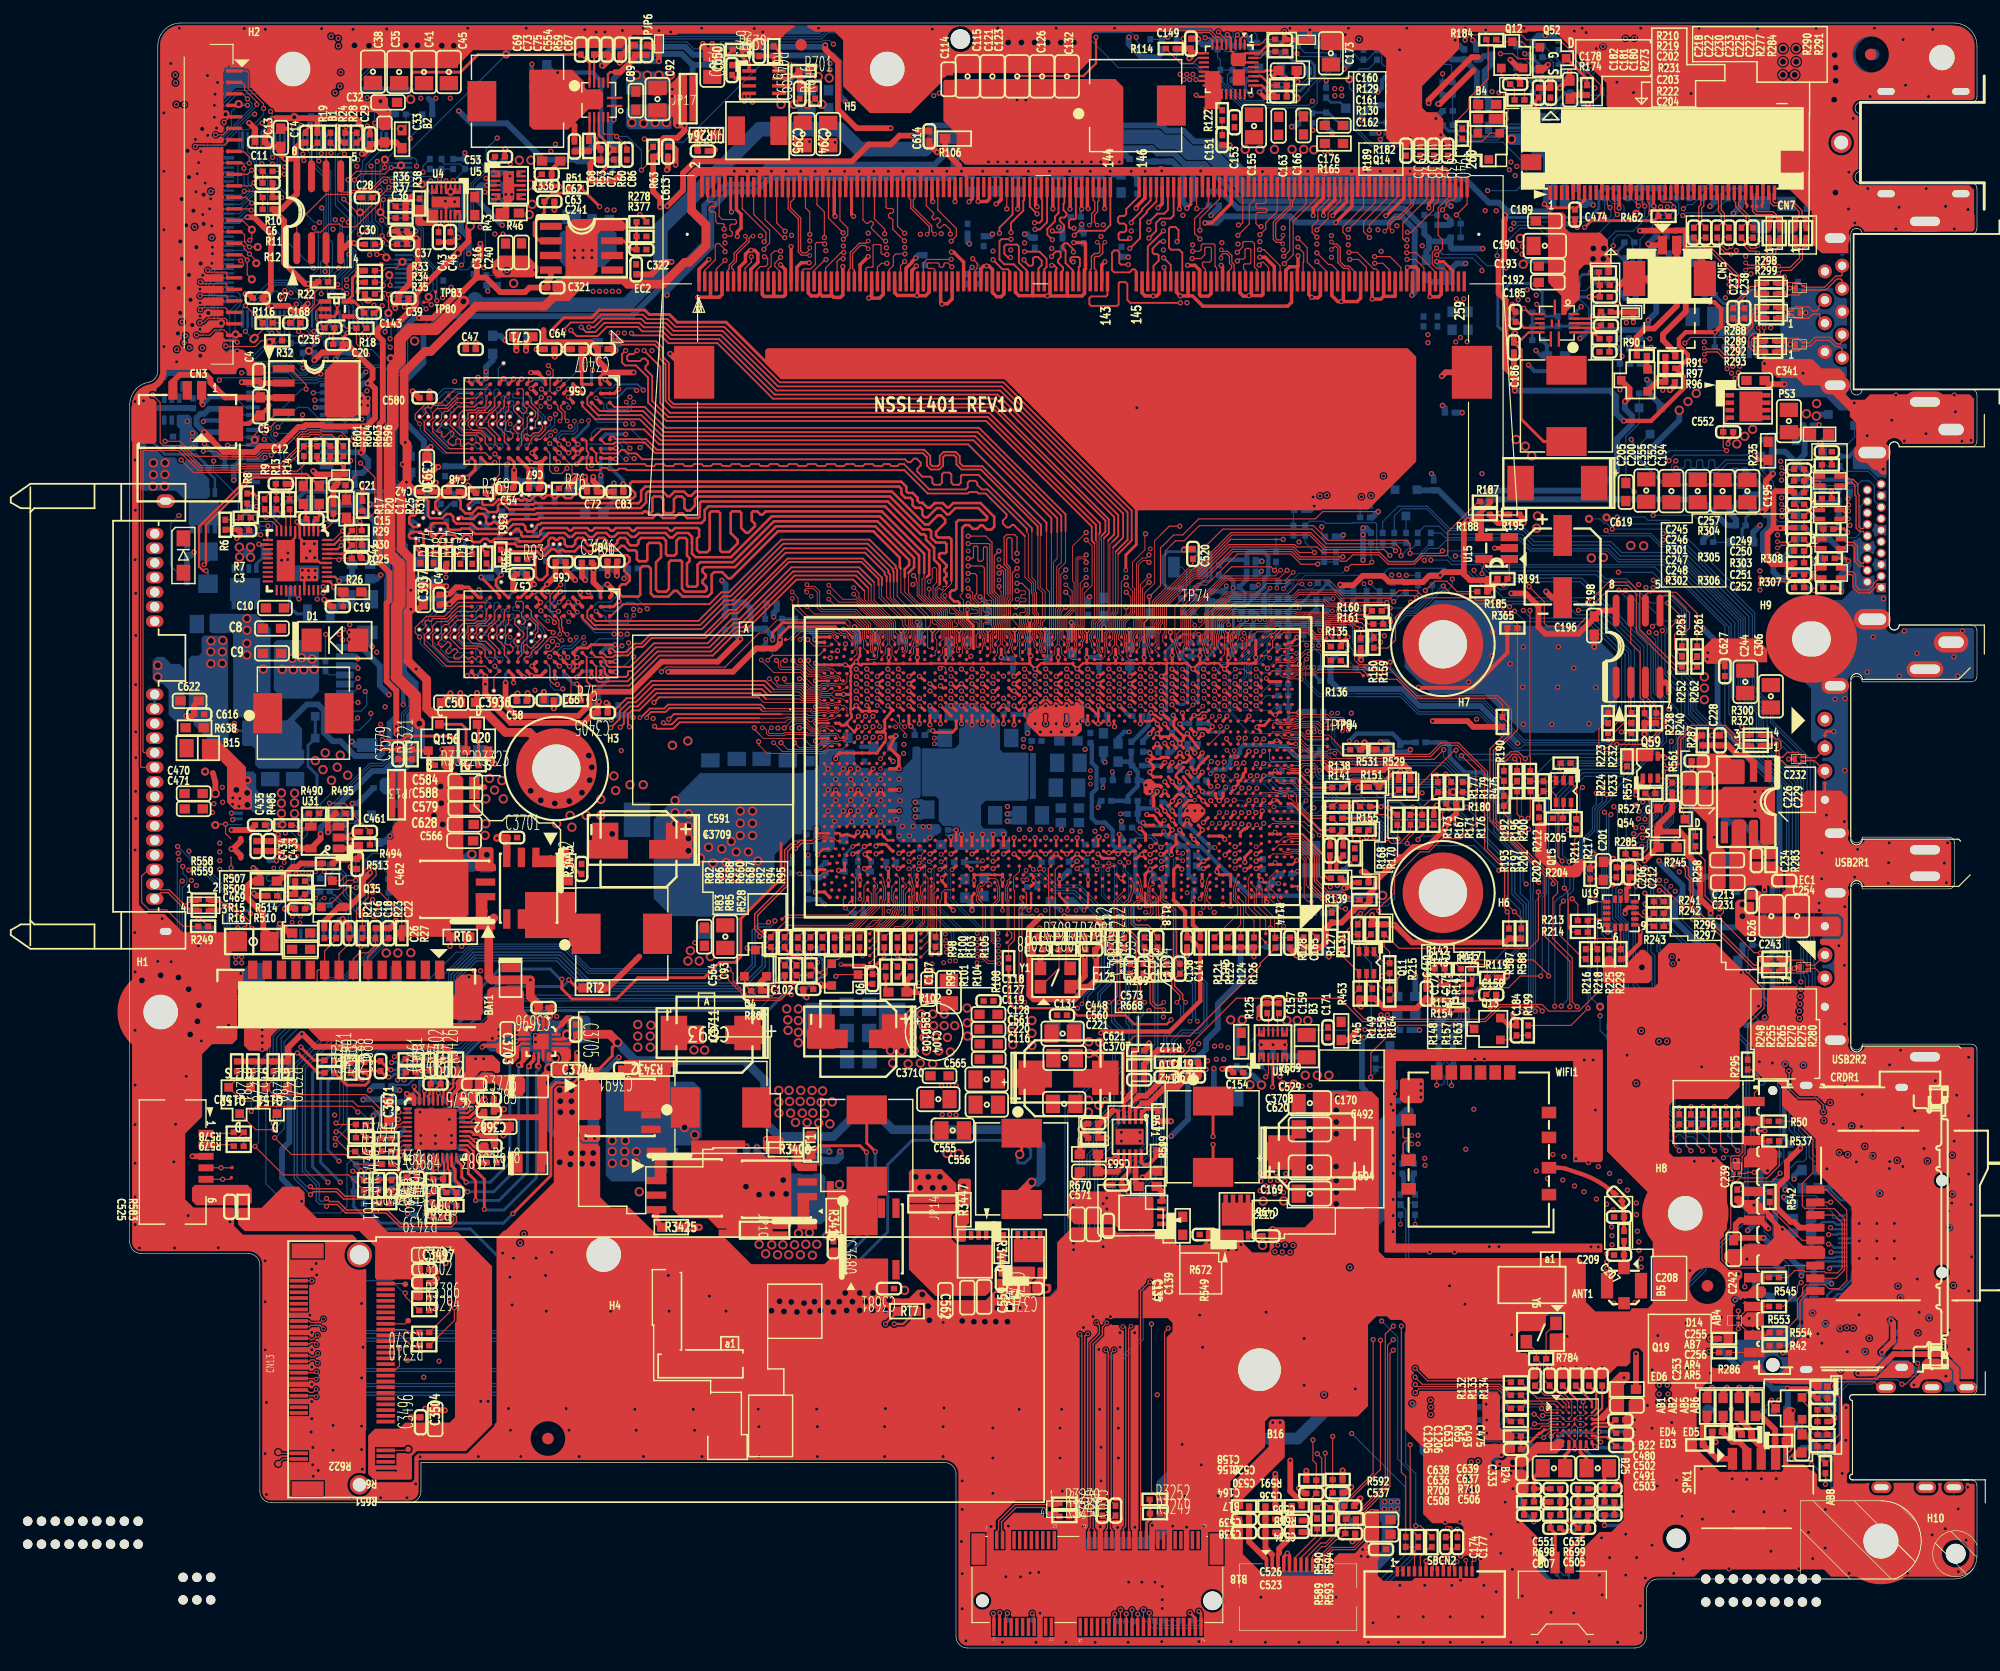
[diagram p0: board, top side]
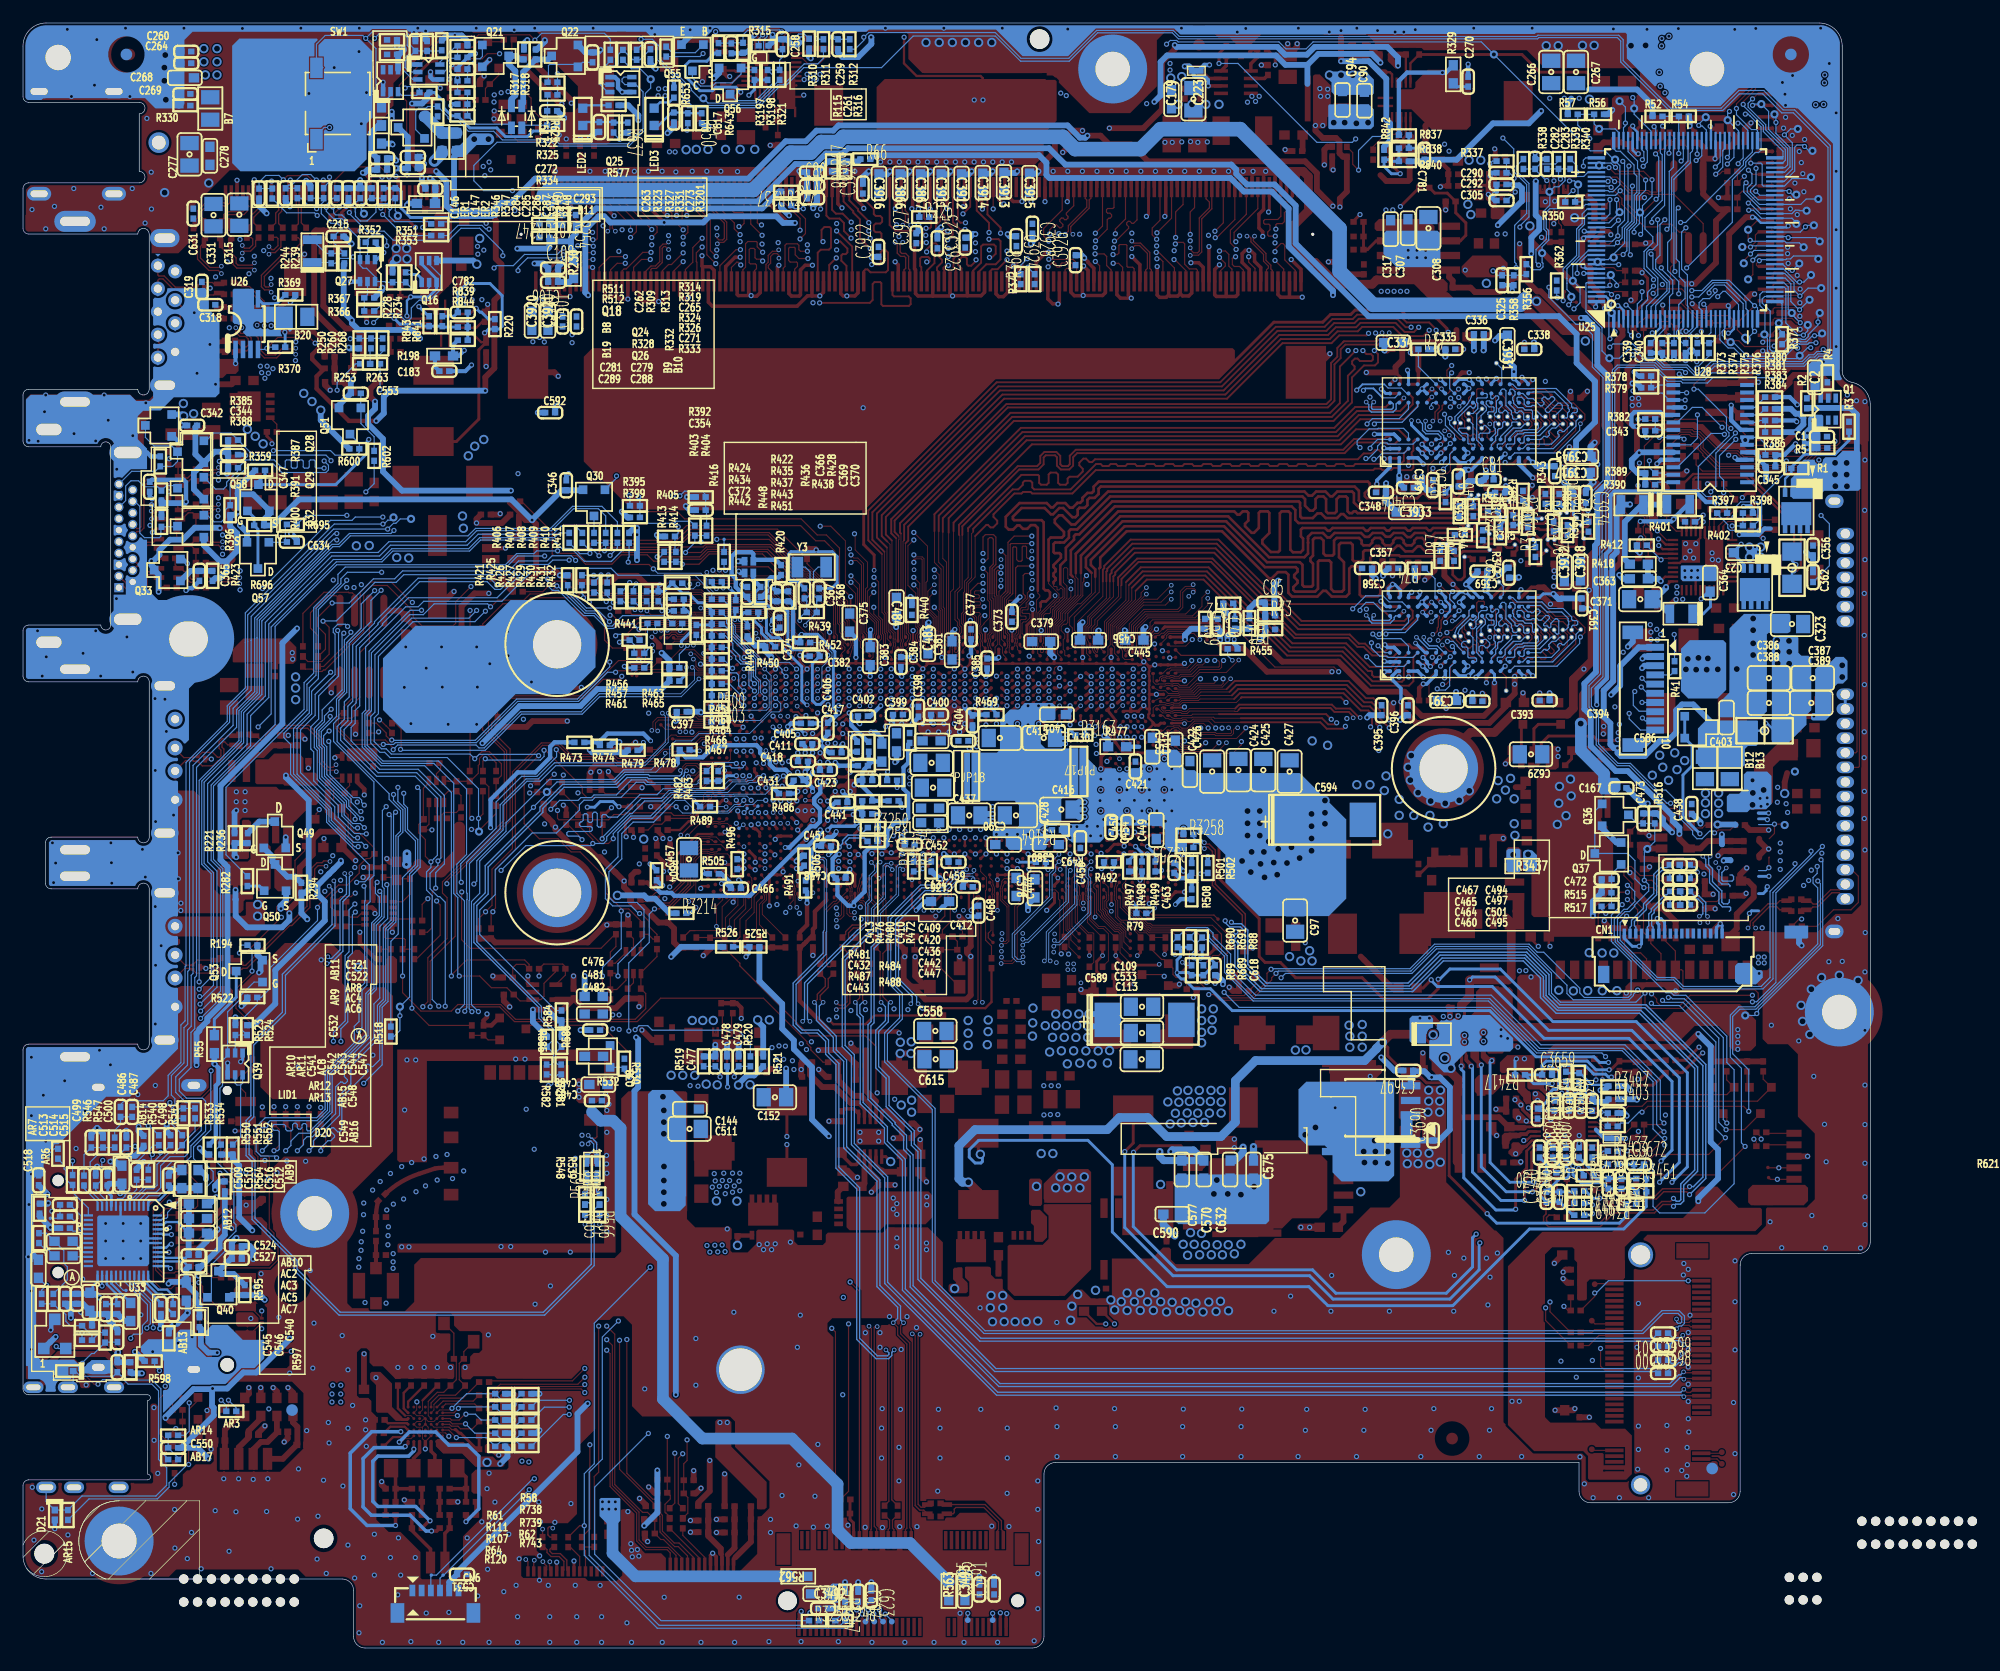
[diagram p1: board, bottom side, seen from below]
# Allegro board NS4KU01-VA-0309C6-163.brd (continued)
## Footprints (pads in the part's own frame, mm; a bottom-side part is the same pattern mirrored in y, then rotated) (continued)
SMD_CRYSTAL-TXC-4P_3D2X2D5
  rect 1.016x1.194 smd: 1(-1.291,-0.8) 2(1.291,-0.8) 3(1.291,0.8) 4(-1.291,0.8)
SOD_123_2D0
  rect 1.397x1.194 smd: 1(-1.499,0) 2(1.499,0)
SOT363
  rect 0.406x0.813 smd: 1(0.65,0.955) 2(0,0.955) 3(-0.65,0.955) 4(-0.65,-0.955) 5(0,-0.955) 6(0.65,-0.955)
SOT-23-5
  rect 0.711x1.016 smd: 1(-0.95,-1.2) 2(0,-1.2) 3(0.95,-1.2) 4(0.95,1.2) 5(-0.95,1.2)
SWITCH_T-V_TME-533K-Q-TR_DIP
  rect 1.092x1.778 smd: 1(1.85,3.1) 2(1.85,-3.1) 3(-1.85,3.1) 4(-1.85,-3.1)
  rect 0.61x1.016 smd: 5(2.5,0) 6(-2.5,0)
TC276BC236D165
  round 7.01 hole 4.191: 1(0,0)
TC296BC236D118
  round 7.518 hole 2.997: 1(0,0)
TF_M2_KEY-B_2280_3H
  rect 0.33x1.6 smd: 1(-9.25,3.773) 2(-9,-3.777) 3(-8.75,3.773) 4(-8.5,-3.777) 5(-8.25,3.773) 6(-8,-3.777) 7(-7.75,3.773) 8(-7.5,-3.777) 9(-7.25,3.773) 10(-7,-3.777) 11(-6.75,3.773) 20(-4.5,-3.777) 21(-4.25,3.773) 22(-4,-3.777) 23(-3.75,3.773) 24(-3.5,-3.777) 25(-3.25,3.773) 26(-3,-3.777) 27(-2.75,3.773) 28(-2.5,-3.777) 29(-2.25,3.773) 30(-2,-3.777) 31(-1.75,3.773) 32(-1.5,-3.777) 33(-1.25,3.773) 34(-1,-3.777) 35(-0.75,3.773) 36(-0.5,-3.777) 37(-0.25,3.773) 38(0,-3.777) 39(0.25,3.773) 40(0.5,-3.777) 41(0.75,3.773) 42(1,-3.777) 43(1.25,3.773) 44(1.5,-3.777) 45(1.75,3.773) 46(2,-3.777) 47(2.25,3.773) 48(2.5,-3.777) 49(2.75,3.773) 50(3,-3.777) 51(3.25,3.773) 52(3.5,-3.777) 53(3.75,3.773) 54(4,-3.777) 55(4.25,3.773) 56(4.5,-3.777) 57(4.75,3.773) 58(5,-3.777) 59(5.25,3.773) 60(5.5,-3.777) 61(5.75,3.773) 62(6,-3.777) 63(6.25,3.773) 64(6.5,-3.777) 65(6.75,3.773) 66(7,-3.777) 67(7.25,3.773) 68(7.5,-3.777) 69(7.75,3.773) 70(8,-3.777) 71(8.25,3.773) 72(8.5,-3.777) 73(8.75,3.773) 74(9,-3.777) 75(9.25,3.773)
  rect 1.321x2.794 smd: 76(-10.35,2.998) 77(10.35,2.998)
  round 1.676 hole 1.168: 78(-10,-1.502)
  round 2.184 hole 1.676: 79(10,-1.502)
TF_M2_KEY-E_2230_3H
  round 1.118 hole 1.118 unplated: (-10,-1.5)
  round 1.626 hole 1.626 unplated: (10,-1.5)
  rect 0.305x1.575 smd: 1(-9.25,3.775) 2(-9,-3.775) 3(-8.75,3.775) 4(-8.5,-3.775) 5(-8.25,3.775) 6(-8,-3.775) 7(-7.75,3.775) 8(-7.5,-3.775) 9(-7.25,3.775) 10(-7,-3.775) 11(-6.75,3.775) 12(-6.5,-3.775) 13(-6.25,3.775) 14(-6,-3.775) 15(-5.75,3.775) 16(-5.5,-3.775) 17(-5.25,3.775) 18(-5,-3.775) 19(-4.75,3.775) 20(-4.5,-3.775) 21(-4.25,3.775) 22(-4,-3.775) 23(-3.75,3.775) 32(-1.5,-3.775) 33(-1.25,3.775) 34(-1,-3.775) 35(-0.75,3.775) 36(-0.5,-3.775) 37(-0.25,3.775) 38(0,-3.775) 39(0.25,3.775) 40(0.5,-3.775) 41(0.75,3.775) 42(1,-3.775) 43(1.25,3.775) 44(1.5,-3.775) 45(1.75,3.775) 46(2,-3.775) 47(2.25,3.775) 48(2.5,-3.775) 49(2.75,3.775) 50(3,-3.775) 51(3.25,3.775) 52(3.5,-3.775) 53(3.75,3.775) 54(4,-3.775) 55(4.25,3.775) 56(4.5,-3.775) 57(4.75,3.775) 58(5,-3.775) 59(5.25,3.775) 60(5.5,-3.775) 61(5.75,3.775) 62(6,-3.775) 63(6.25,3.775) 64(6.5,-3.775) 65(6.75,3.775) 66(7,-3.775) 67(7.25,3.775) 68(7.5,-3.775) 69(7.75,3.775) 70(8,-3.775) 71(8.25,3.775) 72(8.5,-3.775) 73(8.75,3.775) 74(9,-3.775) 75(9.25,3.775)
  rect 1.219x2.743 smd: 76(10.35,3) 77(-10.35,3)
TOPOPEN-157X20
  rect 0.508x3.988 smd: 1(-0.356,0) 2(0.356,0)
TOPOPEN_20X30
  rect 0.762x0.508 smd: 1(0,0.381) 2(0,-0.381)
TOPOPEN_20X157
  rect 0.508x3.988 smd: 1(-0.318,0) 2(0.318,0)
TOPSHORT_20X30
  rect 0.508x0.762 smd: 1(0,0.254) 2(0,-0.254)
TP12T
  round 0.305 smd: 1(0,0)
TP20
  round 0.508 smd: 1(0,0)
TQFN32-2_4X4_GS9271
  rect 0.203x0.914 smd: 1(-1.4,-2.157) 2(-1,-2.157) 3(-0.6,-2.157) 4(-0.2,-2.157) 5(0.2,-2.157) 6(0.6,-2.157) 7(1,-2.157) 8(1.4,-2.157) 18(1,2.157) 19(0.6,2.157) 20(0.2,2.157) 21(-0.2,2.157) 22(-0.6,2.157) 23(-1,2.157) 24(-1.4,2.157)
  rect 0.914x0.203 smd: 9(2.157,-1.4) 10(2.157,-1) 11(2.157,-0.6) 12(2.157,-0.2) 13(2.157,0.2) 14(2.157,0.6) 15(2.157,1) 25(-2.157,1.4) 26(-2.157,1) 27(-2.157,0.6) 28(-2.157,0.2) 29(-2.157,-0.2) 30(-2.157,-0.6) 31(-2.157,-1) 32(-2.157,-1.4)
  custom 0.229x0.229 smd: 16(2.157,1.4)
  custom 0.381x0.381 smd: 17(1.4,2.157)
  rect 1.067x1.422 smd: 33(-0.885,0.705)
  rect 1.118x1.143 smd: 34(-0.855,-0.845)
TSOT23-8
  rect 0.305x1.219 smd: 1(-0.975,-1.3) 2(-0.325,-1.3) 3(0.325,-1.3) 4(0.975,-1.3) 5(0.975,1.3) 6(0.325,1.3) 7(-0.325,1.3) 8(-0.975,1.3)
unnamed#2
  round 0.813 hole 0.813 unplated: (0,0)
UQFN16_0D4_3X3
  rect 1.346x0.203 smd: 1(-1.381,0.526) 2(-1.381,-0.175) 8(1.381,-0.526) 9(1.381,0.175)
  rect 0.203x0.889 smd: 3(-0.8,-1.501) 4(-0.399,-1.501) 5(0,-1.501) 6(0.399,-1.501) 7(0.8,-1.501) 10(0.8,1.501) 11(0.399,1.501) 12(0,1.501) 13(-0.399,1.501) 14(-0.8,1.501)
  rect 0.66x0.203 smd: 15(0,0.165) 16(0,-0.434)
VIA16
  round 0.406 hole 0.254: 1(0,0)
VQFN40-3_0D4_5D0X5D0MCM
  rect 0.2x0.9 smd: 1(1.8,2.57) 2(1.4,2.57) 3(1,2.57) 4(0.6,2.57) 5(0.2,2.57) 6(-0.2,2.57) 7(-0.6,2.57) 8(-1,2.57) 9(-1.4,2.57) 10(-1.8,2.57) 21(-1.8,-2.57) 22(-1.4,-2.57) 23(-1,-2.57) 24(-0.6,-2.57) 25(-0.2,-2.57) 26(0.2,-2.57) 27(0.6,-2.57) 28(1,-2.57) 29(1.4,-2.57) 30(1.8,-2.57)
  rect 0.9x0.2 smd: 11(-2.57,1.8) 12(-2.57,1.4) 13(-2.57,1) 14(-2.57,0.6) 15(-2.57,0.2) 16(-2.57,-0.2) 17(-2.57,-0.6) 18(-2.57,-1) 19(-2.57,-1.4) 20(-2.57,-1.8) 31(2.57,-1.8) 32(2.57,-1.4) 33(2.57,-1) 34(2.57,-0.6) 35(2.57,-0.2) 36(2.57,0.2) 37(2.57,0.6) 38(2.57,1) 39(2.57,1.4) 40(2.57,1.8)
  rect 1.58x1.18 smd: 41(1.01,-1.21)
  rect 1.58x1.98 smd: 42(1.01,0.81)
  rect 1.58x3.6 smd: 43(-1.01,0)
WFN-25_14P
  rect 0.813x1.6 smd: 1(8.125,0) 2(6.875,0) 3(5.625,0) 4(4.375,0) 5(3.125,0) 6(1.875,0) 7(0.625,0) 8(-0.625,0) 9(-1.875,0) 10(-3.125,0) 11(-4.375,0) 12(-5.625,0) 13(-6.875,0) 14(-8.125,0)
  rect 2.108x2.997 smd: S1(-10.675,-2.9) S2(10.675,-2.9)
WSRPG0402-1R0M-H
  rect 1.499x2.489 smd: 1(1.85,0) 2(-1.85,0)
XTAL_CS3215_2P
  rect 1.016x1.803 smd: 1(-1.25,0) 2(1.25,0)

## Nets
3.3V_LCD_S: B9.2 B10.2 Q26.S R332.1
5V_ON_HV: C552.1 Q51.D Q61.4 R600.2
+0.6V_DDR: C173.1 C176.1 C3917.2 C3918.2 C3919.2 C3932.2 C3933.2 C3935.2 C3938.2 C3939.2 C3940.2 C3945.2 CN11.258 R81.1 R87.1 R93.1 R129.1 R140.1 R165.1 R256.1 R257.1 R266.1 R267.1 R269.1 R271.1 R272.1 R274.1 R276.1 R279.1 R281.1 R335.1 R341.1 R342.1 R343.1 R344.1 R345.1 R354.1 R355.1 R357.1 R360.1 R361.1 R363.1 U13.29
+1.00V_CPU: B3.1 C171.1 C398.2 C399.2 C410.1 R145.1 R472.1 R493.1 U11.AK28 U11.AK30 U11.AL30 U11.AL42 U11.AM28 U11.AM30 U11.AM42 U14.8 U14.9
+1.00VS_CPU: R118.1 R125.1 R398.1 R491.1 R521.2 U14.13 U14.14
+1.2VS: C42.2 C47.2 C48.2 C49.2 C50.2 C54.2 C56.2 C57.2 C58.2 C64.2 C65.2 C66.2 C67.2 C71.2 C72.2 C83.2 C84.2 C114.1 C115.1 C121.1 C123.1 C126.1 C132.1 C161.2 C261.1 C334.2 C335.2 C336.2 C338.2 C348.2 C349.2 C351.2 C353.2 C357.2 C358.2 C359.2 C361.2 C373.2 C375.1 C377.2 C379.1 C381.1 C383.1 C384.2 C385.2 C391.2 C393.2 C394.2 C395.2 C396.2 C483.1 C484.1 C3866.2 C3867.2 C3911.2 C3912.2 C3913.2 C3914.2 C3915.2 C3916.2 C3922.2 C3923.2 C3924.2 C3925.1 C3926.1 C3927.1 C3928.1 C3929.1 CN11.12 CN11.33 CN11.54 CN11.75 CN11.96 CN11.111 CN11.112 CN11.117 CN11.118 CN11.123 CN11.124 CN11.129 CN11.130 CN11.135 CN11.136 CN11.141 CN11.142 CN11.147 CN11.148 CN11.153 CN11.154 CN11.159 CN11.160 CN11.163 CN11.178 CN11.199 CN11.220 CN11.241 L7.1 R67.1 R71.1 R106.1 R226.2 R316.1 R364.1 R368.1 R372.1 R399.2 R440.1 R469.1 U11.AU23 U11.AU28 U11.AU35 U11.AU42 U11.BB23 U11.BB32 U11.BB41 U11.BB47 U11.BB51 U13.2 U13.28 U1635.A1 U1635.A9 U1635.B3 U1635.B9 U1635.C1 U1635.D1 U1635.D9 U1635.E2 U1635.E7 U1635.F2 U1635.F8 U1635.G1 U1635.G7 U1635.G9 U1635.J1 U1635.J2 U1635.J8 U1635.J9 U1635.L1 U1635.L9 U1635.R1 U1635.T9 U1636.A1 U1636.A9 U1636.B3 U1636.B9 U1636.C1 U1636.D1 U1636.D9 U1636.E2 U1636.E7 U1636.F2 U1636.F8 U1636.G1 U1636.G7 U1636.G9 U1636.J1 U1636.J2 U1636.J8 U1636.J9 U1636.L1 U1636.L9 U1636.R1 U1636.T9 U1637.A1 U1637.A9 U1637.B3 U1637.B9 U1637.C1 U1637.D1 U1637.D9 U1637.E2 U1637.E7 U1637.F2 U1637.F8 U1637.G1 U1637.G7 U1637.G9 U1637.J1 U1637.J2 U1637.J8 U1637.J9 U1637.L1 U1637.L9 U1637.R1 U1637.T9 U1638.A1 U1638.A9 U1638.B3 U1638.B9 U1638.C1 U1638.D1 U1638.D9 U1638.E2 U1638.E7 U1638.F2 U1638.F8 U1638.G1 U1638.G7 U1638.G9 U1638.J1 U1638.J2 U1638.J8 U1638.J9 U1638.L1 U1638.L9 U1638.R1 U1638.T9
+1.2VS_DDR: CN11.134 R226.1
+1.5VS_ON_S: C259.1 R312.2 U13.6
+1.8VA_FB: C234.2 R221.2 R236.2 R283.1 U23.7
+1.8VA_FB_R: C322.2 R278.2 R377.1 U8.7
+1.8VA_PCH: C307.1 C308.1 C317.1 C322.1 C531.2 CN6.5 EC2.2 R138.2 R151.2 R377.2 R508.2 R523.1 R3214.1 U8.6
+1.8VA_PCH_EN: C241.2 R336.2 U8.2
+1.35VS_BOOT: R130.2 U13.27
+1.35VS_ON: R312.1 R321.1 U25.16
+1.35VS_PHASE: C162.1 L7.2 R115.1 R122.1 U13.17 U13.18 U13.19 U13.20 U13.25
+2.5VS: C179.1 C223.1 C294.1 C295.1 C653.1 C3400.2 C3401.2 C3404.2 C3405.2 C3406.2 C3407.2 C3920.2 C3921.2 C3930.2 C3931.2 C3936.2 C3937.2 CN11.257 CN11.259 L23.2 R646.1 U32.5 U1635.B1 U1635.R9 U1636.B1 U1636.R9 U1637.B1 U1637.R9 U1638.B1 U1638.R9
+3.3V: AB9.2 B10.1 B16.1 B19.2 C20.1 C140.1 C212.1 C342.2 C344.1 C346.1 C474.2 C509.1 C515.1 C580.1 C592.1 C613.1 C614.1 C3496.1 C3497.1 C3502.1 C3503.1 C3504.1 CN7.7 CN13.2 CN13.4 CN13.70 CN13.72 CN13.74 Q10.5 Q28.G Q29.G Q30.S Q32.G Q40.S Q58.S R35.2 R51.1 R61.2 R64.2 R107.2 R111.2 R127.1 R131.2 R144.2 R149.1 R152.2 R154.2 R157.1 R158.1 R163.1 R180.1 R185.2 R187.2 R188.1 R191.1 R202.1 R204.1 R205.1 R207.2 R217.1 R225.1 R230.2 R237.2 R239.1 R254.2 R359.2 R374.2 R379.1 R381.1 R384.1 R385.1 R388.2 R389.1 R390.2 R396.1 R421.1 R423.2 R424.2 R431.1 R432.2 R437.1 R443.1 R448.1 R451.1 R454.1 R460.1 R464.1 R466.2 R467.1 R500.1 R503.1 R551.1 R552.1 R557.1 R577.2 R583.1 R584.1 R585.1 R586.1 R587.1 R588.1 R591.1 R592.1 R595.1 R653.2 R658.1 R696.2 R697.1 R3197.2 R3198.2 R3278.1 R3279.1 R3280.1 R3281.1 R3386.1 R3426.2 U5.13 U5.14 U15.4 U19.14 U25.11 U28.19 U28.24 U33.9
+3.3V_CCD: C285.1 CN7.19 Q58.D R359.1 R462.1
+3.3V_DDR: C106.1 C108.2 CN11.255 R230.1
+3.3V_LCD: C279.1 C288.1 CN7.8 CN7.9 Q26.D R323.1
+3.3V_WIFI: C485.2 C488.2 Q38.D R532.2 R563.2 WIFI1.8
+3.3VA: C167.1 C476.1 C481.1 C482.1 CN8.1 Q38.S R38.2 R190.1 R362.1 R365.2 R411.1 R461.1 R479.1 R489.2 R530.1 R532.1 U4.8 U4.9
+3.3VA_LDO: C73.1 C75.1 R91.1 U9.6
+3.3VA_ON_R: C282.1 R338.2 R339.2 U4.3
+3.3VA_PCH: C198.1 R43.2 R155.1 R170.1 R195.1 R238.2 R240.1 R287.2 R434.1 R463.1 R465.1 R474.1 R478.1 R484.1 R524.1 R526.2 U4.13 U4.14 U20.8
+3.3VA_PCH_ON: C283.1 R339.1 R340.2 U4.5
+3.3VA_RTC: C369.1 C370.1 C406.2 D4.3 R420.1 R428.1 R452.1 U11.AK19 U11.BB14
+3.3VAL: B2.1 B17.1 C11.1 C13.1 C14.1 C32.1 C35.1 C38.1 C41.1 C45.1 C53.2 C69.1 C143.1 C240.1 C266.1 C267.1 C316.1 C518.1 C781.2 L2.2 LID1.1 Q17.5 Q35.S R12.1 R19.2 R21.1 R22.2 R28.1 R33.1 R36.2 R37.2 R38.1 R43.1 R52.1 R57.1 R97.1 R328.2 R333.1 R334.1 R348.1 R349.1 R369.1 R370.1 R373.2 R598.1 R639.1 R840.1 U3.8 U4.1 U4.2 U4.6 U4.7 U5.1 U5.2 U5.6 U5.7 U8.3 U9.7 U25.74
+3.3VAL_BOOT: R53.1 U9.10
+3.3VAL_BOOT1: C68.1 R53.2
+3.3VAL_EN: C86.1 R63.2 U9.13
+3.3VAL_SN: C270.1 R329.2
+3.3VAL_SW: C68.2 L2.1 R329.1 R837.1 U9.8 U9.9 U9.15 U9.16
+3.3VAL_VBYP: C87.1 R59.1 U9.3
+3.3VAL_VCC: C74.1 U9.11
+3.3VDVDD: AB9.1 C512.1 C516.1 U33.1
+3.3VS: C156.1 C158.1 C164.1 C345.2 R46.1 R525.2 R562.2 SBCN2.1 SBCN2.2 SBCN2.3 U5.8 U5.9 U28.5
+3.3VS_ON: R350.1 R520.1 U25.106
+5V: AB10.2 B8.2 B9.1 B15.2 B18.1 B22.1 C4.1 C347.1 C3682.2 C3703.1 C3704.1 D15.2 D26.A D34.A D41.A D42.A PS3.2 Q61.5 Q61.6 Q61.7 Q61.8 Q61.S1 Q156.E R235.1 R391.2 R400.1 R597.2 R3322.2 R3407.2 U2.2 U109.26 U110.4 U110.13
+5V_AMP: AB10.1 AC2.1 AC3.1 AC5.1 U33.39 U33.46
+5V_CODECAVDD: AC7.1 AC8.1 C540.2 C541.1 C542.1 R597.1 U33.25 U33.38
+5V_ON: C150.1 Q10.1 R113.1 R337.1 R602.2 U25.47
+5V_ON_1: C553.1 Q51.G R602.1
+5VAL: B11.1 C149.1 C186.1 C194.1 C195.1 C196.1 C200.1 C205.1 C226.1 C229.1 C232.1 C292.2 C321.1 C341.1 C352.1 C355.1 C433.1 C434.1 C478.2 C554.2 C619.1 C782.2 JP17.1 L9.2 Q61.1 Q61.2 Q61.3 R59.2 R63.1 R114.2 R220.2 R294.1 R310.2 R600.1 R670.2 R841.1 U4.4 U5.4 U8.4 U13.9 U14.4 U18.7 U23.3 U23.4 U26.2 U26.3 U31.5
+5VAL_BOOT: R222.1 U18.10
+5VAL_BOOT1: C204.1 R222.2
+5VAL_EN: C202.1 Q16.3 Q16.6 R210.2 R219.1 U18.13
+5VAL_LDO: C185.1 U18.6
+5VAL_LX: C204.2 L9.1 R198.1 R844.1 U18.8 U18.9 U18.15 U18.16
+5VAL_SN: C183.1 R198.2
+5VAL_VBYP: R220.1 U18.3
+5VAL_VCC: C203.1 U18.11
+5VS_PANEL: B11.2 C293.1 CN7.5
+V1.00A_SIP: R504.2 U11.AB17 U11.Y18
+V1.8A_SIP: R138.1 U11.AA1
+V1.8S_EDRAM: C463.2 R501.1 R508.1
+VCCAMPHYPLL_1P0: C466.2 R505.2 U11.K15 U11.L15
+VCCAPLL_1P0: R486.2 U11.V15
+VCCAPLLEBB_1P0: C441.2 R488.2 U11.N18
+VCCCLKX: C443.2 R108.2 R487.2 U11.A10 U11.A14 U11.K19 U11.L19 U11.L21 U11.N20
+VCCDSW_1P0: C397.2 TP54.1 U11.AL1
+VCCDTS_1P0: R143.2 U11.T1
+VCCFHV: R476.2 U11.AK20
+VCCMPHYAON_1P0: R139.1 R153.2 U11.K17
+VCCMPHYAON_1P0_C: R139.2 U11.L1
+VCCMPHYGTAON_1P0_LS_SIP: C172.2 C175.2 C457.1 R147.2 U11.N15 U11.N16 U11.N17 U11.P15 U11.P16
+VCCOPC: R477.2 U11.AB62 U11.AE62 U11.AG62 U11.P62 U11.V62
+VCCOPC_TP: R477.1 TP61.1
+VCCPAZIO: C372.2 R434.2 U11.AJ19
+VCCPDSW_3P3: C405.2 R479.2 U11.AD17 U11.AD18 U11.AJ17
+VCCPGPPF_1P8: C411.2 R151.1 U11.AF16
+VCCPGPPX: C431.2 R473.1 R474.2 U11.AG15 U11.AK15 U11.T16 U11.Y15 U11.Y16
+VCCPRIM_1P0: C423.2 R481.2 U11.AB19 U11.AB20 U11.P18
+VCCPRIM_3P3: C413.2 R484.2 U11.AJ21 U11.V19
+VCCPRTCPRIM_3P3: R465.2 U11.AK17
+VCCPSPI: R478.2 U11.AJ16
+VCCSA: C116.1 C118.2 C119.1 C127.1 C128.1 C131.2 C220.1 C221.1 C448.1 C560.1 C561.1 C621.1 C3707.1 L26.1 R3250.2 R3450.1 R3451.2 U11.AK23 U11.AK25 U11.G23 U11.G25 U11.G27 U11.G28 U11.J22 U11.J23 U11.J27 U11.K23 U11.K25 U11.K27 U11.K28 U11.K30
+VCCSFR: C451.2 R491.2 U11.K20 U11.K21
+VCCSFR_OC: C402.2 R440.2 U11.AL23
+VCCSRAM_1P0: C417.2 R480.2 U11.AF20 U11.AF21 U11.T19 U11.T20
+VCCST_CPU: C145.2 C618.1 C3672.1 R86.2 R88.2 R89.2 R92.1 R95.2 R118.2 R528.2 R689.2 R690.2 R691.2 R3413.2 R3414.2 R3527.2 U11.A18
+VCCSTG: C458.2 R83.2 R98.2 R100.1 R101.1 R103.1 R472.2 U11.A22 U11.G20
AGND_+1.35VS: C149.2 C160.2 C258.2 C259.2 PJP10.1 R315.2 U13.4 U13.30 U13.32 U13.34
AGND_+2.5V: PJP11.2 R701.2 U32.6
AGND_+3.3VAL: C74.2 C86.2 C87.2 PJP6.1 R60.2 R842.2 U9.14
AGND_+5VAL: C202.2 C203.2 PJP12.1 R219.2 R231.2 R843.2 U18.14
GND POWER: AB4.1 AB11.1 AB12.1 AB13.1 AB14.1 AC2.2 AC3.2 AC5.2 ANT1.1 ANT1.S1 ANT1.S3 BAT1.S1 BAT1.S2 C1.2 C2.2 C3.2 C4.2 C5.2 C6.2 C7.2 C8.2 C9.2 C10.2 C11.2 C13.2 C14.2 C16.2 C18.2 C19.2 C20.2 C22.2 C26.2 C28.2 C29.2 C30.1 C32.2 C33.2 C35.2 C36.1 C37.1 C38.2 C39.2 C41.2 C42.1 C43.1 C45.2 C46.1 C47.1 C48.1 C49.1 C50.1 C53.1 C54.1 C56.1 C57.1 C58.1 C62.1 C63.1 C64.1 C65.1 C66.1 C67.1 C69.2 C71.1 C72.1 C73.2 C75.2 C78.1 C79.2 C80.1 C81.1 C82.1 C83.1 C84.1 C85.2 C89.2 C90.2 C92.2 C93.2 C94.2 C97.2 C102.1 C104.2 C105.2 C106.2 C107.1 C108.1 C109.2 C113.2 C114.2 C115.2 C116.2 C118.1 C119.2 C121.2 C123.2 C125.2 C126.2 C127.2 C128.2 C131.1 C132.2 C133.2 C134.2 C135.2 C136.2 C137.2 C139.2 C140.2 C143.2 C144.2 C145.1 C146.2 C147.2 C150.2 C151.2 C152.2 C153.2 C154.1 C155.2 C156.2 C157.1 C158.2 C159.1 C161.1 C163.2 C164.2 C165.1 C166.2 C167.2 C168.2 C169.2 C170.2 C171.2 C172.1 C173.2 C175.1 C176.2 C178.2 C179.2 C180.2 C181.2 C182.1 C183.2 C184.1 C185.2 C186.2 C189.2 C190.2 C192.2 C193.2 C194.2 C195.2 C196.2 C198.2 C200.2 C201.2 C205.2 C206.2 C208.2 C209.2 C212.2 C213.2 C214.2 C215.2 C220.2 C221.2 C223.2 C226.2 C228.1 C229.2 C231.2 C232.2 C235.2 C236.2 C239.1 C240.2 C241.1 C242.1 C243.2 C244.2 C254.2 C257.2 C260.2 C262.2 C263.2 C264.2 C265.2 C266.2 C267.2 C268.2 C269.1 C270.2 C271.2 C272.2 C273.2 C277.2 C278.2 C279.2 C281.2 C282.2 C283.2 C284.2 C285.2 C286.2 C287.2 C288.2 C289.2 C290.2 C292.1 C293.2 C294.2 C295.2 C305.2 C306.2 C307.2 C308.2 C315.2 C316.2 C317.2 C318.2 C319.2 C321.2 C323.2 C325.1 C331.2 C332.2 C333.2 C334.1 C335.1 C336.1 C338.1 C339.2 C340.2 C341.2 C342.1 C343.1 C344.2 C345.1 C346.2 C347.2 C348.1 C349.1 C351.1 C352.2 C353.1 C354.1 C355.2 C356.1 C357.1 C358.1 C359.1 C361.1 C362.1 C363.2 C365.1 C366.2 C367.1 C368.1 C369.2 C370.2 C372.1 C373.1 C374.1 C375.2 C377.1 C378.2 C379.2 C380.2 C381.2 C382.2 C383.2 C384.1 C385.1 C386.2 C387.2 C388.2 C389.2 C390.2 C391.1 C393.1 C394.1 C395.1 C396.1 C397.1 C398.1 C399.1 C400.2 C401.2 C402.1 C403.2 C404.1 C405.1 C406.1 C409.2 C410.2 C411.1 C412.2 C413.1 C414.2 C415.2 C416.2 C417.1 C418.1 C420.2 C421.2 C422.2 C423.1 C424.2 C425.2 C426.2 C427.2 C428.2 C430.2 C431.1 C432.1 C433.2 C434.2 C435.2 C436.2 C437.2 C438.2 C441.1 C442.2 C443.1 C444.2 C445.2 C447.2 C448.2 C449.2 C450.2 C451.1 C452.2 C453.2 C454.2 C455.2 C456.2 C457.2 C458.1 C459.2 C461.2 C462.2 C463.1 C466.1 C468.2 C469.2 C470.2 C471.2 C472.2 C473.2 C474.1 C475.2 C476.2 C477.2 C478.1 C479.2 C480.2 C481.2 C482.2 C483.2 C484.2 C485.1 C488.1 C490.2 C491.1 C492.2 C493.2 C496.2 C498.1 C499.1 C500.1 C502.1 C503.2 C504.2 C509.2 C510.1 C511.2 C512.2 C514.1 C515.2 C516.2 C517.2 C518.2 C519.2 C520.1 C523.2 C524.2 C525.2 C526.2 C527.2 C528.2 C529.2 C530.2 C531.1 C532.1 C533.2 C534.2 C535.2 C536.2 C537.2 C538.2 C539.2 C551.1 C552.2 C553.2 C554.1 C555.2 C556.2 C558.2 C559.2 C560.2 C561.2 C562.2 C564.2 C565.2 C566.2 C570.2 C571.2 C573.2 C575.2 C577.2 C579.2 C580.2 C583.2 C584.2 C586.2 C588.2 C589.2 C590.2 C591.2 C592.2 C593.2 C594.2 C597.1 C613.2 C615.2 C616.2 C617.2 C618.2 C619.2 C620.2 C621.2 C622.2 C623.1 C626.2 C627.2 C628.2 C629.2 C631.2 C632.2 C633.2 C634.1 C635.2 C636.1 C637.2 C649.2 C650.2 C654.2 C1205.1 C1206.1 C3400.1 C3401.1 C3404.1 C3405.1 C3406.1 C3407.1 C3491.2 C3492.2 C3493.2 C3494.2 C3495.2 C3496.2 C3497.2 C3502.2 C3503.2 C3504.2 C3672.2 C3680.2 C3681.2 C3682.1 C3690.2 C3691.2 C3697.2 C3701.2 C3702.2 C3703.2 C3704.2 C3707.2 C3708.2 C3709.2 C3710.2 C3711.2 C3713.2 C3714.2 C3773.2 C3783.2 C3866.1 C3867.1 C3911.1 C3912.1 C3913.1 C3914.1 C3915.1 C3916.1 C3917.1 C3918.1 C3919.1 C3920.1 C3921.1 C3922.1 C3923.1 C3924.1 C3925.2 C3926.2 C3927.2 C3928.2 C3929.2 C3930.1 C3931.1 C3932.1 C3933.1 C3934.1 C3935.1 C3936.1 C3937.1 C3938.1 C3939.1 C3940.1 C3945.1 CN1.1 CN1.4 CN1.7 CN1.8 CN1.17 CN1.18 CN1.S1 CN1.S2 CN3.1 CN3.S1 CN3.S2 CN4.3 CN4.S1 CN4.S2 CN5.1 CN5.S1 CN5.S2 CN6.2 CN6.S1 CN6.S2 CN7.6 CN7.10 CN7.13 CN7.23 CN7.26 CN7.29 CN7.32 CN7.35 CN7.38 CN7.S2 CN8.2 CN8.3 CN8.S1 CN8.S2 CN9.H1 CN9.H2 CN9.P4 CN9.P10 CN9.P12 CN9.S1 CN9.S4 CN9.S7 CN11.1 CN11.2 CN11.5 CN11.6 CN11.9 CN11.10 CN11.14 CN11.15 CN11.18 CN11.19 CN11.22 CN11.23 CN11.26 CN11.27 CN11.30 CN11.31 CN11.35 CN11.36 CN11.39 CN11.40 CN11.43 CN11.44 CN11.47 CN11.48 CN11.51 CN11.52 CN11.56 CN11.57 CN11.60 CN11.61 CN11.64 CN11.65 CN11.68 CN11.69 CN11.72 CN11.73 CN11.77 CN11.78 CN11.81 CN11.82 CN11.85 CN11.86 CN11.89 CN11.90 CN11.93 CN11.94 CN11.98 CN11.99 CN11.102 CN11.103 CN11.106 CN11.107 CN11.167 CN11.168 CN11.171 CN11.172 CN11.175 CN11.176 CN11.180 CN11.181 CN11.184 CN11.185 CN11.188 CN11.189 CN11.192 CN11.193 CN11.196 CN11.197 CN11.201 CN11.202 CN11.205 CN11.206 CN11.209 CN11.210 CN11.213 CN11.214 CN11.217 CN11.218 CN11.222 CN11.223 CN11.226 CN11.227 CN11.230 CN11.231 CN11.234 CN11.235 CN11.238 CN11.239 CN11.243 CN11.244 CN11.247 CN11.248 CN11.251 CN11.252 CN11.261 CN11.262 CN13.1 CN13.3 CN13.5 CN13.11 CN13.21 CN13.27 CN13.33 CN13.39 CN13.45 CN13.51 CN13.57 CN13.71 CN13.73 CN13.75 CN14.1 CN14.7 CN14.18 CN14.33 CN14.39 CN14.45 CN14.51 CN14.57 CN14.63 CN14.69 CN14.75 CN33.S1 CN33.S2 CRDR1.5 CRDR1.8 CRDR1.H1 CRDR1.H2 CRDR1.H3 CRDR1.H4 CRDR2.6 CRDR2.10 CRDR2.11 CRDR2.12 CRDR2.13 D7.3 D8.3 D9.3 D10.3 D11.3 D12.3 D13.3 D14.A D15.1 D20.A D21.A DCIN1.2 DCIN1.3 DCIN1.4 DCIN1.5 EC1.1 EC2.1 ED3.2 ED4.2 ED5.2 ED6.2 H1.1 H2.1 H3.1 H4.1 H5.1 H6.1 H7.1 H8.1 H9.1 H10.1 H11.1 H24.1 HDMI1.2 HDMI1.5 HDMI1.8 HDMI1.11 HDMI1.17 HDMI1.S1 HDMI1.S2 HDMI1.S3 HDMI1.S4 JP11.2 JP12.2 KBT1.S1 KBT1.S2 LID1.2 PJP2.2 PJP6.2 PJP10.2 PJP11.1 PJP12.2 PJP36.2 Q1.1 Q1.4 Q4.S Q6.E Q10.3 Q12.S Q13.E Q16.1 Q16.4 Q17.3 Q18.1 Q18.4 Q20.S Q21.E Q22.E Q24.1 Q24.4 Q25.1 Q25.4 Q27.1 Q27.4 Q33.S Q36.S Q37.S Q39.1 Q39.4 Q42.1 Q42.2 Q42.3 Q44.1 Q44.2 Q44.3 Q46.1 Q46.2 Q46.3 Q48.1 Q48.2 Q48.3 Q49.S Q50.S Q51.S Q52.S Q53.S Q55.E Q56.S Q57.S Q59.1 Q59.4 Q62.1 Q62.2 Q62.3 Q63.1 Q63.2 Q63.3 R4.2 R5.1 R6.2 R11.2 R15.2 R24.2 R30.2 R31.2 R34.2 R46.2 R51.2 R54.2 R56.2 R58.1 R62.1 R65.2 R68.2 R69.2 R72.2 R73.2 R74.2 R75.2 R76.2 R77.2 R79.2 R80.1 R96.2 R102.2 R104.2 R106.2 R112.2 R119.2 R125.2 R135.2 R141.2 R142.2 R145.2 R150.1 R165.2 R168.2 R176.1 R182.1 R194.1 R221.1 R227.1 R229.2 R234.1 R235.2 R245.2 R246.1 R247.1 R250.1 R278.1 R309.1 R317.2 R318.2 R319.1 R330.1 R346.1 R352.1 R358.2 R367.1 R378.1 R380.1 R383.2 R386.1 R387.2 R392.2 R405.2 R422.1 R436.1 R438.1 R449.1 R450.1 R455.2 R482.1 R483.2 R492.1 R495.2 R497.1 R498.1 R499.1 R502.1 R506.2 R510.2 R512.1 R515.2 R516.2 R519.2 R522.2 R529.2 R531.2 R546.1 R603.2 R604.2 R637.2 R650.2 R668.2 R669.2 R3154.1 R3247.1 R3251.2 R3258.1 RCH1.1 S1.2 S2.2 S3.2 S4.2 S5.2 S6.2 S7.2 S8.2 S9.2 S10.2 S11.2 S12.2 S13.2 S14.2 S15.2 S16.2 S17.2 S18.2 S19.2 S20.2 S21.2 S22.2 S23.2 S24.2 S25.2 S26.2 S27.2 S28.2 S31.2 S32.2 S33.2 S34.2 S35.2 S36.2 S37.2 S38.2 S39.2 S40.2 S41.2 S42.2 S43.2 S44.2 S45.2 S46.2 S47.2 S48.2 S49.2 S50.2 S51.2 S52.2 S53.2 S54.2 SBCN1.4 SBCN1.5 SBCN1.S1 SBCN1.S2 SBCN2.6 SBCN2.9 SBCN2.12 SBCN2.S1 SBCN2.S2 SPK1.S1 SPK1.S2 SW1.3 SW1.4 SW1.5 SW1.6 U1.28 U1.29 U1.30 U2.5 U2.6 U2.7 U2.8 U3.4 U4.11 U4.S1 U5.11 U5.S1 U8.8 U8.S1 U9.2 U11.A5 U11.A65 U11.A67 U11.A70 U11.AA2 U11.AA4 U11.AA65 U11.AA68 U11.AB8 U11.AB15 U11.AB16 U11.AB18 U11.AB21 U11.AD8 U11.AD13 U11.AD16 U11.AD19 U11.AD20 U11.AD21 U11.AD62 U11.AE64 U11.AE65 U11.AE66 U11.AE67 U11.AE68 U11.AE69 U11.AF1 U11.AF2 U11.AF4 U11.AF10 U11.AF15 U11.AF17 U11.AF63 U11.AG16 U11.AG17 U11.AG18 U11.AG19 U11.AG20 U11.AG21 U11.AG71 U11.AH6 U11.AH13 U11.AH63 U11.AH64 U11.AH67 U11.AJ4 U11.AJ15 U11.AJ18 U11.AJ20 U11.AK8 U11.AK11 U11.AK16 U11.AK18 U11.AK21 U11.AK22 U11.AK27 U11.AK63 U11.AK68 U11.AK69 U11.AL2 U11.AL4 U11.AL28 U11.AL32 U11.AL35 U11.AL38 U11.AL45 U11.AL48 U11.AL52 U11.AL55 U11.AL58 U11.AL64 U11.AL65 U11.AL66 U11.AM8 U11.AM13 U11.AM21 U11.AM25 U11.AM27 U11.AM43 U11.AM45 U11.AM46 U11.AM55 U11.AM60 U11.AM61 U11.AM68 U11.AM71 U11.AN20 U11.AN23 U11.AN28 U11.AN30 U11.AN32 U11.AN33 U11.AN35 U11.AN37 U11.AN38 U11.AN40 U11.AN42 U11.AN58 U11.AN63 U11.AP10 U11.AP18 U11.AP20 U11.AP23 U11.AP28 U11.AP32 U11.AP35 U11.AP38 U11.AP42 U11.AP58 U11.AP63 U11.AP68 U11.AP70 U11.AR5 U11.AR8 U11.AR11 U11.AR15 U11.AR16 U11.AR20 U11.AR23 U11.AR28 U11.AR35 U11.AR42 U11.AR43 U11.AR45 U11.AR46 U11.AR48 U11.AR50 U11.AR52 U11.AR53 U11.AR55 U11.AR58 U11.AR63 U11.AT2 U11.AT4 U11.AT20 U11.AT23 U11.AT28 U11.AT35 U11.AT42 U11.AT56 U11.AT58 U11.AT63 U11.AT68 U11.AT71 U11.AU10 U11.AU15 U11.AU20 U11.AU32 U11.AU38 U11.AV1 U11.AV68 U11.AV69 U11.AV70 U11.AV71 U11.AW6 U11.AW8 U11.AW10 U11.AW12 U11.AW14 U11.AW16 U11.AW18 U11.AW21 U11.AW23 U11.AW26 U11.AW28 U11.AW30 U11.AW32 U11.AW34 U11.AW36 U11.AW38 U11.AW41 U11.AW43 U11.AW45 U11.AW47 U11.AW49 U11.AW51 U11.AW53 U11.AW55 U11.AW57 U11.AW60 U11.AW62 U11.AW64 U11.AW66 U11.AY66 U11.B10 U11.B14 U11.B18 U11.B22 U11.B30 U11.B34 U11.B39 U11.B44 U11.B48 U11.B53 U11.B58 U11.B62 U11.B66 U11.B71 U11.BA1 U11.BA2 U11.BA6 U11.BA10 U11.BA14 U11.BA18 U11.BA23 U11.BA28 U11.BA32 U11.BA36 U11.BA41 U11.BA45 U11.BA49 U11.BA53 U11.BA57 U11.BA62 U11.BA66 U11.BA71 U11.BB6 U11.BB18 U11.BB26 U11.BB30 U11.BB34 U11.BB38 U11.BB43 U11.BB55 U11.BB60 U11.BB64 U11.BB67 U11.BB70 U11.C1 U11.C5 U11.C25 U11.D6 U11.D10 U11.D11 U11.D14 U11.D18 U11.D22 U11.D25 U11.D26 U11.D30 U11.D34 U11.D39 U11.D44 U11.D45 U11.D47 U11.D48 U11.D53 U11.D58 U11.D62 U11.D66 U11.D69 U11.E6 U11.E11 U11.E15 U11.E18 U11.E21 U11.E46 U11.E50 U11.E53 U11.E56 U11.E65 U11.E71 U11.F1 U11.F2 U11.F4 U11.F8 U11.F13 U11.F22 U11.F23 U11.F27 U11.F28 U11.F32 U11.F33 U11.F35 U11.F37 U11.F38 U11.F40 U11.F42 U11.F68 U11.G5 U11.G6 U11.G10 U11.G22 U11.G43 U11.G45 U11.G48 U11.G52 U11.G55 U11.G58 U11.G60 U11.G63 U11.G66 U11.H15 U11.H18 U11.H71 U11.J8 U11.J11 U11.J13 U11.J25 U11.J28 U11.J32 U11.J35 U11.J38 U11.J42 U11.K16 U11.K18 U11.K22 U11.K61 U11.K63 U11.K64 U11.K65 U11.K66 U11.K67 U11.K68 U11.K70 U11.K71 U11.L2 U11.L4 U11.L8 U11.L11 U11.L16 U11.L17 U11.L18 U11.L20 U11.N6 U11.N10 U11.N13 U11.N19 U11.N21 U11.N65 U11.N68 U11.P17 U11.P19 U11.P20 U11.P21 U11.R6 U11.R13 U11.T2 U11.T4 U11.T15 U11.T17 U11.T18 U11.T21 U11.U10 U11.U63 U11.U64 U11.U66 U11.U67 U11.U69 U11.U70 U11.V16 U11.V17 U11.V18 U11.W6 U11.W9 U11.W13 U11.Y17 U11.Y19 U11.Y20 U11.Y21 U12.11 U13.11 U13.12 U13.13 U13.14 U13.15 U13.16 U14.11 U14.S1 U15.2 U18.2 U19.5 U19.12 U20.4 U23.8 U23.S1 U25.1 U25.3 U25.27 U25.49 U25.75 U25.91 U25.113 U25.122 U25.128 U26.1 U28.4 U28.8 U28.18 U28.25 U31.2 U32.4 U33.7 U33.42 U33.43 U33.S1 U109.29 U110.6 U110.11 U110.17 U1634.B6 U1634.C2 U1634.C4 U1634.D4 U1634.D6 U1634.E2 U1634.F3 U1634.G4 U1635.A2 U1635.A8 U1635.B2 U1635.C9 U1635.D2 U1635.D8 U1635.E1 U1635.E3 U1635.E8 U1635.E9 U1635.F1 U1635.G8 U1635.H1 U1635.H9 U1635.K1 U1635.K9 U1635.M9 U1635.N1 U1635.T1 U1636.A2 U1636.A8 U1636.B2 U1636.C9 U1636.D2 U1636.D8 U1636.E1 U1636.E3 U1636.E8 U1636.E9 U1636.F1 U1636.G8 U1636.H1 U1636.H9 U1636.K1 U1636.K9 U1636.M9 U1636.N1 U1636.T1 U1637.A2 U1637.A8 U1637.B2 U1637.C9 U1637.D2 U1637.D8 U1637.E1 U1637.E3 U1637.E8 U1637.E9 U1637.F1 U1637.G8 U1637.H1 U1637.H9 U1637.K1 U1637.K9 U1637.M9 U1637.N1 U1637.T1 U1638.A2 U1638.A8 U1638.B2 U1638.C9 U1638.D2 U1638.D8 U1638.E1 U1638.E3 U1638.E8 U1638.E9 U1638.F1 U1638.G8 U1638.H1 U1638.H9 U1638.K1 U1638.K9 U1638.M9 U1638.N1 U1638.T1 USB2R1.4 USB2R1.S1 USB2R1.S2 USB2R1.S3 USB2R1.S4 USB2R2.4 USB2R2.S1 USB2R2.S2 USB2R2.S3 USB2R2.S4 USB3R1.4 USB3R1.7 USB3R1.H1 USB3R1.H2 USB3R1.H3 USB3R1.H4 WIFI1.1 WIFI1.5 Y1.2 Y1.4 Y6.2 Y6.4
GND_CLK: CN4.1 R578.1
GND_CN: BAT1.10 BAT1.11 R15.1 R16.1
GND_DAT: CN4.2 R579.1
GND_OZ8690: C12.2 C17.1 C21.1 C25.1 C371.1 PJP2.1 R401.1 R412.2 U1.5 U1.35 U1.42
GND_SIGNAL: C3658.2 C3659.2 C3660.1 C3671.1 C3673.1 C3674.1 C3686.2 C3687.2 C3692.1 C3693.1 PJP36.1 R648.1 R3415.1 RT6.1 RT7.1 U109.41
P1.24V_AUX_LX: L23.1 R264.1 U32.3
SVDD: C493.1 U1634.B7
TP_EN/+2.5VS_ON: CN7.14 R645.1 U25.119
V1.00A: B3.2 C142.1 C144.1 C152.1 C154.2 C169.1 C170.1 C432.2 C492.1 C504.1 C511.1 C620.1 C3708.1 L8.1 R110.1 R143.1 R147.1 R153.1 R476.1 R480.1 R481.1 R486.1 R487.1 R488.1 R504.1 R505.1 R521.1 U11.AF18 U11.AF19 U11.V20 U11.V21 U14.1 U14.2 U14.6 U14.7
V1.00A_BOOT: R671.2 U12.10
V1.00A_BOOT1: C563.1 R671.1
V1.00A_CS: C529.1 R669.1 U12.2
V1.00A_EN: C519.1 R576.2 U12.3
V1.00A_FB: C142.2 R110.2 R112.1 U12.4
V1.00A_LG: C332.1 Q48.4 U12.6
V1.00A_LX: C563.2 L8.2 Q47.1 Q47.2 Q47.3 Q48.5 Q48.6 Q48.7 Q48.8 Q48.S1 R549.1 U12.8
V1.00A_RF: C573.1 R599.1 R668.1 U12.5
V1.00A_SN: C496.1 R549.2
V1.00A_UG: R672.2 U12.9
V1.00A_VDD: C571.1 R670.1 U12.7
VCCEOPIO_SENSE: TP51.1 U11.AL63
VCCGT_SENSE: R3255.1 R3439.1 U11.J70
VCCGTX_SENSE: TP60.1 U11.AK62
VCCIO_SENSE: TP53.1 U11.AM23
VCCOPC_1P8: R501.2 U11.G61 U11.H63
VCCOPC_SENSE: TP63.1 U11.AC63
VCCRTCEXT: C374.2 U11.BB10
VCCSA_SENSE: R3250.1 R3434.1 U11.H20
VCCST_PWRGD: R85.1 R528.1 U25.80
VCCST_PWRGD_R: R85.2 R403.2 U11.B65
VDDA: C3671.2 R3407.1 R3408.1 R3410.1 U109.1
VDDIO: C490.1 R697.2 U1634.D3
VDDQC: C404.2 R469.2 U11.AM40
VIN: B4.1 C8.1 C9.1 C10.1 C89.1 C90.1 C92.1 C94.1 C135.1 C137.1 C139.1 C153.1 C155.1 C163.1 C166.1 C189.1 C190.1 C192.1 C193.1 C614.2 C616.1 D1.C JP10.2 JP13.2 JP14.2 Q47.5 Q47.6 Q47.7 Q47.8 Q47.S1 R210.1 R228.1 R311.1 R313.2 R314.2 R511.2 R638.1 R3403.2 U1.6 U1.21 U1.22 U1.23 U1.24 U1.25 U1.43 U9.1 U13.21 U13.22 U13.23 U13.24 U13.33 U18.1
VIN_CPU_CORE: C570.1 C575.1 C577.1 C590.1 C632.1 JP10.1 Q43.5 Q43.6 Q43.7 Q43.8 Q60.5 Q60.6 Q60.7 Q60.8
VIN_CPU_VCCGT: C566.1 C579.1 C584.1 C588.1 C628.1 C629.1 JP13.1 Q45.5 Q45.6 Q45.7 Q45.8
VIN_CPU_VCCSA: C214.1 C559.1 C562.1 JP14.1 Q41.5 Q41.6 Q41.7 Q41.8 Q41.S1
VIN_LCD: C180.1 C181.1 C182.2 CN7.1 CN7.2 CN7.3 CN7.4 CN7.S1 Q14.D R273.2
VIN_LCD_IN0: B4.2 Q14.S R182.2 R189.1
VSSEOPIO_SENSE: TP59.1 U11.AJ62
VSSGT_SENSE: R3258.2 R3442.1 U11.J69
VSSGTX_SENSE: TP58.1 U11.AL61
VSSIO_SENSE: TP52.1 U11.AM22
VSSOPC_SENSE: TP62.1 U11.AE63
VSSSA_SENSE: R3251.1 R3436.1 U11.H21
+0.675_DDR_EN: C258.1 Q56.D R321.2 R3198.1 U13.5
+CPU_CORE: C104.1 C105.1 C109.1 C113.1 C134.1 C136.1 C400.1 C409.1 C412.1 C420.1 C436.1 C437.1 C442.1 C444.1 C447.1 C452.1 C459.1 C468.1 C533.1 C555.1 C556.1 C558.1 C565.1 C583.1 C589.1 C593.1 C615.1 C3710.1 C3711.1 L27.2 L31.2 PJP18.1 R99.2 R102.1 R3153.2 R3422.1 RT1.2 U11.A30 U11.A34 U11.A39 U11.A44 U11.AK33 U11.AK35 U11.AK37 U11.AK38 U11.AK40 U11.AL33 U11.AL37 U11.AL40 U11.AM32 U11.AM33 U11.AM35 U11.AM37 U11.AM38 U11.G30 U11.G32 U11.G33 U11.G35 U11.G37 U11.G38 U11.G40 U11.G42 U11.J30 U11.J33 U11.J37 U11.J40 U11.K33 U11.K35 U11.K37 U11.K38 U11.K40 U11.K42 U11.K43
+CPU_VCCGT: C93.1 C97.1 C414.1 C421.1 C422.1 C424.1 C425.1 C426.1 C427.1 C445.1 C449.1 C450.1 C453.1 C454.1 C455.1 C456.1 C564.1 C591.1 C594.1 C3709.1 L28.2 PJP17.1 R3163.2 R3164.1 R3255.2 R3446.2 RT2.2 U11.A58 U11.A62 U11.A66 U11.AA63 U11.AA64 U11.AA66 U11.AA67 U11.AA69 U11.AA70 U11.AA71 U11.AC64 U11.AC65 U11.AC66 U11.AC67 U11.AC68 U11.AC69 U11.AC70 U11.AC71 U11.AK53 U11.AK55 U11.AK56 U11.AK58 U11.AK60 U11.AK70 U11.AL53 U11.AL56 U11.AL60 U11.AM53 U11.AM56 U11.AM58 U11.AU58 U11.AU63 U11.BB57 U11.BB66 U11.J53 U11.J55 U11.J56 U11.J58 U11.J60 U11.K53 U11.K55 U11.K56 U11.K58 U11.K60 U11.L62 U11.L63 U11.L64 U11.L65 U11.L66 U11.L67 U11.L68 U11.L69 U11.L70 U11.L71 U11.M62 U11.N63 U11.N64 U11.N66 U11.N67 U11.N69 U11.N70 U11.N71 U11.R63 U11.R64 U11.R65 U11.R66 U11.R67 U11.R68 U11.R69 U11.R70 U11.R71 U11.T62 U11.U65 U11.U68 U11.U71 U11.W63 U11.W64 U11.W65 U11.W66 U11.W67 U11.W68 U11.W69 U11.W70 U11.W71 U11.Y62
+CPU_VCCGTXR42: C378.1 C380.1 C390.1 C401.1 C415.1 C416.1 C428.1 C430.1 PJP17.2 PJP18.2 U11.A48 U11.A53 U11.AK42 U11.AK43 U11.AK45 U11.AK46 U11.AK48 U11.AK50 U11.AL43 U11.AL46 U11.AL50 U11.AM48 U11.AM50 U11.AM52 U11.J43 U11.J45 U11.J46 U11.J48 U11.J50 U11.J52 U11.K48 U11.K50
+VSDIO: C213.1 C231.1 C234.1 C418.2 EC1.2 Q54.S R173.2 R245.1 R283.2 R473.2 R561.1 U11.AD15 U23.6
+VSDIO_EN: C228.2 R287.1 U23.2
+VSDIO_R: Q54.D R167.2 R171.2 R177.2 R179.2 R258.2 R475.2
AC_IN+: B7.1 C277.1 C278.1 DCIN1.1
ACZ_BITCLK: C520.2 R407.2 U11.AY22
ACZ_BITCLK_CODEC: R407.1 R564.1
ACZ_RST#: R406.2 U11.AW22
ACZ_RST#_CODEC: C500.2 R406.1 U33.11
ACZ_SDATAIN0: R540.1 U11.BA21
ACZ_SDATAOUT_CODEC: C498.2 R409.1 U33.5
ACZ_SDOUT: R408.1 R409.2 U11.BB22
ACZ_SPKR: C487.2 R460.2 U11.AW5
ACZ_SPKR_B1: C486.1 C487.1 R547.2
ACZ_SPKR_B2: C499.2 C513.1 R546.2 R547.1
ACZ_SYNC: R410.2 U11.BA22
ACZ_SYNC_CODEC: C514.2 R410.1 U33.10
ADAP_IN: C25.2 C235.1 Q17.2 R18.1 R412.1 U1.36 U25.18
ADAP_IN_R: Q17.4 R18.2 R362.2 U11.AY15
ADAPTOR_I: C6.1 C21.2 R10.1 R25.1
ADR0: R58.2 R61.1 U1634.B2
ADR1: R62.2 R64.1 U1634.D2
ALRTB_R: R647.2 U109.7
AMP_MUTE#: R541.1 U25.20
ANT1: C508.1 U1634.G7
ANT2: C506.1 U1634.G6
AP6234_UART_RXD: R581.2 WIFI1.9
AP6234_UART_TXD: R582.2 WIFI1.10
APU_LCDVDD_EN_G: C273.1 Q25.2 R327.2 R331.2
AUX_OFF: C107.2 Q6.C Q16.5 R99.1
BAT1C: BAT1.6 C26.1 R27.2 S28.1
BAT1D: BAT1.7 C22.1 R23.2 S27.1
BAT+: B12.1 B13.1 BAT1.1 BAT1.2 BAT1.3 BAT1.4 BAT1.5 C438.1 R507.1 R509.2
BAT_D: D4.2 R90.1
BAT_I: C435.1 R485.1 U25.70
BAT_SMBCLK: R14.1 R27.1 R36.1 U25.110
BAT_SMBDAT: R13.1 R23.1 R37.1 U25.111
BAT_V: C473.1 Q36.D R507.2 R516.1 U25.73
BAT_V_ON#: C469.1 Q35.G Q36.G Q37.D R509.1 R510.1
BATT-: BAT1.12 BAT1.13 BAT1.14 D19.1 D19.2 R16.2 R514.2 RCH1.2
BATT_DUMP(ROM_PWR): BAT1.8 C18.1 Q35.D S26.1
BATT_TEMP: BAT1.9 C16.1 R21.2 S25.1 U25.71
BATT_VA_OFF#: Q27.2 R352.2 U25.25
BL_DETECT: U11.R12 U25.30
BL_ON: C215.1 C284.1 CN7.20 D6.A R239.2 R244.2
BL_PWM: CN7.21 R250.2 R260.2 R268.2
BPM#0: TP13.1 U11.C55
BPM#1: TP14.1 U11.D55
BPM#2: TP15.1 U11.B54
BPM#3: TP71.1 U11.C56
BST: C364.2 D18.C U1.26
BST1: C3696.1 D42.C U110.1
BST2: C3705.1 D41.C U110.16
BSTA2: C3683.1 D34.C R648.2 U109.25
BT_HOST_WAKE: R596.2 U25.88
BT_ON: R52.2 R54.1 R249.2 R3253.1 U25.82
BT_WAKE: R601.2 U25.69
BTL_BEEP: C486.2 U25.28
CAP+: C546.1 U33.36
CAP-: C546.2 U33.35
CARD_3V3: C242.2 C524.1 C527.1 CRDR1.6 Q40.D R55.2 R550.1 R595.2
CHG_LX: C364.1 D1.A L1.2 R26.2 U1.27 U1.33 U1.34 U1.41
CHG_R_LED: C272.1 LED1.1 R325.2 R334.2
CHG_REF: C461.1 R494.2 U25.81
CLICK_CLK: CN4.4 R594.1 TP3.1
CLICK_DATA: CN4.5 R590.1 TP2.1
CLICK_PAD_+3.3V: C525.1 CN4.6 R583.2
CLK_EC_LPC: CN8.6 R161.2 U25.13
CLK_EC_LPC_R: C343.2 R382.1 U28.21
CLK_EC_LPC_SOC: R161.1 U11.AW9
CLK_LAN_REQ3#: R421.2 U11.AT10
CLK_PCIE_LAN_DN3: SBCN2.11 U11.D40
CLK_PCIE_LAN_DP3: SBCN2.10 U11.C40
CLK_PCIE_SSD_DN: CN13.53 U11.E40
CLK_PCIE_SSD_DP: CN13.55 U11.E38
CLK_PCIE_WLAN_DN: CN14.49 U11.B40
CLK_PCIE_WLAN_DP: CN14.47 U11.A40
CLK_REQ: R741.2 U1634.A2
CLK_TPM: R159.2 R382.2
CLK_TPM_SOC: R159.1 U11.AY9
CODEC_BITCLK: C510.2 R564.2 U33.6
CODEC_DIN: R540.2 U33.8
CODEC_GND: AB4.2 AB11.2 AB12.2 AB13.2 AB14.2 AB16.1 AC7.2 AC8.2 AR8.2 AR12.2 C253.2 C255.1 C256.2 C540.1 C541.2 C542.2 C543.2 C544.2 C545.1 C547.2 C548.1 C549.1 C550.2 U33.26 U33.37
CODEC_PCBEEP: C513.2 U33.12
COMP_OZ8690: R9.2 U1.9
CORE_VID0: TP49.1 U11.AN11
CORE_VID1: TP48.1 U11.AN13
CPPE#: R32.1 R371.1 U25.33
CPU_PROCHOT#: R3160.2 R3527.1 U109.9
CSNA: C3658.1 C3685.1 C3688.1 R3409.2 R3422.2
CSNA_GT: R3409.1 U109.35
CSNB: C3692.2 C3706.1 C3720.1 R3430.2 R3446.1
CSNB_VCORE: R3430.1 U109.15
CSNC: C3686.1 C3715.1 C3721.1 R3428.2 R3451.1
CSNC_SA: R3428.1 U109.13
CSPA: C3659.1 C3685.2 C3688.2 R3417.1 R3421.2 R3431.2 U109.34
CSPB: C3693.2 C3706.2 C3720.2 R3444.1 R3445.2 U109.16
CSPC: C3687.1 C3715.2 C3721.2 R3449.1 R3450.2 U109.14
D+_M: L25.4 R548.2 WIFI1.6
D-_M: L25.1 R539.2 WIFI1.7
DC_IN: C323.1 C362.2 Q34.5 Q34.6 Q34.7 Q34.8 Q34.S1 R20.2 R366.1 R419.2
DC_IN+: B7.2 C260.1 C264.1 C268.1 C269.2 D23.2 Q31.1 Q31.2 Q31.3 R1.1 R2.1 R330.2
DC_IN_B: C356.2 D16.A Q31.5 Q31.6 Q31.7 Q31.8 Q31.S1 R17.2 R29.1 R419.1
DDPC_CTRLCLK: TP67.1 U11.N7
DDPC_CTRLDATA: TP66.1 U11.N8
DDPD_CTRLCLK: TP64.1 U11.N11
DDPD_CTRLDATA: TP65.1 U11.N12
DDR0_A_ALERT#: R364.2 TA18.1 TB19.1 TC19.1 U11.AW50 U1635.P9 U1636.P9 U1637.P9 U1638.P9
DDR0_A_MD_PAR: R363.2 TA23.1 TB22.1 TC23.1 U11.AT52 U1635.T3 U1636.T3 U1637.T3 U1638.T3
DDR1_B_ALERT#: CN11.116 U11.AN43
DDR1_B_PARITY: CN11.143 U11.AP43
DDR4_DRAMRST: R395.2 U11.AT13
DDR4_DRAMRST#: C3934.2 CN11.108 R395.1 R399.1 TP1.1 U1635.P1 U1636.P1 U1637.P1 U1638.P1
DDR_RCOMP0: R436.2 U11.AR18
DDR_RCOMP1: R422.2 U11.AT18
DDR_RCOMP2: R438.2 U11.AU18
DDR_VREF_CA: C77.2 R70.2 U11.AY67
DDR_VTT_CNTL: R3201.2 U11.AW67
DDR_VTT_CNTL_D: Q55.B R3201.1
DMIC_CLK: ER2.2 U33.3
DMIC_CLK_R: C147.1 CN7.24 ER2.1
DMIC_DATA: ER1.2 U33.2
DMIC_DATA_R: C146.1 CN7.25 ER1.1
DSW_PWER_EN: R340.1 U25.29
DSW_PWROK: R356.1 U25.107
DSW_PWROK_R: C325.2 R356.2 R358.1 R413.2 U11.BB20
DWL_REQ: R745.2 U1634.A1
E-USB-N: D9.2 L12.4 R288.1 S51.1 USB3R1.2
E-USB-P: D9.1 L12.1 R289.1 S53.1 USB3R1.3
EAPD/COMBO_JACK: AR10.2 C532.2 R533.2
EC_3.3VA: B2.2 C7.1 C29.1 C33.1 C36.2 C39.1 U25.26 U25.50 U25.92 U25.114 U25.121 U25.127
EC_BL_ON: D6.C R244.1 U25.76
EC_BL_PWM: R56.1 R57.2 R268.1 U25.95
EC_EXTSMI#: R374.1 U11.L6 U25.15
EC_PECI: R105.1 U25.117
EC_PROCHOT#: R3161.2 U25.77
ECSCI#: R375.1 R376.1 U25.23
EDP_AUXN: C218.1 U11.E45
EDP_AUXN_R: C218.2 CN7.27
EDP_AUXP: C222.1 U11.F45
EDP_AUXP_R: C222.2 CN7.28
EDP_DISP_UTIL: R263.2 U11.B52
EDP_HPD_CN: CN7.22 R347.2
EDP_R_D0+: C233.2 CN7.31
EDP_R_D0-: C230.2 CN7.30
EDP_R_D1+: C227.2 CN7.34
EDP_R_D1-: C225.2 CN7.33
EDP_RCOMP: R493.2 U11.E52
EDP_TXN0: C230.1 U11.C47
EDP_TXN1: C225.1 U11.D46
EDP_TXP0: C233.1 U11.C46
EDP_TXP1: C227.1 U11.C45
FAN_CTRL0: R397.1 U2.4 U25.78
FAN_SPEED: C5.1 CN3.3 U2.3
FB_3.3_EN: R60.1 R838.2 R840.2 R842.1 U9.12
FB_5_EN: R231.1 R839.2 R841.2 R843.1 U18.12
G_ADDR: R225.2 R229.1 U19.7
G_INT1: R242.1 R243.1 U11.AD3
G_INT2: R241.1 U11.AD4
G_INT_1: R241.2 R242.2 U19.11
G_INT_2: R243.2 U19.9
G_SCL: R213.2 R214.2 U19.4
G_SDA: R216.2 R218.2 U19.6
G_VIO: C201.1 C206.1 R217.2 U19.1
GPP_B4: TP39.1 U11.AY5
GPP_B15: R437.2 U11.AN8
GPP_B16: R454.2 U11.AP7
GPP_B17: R448.2 U11.AP8
GPP_B18: R451.2 U11.AR7
GPP_B19: R467.2 U11.AM5
GPP_B20: R443.2 U11.AN7
GPP_B21: R464.2 U11.AP5
GPP_B22: R466.1 U11.AN5
H_A20GATE: R35.1 U25.126
H_CATERR#: R95.1 U11.D63
H_CPUPWRGD: R79.1 U11.A68
H_PECI: R105.2 U11.A54
H_PROCHOT#_D: R82.2 U11.C65
H_RCIN#: R424.1 U11.AW13 U25.4
H_THRMTRIP#: R92.2 R94.1 U11.C63
HDMI_5V_C: B6.1 C257.1 HDMI1.18
HDMI_+5V: B6.2 PS3.1
HDMI_CLK: HDMI1.15 Q29.D R391.1
HDMI_DAT: HDMI1.16 Q32.D R400.2
HDMI_DDC_CLK: Q29.S R388.1 U11.L13
HDMI_DDC_DAT: Q32.S R396.2 U11.L12
HDMI_HPD: Q28.S R385.2 U11.L9
HDMIOUT_CLK+: HDMI1.10 L18.3
HDMIOUT_CLK-: HDMI1.12 L18.2
HDMIOUT_D0+: HDMI1.7 L19.3
HDMIOUT_D0-: HDMI1.9 L19.2
HDMIOUT_D1+: HDMI1.4 L20.3
HDMIOUT_D1-: HDMI1.6 L20.2
HDMIOUT_D2+: HDMI1.1 L21.3
HDMIOUT_D2-: HDMI1.3 L21.2
HP_GND: AB16.2 AUDR1.2 AUDR1.6
HP_JD_SENSE#: AR5.1 AR7.2
HP_JD_SENSE_MB#: AB8.1 AR5.2 Q19.S
HP_L: AR4.2 U33.32
HP_OUT_L2: AB7.2 AUDR1.4 C255.2 D14.C
HP_OUT_R2: AB17.2 AUDR1.3 C549.2 D20.C
HP_R: AR14.2 U33.33
HPD_HDMI: D15.3 HDMI1.19 Q28.D R387.1
IACM: C15.1 R20.1 U1.2
IACP: C15.2 R17.1 U1.3
ICHP: C386.1 C387.1 C388.1 C389.1 L1.1 R471.1 U1.17 U1.18 U1.19 U1.20 U1.38
INT_MIC: C521.2 C522.2 TP77.1
INT_PIRQA#: R431.2 U11.BB11
INT_SERIRQ: R389.2 R432.1 U11.AY11 U25.5 U28.27
IRQ: R740.2 U1634.D1
JACK_HP_L: AB7.1 AR4.1 C256.1
JACK_HP_R: AB17.1 AR14.1 C550.1
JACK_MIC1_R_L: AB15.1 AR10.1 AR11.1 AR12.1 AR13.1
KEY_OUT0: KBT1.24 S23.1 U25.36
KEY_OUT1: KBT1.23 S24.1 U25.37
KEY_OUT2: KBT1.22 S22.1 U25.38
KEY_OUT3: KBT1.21 S21.1 U25.39
KEY_OUT4: KBT1.20 S20.1 U25.40
KEY_OUT5: KBT1.19 S19.1 U25.41
KEY_OUT6: KBT1.18 S17.1 U25.42
KEY_OUT7: KBT1.17 S16.1 U25.43
KEY_OUT8: KBT1.16 S15.1 U25.44
KEY_OUT9: KBT1.15 S14.1 U25.45
KEY_OUT10: KBT1.14 S13.1 U25.46
KEY_OUT11: KBT1.13 S12.1 U25.51
KEY_OUT12: KBT1.12 S11.1 U25.52
KEY_OUT13: KBT1.11 S10.1 U25.53
KEY_OUT14: KBT1.10 S9.1 U25.54
KEY_OUT15: KBT1.9 S8.1 U25.55
KEYIN0: KBT1.8 S7.1 U25.58
KEYIN1: KBT1.7 S6.1 U25.59
KEYIN2: KBT1.6 S5.1 U25.60
KEYIN3: KBT1.5 S4.1 U25.61
KEYIN4: KBT1.4 S18.1 U25.62
KEYIN5: KBT1.3 S3.1 U25.63
KEYIN6: KBT1.2 S2.1 U25.64
KEYIN7: KBT1.1 S1.1 U25.65
LAN_TXN: C174.1 SBCN2.7
LAN_TXP: C177.1 SBCN2.8
LANPHYPC: R187.1 TP18.1 U11.AW17
LDRENB: U109.19 U110.8
LDRENC: U109.21 U110.9
LED2_VIN: LED2.A R577.1
LED3_VIN: LED3.A R653.1
LED_3V3: B16.2 C523.1 C526.1 SBCN1.2
LID#: LID1.3 R598.2 U25.19
LID_3V3: B17.2 C538.1 C539.1 SBCN1.3
LINE_OUT_IN#: AB8.2 AUDR1.5
LPC_AD0: CN8.9 R425.2 U25.10 U28.26
LPC_AD0_SOC: R425.1 U11.AY13
LPC_AD1: CN8.8 R427.2 U25.9 U28.23
LPC_AD1_SOC: R427.1 U11.BA13
LPC_AD2: CN8.7 R426.2 U25.8 U28.20
LPC_AD2_SOC: R426.1 U11.BB13
LPC_AD3: CN8.10 R429.2 U25.7 U28.17
LPC_AD3_SOC: R429.1 U11.AY12
LPC_FRAME#: CN8.5 R430.2 U25.6 U28.22
LPC_FRAME#_SOC: R430.1 U11.BA12
LRST1#: C340.1 R373.1 U25.14
LVDS_HPD: R346.2 R347.1 R371.2 U11.L10
LVDS_VIN: R174.2 U25.35
M2_WLAN_WAKE#: CN14.55 R3249.1 R3252.1
M_A_A0: R257.2 TA16.1 TB17.1 TC17.1 U11.AY50 U1635.P3 U1636.P3 U1637.P3 U1638.P3
M_A_A1: R266.2 TA13.1 TB12.1 TC12.1 U11.BB50 U1635.P7 U1636.P7 U1637.P7 U1638.P7
M_A_A2: R267.2 TA12.1 TB13.1 TC13.1 U11.AY51 U1635.R3 U1636.R3 U1637.R3 U1638.R3
M_A_A3: R269.2 TA10.1 TB11.1 TC11.1 U11.BA50 U1635.N7 U1636.N7 U1637.N7 U1638.N7
M_A_A4: R271.2 TA5.1 TB4.1 TC4.1 U11.BB52 U1635.N3 U1636.N3 U1637.N3 U1638.N3
M_A_A5: R272.2 TA4.1 TB5.1 TC5.1 U11.BA51 U1635.P8 U1636.P8 U1637.P8 U1638.P8
M_A_A6: R274.2 TA2.1 TB1.1 TC1.1 U11.BA52 U1635.P2 U1636.P2 U1637.P2 U1638.P2
M_A_A7: R276.2 TA1.1 TB2.1 TC2.1 U11.AW52 U1635.R8 U1636.R8 U1637.R8 U1638.R8
M_A_A8: R279.2 TA3.1 TB3.1 TC3.1 U11.AY52 U1635.R2 U1636.R2 U1637.R2 U1638.R2
M_A_A9: R281.2 TA8.1 TB9.1 TC9.1 U11.BB54 U1635.R7 U1636.R7 U1637.R7 U1638.R7
M_A_A10/AP: R335.2 TA17.1 TB16.1 TC16.1 U11.AT50 U1635.M3 U1636.M3 U1637.M3 U1638.M3
M_A_A11: R341.2 TA9.1 TB8.1 TC8.1 U11.BA54 U1635.T2 U1636.T2 U1637.T2 U1638.T2
M_A_A12/BC_N: R342.2 TA15.1 TB14.1 TC14.1 U11.AW54 U1635.M7 U1636.M7 U1637.M7 U1638.M7
M_A_A13: R343.2 TA6.1 TB7.1 TC7.1 U11.AU46 U1635.T8 U1636.T8 U1637.T8 U1638.T8
M_A_A14/WE_N: R344.2 TA7.1 TB6.1 TC6.1 U11.AT46 U1635.L2 U1636.L2 U1637.L2 U1638.L2
M_A_A15/CAS_N: R354.2 TA24.1 TB24.1 TC24.1 U11.AU48 U1635.M8 U1636.M8 U1637.M8 U1638.M8
M_A_A16/RAS_N: R345.2 TA28.1 TB27.1 TC28.1 U11.AU50 U1635.L8 U1636.L8 U1637.L8 U1638.L8
M_A_DQ0: U11.AL71 U1636.G2
M_A_DQ1: U11.AL68 U1636.J3
M_A_DQ2: U11.AN68 U1636.F7
M_A_DQ3: U11.AN69 U1636.J7
M_A_DQ4: U11.AL70 U1636.H2
M_A_DQ5: U11.AL69 U1636.H3
M_A_DQ6: U11.AN70 U1636.H8
M_A_DQ7: U11.AN71 U1636.H7
M_A_DQ8: U11.AR70 U1635.H2
M_A_DQ9: U11.AR68 U1635.J3
M_A_DQ10: U11.AU71 U1635.F7
M_A_DQ11: U11.AU68 U1635.J7
M_A_DQ12: U11.AR71 U1635.G2
M_A_DQ13: U11.AR69 U1635.H3
M_A_DQ14: U11.AU70 U1635.H7
M_A_DQ15: U11.AU69 U1635.H8
M_A_DQ16: U11.BB65 U1635.B8
M_A_DQ17: U11.AW65 U1635.C3
M_A_DQ18: U11.AW63 U1635.A3
M_A_DQ19: U11.AY63 U1635.D3
M_A_DQ20: U11.BA65 U1635.C7
M_A_DQ21: U11.AY65 U1635.C8
M_A_DQ22: U11.BA63 U1635.C2
M_A_DQ23: U11.BB63 U1635.D7
M_A_DQ24: U11.BA61 U1636.C8
M_A_DQ25: U11.AW61 U1636.D7
M_A_DQ26: U11.BB59 U1636.D3
M_A_DQ27: U11.AW59 U1636.A3
M_A_DQ28: U11.BB61 U1636.B8
M_A_DQ29: U11.AY61 U1636.C7
M_A_DQ30: U11.BA59 U1636.C2
M_A_DQ31: U11.AY59 U1636.C3
M_A_DQ32: U11.AY39 U1637.D7
M_A_DQ33: U11.AW39 U1637.C7
M_A_DQ34: U11.AY37 U1637.D3
M_A_DQ35: U11.AW37 U1637.A3
M_A_DQ36: U11.BB39 U1637.B8
M_A_DQ37: U11.BA39 U1637.C8
M_A_DQ38: U11.BA37 U1637.C3
M_A_DQ39: U11.BB37 U1637.C2
M_A_DQ40: U11.AY35 U1638.D3
M_A_DQ41: U11.AW35 U1638.C2
M_A_DQ42: U11.AY33 U1638.C8
M_A_DQ43: U11.AW33 U1638.B8
M_A_DQ44: U11.BB35 U1638.A3
M_A_DQ45: U11.BA35 U1638.C3
M_A_DQ46: U11.BA33 U1638.D7
M_A_DQ47: U11.BB33 U1638.C7
M_A_DQ48: U11.AY31 U1637.J7
M_A_DQ49: U11.AW31 U1637.H7
M_A_DQ50: U11.AY29 U1637.G2
M_A_DQ51: U11.AW29 U1637.H2
M_A_DQ52: U11.BB31 U1637.H8
M_A_DQ53: U11.BA31 U1637.F7
M_A_DQ54: U11.BA29 U1637.H3
M_A_DQ55: U11.BB29 U1637.J3
M_A_DQ56: U11.AY27 U1638.G2
M_A_DQ57: U11.AW27 U1638.H2
M_A_DQ58: U11.AY25 U1638.J7
M_A_DQ59: U11.AW25 U1638.J3
M_A_DQ60: U11.BB27 U1638.H7
M_A_DQ61: U11.BA27 U1638.H8
M_A_DQ62: U11.BA25 U1638.H3
M_A_DQ63: U11.BB25 U1638.F7
M_A_DQS0: U11.AM69 U1636.G3
M_A_DQS1: U11.AT70 U1635.G3
M_A_DQS2: U11.AY64 U1635.B7
M_A_DQS3: U11.BA60 U1636.B7
M_A_DQS4: U11.AY38 U1637.B7
M_A_DQS5: U11.BA34 U1638.B7
M_A_DQS6: U11.AY30 U1637.G3
M_A_DQS7: U11.BA26 U1638.G3
M_A_DQS#0: U11.AM70 U1636.F3
M_A_DQS#1: U11.AT69 U1635.F3
M_A_DQS#2: U11.BA64 U1635.A7
M_A_DQS#3: U11.AY60 U1636.A7
M_A_DQS#4: U11.BA38 U1637.A7
M_A_DQS#5: U11.AY34 U1638.A7
M_A_DQS#6: U11.BA30 U1637.F3
M_A_DQS#7: U11.AY26 U1638.F3
M_B_A0: CN11.144 U11.BA46
M_B_A1: CN11.133 U11.AY46
M_B_A2: CN11.132 U11.AY47
M_B_A3: CN11.131 U11.BB46
M_B_A4: CN11.128 U11.BA47
M_B_A5: CN11.126 U11.AY48
M_B_A6: CN11.127 U11.BA48
M_B_A7: CN11.122 U11.AP48
M_B_A8: CN11.125 U11.BB48
M_B_A9: CN11.121 U11.AP50
M_B_A10_AP: CN11.146 U11.AW46
M_B_A11: CN11.120 U11.AN48
M_B_A12: CN11.119 U11.AN50
M_B_A13: CN11.158 U11.BA43
M_B_A14_MB_WE#: CN11.151 U11.AY44
M_B_A15_MB_CAS#: CN11.156 U11.AY43
M_B_A16_MB_RAS#: CN11.152 U11.AW44
M_B_ACT#: CN11.114 U11.AN53
M_B_BA0: CN11.150 U11.BB44
M_B_BA1: CN11.145 U11.BA44
M_B_BG0: CN11.115 U11.AP52
M_B_BG1: CN11.113 U11.AN52
M_B_DQ0: CN11.4 U11.AF65
M_B_DQ1: CN11.7 U11.AF64
M_B_DQ2: CN11.21 U11.AK65
M_B_DQ3: CN11.16 U11.AK64
M_B_DQ4: CN11.8 U11.AF66
M_B_DQ5: CN11.3 U11.AF67
M_B_DQ6: CN11.17 U11.AK67
M_B_DQ7: CN11.20 U11.AK66
M_B_DQ8: CN11.25 U11.AF70
M_B_DQ9: CN11.29 U11.AF68
M_B_DQ10: CN11.41 U11.AH71
M_B_DQ11: CN11.38 U11.AH68
M_B_DQ12: CN11.24 U11.AF71
M_B_DQ13: CN11.28 U11.AF69
M_B_DQ14: CN11.37 U11.AH70
M_B_DQ15: CN11.42 U11.AH69
M_B_DQ16: CN11.50 U11.AT66
M_B_DQ17: CN11.46 U11.AU66
M_B_DQ18: CN11.59 U11.AP65
M_B_DQ19: CN11.63 U11.AN65
M_B_DQ20: CN11.45 U11.AN66
M_B_DQ21: CN11.49 U11.AP66
M_B_DQ22: CN11.58 U11.AT65
M_B_DQ23: CN11.62 U11.AU65
M_B_DQ24: CN11.67 U11.AT61
M_B_DQ25: CN11.71 U11.AU61
M_B_DQ26: CN11.79 U11.AP60
M_B_DQ27: CN11.83 U11.AN60
M_B_DQ28: CN11.70 U11.AN61
M_B_DQ29: CN11.66 U11.AP61
M_B_DQ30: CN11.84 U11.AT60
M_B_DQ31: CN11.80 U11.AU60
M_B_DQ32: CN11.174 U11.AU40
M_B_DQ33: CN11.170 U11.AT40
M_B_DQ34: CN11.186 U11.AT37
M_B_DQ35: CN11.182 U11.AU37
M_B_DQ36: CN11.173 U11.AR40
M_B_DQ37: CN11.169 U11.AP40
M_B_DQ38: CN11.187 U11.AP37
M_B_DQ39: CN11.183 U11.AR37
M_B_DQ40: CN11.195 U11.AT33
M_B_DQ41: CN11.191 U11.AU33
M_B_DQ42: CN11.204 U11.AU30
M_B_DQ43: CN11.208 U11.AT30
M_B_DQ44: CN11.194 U11.AR33
M_B_DQ45: CN11.190 U11.AP33
M_B_DQ46: CN11.207 U11.AR30
M_B_DQ47: CN11.203 U11.AP30
M_B_DQ48: CN11.211 U11.AU27
M_B_DQ49: CN11.215 U11.AT27
M_B_DQ50: CN11.224 U11.AT25
M_B_DQ51: CN11.228 U11.AU25
M_B_DQ52: CN11.212 U11.AP27
M_B_DQ53: CN11.216 U11.AN27
M_B_DQ54: CN11.225 U11.AN25
M_B_DQ55: CN11.229 U11.AP25
M_B_DQ56: CN11.233 U11.AT22
M_B_DQ57: CN11.237 U11.AU22
M_B_DQ58: CN11.249 U11.AU21
M_B_DQ59: CN11.245 U11.AT21
M_B_DQ60: CN11.236 U11.AN22
M_B_DQ61: CN11.232 U11.AP22
M_B_DQ62: CN11.246 U11.AP21
M_B_DQ63: CN11.250 U11.AN21
M_B_DQS0: CN11.13 U11.AH65
M_B_DQS1: CN11.34 U11.AG70
M_B_DQS2: CN11.55 U11.AR65
M_B_DQS3: CN11.76 U11.AR60
M_B_DQS4: CN11.179 U11.AR38
M_B_DQS5: CN11.200 U11.AR32
M_B_DQS6: CN11.221 U11.AR27
M_B_DQS7: CN11.242 U11.AR21
M_B_DQS#0: CN11.11 U11.AH66
M_B_DQS#1: CN11.32 U11.AG69
M_B_DQS#2: CN11.53 U11.AR66
M_B_DQS#3: CN11.74 U11.AR61
M_B_DQS#4: CN11.177 U11.AT38
M_B_DQS#5: CN11.198 U11.AT32
M_B_DQS#6: CN11.219 U11.AR25
M_B_DQS#7: CN11.240 U11.AR22
M_VREF_CA_MD0: C81.2 C82.2 C85.1 R70.1 R71.2 R73.1 U1635.M1 U1636.M1 U1637.M1 U1638.M1
M_VREF_CB_DIMM0: C78.2 C79.1 C80.2 CN11.164 R66.1 R67.2 R68.1
MA_ACT_N: R361.2 TA29.1 TB29.1 TC29.1 U11.BA55 U1635.L3 U1636.L3 U1637.L3 U1638.L3
MA_BA0: R357.2 TA14.1 TB15.1 TC15.1 U11.AU52 U1635.N2 U1636.N2 U1637.N2 U1638.N2
MA_BA1: R360.2 TA11.1 TB10.1 TC10.1 U11.AT48 U1635.N8 U1636.N8 U1637.N8 U1638.N8
MA_BG0: R355.2 TA21.1 TB20.1 TC20.1 U11.AY55 U1635.M2 U1636.M2 U1637.M2 U1638.M2
MA_CKE0: R93.2 TA20.1 TB18.1 TC18.1 U11.BA56 U1635.K2 U1636.K2 U1637.K2 U1638.K2
MA_CLK0: R81.2 TA26.1 TB26.1 TC26.1 U11.AT53 U1635.K7 U1636.K7 U1637.K7 U1638.K7
MA_CLK#0: R87.2 TA25.1 TB25.1 TC25.1 U11.AU53 U1635.K8 U1636.K8 U1637.K8 U1638.K8
MA_CS#0: R140.2 TA19.1 TB21.1 TC21.1 U11.AU45 U1635.L7 U1636.L7 U1637.L7 U1638.L7
MA_ODT0: R256.2 TA22.1 TB23.1 TC22.1 U11.AT45 U1635.K3 U1636.K3 U1637.K3 U1638.K3
MB_CKE0: CN11.109 U11.AN56
MB_CKE1: CN11.110 U11.AP55
MB_CLK0: CN11.137 U11.AP45
MB_CLK1: CN11.138 U11.AP46
MB_CLK#0: CN11.139 U11.AN45
MB_CLK#1: CN11.140 U11.AN46
MB_CS#0: CN11.149 U11.BB42
MB_CS#1: CN11.157 U11.AY42
MB_ODT0: CN11.155 U11.BA42
MB_ODT1: CN11.161 U11.AW42
ME_WE#: Q30.G R32.2
MIC1_JD_SENSE#: AR3.1 AR6.2
MIC1_JD_SENSE#_0: AR3.2 Q19.D
MIC1_JD_SENSE_MB#: AR15.1 C253.1 Q19.G
MIC1_L: AC4.1 U33.21
MIC1_R: AC6.1 U33.22
MIC1_VREF_L: AR13.2 U33.31
MIC2_L: C521.1 U33.16
MIC2_R: C522.1 U33.17
MIC2_VREFO: TP78.1 U33.29
MIC_JD_IN#: AB15.2 AR15.2 AUDR1.1 C548.2 D21.C
MSATA_MPCIE_DET_N: R3294.2 R3386.2 U11.G4
MUTE: R534.1 R541.2 U33.4
NFC_CLK_REQ: R741.1 U11.BA8
NFC_DWL_REQ: R745.1 U11.U7
NFC_EN: R742.1 U11.AY8
NFC_I2C1_CLK: R738.1 U11.U9
NFC_I2C1_CLK_R: R111.1 R738.2 U1634.B1
NFC_I2C1_DATA: R739.1 U11.U8
NFC_I2C1_DATA_R: R107.1 R739.2 U1634.C1
NFC_INT#: R740.1 U11.BA7
NFC_RST: R743.1 U11.BB7
NFC_VBAT: B22.2 C333.1 C480.1 R120.2 U1634.C7 U1634.G1 U1634.G2
OZ8127_HDR11: Q43.4 R3406.2
OZ8283_HDR1: R3406.1 U109.31
OZ8283_HDR2: R3425.2 U109.24
OZ8283_HDR2R: Q60.4 R3425.1
OZ8283_HDR3: R3437.2 U110.2
OZ8283_HDR3R: Q45.4 R3437.1
OZ8283_HDR4: R3447.2 U110.15
OZ8283_HDR4R: Q41.4 R3447.1
OZ8283_LDR1: C3681.1 C3773.1 Q44.4 U109.28
OZ8283_LDR2: C3690.1 C3697.1 C3783.1 Q62.4 Q63.4 U109.27
OZ8283_LDR3: C3701.1 Q46.4 U110.5
OZ8283_LDR4: C3713.1 Q42.4 U110.12
OZ8283_LX1: C3675.2 L27.1 Q43.1 Q43.2 Q43.3 Q44.5 Q44.6 Q44.7 Q44.8 R3416.1 R3417.2 U109.32
OZ8283_LX2: C3683.2 L31.1 Q60.1 Q60.2 Q60.3 Q62.5 Q62.6 Q62.7 Q62.8 Q63.5 Q63.6 Q63.7 Q63.8 R3431.1 R3432.1 U109.23
OZ8283_LX3: C3696.2 L28.1 Q45.1 Q45.2 Q45.3 Q46.5 Q46.6 Q46.7 Q46.8 R3443.1 R3444.2 U110.3
OZ8283_LX4: C3705.2 L26.2 Q41.1 Q41.2 Q41.3 Q42.5 Q42.6 Q42.7 Q42.8 Q42.S1 R3448.1 R3449.2 U110.14
PA: C23.1 Q34.4 U1.12
PANEL_3.3V_ON: R331.1 U25.124
PANEL_DETECT: C287.1 CN7.16 R349.2 U25.67
PANEL_DETECT 2: C286.1 CN7.17 R348.2 U25.120
PANEL_VCC: CN7.18 R518.1
PCH_BL_PWM: R253.1 R260.1 R263.1
PCH_PCIE_WAKE#: R132.2 R190.2 U11.AM15
PCH_PWROK: C354.2 R392.1 R404.1 U25.86
PCH_PWROK_R: R403.1 R404.2 U11.BA20
PCH_SMB_CLK: CN11.253 Q11.1 R163.2 R214.1 R215.2
PCH_SMB_CLK_R: Q11.6 R164.1 R215.1 U11.R7
PCH_SMB_DATA: CN11.254 Q11.4 R149.2 R218.1 R453.2
PCH_SMB_DATA_R: Q11.3 R148.1 R453.1 U11.R8
PCH_SPI0_IO2: R136.2 U11.AW2
PCH_SPI_CLK: R261.2 U20.6
PCH_SPI_CLK_E: R262.2 U25.97
PCH_SPI_CLK_R: R261.1 R262.1 U11.AV2
PCH_SPI_CS#0: R223.2 U20.1
PCH_SPI_CS#0_E: R224.1 U25.96
PCH_SPI_CS#0_R: R223.1 R224.2 U11.AU3
PCH_SPI_HOLD#: R238.1 U11.AU4 U20.7
PCH_SPI_SI: R251.2 U20.5
PCH_SPI_SI_E: R252.2 U25.99
PCH_SPI_SI_R: R251.1 R252.1 U11.AV3
PCH_SPI_SO: R232.2 U20.2
PCH_SPI_SO_E: R233.1 U25.98
PCH_SPI_SO_R: R232.1 R233.2 U11.AW3
PCH_SPI_WP: R136.1 R240.2 U20.3
PCH_TCK: R104.1 U11.B56
PCH_TDI: R100.2 U11.D59
PCH_TDO: R103.2 U11.A56
PCH_TMS: R101.2 U11.C59
PCH_VRALERT#: R461.2 U11.AM11
PCH_XATL24_OUT: C133.1 R109.1 R3085.2 R3095.2 Y1.3
PCH_XTAL24_IN: C125.1 R109.2 R3058.2 R3087.2 Y1.1
PCIE_CLKREQ4#: CN14.53 R500.2 U11.AU8
PCIE_N0: TP16.1 U11.D42
PCIE_P0: TP17.1 U11.C42
PCIE_RCOMPN: R496.2 U11.F5
PCIE_RCOMPP: R496.1 U11.E5
PCIE_RXN6: C695.2 U11.G18
PCIE_RXN10: C174.2 U11.F25
PCIE_RXN11: CN13.29 U11.E28
PCIE_RXP6: C696.2 U11.F18
PCIE_RXP10: C177.2 U11.E25
PCIE_RXP11: CN13.31 U11.E27
PCIE_TXN6: C694.1 CN14.37
PCIE_TXN10: C141.1 SBCN2.14
PCIE_TXN10_C: C141.2 U11.D23
PCIE_TXN11: C3535.1 CN13.35
PCIE_TXN11_C: C3535.2 U11.D24
PCIE_TXP6: C693.1 CN14.35
PCIE_TXP10: C138.1 SBCN2.13
PCIE_TXP10_C: C138.2 U11.C23
PCIE_TXP11: C3883.1 CN13.37
PCIE_TXP11_C: C3883.2 U11.C24
PCIE_WAKE#: R133.2 U25.68
PCIE_WAKE#_CN: R132.1 R133.1 SBCN2.4
PID_1_CHG_R_LED: R322.1 R325.1 SBCN1.11 U25.24
PID_1_CHG_R_LED0: C263.1 Q22.B R322.2
PID_2_PWR_LED: R324.1 R326.1 SBCN1.8 U25.34
PID_2_PWR_LED0: C265.1 Q21.B R324.2
PID_3_RF_LED_ON#: C535.1 R625.1 SBCN1.9 U25.94
PLATFORM_ID1: R33.2 R34.1 U25.123
PLATFORM_ID2: R11.1 R12.2 U25.56
PLATFORM_ID3: R24.1 R28.2 U25.87
PLT_RST#: C623.2 CN14.52 R41.2 R134.2 R3310.1 U11.AN10 U25.22 U28.16
PLT_RST#_CN: R134.1 SBCN2.5
PM_BATLOW#: R411.2 U11.AU13
PM_CLKRUN#: R160.2 R185.1 U25.93
PM_CLKRUN#_SOC: R160.1 U11.AW11
PM_H_SLP_S0#: R435.1 U11.AT11
PM_RSMRST#: R116.2 R405.1 R414.1 U25.32
PM_RSMRST#_R: R413.1 R414.2 U11.AY17
PM_SLP_S0#: Q10.2 R117.1 R119.1 R435.2
PM_SLP_S3#: TP80.1 U11.AP15 U25.109
PM_SLP_S4#: TP83.1 U11.BA16 U25.108
PM_SLP_S5#: R416.1 U11.AY16
PM_SLP_SUS#: R442.1 U11.AN15
PM_SLP_SUS#_R: R336.1 R338.1 R442.2 R576.1 U25.83
PM_SUS_STAT#: R375.2 U11.BA11
PME#: TP42.1 U11.AU11
PMON: R3415.2 R3433.1 U109.10
PMON_20464516: R401.2 U1.4
PMUVCC: C633.1 U1634.B5
PROC_TCK: TP7.1 U11.B61
PROC_TDO: TP8.1 U11.A61
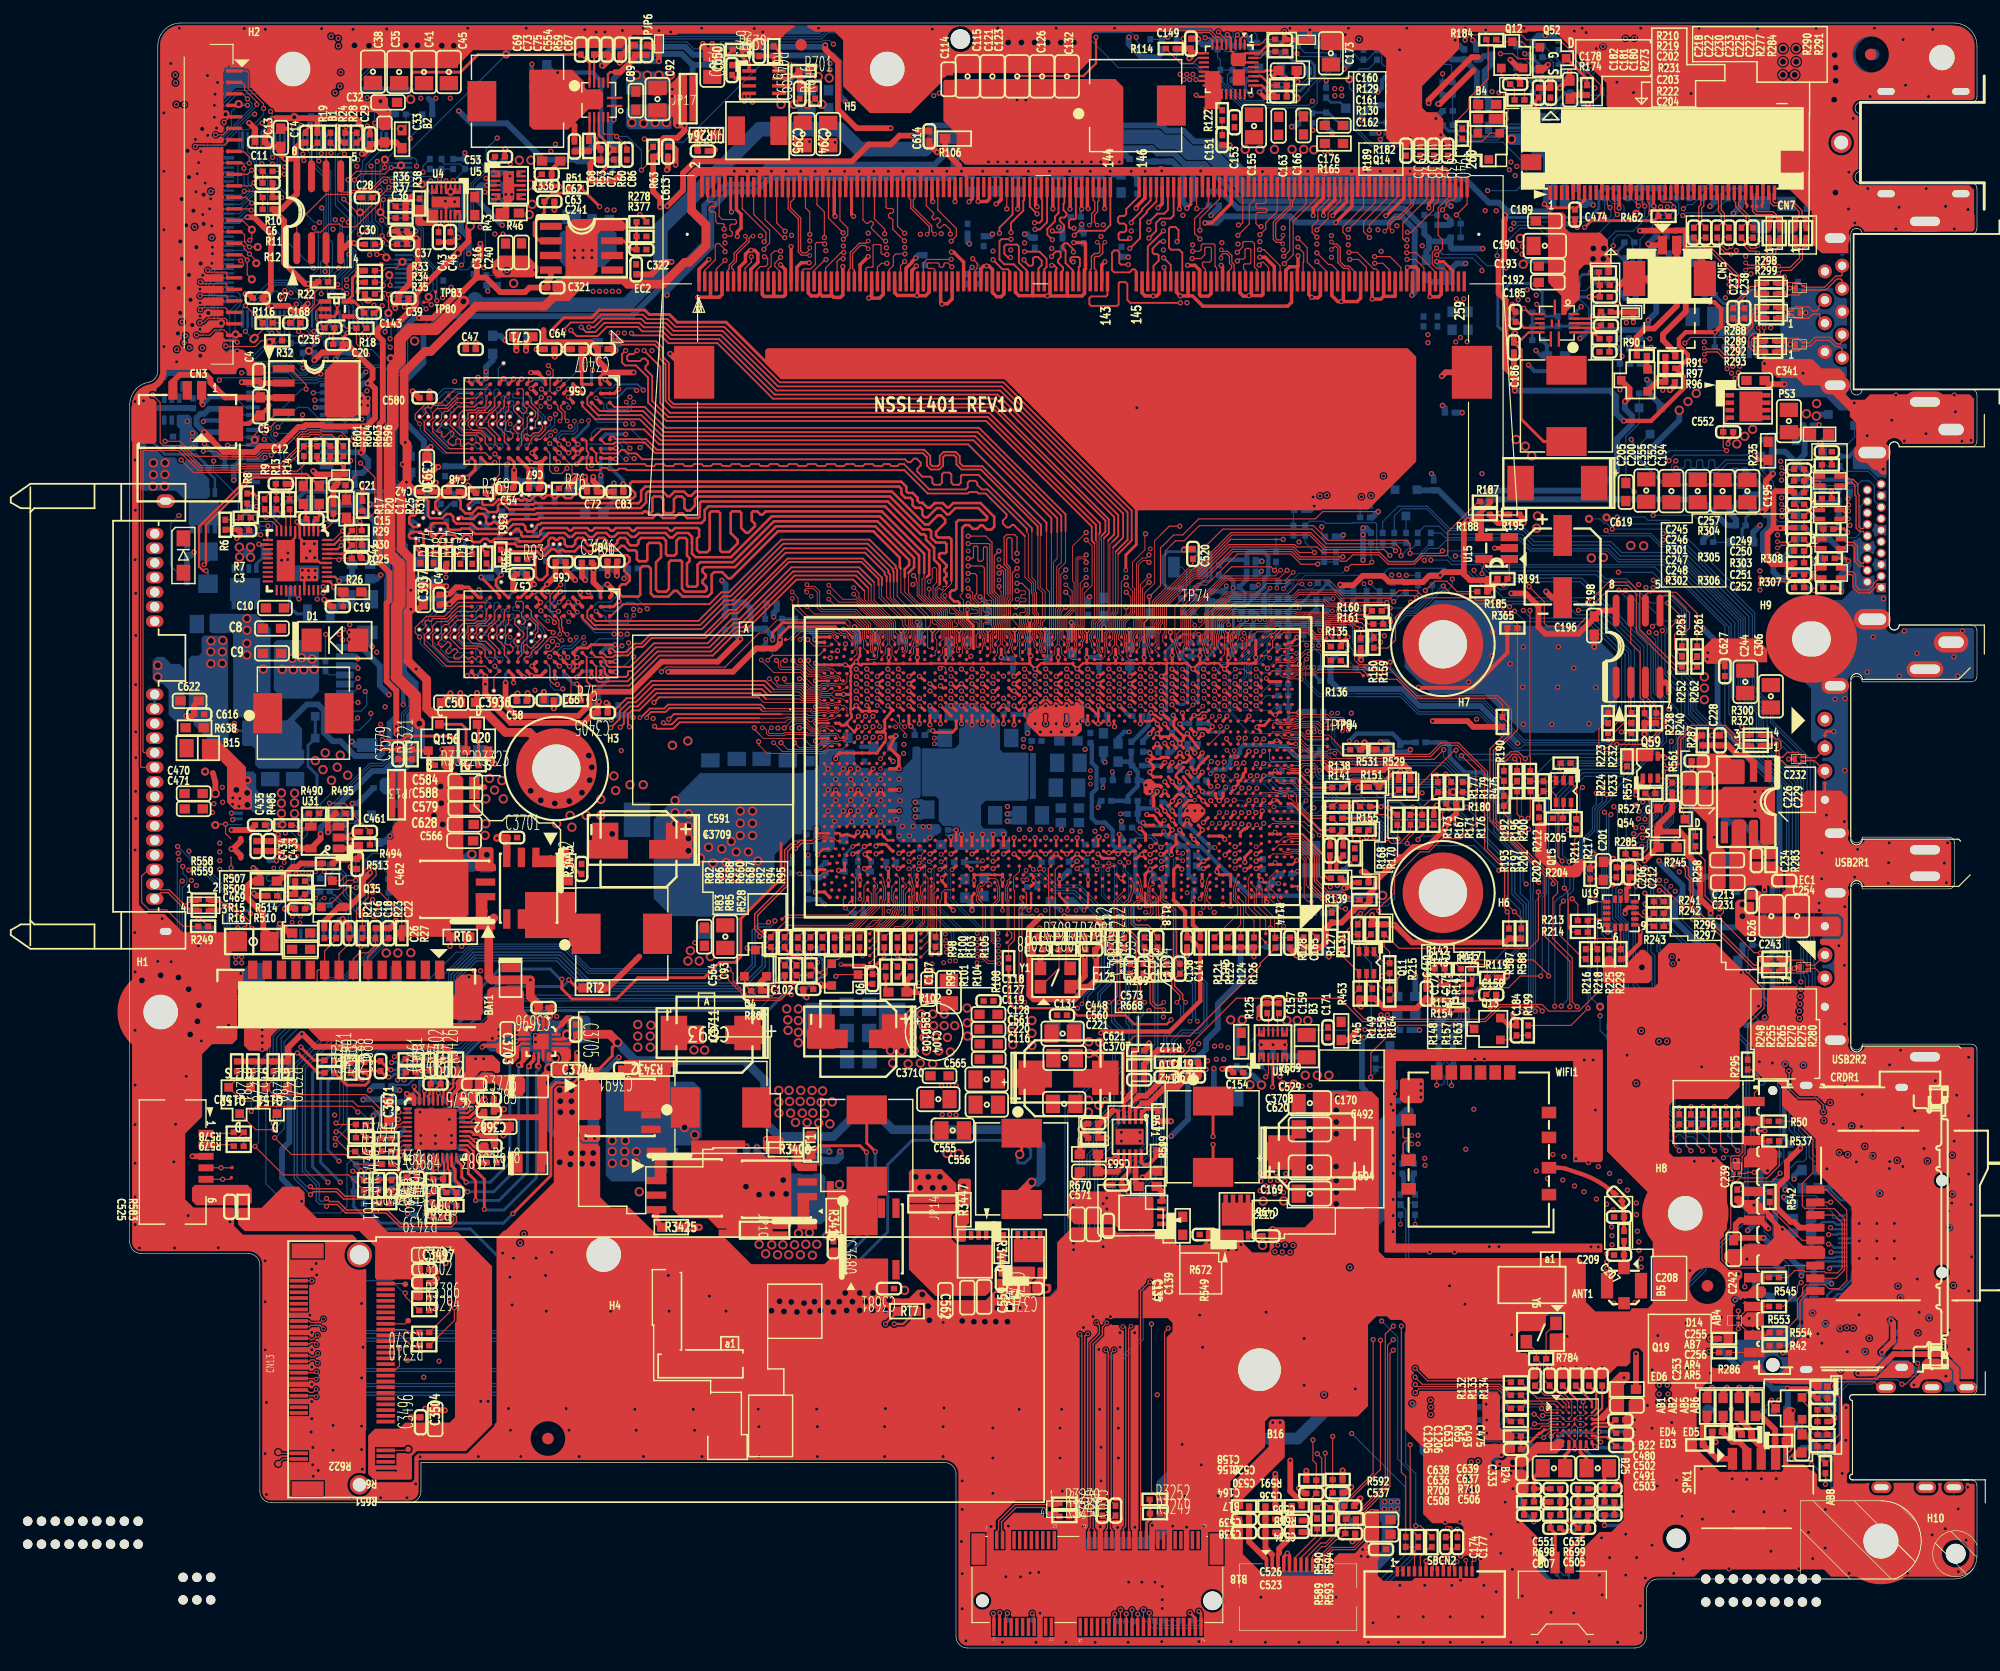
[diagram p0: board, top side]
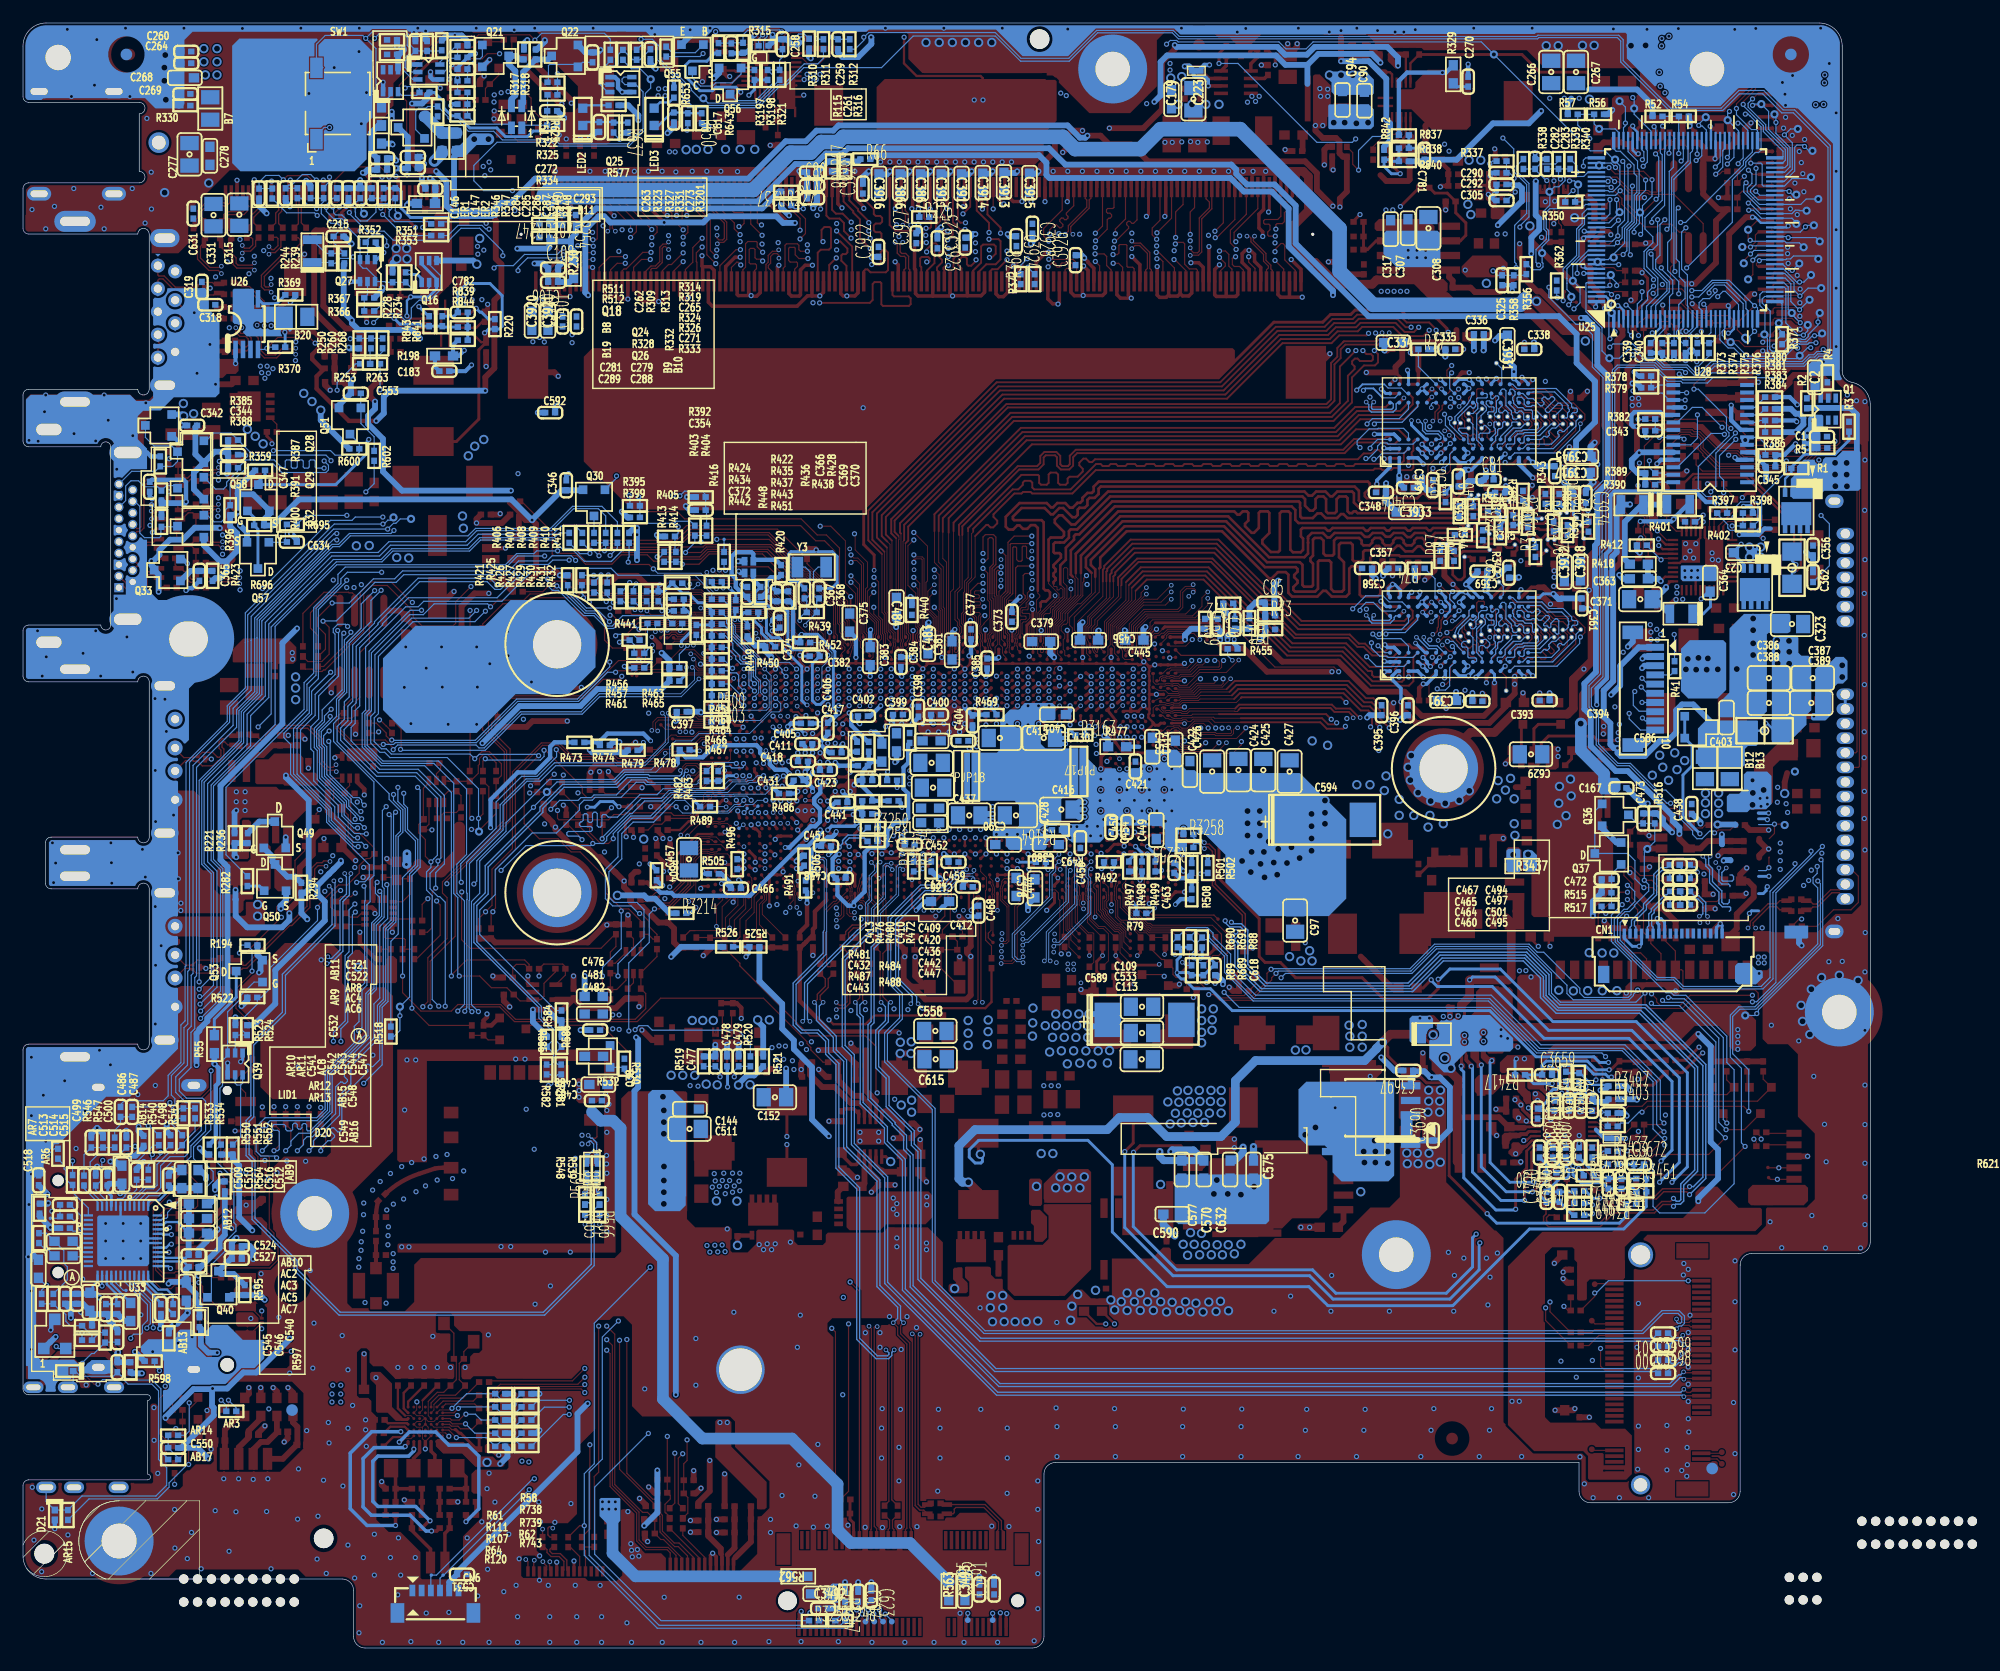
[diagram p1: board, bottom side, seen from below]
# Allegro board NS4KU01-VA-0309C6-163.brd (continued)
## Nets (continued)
PROCHOT#: Q4.D R82.1 R83.1 R402.1 R3160.1
PROCHOT#_H: R398.2 R402.2 U1.11
PSYS_H: R31.1 R3433.2 U1.40
PWMB: U109.20 U110.7
PWMC: U109.22 U110.10
PWR_B_LED: C271.1 LED1.2 R326.2 R333.2
PWR_B_LED_GND: LED1.3 Q21.C R317.1
PWR_GATE#: TP50.1 U11.AM10
PWR_R_LED_GND: LED1.4 Q22.C R318.1
PWR_REQ: R742.2 U1634.B3
PWR_USB#: R370.2 U25.48 U26.4
PWRBTN#: U11.BA15 U25.21
PWRON#: C262.1 Q18.2 Q24.2 R309.2 R313.1 S48.1 SBCN1.12 SW1.1 SW1.2
PWRSW: Q18.3 R328.1 U25.125
PWRSW_0: Q18.5 Q18.6 R511.1 R512.2
R42_XTAL24_IN: R3087.1 U11.E3
R42_XTAL24_OUT: R3095.1 U11.C7
RSNA: C3661.1 C3662.1 R3405.2 U109.37
RSNB: C3694.1 C3695.1 R3442.2 U109.18
RSNC: C3684.1 C3689.1 R3436.2 U109.11
RSP_LLA: C3662.2 R3402.1 U109.36
RSP_LLB: C3695.2 R3440.1 U109.17
RSP_LLC: C3684.2 R3429.1 U109.12
RTC_RST#: C366.1 JP11.1 R420.2 U11.AM16
RTC_X1: C367.2 R439.1 U11.AM18 Y3.1
RTC_X2: C368.2 R439.2 U11.AM20 Y3.2
RUN_ON_CPU_R: C477.1 Q10.4 R113.2 R117.2 R519.1 U14.5
RXN: C505.1 U1634.F5
RXP: C507.1 U1634.F6
SA0_DIM1: CN11.256 R246.2 R254.1
SA1_DIM1: CN11.260 R207.1 R247.2
SA2_DIM1: CN11.166 R227.2 R237.1
SAFTY_PROTECT: C1.1 Q1.2 R5.2 U25.112
SATA_5V: B15.1 C470.1 C471.1 CN1.9 CN1.10 CN1.11 CN1.12 CN1.13 CN1.14 CN1.15 CN9.P7 CN9.P8 CN9.P9
SATA_DET#: R144.1 U11.H2
SATA_ODD_PRSNT_R_N: R154.1 U11.H3
SATA_RXN0: C464.2 C501.2 U11.F20
SATA_RXN0_C: C464.1 CN1.5
SATA_RXN0_R: C501.1 CN9.S5
SATA_RXN2: C3499.1 U11.E30
SATA_RXP0: C460.2 C495.2 U11.E20
SATA_RXP0_C: C460.1 CN1.6
SATA_RXP0_R: C495.1 CN9.S6
SATA_RXP2: C3498.1 U11.F30
SATA_TXN0: C465.2 C497.2 U11.B21
SATA_TXN0_C: C465.1 CN1.3
SATA_TXN0_R: C497.1 CN9.S3
SATA_TXN2: C3500.2 R3232.1
SATA_TXP0: C467.2 C494.2 U11.A21
SATA_TXP0_C: C467.1 CN1.2
SATA_TXP0_R: C494.1 CN9.S2
SATA_TXP2: C3501.2 R3152.1
SCL_OZ8690: R14.2 U1.7
SD3_CD#: R173.1 R286.1 U11.W10
SD3_CLK: R176.2 R265.1 U11.W8
SD3_CMD: R179.1 R270.1 U11.AB11
SD3_D0: R255.1 R475.1 U11.AB13
SD3_D1: R177.1 R248.1 U11.AB12
SD3_D2: R167.1 R280.1 U11.W12
SD3_D3: R171.1 R275.1 U11.W11
SD3_PWREN0: Q39.5 Q39.6 R552.2
SD3_PWREN1: Q39.3 Q40.G Q53.G R551.2
SD3_PWREN#: Q39.2 R285.1 R522.1 R523.2 R524.2 R527.1 U11.BA9
SD3_WP: R194.2 R258.1 R295.1 U11.W7
SD_1P8_SEL: R150.2 R282.1 U11.BB9
SD_CD#_CN: CRDR1.1 R42.1 R286.2 S43.1
SD_CLK_CN: C239.2 CRDR1.7 R265.2 R542.1 S36.1
SD_CMD_CN: CRDR1.4 R270.2 R545.1 S38.1
SD_D0_CN: CRDR1.9 D7.1 R255.2 R537.1 S40.1
SD_D1_CN: CRDR1.10 D7.2 R50.1 R248.2 S39.1
SD_D2_CN: CRDR1.2 D8.2 R280.2 R554.1 S41.1
SD_D3_CN: CRDR1.3 D8.1 R275.2 R553.1 S42.1
SD_WP_CN: CRDR1.11 R295.2
SDA_OZ8690: R13.2 U1.8
SEC_BAT: C622.1 CN9.P1 CN9.P2 D23.1
SENBAT_V: R517.2 U25.31
SENBAT_V_R: C472.1 Q37.G R515.1 R517.1
SENSEA: AR6.1 AR7.1 U33.13
SHDDLED#: C534.1 R643.1 R658.2 SBCN1.10 U11.H1
SIO_I2C0_CLK: R213.1 U11.N3
SIO_I2C0_DATA: R216.1 U11.M4
SLP_A#: U11.AN16 U25.100
SM_INTRUDER#: R452.2 U11.AP16
SMB_3.3V: R148.2 R164.2 R188.2 R192.2 R193.2 R195.2
SMBALERT#: R141.1 R155.2 U11.R10
SMBCLK_C: CN7.11 R351.1
SMBCLK_EC: C37.2 Q151.D R197.2 U25.115
SMBCLK_EC_D: Q15.1 R191.2 R211.2 R351.2 R578.2 U15.1
SMBCLK_EC_S0: Q151.S R3280.2 U109.4
SMBCLK_PCH: R196.1 U11.W3
SMBCLK_PCH_EC: Q15.6 R193.1 R196.2 R197.1 R211.1
SMBDAT_C: CN7.12 R353.1
SMBDAT_EC: C30.2 Q152.D R200.2 U25.116
SMBDAT_EC_D: Q15.4 R202.2 R212.2 R353.2 R579.2 U15.5
SMBDAT_EC_S0: Q152.S R3281.2 U109.5
SMBDAT_PCH: R201.1 U11.V3
SMBDAT_PCH_EC: Q15.3 R192.1 R200.1 R201.2 R212.1
SMC_WAKE_SCI#: R376.2 R489.1 U11.N9
SML0ALERT#: R168.1 R170.2 U11.W1
SML1ALERT#: R463.2 U11.AM7
SOC_3.3V_ON: R327.1 U11.U13 U25.66
SPI_CE#: U3.1 U25.101
SPI_CLK: B1.1 C28.1 U25.105
SPI_CLK_EC: B1.2 U3.6
SPI_HOLD#: R19.1 U3.7
SPI_SI: U3.5 U25.102
SPI_SO: U3.2 U25.103
SPI_WP#: R22.1 U3.3
SPK_L+: AB6.2 ED6.1 S37.1 SPK1.4
SPK_L-: AB5.2 ED5.1 S35.1 SPK1.3
SPK_R+: AB1.2 ED3.1 S31.1 SPK1.1
SPK_R-: AB2.2 ED4.1 S32.1 SPK1.2
SPKL1+: AB6.1 U33.40
SPKL1-: AB5.1 U33.41
SPKR1+: AB1.1 U33.45
SPKR1-: AB2.1 U33.44
SRCCLKREQ0#: TP45.1 U11.AR10
SRTC_RST#: C382.1 JP12.1 R428.2 U11.AN18
SSD_CLKREQ5#: R503.2 R3370.1 U11.AU7
SSD_DET: CN13.69 R3294.1
SSD_DEVSLP: CN13.38 U11.J3
SUS_ACK#: R441.2 U25.118
SUS_ACK#_R: R441.1 R457.1 U11.AP11
SUSWARN#: R456.2 U25.79
SUSWARN#_R: R456.1 R457.2 U11.AR13
SYS_PWROK: R128.2 U25.57
SYS_PWROK_R: C165.2 R127.2 R128.1 U11.B6
SYS_RESET#: R131.1 U11.B5
TEMPA: C3673.2 R3408.2 RT7.2 U109.38
TEMPB: C3674.2 R3410.2 RT6.2 U109.39
TEST1: CN9.P6 R596.1 R603.1
TEST2: CN9.P5 R601.1 R604.1
TEST3: CN9.P13 R249.1
TESTB1/BADD: R383.1 R384.2 U28.9
TMDSB_CLK+: C246.1 U11.G56
TMDSB_CLK+_C: C246.2 L18.4 R301.2
TMDSB_CLK-: C245.1 U11.F56
TMDSB_CLK-_C: C245.2 L18.1 R304.2
TMDSB_D0+: C248.1 U11.G53
TMDSB_D0+_C: C248.2 L19.4 R302.2
TMDSB_D0-: C247.1 U11.F53
TMDSB_D0-_C: C247.2 L19.1 R305.2
TMDSB_D1+: C250.1 U11.F58
TMDSB_D1+_C: C250.2 L20.4 R303.2
TMDSB_D1-: C249.1 U11.E58
TMDSB_D1-_C: C249.2 L20.1 R306.2
TMDSB_D2+: C252.1 U11.F55
TMDSB_D2+_C: C252.2 L21.4 R307.2
TMDSB_D2-: C251.1 U11.E55
TMDSB_D2-_C: C251.2 L21.1 R308.2
TP_5V: B18.2 C528.1 C530.1 SBCN1.1
TP_CLK: C536.1 R591.2 R593.2 R594.2 U25.89
TP_CLK_CN: R593.1 SBCN1.7
TP_DATA: C537.1 R589.2 R590.2 R592.2 U25.90
TP_DATA_CN: R589.1 SBCN1.6
TP_USB_PN1_R: CN7.40 L13.3 R291.2
TP_USB_PP1_R: CN7.39 L13.2 R290.2
TX1: B24.1 U1634.G3
TX2: B25.1 U1634.G5
U22_XTAL24_IN: R3058.1 U11.E37
U22_XTAL24_OUT: R3085.1 U11.E35
UART0_CTS: R180.2 U11.AB3
UART0_RST: R584.2 U11.W4
UART0_RX: R582.1 R586.2 U11.AB1
UART0_TX: R581.1 R585.2 U11.AB2
UART2_RX: CN6.3 R588.2 TP76.1 U11.AD1
UART2_TX: CN6.4 R587.2 TP75.1 U11.AD2
UMA_DIS_DET: R142.1 R152.1 U11.U6
USB2_COMP: R482.2 U11.AB6
USB30_RX_N: L14.2 R293.2 U11.H8
USB30_RX_N_IN: D10.2 L14.1 R293.1 S54.1 USB3R1.5
USB30_RX_P: L14.3 R292.2 U11.G8
USB30_RX_P_IN: D10.1 L14.4 R292.1 S52.1 USB3R1.6
USB30_TX_N: C238.1 U11.C13
USB30_TX_N_C: C238.2 L17.2 R299.2
USB30_TX_N_IN: D13.2 L17.1 R299.1 S50.1 USB3R1.8
USB30_TX_P: C237.1 U11.D13
USB30_TX_P_C: C237.2 L17.3 R298.2
USB30_TX_P_IN: D13.1 L17.4 R298.1 S49.1 USB3R1.9
USB_5N: D12.1 L16.4 R296.1 S44.1 USB2R2.2
USB_5P: D12.2 L16.1 R297.1 S45.1 USB2R2.3
USB_5V: B20.1 U26.6 U26.7 U26.8
USB_5VOUT: B20.2 C243.1 C244.1 C254.1 C306.1 C315.1 C318.1 C319.1 C331.1 C626.1 C627.1 C631.1 USB2R1.1 USB2R2.1 USB3R1.1
USB_8N: D11.1 L29.4 R300.1 S46.1 USB2R1.2
USB_8P: D11.2 L29.1 R320.1 S47.1 USB2R1.3
USB_PN1: L12.3 R288.2 U11.AB9
USB_PN2: R566.1 R568.1 U11.AD6
USB_PN2_LGA: L25.2 R539.1 R568.2
USB_PN2_M.2: L49.3 R566.2 R3243.2
USB_PN2_W: CN14.5 L49.4 R3243.1
USB_PN4: L32.3 R559.2 U11.AD9
USB_PN4_CN_R: CN9.P15 L32.4 R559.1
USB_PN5: L16.3 R296.2 U11.AJ1
USB_PN6: L11.4 R284.2 U11.AF6
USB_PN7: L13.4 R291.1 U11.AH1
USB_PN8: L29.3 R300.2 U11.AF8
USB_PN9: TP81.1 U11.AG1
USB_PP1: L12.2 R289.2 U11.AB10
USB_PP2: R565.1 R567.1 U11.AD7
USB_PP2_LGA: L25.3 R548.1 R567.2
USB_PP2_M.2: L49.2 R565.2 R3239.2
USB_PP2_W: CN14.3 L49.1 R3239.1
USB_PP4: L32.2 R558.2 U11.AD10
USB_PP4_CN_R: CN9.P14 L32.1 R558.1
USB_PP5: L16.2 R297.2 U11.AJ2
USB_PP6: L11.1 R277.2 U11.AF7
USB_PP7: L13.1 R290.1 U11.AH2
USB_PP8: L29.2 R320.2 U11.AF9
USB_PP9: TP82.1 U11.AG2
V_ADPATER: R29.2 R30.1 U1.37
V_DDR_CB_VREF: C76.2 R66.2 U11.BA67
VAC: C363.1 R418.2 R3323.1 U1.32
VAD: C23.2 Q34.1 Q34.2 Q34.3 U1.13 U1.14 U1.15 U1.16
VB: Q16.2 Q24.3 Q27.3 Q27.6 R228.2 R234.2
VCHG: B12.2 B13.2 C403.1 C3579.2 D17.A D19.3 R8.1 R471.2 U1.39
VCLK_R: R622.2 U109.6
VCORE_ON: R621.2 U25.84
VCORE_VCCSENSE: R3153.1 R3401.1 U11.E32
VCORE_VSSSENSE: R3154.2 R3405.1 U11.E33
VDHF: C502.2 U1634.D7
VDIO_R: R651.2 U109.8
VEN: R120.1 R743.2 U1634.E1
VIDALERT#: R89.1 R647.1 R660.2 R691.1
VIDSCLK: R622.1 R687.2 R690.1 R3414.1
VIDSOUT: R88.1 R651.1 R688.2 R689.1 R3413.1
VMID: C503.1 U1634.F7
VR_EN: C586.1 R621.1 U109.2
VR_READY: R3426.1 U109.33
WB_ANTA: C207.1 WIFI1.2
WEBCAM_+5V: B8.1 B19.1 C281.1 C289.1 CN7.15
WEBCAM_ON: R462.2 R695.2 U25.104
WEBCAM_USB+: CN7.36 L11.2 R277.1 S33.1
WEBCAM_USB-: CN7.37 L11.3 R284.1 S34.1
WIFI_BT_ANT_CN: ANT1.S2 B5.2 C209.1
WIFI_BT_ANT_R: B5.1 C207.2 C208.1
WLAN_3.3VDD: C3491.1 C3492.1 C3493.1 C3494.1 C3495.1 CN14.2 CN14.4 CN14.72 CN14.74 R562.1 R563.1
WLAN_HOST_WAKE_EC: R518.2 R3252.2 U25.85
WLAN_HOST_WAKE_SOC: R365.1 R3249.2 U11.BB15
WLAN_ON: CN14.56 R199.1 R3248.2 U25.17
XDP_TCK_JTAGX: R98.1 U11.A59
XTAL_IN: C1205.2 R784.2 U1634.A3 Y6.3
XTAL_OUT: C1206.2 R784.1 U1634.C3 Y6.1
N123255: Q31.4 R1.2 R3.1
N123343: C2.1 Q1.5 Q1.6 R2.2 R4.1
N123405: Q1.3 R3.2
N123817: R378.2 R379.2 U28.15
N126703: R390.1 U28.28
N126765: R386.2 U28.7
N15641221: R381.2 U28.10
N15767439: C339.1 U25.12
N16053782: Q24.5 Q24.6 R314.1 R319.2
N17639924: Q27.5 R366.2 R367.2
N18176932: AC4.2 AR9.2 AR11.2
N18176934: AC6.2 AR9.1
N18775510: R380.2 U28.11
N18791800: R533.1 R534.2 U33.47
N20449136: R253.2 U11.R11
N20451145: TP68.1 U11.H5
N20451146: TP20.1 U11.D7
N20451156: TP74.1 U11.BA17
N20451171: R483.1 U11.AB7
N20451217: TP33.1 U11.AY21
N20451220: R108.1 U11.E42
N20451227: Q30.D R408.2
N20452140: Q11.2 R157.2
N20452178: R416.2 TP34.1
N20452276: TP29.1 U11.AU1
N20452277: TP28.1 U11.AU2
N20453875: R506.1 U11.E13
N20453885: TP47.1 U11.AP13
N20453922: TP11.1 U11.D60
N20453925: R499.2 U11.H66
N20453926: R449.2 U11.AU16
N20453927: R450.2 U11.AT16
N20453928: R498.2 U11.H65
N20453936: Q4.G R80.2 R3161.1
N20453947: C102.2 Q6.B R94.2
N20453993: TP72.1 U11.B59
N20453994: TP70.1 U11.C61
N20453995: TP19.1 U11.B7
N20453996: TP10.1 U11.C60
N20454605: R3164.2 U11.K52
N20454815: R3163.1 U11.AK52
N20465328: R455.1 U11.AY71
N20465363: R86.1 U11.C64
N20465393: R135.1 U11.AY3
N20465492: TP40.1 U11.AW71
N20465512: TP38.1 U11.AW70
N20465520: TP21.1 U11.BB3
N20465522: TP24.1 U11.AY4
N20465536: TP36.1 U11.BA68
N20465538: TP35.1 U11.BA70
N20465582: TP27.1 U11.BB5
N20465590: TP43.1 U11.AT5
N20465592: TP41.1 U11.AU5
N20465606: TP5.1 U11.BB68
N20465608: TP6.1 U11.BB69
N20465622: TP56.1 U11.AK13
N20465624: TP55.1 U11.AK12
N20465636: TP69.1 U11.E8
N20465638: R497.2 U11.F65 U11.G65
N20465664: TP4.1 U11.E68
N20465666: R492.2 U11.E60
N20465674: R502.2 U11.E70
N20477829: R6.1 R7.1 R8.2
N20477836: C3.1 R7.2 U1.10
N20477991: C462.1 R494.1 R513.1 U31.1
N20478004: R490.1 R495.1 U31.3
N20478029: R485.2 R490.2 U31.4
N20478055: R513.2 R514.1
N20478465: C371.2 D18.A U1.31
N20478537: C12.1 R9.1
N20478593: D16.C D17.C R418.1
N20478599: C17.2 R25.2 U1.1
N20478786: C19.1 R26.1
N20490831: C178.1 Q12.G R174.1
N20491024: Q14.G R184.1 R189.2
N20491118: Q12.D Q52.G R184.2
N20491230: Q25.5 Q25.6 Q26.G R332.2
N20491272: Q25.3 R323.2
N20495877: Q11.5 R158.2
N20517388: CN5.2 R90.2
N20520101: R121.1 R123.1 R124.1 R126.1 R525.1 R526.1
N20520130: R529.1 U11.AG3
N20520132: R531.1 U11.AG4
N20520144: TP12.1 U11.D56
N20520146: TP9.1 U11.D61
N20520298: TP23.1 U11.J1
N20520302: TP26.1 U11.J2
N20520326: R126.2 U11.B9
N20520328: R121.2 U11.D9
N20520330: R123.2 U11.C9
N20520332: R124.2 U11.A9
N20666125: R10.2 U25.72
N20760284: C46.2 U4.12
N20760306: C43.2 U4.10
N20760742: C479.1 R520.2 U14.3
N20760798: C157.2 U14.12
N20760802: C159.2 U14.10
N20761063: C305.1 R350.2 U5.5
N20761065: C290.1 R337.2 U5.3
N20761089: C63.2 U5.10
N20761094: C62.2 U5.12
N20806808: Q33.D R301.1 R302.1 R303.1 R304.1 R305.1 R306.1 R307.1 R308.1
N20806890: C365.2 Q33.G R423.1
N21082318: TP57.1 U11.AF13
N21109689: TP37.1 U11.AY68
N22024249: C184.2 Q13.B R199.2
N22024263: Q13.C Q38.G R530.2
N22305840: Q15.2 R205.2
N22305920: Q15.5 R204.2
N22401821: C162.2 R130.1
N22401893: C151.1 R122.2
N22401921: C261.2 R115.2 R315.1 R316.2 U13.3
N22402176: R129.2 U13.31
N22402238: R310.1 U13.8
N22402256: R114.1 U13.10
N22553007: TP79.1 U11.AH3
N22553010: TP84.1 U11.AJ3
N23119620: D4.1 R91.2 R96.1 R97.2
N25111157: R369.2 U26.5
N25464769: Q47.4 R672.1
N25488348: TP73.1 U11.L7
N25568278: R311.2 U13.7
N25568374: C160.1 U13.1
N25663816: CN8.4 R41.1
N25665640: C517.1 LED2.C R625.2 R637.1
N25665924: C617.1 LED3.C R643.2 R650.1
N25687178: R660.1 U11.B63
N25687185: R687.1 U11.A63
N25687195: R688.1 U11.D64
N25839152: CRDR2.8 R50.2
N25839155: CRDR2.7 R537.2
N25839158: CRDR2.5 R542.2
N25839161: CRDR2.3 R545.2
N25839164: CRDR2.2 R553.2
N25839167: CRDR2.1 R554.2
N25839177: CRDR2.9 R42.2
N26433249: CN9.P3 R638.2
N26482662: Q49.D R236.1
N26483213: Q49.G Q50.D R294.2
N26483218: Q50.G R282.2
N26484019: Q53.D R55.1
N26484324: Q54.G Q59.3 R285.2 R561.2
N26516302: CRDR2.4 R550.2
N26523035: Q55.C Q56.G R3197.1
N26526896: C634.2 Q57.G R695.1
N26526935: Q57.D Q58.G R696.1
N26564205: C168.1 Q17.1 R116.1
N26603686: C781.1 R837.2 R838.1
N26604940: C782.1 R839.1 R844.2
N26701011: Q52.D R273.1
N27282749: R599.2 U12.1
N27388610: Q59.5 Q59.6 R557.2
N27388676: Q59.2 R527.2
N27538533: B24.2 C551.2 C638.1 R698.2
N27538535: B25.2 C635.1 C639.1 R699.2
N27538543: C636.2 C638.2 R700.1
N27538545: C637.1 C639.2 R710.1
N27538569: C508.2 CN33.1 R700.2
N27538571: C506.2 CN33.2 R710.2
N27538743: C505.2 R699.1
N27538964: R65.1 U1634.A7
N27539034: C475.1 U1634.C6
N27539138: C491.2 U1634.E7
N27539315: C507.2 R698.1
N27647798: C3689.2 R3429.2 R3434.2
N27647889: C3675.1 D26.C U109.30
N27647893: C3660.2 R3403.1 U109.40
N27647940: R3445.1 RT2.1
N27648096: C3694.2 R3439.2 R3440.2
N27648286: C3661.2 R3401.2 R3402.2
N27648351: C3714.1 R3448.2
N27648358: R3421.1 RT1.1
N27648790: C3680.1 R3416.2
N27649020: C3691.1 R3432.2
N27719031: Q151.G R3279.2
N27719037: Q152.G R3278.2
N27740374: R3214.2 U11.U11 U11.U12
N28022357: C597.2 CN14.54 R3247.2 R3248.1 R3253.2
N28022719: CN14.50 TP188.1
N28022721: CN14.48 TP187.1
N28022723: CN14.46 TP186.1
N28022725: CN14.44 TP185.1
N28022786: CN14.16 TP184.1
N28022788: CN14.6 TP183.1
N28022853: C695.1 CN14.43
N28022855: C696.1 CN14.41
N28025825: C694.2 U11.D20
N28025828: C693.2 U11.C20
N28033617: C3501.1 CN13.49
N28033619: C3500.1 CN13.47
N28033621: C3498.2 CN13.41
N28033623: C3499.2 CN13.43
N28034069: CN13.50 R3310.2
N28034083: CN13.54 TP209.1
N28034085: CN13.52 R3370.2
N28034570: R3232.2 U11.A25
N28034572: R3152.2 U11.B25
N28172519: C3579.1 R3321.1
N28172541: Q156.B R3321.2 R3322.1
N28172556: Q20.G Q156.C
N28172573: Q20.D R3323.2
N28287409: C76.1 R69.1
N28330696: C236.1 R264.2
N28330751: R639.2 TP46.1 U32.1
N28330775: C653.2 R646.2 R701.1 U32.7
N28330789: C649.1 R645.2 U32.8
N28330811: C650.1 C654.1 JP17.2 U32.2
N28361448: C77.1 R72.1
N28363524: R74.1 U1635.F9
N28388369: R76.1 U1637.F9
N28390577: R77.1 U1638.F9
N28397978: R75.1 U1636.F9
N28437134: CN11.95 R372.2
N28437143: CN11.97 R368.2
N28576440: TC27.1 U1635.N9
N28576458: TC30.1 U1636.N9
N28576472: TC31.1 U1637.N9
N28576486: TC32.1 U1638.N9
N68041277: R397.2 U2.1
N133129643: C543.1 C544.1 U33.27
N133129783: C545.2 U33.34
N133129846: AR8.1 U33.19
N133130060: C547.1 U33.28
N276491031: C3702.1 R3443.2
N280337050: CN13.68 TP190.1
N280338137: CN13.7 TP200.1
N2803381310: CN13.10 TP189.1
N2803381313: CN13.9 TP201.1

Pads without a net: CN1 16; CN3 2; CN6 1 6; CN9 P11; CN11 87 88 91 92 100 101 104 105 162 165; CN13 6 8 20 22 23 24 25 26 28 30 32 34 36 40 42 44 46 48 56 58 59 60 61 62 63 64 65 66 67 76 77 78 79; CN14 8 9 10 11 12 13 14 15 17 19 20 21 22 23 32 34 36 38 40 42 58 59 60 61 62 64 65 66 67 68 70 71 73 76 77; HDMI1 13 14; M3 1; M4 1; M5 1; M6 1; M9 1; M10 1; M13 1; M14 1; U8 1 5; U9 4 5; U11 A3 A4 A6 A7 A11 A13 A15 A17 A19 A23 A26 A27 A29 A31 A33 A36 A38 A42 A45 A47 A50 A52 A69 AB4 AC1 AC2 AC3 AD11 AD12 AF11 AF12 AH7 AH8 AH9 AH10 AH11 AH12 AK6 AK7 AK9 AK10 AK32 AL25 AL27 AM1 AM2 AM3 AM4 AN1 AN2 AN3 AN55 AP1 AP2 AP3 AP4 AP53 AP56 AR56 AT1 AT7 AT8 AT15 AT43 AT55 AU43 AU55 AU56 AW1 AW7 AW15 AW20 AW48 AW56 AW68 AW69 AY1 AY2 AY7 AY20 AY54 AY56 B2 B3 B11 B13 B15 B17 B19 B23 B26 B27 B29 B31 B33 B36 B38 B42 B45 B47 B50 B67 B69 B70 BA3 BA4 BA5 BB2 BB4 BB17 BB56 C2 C4 C8 C11 C12 C15 C16 C17 C19 C21 C27 C28 C29 C31 C32 C33 C36 C37 C38 C41 C50 C51 C52 C54 C67 C68 C70 C71 D1 D3 D4 D5 D8 D12 D15 D16 D17 D19 D21 D27 D28 D29 D31 D32 D33 D36 D37 D38 D41 D50 D51 D52 D54 D65 D67 D68 D71 E1 E2 E10 E16 E22 E23 E43 E48 E61 E63 E66 F6 F10 F11 F15 F16 F21 F43 F46 F48 F50 F52 F60 F61 F63 F66 F70 F71 G1 G2 G3 G11 G13 G15 G16 G21 G46 G50 G68 G69 G70 G71 H6 H10 H11 H13 H16 H69 H70 J4 J5 J6 J10 J68 J71 K32 K45 K46 M1 M2 M3 N1 N2 P1 P2 P3 P4 R9 U1 U2 U3 U4 V1 V2 W2; U13 26; U15 3; U18 4 5; U19 2 3 8 10 13 15 16; U23 1 5; U25 2; U28 1 2 3 6 12 13 14; U33 14 15 18 20 23 24 30 48; U109 3; U1634 A4 A5 A6 B4 C5 D5 E3 E4 E5 E6 F1 F2 F4; U1635 T7; U1636 T7; U1637 T7; U1638 T7; WIFI1 3 4 11 12 13 14

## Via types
v1: diameter 0.711, hole 0.356, TOP to BOTTOM, 68 vias
v2: diameter 0.406, hole 0.254, TOP to BOTTOM, 450 vias
v3: diameter 0.457, hole 0.254, TOP to BOTTOM, 3173 vias
v4: diameter 0.813, hole 0.508, TOP to BOTTOM, 412 vias

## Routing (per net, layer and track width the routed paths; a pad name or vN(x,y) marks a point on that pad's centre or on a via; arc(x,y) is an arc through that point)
3.3V_LCD_S: length 3.4
  BOTTOM w1.016: Q26.S 125.56,133.17 B9.2 B10.2
5V_ON_HV: length 12.9
  TOP w0.102: Q61.4 138.49,106.41 C552.1 138.49,104.41 v3(138.78,104.12)
  BOTTOM w0.102: v3(138.78,104.12) 133.81,104.12 133.42,103.72 131.58,103.72 131.31,103.99 R600.2 131.31,104.73 Q51.D
+0.6V_DDR: length 114
  TOP w0.508: R281.1 27.48,94.21 v3(27.48,93.67) ; R269.1 30.06,100.42 v3(29.38,101.1)
  BOTTOM w0.508: C3945.2 25.89,103.88 25.57,104.2 25.57,104.95 23.92,106.6 23.92,110.14 25.52,111.74 25.52,114.25 27.08,115.81 43.61,115.81 49.94,122.13 49.94,125.42 51.77,127.26 54.18,127.26 55.1,128.17 55.1,128.56 55.53,128.99 69.95,128.99 71.37,130.41 88.85,130.41 89.3,129.96 90.76,129.96 91.69,129.04 93.41,129.04 96.66,125.79 114.42,125.79 v3(114.84,125.37)
  vias: v3(27.48,93.11) v3(30.36,94.54)
+1.00V_CPU: length 25.5
  TOP w0.203: U11.AK30 83.94,80.37 v3(84.17,80.37) ; U11.AM30 83.71,81.52 U11.AL30 ; U11.AL42 v3(77.77,81.93) 77.38,81.54 U11.AM42 77.25,81.54 v3(76.86,81.93) ; v3(84.17,80.37) 84.4,80.37 U11.AK28 ; v3(84.17,80.37) U11.AL30 ; U11.AL30 v3(84.17,81.93)
  TOP w0.254: v3(84.17,81.93) U11.AM28 ; v3(83.26,81.93) U11.AM30
  L3_IN1 w0.127: 76.14,70.24 76.35,70.44 76.35,70.93 75.97,71.3 75.81,71.3 75.51,71 75.51,70.37 75.38,70.24 76.14,70.24
  L3_IN1 w0.203: v3(77.77,81.93) 77.77,80.15 77.16,79.54 77.16,74.81 75.81,73.46 75.81,71.3
  L3_IN1 w0.254: 75.38,70.24 75.38,70.11 74.11,68.84 v2(74.11,68.46)
  BOTTOM w0.254: R493.1 73.99,68.34 v2(74.11,68.46)
  vias: v4(100.55,54.57) v4(101.47,54.57) v4(102.38,54.57)
+1.00VS_CPU: length 173.6
  TOP w0.381: R118.1 93.04,62.24 92.4,62.87 v3(92.4,64.78)
  L3_IN1 w0.381: v3(42.72,78.04) 43.3,78.04 45.68,75.66 45.68,69.65 50.16,65.16 57.73,65.16 58.87,66.3 60.62,66.3 61.57,65.36 61.57,64.19 64.74,61.02 64.74,57.44 63.97,56.66 63.97,54.79 59.14,49.96 56.31,49.96 56.28,49.94 56.02,49.94 55.04,48.96 55.04,46.22 57.71,43.55 58.85,43.55 59.64,44.34 61.8,44.34 63.11,45.64 66.19,45.64 69.98,49.44 78.89,49.44 83.65,54.2 89.82,54.2 90.16,53.86 93.04,53.86 93.67,54.49 95.55,54.49 v4(95.68,54.62) 95.68,55.97 92.54,59.11 92.54,64.64 v3(92.4,64.78)
  L4_IN2 w0.381: v3(23.77,82.03) 24.62,81.18 39.57,81.18 v3(42.72,78.04) ; v3(13.3,99.42) 13.15,99.27 v3(11.02,99.27)
  BOTTOM w0.381: R398.1 10.2,99.07 10.41,99.27 v3(11.02,99.27) ; R491.1 92.4,65.75 v3(92.4,64.78) ; v3(13.3,99.42) 13.53,99.65 14.27,99.65 15.19,100.57 22.22,100.57 22.6,100.18 22.6,95.49 22.97,95.13 22.97,92.69 22.89,92.61 22.89,84.31 23.77,83.43 v3(23.77,82.03)
  BOTTOM w0.508: v4(96.69,54.62) 96.69,54.49 96.21,54.01 R521.2
+1.2VS: length 296.5
  TOP w0.102: v3(88.61,91.42) 89.58,92.39 89.58,95.64 90.72,96.78 91.51,96.78 92.91,98.18 103.04,98.18 103.68,98.81 v3(108.5,98.81)
  TOP w0.152: U11.BB41 78.22,88.4 ; U11.BB23 88.16,87.5 88.16,89.17 88.61,89.62 v3(88.61,91.42)
  TOP w0.178: U11.BB47 74.56,87.92 74.56,87.92 74.57,88.1 74.57,88.45 v3(74.6,88.52) ; v3(72.05,88.48) 72.11,88.43 72.11,87.93 72.11,87.81 U11.BB51 ; v3(83.18,88.47) 83.18,87.51 U11.BB32
  TOP w0.203: v3(96.95,140.27) 96.88,140.27 96.5,139.89 U13.2 ; U13.28 98.6,137.07 98.7,137.16 C161.2 ; v3(83.97,140.06) 83.97,139.63 83.98,139.62 83.98,137.79 82.88,136.69 77.32,136.69 77.13,136.51 C123.1
  TOP w0.229: U1637.B9 40.98,103.44 41.69,103.44 U1637.A9
  TOP w0.254: v3(37,84.36) 36.93,84.43 U1636.G9 ; U1637.F2 37.73,109.12 v2(38.09,109.48) 38.49,109.09 U1637.E2 ; v2(38.91,90.06) 38.53,90.44 U1636.E2 38.53,90.55 v2(38.13,90.95) 37.73,90.55 U1636.F2 ; U1636.B9 40.93,84.46 v3(40.95,84.43) ; v3(42.19,87.24) 40.09,87.24 39.81,86.95 38.94,86.95 U1636.E7 38.53,86.46 v3(38.87,86.13) ; v3(37.25,103.1) 37.25,103.11 36.93,103.43 U1637.G9 ; v3(52.29,124.87) 52.22,124.93 CN11.12 ; v3(34.06,110.35) 33.73,110.02 U1637.L1 ; v3(76.86,84.48) 77.14,84.67 77.26,84.79 U11.AU42 ; U1637.E7 v3(38.96,104.66) ; v3(35.71,90.92) 35.71,90.97 U1636.J1 ; v3(62.91,124.48) 62.72,124.66 CN11.54 ; v3(38.85,102.95) 39.33,103.43 U1637.D9 ; v3(38.22,85.35) 38.18,85.35 37.78,85.75 U1636.F8 37.73,85.84 v2(37.44,86.13) 37.44,86.16 37.05,86.55 U1636.G7 ; v3(84.17,84.48) U11.AU28 ; v3(38.85,84.41) 39.33,84.89 U1636.D9 ; v3(30.09,84.46) 29.73,84.82 U1636.T9 ; v3(34.88,109.52) 35.25,109.89 U1637.J1 ; U1637.B3 40.93,108.3 v2(40.53,108.69) ; v3(29.33,101.76) 30.02,102.45 30.02,103.2 U1637.T9 ; v3(86.91,84.48) U11.AU23 ; v3(80.51,84.48) U11.AU35 ; U1636.C1 U1636.D1 39.14,91.54 v3(39.14,91.81) ; 78.22,88.4 78.21,88.42 v3(78.21,89.36) ; v3(35.13,92.48) 35.1,92.48 33.96,91.35 U1636.L1 ; v2(40.53,90.15) 40.93,89.75 U1636.B3 ; U1637.G7 37.33,104.69 v2(37.33,104.66) 37.7,104.29 U1637.F8 38.1,103.91 v3(38.14,103.91) ; U1637.D1 U1637.C1
  TOP w0.305: CN11.147 87.97,117.84 88.24,117.57 v3(88.94,117.57) 89.26,117.57 89.47,117.78 CN11.153 ; U1636.G1 36.93,91.39 37.4,91.86 37.41,91.86 v3(37.43,91.88) ; CN11.33 v3(57.47,121.86) ; v3(89.36,125.23) 89.72,125.59 CN11.154 ; U1636.J2 35.71,90.92 v3(35.71,90.92) ; U1636.R1 30.34,91.35 29.45,92.23 28.86,92.23 ; v3(42.25,103.41) 41.81,103.41 U1637.A9 ; v3(37.36,110.31) 37.34,110.29 37.33,110.29 36.93,109.89 U1637.G1 ; v3(78.86,125.32) 78.72,125.45 CN11.118 ; v3(34.88,109.52) 34.9,109.52 U1637.J2 ; v3(79.76,117.57) 81.47,117.57 81.47,117.57 ; v3(79.76,117.57) 79.97,117.78 CN11.123 ; v3(79.76,117.57) 79.74,117.59 78.47,117.59 ; CN11.124 v3(80.22,125.15) ; U1637.R1 30.27,110.15 v3(30.27,110.49) ; CN11.199 100.97,117.03 100.63,116.68 93.26,116.68 92.36,117.58 91.98,117.58 ; v3(72.94,125.76) 73.22,126.04 CN11.96 ; CN11.220 106.22,125.36 v3(104.82,123.96) ; v3(111.42,117.62) 111.47,117.67 CN11.241 ; U1636.A1 41.89,91.5 41.89,92.11 ; CN11.112 77.23,125.19 v3(77.16,125.12) ; CN11.75 67.97,119.78 v3(68.37,120.17) ; U1637.D1 39.27,109.95 39.27,111.1 ; 78.47,117.59 CN11.117 ; 78.47,117.59 77.28,117.59 76.97,117.89 CN11.111 ; CN11.141 84.47,120.27 v3(84.75,120.54) ; CN11.148 88.22,126.06 87.47,125.31 v3(87.47,125.18) ; 91.98,117.58 91.97,117.57 v3(91.29,117.57) 90.97,117.89 CN11.159 ; 91.98,117.58 CN11.163 ; CN11.142 v3(84.72,125.16) ; U1637.J8 34.97,103.92 v3(34.97,103.91) 35.33,103.55 U1637.J9 ; CN11.178 95.72,125.62 94.02,123.92 v3(93.45,123.92) ; 81.47,117.57 82.76,117.57 82.97,117.78 CN11.135 82.97,119.83 83.06,119.92 83.06,122.12 82.97,122.21 v3(82.04,122.21) ; 81.47,117.57 CN11.129 ; U1637.L9 34.77,102.45 v3(34.91,102.45) ; v3(34.27,84.42) 34.26,84.42 U1636.L9 ; v3(42.25,84.86) 41.81,84.86 U1636.A9 ; v3(41.31,110.31) U1637.A1 ; CN11.160 v3(91.22,125.13) ; U1636.J8 34.97,85.38 v3(34.97,85.37) 35.33,85.01 U1636.J9 ; CN11.136 83.22,125.23 v3(83.3,125.15) ; CN11.130 81.72,125.14 v3(81.7,125.12)
  TOP w0.356: C161.2 99.33,136.65 v3(99.12,136.65)
  TOP w0.508: C57.2 34.49,93.13 v3(35.13,92.48) ; v3(42.88,101.21) 42.89,101.2 C83.2 ; C54.2 31.84,100.87 v3(31.67,101.04) ; C49.2 27.46,91.58 v3(27.54,91.66) 27.79,91.66 28.36,92.23 28.86,92.23 ; 39.27,111.1 C56.2 39.67,112.93 v3(39.96,112.63) ; C58.2 33.63,82.92 v3(33.71,83.01) ; C65.2 37.88,93.7 v3(38.72,92.87) ; v3(41.52,93.25) C84.2 ; C67.2 34.71,102.25 v3(34.91,102.45) ; C50.2 28.73,82.22 v3(28.73,83.04) ; v3(33.61,112.83) 33.58,112.85 33.58,113.85 C71.2 ; C66.2 36.84,81.73 v3(36.86,81.7) ; v3(26.6,101.33) 26.26,100.99 C42.2 C48.2 27.74,101.07 28.43,101.76 v3(29.33,101.76) ; C47.2 30.07,113.52 v3(30.06,113.53) ; C72.2 39.74,101.11 39.58,101.27 v3(39.58,101.84) ; C64.2 v3(35.35,112.93) ; v3(41.52,92.48) 41.89,92.11
  L3_IN1 w0.508: v3(29.33,101.76) 30.33,101.76 31.05,101.04 v3(31.67,101.04) 33.49,101.04 v3(34.91,102.45) 34.57,102.45 34.18,102.84 34.18,103.56 34.54,103.91 v3(34.97,103.91) 36.43,103.91 v3(37.25,103.1)
  L4_IN2 w0.203: v3(83.97,140.06) 85.42,140.06 86.04,140.69 93.56,140.69 93.94,140.31 94.42,139.83 96.51,139.83 v3(96.95,140.27)
  L4_IN2 w0.508: v3(43.1,105.54) 43.1,105.1 42.88,104.89 42.88,104.04 v3(42.25,103.41)
  BOTTOM w0.203: 36.54,90.71 36.54,90.69 36.53,90.68 ; 36.54,90.71 36.92,91.09 36.92,91.33 U1636.G1 ; 36.54,90.71 36.53,90.7 36.53,90.68 ; 36.53,90.68 36.53,90.15 U1635.G7
  BOTTOM w0.254: v3(39.14,91.81) 39.14,91.54 U1636.D1 ; 76.37,82.3 76.37,82.14 76.4,82.12 76.4,81.74 75.94,81.28 R469.1 ; v2(37.44,86.13) 37.73,85.84 U1636.F8 ; v2(37.33,104.66) 37.7,104.29 U1637.F8 ; U1636.F2 37.73,90.55 v2(38.13,90.95) ; v3(37.43,91.88) 36.93,91.38 U1636.G1 ; U1636.A1 41.73,91.5 41.89,91.66 41.89,92.11 v3(41.52,92.48) 41.32,92.48 40.81,91.98 40.81,91.47 U1635.B9 ; U1637.L1 33.73,110.02 v3(34.06,110.35) ; v3(27.54,91.66) 28.43,91.66 28.74,91.35 U1635.T9 ; v3(35.13,92.48) 35.1,92.48 33.96,91.35 U1636.L1 ; v3(38.22,85.35) 38.53,85.65 U1635.E2 38.53,85.79 v3(38.87,86.13) ; v3(38.14,103.91) 38.52,104.29 U1638.E2 38.58,104.29 v3(38.96,104.66) ; U1637.G1 36.94,109.89 v3(37.36,110.31) ; U1635.E7 38.58,89.75 38.91,90.07 v2(38.91,90.06) ; U1636.J1 35.71,90.97 v3(35.71,90.92) ; v3(34.88,109.52) 35.25,109.89 U1637.J1 ; U1638.T9 29.73,109.95 v3(30.27,110.49)
  BOTTOM w0.305: U1637.G9 36.93,103.43 37.25,103.11 v3(37.25,103.1) ; U1636.A9 42.17,84.95 v3(42.25,84.86) ; v3(30.09,84.46) 30.53,84.91 U1635.R1 ; U1636.J8 35.33,85.74 v3(34.97,85.37) 35.33,85.01 U1636.J9 ; 41.39,105.54 U1638.B3 40.93,105.09 41.39,105.54 41.39,105.54 ; 41.39,105.54 v3(43.1,105.54) ; v3(38.85,84.41) 38.85,84.46 U1636.D9 U1635.C1 ; U1636.G9 36.93,84.43 v3(37,84.36) ; 41.39,87 U1635.B3 40.93,86.55 41.39,87 41.39,87 ; 41.39,87 41.95,87 v3(42.19,87.24) ; v3(35.71,90.92) 35.71,90.92 U1636.J2 ; v3(34.88,109.52) 34.9,109.52 U1637.J2 ; v3(38.85,102.95) 38.85,103.01 U1637.D9 U1638.C1 ; U1636.L9 34.26,84.42 v3(34.27,84.42) ; U1637.A9 41.73,102.68 42.88,101.52 v3(42.88,101.21) ; v3(34.91,102.45) 34.64,102.45 33.73,103.36 U1637.L9 ; U1637.J8 35.33,104.28 v3(34.97,103.91) 35.33,103.55 U1637.J9
  BOTTOM w0.381: v3(29.33,101.76) 30.53,102.96 U1638.R1 ; v3(96.95,140.27) 97.3,139.91 97.3,139.12 97.71,138.71 R316.1 98.02,138.66 C261.1 ; C384.2 84.25,84.56 v3(84.17,84.48) ; C385.2 76.75,84.59 v3(76.86,84.48) ; v3(86.91,84.49) C383.1
  BOTTOM w0.508: C336.2 33.58,112.85 v3(33.61,112.83) ; C361.2 26.84,91.27 26.9,91.2 27.08,91.2 v3(27.54,91.66) ; v3(111.42,117.62) 111.68,117.88 111.68,123.32 110.51,124.49 110.03,124.49 109.49,123.96 v3(104.82,123.96) 101.42,123.96 100.88,124.49 95.06,124.49 94.48,123.92 v3(93.45,123.92) ; v3(34.91,102.45) 35.21,102.45 C353.2 ; C351.2 31.67,100.54 v3(31.67,101.04) ; v3(35.13,92.48) 34.13,93.49 C359.2 ; R364.1 25.8,100.53 v3(26.6,101.33) ; R399.2 107.99,98.31 v3(108.5,98.81)
  vias: v3(43.79,90.33) v3(74.63,129.22) v3(75.44,129.22) v3(76.26,129.22) v3(77.11,134.6) v3(77.07,129.22) v3(77.87,134.6) v3(77.88,129.22) v3(78.7,129.22) v3(79.51,129.22) v3(80.32,129.22) v3(81.13,129.22) v3(81.95,129.22) v3(82.76,129.22) v3(83.57,129.22) v3(84.39,129.22) v3(85.2,129.22) v3(86.01,129.22)
+1.2VS_DDR: length 2.6
  TOP w0.305: CN11.134 v3(82.72,125.13)
  BOTTOM w0.254: v3(82.72,125.13) 82.64,125.05 R226.1
+1.5VS_ON_S: length 7.3
  TOP w0.102: U13.6 94.9,139.8 94.61,140.09 94.5,140.09 93.91,140.67 90.82,140.67 v3(90.21,140.06)
  BOTTOM w0.102: v3(90.21,140.06) 90.04,139.89 C259.1 R312.2
+1.8VA_FB: length 2.4
  BOTTOM w0.508: R236.2 R221.2 142.15,68.91 v3(142.01,68.76)
+1.8VA_FB_R: length 4.8
  TOP w0.254: U8.7 42.94,122.36 43.7,121.59 C322.2 R377.1 R278.2
+1.8VA_PCH: length 304.8
  TOP w0.381: v3(109.67,76.21) 109.67,75.98 R151.2 108.55,74.94 108.09,75.4 106.07,75.4 105.48,74.81 R138.2
  L3_IN1 w0.508: v3(103.81,22.02) 104.57,21.26 v3(111.46,21.26) ; 105.86,52.97 105.99,53.1 v3(107.26,53.1)
  L3_IN1 w1.016: v4(108.89,65.44) 108.91,65.41 109.12,65.41 109.42,65.11 109.42,63.76 105.86,60.21 105.86,52.46 104.73,51.32 101.55,51.32 101.06,50.84 96.62,50.84 95.12,49.34 92.9,49.34 92.88,49.31 83.28,49.31 81.44,47.47 70.36,47.47 65.01,42.11 53.78,42.11 52.41,43.48 52.41,48.5 55.24,51.33 58.61,51.33 62.68,55.41 62.68,59.39 62.71,59.42 62.71,60.31 62.89,60.49 62.89,61.52 60.4,64.02 v2(60.4,64.65) 58.78,64.65 58.39,64.26 49.73,64.26 45,68.99 38.21,68.99 33.61,73.58 33.61,76.38 29.8,80.19 26.79,80.19 22.82,84.17 22.82,86.5 20.98,88.34 20.98,93.84 21.7,94.56 21.7,98.8 21.98,99.08 21.98,110.87 v4(24.76,113.65)
  L4_IN2 w0.508: v3(107.26,53.1) 107.82,52.54 131.89,52.54 132.72,53.37 140.11,53.37 141.58,54.85 v3(142.08,54.85)
  L4_IN2 w1.016: v4(33.36,118.67) 30.78,116.09 27.2,116.09 v4(24.76,113.65)
  BOTTOM w0.381: v2(60.4,64.65) 59.93,65.12 59.43,65.12 59.42,65.11 R508.2
  BOTTOM w0.508: CN6.5 123.5,5.72 C531.2 122.82,6.6 112.35,17.07 112.35,20.37 v3(111.46,21.26) ; R3214.1 104.34,63.89 105.61,65.16 106.28,65.16 106.56,65.44 v4(108.89,65.44) ; v3(107.26,53.1) 107.08,52.92 107.08,48.76 107.4,48.44 107.4,37.71 103.81,34.11 v3(103.81,22.02) ; R523.1 v3(142.08,54.85)
  vias: v3(41.5,125.05) v3(42.1,125.04)
+1.8VA_PCH_EN: length 7.8
  TOP w0.254: R336.2 37.85,126.51 36.76,126.51 C241.2 36.03,125.77 36.03,124.8 35.15,123.92 35.15,122.84 35.63,122.36 U8.2
+1.35VS_BOOT: length 2.4
  TOP w0.203: R130.2 99.13,135.9 98.36,136.67 U13.27
+1.35VS_ON: length 167.3
  L4_IN2 w0.102: v3(16.6,110.77) 16.66,110.83 16.66,113.96 v3(16.46,114.16) ; v3(87.47,140.06) 88.46,140.06 89.09,139.43 99.93,139.43 100.16,139.66 106.61,139.66 v3(106.83,139.88)
  BOTTOM w0.102: R321.1 94.79,136.36 96.8,134.34 101,134.34 v1(101.42,134.76) 101.75,134.76 102.46,135.46 102.46,135.6 103.74,136.88 103.9,136.88 105.23,138.22 105.23,139.27 105.84,139.88 v3(106.83,139.88) ; v3(87.47,140.06) 87.47,140.04 ; 87.47,140.04 87.47,139.78 88.23,139.02 R312.1 ; 87.47,140.04 87.04,140.47 76.05,140.47 73.81,138.23 69.65,138.23 67.23,140.65 60.57,140.65 60.05,140.13 29,140.13 28.89,140.24 21.86,140.24 21.47,139.85 21.47,138.02 17.34,133.9 12.95,133.9 11.42,135.43 9.26,135.43 7.57,133.74 6.57,133.74 3.47,130.64 3.47,112.63 3.77,112.33 4.47,112.33 4.75,112.05 5.17,112.05 5.75,111.46 13.52,111.46 14.5,110.47 16.2,110.47 16.5,110.77 v3(16.6,110.77) ; U25.16 16.25,114.8 16.46,114.59 v3(16.46,114.16)
+1.35VS_PHASE: length 20
  TOP w0.203: 98.83,135.44 98.4,135.87 U13.25
  TOP w0.381: 98.83,135.44 98.94,135.33 99.24,135.33 C162.1 99.61,134.8 98.65,134.8 v3(98.17,135.29)
  L4_IN2 w0.381: v3(98.17,135.29) 97.8,135.66 96.87,135.66 96.25,135.03 v3(92.69,135.03)
  BOTTOM w0.254: R115.1 100.4,138.69 101.11,137.98 102.61,137.98 102.97,137.61 102.97,136.66 101.72,135.41 100.63,135.41 100.33,135.72 98.59,135.72 v3(98.17,135.29)
+2.5VS: length 63.1
  TOP w0.254: U1637.B1 40.85,109.97 40.85,110.5 41.26,110.91 ; v3(31.73,103.09) 31.61,102.96 31.06,102.96 U1637.R9 ; v3(30.9,84.48) 30.9,84.57 U1636.R9 ; 40.93,92.04 U1636.B1
  TOP w0.508: v3(26.83,102.69) 26.7,102.69 25.93,101.92 C3930.2 ; v3(30.9,84.48) v3(30.9,83.81) 30.9,82.98 C3936.2 31.67,81.88 33.11,80.44 39.46,80.44 40.34,81.33 C3405.2 40.67,82.17 v3(40.79,82.28) ; v3(43.8,110.91) 41.26,110.91 41.26,111.41 40.67,111.99 C3407.2 40.09,113.54 36.26,113.54 35.96,113.84 35.96,114.6 ; C3937.2 v3(27.51,92.32) ; 40.93,92.04 40.3,92.67 v3(40.3,93.75) 40.3,94.25 C3406.2
  L4_IN2 w0.508: v3(40.3,93.75) 40.93,94.38 v3(40.93,101.95) 40.93,103.91 42.49,105.46 42.49,108.61 43.09,109.21 43.09,110.21 v3(43.8,110.91)
  BOTTOM w0.254: v3(30.36,92.02) 30.53,91.85 U1635.R9 ; v3(30.97,110.39) 30.53,109.96 U1638.R9
  BOTTOM w0.305: v3(40.79,82.28) 40.79,83.45 41.55,84.21 41.55,84.52 41.12,84.95 U1635.B1 ; U1638.B1 v3(40.93,101.95)
  BOTTOM w0.508: v3(30.97,110.39) v3(30.97,110.99) 30.97,111.39 31.54,111.96 C3931.2 ; v3(40.93,101.95) 40.93,101.3 C3404.2
  vias: v3(40.27,117.97) v3(40.83,117.97) v3(41.39,117.97) v3(41.94,117.97) v3(42.5,117.97) v3(115.3,117.31) v3(115.93,117.31) v4(56.6,134.23) v4(57.74,134.23) v4(58.95,134.23) v4(60.16,134.23)
+3.3V: length 560.2
  TOP w0.254: C20.1 18.54,113.94 v3(18.95,114.35) ; v3(107.49,70.49) 107.49,70.95 R152.2 ; v3(122.96,125.56) 123.28,125.23 125.44,125.23 C474.2 126.44,125.91 CN7.7
  TOP w0.381: U19.14 130.09,65.99 130.28,66.19 130.28,66.95 C212.1 ; R188.1 117.34,98.64 118.21,99.51 R187.2
  TOP w0.508: B16.1 v3(99.56,15.14) ; R592.1 v3(102.26,15.42) ; v3(6.48,105.72) 7.18,105.02 7.18,104.98 8.16,104 10.83,104 11.34,104.51 12.99,104.51 14.65,106.17 15.14,106.17 15.31,106.33 16.76,106.33 16.87,106.22 v3(20.28,106.22) ; R3426.2 27.35,52.28 16.12,52.28 15.01,53.39 v3(14.94,53.39) 13.75,52.2 R3279.1 R3280.1 R3278.1 R3281.1 ; R35.2 20.44,117.33 20.61,117.17 20.8,117.17 v3(20.8,117.2) ; 112.67,56.47 111.83,55.64 109.04,55.64 108.2,56.47 R158.1 R149.1 106.85,55.92 v3(107.01,55.76) ; 112.67,56.47 113.63,55.51 v3(115.01,55.51) v3(116.23,55.51) ; 112.67,56.47 C140.1 112.79,56.38 Q10.5 ; v3(20.28,106.22) 20.28,104.13 v3(20.09,103.94) ; v3(20.28,106.22) 20.59,106.22 21.32,106.95 21.32,109.5 20.85,109.96 v3(20.67,109.96) 21.1,110.4 21.1,111.2 20.76,111.54 20.75,111.54 18.93,113.36 C20.1 18.54,113.06 18.13,112.66 16.73,112.66 v3(16.05,111.97) ; v3(127.22,68.13) 126.92,67.83 R217.1 ; C614.1 69.49,130.74 v3(70.18,130.05) ; v3(141.88,98.79) 142.19,99.1 142.19,101.49 v3(142.82,102.12) ; C580.1 25.14,108.72 v3(24.58,109.27) ; 115.95,93.38 116.48,92.84 117.85,92.84 117.98,92.97 R185.2 118.87,92.74 R191.1 ; 115.95,93.38 115.95,97.72 v3(116.3,98.08) 116.86,98.08 R188.1 117.44,98.46 117.44,96.84 U15.4 ; 115.95,93.38 115.77,93.56 114.17,93.56 v3(113.89,93.28) 113.84,93.23 112.92,93.23 112.39,92.69 110.7,92.69 110.67,92.72 109.43,92.72 108.92,93.23 107.15,93.23 106.34,92.41 105.25,92.41 v2(105.2,92.46) ; R180.1 115.28,72.55 114.92,72.19 114.92,72.19 114.51,71.78 114.51,71.61 v3(114.27,71.38) 114.27,71.19 112.74,69.65 111.55,69.65 110.66,68.77 110.39,68.77 109.07,67.45 109.06,67.45 v3(108.3,66.69) 108.3,66.15 107.74,65.6 R154.2 107.74,64.88 107.3,64.45 106.67,64.45 105.31,63.08 R144.2 103.96,62.57 103.96,61.35 103.53,60.92 R131.2 R127.1 ; v3(47.44,128.96) 47.44,130.3 47.19,130.55 C613.1 ; R591.1 v3(105.41,15.44) ; C212.1 v3(130.98,67.01) ; R658.1 v3(106.55,10.63) ; v3(117.93,18.68) 118.18,18.42 R697.1 ; R3386.1 C3502.1 C3503.1 25.17,34.15 C3497.1 ; R588.1 R587.1 119.51,61.35 111.45,61.35 109.93,62.87 v3(109.8,62.87) 109.77,62.87 109.72,62.92 R163.1 R157.1 107.97,63.03 v3(107.97,63.74)
  TOP w1.016: 125.7,67.52 125.55,67.52 ; 125.55,67.52 126.13,68.1 ; 125.55,67.52 124.2,67.52 122.63,69.1 122.63,71.36
  L3_IN1 w0.254: v3(103.99,136.3) 103.03,135.35 101,135.35 100.35,134.7 97.78,134.7 v3(97.45,135.02)
  L3_IN1 w0.508: v3(114.27,71.38) 114.42,71.38 115.43,70.37 124.99,70.37 v3(127.22,68.13) 128.04,67.32 130.65,67.32 130.96,67.01 v3(130.98,67.01) ; v3(107.01,55.76) 107.01,60.08 v3(109.8,62.87) ; v3(144.64,40.78) 150.84,40.78 v3(152.09,39.53) ; v3(122.96,125.56) 122.96,121.6 125.55,119.01 130.7,119.01 131.96,117.75 v3(131.96,115.45) ; v4(121.33,131.2) 121.79,130.74 v3(128.42,130.74) ; v3(107.97,63.74) 107.97,63.99 107.79,64.17 107.79,65.69 108.3,66.2 v3(108.3,66.69) 107.81,67.18 107.81,68.24 107.49,68.56 v3(107.49,70.49) 107.49,71.08 108.43,72.02 109.31,72.02 110.02,72.73 110.02,73.31 108.91,74.41 108.91,76.78 109.34,77.21 109.34,77.53 109.34,77.53 109.34,79 109.34,79 109.34,81.59 107.56,83.37 107.56,85.35 107.66,85.45 107.66,89.7 107.99,90.03 107.99,91.27 107.33,91.93 105.73,91.93 v2(105.2,92.46)
  L3_IN1 w0.762: v4(131.42,59.19) 131.42,59.85 131.21,60.05 129.38,60.05 127.22,62.21 v3(127.22,68.13)
  L3_IN1 w1.016: 32.03,21.77 88.03,21.77 89.21,20.59 90.29,20.59 95.74,15.14 v3(99.56,15.14)
  L4_IN2 w0.381: v3(107.06,132.85) 107.06,135.14 106.05,136.14 104.14,136.14 v3(103.99,136.3)
  BOTTOM w0.203: v3(18.95,114.35) 18.69,114.35 18.25,114.8 U25.11
  BOTTOM w0.254: C515.1 153.18,40.19 153.18,39.63 152.86,39.31 U33.9 ; v3(97.45,135.02) 96.97,135.5 R3197.2 R3198.2 ; R448.1 100.76,88.96 R443.1 ; R443.1 R437.1 100.68,90.23 101.34,90.89 101.87,90.89 102.71,91.73 103.25,91.73 R424.2 104.82,91.88 R432.2 ; R443.1 R451.1 R454.1 R460.1 R464.1 R466.2 R467.1 100.68,81.83 R500.1 R503.1 ; R432.2 105.33,92.34 v2(105.2,92.46) ; R432.2 R431.1
  BOTTOM w0.381: R653.2 103.97,136.29 v3(103.99,136.3) ; v3(20.28,106.22) 20.59,106.22 20.76,106.39 20.76,107.2 20.49,107.47 18.27,107.47 18.02,107.22 U28.19
  BOTTOM w0.508: R381.1 6.9,107.75 6.47,107.32 6.17,107.32 5.81,106.97 5.81,106.4 v3(6.48,105.72) R384.1 ; R374.2 v3(16.05,111.97) ; R551.1 R552.1 142.31,42.52 141.75,41.96 141.75,37.45 v3(140.61,36.31) ; v3(116.23,55.51) 116.23,54.44 115.01,53.22 R586.1 ; Q28.G 145.56,103.8 145.56,106.15 C342.2 ; Q28.G 143.87,104.02 142.97,104.02 C344.1 ; Q28.G 145.69,102.2 145.69,100.76 Q29.G ; R379.1 20.29,109.96 v3(20.67,109.96) ; R64.2 v3(117.93,18.68) ; R239.1 132.67,120.35 132.67,116.16 v3(131.96,115.45) 131.96,115.2 131.37,114.61 126.76,114.61 v3(126.03,113.88) ; v3(117.58,121.69) 114.93,121.69 114.8,121.81 R207.2 114.46,122.31 112.92,122.31 ; R237.2 94.84,126.65 96.31,125.18 110.73,125.18 112.17,123.74 R254.2 112.5,122.98 112.92,122.56 112.92,122.31 ; 112.92,122.31 112.92,121.69 112.69,121.46 R230.2 ; v3(105.41,15.44) 105.41,11.78 v3(106.55,10.63) ; Q30.S 111.92,100.67 C346.1 113.74,100.67 116.22,98.18 116.3,98.18 v3(116.3,98.08) 118.1,99.88 136.55,99.88 138.82,97.61 R696.2 139.59,98.14 139.13,98.6 Q58.S 139.13,98.9 140.55,100.32 141.81,100.32 141.88,100.39 ; R390.2 R389.1 20.22,102.17 20.72,102.67 20.72,103.3 v3(20.09,103.94) 20.05,103.97 U28.24 ; AB9.2 145.15,41.56 144.64,41.05 v3(144.64,40.78) ; 141.88,100.39 v3(141.88,98.79) 142.16,98.51 R396.1 142.54,97.52 141.93,96.92 141.93,95.41 142.84,94.5 ; 141.88,100.39 141.88,100.89 R359.2 ; v3(142.82,102.12) 142.72,102.22 R388.2 C344.1 ; v3(14.94,53.39) 13.86,52.31 13.86,43.99 13.23,43.36 13.23,40.82 14.94,39.1 v3(14.94,38.85) ; v3(113.89,93.28) R421.1 ; v3(117.88,21.19) 118.11,20.96 R111.2 ; R585.1 R584.1 114.07,54.57 v3(115.01,55.51) ; B10.1 122.85,129.88 123.08,129.65 123.08,125.66 122.96,125.53 v3(122.96,125.56) ; B19.2 128.5,130.81 v3(128.42,130.74) ; R577.2 107.94,134.14 107.06,133.26 v3(107.06,132.85) ; R385.1 C344.1 ; 142.84,94.5 142.84,93.59 143.41,93.02 143.83,93.02 R423.2 ; 142.84,94.5 143.43,94.5 144.82,95.89 Q32.G ; R61.2 v3(117.93,22.11) ; R107.2 v3(117.93,19.82) ; C592.1 v3(115.8,107.42) ; Q40.S 142.4,30.69 R595.1 139.95,30.69 v3(139.53,30.28) ; C515.1 153.05,40.37 C509.1 151.94,39.68 v3(152.09,39.53)
  BOTTOM w0.762: v3(127.22,68.13) 127.17,68.18 v3(127.17,69.07)
  BOTTOM w1.016: v4(120.09,131.2) v4(121.33,131.2) 122.37,130.16 B10.1
  vias: v3(30.5,21.45) v3(31.14,21.45) v3(132.93,22.85) v3(132.93,22.09) v3(132.93,21.39) v3(133.63,22.85) v3(133.69,22.09) v3(133.69,21.39) v4(33.85,129.37) v4(34.87,129.37)
+3.3V_CCD: length 43.2
  TOP w0.254: v3(126.44,123.52) 127.03,124.11 132.48,124.11 R462.1 132.86,124.8 132.46,125.21 v3(132.46,125.38) 132.44,125.4 CN7.19
  L4_IN2 w0.254: v3(130.49,105.09) 130.41,105.17 130.41,109.57 128.83,111.15 128.83,113.3 127.63,114.49 127.63,118.2 126.44,119.39 v3(126.44,123.52)
  BOTTOM w0.254: R359.1 139.5,102 140.08,101.42 Q58.D 133.36,101.16 130.63,103.89 130.63,104.95 v3(130.49,105.09)
  BOTTOM w0.508: C285.1 132.25,125.59 v3(132.46,125.38)
+3.3V_DDR: length 6.1
  TOP w0.254: CN11.255 114.97,119.76 114.18,120.56 v3(113.58,120.56)
  BOTTOM w0.508: v3(113.58,120.56) 114.04,120.1 C108.2 C106.1 113.05,118.77 R230.1
+3.3V_LCD: length 35.2
  TOP w0.102: v3(116.05,139.82) 116.51,140.27 120.96,140.27 121.39,139.83 124.28,139.83 125.55,138.57 125.55,138.19 127.83,135.9 127.83,135.14 127.2,134.5 127.2,128.86 127.3,128.76 128.06,128.76 v3(128.14,128.68)
  BOTTOM w0.102: v3(116.05,139.82) 115.46,140.41 110.01,140.41 109.5,139.89 R323.1
  BOTTOM w0.508: v3(128.14,128.68) 128.11,128.66 C288.1 C279.1 127.1,131.38 Q26.D
  vias: v3(127.17,128.1)
+3.3V_WIFI: length 61.9
  BOTTOM w1.016: R563.2 83.46,9.13 88.6,9.13 89.75,10.27 89.75,14.25 93.71,18.21 101.49,18.21 104.92,21.64 104.92,33.83 108.61,37.52 108.61,45.2 109.26,45.85 110.34,45.85 111.09,46.61
  vias: v3(112.21,49.03) v3(112.21,48.47) v3(112.21,47.89)
+3.3VA: length 192.8
  TOP w0.356: R365.2 119.73,86.55 116.67,83.49 112.06,83.49 v3(112.02,83.53)
  TOP w0.508: v3(113.24,80.6) 116.26,80.6 116.76,80.09 R190.1
  TOP w1.016: v4(25.17,80.38) 24.81,80.74 24.81,82.8 23.18,84.42 23.18,90.48 23.44,90.73 23.44,94.23 22.58,95.09 22.58,106.05 22.86,106.33 22.86,111.34 23.47,111.96 23.47,113.8 24.35,114.68 26.58,114.68 v4(29,117.1)
  L3_IN1 w0.508: v4(25.17,80.38) 24.53,80.38 23.19,81.72 23.19,82.23 v3(22.53,82.89)
  L4_IN2 w0.254: v2(102.23,73.69) 102.35,73.81 103.73,73.81 103.85,73.93 106.81,73.93 106.93,73.82 109.44,73.82 109.6,73.97 111.93,73.97 v3(112.31,74.35)
  BOTTOM w0.254: R461.1 108.15,85.22 v3(108.28,85.35) ; v2(102.23,73.69) R489.2
  BOTTOM w0.508: v3(107.18,97.39) 107.44,97.39 ; 107.44,97.39 R411.1 ; 107.44,97.39 107.18,97.14 v3(107.18,96.81) v3(107.18,94.6) ; CN8.1 20.12,87.02 21.74,85.4 21.74,83.68 v3(22.53,82.89) ; R479.1 108.17,77.88 111.07,77.88 v3(111.3,78.11)
  BOTTOM w1.016: 23.14,74.98 23.14,76.04 25.15,78.05 25.15,80.37 v4(25.17,80.38)
  BOTTOM w1.27: 115.28,126.32 114.83,126.78 97.08,126.78 93.84,130.03 92.1,130.03 91.17,130.95 89.71,130.95 89.26,131.4 70.17,131.4 69.1,130.34 63.41,130.34 61.68,132.07 54.76,132.07 46.12,123.43 46.12,119.72 43.2,116.8 30.45,116.8 30.02,117.23 30.02,117.28
  vias: v3(108.73,55.05) v3(108.73,53.78) v3(109.29,55.05) v3(109.29,53.84) v3(117.8,124.98) v3(118.76,124.98) v4(25.7,124.37)
+3.3VA_LDO: length 128
  TOP w0.203: U9.6 40.36,138.54 C73.1
  TOP w0.508: v3(66.13,132.16) 63.18,132.16 61.55,133.78 61.55,137.91 60.45,139.02 v3(60.45,139.38) ; v3(131.24,123.24) 134.39,123.24 134.41,123.27 135.08,123.27 135.23,123.12 135.23,116.21 133.25,114.23 133.25,113.72 134.32,112.64 R91.1 ; v3(41.04,137.59) 41.17,137.59 41.68,138.1 41.68,138.56 C75.1 C73.1
  L4_IN2 w0.508: v3(131.24,123.24) 130.84,123.24 130.1,123.99 129.09,123.99 127.96,125.12 127.96,125.94 127.34,126.57 125.09,126.57 121.37,130.29 119.91,130.29 115.02,135.18 114.89,135.18 112.65,137.42 110.34,137.42 109.62,136.71 105.05,136.71 104.87,136.88 103.01,136.88 99.35,133.22 90.41,133.22 89.81,133.82 72.11,133.82 71.42,133.13 67.97,133.13 66.99,132.16 v3(66.13,132.16)
  BOTTOM w0.508: v3(41.04,137.59) 41.04,138.29 41.97,139.22 48.28,139.22 48.96,138.54 50.85,138.54 51.53,139.22 60.29,139.22 v3(60.45,139.38)
+3.3VA_ON_R: length 5.9
  TOP w0.102: U4.3 27.88,127.46 28.02,127.6 v3(28.11,127.6)
  BOTTOM w0.102: C282.1 28.7,129.04 27.35,129.04 27.1,129.29 R339.2 ; C282.1 R338.2 ; C282.1 29.13,128.55 28.17,127.6 v3(28.11,127.6)
+3.3VA_PCH: length 259.3
  TOP w0.254: R155.1 108.66,73.16 108.67,73.16 v3(108.74,73.16)
  TOP w0.508: v3(136.04,79.03) 136.36,79.35 R287.2 ; R170.1 111.3,76.06 v3(111.2,76.16) 111.14,76.21 111.14,76.39 110.72,76.82 109.46,76.82 108.97,76.34 104.26,76.34 v2(103.81,76.79) ; R195.1 119.15,98.56 v3(119.07,98.64) ; U20.8 127.79,90.2 C198.1 127.28,89.56 125.9,88.19 123.02,88.19 122.43,88.78 122.43,90.58 121.3,91.7 v3(120.06,91.7) ; R240.1 R238.2 131.65,79.47 v3(131.64,79.46) ; v3(23.2,79.49) 23.17,79.52 v3(23.17,80.14) 23.17,83.22 22.32,84.07 22.32,90.84 22.57,91.09 22.57,93.51 21.71,94.37 21.71,106.45 21.99,106.73 21.99,113.68 21.53,114.14 21.53,114.63 21.98,115.07 23.15,115.07 24.85,116.78 24.85,116.95 24.86,116.95 24.86,117.74 29.43,122.31 29.43,123.5 v4(29.59,123.66)
  L3_IN1 w0.203: v3(108.74,73.16) 108.14,73.16 105.99,71 105.99,70.6 105.99,70.59 105.99,70.09 105.99,70.09 105.99,69.07 106.47,68.59 106.47,67.83 106.96,67.35 106.96,64.6 106.5,64.14 106.5,63.76 104.21,61.48 v3(104.21,60.1)
  L3_IN1 w0.254: v3(111.2,76.16) 111.2,74.63 111.5,74.33 v3(111.5,73.11)
  L3_IN1 w0.508: v3(131.64,79.46) 131.9,79.2 131.9,76.59 132.94,75.55 133.45,75.55 135.45,73.54 135.45,72.65 133.04,70.24 133.04,68.59 v3(132.91,68.46) 132.53,68.46 131.9,69.1 130.22,69.1 126.51,72.81 124.06,72.81 122.41,74.45 122.41,77.17 120.92,78.67 v3(120.62,78.67) ; v3(119.07,98.64) 118.19,99.51 107.93,99.51 106.37,97.95 106.37,93.51 106.01,93.15 104.77,93.15 104.27,92.66 104.27,91.54 v2(104.57,91.24) 105.02,91.24 105.73,90.53 105.73,89.42 106.24,88.91 106.24,88.51 106.63,88.13 106.63,86.7 106.04,86.11 105.51,86.11 105.1,86.52 v2(105.05,86.52) 104.8,86.26 104.8,85.27 108.73,81.34 108.73,78.8 v3(108.71,78.77) 108.71,77.76 107.25,76.3 104.3,76.3 v2(103.81,76.79)
  L4_IN2 w0.381: v3(131.64,79.46) 132.59,79.46 133.93,78.11 135.2,78.11 136.04,78.95 v3(136.04,79.03) ; v2(93.92,76.03) 93.92,75.67 93.52,75.27 91.93,75.27 91.47,74.8 91.04,74.8 90.02,73.79 87.05,73.79 86.02,74.81 v2(84.58,74.81)
  L4_IN2 w0.508: v3(120.06,91.7) 120.06,97.65 v3(119.07,98.64)
  BOTTOM w0.254: v3(111.5,73.11) 110.87,73.11 110.38,73.6 109.26,73.6 108.82,73.16 v3(108.74,73.16) ; R434.1 104.31,91.19 104.36,91.24 v2(104.57,91.24)
  BOTTOM w0.381: 103.47,77.99 102.94,77.45 101.47,77.45 100.51,78.41 99.48,78.41 99.4,78.5 96.8,78.5 96.48,78.18 96.48,77.83 96.19,77.54 95.97,77.54 95.64,77.21 95.64,76.83 95.17,76.37 94.26,76.37 v2(93.92,76.03) ; 103.47,77.99 R478.1 ; 103.47,77.99 103.47,77.76 103.65,77.58 103.65,76.94 v2(103.81,76.79) ; R484.1 v2(84.58,74.81)
  BOTTOM w0.508: R524.1 140.48,54.16 138.61,56.03 138.61,58.95 134.31,63.26 134.31,64.91 134.95,65.54 134.95,66.3 133.94,67.32 133.55,67.7 133.55,67.7 132.91,68.34 v3(132.91,68.46) ; v3(108.71,78.77) 109.26,78.77 R474.1 ; v2(105.05,86.52) 105,86.52 104.36,85.88 R463.1 R465.1 105.06,83.38 110.63,83.38 112.1,81.91 117.38,81.91 v3(120.62,78.67) ; v3(104.21,60.1) 103.35,60.97 R526.2
+3.3VA_PCH_ON: length 3.9
  TOP w0.102: v3(26.93,127.73) 27.08,127.58 U4.5
  BOTTOM w0.102: C283.1 R339.1 ; R339.1 27.1,127.9 v3(26.93,127.73) ; R339.1 R340.2
+3.3VA_RTC: length 71.5
  TOP w0.178: U11.BB14 93.01,87.59 93.01,88.02 v2(92.88,88.15)
  TOP w0.254: v3(89.66,81.31) U11.AK19
  TOP w0.508: D4.3 130.34,109.51 130.34,108.79 v3(129.94,108.39)
  L3_IN1 w0.508: v3(101.62,96.17) 103.4,96.17 104.5,97.27 104.5,98.87 106.51,100.89 117.88,100.89 v3(118.13,100.64)
  L4_IN2 w0.508: v3(101.62,96.17) 101.09,95.64 98.75,95.64 98.19,95.08 98.15,95.08 97.76,94.69 97.76,92.92 97.02,92.18 v2(95.88,92.18)
  BOTTOM w0.254: v2(92.88,88.15) 91.48,88.15 89.98,86.64 89.98,86.06 90.11,85.93 90.11,81.75 89.85,81.49 89.83,81.49 v3(89.66,81.31)
  BOTTOM w0.381: v2(95.88,92.18) 95.88,92.24 ; 95.88,92.24 95.9,92.21 95.9,91.85 96.36,91.4 ; 95.88,92.24 95.9,92.26 95.9,92.74 95.55,93.1 94.86,93.1 R420.1 ; C406.2 90.59,80.45 90.17,80.87 90.09,80.87 v3(89.66,81.31) ; v2(92.88,88.15) 92.99,88.03 R452.1 93.38,87.43 93.62,87.66 93.62,90.78 93.85,91.02 C370.1 C369.1 95.36,91.02 95.74,91.4 96.36,91.4 ; 96.36,91.4 R428.1
  BOTTOM w0.508: v3(129.94,108.39) 129.94,107.76 130.55,107.15 130.55,106.43 129.26,105.14 129.26,102.3 127.6,100.64 v3(118.13,100.64)
+3.3VAL: length 562.7
  TOP w0.203: U9.7 39.96,137.8 C69.1
  TOP w0.254: C143.1 20.34,116.25 19.51,117.09 Q17.5 18.97,117.2 19.35,117.59 19.35,119.11 v3(19.83,119.59) ; 19.91,132.54 19.91,132.43 20.21,132.13 20.21,131.38 R28.1 ; 24.51,136 24.5,136.01 24.5,136.86 24.67,137.03 28.74,137.03 30.27,138.56 C69.1 ; v3(51.71,137.66) 51.71,138.28 R639.1
  TOP w0.381: v3(137.31,117.02) 137.72,117.02 138.29,116.45 138.29,114.92 v3(137.78,114.41) 135.22,114.41 134.63,113.82 134.63,113.25 135.4,112.48 135.4,112.07 134.61,111.27 R97.1 135.02,110.57 135.02,109.51 132.22,106.7 v3(129.84,106.7)
  TOP w0.508: v3(120.36,109.33) 120.36,110.5 119.58,111.29 119.58,117.2 118.97,117.81 118.97,120.33 119.45,120.81 119.45,124.11 119.53,124.19 v3(119.53,124.59) ; 14.52,129.51 U3.8 14.52,126.43 13.19,125.1 R12.1 13.41,124.11 13.41,120.45 15.24,118.63 v3(15.51,118.63) 16.18,118.63 R22.2 ; 14.52,129.51 14.52,129.5 v3(13.49,129.5) 13.13,129.87 C13.1 12.17,130.54 C11.1 11.77,131.47 12.21,131.91 12.21,132.52 12.36,132.67 12.36,132.72 12.57,132.93 12.62,132.93 12.72,133.03 16.3,133.03 ; 14.52,129.51 14.38,129.65 14.38,130.39 14.89,130.89 C14.1 ; v3(68.03,131.51) 66.9,131.51 66.13,130.74 64.23,130.74 62.76,129.27 49.12,129.27 48.09,128.25 48.09,126.76 v3(46.71,125.38) ; B17.1 101.85,12.65 100.86,13.64 v3(100.86,16.31) ; v3(20.89,67.42) 20.27,66.8 20.27,65.64 19.07,64.43 Q35.S 18.17,64.43 16.91,63.17 R21.1 ; v3(126.74,134.3) 126.74,129.22 126.06,128.53 125.99,128.53 125.92,128.46 124.68,128.46 v3(124.63,128.4) ; 16.3,133.03 R19.2 ; 16.3,133.03 19.63,133.03 19.91,132.75 19.91,132.54 ; v3(19.83,119.59) 20.01,119.77 R33.1 ; 24.56,126.25 23.97,125.66 R36.2 R37.2
  L2_VCC w0.508: v3(145.46,50.68) 149.98,50.68 153.03,47.63 153.03,44.62 153.54,44.12 156.24,44.12 158.41,41.94 v3(158.41,39.47) 159.07,38.8 159.07,27.6 158.53,27.06 v3(157.7,27.06)
  L3_IN1 w0.508: v3(15.51,118.63) 15.52,118.62 18.01,118.62 v3(18.07,118.56) 18.07,118.62 18.14,118.69 18.14,119.11 18.66,119.64 19.78,119.64 v3(19.83,119.59) 22.06,119.59 23.64,121.17 29.38,121.17 v3(29.46,121.24) 29.71,121.5 30.73,121.5 31.08,121.85 31.08,121.92 31.6,122.44 32.51,122.44 32.68,122.26 38.26,122.26 38.92,122.92 44.33,122.92 45.93,124.52 46.45,124.52 46.71,124.78 v3(46.71,125.38) ; v3(100.86,16.31) 100.99,16.18 v3(116.58,16.18) ; v3(21.8,80.31) 21.75,80.31 21.54,80.53 21.54,81.5 21.36,81.69 21.36,85.59 19.91,87.03 19.91,94.28 20.64,95.01 20.64,98.5 20.21,98.92 20.21,100.06 20.91,100.76 20.91,107.18 20.63,107.46 19.61,107.46 19.14,107.94 19.14,109.98 v3(17.06,112.05) ; v3(129.84,106.7) 129.84,103.7 136.27,97.28 136.27,89.29 136.72,88.83 v3(136.72,88.66)
  L4_IN2 w0.254: v3(51.71,137.66) 51.71,137.15 50.63,136.07 37.46,136.07 36.69,136.83 29.94,136.83 v3(27.86,134.75) ; v3(116.58,16.18) 116.58,16.41 117.15,16.98 117.15,22.52 119.69,25.05 132.64,25.05 136.22,21.47 141.57,21.47 142.59,22.49 143.45,22.49 143.88,22.06 145.32,22.06 145.61,22.36 146.46,22.36 148.15,24.06 148.15,24.6 148.66,25.1 149.28,25.1 149.94,25.76 v3(150.82,25.76)
  L4_IN2 w0.508: v3(21.8,80.31) 21.68,80.19 21.67,80.19 21.16,79.68 21.16,67.69 v3(20.89,67.42) ; v3(18.07,118.56) 18.05,118.54 18.05,118.34 17.2,117.49 17.2,116.28 18.16,115.32 18.16,113.68 17.06,112.58 v3(17.06,112.05) ; v3(157.7,27.06) 157.61,27.06 156.5,25.95 153.8,25.95 153.45,26.29 151.73,26.29 151.2,25.76 v3(150.82,25.76)
  BOTTOM w0.203: v3(13.49,129.5) 13.45,129.55 U25.74
  BOTTOM w0.254: R328.2 124.78,135.26 123.97,134.45 123.97,133.91 123.3,133.23 R333.1 122.35,132.8 122.34,132.8 121.72,132.18 119.37,132.18 118.61,131.42 116.69,131.42 116.2,131.91 114.63,131.91 R334.1 ; v3(137.78,114.41) 137.75,114.38 R370.1 ; R349.1 R348.1 127.99,126.93 127.68,126.63 127.68,125.21 126.87,124.39 119.73,124.39 v3(119.53,124.59)
  BOTTOM w0.381: v3(137.31,117.02) 136.88,117.45 R369.1
  BOTTOM w0.508: v3(29.46,121.24) 29.46,122.64 28.77,123.32 28.77,124.29 29.08,124.59 29.08,127.52 v3(29.06,127.54) ; LID1.1 158.16,26.61 158.15,26.61 v3(157.7,27.06) ; R598.1 150,24.94 v3(150.82,25.76) ; R52.1 18.92,134.17 20.27,135.52 24.46,135.52 ; C518.1 v3(158.41,39.47) ; v3(124.63,128.4) 123.74,127.52 123.74,125.41 123.26,124.93 119.86,124.93 v3(119.53,124.59) 119.5,124.62 119.5,125.17 118.99,125.68 118.12,125.68 116.03,127.77 97.5,127.77 94.26,131.02 92.51,131.02 91.58,131.94 90.12,131.94 89.67,132.39 69.76,132.39 68.69,131.33 68.21,131.33 v3(68.03,131.51) ; v3(120.36,109.33) 128.67,109.33 129.18,108.82 129.18,107.36 v3(129.84,106.7) ; v3(136.72,88.66) 137.99,87.39 137.99,80.36 143.38,74.98 143.38,68.54 143.01,68.17 142.77,67.93 142.77,56.51 144.52,54.75 144.52,54.5 145.21,53.81 145.21,53.68 145.46,53.43 v3(145.46,50.68) ; R328.2 125.42,135.06 125.42,134.73 125.85,134.3 v3(126.74,134.3) ; R373.2 v3(17.06,112.05) ; R57.1 26.29,134.43 25.98,134.73 ; v3(28.6,133.65) 29.68,132.58 32.79,132.58 35.95,129.41 C781.2 38.9,129.27 R840.1
  vias: v3(25.3,134.76) v3(26.59,134.76) v3(31.73,122.96) v3(32.43,122.94) v4(24.41,134.67)
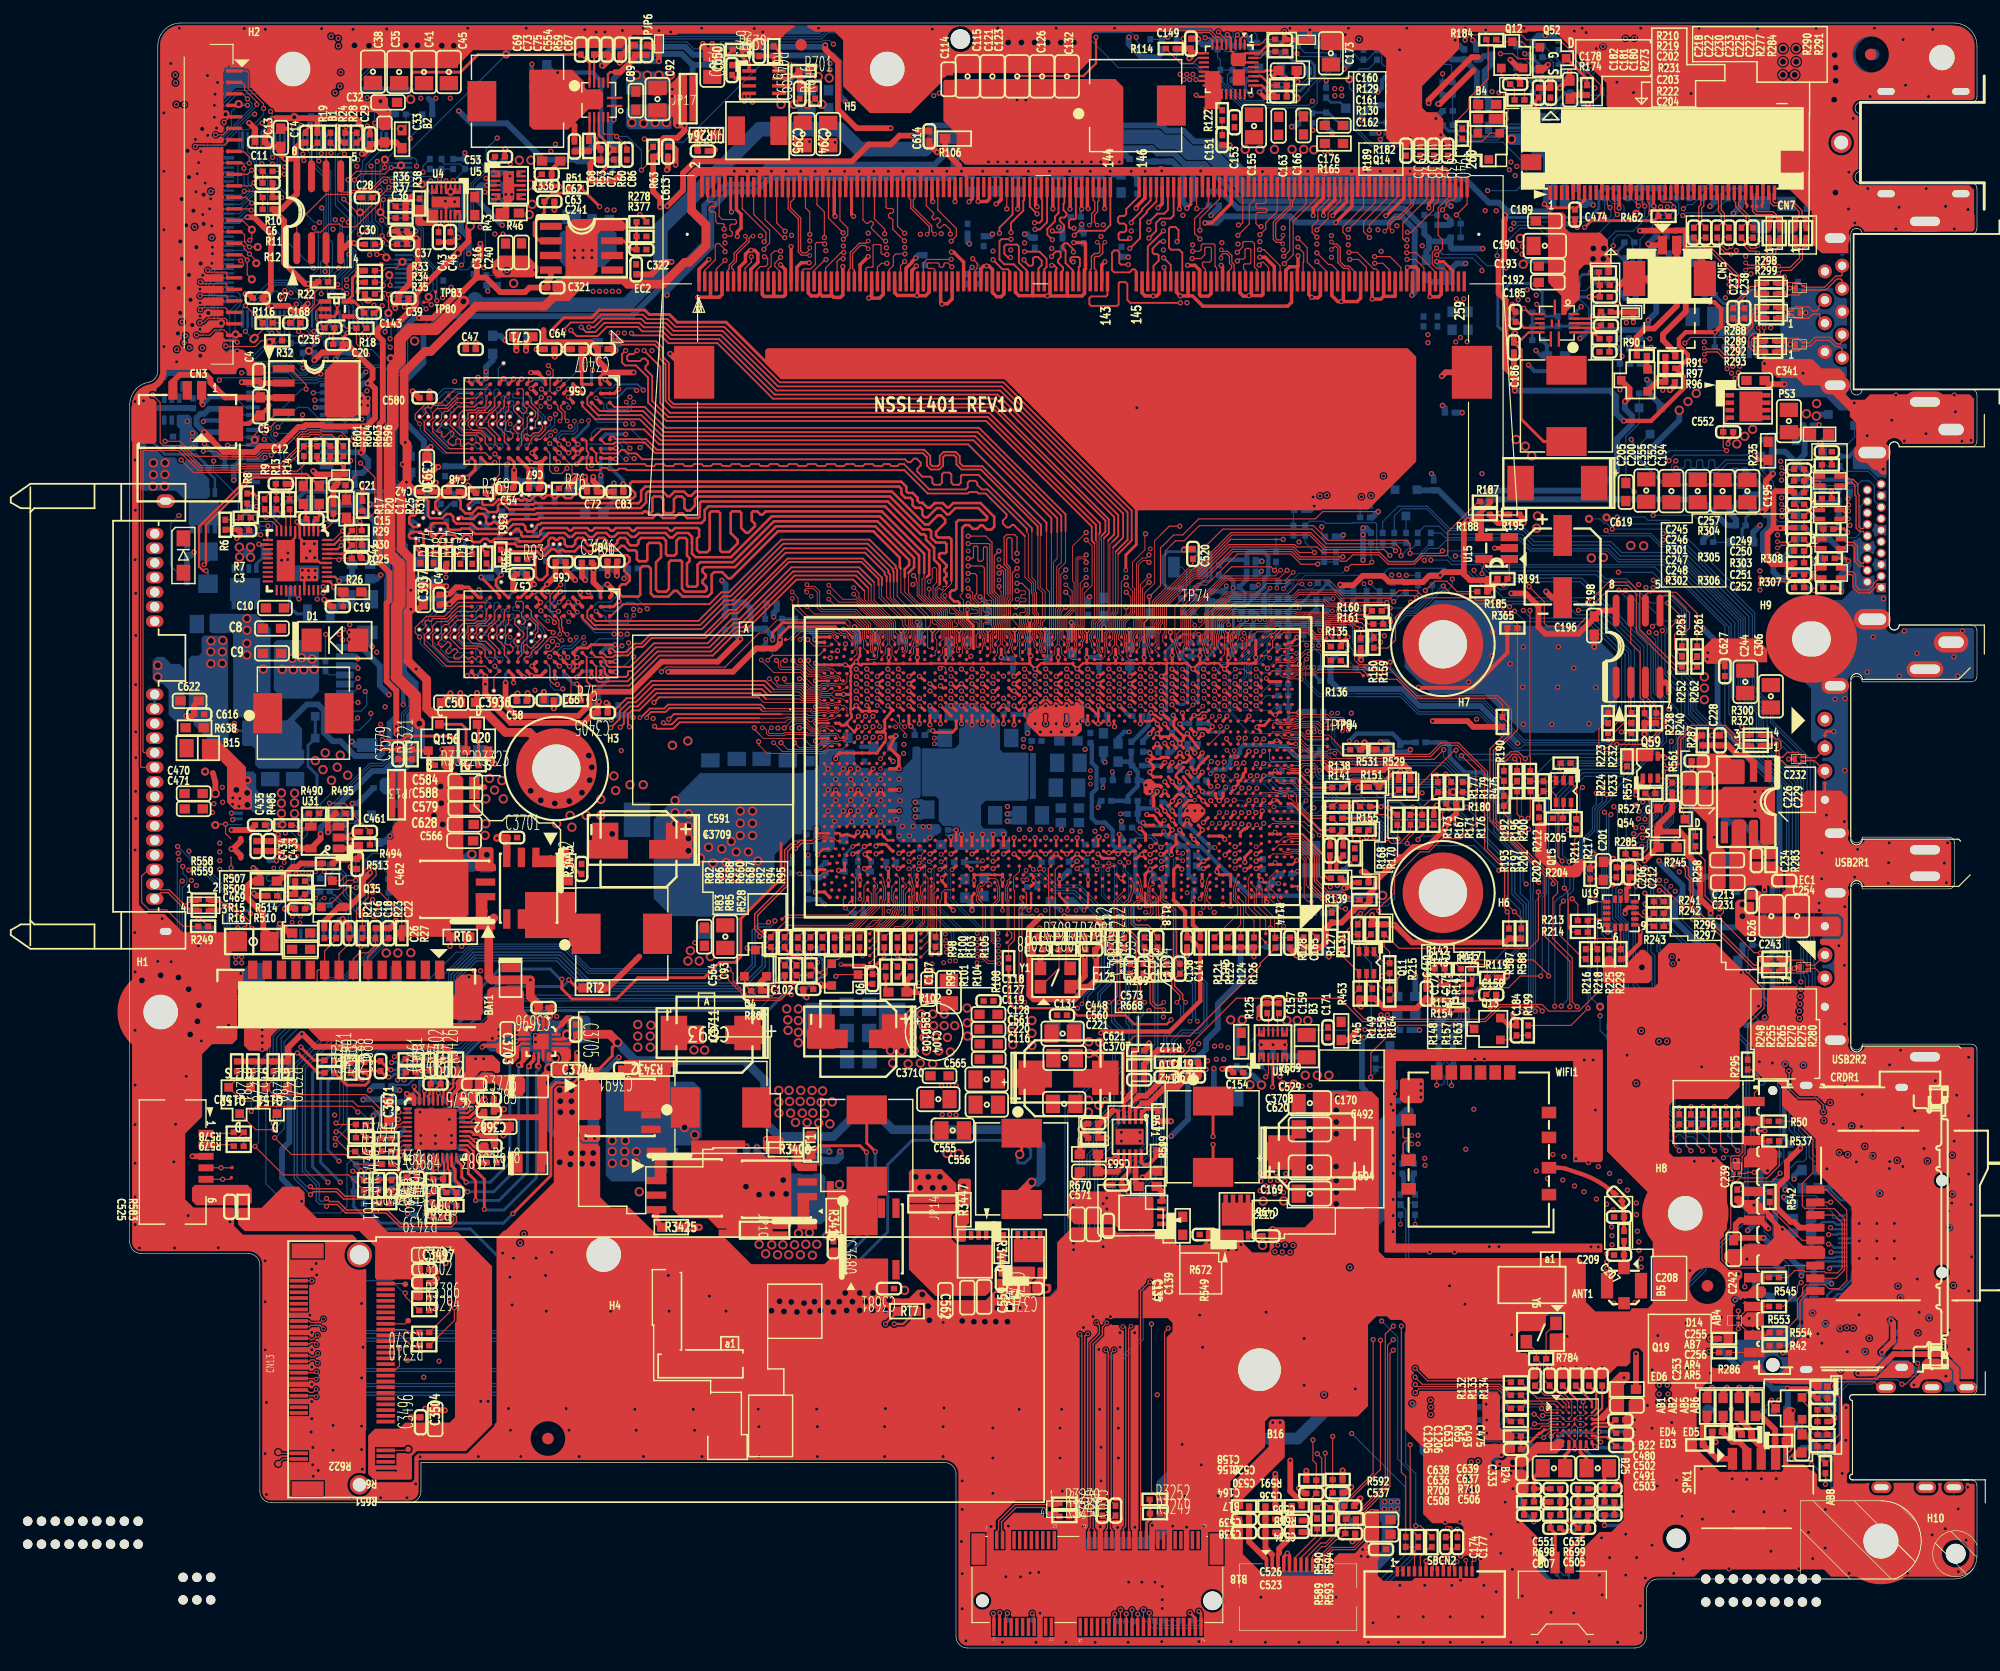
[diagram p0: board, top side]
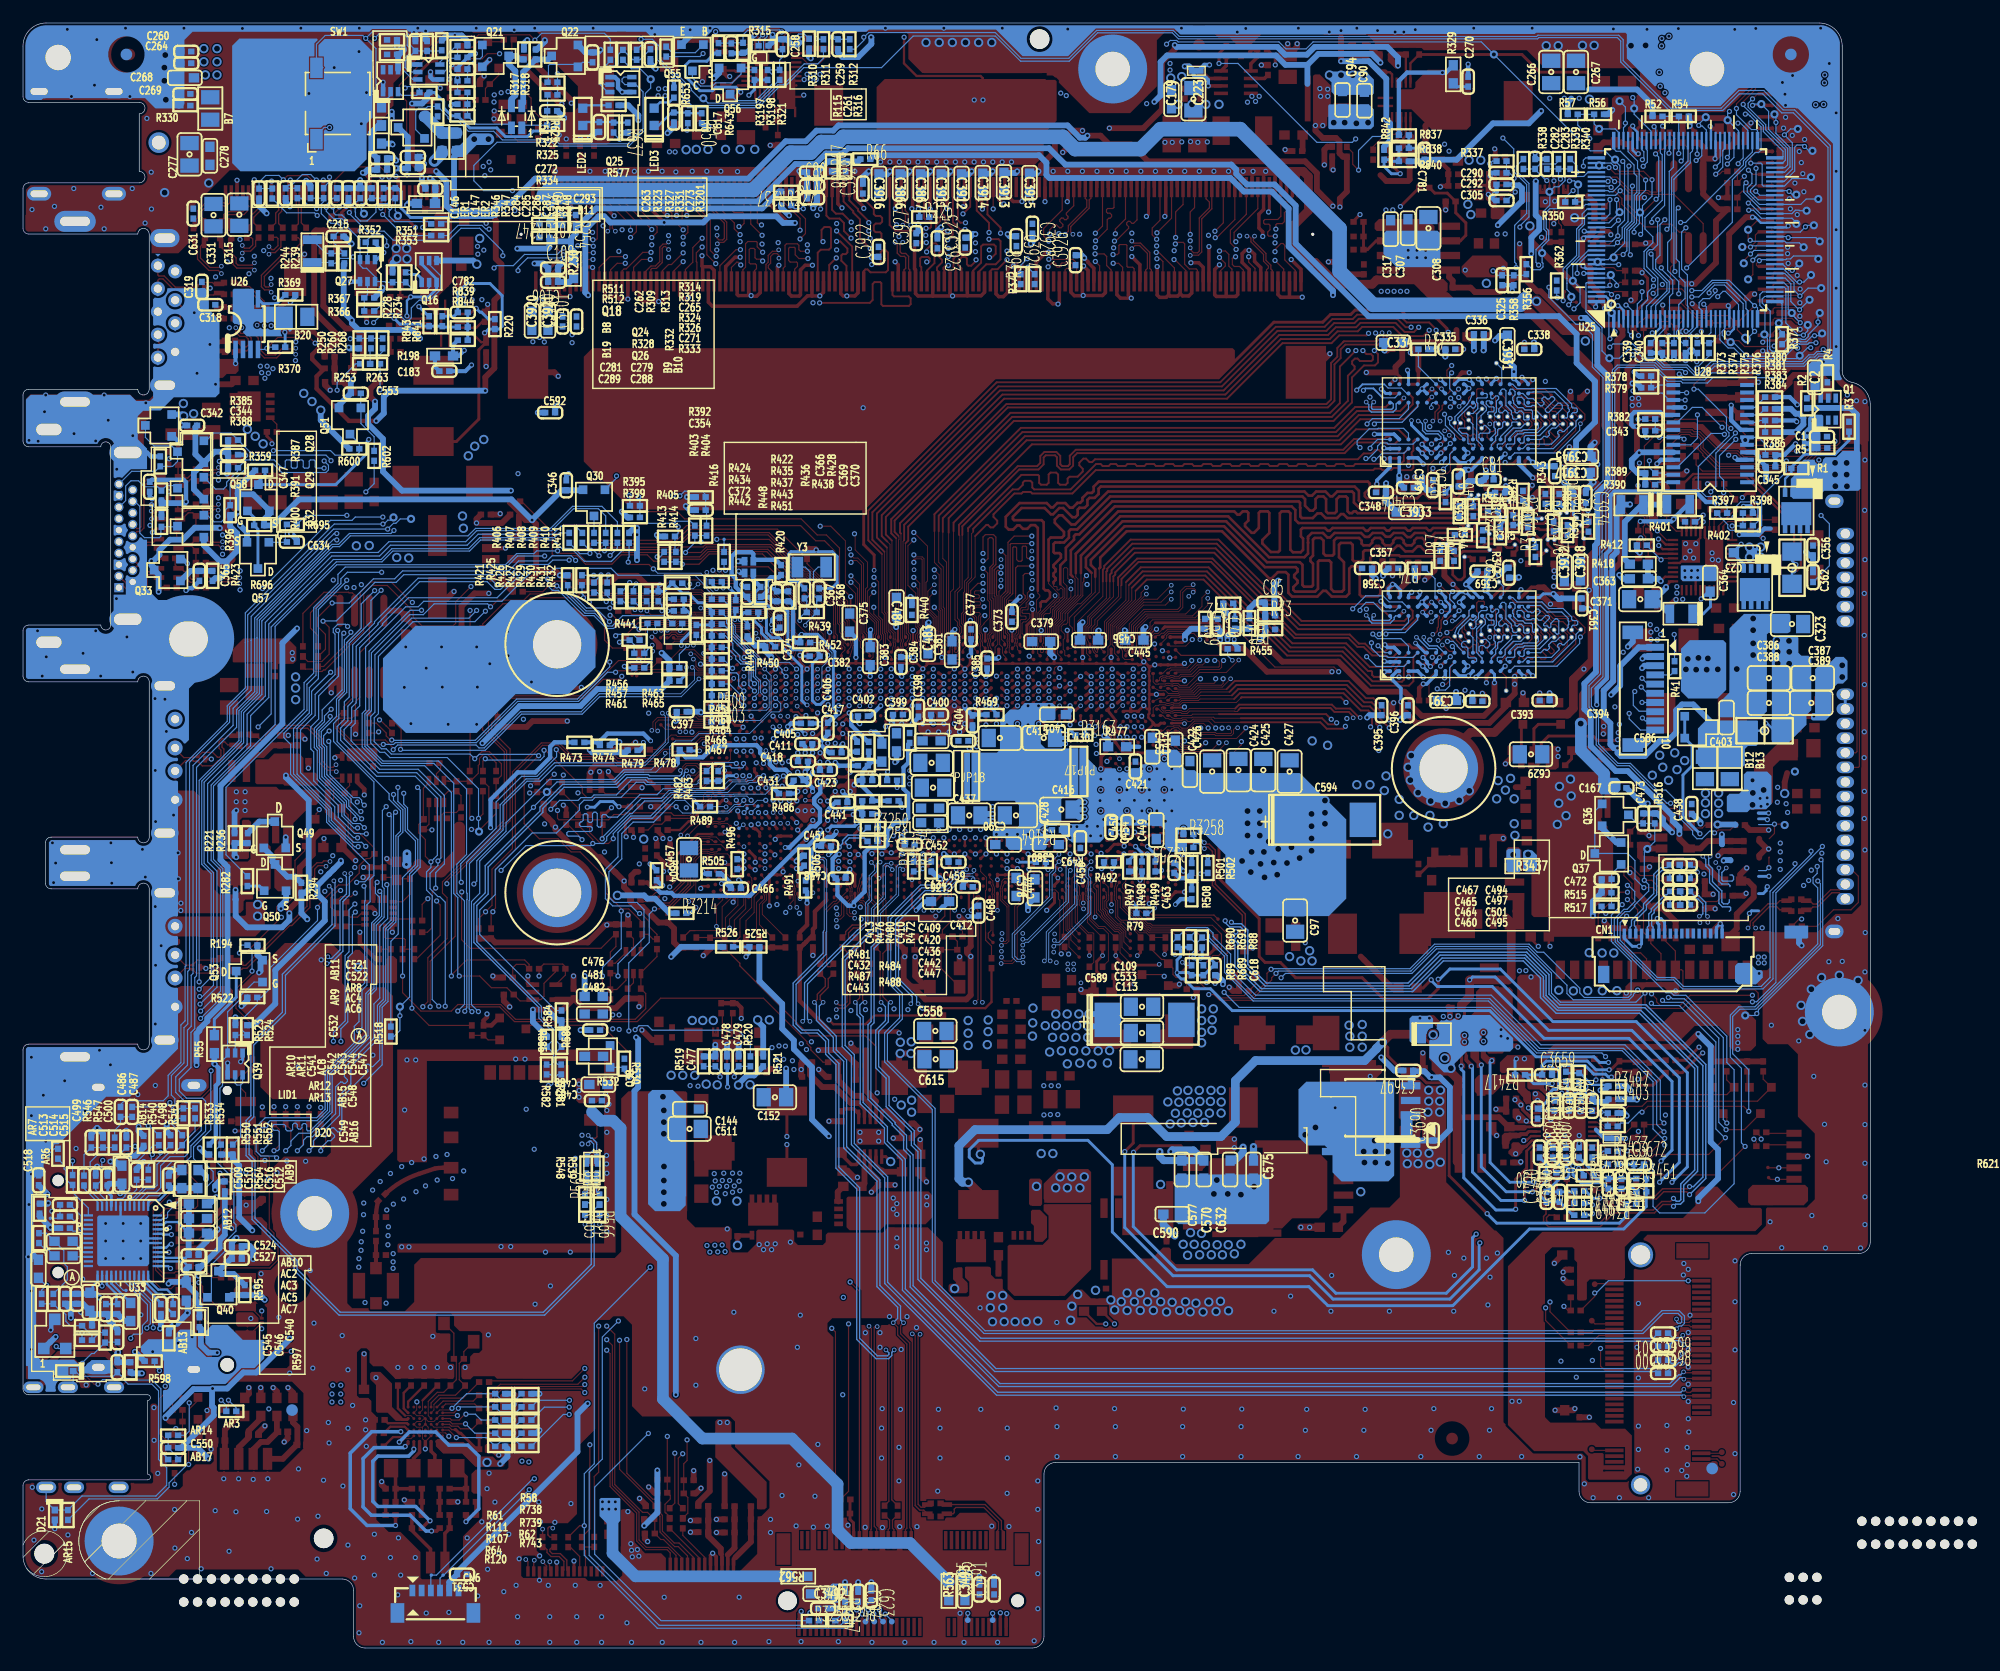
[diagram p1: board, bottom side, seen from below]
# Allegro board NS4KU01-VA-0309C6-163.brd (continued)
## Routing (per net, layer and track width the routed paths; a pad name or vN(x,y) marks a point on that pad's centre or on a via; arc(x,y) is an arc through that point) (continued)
+3.3VAL_BOOT: length 2.1
  TOP w0.203: U9.10 39.96,131.51 39.9,131.45
  TOP w0.508: 39.9,131.45 R53.1
+3.3VAL_BOOT1: length 1.3
  TOP w0.508: R53.2 39.85,130.13 C68.1
+3.3VAL_EN: length 11
  TOP w0.102: R63.2 44.98,130.03 44.98,129.02 v3(44.47,128.51) ; C86.1 43.2,130.54 v3(42.31,131.43) 42.12,131.63 41.26,131.63 41.16,131.73 U9.13
  BOTTOM w0.102: v3(42.31,131.43) 43.27,131.43 44.47,130.23 v3(44.47,128.51)
+3.3VAL_SN: length 1.4
  BOTTOM w0.254: C270.1 35.96,135.77 R329.2
+3.3VAL_SW: length 12.1
  TOP w0.508: C68.2 38.65,132.37 38.12,132.9
  BOTTOM w0.381: R329.1 36.88,136.99 v3(37.18,136.99) 40.25,136.99 40.97,136.27 R837.1
+3.3VAL_VBYP: length 4.9
  TOP w0.203: 42.18,137.02 41.75,137.02 41.56,136.84 U9.3
  TOP w0.508: C87.1 R59.1 43.92,138.32 42.63,137.02 42.18,137.02
+3.3VAL_VCC: length 3.1
  TOP w0.203: U9.11 40.36,131.5 40.59,131.27 40.59,130.89
  TOP w0.508: 40.59,130.89 40.59,130.65 40.92,130.33 C74.1
+3.3VDVDD: length 5.6
  BOTTOM w0.203: C516.1 147.87,39.76 148.69,38.94 149.46,38.94 149.66,38.74 U33.1
  BOTTOM w0.508: C516.1 147.64,39.99 C512.1 AB9.1
+3.3VS: length 87.9
  L4_IN2 w0.508: v4(34.72,124.65) 29.33,124.65 27.96,123.27 25.61,123.27 25.1,123.78 22.51,123.78 22.3,123.57 21.65,123.57 21.47,123.75 19.88,123.75 19.18,123.05 18.79,123.05 18.04,122.3 15.36,122.3 13.87,120.81 13.87,119.25 12.53,117.92 12.53,117.41 12.93,117.01 12.93,112.11 13.05,111.99 13.05,109.31 13.67,108.69 13.67,104.17 12.42,102.92 10.42,102.92 v3(9.04,101.54)
  BOTTOM w0.381: U28.5 10.04,103.97 9.68,103.61 9.68,103.37 9.11,102.79 C345.2
  BOTTOM w0.508: v3(9.04,101.54) 9.05,101.55 9.05,102.66 C345.2 ; R525.2 96.54,58 94.56,56.02 94.56,53.86 93.54,52.84 93.54,52.08 91.97,50.51 91.97,45.96 v3(90.51,44.5)
  BOTTOM w1.016: 109.31,11.1 109.31,8.24 107.3,6.23 R562.2
  vias: v3(99.53,34.47) v3(99.78,35.04) v3(100.16,34.45) v3(100.42,35.02) v3(100.85,34.43) v3(101.1,35) v3(109.04,12.07) v3(109.06,12.71) v3(109.62,12.71) v3(109.62,12.07) v3(110.18,12.71) v3(110.18,12.07) v4(34.97,125.53)
+3.3VS_ON: length 243.6
  L3_IN1 w0.102: v3(128.3,97.18) 128.3,97.45 123.35,102.41 122.18,102.41 118.24,106.35 118.24,116.89 120.75,119.4 121.38,119.4 122.09,120.12 122.09,124.47 117.65,128.91 91.68,128.91 91.66,128.93 91.64,128.93 90.01,130.56 74.24,130.56 72.99,129.32 72.99,128.1 72.53,127.64 67.46,127.64 66.98,127.16 51.66,127.16 48.46,130.36 38.31,130.36 35.34,127.39 32.48,127.39 31.69,128.18 26.27,128.18 26.14,128.05 v3(26.14,127.57)
  L4_IN2 w0.102: v3(145.23,57.92) 142.66,55.35 141.51,55.35 139.94,53.78 132.55,53.78 131.72,52.95 108.06,52.95 107.34,53.66 v3(107.34,53.77)
  BOTTOM w0.102: v3(107.34,53.77) 107,54.11 106.24,54.11 105.85,53.72 98.38,53.72 97.33,52.66 R520.1 ; v3(26.14,127.57) 25.71,127.57 v1(25.39,127.26) 25.39,127.26 25.39,126.3 25.65,126.04 R350.1 25.06,125.74 24.88,125.92 U25.106 ; v3(145.23,57.92) 145.23,75.44 141.78,78.9 141.78,81.5 140.2,83.07 140.2,87.83 140.2,89.46 133.69,95.97 133.11,95.97 132.17,96.91 128.57,96.91 v3(128.3,97.18)
+5V: length 192.1
  TOP w0.203: U110.4 34.76,54.06 ; 29.61,45.31 U109.26
  TOP w0.254: 30.1,45.24 30.02,45.31 29.61,45.31
  TOP w0.508: B18.1 96.42,14.34 99.34,17.26 v3(99.34,19.61) ; v3(112.88,134.33) 112.88,134.58 116.64,138.34 117.18,138.34 ; v3(130.9,25.58) 130.91,25.56 B22.1 ; 30.1,45.24 31.28,45.24 C3682.2 31.45,45.33 32.28,46.15 35.71,46.15 35.9,45.96 ; v3(9.72,110.07) 10.74,110.07 10.87,110.19 C4.1 11.42,109.99 U2.2
  TOP w0.762: D34.A 35.9,42.3 35.9,48.74 D26.A 35.8,49.42 36.42,50.04 36.42,50.38 v4(36.45,50.41)
  L3_IN1 w0.508: v3(37,130.76) 36.73,131.03 32.49,131.03 32.05,130.59 24.41,130.59 23.69,129.88 21.16,129.88 20.36,129.07 20.36,128.64 19.98,128.26 17.16,128.26 13.02,124.11 13.02,119.92 11.76,118.66 11.76,116.14 13,114.9 13,111.15 13.74,110.41 13.74,106.35 14.52,105.56 14.52,104.37 10.43,100.28 10.43,96.93
  L4_IN2 w0.508: v3(37,130.76) 43.45,130.76 44.48,131.8 48.52,131.8 48.93,132.21 62.37,132.21 63.03,131.55 67.25,131.55 68.22,132.52 71.68,132.52 72.37,133.21 89.56,133.21 90.16,132.61 99.6,132.61 100.51,133.53 105.43,133.53 106.7,132.26 107.3,132.26 109.37,134.33 v3(112.88,134.33)
  BOTTOM w0.381: v3(146.37,99.68) 146.37,101.37 146.58,101.58 149.35,101.58 C347.1
  BOTTOM w0.508: v3(128.49,133.59) v3(128.49,133) ; v4(146.58,107.12) 146.72,107.26 D15.2 ; R3407.2 21.21,48.86 v3(20.85,48.5) ; AB10.2 144.42,38.74 144.22,38.74 v3(143.76,39.2) ; R597.2 145.08,27.77 145.08,26.32 144.44,25.68 v3(143.66,25.68) ; v3(146.37,99.68) 146.5,99.55 148.28,99.55 R391.2 R400.1
  BOTTOM w1.016: B9.1 124.12,129.96 v4(124.79,129.3)
  vias: v1(10.23,75.45) v3(8.94,73.37) v3(8.96,73.92) v3(9.5,73.19) v3(9.57,73.87) v3(11.52,53.77) v3(11.52,53.2) v3(11.52,52.63) v3(11.52,52.06) v3(27.14,78.16) v3(27.14,77.52) v3(31.52,53.01) v3(32.09,53.77) v3(32.09,53.2) v3(99.97,19.61) v4(9.27,74.61) v4(10.21,74.35) v4(10.23,73.31) v4(145.71,107.32) v4(146.6,108.21)
+5V_AMP: length 10.6
  BOTTOM w0.203: U33.46 148.33,36.81 148.11,37.04 147.08,37.04 AC3.1 ; U33.39 148.28,34.01 148.2,33.93 146.39,33.93 AC5.1
  BOTTOM w0.508: AB10.1 AC2.1 146.12,36.18 ; 146.12,36.18 146.15,36.15 AC5.1 ; 146.12,36.18 AC3.1
+5V_CODECAVDD: length 14.6
  BOTTOM w0.203: U33.25 154.06,31.89 154.48,31.48 154.48,31.15 C542.1 ; U33.38 146.6,33.61 AC7.1
  BOTTOM w0.508: C541.1 AC8.1 154.83,30.79 ; 154.83,30.79 154.22,30.79 v3(153.89,30.46) ; 154.83,30.79 C542.1 ; R597.1 145.21,29.85 145.54,30.18 145.54,30.82 146.35,31.63 C540.2 ; C540.2 146.4,31.83 147.75,31.83 v3(147.9,31.68) ; C540.2 146.35,32.95 AC7.1
+5V_ON: length 230.4
  TOP w0.102: R113.1 114.27,58.79 115.26,57.79 115.26,56.65 115.53,56.38 Q10.1 116.35,56.27 117.34,56.27 C150.1 118.48,57.41 119.83,57.41 120.85,58.43 v3(122.63,58.43)
  L4_IN2 w0.102: v3(7.13,122.64) 7.36,122.64 8.53,123.81 8.53,129.44 10.11,131.02 14.06,131.02 14.41,131.38 20.73,131.38 21.19,130.92 21.48,130.92 21.58,130.82 26.58,130.82 28.26,129.14 32.99,129.14 v3(33.06,129.07) 33.19,129.07 33.39,128.86 33.39,128.81 33.62,128.58 43.9,128.58 44.22,128.89 45.11,128.89 46.12,129.91 68.7,129.91 69.65,130.86 72.32,130.86 73.04,131.59 88.88,131.59 89.61,130.86 94.57,130.86 96.04,129.4 114.95,129.4 115.71,128.64 118.63,128.64 122.86,124.41 126.75,124.41 128.39,122.77 129.19,122.77 129.77,122.19 129.77,116.81 129.11,116.15 129.11,111.6 130.87,109.83 130.87,101.04 130.74,100.91 v3(130.74,100.53) 130.74,100.36 129.94,99.56 129.94,97.75 128.66,96.46 128.66,93.95 125.91,91.2 v3(125.91,90.23)
  BOTTOM w0.102: R602.2 130.02,101.25 v3(130.74,100.53) ; v3(125.91,90.23) 126.9,90.23 130.46,86.67 130.46,81.58 130.83,81.22 130.83,78.41 129.34,76.92 124.84,76.92 123.11,75.19 123.11,65.61 122.75,65.25 122.75,58.56 v3(122.63,58.43) ; v3(33.06,129.07) 32.84,129.29 R337.1 ; v1(4.39,122.31) 4.72,122.64 v3(7.13,122.64) 7.22,122.72 U25.47
+5V_ON_1: length 5.5
  BOTTOM w0.102: R602.1 130.02,105.32 131.17,106.47 Q51.G 131.19,107.84 C553.1
+5VAL: length 341.3
  TOP w0.203: U5.4 v3(31.03,127.19) ; v3(27.49,127.57) 27.48,127.56 U4.4 ; U13.9 92.62,138.67 92.43,138.87 ; v3(99.31,48.79) 99.36,48.83 U14.4 ; C186.1 120.32,113.55 120.72,113.55 121.57,114.4 U18.7
  TOP w0.254: 92.43,138.87 C149.1 ; L9.2 122.88,104.9 120.93,106.86 120.93,112.88 C186.1
  TOP w0.508: v3(42.57,137.85) 42.63,137.91 C554.2 42.82,138.56 43.64,139.38 R59.2 ; v3(30.47,122.11) 30.47,120.92 30.17,120.62 30.17,119.21 30.21,119.17 ; R114.2 92.22,139.07 C149.1 92.22,138.36 v3(92.08,138.22) ; v3(48.22,132.38) 48.22,131.94 47.58,131.31 46.44,131.31 46.12,130.99 46.12,129.97 45.82,129.67 R63.1 45.49,126.64 46.1,126.03 v3(46.1,125.3) ; v3(120.42,114.35) 120.29,114.23 C186.1 ; U8.4 36.6,119.2 36.29,118.9 C321.1 34.74,118.29 34.35,117.9 32.2,117.9 30.93,119.17 30.21,119.17 ; 30.21,119.17 30.15,119.17 28.95,117.97 28.64,117.97 26.33,115.65 v3(25.14,115.65) ; R670.2 v3(82.57,44.21) ; v3(16.59,70.79) 16.59,70.37 U31.5 14.76,69.52 14.12,70.16 C433.1 C434.1 ; C232.1 136.6,77.47
  L3_IN1 w0.508: v3(30.47,122.11) 30.47,122.61 31.37,123.51 31.58,123.72 v3(32.37,123.72) 33.02,123.72 33.87,122.87 38.01,122.87 38.69,123.55 44.1,123.55 45.84,125.3 v3(46.1,125.3) ; v3(31.03,127.19) 30.11,127.19 29.83,126.9 27.92,126.9 27.49,127.33 v3(27.49,127.57) ; v3(82.57,44.21) 83.38,44.21 85.67,46.49 86.18,46.49 87.83,48.14 98.62,48.14 99.26,48.79 v3(99.31,48.79) 99.95,48.14 103.01,48.14 103.48,48.61 103.54,48.68 103.65,48.72 103.83,48.9 105.04,48.9 109.05,52.91 110.06,52.91 114.92,57.77 133.82,57.77 135.84,59.79 v3(135.84,63.36) 135.84,64.31 136.09,64.57 136.09,73.8 134.57,75.32 134.57,88.15 130.5,92.21 130.5,92.72 134.18,96.4 134.18,98.34 129.1,103.42 129.1,106.83 129.64,107.37 133.48,107.37 133.59,107.49
  L4_IN2 w0.381: v3(92.08,138.22) 88.76,138.22 88.65,138.12 73.83,138.12 71.78,136.07 70.63,136.07 70.35,135.79 v3(70.35,135.2)
  BOTTOM w0.254: v3(120.42,114.35) 120.09,114.69 R220.2 119.15,114.69 118.89,114.94 118.89,117.59 119.95,118.64 121.95,118.64 122.76,117.84 C782.2 123.09,115.8 R841.1 ; 99.31,50.11 99.31,50.53 C478.2 99.36,50.16 99.31,50.11 ; 99.31,50.11 v3(99.31,48.79)
  BOTTOM w0.381: C292.2 31.11,127.26 v3(31.03,127.19)
  BOTTOM w0.508: 48.92,137.66 50.83,137.66 51.65,138.48 61.11,138.48 61.68,137.91 61.68,134.99 v3(62.22,134.45) ; 48.92,137.66 48.92,136 ; 48.92,137.66 47.96,138.61 43.33,138.61 v3(42.57,137.85) ; v3(92.08,138.22) 92.22,138.36 C149.1 ; B11.1 127.03,125.61 v3(127.17,125.47) ; v3(32.37,123.72) 30.27,125.82 30.27,126.93 30.52,127.19 v3(31.03,127.19) ; R600.1 134.66,106.76 v4(134.66,107.63) ; v3(137.69,75.87) 137.69,75.7 135.71,73.72 135.71,65.98 136.01,65.67 R294.1 136.34,63.89 135.84,63.38 v3(135.84,63.36) ; v3(25.14,115.65) 24.73,115.65 23.72,114.64 23.72,111.53 22.82,110.63 22.82,101.32 23.72,100.41 23.72,96.07 23.92,95.86 23.92,92.3 23.84,92.22 23.84,84.86 24.85,83.86 24.85,81.65 24.29,81.09 24.29,78.43 22.11,76.25 21.07,76.25 17.17,72.35 17.17,71.91 16.59,71.33 v3(16.59,70.79)
  vias: v3(47.16,135.54) v3(47.15,134.92) v3(47.58,132.38) v3(47.84,135.6) v3(47.77,134.92) v3(62.89,134.29) v3(69.87,134.99) v3(119.9,128.53) v3(120.04,129.21) v3(120.41,128.03) v3(120.54,128.83) v3(138.82,111.24) v3(139.21,110.85) v3(139.33,111.46) v3(139.52,110.41) v3(139.8,110.9) v3(139.91,111.45) v4(135.43,108.39) v4(136.14,109.09)
+5VAL_BOOT: length 2.4
  TOP w0.203: R222.1 127.18,114.4 U18.10
+5VAL_BOOT1: length 1.1
  TOP w0.203: R222.2 C204.1
+5VAL_EN: length 12.2
  TOP w0.203: v3(126.85,117.48) C202.1 R219.1 127.69,118.57 R210.2 ; U18.13 126.94,115.6 v3(127.18,115.83)
  BOTTOM w0.203: v3(127.18,115.83) 127.18,117.16 v3(126.85,117.48)
  BOTTOM w0.254: Q16.6 125.9,120.34 124.59,119.04 Q16.3 124.59,118.18 125.29,117.48 v3(126.85,117.48)
+5VAL_LDO: length 2.3
  TOP w0.203: C185.1 120.63,115.32 121.15,114.8 U18.6
+5VAL_LX: length 2.7
  BOTTOM w0.356: v3(122.2,112.83) 122.68,112.35 R198.1 123.16,113.31 R844.1
+5VAL_SN: length 1.5
  BOTTOM w0.356: C183.1 124.74,111.41 R198.2
+5VAL_VBYP: length 3.6
  TOP w0.203: U18.3 121.7,116 121.22,116.48 v3(121.16,116.48)
  BOTTOM w0.254: v3(121.16,116.48) 120.83,116.16 120.7,116.16 120.09,115.55 R220.1
+5VAL_VCC: length 2.4
  TOP w0.203: U18.11 127.67,114.8 C203.1
+5VS_PANEL: length 3.8
  TOP w0.305: v3(125.17,127.82) 125.44,127.55 CN7.5
  BOTTOM w0.508: B11.2 124.71,125.64 C293.1 124.71,127.34 125.17,127.8 v3(125.17,127.82)
+V1.00A_SIP: length 25.1
  TOP w0.203: v3(91.25,75.32) 91.25,75.42 U11.Y18 90.93,75.93 U11.AB17
  L4_IN2 w0.381: v2(94.31,69.61) 94.23,69.61 93.93,69.3 93.93,67.32 95.43,65.81 100.38,65.81 101.26,66.68 101.72,66.68 101.98,66.94 104.31,66.94 v3(104.95,66.3)
  BOTTOM w0.381: v3(104.95,66.3) 105.03,66.3 R504.2 ; v2(94.31,69.61) 93.93,69.61 92.08,71.45 91.69,71.45 91.28,71.85 91.28,72.93 91.77,73.42 91.77,73.86 91.25,74.38 v3(91.25,75.32)
+V1.8A_SIP: length 4.4
  TOP w0.203: R138.1 102.86,74.81 101.6,76.08 U11.AA1
+V1.8S_EDRAM: length 3.3
  BOTTOM w0.381: C463.2 60.45,67.39 59.99,66.94 59.43,66.94 R501.1 R508.1
+VCCAMPHYPLL_1P0: length 13.7
  TOP w0.254: U11.L15 v3(93.22,71.13) U11.K15
  L4_IN2 w0.381: v2(99.84,66.48) 99.63,66.26 96.76,66.26 94.69,68.34 94.69,68.74 94.68,68.76 94.68,69.19 94.81,69.33 94.81,69.85 93.53,71.13 v3(93.22,71.13)
  BOTTOM w0.381: v2(99.84,66.48) 99.42,66.48 C466.2 99.01,66.49 99.84,67.32 R505.2
+VCCAPLL_1P0: length 1.4
  TOP w0.254: v3(93.22,74.48) U11.V15
  BOTTOM w0.381: v3(93.22,74.48) 93.4,74.3 R486.2
+VCCAPLLEBB_1P0: length 9.5
  TOP w0.254: v3(90.6,72.8) U11.N18
  L4_IN2 w0.381: v2(84.14,73.08) 84.68,73.62 86.3,73.62 86.59,73.33 90.14,73.33 90.47,73 90.47,72.92 v3(90.6,72.8)
  BOTTOM w0.381: v3(90.6,72.8) 90.47,72.92 90.47,73 89.93,73.54 C441.2 ; v2(84.14,73.08) 84.25,73.19 84.25,73.46 R488.2
+VCCCLKX: length 52.3
  TOP w0.203: v3(95.68,64.53) U11.A10 ; R108.2 76.37,56.17 76.91,55.64 81.73,55.64 82.37,55 86.56,55 87.32,54.24 90.12,54.24 v3(90.5,54.62)
  TOP w0.254: v3(88.08,71.76) 88.08,71.75 88.28,71.55 U11.L21 ; U11.K19 90.28,70.73 90.59,71.13 v3(90.6,71.13) 90.28,71.46 U11.L19 ; U11.A14 93.2,65.55 93.06,65.16 v2(93.01,65.16) ; v3(89.3,72.81) U11.N20
  L3_IN1 w0.203: v3(90.5,54.62) 90.37,54.75 90.37,63.51 92.27,65.41 92.75,65.41 v2(93.01,65.16)
  L3_IN1 w0.381: v3(95.68,64.53) 95.68,64.81 95.2,65.29 93.14,65.29 v2(93.01,65.16)
  L4_IN2 w0.381: v2(93.01,65.16) 93.01,65.44 92.2,66.26 92.2,69.81 91.51,70.49 90.86,70.49 90.6,70.75 v3(90.6,71.13)
  BOTTOM w0.305: v3(90.6,71.13) 90.28,71.46 88.28,71.46 88.08,71.66 v3(88.08,71.76) 87.8,71.76 87.6,71.97 C443.2
  BOTTOM w0.381: R487.2 87.6,72.7 ; 87.6,72.7 C443.2 ; 87.6,72.7 87.9,73.01 89.1,73.01 v3(89.3,72.81)
+VCCDSW_1P0: length 2.2
  TOP w0.152: v3(101.61,81.35) 101.6,81.33 100.73,81.33 U11.AL1
  BOTTOM w0.508: v3(101.61,81.35) 101.68,81.41 C397.2
+VCCDTS_1P0: length 4.8
  TOP w0.203: U11.T1 101,73.43 102.54,71.89 102.69,71.89 103.45,71.13 R143.2
+VCCFHV: length 4.3
  TOP w0.203: U11.AK20 89.25,81 89.25,81.01 89.13,81.13 89.04,81.13 v3(88.74,81.31)
  BOTTOM w0.381: R476.2 87.12,78.8 88.56,80.25 88.56,81.13 v3(88.74,81.31)
+VCCMPHYAON_1P0: length 20.1
  TOP w0.254: v3(91.25,71.13) U11.K17
  TOP w0.381: R139.1 105.53,66.65 v3(105.53,66.08) 105.79,66.08 106.27,66.56 R153.2
  BOTTOM w0.381: v3(91.25,71.13) 91.25,70.8 92.32,69.73 93.04,69.73 97.36,65.41 103.93,65.41 104.18,65.66 104.56,65.66 104.58,65.68 105.14,65.68 v3(105.53,66.08)
+VCCMPHYAON_1P0_C: length 6.3
  TOP w0.203: R139.2 104.09,66.94 103.7,67.32 103.7,68.97 101.9,70.77 U11.L1
+VCCMPHYGTAON_1P0_LS_SIP: length 4
  TOP w0.254: U11.N15 93.22,72.73 v3(93.22,72.81) ; U11.N17 91.92,72.73 v3(91.92,72.81) 92.23,73.12 U11.P16 ; U11.N16 92.57,72.73 v3(92.57,72.81) 92.88,73.12 U11.P15
  TOP w0.381: C175.2 105.45,70.29 v3(105.56,70.39) ; C172.2 v3(104.31,70.37)
  vias: v4(106.6,70.34)
+VCCOPC: length 7.6
  TOP w0.254: U11.AE62 v3(66.58,79.32) U11.AG62
  TOP w0.305: U11.AB62 66.58,76.45 ; 66.58,76.45 v3(66.88,76.45) ; 66.58,76.45 66.85,76.72 66.85,77.48 U11.AE62 ; v3(66.88,74.62) U11.V62 ; v3(66.88,72.79) U11.P62
  BOTTOM w0.508: v3(66.58,79.32) 66.24,78.98 R477.2
+VCCOPC_TP: length 1.1
  BOTTOM w0.381: R477.1 TP61.1
+VCCPAZIO: length 24.8
  TOP w0.254: v3(89.95,80.35) U11.AJ19
  L3_IN1 w0.254: v3(89.95,80.35) 90.16,80.56 90.16,81.29 90.44,81.57 90.76,81.57 91.29,82.1 91.69,82.1 91.94,82.36 91.94,84.29 92.2,84.54 92.73,84.54 92.86,84.67 92.86,85.31 93.13,85.58 93.41,85.58 94.97,87.13 98.87,87.13 100.49,88.75 101.85,88.75 102.97,87.64 103.33,87.28 v2(103.33,87.17)
  BOTTOM w0.254: v2(103.33,87.17) 103.33,87.55 102.53,88.34 102.53,89.89 102.83,90.18 C372.2 R434.2
+VCCPDSW_3P3: length 20.2
  TOP w0.254: U11.AD18 91.2,77.76 v3(91.27,77.84) U11.AD17 ; v3(91.25,80.35) U11.AJ17
  L3_IN1 w0.279: 91.95,78.91 93.43,78.91 93.69,79.18 94.45,79.18 94.87,79.6 97.13,79.6 97.42,79.32 97.42,78.79 97.71,78.5 99.1,78.5 99.4,78.2 100.32,78.2 101.04,77.48 101.89,77.48 102.53,78.11 104.4,78.11 104.54,78.25 106.26,78.25 106.63,78.62 v2(106.63,78.75)
  BOTTOM w0.381: v2(106.63,78.75) 106.63,78.39 106.95,78.06 R479.2 ; v3(91.25,80.35) 91.3,80.4 C405.2
+VCCPGPPF_1P8: length 19.6
  TOP w0.254: v3(92.57,77.84) U11.AF16
  TOP w0.508: v3(106.75,74.81) 106.79,74.86 R151.1
  L3_IN1 w0.381: v3(92.57,77.84) 92.57,77.92 93.09,78.44 93.78,78.44 94.05,78.72 94.95,78.72 95.11,78.56 96.16,78.56 96.48,78.24 96.48,78.03 97.05,77.46 99.07,77.46 99.73,76.8 99.77,76.8 100.06,76.51 100.06,76.47 100.33,76.2 100.33,75.48 101.58,74.23 106.16,74.23 v3(106.75,74.81)
  BOTTOM w0.381: C411.2 92.57,78.38 v3(92.57,77.84)
+VCCPGPPX: length 35.1
  TOP w0.254: v3(93.36,80.98) 93.15,80.77 U11.AK15 ; v3(93.21,79.43) 92.88,79.1 U11.AG15 ; v3(91.92,76.16) U11.Y16 ; v3(91.92,74.48) U11.T16 ; v3(93.22,76.16) U11.Y15
  L3_IN1 w0.254: 99.73,81.77 99.1,81.77 98.82,81.49 93.93,81.49 93.43,80.98 v3(93.36,80.98) ; v3(93.21,79.43) 93.21,79.97 93.82,80.58 95.16,80.58 95.17,80.57 100.07,80.57 100.28,80.77 100.28,80.78
  L3_IN1 w0.508: 99.73,81.77 100.12,81.38 100.12,80.94 101.29,79.77 101.29,79.64 102.05,78.88 v2(105.99,78.88)
  BOTTOM w0.381: v3(93.22,76.16) 93.22,76.07 92.7,75.56 C431.2 92.6,75.45 ; v2(105.99,78.88) 106.62,79.51 109.75,79.51 110.33,78.93 110.33,78.57 R474.2 110.66,78.75 R473.1 ; v3(91.92,76.16) 91.92,76.07 92.54,75.45 92.6,75.45 ; v3(91.92,74.48) 91.92,74.76 92.6,75.45
+VCCPRIM_1P0: length 4.4
  TOP w0.254: v3(91.25,73.65) U11.P18 ; v3(89.95,77) U11.AB20 ; v3(90.6,77) U11.AB19
  BOTTOM w0.381: v3(90.6,77) 90.42,76.81 C423.2 ; v3(89.95,77) 89.67,76.72 R481.2
+VCCPRIM_3P3: length 11.5
  TOP w0.254: v3(88.65,79.51) U11.AJ21 ; v3(89.95,75.33) U11.V19
  L4_IN2 w0.381: 87.24,76.72 88.36,75.6 88.82,75.6 89.09,75.33 v3(89.95,75.33) ; 87.24,76.72 87.47,76.94 87.47,78.33 v3(88.65,79.51) ; 87.24,76.72 86.28,76.72 85.77,76.21 v2(85.39,76.21)
  BOTTOM w0.381: R484.2 85.44,76.16 v2(85.39,76.21) ; C413.2 88.06,78.92 v3(88.65,79.51)
+VCCPRTCPRIM_3P3: length 19
  TOP w0.254: v3(91.49,81.31) U11.AK17
  L3_IN1 w0.254: v3(91.49,81.31) 91.72,81.54 92.69,81.54 92.77,81.47 93.44,81.47 93.69,81.72 93.69,82.3 93.8,82.4 93.8,83.4 93.77,83.42 93.77,85.28 95.3,86.8 99.74,86.8 101.8,84.74 102.62,84.74 102.89,85.02 v2(102.89,85.27)
  BOTTOM w0.254: R465.2 102.89,84.69 v2(102.89,85.27)
+VCCPSPI: length 12
  TOP w0.305: U11.AJ16 92.23,79.91 92.58,79.56 v3(92.58,79.48)
  L3_IN1 w0.254: v2(101.75,78.01) 101.29,78.01 99.69,79.61 97.77,79.61 97.5,79.88 97.5,79.94 97.35,80.09 v2(95.37,80.09)
  BOTTOM w0.254: v3(92.58,79.48) 92.6,79.48 93.01,79.89 93.64,79.89 93.9,79.64 94.94,79.64 95.26,79.95 95.26,79.95 95.37,80.07 v2(95.37,80.09) ; v2(101.75,78.01) 102.51,78.01 R478.2
+VCCSA: length 85
  TOP w0.076: 87.79,69.44 87.68,69.59 87.57,69.77
  TOP w0.102: U11.J22 87.59,69.6 ; U11.J22 87.68,69.77 87.56,69.78 ; U11.J22 87.7,69.5 ; U11.J22 87.69,70.02
  TOP w0.203: 85.9,69.08 86.28,69.3 U11.G25 86.86,69.07 86.86,69.04 86.76,68.94 v3(86.76,69.07) 86.82,69.02 86.82,69.1 87.17,69.3 U11.G23 ; 85.9,69.08 v3(85.9,69.05) 85.9,68.99 ; 85.9,69.08 85.9,69.1 U11.G27 85.27,69.15 v3(85.09,69.15) 84.9,69.15 U11.G28
  TOP w0.254: v4(77.34,42.93) 77.51,43.1 L26.1
  BOTTOM w0.254: R3451.2 19.47,40.81 R3450.1 19.47,38.39 21.42,36.44 29.61,36.44 36.28,29.77 47.14,29.77 48.79,31.42 61.11,31.42 65.87,36.18 65.87,42.02 67.99,44.14 77.48,44.14 78.31,43.32 78.31,42.68 77.8,42.17 77.29,42.17 77.16,42.3 77.16,42.75 v4(77.34,42.93)
  BOTTOM w0.381: R3250.2 86.18,71.41 v3(86.18,71.89)
  vias: v3(83.89,71.03) v3(84.53,71.26) v3(84.91,70.62) v4(76.66,54.61) v4(76.67,53.6) v4(76.74,52.46) v4(78.4,54.56) v4(78.4,53.46) v4(78.4,52.39)
+VCCSFR: length 6.9
  TOP w0.254: U11.K21 89.55,70.71 89.56,70.7 U11.K20 89.86,70.95 v2(89.86,71)
  BOTTOM w0.381: v2(89.86,71) 89.89,70.97 89.89,70.93 89.93,70.8 90.03,70.7 90.21,70.52 90.6,70.52 91.18,69.94 C451.2 91.25,69.8 91.58,69.8 92.02,69.35 92.02,67.24 R491.2
+VCCSFR_OC: length 23.8
  TOP w0.203: v3(87.83,80.37) U11.AL23
  L3_IN1 w0.254: 86.79,81.41 v3(87.83,80.37) 86.25,80.37 85.15,81.47 84.9,81.47 84.63,81.74 84.63,84.67 84.63,84.67 84.63,85.45 85.06,85.89 85.06,85.91 85.54,85.43 85.54,81.64 85.77,81.41 86.79,81.41
  L3_IN1 w0.381: v3(83.42,91.41) 83.42,89.58 83.99,89.01 83.99,86.98 85.06,85.91
  BOTTOM w0.381: C402.2 87.98,80.52 v3(87.83,80.37)
  BOTTOM w0.508: v3(83.42,91.41) 83.29,91.28 R440.2
+VCCSRAM_1P0: length 4.5
  TOP w0.254: U11.AF20 89.63,78.29 v3(89.3,78.62) 88.98,78.3 U11.AF21 ; U11.T19 90.28,74.07 v3(89.95,74.48) 89.63,74.07 U11.T20
  BOTTOM w0.381: v3(89.3,78.62) 89.4,78.52 C417.2 ; v2(86.86,79.66) 86.43,79.66 85.9,79.13 R480.2
+VCCST_CPU: length 154.4
  TOP w0.254: R3413.2 21.04,43.17 v3(21.1,43.23) ; R528.2 59.22,59.36 59.84,58.73 v2(60.25,58.73) ; v2(63.7,60.21) 63.42,60.49 R95.2 ; R3414.2 20.15,44.74 v3(20.15,44.92) ; R86.2 56.92,60.84 57.6,60.15 58.06,60.15 v3(58.21,60) ; R92.1 61.26,60.59 61.34,60.51 v2(61.34,60.31) ; U11.A18 90.72,65.03
  TOP w0.381: 90.72,65.03 91.72,64.04 91.72,62.67 91.89,62.49 C145.2 92.1,61.78 92.49,61.39 92.49,61.38 92.66,61.21 92.67,61.21 92.96,60.92 R118.2 93.04,56.27 90.37,53.6 84.53,53.6 v3(84.4,53.48)
  L3_IN1 w0.381: v2(63.7,60.21) 63.48,59.99 63.48,54.99 58.94,50.44 56.11,50.44 56.08,50.42 55.82,50.42 54.56,49.16 54.56,46.42 54.56,46.02 57.2,43.37 57.51,43.07 59.05,43.07 59.84,43.85 62,43.85 63.28,45.14 66.45,45.14 69.59,48.27 81.11,48.27 83.27,50.43 84.27,50.43 85.29,51.44 85.29,52.71 84.53,53.48 v3(84.4,53.48)
  L4_IN2 w0.254: v2(63.7,60.21) 63.04,60.21 62.94,60.31 v2(61.34,60.31) 61.34,59.78 60.29,58.73 v2(60.25,58.73) ; v3(22.75,50.91) 20.21,50.91 19.2,49.9 19.2,45.96 20.15,45.01 v3(20.15,44.92) 20.15,44.37 21.1,43.42 v3(21.1,43.23) 21.1,41.86 v3(20.72,41.48)
  BOTTOM w0.254: v3(20.72,41.48) 20.53,41.67 C3672.1 R3527.2 ; v2(60.25,58.73) 59.25,58.73 59.03,58.5 R89.2 R689.2 57.91,58.5 57.05,59.36 C618.1 56.94,59.54 57.4,60 v3(58.21,60) 58.06,60.15 R88.2 ; v2(60.25,58.73) 60.25,58.53 59.88,58.17 59.63,58.17 58.79,57.33 57.35,57.33 55.45,55.42 33.06,55.42 29.05,51.41 24.01,51.41 23.52,50.91 v3(22.75,50.91) ; v2(60.25,58.73) 60.25,59.82 59.94,60.13 59.94,60.68 R690.2 R691.2
+VCCSTG: length 111.2
  TOP w0.203: v3(88.34,64.55) 88.34,64.75 88.24,64.84 U11.A22
  TOP w0.254: R101.1 66.77,58.38 67.23,58.83 67.23,59.7 v2(66.72,60.21) R100.1 ; v3(89.61,69.02) 89.84,69.02 U11.G20 ; v2(67.86,60.21) R103.1 ; R98.2 v2(65.58,60.21) 65.58,60.1 64.57,59.1 64.11,59.1 63.83,59.38 61.86,59.38 v2(61.79,59.45) ; R83.2 v3(56.94,57.79)
  L3_IN1 w0.381: v2(65.58,60.21) 65.22,59.85 65.22,57.16 64.45,56.39 64.45,54.45 59.46,49.45 56.22,49.45 55.52,48.76 55.52,46.42 57.12,44.82 61.6,44.82 62.9,46.13 65.99,46.13 69.78,49.92 78.69,49.92 83.45,54.68 88.78,54.68 89.11,55.01 89.11,64.03 88.59,64.55 v3(88.34,64.55)
  L4_IN2 w0.254: v2(67.86,60.21) v2(66.72,60.21) v2(65.58,60.21) ; v3(56.94,57.79) 57.68,58.53 58.51,58.53 58.76,58.28 60.54,58.28 61.7,59.45 v2(61.79,59.45)
  BOTTOM w0.381: v3(89.61,69.02) 89.78,69.02 90.18,68.62 90.18,67.2 C458.2 89.76,66.79 89.76,65.47 88.84,64.55 v3(88.34,64.55) 88.34,64.84 87.4,65.77 87.4,69.17 86.98,69.59 85.69,69.59 85.43,69.85 85.43,71.09 84.74,71.78 84.01,71.78 83.61,72.17 83.61,74.3 84.02,74.71 84.02,76.56 83.61,76.97 83.61,78.57 R472.2
AGND_+1.35VS: length 35.3
  TOP w0.203: U13.34 96.6,137.87 U13.30 ; U13.34 96.35,138.24 95.7,138.9 U13.4 95.7,139.88 95.7,139.89 95.7,140.01 95.42,140.29 v3(95.4,140.29) ; U13.34 96.91,138.67 U13.32 98.14,138.67 98.77,139.3 99.87,139.3 100.4,139.84 C160.2
  TOP w0.381: C160.2 100.35,139.94 v3(100.35,140.55)
  TOP w0.457: C160.2 100.45,139.83 PJP10.1
  TOP w0.508: v3(92.86,139.91) 92.82,139.95 92.24,139.95 C149.2
  L3_IN1 w0.381: v3(86.84,140.06) 86.84,140.32 87.12,140.6 93.69,140.6 94.3,139.99 95.09,139.99 v3(95.4,140.29) 95.98,139.71 98.8,139.71 99.05,139.96 99.08,139.96 99.64,140.52 100.32,140.52 v3(100.35,140.55)
  BOTTOM w0.508: v3(95.4,140.29) 95.4,139.68 ; 95.4,139.68 R315.2 ; 95.4,139.68 95.19,139.89 C258.2 94.17,139.89 93.71,139.43 93.22,139.43 92.86,139.8 v3(92.86,139.91) ; C259.2 89.71,138.72 89.33,138.34 87.95,138.34 86.81,139.48 86.81,140.04 v3(86.84,140.06)
AGND_+2.5V: length 5.1
  TOP w0.305: U32.6 v3(57.54,135.83)
  TOP w0.508: v3(59.58,137.53) 59.38,137.53 R701.2
  BOTTOM w0.305: PJP11.2 58.82,136.77 58.63,136.58 57.74,136.58 57.54,136.37 v3(57.54,135.83)
  BOTTOM w0.508: PJP11.2 59.2,137.53 v3(59.58,137.53)
AGND_+3.3VAL: length 18.7
  TOP w0.508: 42.57,128.07 42.06,127.56 40.15,127.56 40.03,127.69 40.03,129.04 40.41,129.42 C74.2 ; v3(46,137.98) 46,139.24 PJP6.1 45.3,139.24 45.16,139.38 C87.2
  BOTTOM w0.508: v3(46,137.98) 43.58,137.98 42.06,136.45 v3(42.06,132.9) 41.73,132.57 41.73,131.06 42.25,130.54 R842.2
AGND_+5VAL: length 2.7
  TOP w0.381: PJP12.1 130.16,116.13 128.72,116.13
  BOTTOM w0.254: v3(126.13,116.64) 125.3,115.8 R843.2
GND POWER: length 1919.8
  TOP w0.076: v3(122.79,20.21) 122.8,20.2 124.32,20.2 U1634.C2 124.83,19.7 125.32,19.7 U1634.C4 ; v3(126.31,21.4) 126.32,21.39 126.32,20.71 126.57,20.46 U1634.B6 126.56,20.45 126.31,20.2 125.82,20.2 U1634.C4 ; 125.83,19.2 125.83,19.19 125.83,18.2 U1634.G4 ; 125.83,19.2 125.58,19.45 U1634.D4 ; 125.83,19.2 126.32,19.2 U1634.D6 126.55,19.45 126.31,19.7 125.93,19.7 125.68,19.95 125.58,19.95 U1634.C4 ; U1634.C4 U1634.D4 ; 123.83,18.7 124.3,18.7 124.55,18.95 U1634.E2 U1634.F3 125.33,18.71 125.33,19.2 U1634.D4
  TOP w0.102: U11.AG21 88.98,79.19 v3(89.3,79.51) ; 8.79,68.72 8.79,68.77 8.81,68.74 v3(8.81,67.85) ; U1634.F3 U1634.G4 ; 123.83,18.7 v3(123.53,18.41) ; v1(7.44,71.56) 7.52,71.64 v3(8.33,71.64) 8.33,70.83 8.79,70.37
  TOP w0.14: U11.BB67 62.61,88.08 62.61,88.1 62.13,88.59 v3(62.04,88.59) ; v3(92.5,81.08) 92.53,81.11 92.91,81.11 93.19,81.39 93.63,81.39 U11.AM13
  TOP w0.152: v3(67.05,88.48) 67.05,87.68 U11.BB60 ; U11.AF10 95.32,78.94 v3(95.32,79.08)
  TOP w0.178: U11.BB55 69.75,87.58 69.75,88.45 v3(69.79,88.49) ; U11.BB64 64.8,88.11 64.8,88.49 v3(64.8,88.49) ; U11.BB43 76.92,88.51 v3(76.89,88.53) ; U11.AM71 60.67,81.77 59.66,81.77 v3(59.6,81.83) ; U11.BB34 81.87,87.85 81.87,89.13 v3(81.83,89.17) ; v3(90.44,88.32) 90.44,87.74 U11.BB18 ; U11.AT71 59.78,84.1 v3(59.6,84.1) ; U11.BB26 86.85,87.98 86.85,88.49 86.88,88.51 v3(86.88,88.54) ; U11.AG71 59.78,79.09 59.62,78.93 v3(59.6,78.87) ; U11.H71 60.28,69.49 v3(59.78,68.99) ; U11.BB38 79.53,87.59 79.53,88.54 v3(79.56,88.56) ; U11.BB30 84.5,88.23 84.5,88.61 v3(84.66,88.77)
  TOP w0.203: v3(6.35,119.36) 6.55,119.16 S19.2 ; S16.2 7.34,121.14 7.24,121.24 v3(7.18,121.24) ; U11.AD20 89.52,77.31 89.09,77.31 U11.AD21 ; v3(9.34,113.55) 9.29,113.55 9.14,113.69 8.27,113.69 8.06,113.9 ; 90.14,85.6 89.84,85.6 89.81,85.63 U11.AW21 89.02,85.63 88.99,85.6 88.7,85.6 88.67,85.63 U11.AW23 87.7,85.63 87.67,85.6 87.37,85.6 87.34,85.63 U11.AW26 86.47,85.63 86.44,85.6 86.14,85.6 86.11,85.63 U11.AW28 85.24,85.63 85.21,85.6 84.92,85.6 84.89,85.63 U11.AW30 84.02,85.63 83.98,85.6 83.69,85.6 83.66,85.63 U11.AW32 82.83,85.63 v3(82.34,85.13) 81.97,85.5 U11.AW34 81.94,85.6 80.73,85.6 U11.AW36 80.67,85.6 79.45,85.6 U11.AW38 79.19,85.63 v3(78.68,85.12) 78.22,85.58 U11.AW41 78.19,85.6 77.05,85.6 U11.AW43 76.99,85.6 75.77,85.6 U11.AW45 75.71,85.6 74.56,85.6 U11.AW47 74.52,85.63 74.49,85.6 73.37,85.6 U11.AW49 73.3,85.6 72.17,85.6 U11.AW51 72.11,85.6 70.96,85.6 U11.AW53 70.91,85.61 69.67,85.61 U11.AW55 69.62,85.6 68.48,85.6 U11.AW57 68.42,85.6 67.28,85.6 U11.AW60 67.22,85.6 66,85.6 U11.AW62 65.94,85.6 64.73,85.6 U11.AW64 64.65,85.58 63.68,85.58 U11.AW66 63.42,85.49 63.33,85.58 63.32,85.58 v3(63.14,85.75) U11.AY66 U11.BA66 ; 90.14,85.6 90.11,85.57 U11.AU20 ; 90.14,85.6 90.17,85.63 U11.AW18 91.09,85.63 91.12,85.6 91.41,85.6 91.44,85.63 U11.AW16 91.89,85.63 v3(92.4,85.12) 92.91,85.63 U11.AW14 93.51,85.63 93.54,85.6 93.83,85.6 93.86,85.63 U11.AW12 94.64,85.63 v3(95.14,85.12) 95.44,85.42 U11.AW10 95.46,85.61 96.66,85.61 U11.AW8 97.08,85.63 97.11,85.6 97.4,85.6 97.43,85.63 U11.AW6 ; S3.2 7.44,135.13 v3(7.41,135.11) ; v3(101.42,68.49) 101.05,68.12 U11.F1 ; U11.AK22 88.8,80.6 U11.AK21 89.3,80.45 v3(89.3,80.35) ; CN7.35 140.44,125.62 140.57,125.49 S33.2 ; S10.2 6.8,127.16 6.58,127.39 v3(6.55,127.39) ; v3(148.53,61.07) 148.36,61.24 147.32,61.24 ; U11.D48 73.42,67.23 U11.D47 74.44,67.23 74.47,67.26 74.76,67.26 74.79,67.23 75.17,67.23 U11.D45 75.81,67.23 U11.D44 ; U11.AM68 62.65,81.26 62.74,81.17 62.74,80.9 62.33,80.49 U11.AK68 62.33,80.3 U11.AH67 ; U11.AM68 62.84,81.64 v3(63.14,81.94) ; U11.AM68 62.65,82.13 62.68,82.16 62.68,82.45 62.65,82.49 U11.AP68 62.65,83.36 62.68,83.39 62.68,83.68 62.65,83.71 U11.AT68 62.65,84.52 62.7,84.69 62.7,84.87 62.65,84.92 62.65,85.29 U11.AV68 ; CN7.38 141.94,125.62 141.84,125.52 S34.2 ; v3(6.12,116.97) 6.27,117.12 8.06,117.12 S21.2 ; 61.84,70.64 61.69,70.84 U11.K70 ; v3(6.78,131.53) 7.26,131.04 7.99,131.04 S6.2 ; S13.2 6.86,124.13 v3(6.35,124.64) ; v3(84.22,70.52) 84.17,70.47 U11.J28 ; v3(6.09,118.16) 6.12,118.14 S20.2 ; U11.AH63 65.68,79.54 65.68,78.84 U11.AF63 ; v3(7.36,133.1) 7.39,133.13 S4.2 ; S46.2 147.34,79.54 147.5,79.7 v3(148.08,79.7) ; v3(72.28,80.37) U11.AL52 ; S7.2 v3(6.17,130.13) ; v3(7.64,136.13) 7.65,136.12 7.66,136.13 S2.2 ; U11.K71 59.8,70.84 59.7,70.85 v2(59.7,71.26) ; v3(7.13,120.4) 7.39,120.15 S17.2 ; v3(74.11,80.37) U11.AL48 ; U11.F37 v3(80.51,69.04) U11.F35 ; v3(85.58,80.12) 85.54,80.16 U11.AK27 ; S15.2 7.53,122.15 v3(7.18,121.8) ; v3(78.68,70.45) U11.J38 ; v3(5.99,129.16) S8.2 ; U11.F38 v3(78.68,69.04) U11.F40 ; v3(7.13,123.66) 7.62,123.17 S14.2 ; v3(101.66,85.55) 101.53,85.42 U11.AV1 ; v3(82.34,70.45) U11.J32 ; U11.F33 v3(82.34,69.04) U11.F32 ; v3(101.64,66.05) 101.64,66.12 101.52,66.24 U11.C1 ; v3(76.86,70.45) U11.J42 ; v3(7.03,126.01) 7.16,126.14 S11.2 ; U11.G10 95.52,69.3 v3(95.2,68.97) ; S27.2 19.41,57.8 18.2,57.8 S26.2 18.17,57.8 S25.2 16.94,57.17 v3(16.91,57.14) ; S47.2 147.32,74.53 147.31,74.52 ; S5.2 v3(7.54,132.16) ; U11.AL64 64.83,81.43 64.78,81.48 64.4,81.48 64.36,81.43 U11.AL65 64.19,81.43 64.15,81.48 63.77,81.48 63.72,81.43 U11.AL66 ; v3(76.86,69.04) U11.F42 ; U109.29 29.36,46.51 29.71,46.86 v3(29.71,46.96) ; U11.K61 65.86,70.23 U11.K63 ; v3(75.94,80.37) U11.AL45 ; U11.AF1 100.79,78.62 v2(101.34,78.62) ; U11.BA2 U11.BA1 ; v3(70.45,80.37) U11.AL55 ; v3(68.63,80.37) U11.AL58 ; v3(86,70.75) U11.J25 ; v3(80.51,70.45) U11.J35 ; 5.73,131.15 v3(5.71,131.17) ; 90.67,75.24 U11.V18 v3(90.6,75.32) U11.Y19 90.67,75.24
  TOP w0.254: v3(62.83,69.04) U11.G66 ; v3(64.97,82.58) 65.15,82.43 65.17,82.43 65.31,82.28 U11.AN63 ; U11.BB6 U11.BA6 v3(97.86,86.14) 97.86,85.67 U11.AW6 ; U11.C25 86.15,66.87 v2(86.15,66.94) 86.1,66.94 ; U11.BA23 v3(88.16,86.14) U11.AW23 ; v3(95.99,72.65) 95.99,72.64 U11.N10 ; U11.N6 v3(98.43,72.79) ; U11.AT35 v3(80.51,83.85) U11.AR35 ; U11.AF63 U11.AE64 U11.AE65 U11.AE66 U11.AE67 U11.AE68 U11.AE69 61.35,77.5 v3(61.35,77.33) ; U11.AA65 v3(64.6,76.45) ; U11.F13 v3(93.31,68.41) 93.28,68.41 92.86,68.03 U11.E15 ; U11.N13 93.31,71.78 v3(93.31,71.77) ; v3(108.12,70.54) 108.2,70.62 108.2,71.71 107.77,72.14 R142.2 ; U11.V17 91.36,74.69 91.14,74.69 U11.V18 ; v3(91.25,78.68) U11.AG18 90.61,79.41 90.48,79.41 90.28,79.21 U11.AG19 90.14,79.23 89.77,79.23 U11.AG20 89.63,79.19 v3(89.3,79.51) 89.63,79.84 U11.AJ20 89.3,80.26 v3(89.3,80.35) ; v3(91.25,78.68) 91.58,79 U11.AG17 91.58,79.18 ; v3(91.25,78.68) U11.AF17 ; U11.F23 87.51,68.65 87.95,69.1 ; 86.1,66.94 U11.D26 ; 86.1,66.94 86.15,66.89 86.44,67.18 U11.D25 ; U11.BA14 v3(93.02,86.32) U11.AW14 ; U1637.B2 U1637.A2 42.11,109.09 v3(42.49,109.47) ; U11.E71 59.82,67.69 v3(59.7,67.56) ; v3(6.94,125.14) 7.06,125.14 7.08,125.12 S12.2 ; U11.K65 v3(63.93,70.94) U11.K66 ; v2(37.33,90.94) 37.73,91.34 U1636.F1 ; U11.AH6 98.28,79.73 97.96,80.04 v3(97.96,80.07) 98.11,80.22 98.64,80.22 U11.AJ4 ; U11.A65 64.14,64.86 64.05,64.78 v2(64.08,64.78) ; v3(92.4,85.12) U11.AU15 ; U11.BA18 v3(90.6,86.32) U11.AW18 ; 94.88,70.6 U11.J11 U11.J13 ; 94.88,70.6 v3(95.17,70.32) 95.17,70.4 94.96,70.6 94.88,70.6 ; U11.K16 92.23,70.56 v3(92.48,70.32) ; v3(92.5,81.08) 92.23,80.81 U11.AK16 ; U11.AU10 v3(95.14,85.12) ; v3(36.27,92.49) 35.81,92.04 35.81,91.67 U1636.H1 ; CN13.71 v3(16.24,32.43) ; U11.BA28 v3(85.68,86.14) U11.AW28 ; v3(73.12,67.72) 72.85,68 U11.E50 ; S39.2 141.48,45.05 141.56,44.96 v3(142.11,44.96) ; U11.BA57 v3(68.45,86.14) U11.AW57 ; v3(96.06,81.94) U11.AM8 ; U11.B58 v2(68.42,66.78) U11.D58 ; U11.T2 99.74,73.72 v2(99.44,73.72) 99.28,73.57 99.26,73.57 99.12,73.43 U11.T4 ; v3(96.91,67.67) 97.4,67.91 U11.E6 ; 91.33,77 91.26,77 U11.AB18 ; 91.33,77 91.81,77 U11.AD16 v3(91.92,77.84) ; 91.33,77 v2(91.28,77.05) ; U11.AP68 v3(62.04,82.92) U11.AP70 ; v3(69.54,69.04) U11.G55 ; v3(77.75,82.6) 77.73,82.6 U11.AN42 ; v3(79.6,80.37) U11.AL38 ; S37.2 143.07,14.74 v3(143.1,14.71) ; v3(59.59,65.74) U11.B71 U11.A70 ; C20.2 17.67,113.93 v3(17.5,114.1) 17.79,114.39 C235.2 ; v3(68.56,67.7) 68.59,67.73 68.61,67.73 68.64,67.75 69.08,67.97 U11.E56 ; v3(38.89,85.36) 38.53,85.01 U1636.E9 ; CN13.73 15.81,32.93 v3(15.82,32.93) ; U11.C5 98.55,66.58 v3(98.34,66.78) 98.13,67 U11.D6 ; 91.58,79.18 91.58,79.26 90.93,79.92 U11.AJ18 90.92,79.93 90.74,80.12 90.74,80.58 U11.AK18 90.89,80.77 90.67,81.1 90.67,81.14 v3(90.7,81.11) ; 91.58,79.18 v3(91.92,79.51) U11.AG16 U11.AF15 ; U11.AW10 95.44,86.04 v2(95.51,86.11) 95.44,86.17 U11.BA10 ; v3(75.03,83.18) 75.17,83.18 U11.AR45 ; C552.2 139.35,105.38 138.9,104.94 v3(138.9,104.71) ; v3(86,81.93) U11.AM25 ; CN14.39 v3(84.35,10.55) ; U11.AP18 91,82.86 v3(90.57,83.21) ; v3(62.65,76.45) U11.AA68 ; v3(93.95,74.91) 93.75,75.12 93.75,75.42 U11.W13 ; U11.AA2 99.79,76.08 ; 99.79,76.08 99.72,76.08 99.59,76.21 99.59,76.28 ; 99.79,76.08 99.59,76.28 ; v3(98.55,75.85) U11.W6 ; U11.G60 67.24,69.3 66.85,69.08 v3(66.85,69.1) ; S31.2 139.29,14.74 v3(139.26,14.71) ; U11.BA71 59.78,87.44 59.56,87.66 ; v3(74.11,83.85) U11.AR46 ; v3(83.26,82.58) U11.AN30 ; CN13.1 v3(15.95,14.93) ; U11.AF4 99.36,78.73 99.54,78.91 v2(99.69,78.91) 99.85,78.91 U11.AF2 ; U11.E11 94.48,67.79 v3(94.48,67.5) 94.48,67.43 94.69,67.23 U11.D11 U11.D10 U11.B10 ; U11.L16 v3(91.9,71.97) U11.L17 ; v3(63.85,67.77) U11.E65 ; v3(64.97,83.21) U11.AP63 ; v3(63.28,70.94) U11.K67 U11.K68 61.84,70.64 ; U1636.D2 39.33,90.59 v2(38.97,90.95) ; CN14.57 v3(88.85,10.67) ; U11.U69 v3(61.35,74.62) U11.U70 ; v2(86.57,93.71) 86.57,95.05 87.48,95.95 87.48,99.07 76.09,110.46 56.66,110.46 51.83,115.28 47.58,115.28 46.91,115.96 45.15,115.96 44.76,116.34 40.8,116.34 40.12,115.66 37.72,115.66 36.79,114.74 36.79,114.52 v3(36.68,114.41) ; v3(89.66,83.85) U11.AR20 ; v3(98.55,73.71) U11.R6 ; U11.AT23 v3(86.91,83.85) U11.AR23 ; U11.L18 v3(90.61,71.97) U11.N19 v3(89.95,72.78) U11.P20 ; v3(66.8,81.93) U11.AM60 ; CN13.33 v3(15.82,22.93) ; U1637.E3 38.53,108.35 v2(38.1,108.78) ; v3(71.37,69.04) U11.G52 ; U11.BA45 v3(75.74,86.14) ; 99.59,76.28 v2(99.56,76.3) 99.34,76.08 U11.AA4 ; U1637.M9 33.05,103.49 33.41,103.13 v3(33.41,102.4) ; v3(86.91,82.58) U11.AN23 ; U11.AL4 99.17,81.38 99.4,81.15 v2(99.56,81.15) 99.62,81.15 99.86,81.38 U11.AL2 ; 89.63,71.61 89.18,72.05 89.18,72.18 U11.N21 88.47,72.39 v3(88.39,72.47) ; 89.63,71.61 U11.L20 ; 89.63,71.61 89.63,71.68 v2(89.91,71.97) ; U11.D69 v3(61.6,67.62) U11.D69 ; U11.D69 U11.F68 ; U11.B53 70.9,66.34 70.59,66.65 70.59,66.73 70.58,66.74 70.58,66.93 v2(70.6,66.96) 70.6,66.97 U11.D53 ; U11.AD20 89.72,77.42 89.76,77.46 90.14,77.46 90.18,77.42 U11.AD19 ; v3(96.06,83.85) U11.AR8 ; U11.BA41 78.22,86.37 v3(78.33,86.27) 78.22,86.16 U11.AW41 ; v3(64.05,81.94) 64.28,81.72 U11.AL65 ; S35.2 141.85,14.77 v3(141.8,14.71) ; U11.AM43 v3(75.94,81.93) 75.84,81.93 75.48,81.57 U11.AM45 ; CN14.63 90.35,10.31 v3(90.64,10.59) ; U11.AT2 U11.AT4 99.05,84.03 v2(98.77,84.31) ; v3(91.43,67.72) 91.16,68 U11.E18 90.72,67.69 U11.D18 U11.B18 ; U11.AR43 76.67,83.21 v3(76.86,83.21) U11.AP42 ; v3(75.03,69.04) U11.G45 ; v3(44.35,124.64) 44.9,124.08 R278.1 ; v3(67.71,83.21) U11.AP58 ; v3(18.54,102.98) 17.47,102.98 ; 17.47,102.98 17.42,103.03 R603.2 ; 17.47,102.98 16.61,102.98 16.28,103.31 R604.2 ; v3(59.56,87.69) 59.56,87.66 ; 59.56,87.66 59.56,87.64 59.82,87.9 U11.BB70 ; U11.AT28 v3(84.17,83.85) U11.AR28 ; v3(68.63,84.48) U11.AT56 ; U11.B66 v2(63.46,66.76) U11.D66 ; 87.95,69.1 88.16,69.3 U11.G22 ; 87.95,69.1 v3(87.95,68.99) 88.29,68.66 U11.F22 ; v3(33.61,52.76) 33.68,52.76 33.86,52.94 U110.6 ; U11.B44 v2(75.85,66.81) U11.D44 ; v3(35.16,91.82) 34.68,91.35 U1636.K1 ; v3(74.11,67.77) U11.E46 ; U11.E53 70.89,67.94 70.46,67.73 70.46,67.71 70.42,67.7 v2(70.4,67.7) ; v3(21.94,116.72) 21.3,116.08 C143.2 ; U11.AR11 v3(94.23,83.85) ; v3(59.6,85.62) 59.73,85.49 U11.AV71 U11.AV70 U11.AV69 v3(62.18,85.49) U11.AV68 62.66,85.33 63.1,85.75 v3(63.14,85.75) ; U11.AW62 v3(65.97,86.14) U11.BA62 ; v2(90.53,68.97) 90.53,69.52 90.97,69.95 U11.H18 90.93,70.05 U11.K18 ; CN14.51 v3(87.35,10.5) ; CN13.39 v3(15.82,24.43) ; U11.BA1 101.43,87.87 v3(101.43,87.89) ; D13.3 v3(144.27,118.25) ; U11.AB8 96.97,76.21 96.8,76.04 96.8,76.02 96.77,75.99 96.77,75.8 96.49,75.39 U11.W9 96.32,75.11 96.02,74.81 v3(95.98,74.81) 95.97,74.8 95.97,74.74 U11.U10 ; v2(38.18,90.07) 38.22,90.07 38.53,89.76 U1636.E3 ; v3(18.04,116.77) 18.04,116.07 17.75,115.79 Q17.3 ; U11.AW53 v3(70.93,86.14) U11.BA53 ; v3(73.2,83.85) U11.AR48 ; U11.AR42 v3(76.86,83.85) U11.AT42 ; U11.E21 89.19,67.96 v3(88.68,67.72) 88.24,67.28 U11.D22 U11.B22 ; CN13.51 v3(15.82,27.43) ; 65.37,79.65 65.63,79.9 65.63,80.51 U11.AK63 65.58,80.65 66.27,81.54 U11.AM61 v3(65.88,81.93) ; 65.37,79.65 U11.AH63 ; 65.37,79.65 U11.AH64 ; v3(97.26,81.03) U11.AK8 ; v3(97.89,83.85) U11.AR5 ; U11.AB16 v3(92.57,76.16) U11.AB15 92.88,76.68 U11.AD13 ; U1637.H1 36.13,110.22 35.6,110.75 35.6,110.77 ; v3(96.06,68.41) U11.F8 ; v3(66.34,77.1) 66.34,77.06 66.05,77.35 U11.AD62 ; U11.F2 99.72,68.12 v2(99.54,68.3) 99.36,68.12 U11.F4 ; v3(34.84,110.29) 34.53,109.98 U1637.K1 ; v3(81.43,80.37) U11.AL35 ; U11.K63 v3(65.23,70.94) U11.K64 ; D11.3 v3(144.17,77.29) ; CN14.75 v3(93.35,10.62) ; U11.AM21 89.2,81.6 88.81,81.94 v3(88.74,81.94) ; C168.2 14.68,115.09 v3(14.68,114.48) ; v3(82.34,83.21) U11.AP32 ; v3(84.17,82.58) U11.AN28 ; v2(92.4,83.85) U11.AR15 ; U1636.N1 32.13,91.51 v3(30.54,93.11) ; v3(140.53,14.66) 140.48,14.71 S32.2 ; U11.AJ15 93.45,79.93 U11.AH13 v3(94.09,80.11) ; U11.B48 v2(73.38,66.73) U11.D48 ; v3(89.66,82.58) 89.7,82.58 90.11,82.22 U11.AN20 ; v3(62.66,64.72) 62.66,64.81 62.79,64.94 U11.A67 ; U11.A5 98.71,65.25 98.71,64.97 v3(98.82,64.86) ; C14.2 15.28,131.93 v3(15.69,132.34) ; U11.U66 v3(63.3,74.62) U11.U67 ; U11.F27 85.52,68.67 84.65,68.67 U11.F28 84.55,68.65 v3(84.15,69.05) ; U11.AT20 v3(89.66,84.48) U11.AU20 ; U11.U63 v3(65.25,74.62) U11.U64 ; U11.AU38 v3(78.68,85.12) ; U11.T17 91.43,74.21 91.08,74.21 U11.T18 v3(90.62,73.65) U11.P19 ; v3(86.91,83.21) U11.AP23 ; U1636.G8 36.98,85.75 v3(37.35,85.38) ; v3(81.43,82.58) U11.AN33 ; CN14.18 v3(79.1,3.02) ; v3(63.14,81.94) 63.63,81.46 U11.AL66 ; v2(91.49,83.85) U11.AR16 ; U11.T15 92.9,74.07 v3(93.29,73.67) 93.71,73.26 U11.R13 ; U1636.A8 41.74,85.73 42.16,85.73 v3(42.23,85.81) ; v3(67.71,69.04) U11.G58 ; U11.P21 U11.T21 89.3,74.39 v3(89.3,74.48) ; v3(89.66,83.21) U11.AP20 ; U11.L4 99.36,70.77 v2(99.54,70.95) 99.72,70.77 U11.L2 ; v3(42.53,91.02) 42.05,90.55 U1636.A2 U1636.B2 ; U11.AN38 v3(79.6,82.58) U11.AN37 ; U11.Y20 U11.Y21 88.65,76.07 v3(88.65,76.16) 88.98,76.49 U11.AB21 88.98,76.68 v2(88.44,77.22) 88.78,77.22 U11.AD21 88.65,77.75 v3(88.65,77.84) ; U110.17 35.93,52.54 U110.11 ; v3(78.68,83.21) U11.AP38 ; CN14.33 v3(82.85,10.55) ; v3(95.36,81.03) U11.AK11 ; U11.AT63 v3(64.97,83.85) U11.AR63 ; v3(85.09,80.37) U11.AL28 ; S18.2 v3(7.36,134.14) ; U11.BA36 v3(80.7,86.14) U11.AW36 ; v3(69.54,81.93) U11.AM55 ; v3(92.57,74.48) U11.V16 U11.Y17 ; v3(67.71,82.58) U11.AN58 ; v3(65.88,67.77) 65.94,67.71 U11.D62 v2(65.94,66.76) U11.B62 ; U11.AU32 v3(82.34,85.13) ; v3(42.27,104.35) 42.2,104.28 41.74,104.28 U1637.A8 ; v3(73.2,69.04) U11.G48 ; v2(72.81,90.3) 72.78,90.27 72.78,89.45 73.3,88.93 73.3,86.96 U11.BA49 ; U11.AK68 62.15,80.24 61.84,80.24 61.66,80.42 U11.AK69 ; U11.J8 96.52,70.9 96.85,71.23 96.92,71.23 96.95,71.25 U11.L8 97.07,71.27 v3(97.26,71.58) ; v3(83.26,80.37) U11.AL32 ; v3(71.37,83.85) U11.AR52 v3(72.28,83.85) U11.AR50 ; U1637.D2 39.33,109.13 v2(38.96,109.51) ; U11.AT58 v3(67.71,83.85) U11.AR58 ; S9.2 5.89,128.17 v3(5.86,128.2) ; v2(92.55,73.72) 92.53,73.7 92.02,73.7 91.68,73.35 91.68,73.32 U11.P17 ; CN13.21 v3(15.82,19.93) ; v3(85.09,81.93) U11.AM27 ; U1637.F1 37.73,109.88 37.34,109.49 v2(37.27,109.49) ; U1637.E9 38.53,103.49 v3(38.93,103.89) ; U11.D39 78.35,67.27 78.56,67.06 v2(78.56,66.73) 78.56,66.47 U11.B39 ; 5.97,129.14 v3(5.99,129.16) ; v3(84.17,83.21) U11.AP28 ; CN13.3 v3(16.39,15.43) ; v3(96.91,68.32) 96.91,68.78 U11.G6 ; SBCN2.6 v3(112.66,7.57) ; v3(64.6,72.79) U11.N65 ; U11.AD8 v3(97.26,77.98) ; CN14.69 v3(91.85,10.51) ; U11.D14 v2(93.2,66.68) U11.B14 ; CN13.75 v3(16.2,33.43) ; v3(82.34,82.58) U11.AN32 ; v3(69.54,83.85) U11.AR55 ; v3(87.8,71.26) 88.29,70.77 U11.K22 ; CN13.27 v3(15.82,21.43) ; CN13.57 v3(15.66,28.93) ; v3(97.89,69.04) U11.G5 ; U11.D34 v2(80.81,66.86) U11.B34 ; CN13.45 v3(15.82,25.93) ; U11.BA32 v3(83.17,86.14) U11.AW32 ; v3(95.36,71.71) U11.L11 ; v3(63.32,80.11) U11.AH67 ; v3(75.94,69.04) U11.G43 ; v3(62.65,72.79) U11.N68 ; U11.AR53 70.7,83.46 v3(70.45,83.66) ; U11.D30 v2(83.29,66.81) U11.B30 ; CN14.45 v3(85.85,10.48) ; v3(64.87,69.04) U11.G63 ; v3(78.7,82.54) 78.58,82.54 U11.AN40 ; v3(74.11,81.93) U11.AM46 ; SBCN2.9 v3(114.16,7.46) ; v3(95.14,83.21) U11.AP10 ; v3(80.51,82.58) U11.AN35 ; CN13.5 v3(15.9,15.93) ; v3(80.51,83.21) U11.AP35 ; CN13.11 v3(15.92,17.43) ; SBCN2.12 v3(115.66,5.89) ; D9.3 v3(145.65,116.11) ; D10.3 v3(144.3,113.35)
  TOP w0.305: CN11.168 93.22,128.27 93.09,128.4 ; 50.46,117.46 51.24,117.46 51.47,117.69 CN11.9 ; 50.46,117.46 50.47,117.47 CN11.5 ; 50.46,117.46 v3(49.37,117.46) ; v3(53.64,128.4) 53.72,128.32 CN11.18 ; CN7.6 125.94,127.81 v3(125.88,127.87) ; 60.53,128.4 60.22,128.1 CN11.44 ; v3(98.44,128.38) 98.22,128.16 CN11.188 ; v3(71.41,121.38) 71.61,121.38 72.47,120.51 72.47,118.83 CN11.93 ; CN11.73 67.47,119.97 67.99,120.49 67.99,120.55 v3(68.31,120.87) ; CN11.64 65.22,128.38 65.19,128.4 ; U1637.G8 36.95,104.29 v3(37.32,103.91) ; CN11.171 93.97,117.77 93.76,117.56 93.08,117.56 92.97,117.66 CN11.167 92.97,119.82 92.56,120.23 v3(91.93,120.23) ; 101.71,128.4 101.72,128.39 CN11.202 ; v3(102.38,128.4) 102.72,128.06 CN11.206 ; 96.18,128.4 96.22,128.36 CN11.180 ; CN11.184 97.22,128.3 97.33,128.4 ; CN11.217 105.47,117.25 v3(105.3,117.08) ; 101.47,120.11 CN11.201 ; 101.47,120.11 100.79,120.11 100.47,119.79 CN11.197 ; 101.47,120.11 101.53,120.16 v3(101.53,121.06) ; v3(52.8,122.74) 52.8,123.14 53.13,123.47 53.13,124.68 52.72,125.08 CN11.14 52.72,128.23 v3(52.55,128.4) ; 106.79,128.4 106.72,128.34 CN11.222 ; v3(59.04,120.45) 58.37,120.45 57.97,120.06 CN11.35 ; 60.97,117.66 60.87,117.56 60.19,117.56 59.97,117.77 ; 60.97,117.66 CN11.47 ; 60.97,117.66 61.19,117.44 61.77,117.44 61.97,117.65 CN11.51 v3(61.97,120.13) ; CN11.218 105.72,125.73 v3(104.55,124.56) ; v3(114.28,128.4) 114.22,128.35 CN11.252 ; 59.97,117.77 59.77,117.57 59.23,117.57 58.97,117.82 CN11.39 ; 59.97,117.77 CN11.43 ; v3(107.41,128.4) 107.72,128.09 CN11.226 ; CN11.22 54.72,128.18 v3(54.5,128.4) ; CN11.251 113.97,117.71 113.76,117.49 113.02,117.49 v3(113,117.51) 112.97,117.53 CN11.247 ; U1637.N1 32.13,110.03 v3(32.49,110.4) ; U1636.K9 34.53,84.93 v3(34.92,84.54) 34.94,84.52 35.7,84.52 U1636.H9 ; CN7.10 127.94,127.78 v3(128.14,127.97) ; CN11.234 109.72,128.18 v3(109.95,128.4) ; CN11.176 95.22,128.34 95.29,128.4 ; CN11.81 69.47,117.89 69.17,117.59 68.42,117.59 v3(68.4,117.61) ; v3(59.58,128.4) 59.22,128.05 CN11.40 ; CN11.94 72.72,128.1 72.42,128.4 ; CN7.26 v3(135.94,127.59) ; D12.3 144.75,59.19 v3(144.65,59.09) ; v3(55.77,128.4) 55.72,128.36 CN11.26 ; CN11.196 100.22,128.07 v3(99.89,128.4) ; CN11.86 70.72,128.12 v3(71.01,128.4) ; 51.63,128.4 51.72,128.3 CN11.10 ; v3(94.85,120.23) 94.97,120.11 CN11.175 ; CN11.107 75.97,117.74 75.74,117.5 75.34,117.5 74.97,117.87 CN11.103 74.97,119.87 74.67,120.17 v3(74.47,120.17) 74.21,120.17 73.97,119.93 CN11.99 ; CN11.106 75.72,125.94 75.35,125.57 v3(75.3,125.57) ; U1637.E8 v3(38.93,103.89) U1637.D8 ; v3(109.17,124.54) 109.21,124.54 110.72,126.05 CN11.238 110.72,128.34 110.66,128.4 ; v2(38.96,109.51) 38.96,109.46 U1637.E1 ; v3(69.79,125.76) 69.72,125.83 CN11.82 ; CN7.32 v3(138.94,127.55) ; v3(62.12,128.4) 62.22,128.3 CN11.52 ; v3(112.9,125.2) 112.9,125.59 113.22,125.92 CN11.248 ; CN11.30 56.72,128.09 v3(57.04,128.4) ; v3(92.48,70.32) 92.84,69.95 U11.H15 ; CN11.85 70.47,116.98 v3(70.59,116.86) 70.62,116.89 71.05,116.89 71.47,117.31 CN11.89 ; CN11.90 v3(71.72,125.77) ; CN11.243 111.97,119.87 111.76,120.09 111.09,120.09 v3(111.04,120.04) 110.97,119.98 CN11.239 ; CN11.213 104.47,117.59 104.99,117.08 v3(105.3,117.08) ; CN11.193 99.47,120.12 98.66,120.93 v3(98.21,120.93) ; CN11.15 52.97,120.04 53.51,120.58 53.51,121.19 53.86,121.53 v3(53.99,121.53) 54.31,121.53 54.59,121.25 54.59,120.48 53.97,119.87 CN11.19 ; v3(29.33,110.29) U1637.T1 ; v3(67.2,128.4) 67.22,128.38 CN11.72 ; 94.21,128.4 94.22,128.39 CN11.172 ; 55.97,117.52 56.83,117.52 56.97,117.67 CN11.31 56.97,119.86 v3(56.56,120.28) ; 55.97,117.52 55.14,117.52 54.97,117.69 CN11.23 ; 55.97,117.52 CN11.27 ; CN11.185 97.47,117.81 v3(97.26,117.6) ; CN11.6 50.72,128.34 50.78,128.4 ; CN11.56 63.22,128.24 v3(63.39,128.4) ; v3(108.68,128.4) 108.72,128.36 CN11.230 ; CN11.78 68.72,128.15 v3(68.47,128.4) ; 99.17,128.4 99.22,128.35 CN11.192 ; v3(61.31,124.48) 61.22,124.57 CN11.48 ; v3(64.18,120.99) 63.47,120.29 CN11.57 ; v3(137.31,127.64) 137.44,127.51 CN7.29 ; CN11.231 108.97,117.53 ; 108.97,117.53 109.93,117.53 109.97,117.58 CN11.235 ; 108.97,117.53 108.74,117.29 v3(107.97,117.29) CN11.227 ; CN11.36 58.22,128.32 v3(58.31,128.4) ; v3(40.12,84.44) 40.12,84.94 U1636.C9 ; 29,91.41 29.06,91.35 U1636.T1 ; CN11.189 98.47,117.7 98.37,117.6 v3(97.26,117.6) ; v3(65.93,128.4) 66.22,128.11 CN11.68 ; v3(50.33,120.73) 49.47,119.88 CN11.1 ; v3(33.36,83.93) 33.36,84.52 U1636.M9 ; CN11.65 65.47,117.68 65.17,117.38 v3(64.23,117.38) 64.47,117.62 CN11.61 ; CN11.209 103.47,117.62 103.26,117.4 102.76,117.4 v3(102.72,117.44) 102.47,117.69 CN11.205 ; U1634.G4 v3(125.57,17.31) ; v3(68.4,117.61) 68.47,117.68 CN11.77 ; v3(68.4,117.61) 66.72,117.61 66.47,117.85 CN11.69 ; CN11.2 49.72,128.36 49.76,128.4 ; v3(129.44,125.21) CN7.13 ; U1636.D8 39.27,85.75 v3(38.89,85.36) 38.53,85.72 U1636.E8 ; CN7.35 v3(140.44,127.67) ; v3(97.26,117.6) 97.21,117.54 96.78,117.54 96.47,117.85 CN11.181 ; CN11.60 64.22,128.1 64.53,128.4 ; CN7.38 v3(141.94,127.63) ; SBCN1.4 100.29,7.92 100.61,8.24 v3(100.61,8.24) 100.79,8.06 SBCN1.5 ; U1636.E1 38.53,91.34 38.97,90.91 v2(38.97,90.95) ; CN11.102 74.72,126.02 74.49,125.78 v3(73.72,125.78) CN11.98 ; 112.25,128.4 112.22,128.38 CN11.244 ; v3(105.3,117.08) 106.68,117.08 106.97,117.37 CN11.223 ; CN14.7 v3(76.35,10.59) ; CN11.210 103.72,126.07 102.85,125.2 v3(102.85,124.56) ; v3(40.13,102.83) U1637.C9 ; CN14.1 v3(74.85,10.56) ; CN11.214 104.72,125.92 103.74,124.94 v3(103.74,124.56) ; U1637.H9 35.7,103.06 34.94,103.06 v3(34.92,103.08) 34.53,103.47 U1637.K9
  TOP w0.356: C18.2 19.07,62.86 v3(18.51,63.43) 17.93,62.85 C16.2 ; v3(13.91,132.32) 13.71,132.11 C13.2 ; v3(18.05,132.34) 18.05,131.34 18.49,130.89 R24.2
  TOP w0.381: v3(32.64,130.35) 32.58,130.29 32.58,129.7 C53.1 ; U15.2 v3(118.61,95.64) ; v3(133.44,77.4) 133.3,77.55 Q59.4 ; v3(134.39,70.38) 134.39,69.65 R245.2 ; C257.2 147.06,104.63 v3(146.91,104.78) ; R31.2 20.21,99.78 20.21,101.06 v3(20.18,101.09) ; v3(9.34,112.79) 9.34,112.58 9.09,112.33 9.09,111.9 9.47,111.52 10.63,111.52 C4.2 ; R34.2 v3(19.86,118.75) ; v3(12.09,108.06) 12.09,107.91 C5.2 11.09,107.17 10.38,106.45 CN3.S2 ; CN3.1 6.25,108.21 v3(6.34,108.11) ; v3(19.95,96.53) 20.16,96.32 R30.2 ; 35.6,110.77 35.48,110.9 v3(34.85,110.9) ; v3(131.26,62.24) 131.26,61.29 129.87,59.9 R229.2 ; Q13.E 119.19,54.78 119.83,54.14 C184.1 120.52,54.56 120.21,54.86 v3(120.21,55.13) ; C175.1 104.87,68.33 v3(104.87,67.52) ; v3(130.94,67.88) C212.2 C206.2 ; v3(28.57,122.66) 28.47,122.66 28.06,122.26 C46.1 C43.1 ; R75.2 39.21,83.47 v3(38.85,83.83) ; v3(130.88,74.18) 130.88,74.69 131.5,75.31 Q59.1 ; C28.2 v3(19.63,126.12) ; R135.2 105.25,87.3 105.86,87.91 v2(105.89,87.91) ; CN3.S1 v3(1.2,108.45) ; C107.1 v2(64,57.74) ; C159.1 C157.1 98.51,56.07 98.12,55.67 v3(98.12,54.75) ; v3(20.65,132.34) 20.87,132.12 C29.2 ; v3(141.2,103.69) 141.57,103.31 R235.2 ; v3(23.87,116.62) 23.87,116.67 24.23,117.03 C39.2 ; v3(134.44,127.64) CN7.23 ; C30.1 19.62,122.05 v3(19.52,122.16) ; v3(128.44,62.24) 128.44,62.81 U19.5 ; v4(144.4,127.39) 144.59,127.58 CN7.S2 ; C37.1 24.1,122.25 23.24,123.11 C36.1 22.75,123.2 22.55,122.99 v3(22.55,122.89) ; v3(116.66,58.43) 116.66,57.83 116.51,57.68 Q10.3 ; v3(113.58,73.29) 113.33,73.03 R176.1 ; v3(129.96,63.87) 129.96,64.13 130.21,64.39 U19.12 ; v3(9.31,96.49) 9.6,96.77 9.6,97.09 C3.2 9.44,97.24 R6.2 ; v3(30.63,52.25) 30.76,52.37 31.77,52.37 31.77,52.37 32.65,52.37 C3703.2 ; PJP2.2 18.59,102.93 v3(18.54,102.98) ; 33.04,128.15 v3(33.04,128) ; C172.1 v3(104.31,67.57) ; v3(22.42,133.74) 22.14,133.46 C33.2 ; C185.2 120.16,116.44 v3(120.16,116.83) ; v3(13.2,126.12) R11.2 C6.2 ; v3(125.8,123.52) 125.6,123.73 C474.1 ; R51.2 36.67,128.56 C62.1 C63.1 37.28,127.13 v3(37.36,127.05) ; C173.2 105.04,140.29 v3(105.63,140.29) ; v3(46,140.64) PJP6.2
  TOP w0.406: PJP12.2 v3(130.68,115.27)
  TOP w0.457: PJP10.2 102.53,140.68 v3(102.56,140.71)
  TOP w0.508: v3(106.26,9.26) 106.5,9.5 C534.2 ; v3(36,83.14) 35.98,83.12 C66.1 ; C182.1 C181.2 v3(123.46,136.41) ; v3(32.53,46.85) 32.51,46.83 31.83,46.83 C3783.2 C3773.2 ; v3(13.23,68.89) 12.82,69.3 C433.2 C434.2 ; C573.2 83.1,45.6 v3(82.59,45.09) 83.31,44.38 R668.2 ; C196.2 123.62,91.34 v3(123.08,91.87) ; C3935.1 110.91,130.95 v3(111.27,131.31) ; C503.2 v3(130.7,17.54) ; 29,91.41 28.43,91.41 v3(27.79,90.77) 27.16,90.77 27.11,90.72 C49.1 ; C491.1 130.47,18.68 v3(130.77,18.97) ; v3(101.42,60.21) 100.83,60.79 C165.1 ; ED4.2 137.54,18.22 v3(137.84,17.91) ; v3(42.82,140.64) 42.82,139.62 C554.1 ; C613.2 46.76,128.61 v3(46.68,128.53) ; C538.2 v3(102.53,10.07) ; v3(37.62,112.88) 37.68,112.93 C56.1 ; v3(136.07,121.2) 136.89,120.38 CN5.S2 ; C57.1 33.32,93.09 33.32,92.1 v3(33.46,91.96) ; v3(58.82,56.57) 58.54,56.85 C102.1 ; v2(79.19,63.64) 78.18,62.62 78.18,61.02 C125.2 78.48,60.43 v3(78.18,60.13) 78.18,56.78 78.56,56.4 82.11,56.4 83.22,57.5 ; SBCN2.S1 v3(108.06,2.19) ; v3(129.31,118.29) 130.1,119.09 CN5.S1 131.81,119.09 v3(132.08,118.81) ; v3(127.4,12.88) 127.23,12.71 C637.2 ; v3(123.26,137.68) 122.87,137.28 Q52.S ; R531.2 107.01,78.11 107.31,78.42 v3(107.31,78.75) 107.93,78.13 R529.2 ; R141.2 v3(105.99,73.16) ; R495.2 17.22,71.91 v3(17.22,70.92) ; v3(98.34,52.46) v3(99.36,52.46) v3(100.37,52.46) ; 83.22,57.5 83.34,57.5 84.01,58.16 84.01,60.01 v3(83.92,60.1) C133.2 84.53,61.33 84.53,62.87 83.89,63.51 81.35,63.51 v2(81.23,63.64) ; 83.22,57.5 82.07,57.5 ; 120.1,28.24 120.11,28.23 Y6.2 ; 120.1,28.24 120.1,28.75 120.74,29.39 124.61,29.39 124.93,29.07 v3(124.93,27.1) ; 120.1,28.24 v3(120.1,27.23) 120.1,25.51 121.22,24.39 v3(122.12,24.39) C1205.1 ; v3(60.04,57.71) 60.15,57.6 Q6.E ; v3(49.81,139.5) 49.81,139.24 50.48,138.57 C650.2 v3(50.63,139.5) ; C469.2 14.3,64.35 13.56,64.35 v3(13.48,64.27) ; v3(83,60.1) 83,58.43 82.07,57.5 ; v3(26.69,32.12) 26.33,31.76 C3502.2 ; v3(119.2,16.77) 119.71,17.28 C490.2 ; C3496.2 v3(24.42,20.06) ; v3(91.61,95.49) 91.69,95.56 C520.1 ; v3(38.95,101.84) 38.17,101.07 R76.2 ; v3(112.1,131.24) 112.12,131.22 C3938.1 ; C3691.2 42.69,50.39 42.69,50.15 43.14,49.71 v3(43.46,49.71) ; C580.2 v3(26.06,109.27) ; C67.1 35.7,100.96 35.7,103.06 ; v3(88.59,52.59) 88.59,52.38 R112.2 ; v3(119.71,58.43) 119.58,58.3 R119.2 ; C3930.1 25.82,104.12 v3(26.15,104.44) ; v3(143.81,109.89) 142.41,109.89 C341.2 ; Q20.S 31.14,77.46 v3(31.71,76.89) ; v4(83.37,51.69) 83.38,51.7 v4(84.31,51.7) 84.4,51.6 84.4,49.97 C621.2 ; BAT1.S1 8.14,54.61 v3(8.59,54.15) ; v3(106.16,14) 105.66,13.5 C536.2 ; C539.2 v3(102.53,11.09) ; C154.1 95.6,50.35 v3(94.94,50.35) ; v3(26.69,32.69) 26.48,32.9 C3503.2 ; Q4.S 54.87,57.95 R80.1 55.39,57.14 v3(55.71,57.45) ; 8.96,69.48 9.09,69.48 9.65,68.92 9.65,68.72 ; 8.96,69.48 9.65,70.16 9.65,70.37 ; 8.96,69.48 v3(8.84,69.48) ; R669.2 92.83,50.89 92.91,50.81 v3(92.91,50.3) 92.91,49.74 C529.2 ; v3(41.42,82.19) 41.54,82.08 C3405.1 ; C42.1 24.87,100.55 v3(24.05,101.37) ; SBCN1.S2 v3(104.82,4.41) ; EC2.1 45.36,119.45 46.44,120.53 v3(47.09,120.53) ; C333.2 v3(120.04,15.2) ; v3(29.23,113.53) 29.2,113.5 C47.1 ; v3(91.39,50.3) 90.75,49.67 C519.2 ; ED5.2 140.08,18.73 139.52,19.28 v3(139.52,19.31) ; v3(34.44,112.83) 34.45,112.84 34.45,113.47 C71.1 ; C84.1 42.33,94.44 v3(42.33,93.25) ; v3(30.18,83.05) 30.18,82.39 30.1,82.31 C3936.1 ; v3(40.54,140.52) 40.35,140.33 C73.2 ; Y1.2 82.07,57.5 ; v3(10.37,132.61) 10.91,132.07 C11.2 ; R510.2 10.99,65.41 v3(10.79,65.62) ; v3(36.94,112.3) 36.92,112.31 C64.1 ; CN33.S2 v3(127.97,4.62) ; v3(107.03,85.91) 106.98,85.96 R150.1 ; C635.2 129.37,14.2 v3(129.37,14.47) ; ED6.2 143.86,17.61 v3(144.19,17.28) ; v3(120.46,136.69) 120.84,136.32 C178.2 ; C54.1 33.41,100.97 v3(33.41,102.4) ; v3(23.11,63.24) 23.11,63.1 22.61,62.59 C26.2 C22.2 ; v3(16.89,91.17) 17.49,90.56 C19.2 ; v3(29.49,58.34) 29.49,57.14 29.49,57.13 BAT1.S2 ; v3(106.75,53.73) 105.89,52.87 R145.2 ; CN4.S1 v3(3.98,45.54) ; v3(27.45,33.45) 27.45,33.49 C3497.2 ; C161.1 101.42,136.28 v3(101.5,136.2) ; C480.2 v3(131.9,21.09) ; v3(24.43,90.33) 25.09,90.33 C3937.1 ; C186.2 v3(120.29,111.43) ; v3(124.93,27.1) 124.93,25.77 123.55,24.39 v3(123.39,24.39) C1206.1 ; v3(124.93,27.1) 124.42,27.1 Y6.4 ; v3(39.59,92.87) 39.3,93.16 C3406.1 ; C241.1 v3(36.9,125.05) ; v3(40.28,101.84) 40.28,101.46 40.61,101.13 C72.1 C83.1 ; C571.2 82.57,41.09 v3(82.02,40.54) ; v3(13.04,62.98) 13.84,62.18 R15.2 ; SBCN2.S2 v3(118.76,4.9) ; C526.2 v3(100.28,11.19) ; CN5.1 132.09,121.99 v3(131.98,122.1) ; KBT1.S1 3.83,138.04 v3(3.56,137.78) ; C3940.1 114.53,130.97 v3(113.94,131.56) ; v3(27.87,83.02) 27.87,82.93 C50.1 ; v3(34.58,83.04) 34.58,82.43 C58.1 ; C462.2 19.38,67.74 v3(19.19,67.93) ; C535.2 106.42,12.46 106.96,12.99 v3(106.96,13) ; C636.1 v3(122.75,12.71) ; C7.2 10.34,117.73 v3(10.06,117.73) ; 7.23,76.08 7.44,75.3 v4(7.44,74.3) ; v3(114.03,110.58) 114.37,110.93 CN11.262 ; C525.2 v3(8.71,37.06) ; C3407.1 41.87,112.95 42,112.82 v3(42.21,112.82) ; CN4.3 v3(5.45,42.75) ; C198.2 v3(127.28,87.05) ; U3.4 18.62,121.72 19.06,122.16 v3(19.52,122.16) ; v3(133.85,109.37) 134.29,109.81 R96.2 ; C151.2 94.96,130.67 v3(95.6,130.67) ; v3(128.92,68.64) 128.65,68.36 C201.2 ; v3(46.97,112.54) 48.58,110.93 CN11.261 ; C3682.1 32.94,45.03 v3(32.47,44.56) ; R104.2 67.51,58.02 R102.2 68.47,57.03 68.6,57.16 v3(68.6,57.26) ; R168.2 110.28,76.05 v3(110.44,76.21) ; v3(133.75,83.06) 133.75,83.72 133.52,83.95 U20.4 ; C461.2 19.58,70.99 v3(19.23,70.64) 19.06,70.47 U31.2 ; v3(38.88,51.74) 38.88,50.3 C3704.2 ; C236.2 50.73,130.16 v3(50.86,130.29) ; C537.2 102.07,13.44 v3(101.62,13.89) ; C493.2 v3(126.82,24.39) ; v3(27.39,20.67) C3504.2 25.82,20.67 v3(25.68,20.82) ; C523.2 v3(100.28,10.04) ; C622.2 5.61,81.98 C616.2 5.46,81.04 v3(4.9,81.04) ; C530.2 v3(95.58,10.04) ; Y1.4 v3(79.15,60.1) ; 72.08,128.4 72.08,128.91 70.86,130.13 R106.2 ; C150.2 118.75,56.26 v3(118.25,55.75) ; C145.1 v3(91.89,60.22) ; v3(39.54,140.72) 39.2,140.38 C69.2 ; Q12.S 120.71,137.38 v3(119.99,138.11) ; CN33.S1 v3(121.02,4.52) ; v3(99.34,36.44) 99.31,36.41 C332.2 ; v3(8.84,71.13) 10.47,71.13 C435.2 ; SBCN1.S1 v3(98.3,4.41) ; C232.2 v3(135.74,76.51) ; C496.2 v3(93.85,35.29) ; v3(124.28,135.65) 124.93,136.3 C180.2 125.12,136.39 v3(125.12,137.04) ; C654.2 v3(52.92,137.64) ; v3(86.18,44.08) 86.02,44.08 U12.11 86.02,44.84 v3(86.18,44.84) ; v3(36.27,92.49) 37.01,93.24 C65.1 ; v3(41.3,140.52) 41.49,140.33 C75.2 ; C3939.1 v3(113.33,131.22) 113.31,131.24 ; v3(29.37,100.04) 28.86,100.55 C48.1 ; C528.2 v3(95.58,11.19) ; C633.2 v3(124.53,24.39) ; C475.2 v3(127.96,24.39) ; C228.1 v3(137.49,79.35) ; CN4.S2 v3(5.08,37.6) ; 30.14,74.85 30.82,74.85 ; C502.1 v3(130.77,19.84) ; R65.2 v3(125.68,24.39) ; C140.2 v3(112.69,58.43) ; C551.1 v3(120.21,13.85)
  TOP w0.762: v3(114.28,128.4) v3(111.27,128.4) v3(109.95,128.4) v3(108.68,128.4) v3(107.41,128.4) v3(106.19,128.4) v3(105,128.4) 103.75,128.4 ; H3.1 37.08,77.27 34.74,79.62 32.66,79.62 31.07,81.2 26.31,81.2 25.8,81.71 25.8,84.21 v3(24.89,85.12) 24.17,85.84 24.17,90.07 v3(24.43,90.33) v3(24.43,91.98) 24.43,94.71 23.57,95.57 23.57,100.9 v3(24.05,101.37) 24.09,101.42 24.09,104.68 v3(23.95,104.83) 23.85,104.92 23.85,110.93 25.66,112.75 26.17,112.75 30.1,116.68 36.05,116.68 36.88,117.5 38.02,117.5 39.48,118.96 42.91,118.96 43.29,118.58 46.33,118.58 48.24,120.49 48.62,120.49 50.08,121.95 50.08,123.73 48.83,124.98 48.83,127.94 49.28,128.4 51.63,128.4 51.63,128.4 v3(52.55,128.4) v3(53.64,128.4) v3(54.5,128.4) v3(55.77,128.4) v3(57.04,128.4) v3(58.31,128.4) v3(59.58,128.4) v3(60.85,128.4) v3(62.12,128.4) v3(63.39,128.4) v3(64.66,128.4) v3(65.93,128.4) v3(67.2,128.4) v3(68.47,128.4) v3(69.74,128.4) v3(71.01,128.4) v3(72.28,128.4) v3(74.14,128.4) v3(76.27,128.4) v3(78.1,128.4) v3(79.93,128.4) v3(81.68,128.4) v3(83.48,128.4) v3(85.21,128.4) v3(87.04,128.4) v3(88.25,128.4) 89.51,128.4 89.56,128.45 v3(89.68,128.45) 89.73,128.4 93.05,128.4 v3(93.07,128.43) 93.09,128.4 98.42,128.4 v3(98.44,128.38) 98.47,128.4 v3(99.89,128.4) v3(101.11,128.4) v3(102.38,128.4) 103.75,128.4 ; 103.75,128.4 v3(103.8,128.35)
  L2_VCC w0.102: 151.69,94.62 151.61,94.7 151.61,95.28 ; 151.64,93.76 151.64,93.4 151.43,93.2 ; 151.74,96.75 151.74,96.52 151.41,96.19 ; 151.66,97.51 151.58,97.59 151.58,99.65 151.66,99.72 ; 151.53,101.15 151.53,100.88 HDMI1.17
  L3_IN1 w0.127: 151.51,96.12 151.61,96.22 151.61,96.68 151.76,96.83 ; 151.64,94.67 151.64,95.05 151.53,95.15 ; 151.48,93.15 151.64,93.3 151.64,93.7 ; 151.69,97.74 151.64,97.79 151.64,99.65 ; 151.53,101.22 151.53,100.92 151.74,100.72
  L3_IN1 w0.381: v3(24.43,90.33) v3(24.43,91.98)
  L3_IN1 w0.508: v3(84.66,88.77) 84.66,89.07 85.39,89.8 89.13,89.8 91.53,92.19 91.53,94.59 92.27,95.33 92.27,98.05 77.51,112.81 52.61,112.81 48.47,116.96 38.25,116.96 36.68,115.39 v3(36.68,114.41)
  L4_IN2 w0.254: 91.54,124.56 91.85,124.25 91.85,120.35 91.93,120.26 v3(91.93,120.23) ; v4(48.5,78.87) 48.5,80.42 47.27,81.65 47.27,112.24 v3(46.97,112.54) 46.97,116.72 47.2,116.95 47.2,119.49 50.95,123.23 50.95,123.48 ; v3(112.33,121.93) 112.33,114.37 110.96,113 110.96,108.54 97.99,95.56 97.95,95.56 96.34,93.95 96.34,93.41 93.3,90.37 93.3,90.37 91.55,88.61 91.55,87.52 89.71,85.68 89.71,84.72 89.66,84.67 v3(89.66,84.48)
  L4_IN2 w0.381: v3(112.33,121.93) 112.33,122.58 110.37,124.54 v3(109.17,124.54) 109.15,124.56 v3(104.55,124.56) 104.55,124.56 v3(103.74,124.56) v3(102.85,124.56) v3(93.96,124.56) 91.54,124.56 ; v3(76.89,88.53) 77.05,88.53 77.68,89.16 77.68,89.66 79.7,91.68 79.7,95.79 80.65,96.75 80.65,100.97 v3(87.52,107.84) 87.52,108.83 91.88,113.19 v3(91.88,116.97) 91.91,117 91.91,120.18 ; 91.51,124.56 88.86,124.56 87.59,125.84 78,125.84 77.75,125.59 77.75,124.68 76.98,123.92 51.39,123.92 50.95,123.48 ; 91.51,124.56 v3(91.53,124.57) 91.54,124.56 ; 91.51,124.56 91.54,124.56
  L4_IN2 w0.508: v3(72.97,122.11) 72.38,121.51 72.38,118.69 64.69,111.01 64.69,92.51 67.05,90.15 v3(67.05,88.48) 67.05,88.44 68.45,87.04 v3(68.45,86.14)
  L5_GND w0.127: 151.56,95.18 151.56,94.97 151.66,94.87 151.66,94.59 151.79,94.47 ; 151.51,93.25 151.51,93.3 151.71,93.5 151.71,93.68 ; 151.75,96.77 151.58,96.6 151.58,96.22 151.43,96.07 ; 151.66,97.51 151.69,97.54 151.61,97.62 151.61,99.57 151.69,99.65 ; 151.81,100.64 151.58,100.87 151.58,101.17
  BOTTOM w0.102: v3(8.81,67.85) 9.06,67.6 9.71,67.6 ; 9.71,71.6 8.37,71.6 v3(8.33,71.64)
  BOTTOM w0.203: v3(21.94,116.72) 21.84,116.72 21.45,116.33 U25.3 ; U25.113 24.79,123.12 v3(24.86,123.2) ; U25.27 11.85,114.7 12.21,114.33 v3(12.34,114.33) ; S48.2 v3(133.5,137.42) ; v3(23.87,116.62) 23.8,116.69 U25.128 ; v3(13.91,132.32) 13.85,132.25 U25.75 ; v3(7.13,123.66) 7.26,123.52 U25.49 ; U33.43 150.09,35.61 v3(150.31,35.39) 150.13,35.21 U33.42 ; v3(22.18,114.45) 22.3,114.56 U25.1 ; U33.7 152.06,37.14 v3(151.84,36.91) ; U25.91 20.25,131.83 20.65,132.23 v3(20.65,132.34) ; U25.122 v3(24.9,119.52)
  BOTTOM w0.254: U1635.C9 40.13,91.53 v3(39.86,91.8) ; U1635.T1 v3(29.33,84.55) ; v3(33.46,91.96) 32.93,91.44 U1635.M9 ; v3(8.95,66.2) 9.05,66.1 9.05,65.85 9.3,65.6 9.71,65.6 ; R438.1 97.83,90.05 98.22,89.67 v2(98.22,89.42) ; C367.1 93.24,92.74 93.8,92.74 93.98,92.93 93.98,95.15 93.8,95.33 91.77,95.33 v3(91.61,95.49) 91.46,95.33 90.21,95.33 89.78,94.9 89.78,92.62 90.27,92.13 C368.1 ; U1637.A8 42.21,104.29 v3(42.27,104.35) ; R234.1 v3(126.95,119.61) 126.77,119.43 126.26,119.43 125.9,119.07 Q16.1 ; R482.1 R483.2 99.82,75.4 99.36,75.85 v3(98.55,75.85) ; U1637.K1 34.53,109.98 v3(34.84,110.29) 35.73,110.29 U1637.H1 ; USB2R1.4 147.32,73.76 147.32,75.29 ; U1638.T1 v3(29.33,103.09) ; v2(38.97,90.95) 38.57,91.35 U1636.E1 ; U1637.A2 42.11,109.09 v3(42.49,109.47) ; CN1.8 17.87,63.12 18.18,63.43 v3(18.51,63.43) 18.51,63.05 18.37,62.92 CN1.7 ; U1636.D8 39.27,85.75 v3(38.89,85.36) 38.53,85.01 U1636.E9 ; v3(42.53,91.02) 42.05,90.55 U1636.A2 ; U1638.E3 38.62,105.09 39.87,106.34 v2(39.87,106.74) ; v2(39.52,87.38) 39.42,87.28 38.69,86.55 U1635.E3 ; v3(10.5,63.87) 10.49,63.87 10.49,63.92 10.31,64.1 9.71,64.1 ; v2(98.67,89.42) 98.67,90.18 R436.1 ; v2(64.08,64.78) 63.77,64.47 63.77,63.89 R79.2 ; 9.71,67.1 v3(8.81,67.1) ; v3(42.23,85.81) 42.17,85.75 U1636.A8 ; v2(37.33,90.94) 36.94,90.55 U1635.G8 ; C382.2 92.98,86.24 93.02,86.29 v3(93.02,86.32) ; CN1.18 12.87,62.82 v3(13.04,62.98) 13.37,62.65 CN1.17 ; U1637.E9 38.53,103.49 v3(38.93,103.89) U1637.D8 ; U1638.G8 36.94,109.09 37.27,109.42 v2(37.27,109.49) ; U1638.M9 32.93,109.96 v3(32.49,110.4) ; v2(100.27,92.11) 100.58,92.41 100.58,92.62 R422.1 ; v3(40.22,111.11) 40.22,110.95 40.13,110.86 U1638.C9 ; v3(31.73,103.82) 32.07,103.49 U1638.N1 ; Q27.1 129.8,120.72 v3(129.18,121.34) 129.89,122.05 R352.1 ; v2(38.96,109.51) 38.58,109.89 U1637.E1 ; CN1.1 21.37,61.71 20.68,61.01 v3(20.09,61.01) 19.87,61.23 CN1.4 ; U1636.K1 34.68,91.35 v3(35.16,91.82) 35.66,91.82 U1636.H1 ; v3(141.63,50.98) 141.46,51.15 Q39.1 ; v3(31.73,85.37) 32.13,84.97 U1635.N1 ; C372.1 v2(104.52,90.18) ; 9.71,72.1 9.01,72.1 v3(8.94,72.03) ; v2(95.5,88.98) 95.5,89.44 95.35,89.59 C374.1
  BOTTOM w0.305: U1637.H9 35.7,103.06 34.94,103.06 v3(34.92,103.08) 34.53,103.47 U1637.K9 ; 9.71,72.6 v3(8.84,72.6) ; R319.1 121.91,138.28 122.78,137.42 C265.2 ; U1636.K9 34.53,84.93 v3(34.92,84.54) 34.94,84.52 35.7,84.52 U1636.H9 ; U1638.B2 U1637.A8 ; U1638.F1 37.32,103.9 v3(37.32,103.91) ; U1635.B2 U1636.A8 ; U1638.E8 38.53,109.09 38.96,109.51 v2(38.96,109.51) 38.96,109.46 39.33,109.09 U1637.D2 ; v3(38.85,83.83) 38.55,83.83 37.73,84.64 U1635.F1 ; U1635.E8 38.55,90.55 38.97,90.96 v2(38.97,90.95) 38.97,90.91 39.33,90.55 U1636.D2
  BOTTOM w0.356: C183.2 122.1,111.03 v3(121.56,111.56) ; U26.1 v3(142.07,111.69)
  BOTTOM w0.381: C423.1 v2(91.28,77.05) ; C466.1 98.15,66.59 v3(98.34,66.78) ; Q24.1 126.83,137.69 v3(126.94,137.57) ; v3(12.09,108.06) 12.09,106.76 11.25,105.92 U28.8 ; v3(81.43,80.37) 81.63,80.57 C400.2 ; v3(33.19,126.4) 32.66,125.86 C305.2 ; v3(29.13,130.01) C282.2 C283.2 ; C377.1 78.15,86.44 v3(78.33,86.27) ; v3(98.34,93.63) 98.19,93.48 JP12.2 ; v3(88.65,77.84) 88.55,77.94 C413.1 ; v3(79.56,88.56) 79.8,88.32 C381.2 ; R499.1 61.7,67.52 v3(61.6,67.62) ; C385.1 75.84,86.04 v3(75.74,86.14) ; SW1.3 131.34,132.34 v3(131.14,132.54) ; v2(63.46,66.76) 63.46,66.84 63.29,67.01 R498.1 ; C365.1 145.84,92.16 146.15,92.16 146.35,91.96 v3(146.38,91.96) ; LID1.2 158.08,28.28 158.08,27.69 v3(158.13,27.64) ; v3(18.54,102.98) 18.2,103.32 U28.25 ; Q27.4 v3(132.08,118.81) ; C411.1 91.94,77.86 v3(91.92,77.84) ; v2(90.53,68.97) 90.32,69.19 C451.1 ; v3(89.3,74.48) 89.3,74.4 88.89,73.99 C441.1 ; C347.2 149.52,100.13 v3(149.32,99.93) ; v3(94.09,80.11) 93.8,80.4 C405.1 ; v3(83.26,80.37) 82.72,80.91 C398.1 ; v3(63.85,67.77) 64.1,67.52 R497.1 ; Q25.1 109.1,136.6 108.83,136.33 108.83,135.66 v3(108.47,135.29) ; Q39.4 v3(142.76,50.87) ; C399.1 84.93,80.53 v3(85.09,80.37) ; C401.2 69.54,81.52 v3(69.54,81.93) ; R502.1 v2(57.58,68.84) ; Q24.4 124.92,136.39 125.12,136.59 v3(125.12,137.04) ; R3251.2 86.28,70.47 v3(86,70.75) ; C370.2 C369.2 95.29,92.13 v2(95.29,92.36) ; C375.2 88.16,87.84 v3(88.16,86.14) ; SW1.5 v3(135.69,135.17) ; C136.2 80.49,64.47 80.62,64.47 v2(80.94,64.14) ; R383.2 6.5,106.74 v3(6.39,106.64) ; v3(125.7,129.73) 125.75,129.67 125.9,129.67 ; v2(78.56,66.73) 78.86,66.43 C134.2 ; R378.1 20.16,110.6 v3(20.52,110.96) ; C3672.2 19.67,41.94 v3(20.1,41.52) ; v3(146.25,94.29) 146.64,94.69 Q33.S ; v3(33.04,128) 33.04,128.15 32.91,128.28 C290.2 ; C384.1 83.2,86.16 v3(83.17,86.14) ; C345.1 R386.1 7.46,103.74 v3(6.5,104.71) ; v3(32.68,126.4) 32.48,126.6 C292.1 ; v2(98.09,92.46) 97.89,92.26 C366.2 ; R387.2 149.42,103.61 149.76,103.95 HDMI1.S2 ; C443.1 v2(86.1,72.52) ; C512.2 147.39,41.56 v3(147.49,41.66) ; U28.18 v3(16.12,107.87) ; C402.1 86.89,81.03 v3(86,81.93) ; v3(92.57,76.16) 92.57,76.25 92.32,76.49 C418.1 ; R492.1 65.73,67.93 v3(65.88,67.77) ; C270.2 v3(34.95,137.72) ; C463.1 60.39,68.26 v3(59.7,67.56) ; v3(119.99,138.11) 120,138.11 Q21.E ; v3(19.42,105.27) 19.55,105.39 C343.1 ; C458.1 89.05,67.24 88.68,67.61 v3(88.68,67.72) ; v3(121.23,138.64) 121.3,138.56 121.66,138.56 R319.1 ; v2(55.28,87.7) 55.28,87.34 54.99,87.04 R455.2 ; v3(141.2,103.69) 141.27,103.77 C344.2 ; v2(69.92,78.62) 70.34,78.62 C430.2 v2(69.92,79.13) ; C468.2 77.57,63.61 78.4,63.61 78.43,63.64 v2(78.43,63.64) ; C271.2 123.23,134.25 v3(123.36,134.12) ; Q18.1 v3(129.25,136.15) ; v3(31.11,117.99) 31.11,118.32 R358.2 C325.1 ; v3(93.95,74.91) 93.57,75.29 C431.1 ; C373.1 74.59,90.7 v3(73.9,91.39) ; v3(6.34,108.11) 7,108.77 R380.1 ; C406.1 90.6,79.42 91.25,78.76 v3(91.25,78.68) 91.25,78.59 90.52,77.86 C417.1 ; v3(146.91,104.78) 147.48,105.35 D15.1 ; 58.31,137.15 58.31,137.21 57.87,137.66 v3(57.43,137.66) ; v3(24.43,90.33) 24.51,90.4 C361.1 ; U28.4 11.56,103.32 v3(11.76,103.52) ; v3(86.88,88.54) 86.91,88.51 C383.2 ; C432.1 86.74,75.9 v2(86.91,76.08) ; D21.A v3(157.78,10.37) ; SW1.6 v3(130.69,135.25) ; SW1.4 v3(131.34,138.82) ; C339.2 C340.2 18.08,112.28 v3(17.88,112.07) ; C346.2 113.33,101.91 v3(113.13,102.12) ; PJP36.2 v3(21.27,44.31)
  BOTTOM w0.406: Q25.4 v3(108.47,135.29)
  BOTTOM w0.508: v3(89.73,5.34) 90.12,5.34 90.47,4.99 C3492.2 90.47,4.68 89.99,4.2 v3(89.73,4.2) ; v4(121.1,120.33) 121.42,120.64 Q16.4 ; C3924.1 74.79,122.76 v3(74.97,122.94) ; C498.1 148.05,44.92 v3(148.05,45.55) ; v3(110.36,138.97) 110.59,138.74 C263.2 111.67,138.74 Q22.E ; v3(30.54,93.11) 30.57,93.07 C82.1 ; v3(84.22,70.52) 84.21,70.52 83.86,70.17 83.86,69.91 C452.2 ; v3(145.84,27.06) 146.4,26.5 v3(147.06,26.5) AB13.1 ; CN8.S1 20.64,87.49 v3(21.07,87.07) ; C286.2 v3(131.24,127.64) ; C286.2 C285.2 C284.2 ; C286.2 C287.2 ; v3(19.34,73.43) 19.83,73.43 C167.2 ; v3(42.5,51.36) 41.36,50.22 C3697.2 ; R309.1 125.55,139.86 v3(125.55,140.6) 125.55,140.6 ; R250.1 132.15,113.01 v3(132.23,113.08) ; R650.2 101.25,132.28 v3(100.97,132.28) ; AB14.1 150.49,44.96 v3(150.49,45.34) ; Q57.S 141.08,97.01 v3(141.69,97.62) ; v3(93.07,128.43) 92.97,128.32 C79.2 C80.1 C78.1 ; v3(140.54,33.81) 140.54,34.65 140.84,34.96 C524.2 C527.2 ; v3(56.26,57.71) 56.26,57.99 56.77,58.5 C618.2 ; C262.2 126.44,140.34 v3(126.57,140.47) ; v3(152.95,42.3) 152.52,42.3 152.17,41.94 C509.2 ; Q50.S 137.68,65.02 138.17,64.52 138.17,64.29 v3(138.12,64.29) ; R346.1 135.55,127.2 v3(135.94,127.59) ; C393.1 v3(34.58,83.04) ; C293.2 125.57,127.16 125.88,127.47 v3(125.88,127.87) ; v3(33.41,102.4) 33.41,101.78 C81.1 33.71,101.48 34.9,101.48 35.37,101.01 C353.1 ; C623.1 v3(86.81,5.72) ; C3494.2 v3(89.73,3.44) ; R246.1 114.69,123.74 R247.1 114.8,124.1 v3(114.41,124.49) ; v3(139.37,124.74) 140.03,125.4 C146.2 ; v2(95.51,86.11) 95.51,86.17 96.04,86.7 R450.1 96.14,87.17 96.88,87.17 96.89,87.18 96.93,87.18 97.58,87.82 R449.1 ; v3(79,6.58) 79,6.07 C3493.2 78.25,6.18 v3(78.25,6.53) ; C397.1 103.73,80.71 v2(103.83,80.61) ; v3(152.93,41.69) 153.21,41.41 C515.2 ; C3914.1 76.48,128.2 v3(76.27,128.4) ; v3(158.34,38.69) 158.39,38.64 AB11.1 ; v3(137.25,96.89) 136.75,96.39 C634.1 ; C500.1 v3(151.56,44.99) ; R58.1 v3(115.66,22.11) ; v3(40.85,80.7) 40.44,81.11 C396.1 ; R72.2 56.23,90.29 55.97,90.03 v2(55.97,89.65) ; CN8.2 19.61,86.22 v3(19.8,86.03) ; C351.1 32.79,100.28 v3(33.32,100.28) ; C354.1 102.58,98.94 v3(102.94,99.3) ; v3(116.09,120.39) 115.31,120.39 C108.1 C106.2 ; C517.2 110.75,131.83 v3(111.27,131.31) ; R194.1 140.16,60.25 Q53.S 139.9,59.63 139.9,58.86 v3(140.03,58.73) ; C362.1 C356.1 5.3,95 v3(5.59,95.29) ; R74.2 v3(39.59,92.87) ; v3(17.22,70.92) 18,71.71 18,72.07 18.5,72.57 R516.2 C473.2 ; v3(4.08,111.84) 4.64,111.28 C2.2 ; C459.2 80.11,68.64 v3(80.51,69.04) ; v3(9.66,58.66) 11,58.66 CN1.S2 ; v3(74.14,128.4) 74.28,128.26 C3913.1 ; v3(68.31,120.87) 68.55,121.11 C3926.2 ; v3(143.85,39.84) 143.85,40.2 143.48,40.57 AB12.1 ; R69.2 59.02,88.62 59.56,88.09 v3(59.56,87.69) ; C445.2 64.74,88.44 v3(64.8,88.49) ; v3(128.14,129.34) 128.11,129.34 128.31,129.55 C281.2 C289.2 ; Q55.E 102.56,140.18 v3(102.56,140.71) ; 69.29,72.91 C416.2 69.33,72.99 68.78,73.54 v3(68.27,73.54) ; 69.29,72.91 v3(68.27,72.91) ; 69.29,72.91 69.29,72.78 68.78,72.27 v3(68.27,72.27) ; v3(150.06,42.27) 150.67,41.66 C510.1 ; C64.1 36.92,112.31 v3(36.94,112.3) ; 38.95,101.08 38.56,100.69 C349.1 ; 38.95,101.08 39.14,100.89 C3404.1 ; 38.95,101.08 v3(38.95,101.84) ; C273.2 106.01,137.78 v3(105.56,137.32) ; v3(160.08,34.01) 159.99,34.01 159.74,34.27 159.23,33.76 C532.1 ; C3912.1 78.37,128.13 v3(78.1,128.4) ; C3922.1 86.75,120.97 v3(86.78,120.93) ; C272.2 113.52,133.06 v3(113.52,133) ; C597.1 v3(87.96,5.72) ; v3(131.85,110.29) 132.05,110.09 C553.2 133.08,108.07 Q51.S ; C617.2 103.97,132.28 v3(104.53,131.73) ; v3(111.73,58.43) C476.2 ; C3923.1 81.07,123.22 v3(80.75,123.54) ; v3(22.42,133.74) 22.8,133.36 R56.2 ; v3(29.23,113.53) 29.2,113.5 C47.1 ; v3(12.9,70.75) 12.9,69.9 12.88,69.88 ; R54.2 15.77,132.85 15.69,132.78 v3(15.69,132.34) ; C363.2 21.48,92.97 v3(21.82,93.31) ; v2(80.81,66.86) 80.89,66.94 80.97,66.94 81.56,67.52 R3154.1 ; v3(5.97,61.08) 6.19,61.31 6.19,62.35 6.15,62.31 ; C499.1 154.6,44.71 v3(154.1,45.22) 153.59,44.71 R546.1 ; C395.1 43.53,81.11 v3(43.73,80.91) ; v3(81.68,128.4) 81.95,128.13 C3867.1 ; v3(72.97,122.11) 72.81,122.26 C3928.2 ; C592.2 114.3,107.83 v3(114.09,108.04) ; v2(59.7,71.26) 59.69,71.25 R3258.1 ; C516.2 147.87,41.28 v3(147.49,41.66) ; C394.1 v3(27.87,83.02) ; C586.2 21.4,46.51 v3(21.17,46.28) ; v3(19.3,78.83) 19.61,78.51 CN8.S2 ; v3(142.01,72.83) 142.15,72.68 R221.1 ; v3(34.44,112.83) 34.45,112.84 C336.1 ; v3(29.33,103.09) 29,102.76 C3919.1 ; C391.1 v3(36,83.14) ; C152.2 v3(94.22,50.39) ; Q56.S 100.04,136.95 v3(100.5,136.49) ; R317.2 117.01,139.52 v3(116.71,139.82) ; v3(143.63,36.41) 143.63,36.38 144.57,35.44 144.57,35.36 145.28,34.65 AC5.2 ; v3(77.77,122.94) 77.98,122.94 78.29,122.63 C3925.2 ; C147.2 137.72,125.73 v3(137.34,125.35) ; Q49.S v3(137.71,70.49) ; C3911.1 80.2,128.13 v3(79.93,128.4) ; v3(141.55,55.81) 141.04,56.32 R522.2 ; v2(84.75,77.02) 84.63,77.15 C410.2 ; C215.2 132.61,122.74 v3(131.98,122.1) ; v3(115.19,139.82) 115.19,139.69 115.89,139 R318.2 ; v3(67.05,88.48) 67.1,88.42 C455.2 ; v3(93.96,124.56) 94.65,125.25 R227.1 ; v3(115.66,18.93) 115.91,18.68 R62.1 ; C438.2 15.47,72.52 14.75,71.81 v3(14.75,71.68) ; C3929.2 87.55,127.9 v3(87.04,128.4) ; C484.2 84.66,89.7 v3(84.66,88.77) ; v3(32.62,113.69) 32.21,114.1 C3931.1 ; v3(83.48,128.4) 83.75,128.13 C3866.1 ; R637.2 108.01,131.75 v3(108.56,131.75) ; v3(70.93,86.14) 71.27,86.47 C379.2 ; R506.2 92.83,68.89 v3(93.31,68.41) ; 12.14,68.48 12.17,68.51 12.7,68.51 v3(12.75,68.46) ; C358.1 43.3,93.32 v3(42.97,92.99) ; C342.1 146.76,106.31 v3(146.81,106.36) ; v3(76.27,72.53) 77.2,72.53 C437.2 77.33,72.31 76.91,71.89 v3(76.27,71.89) ; C482.2 v3(112.09,53.73) ; R68.2 89.73,128.4 v3(89.68,128.45) ; R405.2 105.33,96.65 v3(105.45,96.78) ; C3917.1 24.38,101.71 v3(24.05,101.37) 24.72,100.7 C3934.1 ; v3(127.45,139.07) 127.45,138.95 127.83,138.57 R512.1 127.95,138.48 Q18.4 ; Q37.S 22.06,70.04 v3(22.62,70.6) 23.3,71.28 Q36.S ; C359.1 33.32,93.58 33.32,92.1 v3(33.46,91.96) ; C357.1 42.33,93.42 v3(42.33,93.25) ; C3491.2 v3(76.15,6.2) ; C3933.1 42.09,99.71 C348.1 42.09,100.73 42.08,100.75 42.08,101.27 v3(42.08,101.27) ; R73.2 51.79,89.84 C85.2 51.79,92.49 v3(51.46,92.82) ; CN8.3 19.62,85.42 v3(19.83,85.2) ; C483.2 81.9,89.11 v3(81.83,89.17) ; C479.2 v3(98.34,52.46) ; 125.9,129.67 C279.2 C288.2 126.05,128.66 v3(125.67,129.04) ; v3(99.36,52.46) C478.1 ; C334.1 42.23,112.84 v3(42.21,112.82) ; v3(23.71,102.92) 24.32,103.53 C3945.1 24.32,104.46 v3(23.95,104.83) ; C472.2 23.34,65.68 R515.2 24.11,64.92 v3(24.11,63.66) ; R367.1 129.36,118.07 129.36,118.24 v3(129.31,118.29) ; C3915.1 72.49,128.2 v3(72.28,128.4) ; JP11.2 v3(98.39,94.5) ; C3927.2 82.72,123.21 v3(82.72,123.79) ; R3247.1 v3(89.1,5.72) ; C404.1 v3(78.02,79.54) ; v3(85.21,128.4) 85.48,128.13 C3916.1 ; v3(37.62,112.88) 37.68,112.93 C56.1 ; C3495.2 v3(77.42,6.2) ; v3(100.37,52.46) C477.2 R519.2 ; C514.1 154.22,41.71 154.1,41.84 v3(154.1,41.87) ; R392.2 v3(102.84,100.08)
  BOTTOM w0.635: v3(60.79,43.17) 60.66,43.3 58.83,43.3 C570.2 C577.2 61.41,42.39 61.74,42.72 v3(61.74,43.17) ; v3(54.5,43.55) 54.5,43.1 55.22,42.39 C632.2 ; v3(60.44,35.83) 61.44,36.83 C590.2 ; C575.2 v3(53.6,43.6)
  vias: v1(6.55,76.21) v2(13.43,68.3) v2(14.12,63.1) v2(14.8,63.07) v2(33.06,106.43) v2(33.06,87.89) v2(59.23,91.45) v2(68.6,57.84) v2(69.23,59.49) v2(69.23,58.98) v2(69.74,59.49) v2(69.74,58.98) v2(70.73,59.6) v2(70.89,62.09) v2(70.96,60.51) v2(72.82,92.84) v2(72.87,95.38) v2(73.65,62.14) v2(73.68,60.61) v2(75.55,94.64) v2(75.55,92.87) v2(75.46,62.14) v2(75.51,60.59) v2(77.13,93.23) v2(77.13,91.19) v2(81.32,93.12) v2(83.1,93.75) v2(83.49,76.29) v2(83.48,75.69) v2(83.5,75.12) v2(88.69,95.58) v2(91.89,65.67) v3(0.44,62.21) v3(0.47,108.38) v3(0.47,103.3) v3(0.49,98.93) v3(0.46,94.64) v3(0.52,91.7) v3(0.52,88.05) v3(0.51,83.77) v3(0.52,79.66) v3(0.53,77.42) v3(0.51,74.49) v3(0.52,72.12) v3(0.47,69.39) v3(0.47,58.79) v3(0.47,53.71) v3(0.47,48.95) v3(0.47,45.52) v3(0.47,42.15) v3(0.47,39.23) v3(0.47,36.82) v3(0.85,34.79) v3(2.44,59.7) v3(2.82,63.42) v3(2.97,133.48) v3(2.97,128.4) v3(2.97,123.32) v3(2.97,118.24) v3(2.97,113.16) v3(3.6,59.67) v3(3.83,42.28) v3(3.9,34.79) v3(4.31,140.85) v3(4.91,49.71) v3(5,106.66) v3(5.46,105.64) v3(5.46,105.06) v3(5.48,104.4) v3(5.77,126.63) v3(6.12,115.8) v3(6.09,114.66) v3(6.22,52.79) v3(6.75,136.73) v3(7.18,72.65) v3(7.31,73.42) v3(7.69,34.81) v3(8.05,74.84) v3(8.07,73.54) v3(9.39,62.62) v3(9.95,140.83) v3(11.78,140.74) v3(11.76,33.66) v3(11.76,30.11) v3(11.76,25.92) v3(11.76,16.9) v3(11.88,21.35) v3(11.88,13.34) v3(14.46,67.3) v3(15.77,18.78) v3(16.3,91.19) v3(16.68,140.82) v3(16.81,92.29) v3(16.81,91.73) v3(17.67,19.35) v3(17.67,17.2) v3(17.67,15.48) v3(17.8,46.34) v3(17.87,43.74) v3(19.26,13.07) v3(19.4,140.75) v3(20.14,108.66) v3(20.11,108.11) v3(20.15,29.96) v3(20.15,23.48) v3(20.15,19.29) v3(20.15,17.26) v3(20.21,15.54) v3(20.28,26.15) v3(20.7,108.66) v3(20.68,108.04) v3(21.2,56.95) v3(21.8,13.07) v3(22.32,140.78) v3(24.09,13.07) v3(24.15,25.01) v3(24.85,14.27) v3(25.23,16.62) v3(25.55,23.55) v3(26.88,24.94) v3(27.43,125.81) v3(27.5,123.86) v3(28.24,125.76) v3(28.24,110.14) v3(29.38,140.85) v3(30.3,16.65) v3(31.9,119.97) v3(32.41,34.34) v3(32.91,20.82) v3(33.04,32.25) v3(33.09,18.93) v3(33.23,29.83) v3(33.35,33.9) v3(33.98,16.65) v3(34.46,140.85) v3(35.2,119.82) v3(35.22,83.28) v3(35.26,82.35) v3(35.26,53.26) v3(35.26,52.69) v3(35.32,33.9) v3(36.14,32.39) v3(36.2,29.28) v3(36.66,34.4) v3(37.93,20.82) v3(38.17,18.93) v3(38.28,106.21) v3(38.28,87.66) v3(38.65,121.52) v3(38.65,120.89) v3(39.06,16.65) v3(39.4,121.53) v3(39.4,120.9) v3(40.16,121.53) v3(40.16,120.9) v3(41.79,29.28) v3(42.99,114.34) v3(43.48,108.77) v3(43.9,20.75) v3(44.01,18.93) v3(44.62,140.85) v3(44.65,16.65) v3(45.38,112.82) v3(45.49,80.82) v3(46.81,32.39) v3(46.87,29.28) v3(47.01,140.52) v3(48.98,20.75) v3(49.11,61.33) v3(49.09,18.93) v3(49.7,140.85) v3(49.73,16.65) v3(50.38,30.59) v3(51.73,122.18) v3(51.83,29.28) v3(53.11,134.92) v3(53.43,134.48) v3(53.74,134.92) v3(54.12,134.42) v3(54.27,140.83) v3(54.62,20.77) v3(54.68,19.25) v3(54.68,16.65) v3(54.81,122.79) v3(55.01,140.51) v3(56.33,79.99) v3(57.51,122.84) v3(57.62,130.96) v3(58.44,130.92) v3(59.08,130.99) v3(59.1,122.36) v3(59.7,20.77) v3(59.84,130.96) v3(59.76,19.25) v3(59.76,16.65) v3(59.86,140.85) v3(60.5,121.5) v3(60.66,130.92) v3(60.85,137.78) v3(60.85,137.21) v3(61.3,130.92) v3(62.02,121.91) v3(64.18,123.02) v3(65.6,19.25) v3(65.6,16.65) v3(65.68,20.82) v3(65.76,121.75) v3(67.28,78.57) v3(67.25,77.78) v3(67.35,121.78) v3(68.07,92.48) v3(68.71,122.93) v3(69.75,140.77) v3(70.52,122.98) v3(70.56,48.88) v3(70.61,46.38) v3(70.7,28.31) v3(70.68,19.25) v3(70.68,16.65) v3(70.76,20.88) v3(71.19,48.9) v3(71.25,46.38) v3(71.83,48.9) v3(71.82,46.35) v3(72.28,9.26) v3(72.35,14.53) v3(72.35,12.05) v3(72.35,6.46) v3(72.35,3.42) v3(72.67,0.62) v3(75.03,121.47) v3(75,19.12) v3(75,16.52) v3(75.02,13.45) v3(75.43,140.85) v3(75.84,0.5) v3(76.27,73.16) v3(76.56,121.57) v3(77.3,20.75) v3(77.36,29.58) v3(77.67,79) v3(77.67,78.37) v3(77.77,122.18) v3(78.3,78.24) v3(78.76,0.5) v3(80.12,121.69) v3(80.51,140.85) v3(80.84,19.12) v3(80.84,16.52) v3(80.98,20.75) v3(81.05,13.64) v3(81.37,0.5) v3(82.02,35.21) v3(82.02,34.64) v3(82.37,55.64) v3(82.89,27.86) v3(83.64,55.51) v3(83.71,28.82) v3(83.91,0.5) v3(84.22,25.96) v3(84.29,20.75) v3(84.41,122.73) v3(84.41,17.45) v3(84.41,14.53) v3(84.62,123.75) v3(84.6,35.65) v3(84.6,34.89) v3(84.85,55.57) v3(84.79,47.71) v3(85.24,28.82) v3(85.59,140.85) v3(85.87,20.82) v3(85.92,19.12) v3(85.92,16.52) v3(86.08,55.51) v3(86.06,27.42) v3(86.06,26.15) v3(86.76,0.5) v3(87.04,123.22) v3(87.32,55.51) v3(87.33,27.42) v3(87.7,63.38) v3(87.78,64.42) v3(87.8,44.84) v3(87.8,44.08) v3(88.56,123.33) v3(88.59,55.43) v3(89.68,0.56) v3(89.83,123.86) v3(89.83,121.57) v3(89.81,62.72) v3(89.83,54.87) v3(89.86,64.35) v3(91.28,136.84) v3(91.46,17.7) v3(91.61,136.38) v3(91.72,13.2) v3(91.87,136.84) v3(92.12,136.38) v3(92.4,136.84) v3(92.37,122.01) v3(92.65,136.38) v3(92.92,0.56) v3(92.99,28.94) v3(93.06,63.89) v3(93.11,15.93) v3(93.24,26.15) v3(93.54,50.3) v3(94.26,63.96) v3(94.57,13.26) v3(94.91,122.2) v3(95.02,64.65) v3(95.17,35.14) v3(95.48,34.64) v3(95.72,0.56) v3(95.87,35.14) v3(96.18,34.64) v3(96.31,122.08) v3(96.56,35.08) v3(98.22,122.29) v3(98.7,0.5) v3(98.76,29.2) v3(100.25,123.47) v3(100.25,121.57) v3(100.83,140.85) v3(101.62,0.5) v3(102.07,26.91) v3(102.07,22.85) v3(102.33,76.26) v3(102.41,79.64) v3(103.17,122.08) v3(103.87,130.09) v3(104.36,130.1) v3(104.44,122.82) v3(104.44,120.93) v3(104.99,0.5) v3(105.91,140.85) v3(105.9,122.01) v3(106.17,81.29) v3(106.51,22.53) v3(107.02,7.99) v3(107.15,8.56) v3(107.59,7.92) v3(107.72,9.07) v3(107.65,8.5) v3(107.65,0.5) v3(107.97,11.86) v3(108.48,123.32) v3(108.76,121.45) v3(109.62,47.27) v3(109.8,46.75) v3(109.8,44.84) v3(109.83,42.83) v3(109.83,42.09) v3(109.8,41.28) v3(109.8,39) v3(109.8,37.6) v3(109.8,36.2) v3(109.91,48.18) v3(110.12,123.66) v3(110.26,2.72) v3(110.26,0.5) v3(110.38,5.45) v3(110.99,140.85) v3(110.98,121.89) v3(111.96,44.59) v3(111.96,43.82) v3(112.42,2.72) v3(112.42,0.5) v3(112.54,42.58) v3(112.54,5.45) v3(112.57,41.97) v3(112.82,114.2) v3(112.82,113.5) v3(112.92,12.56) v3(112.98,34.43) v3(114.32,10.93) v3(114.7,31.48) v3(114.77,2.72) v3(114.77,0.5) v3(114.89,5.45) v3(115.13,34.43) v3(115.23,113.57) v3(115.59,10.98) v3(115.64,8.01) v3(115.65,113.96) v3(115.72,12.69) v3(116.04,29.9) v3(116.07,140.85) v3(116.11,43.37) v3(116.23,113.58) v3(116.35,84) v3(116.81,46.85) v3(116.91,51.21) v3(117.05,80.76) v3(117.42,7.76) v3(117.56,2.72) v3(117.56,0.5) v3(117.73,51.21) v3(117.69,5.45) v3(117.85,140.7) v3(118.16,34.9) v3(118.32,9.89) v3(118.39,86.28) v3(118.45,88.38) v3(119,34.9) v3(119.15,8.24) v3(119.53,12.69) v3(119.59,133.65) v3(119.62,132.97) v3(119.97,85.59) v3(120.04,0.5) v3(120.16,6.85) v3(120.5,121.55) v3(120.66,117.25) v3(120.67,10.97) v3(121.04,121.87) v3(121.01,121.2) v3(121.12,87.05) v3(121.05,83.55) v3(121.12,80.31) v3(121.15,140.85) v3(121.45,118.11) v3(121.51,117.23) v3(121.94,9.58) v3(122.23,117.64) v3(122.28,116.83) v3(122.25,41.48) v3(122.32,0.5) v3(123.21,40.82) v3(123.53,3.1) v3(123.59,80.31) v3(123.69,42.91) v3(124.1,83.55) v3(124.16,87.05) v3(124.42,0.5) v3(124.55,40.69) v3(124.65,42.74) v3(125.5,85.2) v3(125.5,3.04) v3(125.56,40.18) v3(125.69,42.53) v3(126.23,140.85) v3(126.41,51.13) v3(126.39,39.67) v3(126.45,7.86) v3(126.83,80.38) v3(126.77,42.21) v3(126.83,0.56) v3(127,34.88) v3(127.18,51.13) v3(127.4,83.53) v3(127.38,46.78) v3(127.47,39.04) v3(127.63,41.86) v3(127.63,34.88) v3(127.72,6.34) v3(127.91,9.58) v3(128.36,38.6) v3(128.37,34.29) v3(128.38,33.58) v3(128.38,33.01) v3(128.61,41.26) v3(128.61,7.86) v3(128.78,36.62) v3(128.82,35.86) v3(128.83,35.06) v3(128.93,38.09) v3(128.99,29.98) v3(129.31,0.5) v3(129.5,40.56) v3(130.01,9.89) v3(130.01,6.34) v3(130.13,51.55) v3(130.16,39.82) v3(130.82,30.04) v3(130.93,38.69) v3(130.94,37.68) v3(131.02,36.24) v3(130.96,7.86) v3(131.15,35.33) v3(131.17,34.58) v3(131.31,140.85) v3(131.28,3.67) v3(131.34,1.32) v3(131.35,33.85) v3(131.36,33.12) v3(131.7,67.87) v3(131.72,6.08) v3(132.3,24.19) v3(132.3,19.11) v3(132.3,8.95) v3(132.74,14.08) v3(132.8,27.17) v3(132.94,66.76) v3(133.62,68.89) v3(133.94,17.83) v3(134.01,19.61) v3(134.18,6.48) v3(134.31,65.8) v3(134.42,14.59) v3(134.63,59.84) v3(134.66,67.5) v3(134.91,11.46) v3(134.99,7.73) v3(135.25,28.25) v3(135.35,24.34) v3(135.58,32.82) v3(135.89,18.9) v3(135.98,42.32) v3(136.39,140.85) v3(136.61,50.53) v3(136.6,15.57) v3(136.67,11.21) v3(136.84,113.58) v3(136.86,111.95) v3(137.14,86.54) v3(137.11,85.98) v3(137.36,23.9) v3(137.61,42.35) v3(138.3,28.76) v3(138.46,41.33) v3(138.67,117.41) v3(138.99,119.1) v3(138.97,114.98) v3(138.99,6.89) v3(139.18,20.79) v3(139.37,11.87) v3(139.52,42.4) v3(139.62,121.51) v3(139.85,32.54) v3(140.44,121.02) v3(140.74,28.66) v3(140.9,119.5) v3(141.15,38.51) v3(141.24,74.45) v3(141.25,73.59) v3(141.25,72.83) v3(141.47,140.83) v3(141.51,120.75) v3(141.68,122.48) v3(141.68,93.66) v3(141.68,92.01) v3(142,74.45) v3(142.01,73.59) v3(142.03,11.85) v3(142.34,41.51) v3(142.61,114.8) v3(142.63,8.41) v3(142.78,120.52) v3(143.2,96.78) v3(143.2,95.11) v3(143.48,103.18) v3(143.55,101.56) v3(143.55,100.01) v3(143.61,98.41) v3(143.8,119.22) v3(143.84,11.94) v3(144.55,20.65) v3(145.06,6.89) v3(145.42,110.84) v3(145.9,10.05) v3(146.26,7.77) v3(146.55,140.85) v3(146.71,27.33) v3(146.82,64.77) v3(146.83,64.13) v3(147.04,66.88) v3(147.06,69.14) v3(147.34,8.69) v3(147.37,12.04) v3(147.46,72.42) v3(148.21,82.5) v3(148.83,15.19) v3(149.04,76.31) v3(149.02,71.86) v3(149.04,64.47) v3(149.02,59.36) v3(149.04,54.26) v3(149.04,48.91) v3(149.07,82.55) v3(149.16,20.9) v3(149.15,18.06) v3(149.27,25.76) v3(149.4,128.33) v3(149.37,125.12) v3(149.37,99.4) v3(149.42,6.48) v3(149.5,97.62) v3(149.78,133) v3(149.93,123.91) v3(149.87,108.27) v3(149.91,67.03) v3(150.16,69.45) v3(150.31,36.91) v3(150.31,33.87) v3(150.3,28.97) v3(150.56,48.13) v3(151,105.41) v3(151,84.87) v3(151.05,126.91) v3(151.25,134.91) v3(151.51,87.91) v3(151.63,140.85) v3(151.84,35.39) v3(151.84,33.87) v3(152.39,102.5) v3(152.42,91.24) v3(152.83,66.51) v3(152.9,70.01) v3(152.85,68.28) v3(152.94,50.71) v3(153.13,106.76) v3(153.36,36.91) v3(153.36,35.39) v3(153.36,33.87) v3(153.49,123.4) v3(153.49,108.95) v3(153.77,125.28) v3(153.79,84.51) v3(153.89,51.98) v3(154.12,139.86) v3(154.23,104.96) v3(154.22,88.45) v3(154.33,135.89) v3(154.5,6.48) v3(155.14,46.69) v3(155.05,22.87) v3(155.32,86.49) v3(155.35,32.08) v3(155.52,29.19) v3(155.93,43.43) v3(156.13,126.91) v3(156.11,105.59) v3(156.33,134.91) v3(156.64,9.83) v3(156.69,140.75) v3(156.92,49.32) v3(157.71,68.25) v3(157.81,125.35) v3(157.83,23.64) v3(157.88,66.55) v3(157.98,70.01) v3(158.03,37.98) v3(158.52,86.19) v3(158.57,123.4) v3(158.57,108.95) v3(158.56,44.07) v3(158.67,107.5) v3(158.77,48.07) v3(158.87,84.51) v3(158.91,12.09) v3(158.92,6.64) v3(159.23,104.94) v3(159.28,88.45) v3(159.59,9.38) v3(159.73,13.98) v3(159.76,125.08) v3(159.81,51.37) v3(159.81,46.29) v3(159.81,41.21) v3(159.81,31.05) v3(159.81,25.97) v3(160.02,105.01) v3(160.03,38.56) v4(1.06,58.05) v4(2.44,85.45) v4(2.44,84.43) v4(2.69,58.49) v4(4.24,58.3) v4(5.12,57.28) v4(5.25,53.35) v4(5.89,54.49) v4(6.01,55.89) v4(10.18,89.52) v4(10.18,88.5) v4(10.18,87.36) v4(10.18,86.34) v4(11.6,85.12) v4(19.53,139.35) v4(20.8,139.33) v4(24,139.35) v4(25.01,139.35) v4(27.12,139.33) v4(28.16,139.33) v4(30.88,70.66) v4(30.95,73.84) v4(30.95,71.68) v4(31.26,75.62) v4(31.71,74.6) v4(32.34,75.43) v4(32.47,73.84) v4(34.84,74.53) v4(35.73,73.71) v4(36.94,73.44) v4(37.11,71.68) v4(37.36,48.5) v4(37.42,47.55) v4(37.42,46.6) v4(37.37,42.24) v4(38.21,73.64) v4(38.27,72.4) v4(38.29,42.05) v4(38.43,71.38) v4(38.38,48.5) v4(38.38,47.55) v4(38.44,46.6) v4(38.35,43.03) v4(39.3,74.38) v4(39.3,42.11) v4(39.37,43.03) v4(39.67,72.4) v4(39.9,77.6) v4(39.97,75.46) v4(40.16,76.58) v4(40.24,42.11) v4(40.28,43.04) v4(40.94,73.79) v4(40.94,72.4) v4(41.93,70.79) v4(42.08,75.83) v4(42.23,74.56) v4(43.48,75.06) v4(44.03,136.78) v4(44.15,54.22) v4(44.15,53.2) v4(44.15,52.24) v4(44.62,75.06) v4(44.98,136.77) v4(45.23,53.2) v4(45.23,52.24) v4(45.3,54.15) v4(46,136.77) v4(47,136.78) v4(47.16,78.49) v4(48.51,59.74) v4(48.73,60.63) v4(49.04,52.01) v4(49.49,59.74) v4(49.96,51.99) v4(50.47,60.12) v4(55.77,29.32) v4(56.47,30.15) v4(56.85,29.26) v4(57.1,55.57) v4(57.19,54.62) v4(57.21,53.71) v4(57.49,30.09) v4(57.98,29.22) v4(58.11,55.57) v4(58.11,54.56) v4(58.11,53.54) v4(58.11,52.63) v4(58.6,29.99) v4(59.11,29.23) v4(59.51,30.11) v4(59.84,136.64) v4(60.02,29.35) v4(60.68,30.06) v4(60.79,136.51) v4(61.16,29.22) v4(61.67,30.11) v4(62.18,30.87) v4(62.3,29.35) v4(62.81,30.11) v4(63.45,30.87) v4(63.45,29.35) v4(63.95,30.11) v4(64.59,30.87) v4(64.59,29.35) v4(65.1,30.11) v4(65.67,29.39) v4(66,30.27) v4(68.88,30.74) v4(69.39,29.73) v4(69.49,28.5) v4(71.04,43) v4(72.05,43) v4(72.35,28.44) v4(72.77,55.64) v4(72.79,54.36) v4(72.81,53.21) v4(73.36,28.37) v4(74.32,28.37) v4(75.27,28.37) v4(75.4,30.66) v4(75.4,29.58) v4(76.29,28.37) v4(76.35,139.61) v4(76.41,30.66) v4(76.48,29.58) v4(77.49,139.61) v4(78.63,139.61) v4(79.78,139.61) v4(80.92,139.61) v4(82.06,139.61) v4(83.32,47.63) v4(83.32,46.59) v4(83.35,52.72) v4(84.22,47.21) v4(84.3,52.68) v4(96.95,130.31) v4(98.22,130.31) v4(99.49,130.31) v4(101.01,130.31) v4(102.03,130.31) v4(102.91,130.28) v4(104.84,41.87) v4(104.92,47.93) v4(104.85,46.75) v4(104.85,45.73) v4(104.85,44.71) v4(104.85,40.65) v4(104.85,39.63) v4(104.85,38.62) v4(120.5,105.08) v4(120.85,122.56) v4(121.28,104.5) v4(121.84,103.66) v4(122.27,97.37) v4(122.35,98.43) v4(127.02,94.78) v4(128.06,94.83) v4(130.45,95.86) v4(131.57,95.84) v4(148.13,134.63) v4(148.18,138.51) v4(148.23,126.55) v4(148.25,137.42) v4(148.25,136.28)
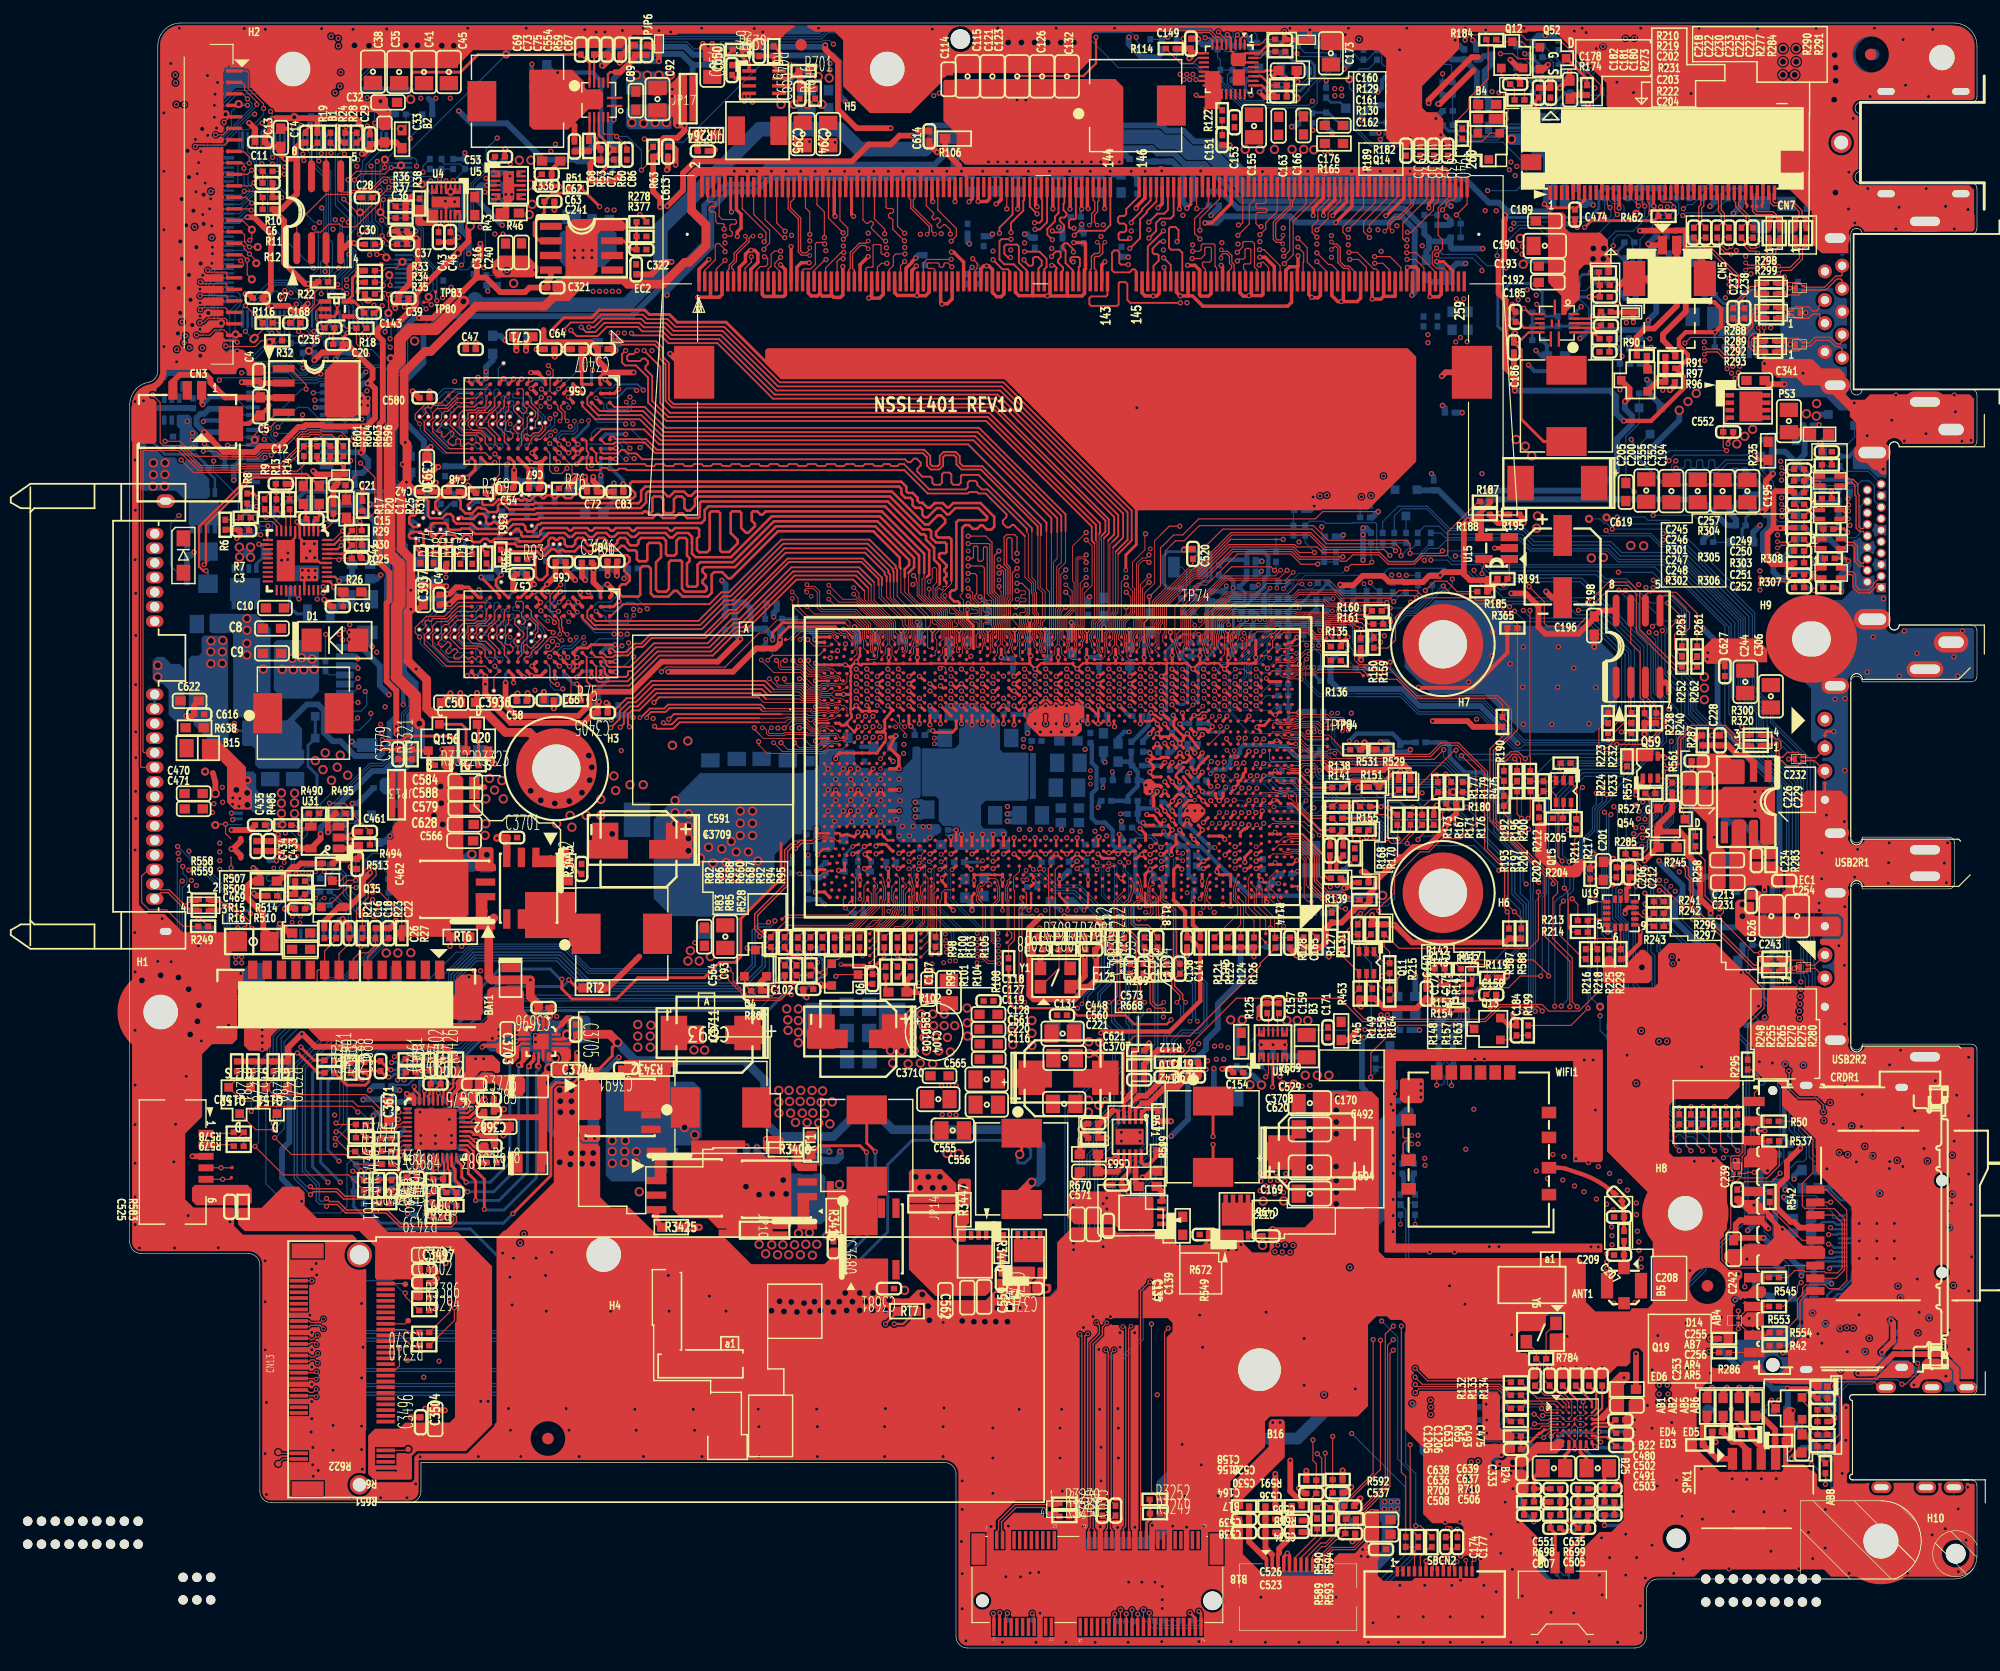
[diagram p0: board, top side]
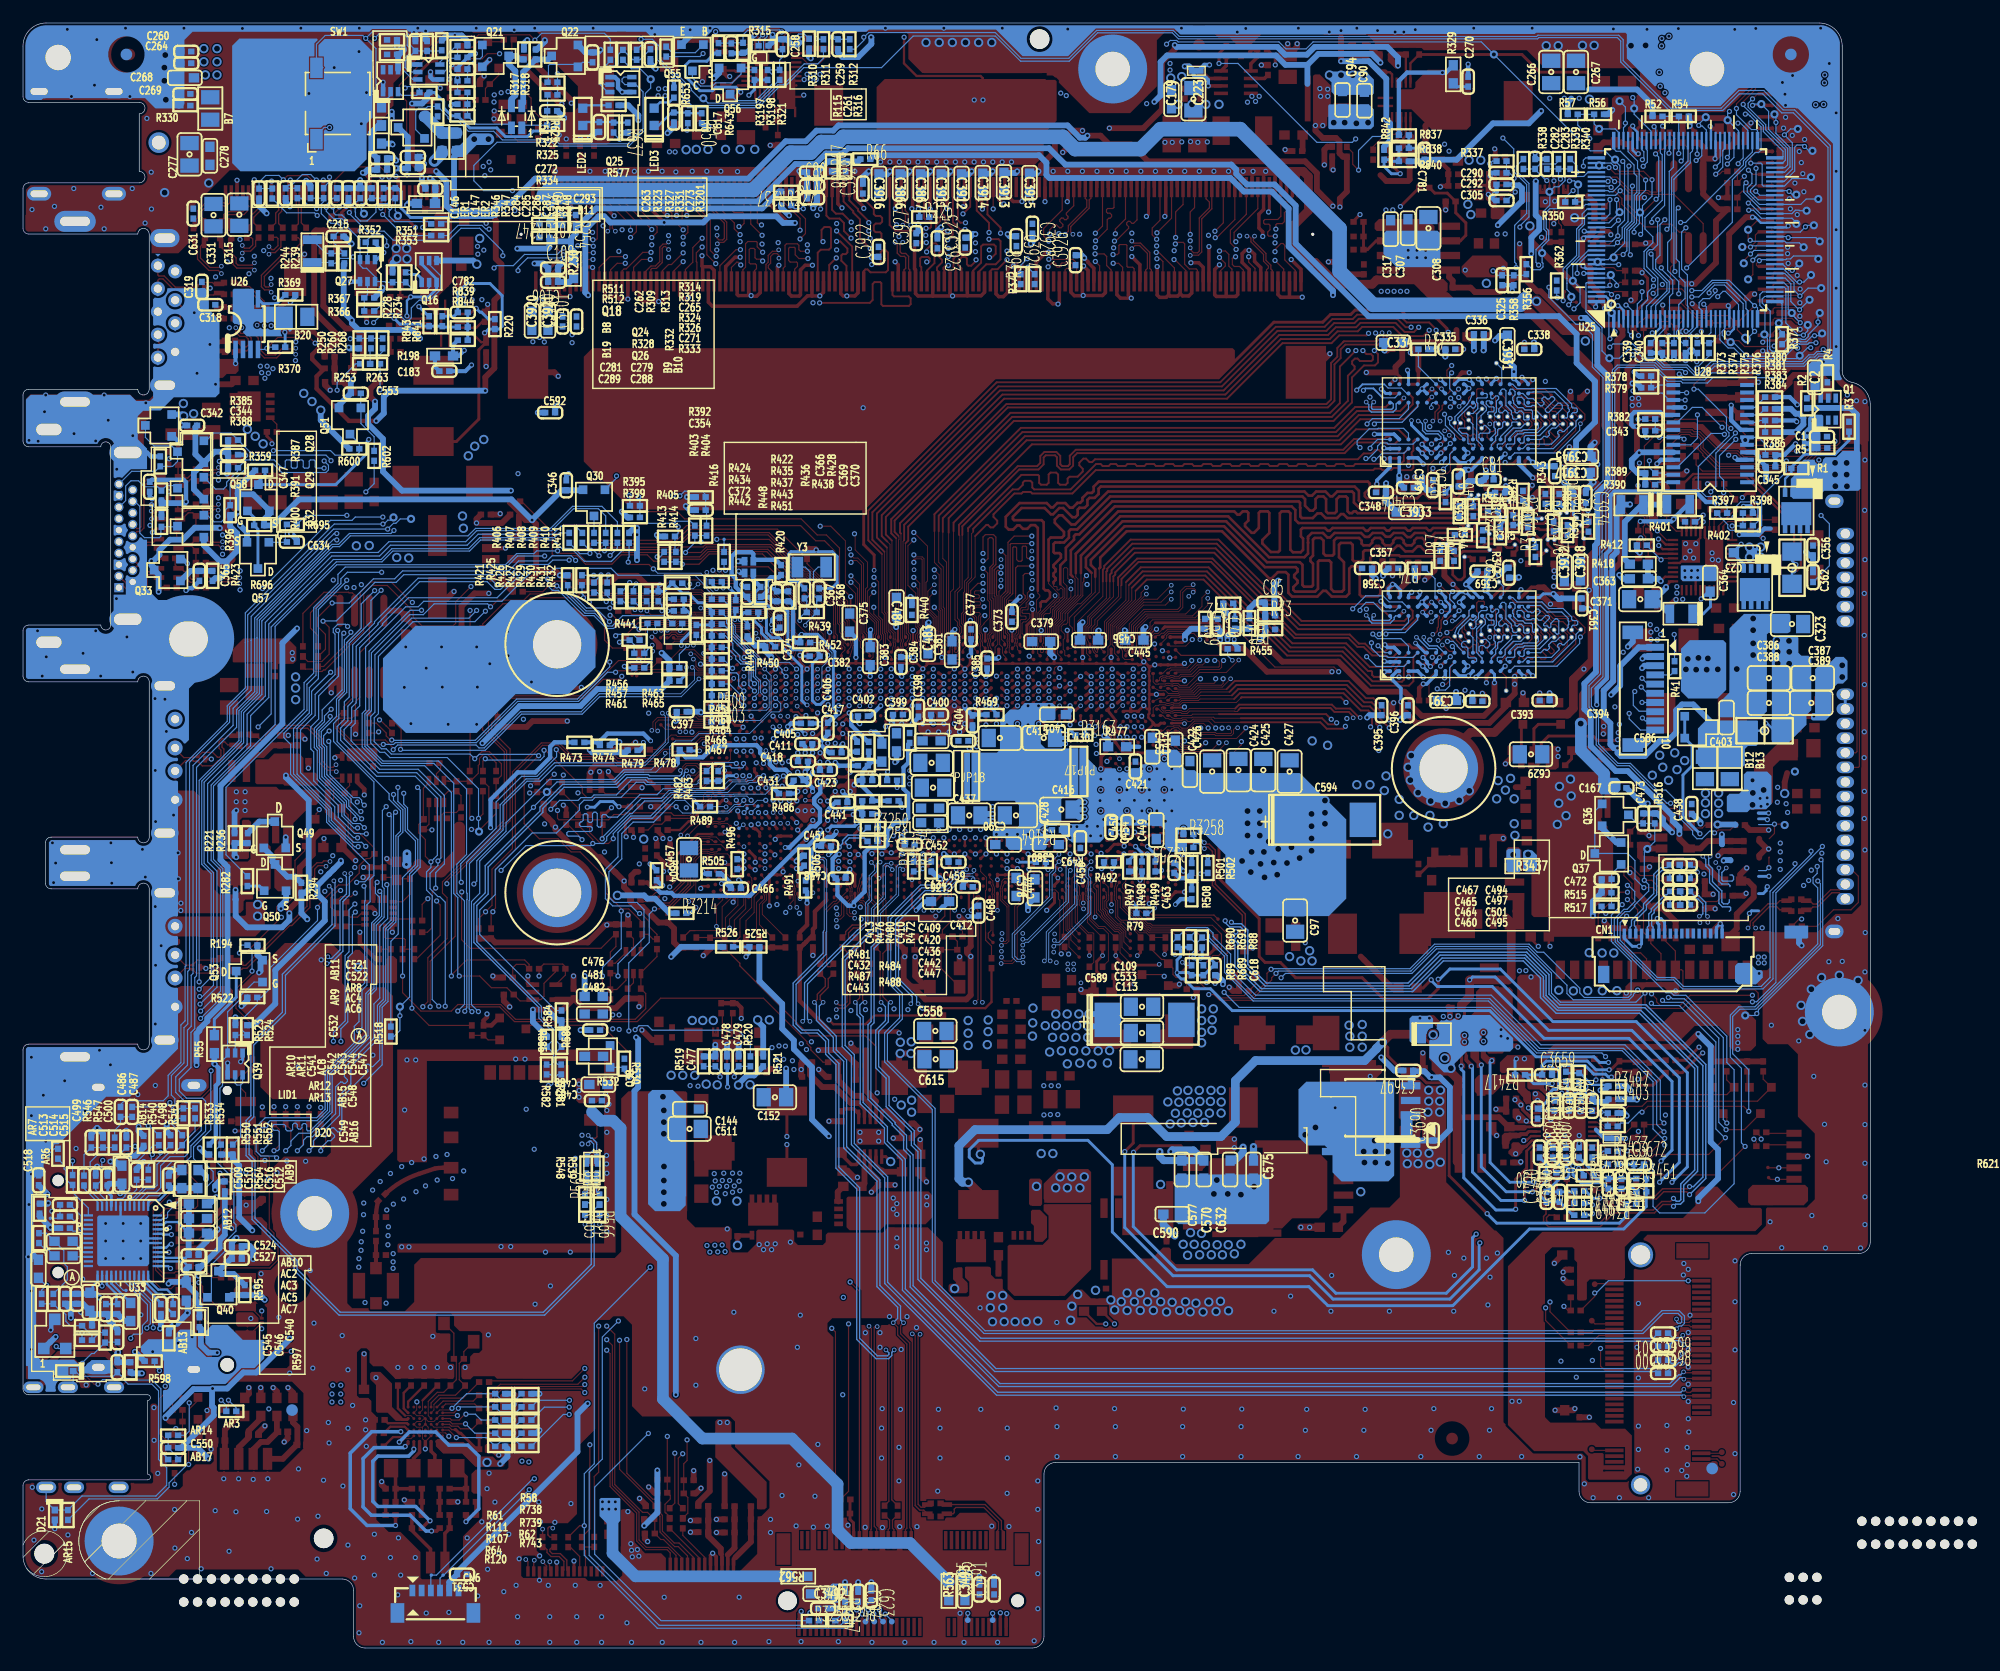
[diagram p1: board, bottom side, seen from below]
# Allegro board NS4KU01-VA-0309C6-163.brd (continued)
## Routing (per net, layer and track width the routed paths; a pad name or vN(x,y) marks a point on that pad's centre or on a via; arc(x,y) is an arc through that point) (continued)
GND_CLK: length 2.4
  TOP w0.102: CN4.1 8.95,44.75 R578.1
GND_DAT: length 2.5
  TOP w0.102: CN4.2 8.92,43.75 R579.1
GND_OZ8690: length 14.1
  TOP w0.203: U1.35 16.55,94.35 15.58,95.31 U1.42 15.58,95.72 14.77,96.53 U1.5 14.77,97.57 14.52,97.82 v3(14.52,97.92)
  TOP w0.508: C25.1 20.03,94.88 v3(20.03,95.23) ; v3(15.95,102.34) 16.25,102.04 PJP2.1 18.08,101.28 C21.1 17.7,100.9 C17.1 ; C12.2 v3(14.14,101.23)
  L3_IN1 w0.508: v3(14.14,101.23) 14.83,101.23 v3(15.95,102.34)
  BOTTOM w0.508: R412.2 20.28,95.88 20.28,95.48 v3(20.03,95.23)
  vias: v3(15.16,96.02) v3(15.36,94.78) v3(15.67,95.38) v3(16.05,96.02) v3(16.07,94.8)
GND_SIGNAL: length 87
  TOP w0.102: 28.09,46.49 28.09,46.47
  TOP w0.203: v3(65.68,28.18) 66.76,29.26 RT7.1 ; v3(27.83,61.01) 27.94,61.11 RT6.1
  TOP w0.508: R648.1 30.44,42.21 v3(30.37,42.28) ; C3671.1 22.59,45.96 v3(23.33,45.96)
  L3_IN1 w0.203: v3(25.23,46.6) 25.17,46.66 ; v3(23.33,45.96) 22.8,46.49 22.8,46.9 22.95,47.04 23.58,47.04 24.53,47.99 24.53,48.37 24.22,48.69 24.22,49.07 24.36,49.22 24.36,49.85 31.14,56.63 31.14,59.02 30.03,60.12 28.72,60.12 v3(27.83,61.01) ; v3(25.29,43.87) 24.86,43.87 24.66,43.66 24.66,41.33 24.86,41.12 25.82,41.12 31.01,35.93 31.01,30.28 33.23,28.05 65.55,28.05 v3(65.68,28.18)
  L3_IN1 w0.254: v3(25.23,46.6) 26.31,47.68 26.31,49.01 v3(27.83,50.53)
  BOTTOM w0.102: v3(27.77,45.96) 27.85,46.04 C3658.2
  BOTTOM w0.381: PJP36.1 23.07,44.31 23.83,45.07 ; 30.37,42.21 v3(30.37,42.28)
  BOTTOM w0.508: C3659.2 27.66,50.36 v3(27.83,50.53)
  vias: v3(25.29,44.56) v3(26.56,44.56) v3(26.56,43.87) v3(27.96,44.56) v3(27.96,43.93)
SVDD: length 2.8
  TOP w0.203: U1634.B7 127.45,20.83 127.45,22.18 C493.1
TP_EN/+2.5VS_ON: length 144.2
  TOP w0.102: v3(129.33,127.9) 129.94,127.29 CN7.14
  TOP w0.254: v3(56.6,137.78) 56.6,138.66 R645.1
  L3_IN1 w0.102: v3(20.67,127.12) 21.87,127.12 21.89,127.1 22.12,126.88 22.12,126.6 22.19,126.53 23.45,126.53 24.12,127.2 24.12,128.87 24.69,129.43 27.84,129.43 28.49,128.79 31.94,128.79 32.1,128.63 35.72,128.63 38.08,131 44.51,131 v3(44.73,131.22) 44.95,131 48.69,131 51.91,127.77 66.3,127.77 66.49,127.97 66.49,128.52 66.99,129.01 71.77,129.01 73.93,131.17 90.32,131.17 91.84,129.65 122.62,129.65 124.99,127.29 128.72,127.29 v3(129.33,127.9)
  BOTTOM w0.102: v3(44.73,131.22) 45.02,130.92 48.09,130.92 54.95,137.78 v3(56.6,137.78) ; U25.119 22.77,120.72 21.36,122.14 21.36,123.43 20.72,124.06 20.72,127.07 v3(20.67,127.12)
V1.00A: length 27.1
  TOP w0.254: v3(88.31,75.04) 88.31,75.08 88.45,74.9 U11.V21 ; v3(90.6,78.68) U11.AF18 ; U11.V21 89.05,74.98 89.55,74.98 U11.V20 ; U11.V21 v3(88.65,74.48) ; v3(89.95,78.68) U11.AF19 ; L8.1 v3(94.15,44.48)
  TOP w0.381: R143.1 105.38,71 104.92,70.54 v3(104.92,70.39)
  TOP w0.508: C142.1 R110.1 88.16,50.79 89.37,51.99 91.4,51.99 v3(91.42,51.97) ; 107.06,67.49 107.34,67.49 107.66,67.16 R153.1
  BOTTOM w0.381: C432.2 87.6,74.94 86.74,74.07 R487.1 R488.1 ; C432.2 87.6,76.17 87.42,76.35 87.42,76.41 R481.1 87.04,76.79 ; C432.2 87.98,75.45 88.31,75.12 v3(88.31,75.04) ; R504.1 105.89,68.03 105.89,68.03 v3(106.04,68.18) ; R480.1 86.76,77.07 87.04,76.79 ; v2(101.49,67.55) 101.26,67.32 R505.1 ; 87.04,76.79 R476.1 ; v3(95.24,74.86) 95.24,74.7 R486.1
  BOTTOM w0.508: R521.1 97,49.79 97.61,49.79 98.36,49.05 v4(98.36,48.95)
  vias: v3(98.24,41.28) v3(98.24,39.76) v3(98.31,40.59) v3(98.72,40.18) v3(98.88,41.28) v3(98.88,39.63) v3(99.13,40.65) v3(99.39,40.14) v3(99.51,39.51) v3(99.64,41.28) v3(99.77,40.65) v3(100.02,40.14) v3(100.27,39.61) v3(100.38,40.62) v3(100.47,41.25) v3(100.64,40.08) v3(101.88,48.85) v3(102.56,48.9) v3(106.98,68.18) v4(97.36,48.98) v4(98.5,38.86) v4(100.21,48.97) v4(100.28,38.87) v4(101.16,49.03) v4(102.16,49.8) v4(103.21,49.8) v4(104.22,49.8)
V1.00A_BOOT: length 2.6
  TOP w0.305: U12.10 87.91,42.25 88.12,42.04 88.56,42.04 89.35,42.83 R671.2
V1.00A_BOOT1: length 5.7
  TOP w0.508: R671.1 88.89,41.51 88.3,40.92 v3(88.02,40.92) ; C563.1 v3(84.76,40.27)
  L4_IN2 w0.508: v3(84.76,40.27) 87.37,40.27 v3(88.02,40.92)
V1.00A_CS: length 7.8
  TOP w0.305: 87.96,47.38 87.41,46.84 U12.2
  TOP w0.508: 87.96,47.38 88.59,47.38 89.99,48.78 91.08,48.78 C529.1 92.15,49.84 92.15,50.76 R669.1
V1.00A_EN: length 6.3
  TOP w0.305: 87.48,47.79 87.48,47.76 86.91,47.19 U12.3
  TOP w0.508: 87.48,47.79 87.71,48.02 88.34,48.02 89.68,49.36 C519.1 89.71,49.69 R576.2
V1.00A_FB: length 6.1
  TOP w0.305: 86.4,47.53 86.4,46.32 86.41,46.3 U12.4
  TOP w0.508: R112.1 R110.2 C142.2 87.3,48.47 86.87,48.04 86.87,48.01 86.4,47.53
V1.00A_LG: length 25.1
  TOP w0.254: v4(85.13,42.3) 85.57,42.73 U12.6
  TOP w0.381: v4(98.45,35.01) C332.1 98.41,35.86 97.22,35.86 Q48.4
  L3_IN1 w0.635: v4(98.45,35.01) 97.37,33.94 87.23,33.94 83.71,37.45 83.71,40.88 v4(85.13,42.3)
V1.00A_LX: length 15.1
  TOP w0.254: L8.2 v3(94.15,43.78)
  TOP w0.305: C563.2 86.23,40.83 86.9,41.5 86.9,41.91 86.91,41.92 U12.8
  TOP w0.508: C563.2 86.23,40.22 v3(86.81,39.63)
  L3_IN1 w0.254: v3(86.81,39.63) 90.01,39.63 v3(94.15,43.78)
V1.00A_RF: length 12.2
  TOP w0.305: U12.5 85.91,46.54 85.71,46.74 85.41,46.74
  TOP w0.508: v3(90.5,45.81) R599.1 ; 85.41,46.74 84.27,45.6 C573.1 R668.1 v3(84.91,44.33)
  L3_IN1 w0.508: v3(90.5,45.81) 86.07,45.81 84.91,44.65 v3(84.91,44.33)
V1.00A_UG: length 2.7
  TOP w0.305: 87.41,41.7 U12.9
  TOP w0.508: 87.41,41.7 87.41,40.41 R672.2
V1.00A_VDD: length 4.7
  TOP w0.305: U12.7 86.41,42.05 85.9,41.54
  TOP w0.508: R670.1 C571.1 85.77,41.41 85.9,41.54
VCCEOPIO_SENSE: length 0.8
  TOP w0.076: v2(64.97,81.95) 65.06,81.95 U11.AL63
VCCGT_SENSE: length 90.7
  TOP w0.076: U11.J70 60.88,70.16 60.74,70.3 60.48,70.42 60.05,70.42 59.93,70.3 59.66,70.3 59.33,69.96
  TOP w0.127: R3439.1 27.44,37.64 27.93,37.64 27.93,37.64 28.14,37.42 28.14,37.16 27.86,36.88 23.58,36.88 22.37,38.09 18.86,38.09 18.12,38.82 17.37,38.82 v3(17.1,39.09) ; 59.33,69.96 58.38,69.96 57.93,69.52 v2(57.87,69.52) 57.84,69.54 57.79,69.54 57.69,69.65 57.55,69.65 57.17,69.27 57.17,66.32 54.57,63.72 54.57,62.6 54.89,62.28 v3(55.14,62.28)
  BOTTOM w0.127: v2(57.87,69.52) 57.93,69.52 58.4,69.99 58.75,69.99 58.82,69.91 R3255.1 ; v3(55.14,62.28) 55.14,62.09 55.52,61.71 55.52,61.46 55.22,61.15 55.22,59.27 53.03,57.09 39.76,57.09 37.11,59.74 30.15,59.74 28.66,58.25 28.66,56.55 27.3,55.19 20.05,55.19 15.26,50.41 15.26,41.56 16.47,40.35 16.47,38.98 16.6,38.85 16.86,38.85 v3(17.1,39.09)
VCCGTX_SENSE: length 2
  TOP w0.076: v2(67.38,79.33) 67.38,79.58 66.91,80.05 66.91,80.24 66.41,80.73 U11.AK62
VCCIO_SENSE: length 0.6
  TOP w0.076: v2(86.91,81.92) 86.98,81.92 U11.AM23
VCCOPC_1P8: length 9.1
  TOP w0.254: v3(64.84,69.73) 64.99,69.88 U11.H63 65.71,69.88 66.03,69.56 66.06,69.52 66.2,69.38 66.22,69.37 66.29,69.3 U11.G61
  L3_IN1 w0.381: v2(58.97,68.97) 60.24,70.24 64.33,70.24 v3(64.84,69.73)
  BOTTOM w0.381: v2(58.97,68.97) R501.2
VCCOPC_SENSE: length 0.6
  TOP w0.076: U11.AC63 65.25,76.58 v2(65.25,76.44)
VCCRTCEXT: length 1.6
  TOP w0.203: v3(95.42,88.45) 95.42,88.36 95.44,88.34 U11.BB10
  BOTTOM w0.254: v3(95.42,88.45) 95.32,88.55 94.96,88.55 C374.2
VCCSA_SENSE: length 112.3
  TOP w0.076: U11.H20 v3(89.61,69.63)
  TOP w0.127: v3(15.71,39.42) 15.96,39.67 17.95,39.67 18.59,39.04 21.31,39.04 R3434.1
  L4_IN2 w0.127: v3(55.52,63.1) 55.52,63.32 56.1,63.89 64.2,63.89 65.74,65.43 66.98,65.43 67.51,65.95 68.89,65.95 69.11,66.17 84.39,66.17 85.83,67.6 86.91,67.6 87.26,67.94 87.26,69.4 88.32,70.47 89.07,70.47 89.32,70.22 89.32,69.91 v3(89.61,69.63)
  BOTTOM w0.127: v3(55.52,63.1) 55.39,62.98 54.65,62.98 54.1,62.42 54.1,59.44 52.48,57.82 40.17,57.82 37.49,60.5 29.87,60.5 29.84,60.48 27.92,58.56 27.92,56.86 27,55.93 19.48,55.93 14.3,50.74 14.3,40.83 v3(15.71,39.42) ; R3250.1 87.76,70.69 88.84,70.69 89.31,70.22 89.31,69.97 v3(89.61,69.63)
VCCST_PWRGD: length 129
  TOP w0.102: R528.1 57.97,58.49 ; 57.97,58.49 R85.1 ; 57.97,58.49 58.2,58.26 58.2,57.78 57.81,57.39 57.3,57.39 56.43,56.53 53.87,56.53 52.43,57.97 52.43,58.66 v3(52.08,59.02)
  L3_IN1 w0.102: v3(16.65,117.76) 17.2,117.2 20.11,117.2 20.49,117.58 21.87,117.58 v3(21.95,117.5) ; v3(22.63,113.84) 21.32,112.53 21.32,99.36 21.04,99.08 21.04,94.84 20.32,94.11 20.32,87.2 21.76,85.75 21.76,82.27 v3(22.2,81.84)
  L4_IN2 w0.102: v3(22.2,81.84) 22.35,81.69 22.35,77.94 21.77,77.36 21.77,64.84 v3(21.56,64.64)
  BOTTOM w0.102: v3(16.65,117.76) 16.65,118.83 17.61,119.79 17.61,122.22 17.27,122.57 17.27,127.86 15.85,129.28 U25.80 ; v3(21.56,64.64) 21.59,64.64 22.5,63.73 22.5,61.46 22.37,61.33 22.37,61.31 20.79,59.72 20.79,56.82 21.04,56.57 24.85,56.57 25.24,56.96 25.24,57.37 28.38,60.5 28.94,60.5 29.64,61.2 37.87,61.2 40,59.06 52.03,59.06 v3(52.08,59.02) ; v3(22.63,113.84) 22.72,113.93 22.72,116.11 22.6,116.23 22.6,116.51 22.52,116.59 22.52,116.93 v3(21.95,117.5)
VCCST_PWRGD_R: length 176.1
  TOP w0.076: 56.91,62.58 57.18,62.85 62.4,62.85 62.57,63.01 62.8,63.01 64.45,64.66 64.45,65.62 U11.B65
  TOP w0.102: 56.91,62.58 56.39,62.06 56.39,60.46 56.63,60.22 57.11,60.22 R85.2 57.55,58.96 57.55,58 v3(57.68,57.87)
  L4_IN2 w0.102: v3(140.11,80.09) 139.87,79.85 139.87,65.83 140.79,64.91 140.79,63.38 136,58.59 130.95,58.59 129.71,59.83 106.43,59.83 104.71,61.55 91.29,61.55 90.61,60.87 85.3,60.87 84.72,61.45 77.34,61.45 76.1,62.7 70.68,62.7 70.17,62.19 70.17,61.43 67.81,59.06 62.72,59.06 60.98,57.33 58.23,57.33 v3(57.68,57.87)
  BOTTOM w0.102: v3(140.11,80.09) 138.97,81.22 138.97,88.78 133.31,94.45 129.34,94.45 128.4,95.38 121.73,95.38 120.77,96.34 114.44,96.34 113.71,95.61 112.88,95.61 111.76,94.5 109.39,94.5 108.38,95.51 108.38,97.72 108.25,97.85 106.32,97.85 106.27,97.8 103.93,97.8 103.75,97.98 102.53,97.98 R403.2
VDDA: length 5.6
  BOTTOM w0.203: R3408.1 26.32,49.99 R3410.1 25.21,49.99 24.19,48.97 22.86,48.97 R3407.1 22.75,48.76 23.01,48.5 23.11,48.5
  BOTTOM w0.508: v3(23.45,48.5) 23.11,48.5 R3407.1
VDDIO: length 6.2
  TOP w0.076: U1634.D3 124.82,19.2 123.9,19.2
  TOP w0.102: 123.9,19.2 123.5,19.2 123.28,18.98 123.01,18.98
  TOP w0.254: 123.01,18.98 122.93,18.98 122.63,18.68 122.5,18.68 121.1,17.28 C490.1 R697.2
VDDQC: length 3
  TOP w0.254: v3(78.68,81.93) 78.25,81.54 U11.AM40
  BOTTOM w0.381: R469.2 77.95,81.16 C404.2 78.68,81.75 v3(78.68,81.93)
VIN: length 73.4
  TOP w0.203: U1.6 14.37,96.56 13.56,95.75
  TOP w0.508: v4(128.06,120.78) 128.35,120.78 128.55,120.58 R210.1 ; v3(68.47,131.94) 68.47,131.94 69.43,131.94 C614.2
  L4_IN2 w0.508: v3(128.04,139.25) 128.04,139.38 127.71,139.71 123.51,139.71 v3(123.01,140.22) ; v3(20.28,47.68) 20.53,47.42 21.42,47.42 22.37,46.47 22.37,41.39 26.76,37.01 43.9,37.01 45.81,35.1 v4(54.7,35.1)
  BOTTOM w0.102: v3(102.79,134.5) 102.43,134.14 96.72,134.14 94.94,135.92 94.47,135.92 92.64,137.75 91.47,137.75 90.98,138.24 R311.1
  BOTTOM w0.508: R314.2 121.91,139.71 122.42,140.22 v3(123.01,140.22) 123.72,140.22 R313.2 ; v3(20.28,47.68) 20.32,47.72 R3403.2 ; v4(128.06,120.78) 128.42,120.43 R228.1 ; R511.2 v3(128.04,139.25)
  vias: v3(13.2,94.59) v3(13.73,94.64) v3(13.75,95.22) v3(82,39.23) v3(82,38.53) v3(84.6,38.64) v3(84.6,37.71) v3(84.91,39.12) v3(84.91,38.17) v3(104.72,135.59) v3(104.73,134.97) v3(105.3,135.57) v3(105.34,134.97) v3(118.39,135.33) v3(118.99,135.24) v3(119.59,135.05) v3(119.61,134.43) v4(13.25,85.1) v4(14.12,86.05) v4(14.22,85.07) v4(14.93,86.1) v4(15.13,85.07) v4(15.86,86) v4(16.02,85.1) v4(16.13,77.16) v4(16.8,76.38) v4(16.99,77.84) v4(17.53,75.45) v4(18.04,76.59) v4(18.3,77.63) v4(18.94,75.89) v4(43.65,132.64) v4(44.66,132.58) v4(45.68,132.64) v4(46.63,132.64) v4(55.27,34.28) v4(55.8,35.06) v4(56.3,34.19) v4(56.76,35.06) v4(57.27,34.19) v4(57.78,35.06) v4(58.12,36.06) v4(58.29,34.19) v4(58.76,35.1) v4(59.08,36.12) v4(59.33,34.15) v4(59.71,35.1) v4(68.31,40.97) v4(68.69,40.01) v4(69.4,40.97) v4(69.78,40.01) v4(70.41,40.97) v4(70.79,40.01) v4(127.2,121.7) v4(127.17,120.78) v4(128.11,121.7)
VIN_CPU_CORE: length 2.1
  TOP w0.102: 53.53,40.09 Q43.7 Q43.8
  vias: v4(53.55,40.12) v4(54.7,39.42) v4(55.84,39.48) v4(56.79,40.69) v4(57.04,39.48)
VIN_CPU_VCCGT:
  vias: v4(25.99,74.09) v4(26.06,75.55) v4(26.44,72.38) v4(27.01,74.92) v4(27.07,73.46) v4(27.2,71.62)
VIN_LCD: length 4.3
  TOP w0.254: 122.2,132.26 122.2,134.56 C182.2
  TOP w0.508: R273.2 125.49,135.04 C180.1
VSSEOPIO_SENSE: length 0.5
  TOP w0.076: U11.AJ62 66.06,80.09 v2(66.57,80.09)
VSSGT_SENSE: length 92.5
  TOP w0.076: U11.J69 61.47,70.16 61.21,70.42 60.92,70.42 60.51,70.59 59.93,70.59 59.84,70.5 59.57,70.5 59.29,70.22 59.27,70.22
  TOP w0.127: R3442.1 28.18,38.25 28.18,37.74 28.39,37.53 28.39,37.06 27.96,36.63 23.47,36.63 22.27,37.83 18.75,37.83 18.02,38.57 17.27,38.57 v3(17.1,38.4) ; 59.27,70.22 58.27,70.22 58.08,70.03 v2(57.87,70.03) 57.75,69.9 57.45,69.9 56.92,69.37 56.92,66.43 54.31,63.82 54.31,62.49 54.74,62.06 v3(54.74,61.89)
  BOTTOM w0.127: R3258.2 58.82,70.49 58.58,70.24 58.09,70.24 v2(57.87,70.03) ; v3(54.74,61.89) 54.99,61.89 55.27,61.6 55.27,61.56 54.96,61.26 54.96,59.37 52.93,57.34 39.87,57.34 37.21,59.99 30.04,59.99 28.41,58.36 28.41,56.66 27.2,55.45 19.94,55.45 15.01,50.51 15.01,41.45 16.21,40.25 16.21,38.87 16.49,38.6 16.91,38.6 v3(17.1,38.4)
VSSGTX_SENSE: length 1.2
  TOP w0.076: U11.AL61 66.9,80.96 66.9,80.48 67.26,80.12 v2(67.35,80.12)
VSSIO_SENSE: length 0.6
  TOP w0.076: v2(87.83,81.92) 87.9,81.92 U11.AM22
VSSOPC_SENSE: length 0.6
  TOP w0.076: v2(65.25,77.33) 65.58,77.66 U11.AE63
VSSSA_SENSE: length 110.1
  TOP w0.076: U11.H21 v3(88.74,69.69)
  TOP w0.127: v3(15.71,40.12) 15.9,39.93 18.06,39.93 18.69,39.29 21.09,39.29 R3436.1
  L4_IN2 w0.127: v3(88.74,69.69) 89.05,70.01 89.05,70.11 88.96,70.2 88.41,70.2 87.51,69.3 87.51,67.84 87.01,67.34 85.93,67.34 84.5,65.91 69.21,65.91 69,65.7 67.61,65.7 67.09,65.17 65.85,65.17 64.31,63.64 56.22,63.64 56.06,63.48 v3(56.06,63.24)
  BOTTOM w0.127: R3251.1 87.44,70.43 88.74,70.43 89.06,70.11 89.06,70.01 v3(88.74,69.69) ; v3(56.06,63.24) 56.06,63.08 55.68,62.7 54.73,62.7 54.35,62.32 54.35,59.33 52.59,57.57 40.06,57.57 37.38,60.25 29.97,60.25 29.95,60.22 28.18,58.45 28.18,56.75 27.1,55.68 19.59,55.68 14.55,50.64 14.55,40.94 15.37,40.12 v3(15.71,40.12)
+0.675_DDR_EN: length 15.1
  TOP w0.102: U13.5 95.3,139.83 v3(94.61,140.52)
  BOTTOM w0.102: v3(94.61,140.52) 94.79,140.7 95.7,140.7 95.88,140.52 95.88,140.11 96.18,139.8 96.18,138.95 96.06,138.82 95.24,138.82 95.04,139.02 C258.1 94.53,138.34 94.79,138.08 R321.2 95.83,137.22 R3198.1 95.4,136.78 95.4,136.03 96.89,134.55 98.53,134.55 Q56.D
+CPU_CORE: length 110.5
  TOP w0.076: 76.33,70.52 U11.K43 76.46,70.53
  TOP w0.203: U11.A39 78.33,64.33 v2(78.15,64.14) ; v2(82.93,64.14) 83.29,64.51 U11.A30 ; v2(75.85,64.14) U11.A44 ; U11.G38 v3(79.6,69.04) 79.62,69.06 U11.G37 ; U11.G32 v3(83.26,69.04) U11.G30 ; v2(81.5,64.14) 81.5,64.7 80.81,65.39 U11.A34 ; U11.G35 v3(81.43,69.04) U11.G33 ; U11.G42 v3(77.77,69.04) U11.G40
  TOP w0.254: U11.AM38 v3(79.6,81.93) U11.AM37 v3(80.51,81.93) U11.AM35 v3(81.43,81.93) U11.AM33 ; v3(14.56,51.74) 14.63,51.74 16.34,50.03 R3422.1 ; v3(64.79,43.17) 64.05,43.91 L27.2 64.05,46.92 ; R99.2 65.7,57.26 R102.1
  L4_IN2 w0.254: v3(14.56,51.74) 14.63,51.74 14.94,51.42 14.94,42.88 13.74,41.67 13.74,37.93 15.99,35.67 33.49,35.67 v3(33.93,35.23)
  BOTTOM w0.076: 83,68.51 83,68.79 v3(83.26,69.04)
  BOTTOM w0.254: v3(33.93,35.23) 33.99,35.17 33.99,32.88 36.53,30.34 46.69,30.34 48.73,32.37 60.6,32.37 64.79,36.56 v3(64.79,43.17)
  BOTTOM w0.381: C468.1 77.74,64.55 v2(78.15,64.14) ; v2(82.93,64.14) 82.16,64.91 C136.1
  BOTTOM w0.508: 67.23,55.13 v4(67.89,55.13) ; 67.23,55.13 C589.1 ; 67.23,55.13 66.77,55.13 C589.1 ; C589.1 66.83,54.06 v4(68.02,54.06)
  vias: v2(78.81,64.14) v2(79.57,64.14) v2(82.24,64.14) v3(77.31,71.17) v3(77.77,70.45) v3(78.23,71.17) v3(78.68,80.37) v3(79.14,79.65) v3(79.14,71.17) v3(79.6,70.45) v3(80.06,79.65) v3(80.06,71.17) v3(80.51,80.37) v3(80.97,79.65) v3(80.97,71.17) v3(81.43,70.45) v3(81.88,79.65) v3(81.88,71.05) v3(82.34,80.37) v3(82.59,71) v3(83.03,78.14) v4(56.41,48.48) v4(56.41,47.48) v4(56.42,46.51) v4(57.3,48.49) v4(57.35,47.53) v4(57.43,46.51) v4(57.86,45.7) v4(58.32,48.49) v4(58.26,47.53) v4(58.45,46.51) v4(58.86,45.7) v4(59.18,47.53) v4(59.3,48.49) v4(59.36,46.52) v4(59.88,45.66) v4(60.09,47.47) v4(60.22,48.44) v4(60.39,46.5) v4(60.85,45.57) v4(61.05,47.49) v4(66.11,51.95) v4(66.3,50.87) v4(67.1,51.93) v4(67.65,50.79) v4(68.02,53.1) v4(68.17,51.93) v4(68.7,50.86) v4(68.78,55.13) v4(68.96,54.11) v4(69.03,53.1) v4(69.23,51.93) v4(69.8,55.13) v4(69.78,50.79) v4(69.87,54.11) v4(70.05,53.1) v4(70.3,51.93) v4(70.78,55.13) v4(70.78,54.11) v4(71.07,53.1) v4(71.32,51.83) v4(71.7,54.11)
+CPU_VCCGT: length 105.7
  TOP w0.076: U11.AA71 v3(60.7,76.45) 60.38,76.78 U11.AC71 ; v3(63.95,71.88) U11.L66 ; v3(63.3,72.79) U11.N67 ; v3(65.25,71.88) U11.L64 ; v3(62.65,74.62) U11.U68 ; v3(60.7,72.79) U11.N71 ; U11.W65 64.08,75.36 v3(63.95,75.54) ; v3(62.65,75.54) 62.78,75.36 U11.W67 ; v3(62,76.45) U11.AA69 ; U11.W69 61.48,75.36 v3(61.35,75.54) ; 62.65,71.88 U11.L68 ; v3(61.35,73.71) 61.14,73.41 U11.R70 ; v3(60.7,74.62) U11.U71 ; U11.R68 62.44,73.41 v3(62.65,73.71) ; U11.R66 63.74,73.41 v3(63.95,73.71) ; v3(64.6,74.62) U11.U65 ; v3(62,72.79) U11.N69 ; 61.35,71.88 U11.L70 ; v3(63.3,76.45) U11.AA67
  TOP w0.152: U11.BB57 v2(68.45,89.2)
  TOP w0.178: v2(59.6,80.38) 59.78,80.4 59.79,80.42 U11.AK70 ; v3(62.99,88.79) 63.47,88.33 U11.BB66
  TOP w0.203: v2(68.4,64.78) 68.42,64.8 U11.A58 ; v2(65.94,64.65) U11.A62 ; U11.A66 v2(63.46,65.13)
  TOP w0.254: v3(64.97,84.48) U11.AU63 ; v2(70.45,81.93) U11.AM53 71.37,81.08 U11.AL53 ; v2(68.63,81.93) U11.AM56 ; U11.AL60 67.71,80.37 67.79,80.3 67.79,80.25 v3(67.89,80.15) ; U11.AL56 v3(69.54,80.27) ; v3(67.71,84.48) U11.AU58 ; 56.6,69.96 56.6,66.92 53.11,63.42 53.11,60.12 52.6,59.61 51.27,59.61 49.93,58.28 44.15,58.28 42.31,56.44 38.44,56.44 37.55,57.33 v3(37.55,58.15) ; v3(67.71,81.93) U11.AM58
  TOP w0.508: 44.28,60.12 41.55,57.39 RT2.2
  L4_IN2 w0.254: v3(17.23,40.5) 20.21,37.52 23.9,37.52 v3(24.15,37.77)
  BOTTOM w0.254: v3(37.55,58.15) 37.42,58.15 36.53,59.04 32.15,59.04 27.58,54.47 20.34,54.47 15.9,50.03 15.9,41.83 v3(17.23,40.5) 17.26,40.47 ; R3446.2 24.28,37.64 v3(24.15,37.77) ; v3(67.89,80.15) 68.22,79.82 R3163.2
  BOTTOM w0.508: v2(68.45,89.2) 68.68,88.97 C455.1 ; v3(62.99,88.79) 63.17,88.61 C445.1
  vias: v3(61.26,71.89) v3(62.76,71.86) v3(65.25,75.54) v3(65.25,73.71) v3(66.62,72.04) v3(66.87,75.55) v3(66.94,73.68) v3(66.87,70.62) v3(67.16,71.45) v3(67.76,70.62) v3(68.07,71.45) v3(68.95,71.42) v3(69.49,71.42) v3(69.54,70.45) v4(47.39,73.69) v4(47.39,72.63) v4(47.39,71.67) v4(48.56,72.52) v4(48.56,71.46) v4(48.56,70.39) v4(48.56,69.32) v4(49.59,68.69) v4(50.3,69.63) v4(50.69,68.26) v4(51.45,69.49) v4(51.54,67.24) v4(51.84,68.3) v4(52.28,70.13) v4(52.64,67.01) v4(52.7,69.22) v4(52.99,68.18) v4(53.05,72.78) v4(53.05,71.71) v4(53.05,70.65) v4(53.77,69.22) v4(53.84,67.47) v4(54.12,72.78) v4(54.12,71.71) v4(54.12,70.65) v4(54.59,68.43)
+CPU_VCCGTXR42: length 14.5
  TOP w0.254: U11.A53 70.9,64.82 v3(71.57,64.14) ; U11.J45 v3(75.03,70.75) ; U11.J50 v3(72.28,70.75) ; U11.AL46 v3(75.03,80.27) ; U11.J43 v3(75.94,70.75) ; v3(73.2,81.93) U11.AM48 ; U11.A48 73.38,65.57 73.2,65.39 v3(73.2,64.14) ; U11.J48 v3(73.2,70.75) ; U11.AL50 v3(73.2,80.27) ; U11.AM50 v3(72.28,81.93) ; U11.AL43 v3(76.86,80.27) ; U11.J46 v3(74.11,70.75) ; v3(71.37,81.93) U11.AM52 ; U11.J52 v3(71.37,70.49)
  BOTTOM w0.508: v3(73.2,64.14) 73.2,64.66 C378.1
+VSDIO: length 85.9
  TOP w0.254: v3(93.22,77.84) 93.15,77.76 U11.AD15 ; R173.2 110.02,72.45 v3(109.4,73.07)
  TOP w0.457: 142.07,66.48 v3(142.07,65.92)
  TOP w0.508: 132.99,70.98 Q54.S 132.86,71.59 134.06,72.78 R561.1 ; 132.99,70.98 132.74,70.98 132.74,69.73 R245.1 132.77,69.6 v3(131.64,68.47) ; 132.99,70.98 134.71,70.98 135.35,70.34 135.35,68.99 136.5,67.85 136.5,65.13 137.39,64.24 v3(137.39,63.89)
  L3_IN1 w0.254: v3(102.9,73.06) 102.7,73.26 102.05,73.26 101.48,73.84 101.42,73.84 99.94,75.31 99.94,75.67 99.74,75.87 99.38,75.87 98.94,76.31 94.53,76.31 94.2,76.64 93.71,76.64 93.22,77.14 v3(93.22,77.84) ; v3(115.21,71.66) 115.54,71.33 v3(119.91,71.33)
  L3_IN1 w0.508: v3(131.64,68.47) 131.62,68.49 129.97,68.49 126.45,72 123.66,72 122.53,73.13 120.75,73.13 119.91,72.28 v3(119.91,71.33)
  L4_IN2 w0.254: v3(102.9,73.06) 103.16,73.06 103.57,72.65 108.99,72.65 v3(109.4,73.07) 109.82,72.65 112.68,72.65 113.19,72.14 114.73,72.14 v3(115.21,71.66)
  BOTTOM w0.381: v3(93.22,77.84) 93.19,77.81 C418.2 ; R473.2 113.4,78.75 113.41,78.75 114.35,78.75 114.73,78.37 114.73,77.42 116.01,76.14 117.54,76.14 119.91,73.77 v3(119.91,71.33)
  BOTTOM w0.508: v3(137.39,63.89) 137.39,63.31 138.04,62.67 141.05,62.67 142.06,63.67 142.06,65.08 142.07,65.09 v3(142.07,65.92)
+VSDIO_EN: length 5.8
  TOP w0.508: R287.1 C228.2 138.88,78.49 139.72,77.65 140.48,77.65 141.12,77.02 U23.2
+VSDIO_R: length 29.7
  TOP w0.102: R167.2 R171.2 112.31,73.05 R177.2 R179.2 R475.2 116.43,74.43 v3(116.51,74.35) ; R258.2 136.07,71.15 Q54.D 135.07,72.14 135.07,72.53 134.8,72.81 v3(134.8,72.91)
  L3_IN1 w0.102: v3(131.49,73.56) 134.26,73.56 134.57,73.26 134.57,73.14 v3(134.8,72.91)
  L4_IN2 w0.102: v3(116.51,74.35) 117.46,74.35 118.42,73.39 125.2,73.39 126.58,72.02 128.98,72.02 130.76,73.8 131.26,73.8 v3(131.49,73.56)
ACZ_BITCLK: length 32.1
  TOP w0.076: 92.25,94.14 89.05,90.94 89.05,89.43 88.91,89.29 88.91,88.6 88.58,88.27 88.58,87.8 88.63,87.68 88.63,87.54 88.57,87.31 88.57,87.19 88.64,86.98 88.74,86.87 88.84,86.76 U11.AY22
  TOP w0.102: 92.25,94.14 92.4,94.3 C520.2 94.99,97.29 102.74,97.29 104.01,96.02 109.98,96.02 110.46,95.54 110.46,95 v3(110.48,94.98)
  BOTTOM w0.102: R407.2 111.45,95.61 111.12,95.61 v3(110.48,94.98)
ACZ_BITCLK_CODEC: length 88.8
  L4_IN2 w0.102: v3(145.16,55.99) 145.16,55.87 145.84,55.18 145.84,52.38 147.7,50.53 150.77,50.53 152.27,49.03 152.27,44.43 150.93,43.09 149.48,43.09 v3(149.3,42.9)
  BOTTOM w0.102: v3(145.16,55.99) 143.68,57.46 143.68,67.55 144.49,68.36 144.49,75.16 141.06,78.59 141.06,81.2 139.48,82.78 139.48,89.18 133.7,94.96 129.55,94.96 128.61,95.89 121.94,95.89 120.98,96.85 114.48,96.85 113.79,97.54 112.52,97.54 R407.1 ; v3(149.3,42.9) 149.4,42.81 149.4,42.22 149.65,41.97 R564.1
ACZ_RST#: length 36.1
  TOP w0.076: 90.49,95.89 89.99,95.39 89.99,92.14 88.87,91.02 88.87,89.49 88.75,89.37 88.75,88.69 88.41,88.35 88.41,87.76 88.43,87.73 88.46,87.65 88.46,87.53 88.39,87.31 88.39,87.17 88.45,87.01 88.45,86.93 88.67,86.23 88.67,86.23 88.84,86.05 U11.AW22
  TOP w0.102: 90.49,95.89 90.88,96.28 91.64,96.28 92.96,97.59 102.87,97.59 104.14,96.32 110.94,96.32 111.27,95.99 v3(111.27,95.18)
  BOTTOM w0.102: R406.2 112.14,95.16 111.3,95.16 v3(111.27,95.18)
ACZ_RST#_CODEC: length 91.8
  L4_IN2 w0.102: v3(145.1,55.38) 145.54,54.95 145.54,52.26 147.57,50.22 150.64,50.22 151.94,48.93 151.94,44.65 150.9,43.62 v3(150.79,43.62)
  BOTTOM w0.102: U33.11 153.66,38.74 154.71,39.78 154.71,42.25 153.97,42.98 152.09,42.98 C500.2 151.45,43.62 v3(150.79,43.62) ; R406.1 113.94,96.96 114.35,96.54 120.86,96.54 121.81,95.59 128.49,95.59 129.42,94.65 133.56,94.65 139.18,89.04 139.18,82.66 140.76,81.07 140.76,78.46 144.19,75.03 144.19,68.49 143.38,67.67 143.38,57.11 v3(145.1,55.38)
ACZ_SDATAIN0: length 110.1
  TOP w0.076: U11.BA21 89.44,86.95 89.44,88.2 89.58,88.33 89.58,88.94 89.76,89.12 89.76,90.7 92.36,93.3 92.88,93.3 93.16,93.58
  TOP w0.102: 93.16,93.58 95.52,95.94 101.24,95.94 101.44,95.74 103.19,95.74 103.68,95.26 108.63,95.26 109.44,94.45 111.56,94.45 112.3,95.18 113.86,95.18 v3(114.08,95.4)
  L4_IN2 w0.102: v3(145.1,54.74) 145.28,54.57 145.28,52.13 147.44,49.97 149.55,49.97 149.96,49.56 149.96,45.7 v3(149.65,45.4)
  BOTTOM w0.102: v3(114.08,95.4) 115.9,95.4 116.14,95.16 117.65,95.16 118.61,94.19 133.28,94.19 138.63,88.84 138.63,80.3 143.99,74.94 143.99,68.57 143.17,67.76 143.17,56.68 v3(145.1,54.74) ; R540.1 149.55,45.4 v3(149.65,45.4)
ACZ_SDATAOUT_CODEC: length 96.4
  L4_IN2 w0.102: v3(148.58,43.09) 149.27,43.77 149.27,45.56 149.75,46.04 149.75,49.48 149.47,49.77 147.31,49.77 145.08,52 145.08,54.24 144.95,54.36 144.95,54.36 144.67,54.64 144.67,56.35 144.98,56.65 v3(145.18,56.65)
  BOTTOM w0.102: U33.5 151.26,38.83 149.96,40.14 149.28,40.14 149.09,40.32 149.09,42.37 148.58,42.88 v3(148.58,43.09) 148.36,43.09 C498.2 ; v3(145.18,56.65) 144.95,56.65 143.99,57.62 143.99,67.42 144.8,68.23 144.8,75.28 141.37,78.71 141.37,81.33 139.79,82.91 139.79,89.3 133.83,95.26 129.68,95.26 128.74,96.2 122.07,96.2 121.11,97.15 114.61,97.15 112.69,99.07 110.53,99.07 109.9,98.43 R409.1
ACZ_SDOUT: length 28.8
  TOP w0.076: U11.BB22 88.84,88.3 89.08,88.54 89.08,89.14 89.22,89.29 89.22,90.86 92.16,93.8 92.51,93.8 92.55,93.84
  TOP w0.102: v3(110,95.41) 109.7,95.72 103.89,95.72 102.62,96.99 95.7,96.99 92.55,93.84
  BOTTOM w0.102: v3(110,95.41) 109.9,95.51 R409.2 R408.1
ACZ_SPKR: length 109.6
  TOP w0.076: v3(98.88,85.19) 98.57,85.5 U11.AW5
  L4_IN2 w0.076: v3(98.88,85.19) 100.13,85.19 101.49,83.83 102.1,83.83 103.5,85.23 106.6,85.23
  L4_IN2 w0.102: 106.6,85.23 107.51,85.23 108.02,85.73 108.91,85.73 109.29,85.35 109.75,85.35 110.56,86.16 110.56,89.42 112.59,91.45 118.33,91.45 120.8,88.98 126.43,88.98 v3(129.42,91.97) ; v3(147.77,47.43) 147.54,47.66 142.69,47.66 141.8,48.55 131.49,48.55 v3(130.93,49.1)
  BOTTOM w0.076: v3(98.88,85.19) 99.67,85.99 R460.2
  BOTTOM w0.102: C487.2 148.15,47.05 v3(147.77,47.43) ; v3(129.42,91.97) 130.3,91.09 130.3,89.25 132.19,87.35 132.19,82.7 132.61,82.27 132.61,80.75 133.24,80.12 133.24,78.81 128.72,74.29 128.72,73.8 127.73,72.8 127.73,71.03 128.14,70.62 128.14,63.13 128.82,62.44 128.82,56.22 129.33,55.71 129.33,50.71 v3(130.93,49.1)
ACZ_SPKR_B1: length 3
  BOTTOM w0.102: R547.2 152.57,45.02 152.06,45.52 C486.1 C487.1
ACZ_SPKR_B2: length 4.7
  BOTTOM w0.102: C513.1 155.24,42.88 C499.2 R546.2 R547.1
ACZ_SYNC: length 28.5
  TOP w0.076: U11.BA22 88.97,87.25 89.11,87.4 89.11,88.33 89.25,88.47 89.25,89.08 89.4,89.23 89.4,90.81 92.23,93.63 92.64,93.63 92.7,93.69
  TOP w0.102: v3(109.52,95) 109.01,95.51 103.8,95.51 102.53,96.78 95.78,96.78 92.7,93.69
  BOTTOM w0.102: v3(109.52,95) 108.88,95.64 R410.2
ACZ_SYNC_CODEC: length 96.6
  L4_IN2 w0.102: v3(145.23,57.28) 145.26,57.28 145.56,56.98 145.56,55.89 146.15,55.31 146.15,52.51 147.82,50.83 151.07,50.83 152.57,49.33 152.57,43.44 v3(153.61,42.4)
  BOTTOM w0.102: v3(153.61,42.4) 153.69,42.32 153.69,40.7 154.17,40.22 C514.2 154.22,39.84 153.26,38.88 U33.10 ; R410.1 108.88,97.92 110.23,99.27 112.78,99.27 114.69,97.36 121.21,97.36 121.86,96.71 132.09,96.71 133.03,95.77 133.61,95.77 140,89.38 140,82.98 141.57,81.41 141.57,78.81 145,75.38 145,68.15 144.19,67.34 144.19,58.33 v3(145.23,57.28)
ADAP_IN: length 44.4
  TOP w0.102: C235.1 17.47,115.35 18.23,115.35 18.82,114.77 R18.1 19.7,113.42 v3(20.67,112.45) ; C235.1 16.8,114.67 16.19,114.67 v3(16.01,114.49) 16.01,113.23 v1(15.57,112.79) ; C235.1 16.15,115.57 16.15,116.21 16.38,116.44 Q17.2 ; v3(20.06,103.03) 21.3,101.79 21.3,98.78 20.94,98.41 19.74,98.41 19.6,98.27 19.6,97.65 19.73,97.52 19.73,96.85 19.52,96.63 19.52,96.42 19.73,96.21 19.73,95.58 19.64,95.49 19.46,95.49 19.3,95.33 C25.2 18.31,94.75 v3(18.18,94.62) 18.06,94.75 U1.36
  L4_IN2 w0.102: v3(20.06,103.03) 19.57,102.54 18.06,102.54 17.57,103.03 17.57,105.89 17.04,106.42 17.04,109.33 16.06,110.31 v3(16.06,110.9)
  BOTTOM w0.102: v3(18.18,94.62) 19.43,95.86 R412.1 ; v3(20.67,112.45) 19.97,111.76 18.67,111.76 18.08,111.16 16.31,111.16 v3(16.06,110.9) ; v3(16.01,114.49) 15.74,114.49 15.45,114.78 U25.18
ADAP_IN_R: length 111.1
  TOP w0.076: U11.AY15 92.11,86.89 92.11,87.04 92.03,87.13 92.03,89.82 95.23,93.02 99.89,93.02 100.45,93.58
  TOP w0.102: v3(20.14,114.13) 20.14,114.34 R18.2 20.01,115.32 19.91,115.32 19.45,115.79 Q17.4 ; v3(100.58,93.71) 100.45,93.58
  L3_IN1 w0.102: v3(100.58,93.71) 99.05,95.23 97.03,95.23 78.22,114.04 53.99,114.04 49.54,118.49 48.25,118.49 47.91,118.83 45.71,118.83 45.66,118.78 36.1,118.78 35.63,118.31 35.14,118.31 33.6,116.78 32.88,116.78 32.24,116.14 28.31,116.14 27.19,117.25 v3(27.19,117.42) 27.07,117.53 26.09,117.53 23.93,115.37 21.39,115.37 v3(20.14,114.13)
  BOTTOM w0.102: v3(27.19,117.42) 27.25,117.47 R362.2
ADAPTOR_I: length 48.5
  TOP w0.102: R10.1 C6.1 10.97,127.97 v3(10.94,127.97) ; v3(6.4,104.07) 7.52,104.07 8,103.59 11,103.59 11.51,104.1 13.16,104.1 14.82,105.76 15.31,105.76 15.48,105.93 16.59,105.93 16.76,105.76 18.39,105.76 19.63,104.51 19.63,101.97 C21.2 18.76,99.93 R25.1
  L4_IN2 w0.102: v3(6.4,104.07) 6.88,104.55 6.88,111.29 6.75,111.42 6.75,113.95 6.88,114.07 6.93,114.13 6.93,118.42 8.18,119.66 8.18,122.52 9.6,123.94 10.43,123.94 11.17,124.68 11.17,127.74 v3(10.94,127.97)
ADR0: length 8.5
  TOP w0.076: 123.4,20.7 124.33,20.7 U1634.B2
  TOP w0.102: 123.4,20.7 v3(123.26,20.84)
  BOTTOM w0.102: v3(123.26,20.84) 121.99,22.11 R61.1 119,21.6 117.73,21.6 R58.2
ADR1: length 8.3
  TOP w0.076: 123.9,19.7 124.33,19.7 U1634.D2
  TOP w0.102: v3(122.08,19.49) 123.23,19.49 123.44,19.7 123.9,19.7
  BOTTOM w0.102: v3(122.08,19.49) 121.27,18.68 R64.1 119,18.17 117.73,18.17 R62.2
ALRTB_R: length 1.5
  TOP w0.102: U109.7 23.62,44.51 23.46,44.35 R647.2
AMP_MUTE#: length 229
  L3_IN1 w0.102: v3(128.85,97.29) 128.09,98.05 128.09,98.94 118.44,108.59 118.44,116.81 120.83,119.2 121.46,119.2 122.3,120.03 122.3,124.56 117.73,129.12 91.76,129.12 90.11,130.77 74.14,130.77 72.79,129.42 72.79,128.19 72.47,127.87 67.4,127.87 66.89,127.36 51.75,127.36 48.54,130.57 38.23,130.57 35.25,127.59 32.56,127.59 31.77,128.38 28.32,128.38 27.98,128.72 25.34,128.72 24.86,128.24 24.86,126.13 24.29,125.56 19.65,125.56 18.85,126.36 16.99,126.36 14.24,123.6 14.24,119.41 13.48,118.65 v3(13.48,118.04)
  BOTTOM w0.102: v1(126.82,98.18) 127.75,98.18 128.13,97.8 128.34,97.8 v3(128.85,97.29) 133.55,97.29 141.02,89.83 141.02,87.5 141.01,83.41 142.59,81.83 142.59,80.5 146.07,77.01 146.07,58.99 146.23,58.83 146.23,54.26 146.55,53.93 146.55,50.88 147.65,49.78 147.65,48.09 147.34,47.78 147.34,47.2 147.62,46.92 147.62,45.57 146.7,44.66 R541.1 ; U25.20 14.65,116.31 14.88,116.54 14.88,116.98 14.52,117.34 13.97,117.34 13.48,117.83 v3(13.48,118.04)
ANT1: length 16.5
  TOP w0.254: U1634.G7 127.07,17.78 v3(127.33,17.52)
  TOP w0.305: v3(125.04,10.17) 124.58,10.17 C508.1
  BOTTOM w0.305: v3(127.33,17.52) 127.43,17.42 130.03,17.42 130.98,16.47 130.98,12.27 130.26,11.54 126.89,11.54 125.52,10.17 v3(125.04,10.17)
ANT2: length 14.9
  TOP w0.254: U1634.G6 v3(126.57,17.29)
  TOP w0.305: C506.1 125.24,11.06 v3(125.17,11.06)
  BOTTOM w0.305: v3(126.57,17.29) 126.57,17.13 127.02,16.69 129.69,16.69 130.13,16.24 130.13,12.75 129.69,12.31 126.42,12.31 v3(125.17,11.06)
AP6234_UART_RXD: length 2.9
  TOP w0.102: WIFI1.9 v3(113.59,48.94)
  BOTTOM w0.102: R581.2 114.04,49.87 114.25,49.67 114.25,49.16 114.03,48.94 v3(113.59,48.94)
AP6234_UART_TXD: length 2.8
  TOP w0.102: WIFI1.10 114.86,49.22 114.88,49.2 v3(114.88,48.9)
  BOTTOM w0.102: R582.2 114.71,49.87 114.5,49.67 114.5,49.04 114.64,48.9 v3(114.88,48.9)
APU_LCDVDD_EN_G: length 7.8
  BOTTOM w0.102: C273.1 106.92,138.11 R331.2 107.54,138.11 R327.2 108.81,138.55 108.81,137.75 108.99,137.57 109.55,137.57 110.24,136.87 110.24,136.21 109.98,135.94 Q25.2
AUX_OFF: length 200.3
  TOP w0.102: R99.1 65.58,59.24 64.94,58.61 C107.2 64.51,58.55 Q6.C 63.29,58.56 61.51,58.56 v3(61.36,58.41)
  L3_IN1 w0.102: v3(61.36,58.41) 61.36,55.04 58.31,51.99 54.5,51.99 51.52,49.01 51.52,43.42 53.49,41.45 65.43,41.45 69.91,45.93 83.94,45.93 85.92,47.92 85.92,48.43 86.15,48.65 95.37,48.65 96.89,50.17 100.03,50.17 101.39,50.17 101.87,50.66 105.72,50.66 108.28,53.22 108.28,60.72 110.19,62.62 110.19,62.65 110.21,62.69 110.21,63.04 110.18,63.07 110.18,69.04 v3(110.01,69.22)
  L4_IN2 w0.102: v3(129.37,93.54) 128.86,94.05 128.86,96.38 130.15,97.67 130.15,98.04 130.15,99.39 131.12,100.37 131.12,109.9 129.31,111.72 129.31,114.48 v3(130.07,115.24) ; v3(110.01,69.22) 110.31,68.91 117.16,68.91 119.11,66.96 122.66,66.96 122.76,66.87 127.27,66.87 128.74,65.39 129.82,65.39 130.2,65.78 130.98,65.78 131.36,66.16 131.36,66.4 v3(131.54,66.58)
  BOTTOM w0.102: Q16.5 125.24,120.32 124.24,119.32 124.24,118.14 125.18,117.2 126.11,117.2 126.79,116.52 126.79,115.67 127.02,115.45 127.33,115.45 127.89,116.01 129.31,116.01 v3(130.07,115.24) ; v3(131.54,66.58) 131.49,66.63 130.83,66.63 130.58,66.88 130.58,66.92 130.45,67.05 130.45,68.1 134.16,71.81 134.16,72.84 136.8,75.49 137.28,75.97 137.28,78.57 137.87,79.16 137.87,79.54 135.86,81.54 135.86,83.8 135.07,84.59 135.07,90.39 132.91,92.55 132.91,92.97 132.35,93.54 v3(129.37,93.54)
BAT1C: length 4.7
  TOP w0.102: R27.2 C26.1 22.32,61.73 20.69,60.09 BAT1.6
BAT1D: length 5.2
  TOP w0.102: R23.2 C22.1 21.36,61.05 20.76,60.45 19.96,60.45 19.44,59.93 BAT1.7
BAT+: length 1.9
  TOP w0.508: v3(13.66,65.54) R509.2 R507.1
  vias: v4(13.18,74.35) v4(13.18,73.46) v4(13.18,72.57) v4(14.32,74.32) v4(14.32,73.49) v4(14.32,72.55) v4(22.02,57.16) v4(22.29,60.43) v4(23.31,60.43) v4(23.29,57.16) v4(24.42,60.46) v4(24.56,57.16) v4(25.8,57.14) v4(27.07,57.2)
BAT_D: length 1.2
  TOP w0.508: D4.2 131.84,111.25 R90.1
BAT_I: length 91.3
  TOP w0.102: v3(13.53,70.88) 13.46,70.88 13.2,71.13 12.18,71.13 C435.1 11.85,71.65 13.03,71.65 13.11,71.63 R485.1
  L4_IN2 w0.102: v3(12.43,129.03) 12.31,129.03 11.85,128.57 11.85,124.78 10.6,123.54 9.77,123.54 8.61,122.38 8.61,119.52 7.36,118.27 7.36,113.98 7.16,113.78 7.16,111.58 7.78,110.96 v3(7.78,110.25)
  BOTTOM w0.102: v3(12.43,129.03) 11.85,129.61 U25.70 ; v3(7.78,110.25) 8,110.46 13.69,110.46 14.15,110 16.3,110 16.45,110.15 17.64,110.15 18.84,111.35 21.9,111.35 22.21,111.04 22.21,101.07 22.98,100.3 22.98,95.7 23.31,95.36 23.31,92.55 23.23,92.47 23.23,84.46 24.24,83.45 24.24,81.9 23.62,81.28 23.62,78.62 21.92,76.92 20.84,76.92 18.52,74.6 17.77,74.6 16.56,73.39 16.56,72.16 15.44,71.05 15.44,70.75 15.06,70.37 14.63,70.37 13.97,71.03 13.69,71.03 v3(13.53,70.88)
BAT_SMBCLK: length 87.4
  TOP w0.102: R27.1 23.64,63.8 21.73,65.72 v3(21.1,65.72) ; v3(22.63,125.94) 22.6,125.92 22.6,125.86 R36.1 ; R14.1 13.89,100.52 v3(13.86,100.54)
  L4_IN2 w0.102: v3(13.86,100.54) 21.19,100.54 22.35,99.38 22.35,85.3 21.81,84.77 21.81,80.93 20.75,79.86 20.75,69.67 20.48,69.4 20.48,65.96 20.72,65.72 v3(21.1,65.72) ; v3(11.72,105.65) 11.33,106.05 11.33,111.54 10.94,111.93 10.94,118.34 12.44,119.84 12.44,121.4 15.69,124.64 16.93,124.64 17.67,125.39 22.29,125.39 22.63,125.72 v3(22.63,125.94)
  BOTTOM w0.102: v3(22.63,125.94) 22.63,124.7 23,124.32 U25.110 ; v3(13.86,100.54) 13.42,100.98 13.42,103.9 11.72,105.6 v3(11.72,105.65)
BAT_SMBDAT: length 89.6
  TOP w0.102: v3(22.04,125.94) 21.79,125.69 v1(21.79,124.85) 21.79,124.79 22.24,124.34 R37.1 ; R23.1 20.22,64.19 v3(21.11,65.08) ; R13.1 v3(12.74,100.46)
  L4_IN2 w0.102: v3(21.11,65.08) 21.07,65.08 20.28,65.87 20.28,69.49 20.55,69.75 20.55,79.95 21.61,81.01 21.61,84.85 22.14,85.38 22.14,91.12 21.24,92.02 21.24,94.22 22.14,95.12 22.14,98.72 20.7,100.16 13.05,100.16 v3(12.74,100.46) ; v3(22.04,125.94) 21.69,125.59 17.59,125.59 16.84,124.84 15.6,124.84 12.24,121.48 12.24,119.93 10.74,118.43 10.74,111.84 11.12,111.46 11.12,105.66 v3(11.68,105.09)
  BOTTOM w0.102: v3(12.74,100.46) 12.74,101.55 13.1,101.9 13.1,103.67 v3(11.68,105.09) ; v3(22.04,125.94) 22.04,124.59 22.71,123.92 U25.111
BAT_V: length 115.9
  TOP w0.102: v3(19.64,66.76) 18.97,66.76 18.18,65.96 15.96,65.96 R507.2
  L4_IN2 w0.102: v3(13.46,128.78) 13.81,128.43 13.81,127.27 12.25,125.71 12.25,124.59 10.8,123.13 9.94,123.13 9.01,122.21 9.01,119.35 7.77,118.1 7.77,113.81 7.57,113.61 7.57,111.75 8.48,110.84 8.48,109.86 7.49,108.87 7.49,104.04 5.66,102.22 5.66,98.75 4.4,97.48 4.4,93.27 4.52,93.15 4.52,83.5 5.6,82.43 5.6,77.16 4.96,76.52 4.96,69.48 v3(5.15,69.29)
  BOTTOM w0.102: v3(5.15,69.29) 5.15,69 8.45,65.69 8.45,58.18 9.33,57.31 16.31,57.31 17.09,58.1 18.58,58.1 21.97,61.48 21.97,63.38 21.32,64.03 20.93,64.03 20.47,64.49 20.47,64.61 19.26,65.82 19.26,66.38 v3(19.64,66.76) 19.64,69.22 v1(19.38,69.48) 18.73,70.13 R516.1 C473.1 20.27,71.7 Q36.D ; U25.73 13.05,129.2 v3(13.46,128.78)
BAT_V_ON#: length 20.3
  TOP w0.102: v3(19.67,66.12) 18.9,66.12 17.51,64.74 16.96,64.74 Q35.G 16.5,64.27 C469.1 R509.1 15.19,65.54 14.55,64.91 13.33,64.91 R510.1
  BOTTOM w0.102: Q36.G 23.94,72.77 Q37.D 21.07,69.09 20.45,68.47 20.45,66.89 v3(19.67,66.12)
BATT-: length 27.5
  TOP w0.508: v3(10.74,67.83) 11.3,67.27 11.3,66.76 R514.2 10.64,66.68 10.13,66.18 10.13,65.29 11.6,63.81 11.6,62.55 12.14,62.02 RCH1.2
  L4_IN2 w0.508: v3(10.74,67.83) 10.36,68.21 10.36,70.11 11.76,71.51 14.04,71.51 14.75,70.81 v3(14.8,70.81)
  BOTTOM w0.254: D19.1 D19.2 15.49,78.48 15.49,76.69 16.28,75.9 16.28,72.28 v3(14.8,70.81)
BATT_DUMP(ROM_PWR): length 14.5
  TOP w0.102: Q35.D 18.33,66.72 18.77,67.17 19.99,67.17 20.78,67.95 21.02,67.95 21.41,67.56 21.41,67.17 20.72,66.47 20.72,65.23 19.71,64.23 19.71,62.23 19.2,61.73 C18.1 19.07,61.26 18.19,60.38 BAT1.8
BATT_TEMP: length 100.4
  TOP w0.102: v3(9.86,55.17) 9.74,55.29 9.74,56.95 10.02,57.23 16.18,57.23 16.28,57.33 16.28,58.86 16.39,58.97 BAT1.9 16.94,60.61 17.93,61.6 C16.1 R21.2
  L4_IN2 w0.102: v3(12.42,129.62) 12.81,129.23 12.81,126.55 12.05,125.79 12.05,124.7 10.69,123.33 9.85,123.33 8.81,122.29 8.81,119.43 7.56,118.19 7.56,113.9 7.36,113.7 7.36,111.67 8.28,110.75 8.28,110.03 7.28,109.04 7.28,104.13 5.46,102.3 5.46,98.83 4.19,97.57 4.19,93.19 4.32,93.06 4.32,83.42 5.39,82.34 5.39,77.25 4.75,76.6 4.75,69.01 v3(4.28,68.54)
  BOTTOM w0.102: U25.71 12.25,129.86 12.42,129.69 v3(12.42,129.62) ; v3(4.28,68.54) 4.13,68.39 4.13,61.07 9.72,55.48 9.72,55.31 v3(9.86,55.17) 10.03,55 v1(10.87,55)
BATT_VA_OFF#: length 158.5
  L4_IN2 w0.102: v3(6.32,113.03) 6.34,113.06 6.34,113.83 6.73,114.21 6.73,118.5 7.97,119.75 7.97,122.6 8.94,123.57 8.94,129.27 10.28,130.62 14.23,130.62 14.58,130.97 19.7,130.97 20.05,130.62 20.87,130.62 21.08,130.41 25.12,130.41 26.8,128.74 32.47,128.74 32.8,128.4 33.22,128.4 33.68,127.94 37.83,127.94 38.34,127.43 44.39,127.43 46.45,129.5 68.86,129.5 69.82,130.46 72.49,130.46 73.21,131.18 88.71,131.18 89.44,130.46 94.41,130.46 95.87,128.99 114.75,128.99 115.51,128.23 118.26,128.23 122.56,123.93 126.66,123.93 128.23,122.36 128.64,122.36 128.93,122.08 v3(128.93,121.93)
  BOTTOM w0.102: v3(128.93,121.93) 128.93,122.48 129.31,122.86 130.2,122.86 130.76,122.31 R352.2 130.6,122.07 Q27.2 ; v3(6.32,113.03) 6.67,113.03 7.39,112.32 10.69,112.32 11.92,113.55 v1(12.14,113.55) 12.26,113.55 12.87,114.15 12.87,114.49 12.65,114.72 U25.25
BL_DETECT: length 228
  TOP w0.076: v3(93.94,73.69) 93.94,73.66 U11.R12
  L3_IN1 w0.102: v3(15.51,117.48) 14.79,118.2 14.79,118.82 15.05,119.07 15.05,123.26 16.22,124.44 17.01,124.44 17.36,124.78 18.99,124.78 19.24,124.53 24.78,124.53 25.37,125.13 28.51,125.13 28.93,125.55 33.27,125.55 34.29,126.58 35.72,126.58 38.69,129.55 48.12,129.55 51.32,126.35 67.32,126.35 67.8,126.83 72.91,126.83 73.95,127.86 91.41,127.86 91.99,127.29 118.11,127.29 118.44,126.96 118.44,125.43 118.38,125.37 118.38,124.62 119.22,123.78 119.22,123.05 119.6,122.67 119.6,120.82 119.98,120.44 119.98,119.82 117.43,117.26 117.43,106.01 121.86,101.57 123.03,101.57 125.42,99.18 125.42,94.45 130.29,89.59 130.29,83.48 133.93,79.84 133.93,79.74 v3(133.93,79.74)
  L4_IN2 w0.076: v3(93.94,73.69) 93.94,73.69 94.5,74.24 103.33,74.24 103.45,74.37 104,74.37 104.86,75.22 105.84,75.22
  L4_IN2 w0.102: 105.84,75.22 107.49,75.22 108.08,74.63 111.72,74.63 112.08,74.99 112.57,74.99 113.61,73.95 115.06,73.95 115.26,73.74 117.48,73.74 118.24,72.98 125.02,72.98 126.39,71.61 129.72,71.61 130.85,72.74 v3(131.18,72.74)
  BOTTOM w0.102: v3(15.51,117.48) 14.9,117.48 13.66,118.72 12.48,118.72 10.81,117.04 10.81,116.47 10.65,116.31 U25.30 ; v3(133.93,79.74) 134.01,79.66 134.08,79.66 134.41,79.33 134.41,78.64 134.14,78.36 134.14,75.94 132.02,73.83 132.02,73.55 131.25,72.78 131.22,72.78 v3(131.18,72.74)
BL_ON: length 12.7
  TOP w0.102: CN7.20 132.94,125.99 133.22,125.71 133.91,125.71 134.18,125.44 v3(134.18,125.28)
  BOTTOM w0.102: D6.A 134.21,121.26 R244.2 R239.2 133.55,122.2 C215.1 133.06,123.23 133,123.23 132.61,123.61 132.61,124.07 132.84,124.29 133.55,124.29 134.18,124.93 v3(134.18,125.28) 134.18,125.49 133.6,126.07 C284.1
BL_PWM: length 26.6
  TOP w0.102: CN7.21 133.44,127.63 132.28,128.79 129.49,128.79 128.72,128.03 v3(128.72,127.9)
  L4_IN2 w0.102: v3(128.72,127.9) 128.72,127.77 129.87,126.63 129.87,124.88 130.65,124.09 131.01,124.09 133.75,121.34 133.75,115.62 132.1,113.97 v3(132.1,113.85)
  BOTTOM w0.102: R268.2 R260.2 R250.2 132.08,113.87 v3(132.1,113.85)
BPM#0: length 5.2
  TOP w0.076: TP13.1 69.31,62.03 69.31,62.3 69.57,62.56 69.57,66.16 U11.C55
BPM#1: length 6.7
  TOP w0.076: U11.D55 69.66,66.66 69.95,66.37 69.95,66.13 69.73,65.91 69.73,62.49 69.48,62.23 69.48,61.56 TP14.1
BPM#2: length 6.5
  TOP w0.076: U11.B54 69.9,65.6 69.9,62.42 69.64,62.16 69.64,60.97 TP15.1
BPM#3: length 2.7
  TOP w0.076: U11.C56 68.72,66.2 68.72,65.54 68.66,65.42 68.66,65.05 68.74,64.97 68.74,64.62 68.4,64.27 v2(68.37,64.27)
BST: length 5
  TOP w0.102: v3(14.7,91.22) 14.78,91.3 14.78,91.44 14.77,91.45 U1.26
  BOTTOM w0.254: D18.C 14.52,89.92 13.89,90.56 13.89,91.83 C364.2 14.07,91.85 v3(14.7,91.22)
BST1: length 1.8
  TOP w0.254: v3(36.53,54.91) 36.53,54.72 36.33,54.53 U110.1
  TOP w0.508: 36.66,55.75 36.53,55.63 v3(36.53,54.91)
  vias: v3(37.11,54.91)
BST2: length 2.1
  TOP w0.254: U110.16 37.06,53.73 37.58,54.25
  TOP w0.508: 37.58,54.25 37.58,54.31 38.04,54.77 v3(38.31,54.77)
  vias: v3(39.14,54.77)
BSTA2: length 3.5
  TOP w0.203: 30.57,44.56 30.5,44.63 29.87,44.63 29.87,44.69 29.64,44.91 U109.25
  TOP w0.381: 30.78,44.56 30.57,44.56
  TOP w0.508: C3683.1 31.7,44.2 31.33,44.56 30.78,44.56
BT_HOST_WAKE: length 69.5
  TOP w0.102: v3(1.99,108.96) 2.65,108.31 2.65,104.82 2.91,104.55 4.45,104.55 6.18,102.83 9.26,102.83 9.38,102.95 13.1,102.95 14.53,104.38 14.53,105.18 14.9,105.56 15.48,105.56 15.65,105.72 16.51,105.72 16.73,105.5 17.56,105.5 R596.2
  L4_IN2 w0.102: v3(1.99,108.96) 2.62,108.96 3.49,109.83 3.49,130.32 6.78,133.61 8.2,133.61 9.69,135.1 10.41,135.1 10.87,134.65 20.47,134.65 v3(20.64,134.82)
  BOTTOM w0.102: U25.88 19.05,131.9 20.52,133.37 v1(20.52,133.87) 20.52,134.7 v3(20.64,134.82)
BT_ON: length 244.8
  TOP w0.102: v3(5.97,63.38) 6.18,63.38 R249.2
  L3_IN1 w0.102: v3(106.19,18.66) 106.07,18.78 98.06,18.78 92.56,24.29 30.83,24.29 25.82,29.3 25.82,33.16 22.13,36.85 14.79,36.85 7.92,43.72 7.92,58.33 5.53,60.72 5.53,63 5.91,63.38 v3(5.97,63.38) 6.04,63.46 6.04,65.8 6.17,65.93 6.17,67.06 5.6,67.64 v3(5.12,67.64)
  L4_IN2 w0.102: v3(16.65,129.95) 16.55,129.95 16.02,129.42 16.02,127.49 11.02,122.49 11.02,120.49 9.02,118.5 9.02,118.09 8.76,117.83 8.76,113.79 8.76,113.03 8.76,111.56 9.09,111.23 9.09,104.18 6.07,101.16 6.07,98.58 4.8,97.31 4.8,93.44 4.93,93.32 4.93,83.67 6,82.6 6,76.99 5.36,76.35 5.36,70.15 5.75,69.76 5.75,68.27 v3(5.12,67.64)
  BOTTOM w0.102: R3253.1 105.09,2.38 110.86,8.15 110.86,13.99 v3(106.19,18.66) ; R52.2 R54.1 16.65,133.17 U25.82 v3(16.65,129.95)
BT_WAKE: length 50.9
  TOP w0.102: R601.2 15.14,102.89 14.58,102.34 10.06,102.34 9.94,102.22 5.55,102.22 v3(4.47,103.3)
  L4_IN2 w0.102: v3(4.47,103.3) 3.69,104.08 3.69,125.31 6.63,128.24 6.63,130.14 10.24,133.76 11.01,133.76 11.37,133.4 12.03,133.4 v3(12.24,133.61)
  BOTTOM w0.102: v3(12.24,133.61) 12.39,133.46 v1(12.39,132.85) 11.45,131.91 U25.69
BTL_BEEP: length 228.5
  L3_IN1 w0.102: v3(13.26,117.51) 13.04,117.73 13.04,118.5 14.03,119.5 14.03,123.69 16.91,126.56 19.73,126.56 19.96,126.32 23.53,126.32 24.33,127.12 24.33,128.78 24.77,129.23 27.76,129.23 28.41,128.58 31.86,128.58 32.02,128.43 35.8,128.43 38.17,130.79 48.6,130.79 51.83,127.57 66.44,127.57 66.69,127.82 66.69,128.44 67.07,128.81 71.86,128.81 74.02,130.97 90.21,130.97 91.84,129.34 117.79,129.34 122.5,124.64 122.5,124.02 122.5,119.95 121.55,118.99 120.92,118.99 118.64,116.72 118.64,108.81 128.57,98.89 128.57,98.21 129.05,97.73 v3(129.26,97.73)
  BOTTOM w0.102: C486.2 152.06,47.25 151.73,47.58 148.36,47.58 147.93,48.01 147.93,49.79 146.82,50.9 146.82,54.17 146.45,54.54 146.45,59.24 146.37,59.32 146.37,77 142.79,80.58 142.79,81.92 141.22,83.49 141.22,87.41 141.22,90 133.49,97.73 v3(129.26,97.73) 129.17,97.73 128.83,98.07 128.58,98.07 v1(128.34,98.31) ; v3(13.26,117.51) 12.8,117.97 12.6,117.97 11.45,116.82 U25.28
CAP+: length 3.9
  BOTTOM w0.203: C546.1 147.53,29.94 147.53,30.68 148.01,31.16 148.78,31.16 149.66,32.04 U33.36
CAP-: length 4.7
  BOTTOM w0.203: C546.2 148.05,29.6 148.05,30.38 148.46,30.79 148.87,30.79 150.06,31.99 U33.35
CARD_3V3: length 42.8
  TOP w0.508: 139.57,35.64 139.6,35.67 v3(141.98,35.67) ; 139.57,35.64 139.57,36.83 139.94,37.2 CRDR1.6 141.69,37.2 v3(142.42,36.48) ; 139.57,35.64 C242.2
  L4_IN2 w0.381: v3(143.88,50.77) 144.49,50.77 145.29,49.96 146.48,49.96 147.32,49.12 147.75,49.12 148.74,48.13 148.74,45.79 148.75,45.71 148.78,45.64 148.83,45.57 148.83,45.36 146.09,42.62 146.09,39.24 144.22,37.37 143.3,37.37 v3(142.42,36.48)
  BOTTOM w0.381: v3(143.88,50.77) 143.56,50.45 143.56,49.12 143.78,48.9 143.78,44.33 R550.1
  BOTTOM w0.508: v3(141.98,35.67) 142.01,35.67 142.39,35.29 C524.1 C527.1 142.51,33.82 Q40.D 143.3,32.52 142.23,32.52 R595.2 ; R55.2 143.91,50.8 v3(143.88,50.77)
CHG_LX: length 1.5
  TOP w0.203: U1.27 15.17,92.93 U1.41
  vias: v3(15,93.71) v3(15,93.07) v3(15.54,93.68) v3(15.56,93.1) v3(16.12,93.68) v3(16.09,93.1) v3(18.22,88.14) v3(18.51,87.66) v3(18.56,88.58) v3(19.12,88.98) v3(19.06,88.33) v3(19.06,87.7)
CHG_R_LED: length 5
  BOTTOM w0.102: R325.2 114.96,133.68 C272.1 R334.2 116.97,132.41 LED1.1
CHG_REF: length 85.5
  TOP w0.102: R494.2 C461.1 19.52,72.35 19.52,72.6 18.66,73.46 v3(17.36,73.46)
  L4_IN2 w0.102: v3(9.72,110.88) 8.96,111.64 8.96,112.63 8.96,112.94 8.96,112.94 8.96,113.39 8.96,113.71 8.96,113.71 8.96,117.75 9.23,118.01 9.23,118.41 11.22,120.41 11.22,122.41 16.44,127.62 v3(16.44,129.3)
  BOTTOM w0.102: v3(16.44,129.3) 16.25,129.49 U25.81 ; v3(9.72,110.88) 13.78,110.88 14.39,110.27 16.28,110.27 16.41,110.39 17.6,110.39 18.76,111.55 21.98,111.55 22.41,111.13 22.41,101.15 23.3,100.26 23.3,95.91 23.52,95.7 23.52,92.47 23.44,92.39 23.44,84.69 24.44,83.69 24.44,81.82 23.82,81.19 23.82,78.54 22,76.72 20.93,76.72 17.67,73.46 v3(17.36,73.46)
CLICK_CLK: length 115.7
  TOP w0.102: R594.1 103.9,12.6 v3(103.9,16.94) ; TP3.1 8.87,41.75 v3(7.95,41.75) CN4.4
  L3_IN1 w0.102: v3(103.9,16.94) 103.48,17.36 96.77,17.36 91.13,23 30.54,23 24.63,28.9 24.63,29.51 24.64,32.76 21.66,35.73 14.01,35.73 7.99,41.75 v3(7.95,41.75)
CLICK_DATA: length 114.6
  TOP w0.102: v3(103.21,16.89) 103.59,16.51 103.59,12.55 R590.1 ; TP2.1 8.69,40.75 v3(8.07,40.75) CN4.5
  L3_IN1 w0.102: v3(103.21,16.89) 103.15,16.95 96.29,16.95 90.55,22.69 30.41,22.69 24.33,28.78 24.33,29.63 24.33,32.63 21.54,35.43 13.42,35.43 8.1,40.75 v3(8.07,40.75)
CLK_EC_LPC: length 196.6
  TOP w0.102: R161.2 108.93,89.44 109.29,89.8 v3(109.52,89.8)
  L4_IN2 w0.102: v3(109.52,89.8) 109.39,89.8 108.55,90.63 108.55,93.68 108.68,93.81 108.68,97.93 109.21,98.46 109.21,100.89 109.95,101.63 109.95,104.08 112.62,106.75 112.62,110.14 114.51,112.04 114.51,119.12 115.39,120 115.39,122.18 111.49,126.07 95.48,126.07 94.24,127.31 71.84,127.31 71.29,126.77 69.53,126.77 69.26,126.5 48.54,126.5 47.8,125.76 46.02,125.76 45.45,125.19 45.45,124.24 44.4,123.2 35.35,123.2 33.78,121.62 24.07,121.62 22.24,119.79 21.28,119.79 20.59,120.48 18.62,120.48 v3(18.16,120.02) 18.1,120.08 16.67,120.08 16.27,119.67 16.27,116.71 14.3,114.75 14.3,113.41 14.7,113.01 14.7,109.53 15.4,108.83 15.4,106.36 15.3,106.26 15.3,103.93 12.93,101.56 11.1,101.56 9.27,99.73 9.27,98.15 8.22,97.1 8.22,94.29 14.13,88.38 16.26,88.38 18.56,86.07 18.56,84.39 19.4,83.56 v3(19.9,83.56)
  BOTTOM w0.102: CN8.6 19.36,83.01 v3(19.9,83.56) ; v3(18.16,120.02) 18.16,119.91 17.16,118.91 17.16,117.79 17.45,117.51 U25.13
CLK_EC_LPC_R: length 2.6
  BOTTOM w0.102: R382.1 C343.2 18.62,105.92 U28.21
CLK_EC_LPC_SOC: length 16.4
  TOP w0.076: U11.AW9 96.11,86.05 95.93,86.23 95.93,86.23 95.71,86.93 95.71,87.01 95.66,87.17 95.66,87.31 95.72,87.53 95.72,87.65 95.69,87.73 95.67,87.76 95.67,88.14 95.89,88.35 95.89,89.55 96.09,89.76 101.25,89.76 101.27,89.74 102.02,89.74 102.03,89.73 102.58,89.73 102.59,89.74 103.9,89.74 104.13,89.5 106.6,89.5
  TOP w0.102: 106.6,89.5 107.19,89.5 107.66,89.03 R161.1
CLK_LAN_REQ3#: length 24.9
  TOP w0.076: U11.AT10 95.43,84.14 95.14,84.43 v2(95.14,84.46)
  L4_IN2 w0.076: 106.6,86.88 105.88,86.16 104.92,86.16 104.71,86.37 104.71,86.85 104.04,87.52 102.44,87.52 102.42,87.54 102.05,87.54 101.72,87.21 100.71,87.21 100,86.5 97.28,86.5 96.94,86.16 96.51,86.16 95.66,85.31 95.66,85.02 95.14,84.5 v2(95.14,84.46)
  L4_IN2 w0.102: v3(109.57,89.24) 109.42,89.09 109.42,87.51 108.99,87.08 106.8,87.08 106.6,86.88
  BOTTOM w0.102: R421.2 113.2,91.77 111.61,90.18 110.51,90.18 v3(109.57,89.24)
CLK_PCIE_LAN_DN3: length 91.5
  TOP w0.076: v2(77.9,67.62) 77.9,67.46 U11.D40
  TOP w0.114: v2(115.36,7.51) 115.22,7.37 115.22,7.31 115.03,7.13 115.03,6.79 SBCN2.11
  L4_IN2 w0.114: v2(115.36,7.51) 115.22,7.66 115.22,7.69 115.13,7.78 115.13,8.44 113.83,9.75 113.83,28.81 107.35,35.29 107.35,50.2 103.7,53.86 89.92,53.86 88.84,54.94 88.39,54.94 88.38,54.94 83.32,54.94 83.09,55.17 83.09,55.7 83.38,56 v2(83.38,56.02)
  BOTTOM w0.076: v2(77.9,67.62) 77.9,67.44 78.03,67.33 78.82,67.33 80.29,65.87 80.44,65.87
  BOTTOM w0.114: 80.44,65.87 82.15,65.87 84.7,63.31 84.7,58.1 83.26,56.65 83.26,56.14 v2(83.38,56.02)
CLK_PCIE_LAN_DP3: length 91.4
  TOP w0.076: v2(77.97,66.81) 77.84,66.95 77.52,66.95 77.47,66.89 77.47,66.77 U11.C40
  TOP w0.114: v2(114.75,7.5) 114.75,7.5 114.78,7.48 114.78,6.79 SBCN2.10
  L4_IN2 w0.114: v2(114.75,7.5) 114.88,7.63 114.88,8.39 113.61,9.66 113.61,28.72 107.13,35.2 107.13,50.11 103.61,53.64 89.83,53.64 88.75,54.73 88.3,54.73 88.29,54.73 83.23,54.73 82.88,55.08 82.88,55.89 v2(82.75,56.02)
  BOTTOM w0.076: 80.44,65.61 80.43,65.61 80.41,65.63 80.4,65.63 80.4,65.65 80.2,65.65 78.73,67.11 78,67.11 77.87,66.99 77.87,66.91 v2(77.97,66.81)
  BOTTOM w0.114: v2(82.75,56.02) 82.88,56.14 82.88,56.63 84.45,58.2 84.45,63.21 82.04,65.61 80.44,65.61
CLK_PCIE_SSD_DN: length 114.7
  TOP w0.076: U11.E40 v2(78.52,67.7)
  TOP w0.114: CN13.53 15.62,27.93 15.74,28.06 16.54,28.06 v2(16.84,27.76)
  BOTTOM w0.102: v2(16.84,27.76) 16.84,27.79 16.63,28 16.39,28 16.15,28.24 16.15,28.87 16.61,29.33 18.11,29.33 19.86,27.59 76.93,27.59 81.27,31.93 81.27,46.92 85.42,51.06 85.42,53.39 84.12,54.68 84.12,56.93 85.13,57.94 85.13,63.42 82.44,66.1 80.45,66.1 80.38,66.18 80.34,66.18 78.94,67.57 78.65,67.57 v2(78.52,67.7)
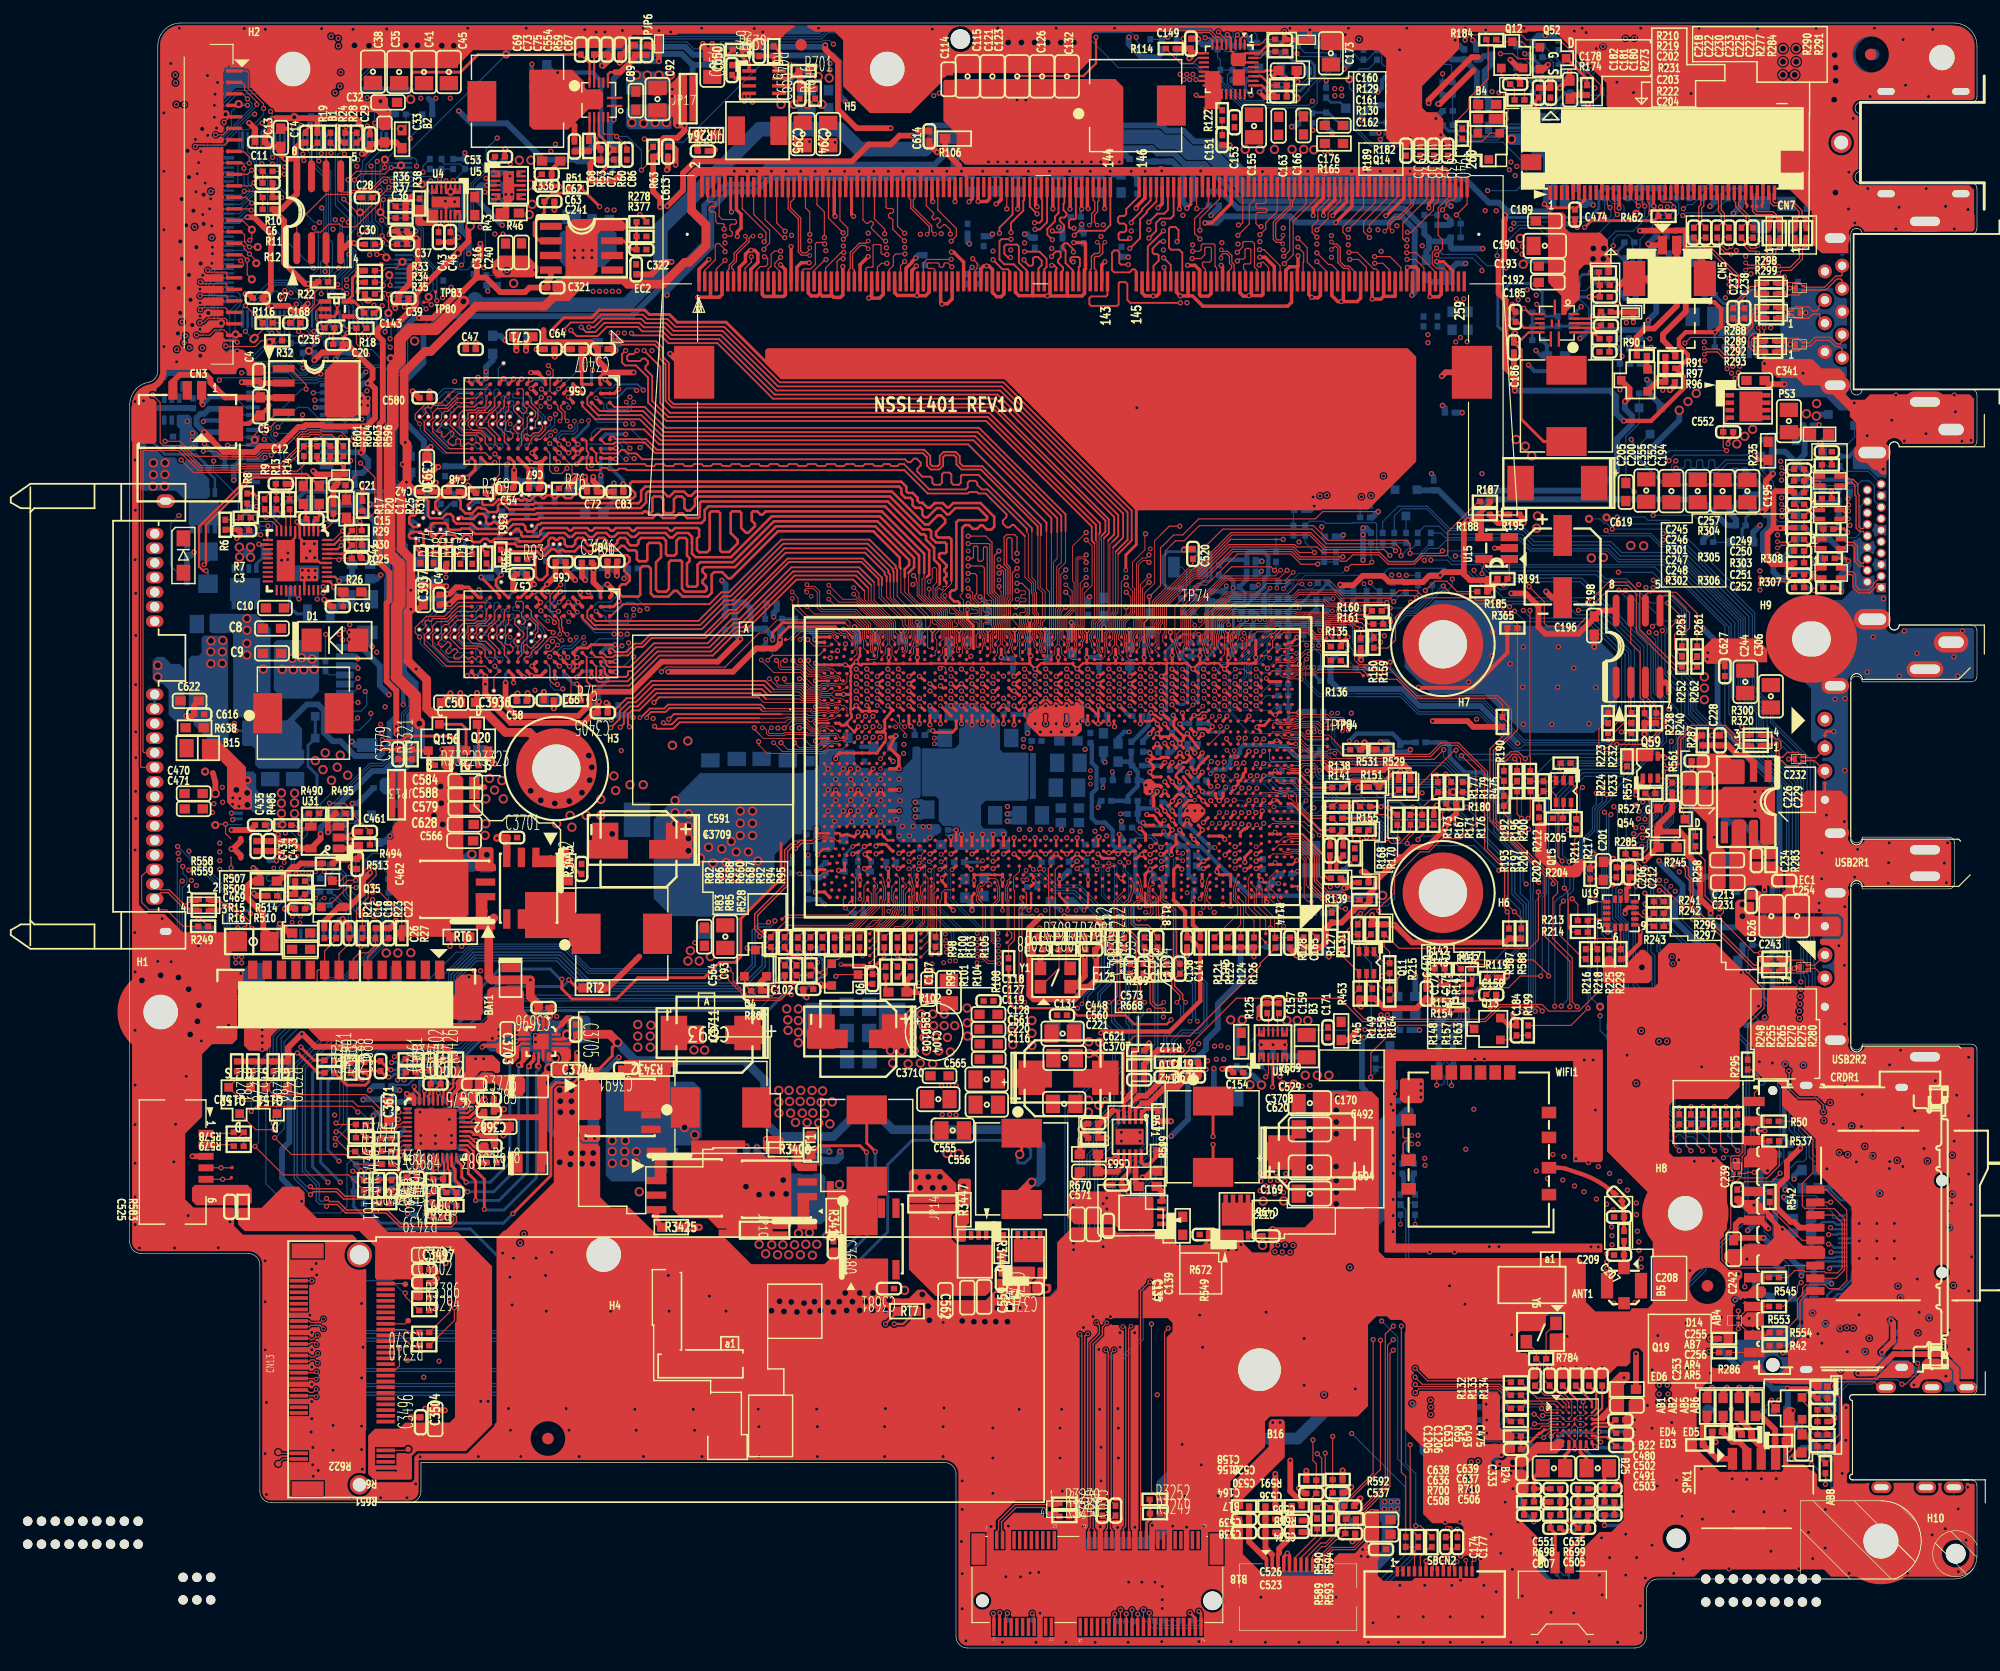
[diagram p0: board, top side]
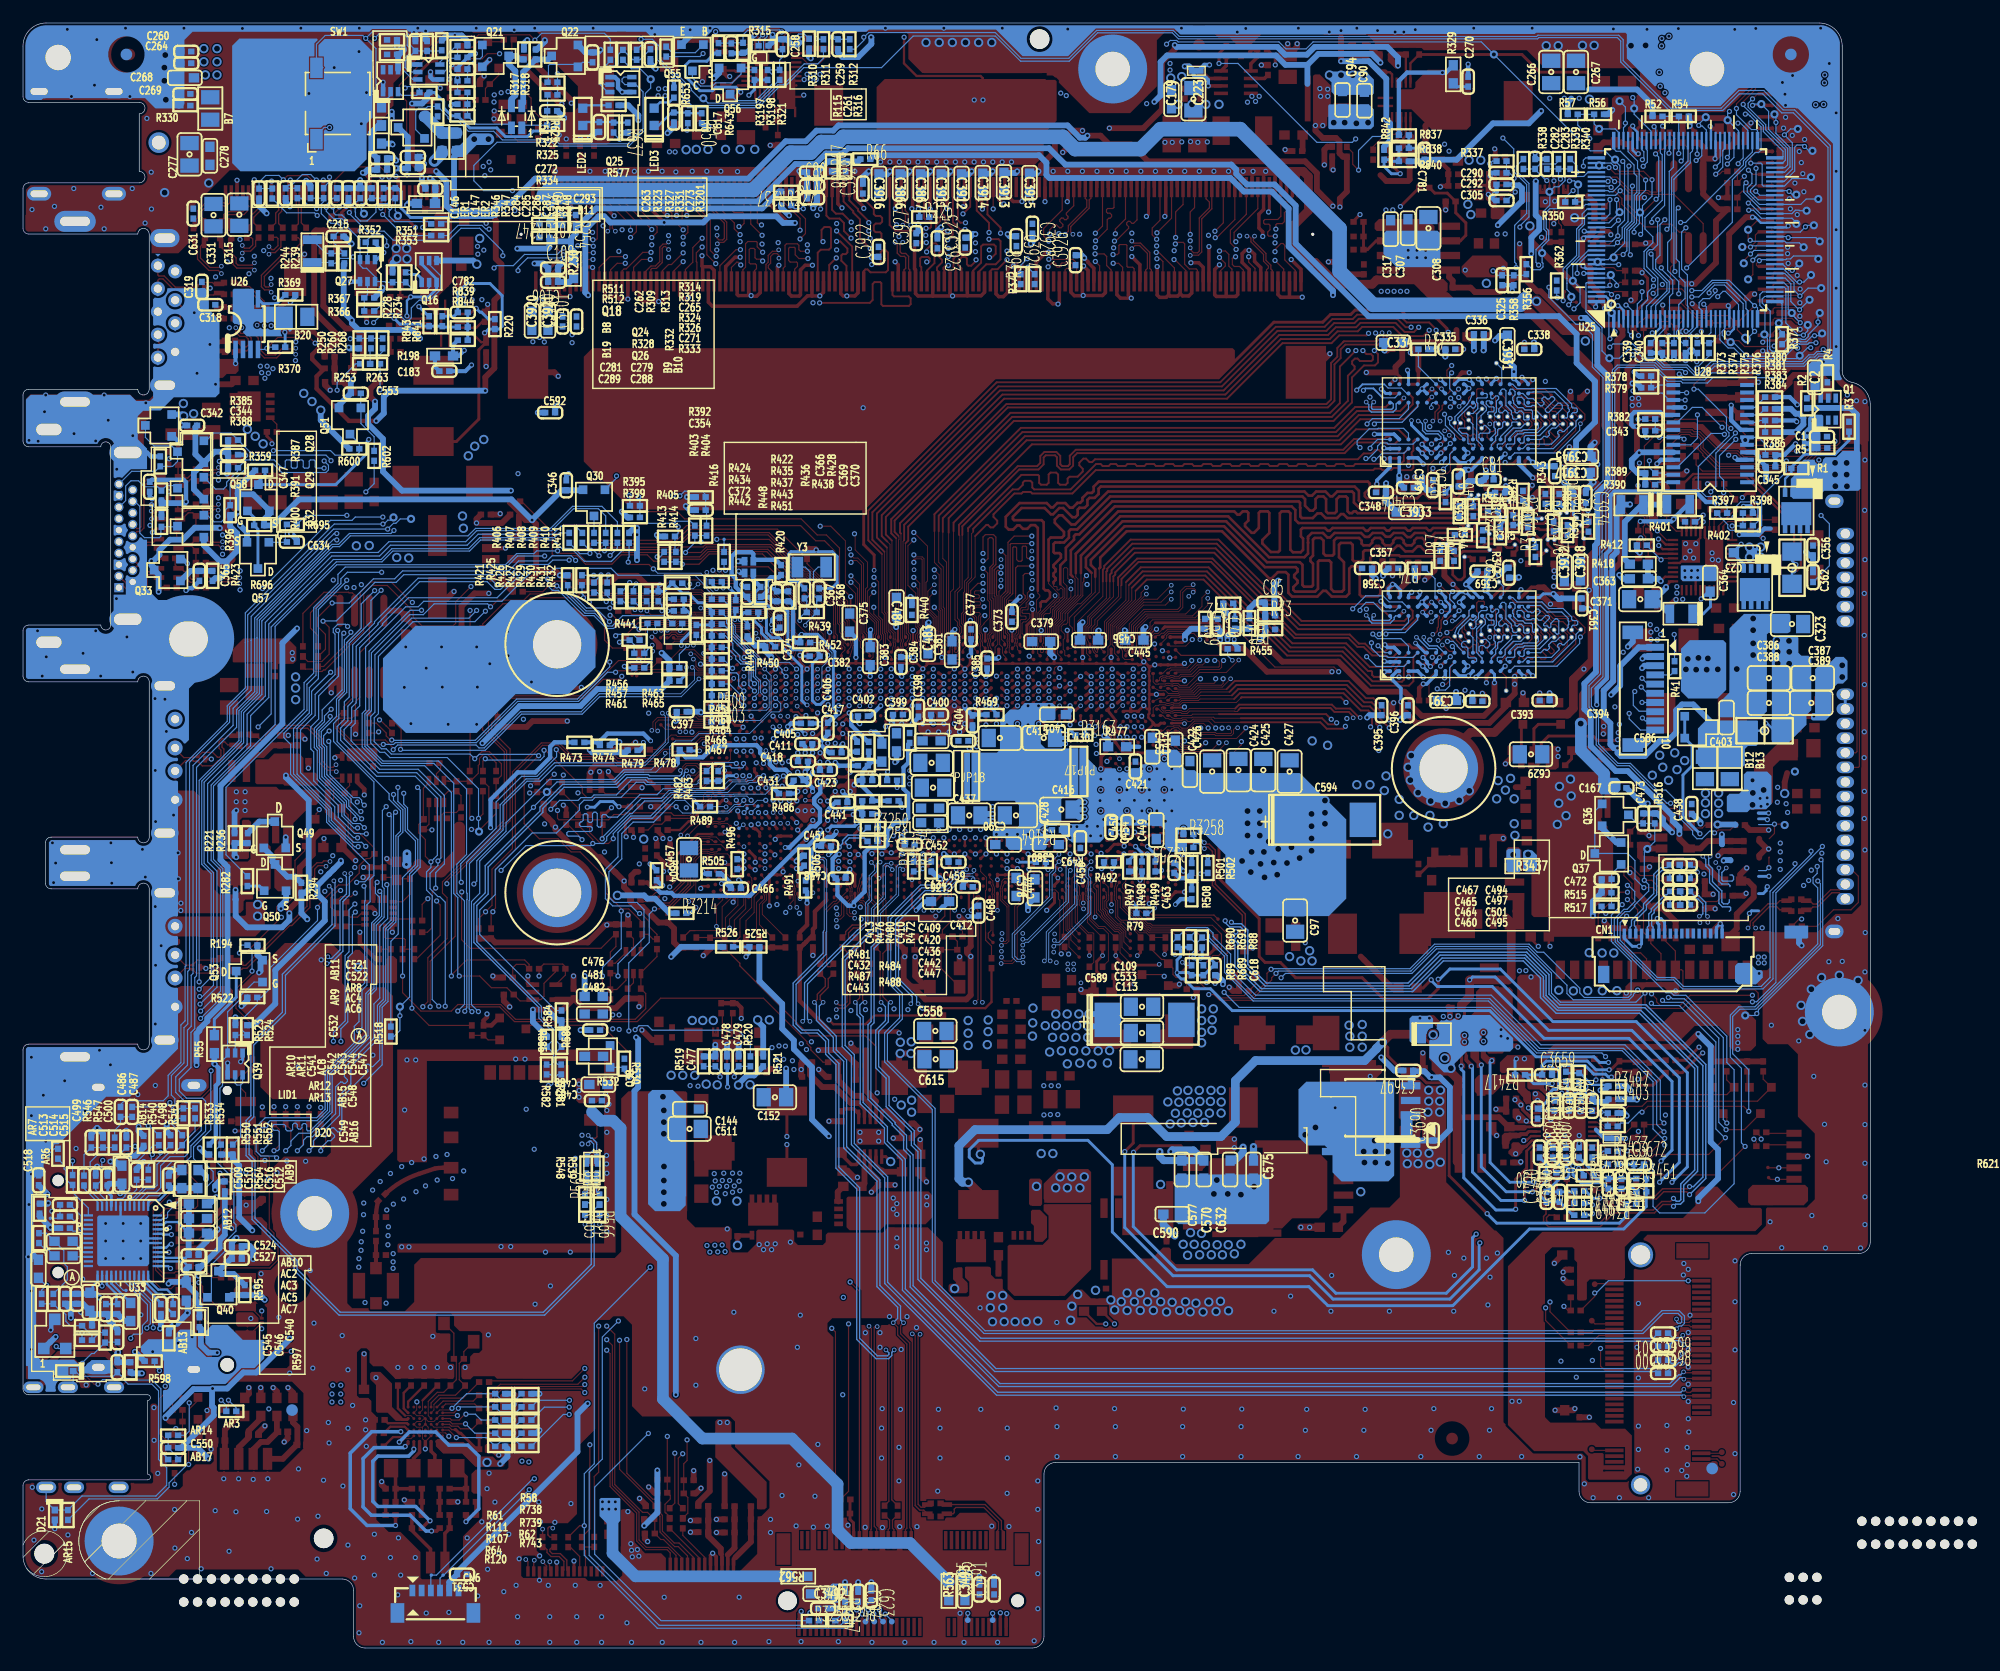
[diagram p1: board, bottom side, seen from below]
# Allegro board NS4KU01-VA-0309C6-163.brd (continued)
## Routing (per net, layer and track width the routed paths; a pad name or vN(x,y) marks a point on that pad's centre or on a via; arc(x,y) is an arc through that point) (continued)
CLK_PCIE_SSD_DP: length 114.7
  TOP w0.076: U11.E38 79.08,68 78.89,67.81 78.89,67.68 78.95,67.61 79.37,67.61 v2(79.45,67.69)
  TOP w0.114: CN13.55 15.62,28.43 15.74,28.31 16.54,28.31 v2(16.84,28.61)
  BOTTOM w0.102: v2(79.45,67.69) 79.4,67.64 79.4,67.5 80.55,66.34 82.54,66.34 85.3,63.59 85.37,63.52 85.37,57.84 84.36,56.83 84.36,54.79 85.66,53.49 85.66,50.96 81.51,46.82 81.51,31.83 77.03,27.35 19.76,27.35 18.01,29.09 16.71,29.09 16.39,28.77 16.39,28.34 16.49,28.24 16.72,28.24 16.84,28.36 v2(16.84,28.61)
CLK_PCIE_WLAN_DN: length 67
  TOP w0.102: v2(77.8,56.14) 77.54,56.4 77.54,64.14 77.92,64.53 77.92,65.66 U11.B40
  TOP w0.114: v2(87.02,27.98) 86.81,27.78 86.81,10.33 86.85,10.3 CN14.49
  L4_IN2 w0.114: v2(77.8,56.14) 77.8,56.12 77.54,55.87 77.54,55.64 77.73,55.45 81.7,55.45 82.83,54.31 85.93,54.31 89.04,51.2 89.04,36.35 86.81,34.12 86.81,28.19 v2(87.02,27.98)
CLK_PCIE_WLAN_DP: length 67
  TOP w0.102: U11.A40 77.53,65.4 77.44,65.4 77.36,65.33 77.36,65.14 77.65,64.85 77.65,64.6 77.29,64.23 77.29,56.27 v2(77.16,56.14)
  TOP w0.114: CN14.47 86.35,10.38 86.56,10.59 86.56,27.88 86.49,27.95 v2(86.31,27.95)
  L4_IN2 w0.114: v2(86.31,27.95) 86.37,27.95 86.6,28.18 86.6,34.21 88.82,36.44 88.82,51.11 85.84,54.09 82.74,54.09 81.61,55.23 77.55,55.23 77.32,55.46 77.32,55.99 77.17,56.14 v2(77.16,56.14)
CLK_REQ: length 4.1
  TOP w0.102: U1634.A2 124.55,20.95 124.02,21.47 121.41,21.47 R741.2
CLK_TPM: length 181.4
  TOP w0.102: v3(12.12,106.05) 12.74,106.68 14.93,106.68 15.1,106.84 16.97,106.84 17.07,106.73 20.07,106.73 v3(20.17,106.84) ; R159.2 108.15,86.95 109.32,86.95 110,87.64 110,89.62 v3(111.32,90.94)
  L4_IN2 w0.102: v3(111.32,90.94) 111.32,92.2 113.51,94.39 113.51,105.91 117.37,109.77 117.37,118.91 119.22,120.76 119.22,123.96 118.38,124.8 118.38,125.37 116.67,127.08 115.06,127.08 114.85,127.29 95.99,127.29 93.99,129.3 89.02,129.3 88.25,130.07 73.67,130.07 72.9,129.3 71.26,129.3 69.95,127.99 69.02,127.99 68.76,127.72 48.03,127.72 47.85,127.54 46.07,127.54 44.85,126.32 36,126.32 35.69,126.63 33.96,126.63 32.89,125.56 29.46,125.56 28.83,126.2 27.12,126.2 26.49,125.56 23.48,125.56 23.2,125.28 23.19,125.28 23.14,125.23 22.98,125.08 17.8,125.08 17.05,124.34 15.81,124.34 12.75,121.27 12.75,119.71 11.25,118.22 11.25,112.21 11.63,111.83 11.63,106.53 v3(12.12,106.05)
  BOTTOM w0.102: R382.2 19.58,106.84 v3(20.17,106.84)
CLK_TPM_SOC: length 15.6
  TOP w0.076: U11.AY9 96.11,86.76 96,86.87 95.9,86.98 95.83,87.19 95.83,87.31 95.89,87.54 95.89,87.68 95.84,87.8 95.84,88.07 96.05,88.29 96.05,88.67 96.46,89.07 97.22,89.07 97.22,89.08 97.56,89.08 97.57,89.07 97.85,89.07 97.85,89.08 98.07,89.08 98.07,89.07 98.82,89.07 99.31,89.57 101.96,89.57 101.96,89.57 102.65,89.57 102.66,89.57 103.83,89.57 104.07,89.34 106.37,89.34 106.54,89.16 106.6,89.16
  TOP w0.102: 106.6,89.16 107.06,89.16 108.12,88.1 R159.1
CODEC_BITCLK: length 3.7
  BOTTOM w0.102: R564.2 C510.2 150.67,39.86 151.66,38.86 U33.6
CODEC_DIN: length 7.5
  BOTTOM w0.102: U33.8 152.46,38.93 152.32,39.07 151.89,39.07 151.68,39.27 151.68,39.36 151.27,39.78 151.27,41.85 150.72,42.4 150.52,42.4 149.19,43.72 R540.2
CODEC_GND: length 91.4
  TOP w0.381: v3(144.06,22.56) 145.74,22.56 146.58,21.72 C255.1 ; C256.2 147.85,19.69 v3(148.15,20)
  TOP w0.508: C253.2 144.95,17 v3(144.42,16.47) ; v3(152.27,25.71) 153.26,26.7 153.26,28.28 v3(153.08,28.46) ; AB4.2 v3(137.36,26.9)
  L4_IN2 w0.508: v3(144.06,22.56) 144.49,22.99 146.4,22.99 147.58,24.17 147.58,24.91 148.63,25.96 v3(148.63,27.78) ; v3(151.48,42.8) 151.46,42.78 151.46,41.84 152.45,40.85 152.63,40.85 156.91,36.57 v3(158.15,36.57) 156.38,34.8 v3(156.38,28.71)
  BOTTOM w0.203: v3(153.67,31.47) 153.67,32.4 U33.26 ; U33.37 148.86,33.21 147.93,33.21 v3(147.72,33)
  BOTTOM w0.508: C545.1 148.56,27.85 v3(148.63,27.78) ; v3(145.29,32.36) 145.29,32.54 145.28,32.55 AC7.2 145.08,33.15 143.46,34.78 143.46,35.46 143,35.92 AB12.2 ; v3(148.15,20) 148.15,20.09 145.73,22.51 144.11,22.51 ; C540.1 146.22,30.08 146.22,29.17 v3(146.25,29.14) 146.25,29.09 147.14,28.2 v3(147.36,28.2) 147.87,27.69 AB13.2 ; AR12.2 154.55,28.03 154.55,29.14 ; 154.55,29.14 154.45,29.04 C543.2 ; 154.55,29.14 C542.2 155.34,29.93 AC8.2 C541.2 156.38,29.42 v3(156.38,28.71) ; 146.78,17.41 145.36,17.41 v3(144.42,16.47) ; 146.78,17.41 143.96,20.22 143.96,20.89 144.11,21.04 144.11,22.51 ; 146.78,17.41 C550.2 ; AB14.2 150.06,43.51 150.77,42.8 v3(151.48,42.8) ; AR8.2 158.09,36.51 v3(158.15,36.57) 159.1,37.52 AB11.2 ; 144.11,22.51 v3(144.06,22.56) 142.79,22.56 141.4,23.96 140.25,23.96 137.36,26.85 v3(137.36,26.9) ; C543.2 153.08,28.79 v3(153.08,28.46) 152.32,27.7 C548.1 ; C543.2 C544.2 151.71,28.43 C547.2 ; v3(152.27,25.71) 152.34,25.64 C549.1 AB16.1
CODEC_PCBEEP: length 2.3
  BOTTOM w0.102: C513.2 155.24,39.96 154.06,38.79 U33.12
COMP_OZ8690: length 2.5
  TOP w0.102: U1.9 13.17,97.57 R9.2
CORE_VID0: length 0.6
  TOP w0.076: U11.AN11 94.65,82.19 v2(94.28,82.56)
CORE_VID1: length 0.6
  TOP w0.076: v2(93.36,82.58) 93.37,82.58 U11.AN13
CPPE#: length 9.2
  TOP w0.102: R32.1 11.43,113.67 10.92,113.17 8.4,113.17 v3(8.35,113.21)
  BOTTOM w0.102: v3(8.35,113.21) 8.2,113.36 8.2,113.69 R371.1 7.66,114.41 7.95,114.69 v1(7.95,115.2) 7.66,115.48 7.66,116.87 7.87,117.08 U25.33
CPU_PROCHOT#: length 4.2
  TOP w0.102: U109.9 23.74,43.71 23.2,43.17 23.2,42.85 22.75,42.4 R3160.2 22.89,42.06 v3(23.43,41.53)
  BOTTOM w0.102: v3(23.43,41.53) 23.43,41.61 22.97,42.06 R3527.1
CSNA: length 18.1
  TOP w0.254: R3422.2 18.87,48.95 20.47,48.95 20.79,49.26 20.79,49.72 C3685.1 20.47,50.16 C3688.1 22.32,49.64 v3(22.5,49.64)
  BOTTOM w0.254: v3(22.5,49.64) 22.75,49.64 23.01,49.9 24.02,49.9 24.77,50.65 26.83,50.65 27.07,50.41 27.07,48.82 27.33,48.56 27.58,48.56 28.03,48.12 28.03,47.61 28.72,46.91 28.91,46.91 C3658.1 28.75,46.74 R3409.2
CSNA_GT: length 1.6
  TOP w0.203: v3(26.82,48.25) 26.82,48.25 26.78,48.21 U109.35
  BOTTOM w0.254: v3(26.82,48.25) 26.82,48.23 R3409.1
CSNB: length 7.4
  BOTTOM w0.254: R3446.1 25.85,37.64 C3706.1 C3720.1 28.66,39.31 28.66,40.09 28.14,40.61 R3430.2 28.14,42.05 C3692.2
CSNB_VCORE: length 2.2
  TOP w0.254: v3(26.65,41.42) 26.47,41.42 26.33,41.56 26.33,42.24 26.38,42.28 U109.15
  BOTTOM w0.254: R3430.1 27.18,41.42 v3(26.65,41.42)
CSNC: length 5.9
  BOTTOM w0.254: C3686.1 24.1,41.44 24.1,41.13 R3428.2 23.77,40.81 C3721.1 C3715.1 20.35,40.81 R3451.1
CSNC_SA: length 1.9
  TOP w0.254: U109.13 25.58,42.29 25.31,42.02 25.31,41.72 25.33,41.69 v3(25.34,41.69)
  BOTTOM w0.254: R3428.1 24.9,41.26 v3(25.34,41.69)
CSPA: length 18.4
  TOP w0.203: v3(27.64,49.07) 27.64,48.76 27.26,48.38 27.26,47.99 27.18,47.91 U109.34
  TOP w0.254: R3421.2 19,51.1 R3431.2 19.26,50.96 C3685.2 20.47,51.03 C3688.2 22.55,50.28 v3(22.69,50.28)
  BOTTOM w0.254: v3(22.69,50.28) 23.83,50.28 24.58,51.03 28.16,51.03 28.52,50.67 C3659.1 R3417.1 29.24,49.07 v3(27.64,49.07)
CSPB: length 9.3
  TOP w0.254: U109.16 26.78,42.18 26.83,42.13 v3(26.83,41.98)
  BOTTOM w0.254: R3444.1 R3445.2 25.8,39.66 C3706.2 C3720.2 27,40.82 26.42,40.82 26.19,41.04 26.19,41.61 26.56,41.98 v3(26.83,41.98) 27.03,41.98 27.59,42.54 C3693.2
CSPC: length 9.8
  TOP w0.254: U109.14 25.98,42.04 v3(25.85,41.92)
  BOTTOM w0.254: C3687.1 26.45,42.52 v3(25.85,41.92) 25.83,41.9 25.83,41.15 25.14,40.45 23.28,40.45 C3721.2 C3715.2 20.6,39.94 R3450.2 20.35,39.65 R3449.1
D+_M: length 5
  TOP w0.114: v2(111.42,43.82) 111.17,44.08 110.92,44.08 110.66,43.82 110.66,42.71 110.95,42.42 WIFI1.6
  BOTTOM w0.114: v2(111.42,43.82) 111.42,43.98 111.32,44.08 111.2,44.08 110.94,43.82 110.94,43.32 111.5,42.76 L25.4
D-_M: length 5
  TOP w0.114: v2(111.42,44.57) 111.18,44.33 110.78,44.33 110.66,44.46 110.66,45.44 WIFI1.7
  BOTTOM w0.114: v2(111.42,44.57) 111.19,44.33 111.07,44.33 110.69,43.95 110.69,43.21 110.7,43.2 L25.1
DC_IN: length 192.7
  TOP w0.203: R20.2 16.43,101.05 15.4,102.08 10.61,102.08 6.02,97.49 6.02,94.04 6.39,93.67 v3(6.63,93.67)
  L4_IN2 w0.102: v3(129.31,116.89) 128.93,117.28 128.93,119.05 129.56,119.69 129.56,122.11 129.1,122.56 128.31,122.56 126.74,124.13 122.66,124.13 118.36,128.44 115.62,128.44 114.87,129.19 95.96,129.19 94.49,130.66 89.52,130.66 88.8,131.39 73.13,131.39 72.4,130.66 69.74,130.66 68.78,129.7 46.25,129.7 44.18,127.64 41.39,127.64 41.38,127.64 38.42,127.64 37.92,128.15 33.77,128.15 33.31,128.61 32.89,128.61 32.56,128.94 28.18,128.94 26.5,130.62 21.2,130.62 20.65,131.17 14.5,131.17 14.15,130.82 10.2,130.82 8.73,129.36 8.73,123.65 7.77,122.69 7.77,119.83 6.52,118.58 6.52,114.29 5.91,113.68 5.91,103.33 5.05,102.47 5.05,99.25 v3(4.28,98.48)
  BOTTOM w0.102: v3(129.31,116.89) 129.94,116.26 R366.1 ; v3(4.28,98.48) 3.56,97.76 3.56,94.11 C362.2
  BOTTOM w0.203: R419.2 6.8,93.5 v3(6.63,93.67)
DC_IN+: length 8.2
  BOTTOM w0.508: 1.17,103.62 1.17,107.19 1.18,107.27 1.74,107.83 5.48,107.83 R2.1
  vias: v3(3.96,136.79) v3(3.98,136.1) v3(4.06,134.22) v3(4.74,134.2) v3(17.5,140.15) v3(17.85,135.24) v3(18.12,139.95) v3(18.14,139.31) v3(18.33,137.02) v3(18.26,135.8) v4(2.03,101.02) v4(2.05,103.05) v4(2.05,102.03) v4(3.03,101.02) v4(3.06,103.05) v4(3.06,102.04) v4(143.68,139.07) v4(143.68,137.93) v4(143.68,136.79) v4(144.7,136.79) v4(144.82,139.07) v4(144.82,137.93)
DC_IN_B: length 32.1
  TOP w0.203: R17.2 15.36,101.33 15.36,101.63 15.22,101.78 10.75,101.78 6.61,97.64 6.61,94.35 v3(6.47,94.21) ; R29.1 20.16,97.79 v3(19.98,97.97)
  L4_IN2 w0.381: v3(17.09,98.15) 17.11,98.18 17.11,98.69 16.75,99.06 14.26,99.06 12.03,96.83 11.41,96.83 v3(11.38,96.81)
  BOTTOM w0.203: v3(6.47,94.21) 6.8,94.54 R419.1
  BOTTOM w0.381: v3(11.38,96.81) 9.72,96.81 9.19,97.34 8.66,97.34 ; D16.A 15.84,99.45 17.11,98.18 v3(17.09,98.15) 17.27,97.97 v3(19.98,97.97)
DDPC_CTRLCLK: length 1
  TOP w0.076: U11.N7 97.62,72.22 v3(97.87,72.65)
  BOTTOM w0.076: v3(97.87,72.65) 97.61,72.91 TP67.1
DDPC_CTRLDATA: length 1.4
  TOP w0.076: U11.N8 v3(97.26,72.65)
  BOTTOM w0.076: TP66.1 v3(97.26,72.65)
DDPD_CTRLCLK: length 0.6
  TOP w0.076: U11.N11 95.02,72.33 v2(95.35,72.65)
DDPD_CTRLDATA: length 0.6
  TOP w0.076: U11.N12 94.37,72.32 v2(94.71,72.65)
DDR0_A_ALERT#: length 111.4
  TOP w0.076: U11.AW50 72.81,85.95 v3(73.1,86.24)
  TOP w0.102: U1637.P9 30.9,103.91 27.54,103.91 25.6,105.86 25.6,106.61 25.95,106.96 TC19.1 ; U1636.P9 30.9,85.37 27.54,85.37 25.6,87.32 25.6,88.07 25.95,88.42 TB19.1
  L3_IN1 w0.076: v3(73.1,86.24) 73.1,86.24 72.45,87.81 72.45,93.78 71.89,94.35
  L3_IN1 w0.292: TA18.1 25.56,98.22 27.52,98.22 28.37,97.75 29.82,97.75 30.18,97.39 30.62,97.39 31.06,97.82 33.68,97.82 34.45,97.05 35.67,97.05 36.61,97.99 38.63,97.99 38.96,97.66 68.57,97.66 71.89,94.35
  L4_IN2 w0.102: TC19.1 26.36,106.66 26.36,106.17 26.54,106 26.54,104.99 26.37,104.83 25.8,104.83 25.51,104.53 25.51,98.26 TA18.1 25.49,98.24 25.49,97.49 25.41,97.41 25.41,97.04 25.75,96.7 25.75,88.91 25.95,88.71 TB19.1
  BOTTOM w0.102: TC19.1 25.95,107.31 25.85,107.42 25.56,107.42 25.46,107.52 25.46,107.72 25.56,107.82 25.85,107.82 25.95,107.92 25.95,108.17 27.3,109.52 29.43,109.52 29.44,109.5 30.69,109.5 31.07,109.89 U1638.P9 ; TB19.1 25.95,88.83 25.85,88.93 25.53,88.93 25.42,89.03 25.42,89.24 25.53,89.34 25.85,89.34 25.95,89.44 25.95,89.65 26.69,90.39 27.96,90.39 28.53,90.96 30.69,90.96 31.07,91.35 U1635.P9
  BOTTOM w0.229: R364.2 25.8,98.56 TA18.1
DDR0_A_MD_PAR: length 97.5
  TOP w0.102: U11.AT52 71.47,84.49 v2(71.37,84.49) ; U1637.T3 28.39,108.29 27.64,107.53 27.36,107.53 27.09,107.27 27.09,106.84 26.71,106.46 TC23.1 ; TB22.1 26.71,87.92 27.09,88.3 27.09,88.73 27.36,88.99 27.64,88.99 28.39,89.75 U1636.T3
  L3_IN1 w0.076: v2(71.37,84.49) 70.91,84.03 70.35,84.03 69.77,84.61 69.77,86.77 70.21,87.21 70.21,89.18
  L3_IN1 w0.292: 70.21,89.18 69.68,89.71 65.62,89.71 64.41,90.92 64.41,92.19 62.8,93.8 41.4,93.8 40.88,93.28 39.91,93.28 39.73,93.47 33.34,93.47 32.8,94.01 32,94.01 31.58,93.59 31.58,92.82 31.33,92.57 28.41,92.57 27.95,93.02 27.95,93.86 27.65,94.16 26.43,94.16 25.32,95.27 25.32,96.75 TA23.1
  L4_IN2 w0.102: TC23.1 26.83,106.32 26.83,104.38 26.44,104 26.44,103.85 26.63,103.67 26.63,103.52 26.49,103.38 26.34,103.38 26.16,103.57 26.01,103.57 25.8,103.35 25.8,98.55 25.9,98.45 25.9,97.32 TA23.1 26.04,96.91 26.04,89.04 26.33,88.75 26.33,87.79 26.44,87.69 26.61,87.69 26.71,87.79 TB22.1
  BOTTOM w0.102: TB22.1 26.97,87.89 27.33,87.54 27.65,87.54 27.94,87.25 27.94,87.1 27.88,87.04 27.88,86.94 28.06,86.76 28.17,86.76 28.23,86.82 28.37,86.82 28.64,86.55 U1635.T3 ; U1638.T3 28.64,105.09 28.37,105.36 28.23,105.36 28.17,105.3 28.06,105.3 27.88,105.48 27.88,105.59 27.94,105.65 27.94,105.79 27.65,106.08 27.33,106.08 26.97,106.43 TC23.1
  BOTTOM w0.229: TA23.1 26.21,97.64 R363.2
DDR1_B_ALERT#: length 55.7
  TOP w0.076: v3(75.94,82.58) U11.AN43
  TOP w0.165: v3(78.85,124.7) 78.22,125.33 CN11.116
  L4_IN2 w0.076: 74.61,97.11 74.61,92.47 76.28,88.43 76.51,87.21 76.51,86.7 76.33,84.8 76.33,84.48 v3(75.94,82.58)
  L4_IN2 w0.216: v3(78.85,124.7) 79.18,124.68 81.84,124.57 84.53,124.25 84.86,124.13 85.09,123.91 85.15,123.5 85.26,122.44 85.26,120.88 85.17,119.51 85.17,115.61 74.61,105.05 74.61,97.11
DDR1_B_PARITY: length 56.3
  TOP w0.076: v2(76.86,82.6) 76.63,82.6 U11.AP43
  TOP w0.165: CN11.143 84.97,117.65 84.85,117.53 83.56,117.53 83.4,117.36 83.4,116.85 83.55,116.7 85.81,116.7 85.94,116.83 85.94,118.68 86.04,118.77 86.53,118.77 86.7,118.61 86.7,117.22 86.95,116.96 v3(91.31,116.96)
  L4_IN2 w0.076: 80.25,97.11 80.25,96.85 79.36,95.96 79.36,91.79 77.32,89.75 77.32,89.56 76.53,88.77 76.53,88.38 76.82,88.09 76.82,84.97 76.49,84.64 76.49,82.97 v2(76.86,82.6)
  L4_IN2 w0.216: v3(91.31,116.96) 91.31,113.18 87.11,108.99 87.11,108 80.25,101.14 80.25,97.11
DDR4_DRAMRST: length 29.9
  TOP w0.076: U11.AT13 93.66,84.14 v3(93.31,84.48)
  L4_IN2 w0.076: 104.57,93.58 105.79,92.36 105.79,89.9 105.4,89.52 104.66,89.52 103.97,88.82 103.97,88.52 103.58,88.13 103.21,88.13 102.27,89.08 100.09,89.08 99.67,88.65 96.58,88.65 95.1,87.17 95.1,87.13 93.68,85.71 93.68,84.78 93.39,84.48 v3(93.31,84.48)
  L4_IN2 w0.102: v3(107.87,100.21) 107.87,99.75 106.27,98.15 106.27,96.68 104.57,94.98 104.57,93.58
  BOTTOM w0.102: R395.2 107.79,100.13 v3(107.87,100.21)
DDR4_DRAMRST#: length 194.2
  TOP w0.102: v3(25.19,87.91) 24.81,88.29 24.81,88.74 25.79,89.72 27.37,89.72 28.56,90.9 30.88,90.9 U1636.P1 ; CN11.108 76.22,125.13 v3(76.22,125.13) ; v2(25.19,106.45) 24.81,106.84 24.81,107.28 25.79,108.26 27.06,108.26 TP1.1 28.24,109.44 30.88,109.44 U1637.P1
  L4_IN2 w0.102: v2(25.19,106.45) 24.53,105.8 v3(24.53,98.9) 24.47,98.83 24.47,92.48 24.81,92.13 24.81,88.29 v3(25.19,87.91)
  L4_IN2 w0.114: 59.85,125.34 60.69,125.34 60.71,125.35 68.88,125.35 69.27,124.97 76.06,124.97 v3(76.22,125.13) 77.28,126.19 93.78,126.19 95.02,124.95 111.02,124.95 114.24,121.73 114.24,120.55 113.39,119.69 113.39,112.5 111.45,110.57 111.45,107.17 106.93,102.65 106.93,100.22 v3(107.04,100.1)
  L4_IN2 w0.14: 59.85,125.34 48.98,125.34 45.71,122.06 35.82,122.06 34.18,120.42 30.51,120.42 28.41,118.32 v3(27.93,118.32)
  BOTTOM w0.102: U1635.P1 30.9,85.37 27.22,85.37 25.25,87.34 25.25,87.85 v3(25.19,87.91) ; v3(107.04,100.1) 106.93,99.99 R395.1 R399.1 ; v3(27.93,118.32) 27.93,117.46 25.57,115.1 25.04,115.1 24.15,114.21 24.15,111.39 23.22,110.46 23.22,101.51 24.15,100.58 24.15,100.14 C3934.2 24.72,99.09 v3(24.53,98.9) ; U1638.P1 30.9,103.91 27.22,103.91 25.25,105.88 25.25,106.39 v2(25.19,106.45)
DDR_RCOMP0: length 17.4
  TOP w0.254: v3(90.57,83.85) 91,83.51 U11.AR18
  L3_IN1 w0.152: 89.55,85.18 90.1,84.63 90.1,84.32 v3(90.57,83.85)
  L3_IN1 w0.254: 89.55,85.18 89.55,86.42 90.9,87.77 90.9,88.83 92.2,90.13 93.65,90.13 95.03,91.51 98.45,91.51 v2(99.1,92.16)
  BOTTOM w0.254: v2(99.1,92.16) 99.1,92.13 98.6,91.63 R436.2
DDR_RCOMP1: length 16.1
  TOP w0.254: U11.AT18 91,84.15 v3(90.57,84.48)
  L3_IN1 w0.152: v3(90.57,84.48) 90.57,84.52 90.08,85.01 90.08,85.4
  L3_IN1 w0.254: 90.08,85.4 90.08,86.49 91.23,87.64 91.23,88.69 92.31,89.77 93.91,89.77 95.32,91.18 98.96,91.18 99.69,91.91 v2(99.69,92.16)
  BOTTOM w0.254: v2(99.69,92.16) 99.69,92.59 R422.2
DDR_RCOMP2: length 10.2
  TOP w0.254: v3(90.57,85.12) 91,84.8 U11.AU18
  L3_IN1 w0.203: 91.15,86.22 90.57,85.64 v3(90.57,85.12)
  L3_IN1 w0.254: v2(96.44,89.42) 95.69,90.16 95.05,90.16 93.4,88.52 93.4,87.89 93.07,87.56 92.49,87.56 91.15,86.22
  BOTTOM w0.254: R438.2 96.64,89.62 v2(96.44,89.42)
DDR_VREF_CA: length 12.9
  TOP w0.076: U11.AY67 63.04,86.85 63.04,87.07 63.07,87.15 63.07,87.36 63.02,87.47 63.02,87.68 63.07,87.8 63.07,88.04 62.9,88.21 62.78,88.21 62.43,88.56 62.43,88.86 62.14,89.15
  TOP w0.254: v2(55.86,87.66) 55.86,88.28 56.73,89.15 62.14,89.15
  BOTTOM w0.508: v2(55.86,87.66) 55.86,87.99 C77.2 54.02,88.62 R70.2
DDR_VTT_CNTL: length 228
  TOP w0.076: 54.71,88.26 55.15,88.26 56.29,89.4 62.37,89.4 62.6,89.18 62.6,88.63 62.85,88.38 62.97,88.38 63.24,88.11 63.24,87.76 63.22,87.73 63.18,87.63 63.18,87.52 63.22,87.43 63.24,87.4 63.24,87.11 63.21,87.05 63.2,87.04 63.2,86.43 63.01,86.23 63,86.23 62.78,86.01 62.78,86 U11.AW67
  TOP w0.102: 54.71,88.26 51.74,85.3 46.61,85.3 v3(46.2,84.89)
  L4_IN2 w0.102: v3(22.64,113.11) 23.1,113.57 23.1,114.44 26.46,117.8 27.47,117.8 27.68,117.58 28.7,117.58 30.44,119.33 45.4,119.33 45.86,118.86 45.86,111.56 46.2,111.21 v3(46.2,84.89) ; v3(101.44,138.64) 101.26,138.82 83.41,138.82 83.31,138.72 73.28,138.72 72.89,138.33 70.4,138.33 69.04,139.68 62.29,139.68 61.25,138.64 43.08,138.64 42.27,139.45 29.33,139.45 28.66,140.12 23.69,140.12 23.01,139.45 23.01,135.57 21.64,134.2 20.62,134.2 20.62,134.2 18.14,134.2 13.82,134.2 12.61,132.99 10.21,132.99 6.96,129.73 6.96,127.09 3.89,124.03 3.89,113.11 v3(4.09,112.91)
  BOTTOM w0.102: v3(101.44,138.64) 101.7,138.38 R3201.2 ; v3(4.09,112.91) 4.26,112.74 4.64,112.74 4.92,112.45 5.33,112.45 5.92,111.87 13.81,111.87 14.8,110.88 15.21,110.88 15.89,111.56 17.91,111.56 18.5,112.16 19.41,112.16 20.64,113.4 22.35,113.4 v3(22.64,113.11)
DDR_VTT_CNTL_D: length 3.7
  BOTTOM w0.102: Q55.B 102.12,138.71 104.11,138.71 R3201.1
DMIC_CLK: length 101.5
  L4_IN2 w0.102: v3(135.02,125.15) 135.35,124.82 135.35,114.75 136.04,114.07 136.04,110.3 133.8,108.06 133.8,104.28 133.08,103.56 133.08,97.1 v3(133.27,96.91)
  BOTTOM w0.102: ER2.2 136.37,126.07 135.81,125.51 135.4,125.51 135.05,125.15 v3(135.02,125.15) ; v3(133.27,96.91) 133.5,96.91 140.71,89.7 140.71,87.62 140.71,83.28 142.28,81.71 142.28,80.22 145.76,76.74 145.76,58.66 145.92,58.5 145.92,54.06 146.25,53.73 146.25,50.68 147.27,49.66 147.27,48.31 146.38,47.43 145.18,47.43 145.05,47.3 145.05,45 146.25,43.79 146.25,42.96 146.48,42.73 147.77,42.73 148.58,41.92 148.58,40.01 148.97,39.63 149.75,39.63 150.46,38.91 U33.3
DMIC_CLK_R: length 5.5
  TOP w0.102: CN7.24 134.94,127.54 v3(135.05,127.64)
  BOTTOM w0.102: v3(135.05,127.64) 135.53,128.13 136.26,128.13 137.18,127.21 137.44,127.21 C147.1 136.7,126.93 ER2.1
DMIC_DATA: length 103.6
  L4_IN2 w0.102: v3(134.97,124.56) 134.97,114.7 135.74,113.94 135.74,110.43 133.5,108.19 133.5,104.41 132.78,103.69 132.78,96.79 133.22,96.35 v3(133.27,96.35)
  BOTTOM w0.102: v3(133.27,96.35) 133.32,96.4 133.55,96.4 140.41,89.55 140.41,87.75 140.41,83.15 141.98,81.58 141.98,80.06 145.46,76.58 145.46,58.45 145.62,58.3 145.62,53.85 145.94,53.53 145.94,50.48 146.96,49.46 146.96,48.44 146.33,47.81 144.93,47.81 144.67,47.55 144.67,44.94 145.95,43.67 145.95,42.73 146.35,42.32 147.57,42.32 148.28,41.61 148.28,39.76 148.71,39.32 149.62,39.32 150.06,38.88 U33.2 ; v3(134.97,124.56) 135.2,124.79 137.63,124.79 ER1.2
DMIC_DATA_R: length 8.1
  TOP w0.102: v3(137.92,127.67) 137.56,128.02 135.81,128.02 135.44,127.66 CN7.25
  BOTTOM w0.102: ER1.1 138.89,126.9 C146.1 140.03,127.46 139.44,128.05 138.29,128.05 v3(137.92,127.67)
DSW_PWER_EN: length 27.2
  L3_IN1 w0.102: v3(14.01,117.84) 14.01,118.89 14.44,119.33 14.44,123.52 16.77,125.85 17.96,125.85 18.21,125.6 19.32,125.6 19.58,125.35 24.36,125.35 25.44,126.43 25.44,128.28 v3(25.5,128.34)
  BOTTOM w0.102: v3(14.01,117.84) 14.01,118.05 13.54,118.52 12.66,118.52 11.05,116.9 U25.29 ; v3(25.5,128.34) 25.5,128.89 R340.1
DSW_PWROK: length 11.5
  BOTTOM w0.102: R356.1 29.81,120.33 29.33,119.85 28.69,119.85 28.44,120.09 28.44,120.41 28.52,120.49 v1(28.52,121.29) 28.52,121.84 27.95,122.42 27.95,123.24 28.16,123.46 28.16,124.85 27.86,125.15 25.11,125.15 24.74,125.52 U25.107
DSW_PWROK_R: length 108.1
  TOP w0.076: U11.BB20 90.07,87.94 90.07,88.97 90.1,88.99 90.1,90.57 92.5,92.97 93.25,92.97 93.86,93.58
  TOP w0.102: 93.86,93.58 95.81,95.54 101.07,95.54 101.73,94.88 v3(105.43,94.88)
  L3_IN1 w0.102: v3(32.79,119.75) 33.34,120.3 35.61,120.3 36.02,119.9 45.06,119.9 45.11,119.95 48.57,119.95 48.83,119.69 50.05,119.69 54.59,115.15 78.69,115.15 96.71,97.13 100.33,97.13 100.99,96.48 100.99,95.87 101.99,94.88 v3(105.43,94.88)
  BOTTOM w0.102: v3(105.43,94.88) 105.18,94.88 104.82,95.23 R413.2 ; R356.2 29.99,119.36 R358.1 C325.2 32.4,119.36 v3(32.79,119.75)
DWL_REQ: length 3.4
  TOP w0.102: R745.2 121.28,21.22 123.81,21.22 U1634.A1
E-USB-N: length 5.2
  TOP w0.114: USB3R1.2 146.78,116.66 146.78,116.42 146.61,116.26 146.25,116.26 145.89,116.62 144.8,116.62 D9.2 144.41,116.23 144.05,116.23 143.78,116.51 L12.4 143.19,116.51 R288.1
E-USB-P: length 5.2
  TOP w0.114: USB3R1.3 146.89,115.63 146.89,115.9 146.79,116 146.28,116 145.89,115.62 144.78,115.62 D9.1 144.42,115.98 143.98,115.98 143.71,115.71 L12.1 143.19,115.71 R289.1
EAPD/COMBO_JACK: length 24.9
  L3_IN1 w0.102: v3(147.24,45.85) 147.24,43.29 148.79,41.74 151.94,41.74 152.44,41.23 155.01,41.23 156.81,39.43 156.81,37.22 158.34,35.69 158.34,31.68 v3(158.49,31.53)
  BOTTOM w0.102: v3(147.24,45.85) 147.03,46.06 R533.2 ; C532.2 158.55,31.53 158.52,31.53 ; 158.52,31.53 v3(158.49,31.53) ; 158.52,31.53 158.92,31.12 AR10.2
EC_3.3VA: length 60
  TOP w0.508: v3(20.16,129.93) 20.34,129.93 20.87,130.46 C29.1 21.36,130.77 21.52,130.92 C33.1 23.16,130.92 B2.2 ; v3(15.47,116.89) 14.85,116.26 14.23,116.26 13.78,116.71 v3(12.34,116.71) 12.12,116.71 11.56,117.27 C7.1 11.83,117.65 11.83,117.67 12.26,118.11 12.26,122.95 10.8,124.41 v3(10.23,124.41) ; v3(23.09,116.49) 23.09,116.88 23.36,117.15 C39.1 23.36,117.66 24.33,118.63 24.33,119.27 24.32,119.28 24.32,119.77 24.33,119.78 24.33,120 24.51,120.18 v3(24.96,120.18) 25.03,120.24 25.03,122.47 v3(24.91,122.59) 24.89,122.56 24.63,122.56 24.1,123.1 C36.2
  L3_IN1 w0.508: v3(15.47,116.89) 16.08,116.89 16.91,116.06 22.27,116.06 22.7,116.49 v3(23.09,116.49)
  L4_IN2 w0.508: v3(20.16,129.93) 19.53,130.56 14.75,130.56 14.4,130.21 10.52,130.21 9.34,129.04 9.34,125.3 v3(10.23,124.41)
  BOTTOM w0.203: v3(10.23,124.41) 10.01,124.41 9.52,123.92 U25.50 ; U25.121 24.69,119.92 24.72,119.96 24.74,119.96 v3(24.96,120.18) ; U25.26 12.25,116.62 v3(12.34,116.71) ; v3(24.91,122.59) 24.77,122.72 U25.114 ; U25.127 22.98,117.52 22.78,117.32 22.78,116.69 22.98,116.49 v3(23.09,116.49) ; U25.92 20.65,130.24 20.34,129.93 v3(20.16,129.93)
EC_BL_ON: length 131.3
  L4_IN2 w0.102: v3(131.85,120.96) 131.73,120.96 129.51,123.17 128.56,123.17 126.92,124.82 123.03,124.82 118.8,129.05 115.94,129.05 115.18,129.8 106.89,129.8 105.34,131.35 89.7,131.35 89.05,132 72.87,132 72.15,131.27 69.49,131.27 68.53,130.31 51.92,130.31 51.36,130.87 49.62,130.87 49.06,130.31 45.72,130.31 44.83,129.42 36.14,129.42 35.43,130.13 33.25,130.13 32.67,129.55 28.56,129.55 26.4,131.71 17.4,131.71 17.2,131.91 15.54,131.91 15.11,132.34 14.96,132.34 v3(14.91,132.39)
  BOTTOM w0.102: v1(14.3,133.11) 14.91,132.5 v3(14.91,132.39) 14.86,132.34 14.6,132.34 14.25,131.99 U25.76 ; v3(131.85,120.96) 131.98,120.83 132.99,120.83 133.42,120.4 R244.1 133.83,120.48 D6.C
EC_BL_PWM: length 133.4
  L4_IN2 w0.102: v3(24.38,131.25) 24.45,131.19 26.5,131.19 28.35,129.34 32.75,129.34 33.34,129.93 35.25,129.93 35.96,129.22 44.92,129.22 45.81,130.11 49.15,130.11 49.71,130.67 51.28,130.67 51.84,130.11 68.61,130.11 69.57,131.07 72.23,131.07 72.96,131.79 88.97,131.79 89.69,131.07 94.66,131.07 96.13,129.6 115.04,129.6 115.79,128.84 118.72,128.84 122.94,124.62 126.83,124.62 128.48,122.97 129.27,122.97 132.46,119.78 132.46,115.41 131.02,113.97 130.96,113.97 129.69,112.7 v3(129.69,112.32)
  BOTTOM w0.102: U25.95 21.85,131.77 22.17,132.09 v1(23.57,132.09) 24,132.52 R56.1 R57.2 25.42,132.42 24.38,131.38 v3(24.38,131.25) ; R268.1 129.28,112.73 v3(129.69,112.32)
EC_EXTSMI#: length 228.9
  TOP w0.076: v3(98.55,71.71) U11.L6
  L3_IN1 w0.102: v3(133.8,84.85) 132.73,84.85 130.9,86.68 130.9,89.84 126.03,94.71 126.03,99.44 123.26,102.2 122.09,102.2 118.04,106.26 118.04,116.97 120.66,119.6 121.29,119.6 121.89,120.2 121.89,124.39 118.38,127.9 92.24,127.9 91.43,128.71 91.33,128.71 89.71,130.34 74.31,130.34 73.2,129.22 73.2,128.02 72.62,127.44 67.55,127.44 67.06,126.96 51.58,126.96 48.37,130.16 38.4,130.16 35.42,127.19 32.64,127.19 31.62,126.16 28.89,126.16 28.59,126.46 27.06,126.46 26.34,125.74 25.12,125.74 24.53,125.14 19.49,125.14 19.24,125.39 18.13,125.39 17.88,125.64 17.1,125.64 v3(16.68,125.22)
  L4_IN2 w0.102: v3(130.75,69.71) 128.09,69.71 128.01,69.78 118.49,69.78 117.96,70.31 113.19,70.31 112.14,71.36 100.6,71.36 100.22,71.74 98.58,71.74 v3(98.55,71.71)
  BOTTOM w0.102: v3(130.75,69.71) 131.11,70.06 131.83,70.06 133.75,71.98 133.75,73.01 136.72,75.99 136.72,79.96 135.46,81.23 135.46,83.19 v3(133.8,84.85) ; v3(16.68,125.22) 16.86,125.05 16.86,120.78 16.6,120.52 16.6,119.24 16.1,118.74 16.1,117.36 16.65,116.81 U25.15 16.65,114.67 16.84,114.48 16.84,114 16.31,113.47 R374.1
EC_PECI: length 125.7
  TOP w0.076: R105.1 70.02,60.69 v3(69.67,60.33)
  TOP w0.102: v3(57.49,56.82) 57.04,56.82 56.55,56.32 53.79,56.32 52.02,58.09 52.02,58.29 v3(51.65,58.66)
  L4_IN2 w0.102: v3(57.49,56.82) 57.68,57.01 61.01,57.01 62.81,58.81 67.85,58.81 69.37,60.33 v3(69.67,60.33) ; v3(20.22,57.2) 20.09,57.33 20.09,59.42 22.24,61.57 22.24,77 22.75,77.52 22.75,80.31 23.2,80.76 23.2,83.05 22.75,83.49 22.75,111.74 23.83,112.82 23.83,114.88 25.39,116.44 v3(25.75,116.44)
  BOTTOM w0.102: v3(25.75,116.44) 25.22,116.97 25.22,118.25 25.73,118.75 v1(25.85,118.88) 25.85,120.17 24.5,121.52 U25.117 ; v3(20.22,57.2) 20.58,56.84 20.58,56.74 20.96,56.36 25.82,56.36 26.36,56.91 26.36,57.63 29.73,61 37.78,61 39.92,58.86 51.45,58.86 v3(51.65,58.66)
EC_PROCHOT#: length 110
  TOP w0.102: v3(10.88,43.61) 13.36,41.14 19.02,41.14 R3161.2
  L4_IN2 w0.102: v3(15.13,129.35) 15.13,126.89 10.82,122.58 10.82,120.58 8.82,118.58 8.82,118.18 8.17,117.53 8.17,113.61 7.97,113.42 7.97,111.92 8.89,111.01 8.89,104.27 5.86,101.24 5.86,98.66 4.6,97.4 4.6,93.36 4.73,93.23 4.73,83.59 5.8,82.51 5.8,77.08 5.16,76.44 5.16,70.07 5.53,69.7 5.53,68.84 4.65,67.96 v3(4.61,67.96)
  BOTTOM w0.102: v3(15.13,129.35) 15.05,129.35 14.65,129.75 U25.77 ; v3(10.88,43.61) 11.2,43.93 11.2,50.41 12.16,51.37 12.16,55.03 11.44,55.75 10.03,55.75 4.57,61.21 4.57,66.1 4.97,66.5 4.97,66.99 4.62,67.35 4.62,67.96 v3(4.61,67.96)
ECSCI#: length 3.5
  BOTTOM w0.102: U25.23 13.45,113.86 13.84,113.47 R376.1 R375.1
EDP_AUXN: length 143.2
  TOP w0.102: v3(75.03,67.77) U11.E45
  TOP w0.114: v2(138.98,118.56) 139.19,118.35 139.44,118.35 139.57,118.47 139.57,119.26 137.42,121.41 136.8,121.41 136.2,122 136.2,122.37 C218.1
  L4_IN2 w0.076: 91.13,66.05 91.13,66.06 91.15,66.08 91.15,66.48 90.77,66.85 90.77,67.81 89.99,68.59 89.99,70.11 89.22,70.88 88.21,70.88 86.91,69.58 76.75,69.58 76.49,69.31 76.49,68.65 75.84,68 75.26,68 v3(75.03,67.77)
  L4_IN2 w0.114: v2(138.98,118.56) 139.2,118.34 141.64,118.34 144.48,115.49 144.48,114.22 143.81,113.55 143.81,110.66 142.07,108.93 142.07,105.48 139.63,103.05 139.63,98.61 139.22,98.2 139.22,91.61 139.46,91.38 139.46,62.63 137.71,60.88 106.85,60.88 104.7,63.04 100.82,63.04 100.48,63.38 97.15,63.38 96.94,63.17 92.11,63.17 91.13,64.14 91.13,66.05
EDP_AUXN_R: length 3.3
  TOP w0.114: CN7.27 136.54,126.44 136.54,125.51 136.36,125.32 136.36,123.92 C218.2
EDP_AUXP: length 143.2
  TOP w0.102: v3(75.03,68.41) 75.14,68.37 75.45,68.53 U11.F45
  TOP w0.114: v2(138.98,117.9) 139.17,118.09 139.55,118.09 139.82,118.37 139.82,119.37 137.53,121.66 136.9,121.66 136.45,122.11 136.45,122.46 136.63,122.64 C222.1
  L4_IN2 w0.076: v3(75.03,68.41) 75.06,68.41 75.29,68.18 75.76,68.18 76.31,68.73 76.31,69.39 76.68,69.76 86.84,69.76 88.14,71.05 89.3,71.05 90.17,70.19 90.17,68.67 90.95,67.88 90.95,66.93 91.33,66.55 91.33,66.08 91.35,66.06 91.35,66.05
  L4_IN2 w0.114: 91.35,66.05 91.35,64.23 92.2,63.38 96.85,63.38 97.06,63.6 100.57,63.6 100.91,63.26 104.79,63.26 106.94,61.1 137.62,61.1 139.24,62.72 139.24,91.29 139.01,91.52 139.01,98.29 139.42,98.7 139.42,103.14 141.85,105.57 141.85,109.02 143.59,110.75 143.59,113.64 144.27,114.31 144.27,115.4 141.55,118.12 139.2,118.12 v2(138.98,117.9)
EDP_AUXP_R: length 3.3
  TOP w0.114: CN7.28 136.92,126.55 136.8,126.42 136.8,125.4 136.61,125.21 136.61,123.84 C222.2
EDP_DISP_UTIL: length 139.8
  TOP w0.076: v3(70.31,60.36) 70.31,60.47 70.43,60.59 70.43,65 70.56,65.13 70.56,65.66 70.82,65.92 U11.B52
  L4_IN2 w0.102: v3(129.51,109.4) 129.05,108.94 129.05,98.55 v3(129.27,98.34) ; v3(139.73,92.12) 139.87,91.98 139.87,80.87 140.49,80.25 140.49,79.93 140.07,79.52 140.07,66 141.04,65.03 141.04,63.34 136.09,58.39 130.86,58.39 129.63,59.62 106.34,59.62 104.62,61.34 91.38,61.34 90.7,60.66 85.22,60.66 84.63,61.25 77.26,61.25 76.02,62.49 70.76,62.49 70.35,62.08 70.35,60.51 70.31,60.47 v3(70.31,60.36)
  BOTTOM w0.102: v3(139.73,92.12) 139.73,92.13 133.8,98.05 131.95,98.05 131.66,98.34 v3(129.27,98.34) ; R263.2 v3(129.51,109.4)
EDP_HPD_CN: length 2.5
  TOP w0.102: CN7.22 133.94,127.86 v3(133.9,127.9)
  BOTTOM w0.102: R347.2 134.41,127.01 133.9,127.52 v3(133.9,127.9)
EDP_R_D0+: length 3.4
  TOP w0.114: C233.2 138.58,123.91 138.58,124.77 138.32,125.03 138.32,126.42 CN7.31
EDP_R_D0-: length 3.4
  TOP w0.114: C230.2 138.33,123.86 138.33,124.66 138.06,124.93 138.06,126.42 CN7.30
EDP_R_D1+: length 3.6
  TOP w0.114: CN7.34 139.94,125.82 139.82,125.7 139.82,125.44 140.74,124.51 140.74,123.85 C227.2
EDP_R_D1-: length 3.7
  TOP w0.114: C225.2 140.48,123.92 140.48,124.41 139.56,125.33 139.56,125.71 139.44,125.83 CN7.33
EDP_RCOMP: length 1.2
  TOP w0.254: U11.E52 v2(71.46,67.67)
  BOTTOM w0.254: v2(71.46,67.67) 71.65,67.86 R493.2
EDP_TXN0: length 153.2
  TOP w0.076: U11.C47 73.98,66.58 73.7,66.3 73.62,66.04 73.62,65.79 73.66,65.7 73.66,65.51 73.63,65.43 73.62,65.42 73.62,65.4 73.57,65.35 73.57,64.98 74.14,64.41 74.14,59.94 74.55,59.52 v2(75.53,59.52)
  TOP w0.114: C230.1 138.13,122.48 138.13,121.84 138.63,121.34 139.02,121.34 139.02,121.33 139.03,121.33 v2(139.16,121.2)
  L4_IN2 w0.114: v2(139.16,121.2) 139.11,121.25 138.49,121.25 138.08,121.66 138.08,122.42 138.9,123.25 142.11,123.25 146.36,118.99 146.36,109.73 144.3,107.67 144.3,104.9 141.13,101.73 141.13,81.39 142.33,80.19 142.33,77.02 143.42,75.92 143.42,63.94 136.55,57.06 130.4,57.06 129.82,57.65 106.53,57.65 106.09,58.09 106.09,58.09 104.78,59.4 104.51,59.4 104.51,59.4 103.92,59.4 76.21,59.4 76.09,59.52 v2(75.53,59.52)
EDP_TXN1: length 143.7
  TOP w0.076: U11.D46 75.27,66.9 75.44,66.73 75.47,66.65 75.47,66.52 75.55,66.24 75.6,66.08 75.61,66.04 75.61,65.79 75.58,65.7 75.58,65.51 75.61,65.41 75.61,65.04 75.02,64.46 75.02,61.55 75.15,61.43 75.31,61.43 v2(75.48,61.6)
  TOP w0.114: C225.1 140.32,122.38 140.32,121.9 140.76,121.47 141.32,121.47 v2(141.49,121.3)
  L4_IN2 w0.114: v2(141.49,121.3) 141.69,121.5 142.64,121.5 144.95,119.2 144.95,115.82 145.51,115.25 145.51,112.2 144.69,111.38 144.69,109.98 142.61,107.9 142.61,104.41 140.28,102.08 140.28,81.04 141.48,79.84 141.48,76.43 142.57,75.33 142.57,64.29 136.26,57.98 130.69,57.98 129.5,59.16 106.22,59.16 104.45,60.93 91.55,60.93 90.87,60.25 84.79,60.25 84.21,60.84 76.76,60.84 76.14,61.45 75.64,61.45 v2(75.48,61.6)
EDP_TXP0: length 153.2
  TOP w0.076: U11.C46 74.85,66.25 74.92,66.33 74.92,66.46 74.77,66.62 74.5,66.62 74.14,66.25 73.93,66.25 73.83,66.15 73.79,66.01 73.79,65.82 73.82,65.73 73.82,65.48 73.79,65.38 73.79,65.07 74.35,64.5 74.35,60.03 74.64,59.74 75.25,59.74 75.5,59.99 v2(75.5,60.07)
  TOP w0.114: C233.1 138.96,122.67 138.5,122.67 138.38,122.55 138.38,121.94 138.73,121.59 138.9,121.59 v2(139.16,121.86)
  L4_IN2 w0.114: v2(75.5,60.07) 75.85,60.07 76.3,59.61 102.57,59.61 104.42,59.61 104.87,59.62 106.18,58.3 106.62,57.86 129.9,57.86 130.49,57.28 136.46,57.28 143.21,64.03 143.21,75.83 142.11,76.93 142.11,80.1 140.92,81.3 140.92,101.82 144.09,104.99 144.09,107.76 146.15,109.82 146.15,118.9 142.02,123.03 138.99,123.03 138.3,122.33 138.3,121.75 138.58,121.46 138.77,121.46 v2(139.16,121.86)
EDP_TXP1: length 143.7
  TOP w0.076: U11.C45 75.36,66.26 75.45,66.01 75.45,65.82 75.41,65.73 75.41,65.48 75.45,65.38 75.45,65.11 74.86,64.53 74.86,61.46 75.08,61.25 75.36,61.25 v2(75.51,61.09)
  TOP w0.114: C227.1 140.69,122.64 140.58,122.52 140.58,122.01 140.87,121.72 141.3,121.72 141.49,121.91 v2(141.49,121.96)
  L4_IN2 w0.114: v2(75.51,61.09) 75.65,61.23 76.05,61.23 76.67,60.62 84.12,60.62 84.7,60.03 90.96,60.03 91.64,60.72 104.36,60.72 106.13,58.95 129.41,58.95 130.6,57.76 136.35,57.76 142.79,64.2 142.79,75.42 141.69,76.52 141.69,79.93 140.5,81.13 140.5,101.99 142.83,104.32 142.83,107.81 144.91,109.89 144.91,111.29 145.73,112.11 145.73,115.34 145.16,115.91 145.16,119.29 142.73,121.72 141.67,121.72 141.49,121.91 v2(141.49,121.96)
FAN_CTRL0: length 50.1
  TOP w0.102: U2.4 12.81,107.45 10.87,105.51 10.87,105.04 v1(10.87,105.04) 10.41,104.58 v3(8.51,104.58)
  L4_IN2 w0.102: v3(15.05,129.9) 14.68,129.53 14.68,126.72 10.88,122.93 10.02,122.93 9.22,122.12 9.22,119.27 7.97,118.02 7.97,113.7 7.77,113.5 7.77,111.84 8.68,110.92 8.68,104.76 v3(8.51,104.58) 7.69,103.77 7.69,103.61 v3(7.29,103.21)
  BOTTOM w0.102: U25.78 v3(15.05,129.9) ; v3(7.29,103.21) 7.29,102.29 9.44,100.13 9.44,97.59 9.85,97.19 12.19,97.19 12.38,97.39 12.38,97.69 13.3,98.61 R397.1
FAN_SPEED: length 11.6
  TOP w0.508: CN3.3 3.75,110.11 4.34,110.7 6.63,110.7 7.01,110.32 7.01,110.04 8.3,108.75 C5.1 11.37,108.72 U2.3
FB_3.3_EN: length 12.2
  TOP w0.102: 40.76,131.63 41.81,130.58 41.81,130.53
  TOP w0.203: R60.1 40.76,131.58 U9.12
  TOP w0.254: R60.1 42.02,130.28 41.42,129.68 41.42,128.77 v3(40.85,128.19)
  BOTTOM w0.254: v3(40.85,128.19) 41.61,128.19 42.25,128.83 R842.1 41.69,129.41 41.55,129.27 R840.2 R838.2
FB_5_EN: length 9.6
  TOP w0.203: U18.12 127.23,115.2 127.66,115.62 127.66,116.01 R231.1
  TOP w0.254: R231.1 128.04,116.03 128.04,115.88 v3(128.29,115.62)
  BOTTOM w0.254: v3(128.29,115.62) 127.78,115.12 126.01,115.12 125.83,114.94 R843.1 R841.2 124.03,114.86 R839.2
G_ADDR: length 2.9
  TOP w0.102: U19.7 R229.1 R225.2
G_INT1: length 45.5
  TOP w0.076: U11.AD3 99.96,78.32 101.17,78.32 101.23,78.26 101.5,78.26 101.59,78.35 101.89,78.35 102.44,77.81 v2(104.72,77.81)
  TOP w0.102: v3(132.94,65.87) 133.17,65.87 133.8,65.24 133.8,64.42 133.32,63.94 R242.1 R243.1
  L4_IN2 w0.102: v3(121.36,66.43) 121.99,65.8 121.99,65.46 122.09,65.36 124.01,65.36 124.35,65.7 124.97,65.7 125.19,65.92 127.36,65.92 128.49,64.78 130.19,64.78 130.56,65.16 131.95,65.16 132.66,65.87 v3(132.94,65.87)
  BOTTOM w0.076: 106.62,76.36 105.97,76.36 104.72,77.61 v2(104.72,77.81)
  BOTTOM w0.102: v3(121.36,66.43) 121.1,66.68 121.1,68.46 118.56,71 118.56,71.75 114.8,75.52 109.17,75.52 108.33,76.36 106.62,76.36
G_INT2: length 44.9
  TOP w0.076: U11.AD4 99.05,77.25 99.21,77.1 101.67,77.1 101.75,77.17 104.02,77.17 104.34,76.84 106.62,76.84
  TOP w0.102: v3(114.2,78.11) 113.35,77.27 109.33,77.27 108.91,76.84 106.62,76.84 ; R241.1 132.89,65.33 132.03,65.33 131.72,65.64 v3(131.67,65.64)
  L4_IN2 w0.102: v3(122.45,66.58) 122.96,66.08 123.86,66.08 124.25,66.46 127.1,66.46 128.57,64.99 130.1,64.99 130.48,65.36 131.39,65.36 v3(131.67,65.64)
  BOTTOM w0.102: v3(122.45,66.58) 122.5,66.62 122.5,68.2 119.42,71.27 119.42,73.57 117.2,75.8 115.87,75.8 114.17,77.5 114.17,78.04 114.2,78.06 v3(114.2,78.11)
G_INT_1: length 2.9
  TOP w0.102: U19.11 131.13,63.89 131.47,63.55 132.12,63.55 R242.2 R241.2
G_INT_2: length 1.7
  TOP w0.102: R243.2 132.31,62.89 U19.9
G_SCL: length 2.7
  TOP w0.102: U19.4 126.85,63.39 R213.2 R214.2
G_SDA: length 4.6
  TOP w0.102: R216.2 R218.2 127.33,60.99 127.33,61.6 127.43,61.7 128.98,61.7 129.08,61.8 U19.6
G_VIO: length 5.5
  TOP w0.102: C206.1 128.29,67.01 C201.1 127.96,66.89 R217.2 126.92,65.54 127.57,64.89 U19.1
GPP_B4: length 0.8
  TOP w0.076: U11.AY5 98.89,86.28 v2(99.08,86.09)
GPP_B15: length 9.6
  TOP w0.076: v3(96.06,82.58) 96.45,82.19 U11.AN8
  BOTTOM w0.076: 96.87,84.69 96.87,84.52 96.44,84.09 96.44,83.07 96.06,82.69 v3(96.06,82.58)
  BOTTOM w0.102: 96.87,84.69 96.87,85.97 99.01,88.11 99.01,88.74 99.38,89.12 99.38,89.59 99.82,90.03 R437.2
GPP_B16: length 6.1
  TOP w0.076: v3(96.97,83.21) 97.35,82.84 U11.AP7
  BOTTOM w0.102: v3(96.97,83.21) 97.45,83.7 97.45,85.35 97.67,85.56 98.17,85.56 98.6,85.99 98.6,86.24 99.36,87 R454.2
GPP_B17: length 10.2
  TOP w0.076: U11.AP8 96.44,82.84 v3(96.06,83.21)
  L4_IN2 w0.076: v2(102.28,87.2) 102.09,87.01 100.73,87.01 99.46,85.74 97.36,85.74 96.44,84.82 96.44,83.59 v3(96.06,83.21)
  BOTTOM w0.076: R448.2 102.03,87.49 102.28,87.23 v2(102.28,87.2)
GPP_B18: length 6.4
  TOP w0.076: v3(96.97,83.85) 97.34,83.49 U11.AR7
  BOTTOM w0.102: v3(96.97,83.85) 97.26,84.14 97.26,85.43 97.59,85.75 98.02,85.75 98.24,85.98 98.24,86.27 98.85,86.88 98.85,87.36 99.51,88.02 R451.2
GPP_B19: length 2.9
  TOP w0.076: U11.AM5 98.3,81.54 v3(97.89,81.94)
  BOTTOM w0.102: R467.2 98.77,82.81 97.91,81.94 v3(97.89,81.94)
GPP_B20: length 8.6
  TOP w0.076: v3(96.97,82.58) 97.37,82.19 U11.AN7
  BOTTOM w0.076: 96.82,84.22 96.6,84 96.6,83.06 96.97,82.69 v3(96.97,82.58)
  BOTTOM w0.102: R443.2 99.69,89.03 99.26,88.61 99.26,88.09 97.07,85.91 97.07,84.47 96.82,84.22
GPP_B21: length 3.8
  TOP w0.076: U11.AP5 98.27,82.84 v3(97.89,83.21)
  BOTTOM w0.102: R464.2 99.25,84.97 99.07,84.79 98.55,84.79 98.34,84.59 98.34,83.67 v3(97.89,83.21)
GPP_B22: length 3.1
  TOP w0.076: v3(97.89,82.58) 98.28,82.19 U11.AN5
  BOTTOM w0.102: R466.1 99.14,83.83 v3(97.89,82.58)
H_A20GATE: length 4.4
  TOP w0.102: v1(22.49,116.09) v3(22.49,117.69) 22.22,117.95 21.52,117.95 R35.1
  BOTTOM w0.102: v3(22.49,117.69) 22.72,117.92 U25.126
H_CATERR#: length 6.8
  TOP w0.076: U11.D63 65.48,66.9 65.56,66.63 65.56,66.52 65.64,66.24 65.68,66.08 65.7,66.04 65.7,65.79 65.69,65.77 65.69,65.44 65.7,65.41 65.7,65.05 65.58,64.93 65.58,63.53 65.17,63.12 64.91,63.12 64.54,62.75 64.31,62.75 63.42,61.86 R95.1
H_CPUPWRGD: length 2
  TOP w0.102: v2(62.2,64.34) 62.02,64.52 62.02,65.08 62.14,65.2 U11.A68
  BOTTOM w0.102: v2(62.2,64.34) 62.66,63.89 R79.1
H_PECI: length 3.5
  TOP w0.076: R105.2 70.12,61.93 70.12,65.17 U11.A54
H_PROCHOT#_D: length 11.5
  TOP w0.076: U11.C65 63.81,66.24 63.81,64.99 63.66,64.84 63.66,64.33 62.83,63.5 57.3,63.5 56.64,62.84
  TOP w0.102: 56.64,62.84 55.72,61.93 R82.2
H_RCIN#: length 110.6
  TOP w0.076: v2(101.87,92.51) 101.49,92.51 100.64,91.66 95.4,91.66 93.56,89.82 93.56,88.65 93.45,88.54 93.45,88.34 93.25,88.14 93.25,87.76 93.26,87.74 93.3,87.65 93.3,87.53 93.24,87.31 93.24,87.17 93.29,87.01 93.29,86.93 93.43,86.49 93.51,86.23 93.51,86.23 93.69,86.05 U11.AW13
  L3_IN1 w0.076: 97.5,93.58 98.11,92.97 101.42,92.97 v2(101.87,92.51)
  L3_IN1 w0.102: v3(20.75,114.13) 20.75,114.22 21.7,115.17 32.14,115.17 33.14,116.17 33.85,116.17 35.25,117.57 45.31,117.57 45.96,118.22 47.65,118.22 47.99,117.88 48.41,117.88 52.86,113.43 77.97,113.43 96.79,94.6 96.79,94.29 97.5,93.58
  BOTTOM w0.076: v2(101.87,92.51) 102.28,92.11 102.76,92.11 R424.1
  BOTTOM w0.102: v3(20.75,114.13) 21.05,114.42 U25.4
H_THRMTRIP#: length 8
  TOP w0.076: U11.C63 65.45,66.26 65.52,66.05 65.52,65.11 65.4,64.99 65.4,63.59 65.09,63.28 64.61,63.28 63.51,62.19 62.91,62.19 62.5,61.78 R94.1 R92.2
HDMI_+5V: length 1.9
  TOP w0.762: PS3.1 145.89,105.71 B6.2
HDMI_CLK: length 7.4
  BOTTOM w0.102: Q29.D 147.34,101.07 148.08,101.07 R391.1 148.84,100.97 149.98,100.97 150.5,101.49 151.16,101.49 151.62,101.04 151.62,99.77 152.19,99.2 HDMI1.15
HDMI_DAT: length 7.4
  BOTTOM w0.102: HDMI1.16 150.82,99.7 150.39,99.27 150.39,96.95 149.98,96.55 148.69,96.55 148.56,96.68 148.56,97.44 R400.2 147.16,97.49 Q32.D
HDMI_DDC_CLK: length 90.7
  TOP w0.076: v2(94.08,71.71) 93.72,71.36 U11.L13
  L4_IN2 w0.076: v2(94.08,71.71) 94.64,72.28 98.03,72.28 98.17,72.42 98.8,72.42 99,72.61 100.84,72.61 101.18,72.27 102.89,72.27
  L4_IN2 w0.102: v3(130.71,70.79) 130.61,70.7 118.87,70.7 118.34,71.23 115.06,71.23 114.53,71.76 113.03,71.76 112.52,72.27 102.89,72.27 ; v3(134.38,102.59) 134.3,102.52 134.3,97.72 134.57,97.45 134.57,91.07 133.2,89.7 v3(133.2,88.47)
  BOTTOM w0.102: v3(130.71,70.79) 131.21,70.79 131.24,70.82 131.73,70.82 133.14,72.23 133.14,73.27 135.28,75.4 135.28,77.92 135.53,78.17 135.53,80.09 134.85,80.78 134.85,82.79 133.12,84.52 133.12,88.4 v3(133.2,88.47) ; Q29.S 143.8,100.77 143.12,100.77 142.84,101.05 142.84,101.37 141.9,102.31 141.9,102.57 R388.1 141.17,103.31 138.71,103.31 138,102.59 137.85,102.59 137.75,102.7 137.75,103.2 137.65,103.31 137.33,103.31 137.23,103.2 137.23,102.7 137.13,102.59 136.81,102.59 136.71,102.7 136.71,103.2 136.61,103.31 136.29,103.31 136.19,103.2 136.19,102.7 136.09,102.59 135.77,102.59 135.67,102.7 135.67,103.2 135.56,103.31 135.25,103.31 135.15,103.2 135.15,102.7 135.04,102.59 v3(134.38,102.59)
HDMI_DDC_DAT: length 90.7
  TOP w0.076: U11.L12 94.37,71.38 v2(94.71,71.71)
  L4_IN2 w0.076: 102.58,71.97 101.01,71.97 100.53,72.45 99.09,72.45 98.88,72.24 98.22,72.24 98.09,72.11 95.11,72.11 v2(94.71,71.71)
  L4_IN2 w0.102: 102.58,71.97 112.4,71.97 113.44,70.92 118.21,70.92 118.74,70.39 130.85,70.39 131.46,71 v3(131.46,71.31) ; v3(132.66,88.24) 132.76,88.35 132.76,90.54 134.26,92.04 134.26,97.32 134,97.59 134,102.85 v3(134.37,103.22)
  BOTTOM w0.102: v3(134.37,103.22) 134,102.85 134,102.44 134.22,102.21 138.05,102.21 138.83,103 140.73,103 141.51,102.22 141.57,102.22 142.54,101.25 R396.2 142.95,98.97 142.95,98.28 143.3,97.92 143.94,97.92 144.51,98.5 Q32.S ; v3(131.46,71.31) 131.78,71.31 132.83,72.36 132.83,73.39 134.97,75.53 134.97,78.04 135.23,78.3 135.23,79.97 134.54,80.65 134.54,81.57 132.81,83.3 132.81,88.09 v3(132.66,88.24)
HDMI_HPD: length 87.3
  TOP w0.076: v3(96.64,71.66) 96.32,71.34 U11.L9
  L4_IN2 w0.076: v3(96.64,71.66) 96.94,71.96 98.17,71.96 98.29,72.07 98.7,72.07 98.73,72.04 100.35,72.04 100.73,71.66 102.41,71.66
  L4_IN2 w0.102: 102.41,71.66 112.27,71.66 113.31,70.62 118.08,70.62 118.61,70.09 131.11,70.09 v3(131.46,70.44) ; v3(132.33,88.83) 132.43,88.93 132.43,90.71 133.96,92.24 133.96,97.2 133.69,97.46 133.69,103.16 v3(133.77,103.24)
  BOTTOM w0.102: Q28.S 144.63,104.97 143.96,105.65 142.46,105.65 R385.2 140.54,103.73 134.21,103.73 133.77,103.28 v3(133.77,103.24) ; v3(131.46,70.44) 131.49,70.47 131.8,70.47 133.44,72.11 133.44,73.14 136.42,76.12 136.42,79.83 135.15,81.1 135.15,82.91 133.42,84.64 133.42,88.16 133.58,88.31 133.58,88.63 133.19,89.02 132.52,89.02 v3(132.33,88.83)
HDMIOUT_CLK+: length 6.6
  TOP w0.114: L18.3 149.18,101.08 149.45,101.35 149.68,101.35 149.93,101.1 149.93,100.26 150.03,100.16 150.03,97.39 150.33,97.09 150.62,97.09 HDMI1.10
HDMIOUT_CLK-: length 6.6
  TOP w0.114: L18.2 149.18,101.88 149.45,101.61 149.78,101.61 150.18,101.21 150.18,100.37 150.29,100.27 150.29,97.49 150.44,97.34 150.65,97.34 HDMI1.12
HDMIOUT_D0+: length 12.4
  TOP w0.114: L19.3 148.72,98.16 148.99,98.43 149.17,98.43 149.37,98.23 v2(149.37,98.18)
  L4_IN2 w0.089: HDMI1.7 152.21,95.27 151.87,95.62 151.76,95.62 151.68,95.7 151.61,95.77 151.47,96.11 151.47,96.35 151.56,96.57 151.56,96.83 151.47,97.04 151.47,97.34 151.6,97.65 151.6,97.75 151.47,98.06 151.47,98.34 151.6,98.64 151.6,98.74 151.47,99.05 151.47,99.34 151.57,99.58 151.57,99.78 151.47,100.02 151.47,100.35 151.56,100.57 151.56,100.83 151.46,101.07 151.23,101.29 151.22,101.29 151.17,101.34 151.17,101.34 151.15,101.34 151.15,101.34
  L4_IN2 w0.114: v2(149.37,98.18) 149.61,98.42 149.92,98.42 150.21,98.71 150.21,101.05 150.6,101.44 151.05,101.44 151.15,101.34
HDMIOUT_D0-: length 12.4
  TOP w0.114: L19.2 148.77,98.96 149.04,98.69 149.22,98.69 v2(149.4,98.86)
  L4_IN2 w0.089: 151.3,101.5 151.62,101.18 151.75,100.86 151.75,100.53 151.66,100.32 151.66,100.06 151.76,99.82 151.76,99.55 151.66,99.3 151.66,99.08 151.79,98.78 151.79,98.61 151.66,98.3 151.66,98.1 151.79,97.79 151.79,97.61 151.66,97.31 151.66,97.08 151.75,96.86 151.75,96.53 151.66,96.32 151.66,96.15 151.77,95.88 151.84,95.81 152.04,95.81 152.21,95.98 HDMI1.9
  L4_IN2 w0.114: 151.3,101.5 151.14,101.66 150.51,101.66 149.99,101.14 149.99,98.8 149.83,98.64 149.63,98.64 v2(149.4,98.86)
HDMIOUT_D1+: length 4
  TOP w0.114: HDMI1.4 150.64,94.07 150.33,94.07 149.9,94.5 149.9,95.69 149.7,95.89 149.19,95.89 148.92,95.62 L20.3
HDMIOUT_D1-: length 4
  TOP w0.114: L20.2 148.92,96.42 149.19,96.15 149.81,96.15 150.16,95.8 150.16,94.6 150.43,94.33 150.64,94.33 HDMI1.6
HDMIOUT_D2+: length 5.4
  TOP w0.114: L21.3 148.95,93.08 149.2,93.33 149.64,93.33 149.75,93.22 149.75,92.23 150.23,91.75 151.23,91.75 151.81,92.33 151.81,92.46 151.88,92.54 152.01,92.54 152.21,92.34 HDMI1.1
HDMIOUT_D2-: length 5.4
  TOP w0.114: HDMI1.3 151.84,92.83 151.81,92.83 151.57,92.58 151.57,92.58 151.55,92.57 151.55,92.44 151.12,92.01 150.33,92.01 150.01,92.34 150.01,93.33 149.75,93.59 149.32,93.59 149.02,93.88 L21.2
HP_GND: length 28.4
  TOP w0.508: AUDR1.2 159.24,22.67 158.74,23.17 158.74,24.23 157.41,25.56 153.29,25.56 151.61,23.88 v3(150.21,23.88)
  L4_IN2 w0.508: AUDR1.6 152,13.75 148.74,13.75 148,14.49 148,19.26 147.44,19.82 147.44,21.12 148.71,22.39 148.71,22.39 v3(150.21,23.88)
  BOTTOM w0.508: v3(150.21,23.88) 151.1,23.88 AB16.2
HP_JD_SENSE#: length 40.7
  TOP w0.102: v3(148.18,22.77) 148.18,22.18 148.63,21.72 148.63,18.63 AR5.1
  L4_IN2 w0.102: v3(156.23,42.35) 157.25,43.36 158.65,43.36 159.15,42.86 159.15,37.85 160.02,36.98 160.02,34.75 159.68,34.41 159.68,32.16 159.15,31.63 159.15,31.03 159.71,30.48 159.71,28.82 159.15,28.26 159.15,26.44 157.84,25.13 153.04,25.13 152.45,24.54 149.96,24.54 v3(148.18,22.77)
  BOTTOM w0.102: AR7.2 v3(156.23,42.35)
HP_JD_SENSE_MB#: length 6.6
  TOP w0.102: AB8.1 146.68,16.75 AR5.2 146.68,17.79 146.07,18.4 146.07,20.8 145.33,21.54 Q19.S
HP_L: length 16
  TOP w0.102: v3(147.26,19.08) 147.54,18.8 AR4.2
  L3_IN1 w0.102: v3(147.26,19.08) 147.26,19.11 147.22,19.16 147.22,25.31 149.37,27.47 149.42,27.47 v3(149.78,27.82)
  BOTTOM w0.102: U33.32 151.26,31.79 149.47,30 149.47,28.2 149.78,27.9 v3(149.78,27.82)
HP_OUT_L2: length 7.5
  TOP w0.102: AB7.2 C255.2 D14.C 147.95,23.15 151.58,23.15 152.06,22.67 AUDR1.4
HP_OUT_R2: length 16.6
  BOTTOM w0.102: AUDR1.3 156.18,23.13 D20.C 156,24.08 155.55,23.63 152.7,23.63 C549.2 152.01,23.66 151.76,23.66 151.4,23.3 149.32,23.3 148.56,22.54 148.56,17.08 147.92,16.44 AB17.2
HP_R: length 16.7
  L3_IN1 w0.102: v3(146.09,21.32) 146.22,21.32 147.01,22.11 147.01,25.44 149,27.43 149,27.63 v3(149.22,27.85)
  BOTTOM w0.102: v3(146.09,21.32) 146.09,18.85 146.45,18.5 AR14.2 ; v3(149.22,27.85) 149.24,27.87 149.24,30.1 150.86,31.72 U33.33
HPD_HDMI: length 11.1
  BOTTOM w0.102: HDMI1.19 151.09,102.32 149.04,102.32 R387.1 147.54,102.75 147.11,103.18 Q28.D 147.62,104.53 149.17,104.53 149.9,105.27 D15.3
IACM: length 2.6
  TOP w0.203: R20.1 16.48,98.43 C15.1 15.97,97.93 U1.2
IACP: length 2.6
  TOP w0.203: U1.3 15.57,97.97 C15.2 15.28,98.26 15.28,98.98 15.08,99.19 R17.1
ICHP: length 24.7
  TOP w0.203: U1.38 18.04,95.55 18.38,95.89 v3(18.38,95.87)
  L3_IN1 w0.203: v3(9.09,80.4) 12.75,80.4 17.47,85.13 17.47,90.33 18.71,91.57 18.71,95.54 v3(18.38,95.87)
  BOTTOM w0.203: R471.1 8.33,79.76 8.96,80.4 v3(9.09,80.4)
  vias: v4(7.04,86.62) v4(7.06,87.57) v4(7.05,85.59) v4(8.09,87.62) v4(8.05,86.62) v4(8.05,85.61)
INT_MIC: length 1.9
  BOTTOM w0.102: TP77.1 157.48,37.37 C522.2 C521.2
INT_PIRQA#: length 14.3
  TOP w0.076: U11.BB11 94.88,89.13 95.89,90.14 101.34,90.14 101.41,90.07 102.16,90.07 102.16,90.06 102.45,90.06 102.45,90.07 104.04,90.07 104.27,89.83 105.98,89.83 v2(106.32,90.18)
  BOTTOM w0.076: v2(106.32,90.18) 106.14,90.36 106.14,90.81 R431.2
INT_SERIRQ: length 132.7
  TOP w0.076: U11.AY11 94.56,87.06 94.45,87.17 94.45,88.14 94.55,88.24 94.55,89.3 95.8,90.56 101.29,90.56 101.54,90.81 103.68,90.81 103.96,90.53 104.82,90.53 105.02,90.33 v2(105.02,90.18)
  L3_IN1 w0.076: 101.84,93.58 102.12,93.3 102.28,93.3 103.22,92.36 103.22,91.85 104.38,90.7 104.5,90.7 v2(105.02,90.18)
  L3_IN1 w0.102: v3(21.23,116.77) 21.56,117.1 23.81,117.1 25.6,118.89 28,118.89 28.88,118.01 29.6,118.01 30.13,117.48 33.01,117.48 34.61,119.08 35.61,119.08 35.87,119.34 45.29,119.34 45.34,119.39 48.16,119.39 48.51,119.05 49.77,119.05 54.23,114.59 78.46,114.59 97.17,95.88 99.55,95.88 101.84,93.58
  L4_IN2 w0.102: v3(21.23,116.77) 21.23,115.2 21.46,114.96 21.46,106.01 19.2,103.75 v3(19.2,103.24)
  BOTTOM w0.102: U28.27 18.02,102.02 18.17,102.17 R389.2 18.71,102.17 19.2,102.65 v3(19.2,103.24) ; v2(105.02,90.18) 105.02,90.71 R432.1 ; v3(21.23,116.77) 21.15,116.77 20.65,116.27 U25.5
IRQ: length 3.6
  TOP w0.102: R740.2 120.9,19.64 121.48,19.06 122.51,19.06 122.74,19.29 123.32,19.29 123.48,19.45 U1634.D1
JACK_HP_L: length 2.2
  TOP w0.102: AR4.1 C256.1 AB7.1
JACK_HP_R: length 2.5
  BOTTOM w0.102: AR14.1 C550.1 147.06,16.54 AB17.1
JACK_MIC1_R_L: length 7.7
  BOTTOM w0.102: AB15.1 153.89,27.42 AR13.1 154.55,27.17 AR12.1 156.44,28.02 156.82,28.41 156.82,29 157.3,29.47 157.45,29.47 AR11.1 AR10.1
KEY_OUT0: length 10.8
  TOP w0.102: KBT1.24 8.45,114.14 S23.1 8.44,114.37 8.21,114.61 7.39,114.61 6.94,114.16 v3(5.81,114.16)
  BOTTOM w0.102: U25.36 7.47,118.32 7.33,118.19 7.33,115.22 6.28,114.16 v3(5.81,114.16) 5.43,114.54 v1(5.43,115.04)
KEY_OUT1: length 8.4
  TOP w0.102: KBT1.23 8.47,115.14 S24.1 8.44,115.49 8.3,115.62 6.8,115.62 6.42,115.24 v3(6.09,115.24)
  BOTTOM w0.102: v3(6.09,115.24) 6.1,115.25 6.1,115.25 6.5,115.64 6.5,115.66 6.83,115.98 v1(6.83,116.09) 7.13,116.39 7.13,118.35 7.51,118.72 U25.37
KEY_OUT2: length 8.8
  TOP w0.102: v3(6.14,116.37) 6.31,116.54 8.33,116.54 8.44,116.42 S22.1 8.45,116.14 KBT1.22
  BOTTOM w0.102: v1(5.28,117.23) 6.14,116.37 v3(6.14,116.37) 6.19,116.37 6.9,117.08 6.9,118.63 7.4,119.12 U25.38
KEY_OUT3: length 8.9
  TOP w0.102: v3(6.12,117.56) 6.18,117.62 8.37,117.62 8.47,117.52 S21.1 8.48,117.14 KBT1.21
  BOTTOM w0.102: U25.39 7.43,119.52 6.62,118.72 6.62,118.07 v3(6.12,117.56) 6.06,117.61 6.04,117.61 5.41,118.25 v1(4.26,118.25)
KEY_OUT4: length 7.3
  TOP w0.102: KBT1.20 S20.1 8.44,118.52 8.34,118.62 6.3,118.62 v3(6.14,118.77)
  BOTTOM w0.102: U25.40 7.54,119.92 6.39,118.77 v3(6.14,118.77) 5.77,118.77 v1(5.15,119.39)
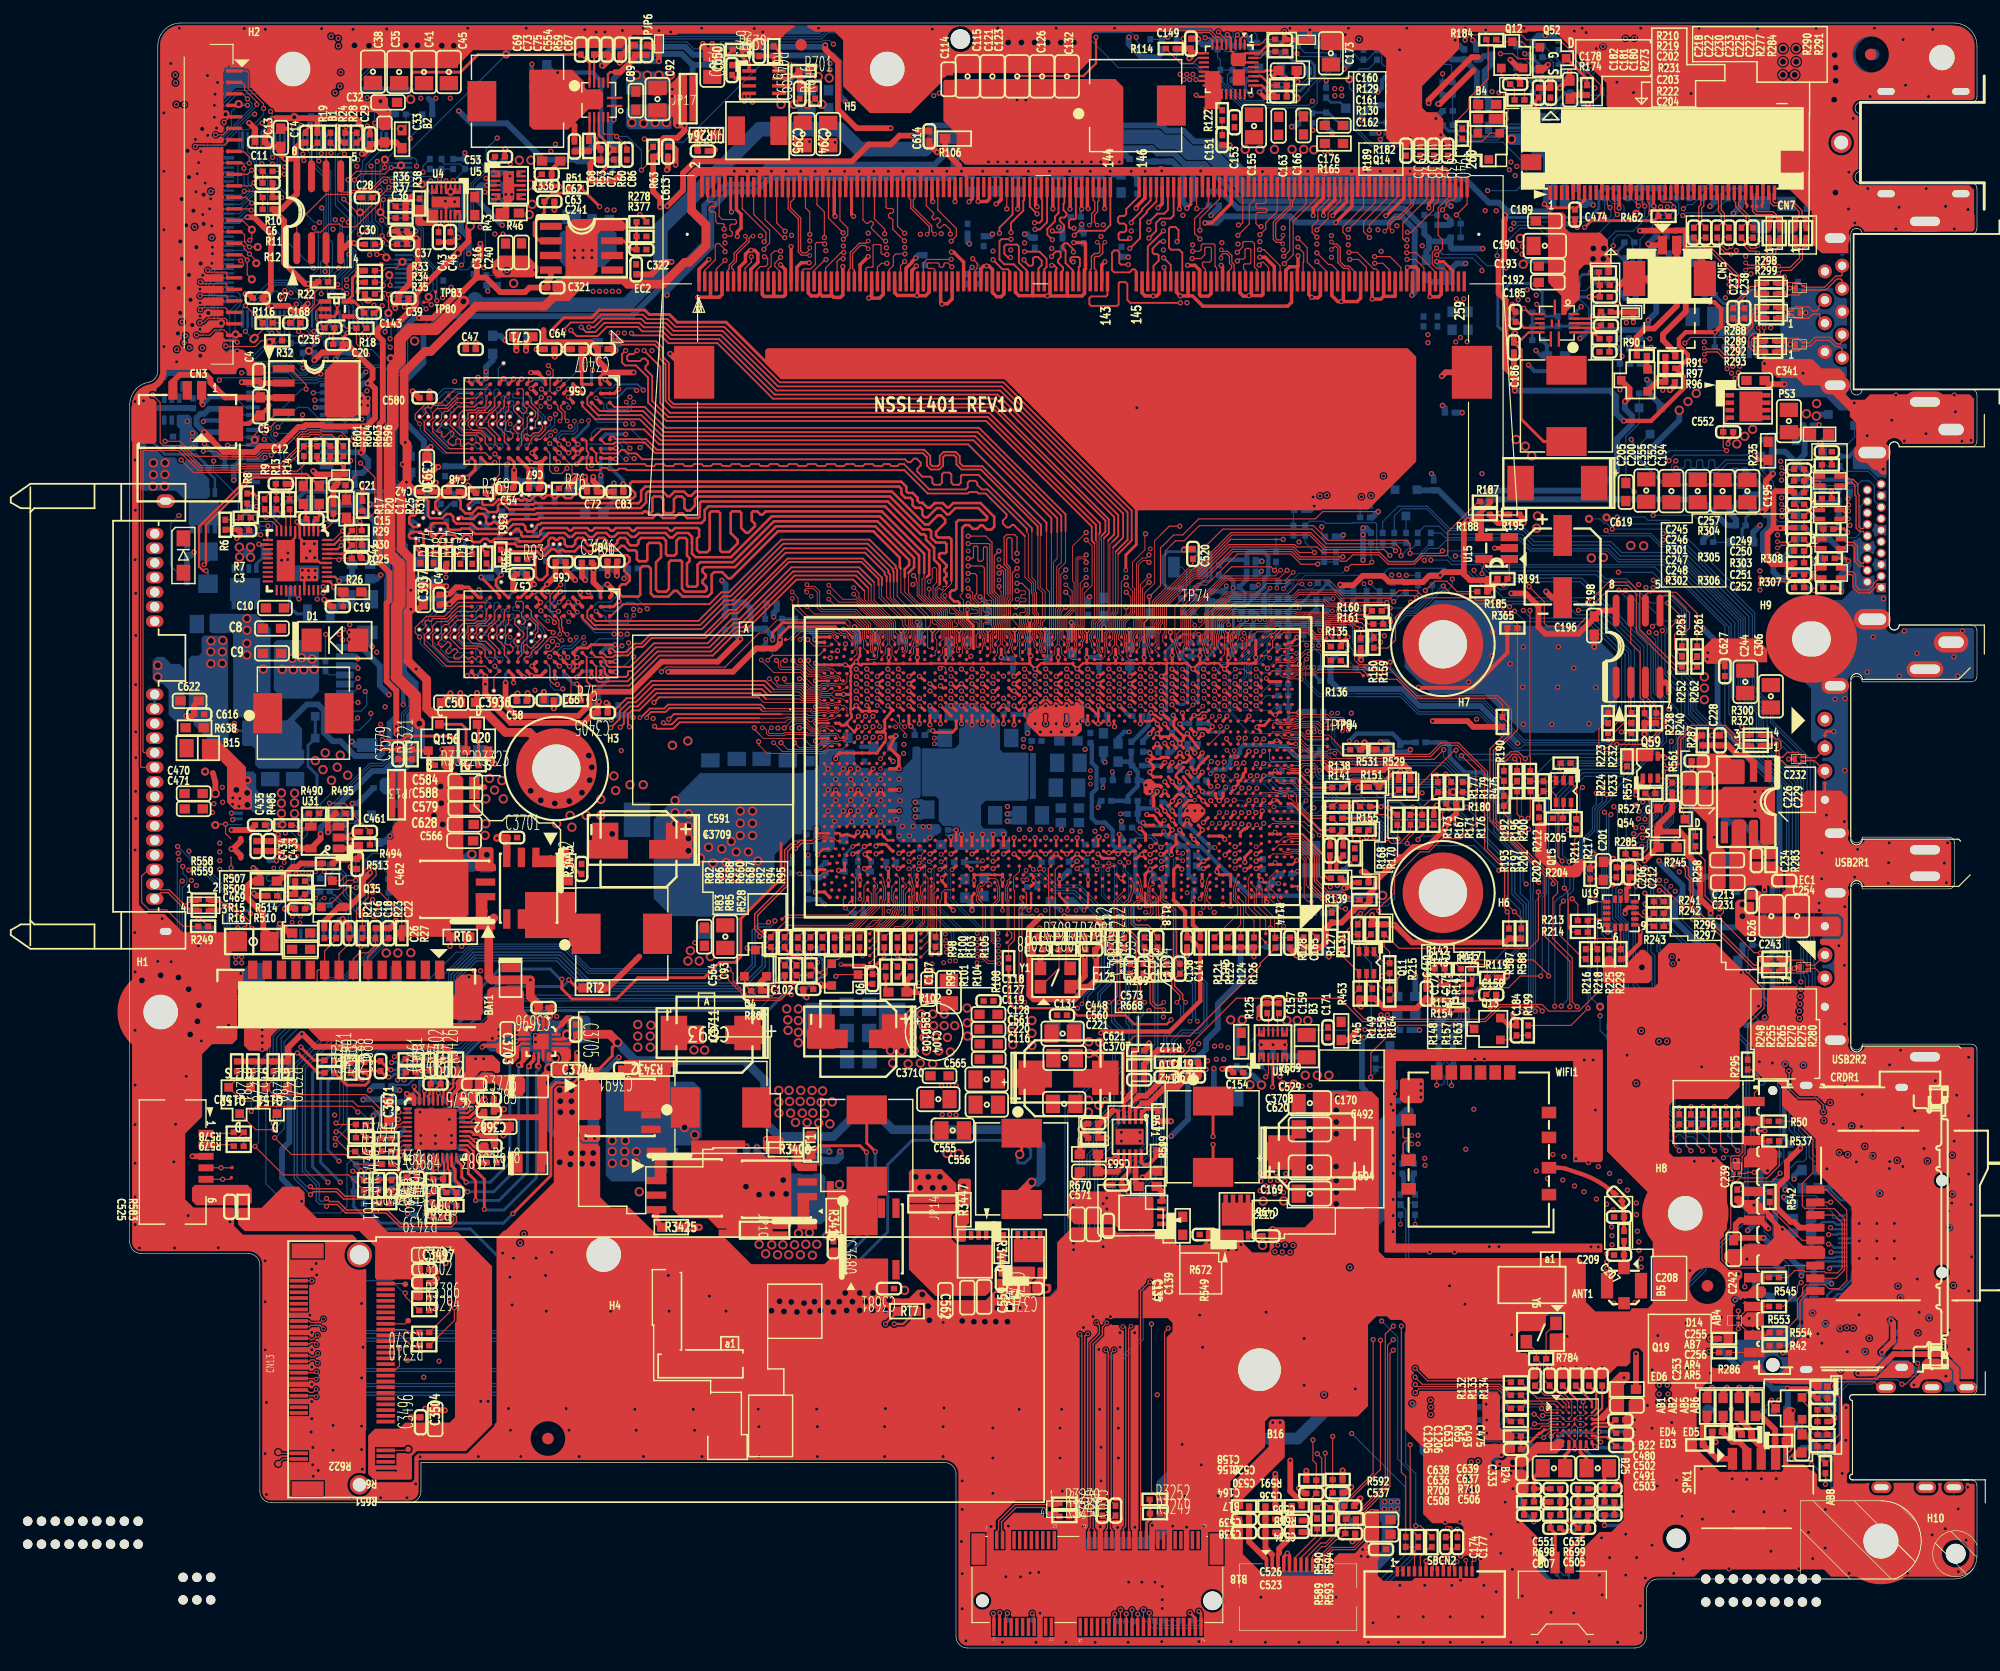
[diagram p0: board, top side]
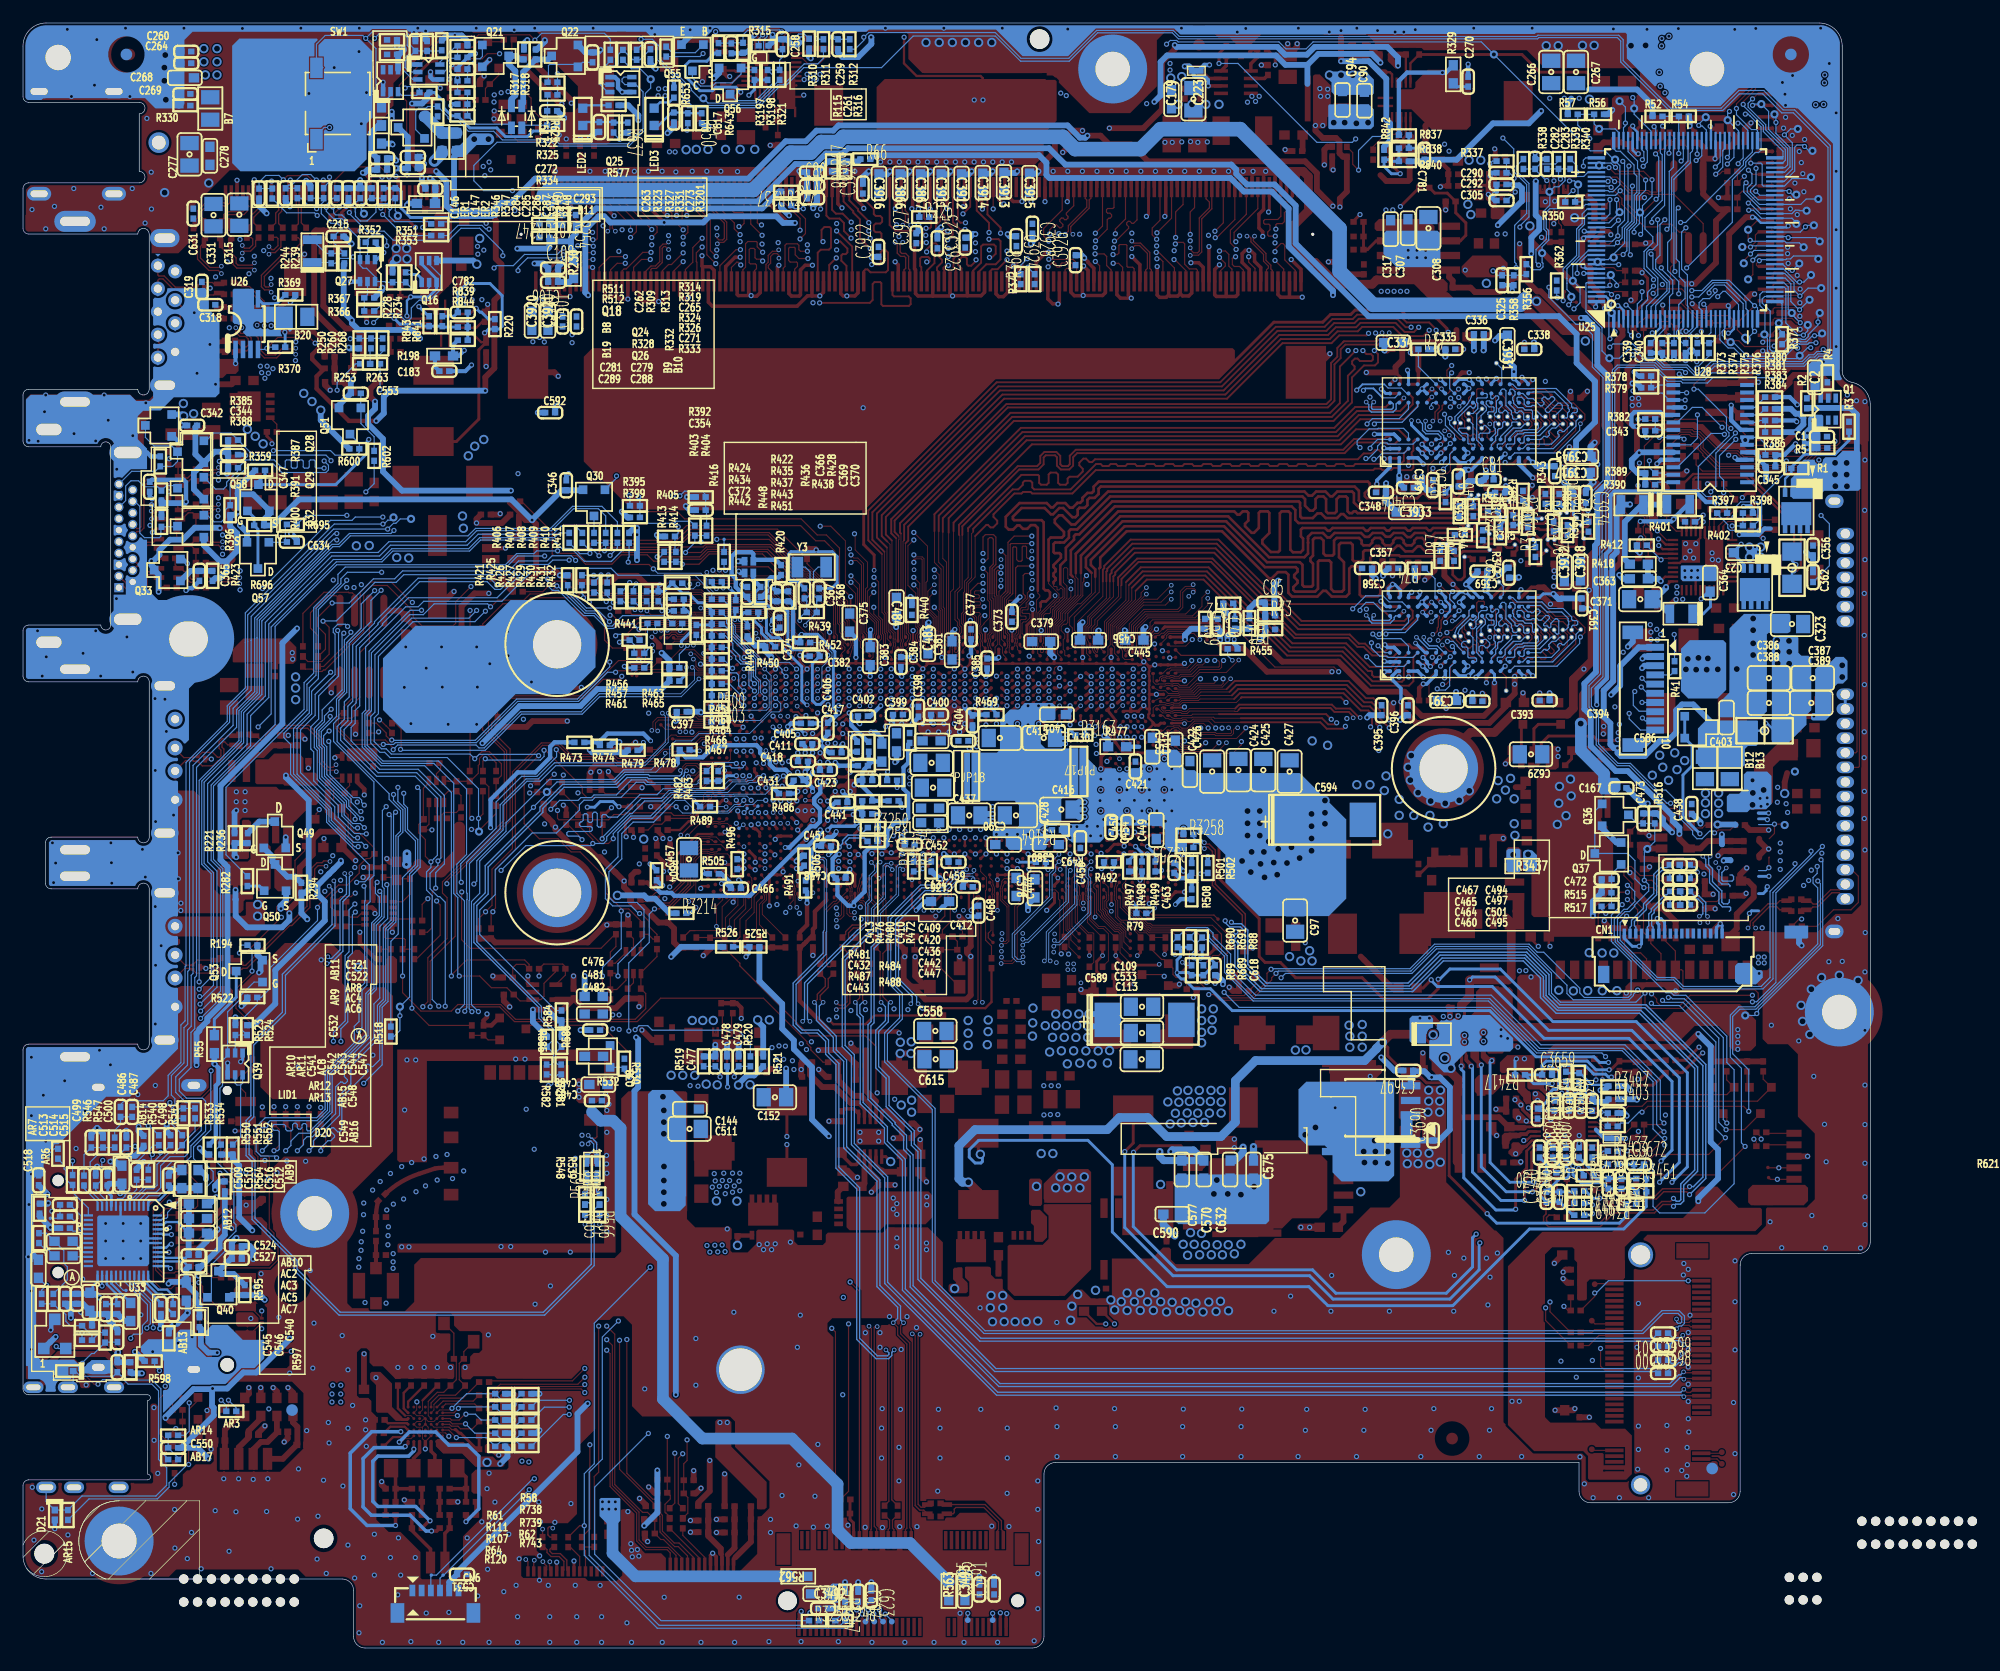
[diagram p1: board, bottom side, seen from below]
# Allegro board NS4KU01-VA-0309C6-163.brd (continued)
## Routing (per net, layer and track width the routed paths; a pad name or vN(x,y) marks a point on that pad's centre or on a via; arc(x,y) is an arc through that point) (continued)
KEY_OUT5: length 5.4
  TOP w0.102: v3(6.78,119.79) 6.93,119.64 8.35,119.64 8.44,119.55 S19.1 8.46,119.14 KBT1.19
  BOTTOM w0.102: U25.41 7.62,120.32 7.08,119.79 v3(6.78,119.79) 6.76,119.79 v1(6.17,120.39)
KEY_OUT6: length 6.7
  TOP w0.102: KBT1.18 9.79,120.14 9.89,120.24 9.89,120.39 v3(9.64,120.63)
  BOTTOM w0.102: v1(4.52,120.79) 4.77,121.04 6.68,121.04 6.93,120.79 7.29,120.79 7.35,120.72 U25.42 9.55,120.72 v3(9.64,120.63)
KEY_OUT7: length 5.2
  TOP w0.102: KBT1.17 9.75,121.14 v3(10.21,120.68) 10.21,119.41 v1(10.61,119.01)
  BOTTOM w0.102: v3(10.21,120.68) 9.76,121.12 U25.43
KEY_OUT8: length 5.1
  TOP w0.102: v1(10.99,120.41) 10.99,120.63 v3(10.41,121.21) 9.93,121.7 9.93,121.9 9.69,122.14 KBT1.16
  BOTTOM w0.102: U25.44 10.1,121.52 v3(10.41,121.21)
KEY_OUT9: length 5.1
  TOP w0.102: v1(11.12,121.82) v3(10.41,121.82) 9.98,122.25 9.98,122.86 9.7,123.14 KBT1.15
  BOTTOM w0.102: v3(10.41,121.82) 10.31,121.92 U25.45
KEY_OUT10: length 7.8
  TOP w0.102: v3(10.44,122.41) 10.61,122.58 v1(10.61,123.33) 9.8,124.14 KBT1.14
  BOTTOM w0.102: v3(10.44,122.41) 10.36,122.32 U25.46 7.44,122.32 7.3,122.18 6.17,122.18 v1(5.79,121.8)
KEY_OUT11: length 6.2
  TOP w0.102: KBT1.13 10.45,125.14 v3(10.56,125.02)
  BOTTOM w0.102: v1(6.42,123.83) 6.42,123.94 6.8,124.32 U25.51 9.46,124.32 10.16,125.02 v3(10.56,125.02)
KEY_OUT12: length 7.3
  TOP w0.102: KBT1.12 10.1,126.14 v3(10.6,125.64)
  BOTTOM w0.102: v1(5.53,124.98) 6.14,124.98 6.19,125.02 6.51,125.02 6.8,124.72 U25.52 9.55,124.72 10.47,125.64 v3(10.6,125.64)
KEY_OUT13: length 6
  TOP w0.102: v3(10.79,127.41) 10.52,127.14 KBT1.11
  BOTTOM w0.102: U25.53 9.52,125.12 11,126.6 11,127.21 v3(10.79,127.41)
KEY_OUT14: length 10.7
  TOP w0.102: KBT1.10 10.23,128.14 v3(10.59,128.5)
  BOTTOM w0.102: v1(4.52,125.99) 5.57,125.99 6.04,125.52 U25.54 9.63,125.52 10.69,126.58 10.69,126.95 10.28,127.36 10.28,128.2 v3(10.59,128.5)
KEY_OUT15: length 5.9
  TOP w0.102: KBT1.9 9.75,129.14 9.93,128.96 v3(9.93,128.66)
  BOTTOM w0.102: v3(9.93,128.66) 9.93,127.28 10.41,126.8 10.41,126.59 9.74,125.92 U25.55
KEYIN0: length 10.1
  TOP w0.102: v3(10.39,129.11) 10.39,129.66 9.9,130.14 KBT1.8 8.45,130.14 S7.1
  BOTTOM w0.102: v1(5.15,127.9) 5.28,127.77 6.8,127.77 7.45,127.12 U25.58 9.29,127.12 9.4,127.23 9.4,129.01 9.5,129.11 v3(10.39,129.11)
KEYIN1: length 9.8
  TOP w0.102: KBT1.7 8.47,131.14 S6.1 8.47,130.88 8.28,130.69 5.83,130.69 v3(5.71,130.56)
  BOTTOM w0.102: v1(5.03,130.18) 5.33,130.18 v3(5.71,130.56) 5.84,130.69 6.37,130.69 6.57,130.49 6.57,128.43 7.48,127.52 U25.59
KEYIN2: length 8.5
  TOP w0.102: v3(7.47,131.58) 8.12,131.58 8.44,131.9 S5.1 8.46,132.14 KBT1.6
  BOTTOM w0.102: U25.60 7.43,127.92 6.77,128.59 6.77,130.88 v3(7.47,131.58) 7.44,131.58 6.93,132.09 v1(6.3,132.09)
KEYIN3: length 7.9
  TOP w0.102: KBT1.5 8.46,133.14 S4.1 8.44,132.9 v3(8.2,132.65)
  BOTTOM w0.102: U25.61 7.44,128.32 6.98,128.79 6.98,130.48 8.2,131.7 v3(8.2,132.65) 8.2,133.23 v1(8.33,133.36)
KEYIN4: length 9.4
  TOP w0.102: v3(10.23,134.14) 10.23,134.14 KBT1.4
  BOTTOM w0.102: v3(10.23,134.14) 10.13,134.25 v1(9.47,134.25) 8.84,133.61 8.84,132.05 7.18,130.39 7.18,128.97 7.42,128.72 U25.62
KEYIN5: length 9.2
  TOP w0.102: KBT1.3 9.79,135.14 v3(10.23,134.7)
  BOTTOM w0.102: v3(10.23,134.7) 10.61,134.32 10.61,133.98 9.09,132.46 9.09,132.01 7.38,130.31 7.38,129.36 7.62,129.12 U25.63
KEYIN6: length 9.8
  TOP w0.102: KBT1.2 9.74,136.14 9.98,135.9 9.98,135.52 11.05,134.45 v3(11.05,134.22)
  BOTTOM w0.102: U25.64 7.71,129.57 7.59,129.7 7.59,130.16 9.29,131.86 9.29,132.37 10.93,134.01 10.93,134.11 v3(11.05,134.22)
KEYIN7: length 8.8
  TOP w0.102: KBT1.1 10.18,137.14 10.28,137.04 10.28,135.61 11.63,134.27 v3(11.63,133.87)
  BOTTOM w0.102: v3(11.63,133.87) 11.63,133.33 10.33,132.03 9.9,132.03 9.8,131.93 U25.65
LAN_TXN: length 3.4
  TOP w0.114: C174.1 114.55,8.78 114.75,8.58 114.75,8.41 114.54,8.21 113.84,8.21 113.28,7.64 113.28,6.79 SBCN2.7
LAN_TXP: length 3.4
  TOP w0.114: C177.1 115.23,8.78 115,8.55 115,8.3 114.65,7.95 113.95,7.95 113.53,7.54 113.53,6.79 SBCN2.8
LANPHYPC: length 37.5
  TOP w0.076: 94.14,93.58 93.16,92.59 92.83,92.59 TP18.1 90.83,90.59 90.83,87.76 90.85,87.73 90.88,87.65 90.88,87.53 90.82,87.31 90.82,87.17 90.87,87.01 90.87,86.93 91.09,86.23 91.09,86.23 91.26,86.05 U11.AW17
  TOP w0.102: 94.14,93.58 95.9,95.33 100.98,95.33 101.64,94.67 105.09,94.67 105.27,94.5 105.73,94.5 106.29,95.05 108.55,95.05 109.36,94.24 111.65,94.24 112.38,94.98 114.4,94.98 114.55,95.13 114.55,97.04 117.22,99.7 R187.1
LDRENB: length 17.8
  TOP w0.254: U109.19 27.98,41.92 28.28,41.62 28.28,40.69 29.3,39.67 v3(29.36,39.67)
  BOTTOM w0.254: v3(33.8,50.7) 33.8,41.83 31.64,39.67 v3(29.36,39.67)
LDRENC: length 20.8
  TOP w0.254: U109.21 29.21,43.31 29.42,43.1 29.42,41.26 30.06,40.63 v3(30.06,38.91) ; U110.9 35.14,51.17 34.67,50.7 v3(34.67,50.59)
  BOTTOM w0.254: v3(30.06,38.91) 32.09,38.91 34.57,41.39 34.57,50.48 v3(34.67,50.59)
LED2_VIN: length 2.3
  BOTTOM w0.203: LED2.A 111.64,134.14 R577.1
LED3_VIN: length 2.1
  BOTTOM w0.203: LED3.A 105.18,134.4 104.39,134.4 R653.1
LED_3V3: length 5.4
  TOP w0.305: SBCN1.2 99.29,8.11
  TOP w0.508: 99.29,8.11 98.7,8.7 C523.1 C526.1 B16.2
LID#: length 264.5
  TOP w0.102: v3(19.01,56.88) 18.56,56.44 18.56,56.18 18.25,55.87 16.53,55.87 15.64,56.76 v3(10.25,56.76)
  L3_IN1 w0.102: v3(117.18,16.24) 116.54,16.88 113.69,16.88 111.53,19.04 98.21,19.04 92.67,24.57 30.83,24.57 26.02,29.39 26.02,33.25 22.21,37.06 15.1,37.06 8.21,43.95 8.21,54.84 10.12,56.76 v3(10.25,56.76)
  L4_IN2 w0.102: v3(15.63,114.07) 15.67,114.04 15.67,110.42 16.74,109.34 16.74,106.24 17.22,105.77 17.22,103.09 18.13,102.18 20.39,102.18 22.55,100.02 22.55,83.41 22.95,83.01 22.95,81.2 22.55,80.81 22.55,77.76 22.03,77.24 22.03,61.72 19.01,58.7 19.01,56.89 v3(19.01,56.88) ; v3(117.18,16.24) 117.43,16.5 117.43,22.4 119.81,24.77 132.52,24.77 136.11,21.19 141.79,21.19 142.71,22.11 143.33,22.11 143.7,21.74 145.49,21.74 145.8,22.06 146.63,22.06 148.68,24.1 v3(148.68,24.11) 149.52,24.95 152.22,24.95 152.81,25.54 157.33,25.54 157.65,25.87 v3(157.65,26.22)
  BOTTOM w0.102: v3(148.68,24.11) 149.1,24.53 R598.2 ; U25.19 15.05,114.9 15.63,114.31 v3(15.63,114.07) ; v3(157.65,26.22) 157.47,26.04 LID1.3
LID_3V3: length 5.6
  TOP w0.305: SBCN1.3 99.79,7.89 99.8,7.9 99.8,8.15 99.89,8.24
  TOP w0.508: 99.89,8.24 99.89,8.65 100.99,9.74 C538.1 C539.1 B17.2
LINE_OUT_IN#: length 11.2
  TOP w0.102: AB8.2 v3(147.36,14.23)
  L4_IN2 w0.102: v3(147.36,14.23) 147.34,14.21 147.34,13.39 147.82,12.91 155.05,12.91 AUDR1.5
LPC_AD0: length 217.4
  L4_IN2 w0.102: v3(110.94,93.28) 112.06,94.39 112.06,104.9 113.53,106.37 113.53,108.02 117.06,111.56 117.06,119.85 118.65,121.44 118.65,124.1 118.45,124.3 117.84,124.3 117.39,124.74 117.39,125.93 116.54,126.78 114.93,126.78 114.72,126.99 95.86,126.99 93.86,128.99 88.89,128.99 88.12,129.76 73.8,129.76 73.03,128.99 72.22,128.99 70.91,127.68 69.15,127.68 68.88,127.41 48.16,127.41 47.42,126.68 45.64,126.68 44.98,126.01 35.87,126.01 35.56,126.32 34.09,126.32 33.02,125.26 29.08,125.26 28.95,125.13 23.48,125.13 23.33,124.98 23.31,124.98 23.11,124.78 18.07,124.78 17.85,124.56 v3(17.85,124.2) 17.35,124.2 16.26,123.11 15.02,123.11 13.05,121.14 13.05,119.59 11.55,118.09 11.55,112.33 12.24,111.65 12.24,108.88 12.5,108.62 12.5,105.72 v3(12.68,105.53) 11.4,104.25 10.89,104.25 7.31,100.68 7.31,98.09 6.58,97.37 6.58,94.88 6.02,94.32 6.02,93.95 6.25,93.72 6.25,92.38 6.89,91.74 8.74,91.74 13.46,87.03 15.73,87.03 16.84,85.93 16.84,83.26 19.23,80.87 v3(19.8,80.87)
  BOTTOM w0.102: R425.2 111.71,93.28 111.71,93.28 v3(110.94,93.28) ; v3(17.85,124.2) 18.28,123.77 18.28,121.09 18.65,120.72 18.65,119.97 17.47,118.79 17.47,117.92 18.65,116.74 U25.10 ; v3(19.8,80.87) 19.55,80.61 CN8.9 ; v3(12.68,105.53) 12.76,105.61 13.83,105.61 16.77,102.67 U28.26
LPC_AD0_SOC: length 23.9
  TOP w0.076: U11.AY13 93.69,86.76 93.58,86.87 93.48,86.98 93.41,87.19 93.41,87.31 93.47,87.54 93.47,87.68 93.42,87.8 93.42,88.07 93.61,88.27 93.61,88.47 93.72,88.59 93.72,89.75 95.47,91.5 101.06,91.5 101.57,92.01 104.85,92.01 105.35,91.5 106.6,91.5
  TOP w0.102: v3(111.83,91.32) 111.66,91.5 106.6,91.5
  BOTTOM w0.102: v3(111.83,91.32) 111.83,91.55 111.96,91.68 R425.1
LPC_AD1: length 205.4
  L4_IN2 w0.102: v3(20.47,83.17) 20.46,83.18 19.32,83.18 18.26,84.24 18.26,85.94 16.13,88.07 14,88.07 7.91,94.16 7.91,97.23 8.96,98.28 8.96,99.85 10.97,101.86 12.8,101.86 14.82,103.88 14.82,107.02 v3(15.02,107.23) 15.02,108.78 14.4,109.4 14.4,112.88 13.99,113.28 13.99,114.87 15.96,116.84 15.96,119.46 15.58,119.84 15.58,120.59 16.2,121.21 v3(19.05,121.21) 20.11,121.21 20.7,121.8 23.49,121.8 23.84,122.16 29.17,122.16 29.77,122.77 30.52,122.77 31.1,123.34 34.48,123.34 34.89,123.76 44.24,123.76 44.94,124.46 44.94,125.4 45.81,126.27 47.59,126.27 48.32,127.01 69.05,127.01 69.32,127.27 71.08,127.27 71.63,127.82 94.45,127.82 95.69,126.58 114.55,126.58 115.89,125.24 115.89,121.13 116.66,120.37 116.66,111.85 113.13,108.31 113.13,106.54 111.65,105.06 111.65,95.02 110.52,93.89 110.26,93.89 v3(109.67,93.3)
  BOTTOM w0.102: U28.23 15.59,104.62 15.02,105.19 v3(15.02,107.23) ; v3(19.05,121.21) 18.89,121.05 18.89,119.92 17.67,118.7 17.67,118 19.05,116.63 U25.9 ; v3(20.47,83.17) 20.6,83.05 20.6,81.97 20.09,81.46 18.74,81.46 CN8.8 ; v3(109.67,93.3) 109.77,93.2 R427.2
LPC_AD1_SOC: length 19.9
  TOP w0.076: U11.BA13 93.69,87.46 93.95,87.72 93.95,88.35 94.05,88.45 94.05,89.57 95.65,91.17 101.19,91.17 101.63,91.6 104.74,91.6 105.43,90.91 106.6,90.91
  TOP w0.102: v3(109.24,90.91) 106.6,90.91
  BOTTOM w0.102: R427.1 109.77,91.5 109.24,90.97 v3(109.24,90.91)
LPC_AD2: length 210.4
  L4_IN2 w0.102: v3(110.31,93.3) 111.86,94.85 111.86,104.98 113.33,106.45 113.33,108.19 116.86,111.72 116.86,120.45 116.1,121.21 116.1,125.32 114.64,126.79 95.78,126.79 94.54,128.02 71.54,128.02 71,127.48 69.24,127.48 68.97,127.21 48.24,127.21 47.5,126.47 45.73,126.47 45.04,125.78 35.76,125.78 35.42,126.12 34.17,126.12 33.1,125.05 29.16,125.05 29.04,124.93 23.57,124.93 23.21,124.57 18.86,124.57 v3(18.48,124.2) 18.48,123.6 17.79,122.91 15.11,122.91 13.26,121.06 13.26,119.5 11.76,118.01 11.76,112.42 12.44,111.73 12.44,108.97 12.81,108.59 12.81,106.21 v3(12.88,106.15) 13.06,105.97 13.06,105.38 11.73,104.05 10.97,104.05 7.51,100.59 7.51,97.98 7.1,97.56 7.1,93.68 13.52,87.26 15.79,87.26 17.09,85.96 17.09,83.58 18.44,82.22 v3(19.84,82.22)
  BOTTOM w0.102: CN8.7 19.83,82.21 v3(19.84,82.22) ; v3(110.31,93.3) 110.53,93.07 110.53,93.07 110.92,92.69 R426.2 ; U28.20 16.77,106.57 15.47,107.87 14.6,107.87 v3(12.88,106.15) ; v3(18.48,124.2) 18.48,122.02 18.91,121.59 19.21,121.59 19.43,121.37 19.43,120.11 18.46,119.14 18.46,117.66 19.43,116.68 19.45,116.68 U25.8
LPC_AD2_SOC: length 20.4
  TOP w0.076: 106.6,91.3 105.3,91.3 104.79,91.8 101.6,91.8 101.13,91.33 95.56,91.33 93.89,89.66 93.89,88.52 93.79,88.42 93.79,88.21 93.69,88.11 U11.BB13
  TOP w0.102: 106.6,91.3 109.54,91.3 v3(109.85,90.99)
  BOTTOM w0.102: R426.1 110.64,91.78 v3(109.85,90.99)
LPC_AD3: length 197.4
  L4_IN2 w0.102: v3(107.82,92.64) 106.8,93.66 106.8,98.03 108.66,99.88 108.66,101.05 109.44,101.84 109.44,104.29 112.11,106.96 112.11,110.36 114,112.25 114,119.34 114.86,120.19 114.86,121.99 111.28,125.57 95.27,125.57 94.03,126.8 72.05,126.8 71.5,126.26 69.74,126.26 69.47,125.99 48.75,125.99 45.44,122.69 35.56,122.69 33.93,121.06 30.25,121.06 29.85,120.66 23.84,120.66 22.47,119.29 20.62,119.29 20.47,119.13 19.55,119.13 v3(18.84,118.42) 17.66,117.24 17.66,116.4 18.56,115.49 18.56,110.67 19.67,109.57 20.36,109.57 v3(20.62,109.31) ; v3(20.96,81.26) 21.21,81.51 21.21,83.34 20.6,83.94 19.45,83.94 18.87,84.52 18.87,86.19 17.42,87.64 17.42,88.29 16.83,88.88 14.34,88.88 8.72,94.5 8.72,96.89 9.78,97.94 9.78,99.52 11.31,101.05 13.14,101.05 15.8,103.72 15.8,105.71 16.53,106.43 16.53,108.06 v3(16.09,108.51)
  BOTTOM w0.102: CN8.10 19.97,79.81 20.96,80.8 v3(20.96,81.26) ; v3(20.62,109.31) 20.43,109.12 18.08,109.12 17.48,108.52 U28.17 16.1,108.52 v3(16.09,108.51) ; v3(18.84,118.42) 18.84,118.39 19.35,117.88 19.35,117.23 19.85,116.74 U25.7 ; v3(107.82,92.64) 107.82,92.54 108.48,91.88 R429.2
LPC_AD3_SOC: length 19.4
  TOP w0.076: U11.AY12 94.26,86.47 93.95,86.77 93.95,87.2 94.12,87.36 94.12,88.28 94.22,88.38 94.22,89.48 95.74,91 101.26,91 101.4,91.14 103.93,91.14 104.21,90.86 105.23,90.86 105.4,90.69 106.6,90.69
  TOP w0.102: v2(107.36,90.28) 107.36,90.41 107.08,90.69 106.6,90.69
  BOTTOM w0.102: R429.1 108.38,91.02 107.87,90.51 107.44,90.51 107.36,90.43 v2(107.36,90.28)
LPC_FRAME#: length 186.4
  L4_IN2 w0.102: v2(107.26,92.54) 106.6,93.2 106.6,98.11 108.45,99.97 108.45,103.88 111.66,107.08 111.66,110.48 113.6,112.42 113.6,119.5 114.45,120.36 114.45,121.82 111.11,125.16 95.1,125.16 93.86,126.4 76.88,126.4 75.66,125.17 69.36,125.17 68.97,125.56 48.89,125.56 45.61,122.28 35.73,122.28 34.09,120.65 30.42,120.65 28.65,118.88 20.9,118.88 19.96,117.94 v3(19.83,117.94) 19.76,117.87 19.76,113.96 21.1,112.61 21.1,106.16 20.72,105.78 18.84,105.78 v3(18.33,105.27) ; v3(16.18,105.11) 16.18,103.81 13.22,100.85 11.39,100.85 9.98,99.43 9.98,97.86 8.93,96.8 8.93,94.58 14.42,89.09 16.91,89.09 17.62,88.37 17.62,87.73 19.07,86.28 19.07,85.08 v3(19.83,84.32)
  BOTTOM w0.102: v3(19.83,117.94) 19.86,117.91 19.86,117.25 20.25,116.86 U25.6 ; R430.2 107.49,92.24 107.26,92.46 v2(107.26,92.54) ; v3(16.18,105.11) 16.34,105.27 U28.22 v3(18.33,105.27) ; v3(19.83,84.32) 19.33,83.81 CN8.5
LPC_FRAME#_SOC: length 17
  TOP w0.076: 106.6,90.48 106.51,90.48 106.48,90.52 105.32,90.52 105.14,90.7 104.08,90.7 103.8,90.98 101.47,90.98 101.31,90.81 95.8,90.81 94.38,89.39 94.38,88.31 94.28,88.21 94.28,86.95 U11.BA12
  TOP w0.102: v2(106.85,90.25) 106.62,90.48 106.6,90.48
  BOTTOM w0.102: v2(106.85,90.25) 106.85,90.43 107.44,91.02 R430.1
LRST1#: length 3.1
  BOTTOM w0.102: U25.14 17.05,113.49 R373.1 C340.1
LVDS_HPD: length 265.3
  TOP w0.076: v3(95.99,71.71) U11.L10
  L4_IN2 w0.076: 102.41,71.15 100.48,71.15 100.1,71.53 99,71.53 98.68,71.21 96.49,71.21 v3(95.99,71.71)
  L4_IN2 w0.102: v3(131.41,69.68) 131.06,69.32 127.97,69.32 127.74,69.55 118.43,69.55 117.87,70.11 113.1,70.11 112.06,71.15 102.41,71.15 ; v3(4.54,115.3) 4.54,121.7 6.17,123.33 6.17,123.64 7.67,125.14 7.67,129.87 9.78,131.99 12.47,131.99 14.07,133.59 20.87,133.59 20.87,133.59 21.69,133.59 21.69,133.59 22.31,132.98 39.63,132.98 40.71,134.06 51.46,134.06 52.09,133.43 66.52,133.43 67.44,134.35 70.92,134.35 73.79,137.22 89.26,137.22 89.66,137.63 92.31,137.63 92.83,138.14 100.34,138.14 100.63,137.85 101.97,137.85 102.76,138.64 109.32,138.64 110.03,139.35 113.14,139.35 113.47,139.02 119.76,139.02 120.72,138.06 123.52,138.06 125.55,136.03 127.96,136.03 130.12,133.87 130.12,127.58 130.53,127.17 130.53,125.16 130.9,124.79 131.36,124.79 132.27,123.88 v3(133,123.88) 133.1,123.88 134.36,122.62 134.36,111.78 132.84,110.26 132.84,105.14 132.14,104.44 132.14,99.95 131.7,99.5 131.7,96.96 132.41,96.25 v3(132.41,92.85)
  BOTTOM w0.102: R371.2 7.21,113.83 6.02,113.83 5.97,113.78 5.65,113.78 5.38,114.05 5.38,114.21 4.54,115.05 v3(4.54,115.3) 4.54,115.94 v1(4.39,116.09) ; v3(132.41,92.85) 132.41,92.77 134.87,90.3 134.87,84.29 135.66,83.5 135.66,81.31 137.03,79.94 137.03,76.01 133.95,72.93 133.95,71.9 131.74,69.68 v3(131.41,69.68) ; v3(133,123.88) 133.78,123.88 134.62,124.72 134.62,125.56 134.41,125.77 R347.1 R346.2
LVDS_VIN: length 152.6
  TOP w0.102: R174.2 121.22,135.38 121.48,135.65 121.48,136.66 121.87,137.04 121.87,138.09 121.77,138.19 120.63,138.19 120.19,138.63 v3(119.12,138.63)
  L4_IN2 w0.102: v3(119.12,138.63) 118.32,137.82 114.86,137.82 114.25,138.44 102.84,138.44 102.06,137.65 100.55,137.65 100.26,137.94 92.92,137.94 92.4,137.42 89.75,137.42 89.34,137.02 73.87,137.02 71,134.15 67.53,134.15 66.6,133.22 51.9,133.22 51.27,133.85 40.99,133.85 39.91,132.77 22.22,132.77 21.61,133.38 21.61,133.39 20.96,133.39 20.95,133.38 14.15,133.38 12.55,131.78 9.87,131.78 7.87,129.79 7.87,125.05 6.37,123.55 6.37,123.23 4.98,121.83 4.98,114.94 4.47,114.44 4.47,113.75 v3(4.72,113.5)
  BOTTOM w0.102: v3(4.72,113.5) 5.31,113.5 5.43,113.37 6.14,113.37 6.18,113.42 6.58,113.42 7.44,112.55 8.71,112.55 8.94,112.78 8.94,112.97 8.94,113.88 9.2,114.15 v1(9.2,114.22) 9.16,114.27 9.16,116.3 9.6,116.74 9.6,117.69 9.36,117.92 U25.35
M2_WLAN_WAKE#: length 3.7
  TOP w0.254: CN14.55 88.35,10.35 88.37,10.37 88.37,10.88 88.67,11.19 R3249.1 88.67,12.89 R3252.1
M_A_A0: length 95.4
  TOP w0.076: U11.AY50 72.77,86.76 72.57,86.96 72.49,87.17 72.49,87.31 72.56,87.54 72.56,87.68 72.54,87.71 72.53,87.72 72.5,87.8 72.5,88.06 72.68,88.24 72.68,88.72 72.17,89.23 72.17,89.93 70.85,91.25 v2(70.85,91.51)
  TOP w0.102: TB17.1 29,87.92 29.41,88.33 29.41,88.76 29.52,88.88 30.09,88.88 30.29,89.09 30.9,89.09 31.33,89.52 U1636.P3 ; TC17.1 29,106.46 29.41,106.87 29.41,107.31 29.52,107.42 30.09,107.42 30.29,107.63 30.9,107.63 31.33,108.06 U1637.P3
  TOP w0.229: TA16.1 28.44,95.14 R257.2
  L3_IN1 w0.292: v2(70.85,91.51) 69.56,90.22 65.87,90.22 64.86,91.24 64.86,92.43 63,94.28 39.39,94.28 39.06,93.95 33.54,93.95 33,94.49 31.8,94.49 30.9,93.58 30.33,93.58 29.8,93.05 28.62,93.05 28.43,93.24 28.43,94.06 27.85,94.65 26.63,94.65 26.32,94.96 26.32,95.32 26.39,95.4 28.12,95.4 TA16.1
  L4_IN2 w0.102: TC17.1 29,103.91 28.4,103.32 28.4,98.93 28.2,98.73 28.2,98.05 28.47,97.78 28.47,95.83 28.15,95.51 TA16.1 28.41,95.43 28.51,95.32 28.51,90.19 28.79,89.92 28.79,88.9 28.62,88.73 28.62,87.15 28.72,87.05 29.76,87.05 29.84,87.12 29.84,87.35 29.7,87.49 29.17,87.49 29,87.66 TB17.1
  BOTTOM w0.102: TC17.1 28.85,106.28 28.85,106.1 29.01,105.94 30.16,105.94 30.27,105.82 30.8,105.82 31.33,105.29 U1638.P3 ; TB17.1 28.85,87.74 28.85,87.55 29.01,87.4 30.16,87.4 30.27,87.28 30.8,87.28 31.33,86.75 U1635.P3
M_A_A1: length 102
  TOP w0.076: U11.BB50 72.86,87.99 72.86,88.78 72.34,89.3 72.34,90.01 72.1,90.25 72.1,90.54
  TOP w0.102: TC12.1 29.76,106.94 29.41,106.58 29.41,106.29 29.82,105.88 30.54,105.88 U1637.P7 ; U1636.P7 30.54,87.33 29.82,87.33 29.41,87.74 29.41,88.04 29.76,88.39 TB12.1
  TOP w0.229: 72.1,90.54 72.1,90.88 71.98,91.01 71.64,91.01 71.29,91.35 71.29,91.8 71.46,91.97 71.69,91.97 71.84,92.12 71.84,97.89 72.02,98.07 74.4,98.07 74.51,98.17 74.51,98.37 73.76,99.12 71.75,99.12 71.21,98.58 71.02,98.58 70.48,99.12 70.14,99.12 69.34,98.32 69.09,98.32 68.88,98.53 68.88,98.98 68.74,99.12 68.74,99.12 68.72,99.14 68.27,99.14 68.04,99.37 68.04,99.83 67.85,100.01 67.4,100.01 67.06,100.35 67.06,100.8 66.87,100.99 44.81,100.99 44.44,100.63 44.44,99.78 44.21,99.55 35.19,99.55 35.09,99.44 33.01,99.44 32.59,99.86 32.05,99.86 31.58,99.39 30.73,99.39 30.63,99.49 30.63,99.83 30.52,99.94 29.94,99.94 29.39,99.39 29.39,99.21 TA13.1
  L4_IN2 w0.102: TC12.1 29.55,107.28 29.55,107.87 29.65,107.98 30.04,107.98 30.14,107.88 30.14,106.1 30.25,106 30.31,106 30.41,105.9 30.41,105.7 30.31,105.59 30.16,105.59 30.06,105.49 30.06,105.29 30.16,105.19 30.31,105.19 30.41,105.09 30.41,104.88 30.31,104.78 30.19,104.78 30.12,104.71 30.12,100.49 29.94,100.32 29.94,99.25 29.78,99.09 TA13.1 29.51,98.64 29.75,98.4 29.75,96.33 29.39,95.97 29.39,91.58 30.07,90.9 30.07,90.32 30.46,89.93 30.46,89.38 29.76,88.68 TB12.1
  BOTTOM w0.102: TB12.1 29.66,88.42 29.66,88.32 29.73,88.25 30.05,88.25 30.12,88.32 30.12,88.81 30.33,89.01 30.5,89.01 30.66,88.86 30.77,88.86 30.88,88.97 30.88,89.15 31.33,89.6 U1635.P7 ; TC12.1 29.66,106.97 29.66,106.86 29.73,106.79 30.05,106.79 30.12,106.86 30.12,107.35 30.33,107.56 30.5,107.56 30.66,107.4 30.77,107.4 30.88,107.51 30.88,107.69 31.33,108.14 U1638.P7
  BOTTOM w0.229: TA13.1 30.18,99.76 R266.2
M_A_A2: length 106.5
  TOP w0.076: 71.41,92.8 71.41,92.55 70.51,91.65 70.51,91.36 72.01,89.86 72.01,89.16 72.42,88.74 72.42,88.21 72.34,88.13 72.34,87.76 72.36,87.71 72.36,87.45 72.33,87.34 72.33,87.14 72.36,87.06 72.36,86.49 U11.AY51
  TOP w0.102: U1637.R3 30.35,108.29 29.97,107.92 28.49,107.92 27.86,107.28 27.86,106.95 27.48,106.57 TC13.1 ; U1636.R3 30.35,89.75 29.97,89.37 28.49,89.37 27.86,88.74 27.86,88.4 27.48,88.02 TB13.1
  TOP w0.229: 71.41,92.8 71.41,96.38 71.23,96.56 70.24,96.56 70.07,96.72 70.07,97.05 70.87,97.84 70.87,98.12 70.5,98.49 70.22,98.49 69.43,97.69 69.1,97.69 66.24,100.56 49.17,100.56 48.82,100.21 48.51,100.21 48.16,100.56 47.34,100.56 46.93,100.14 46.74,100.14 46.32,100.56 45.03,100.56 44.88,100.4 44.88,99.6 44.38,99.11 35.22,99.11 35.12,99.01 32.97,99.01 32.45,99.53 32.19,99.53 32.01,99.34 32.01,98.91 31.87,98.77 31.17,98.77 30.88,99.06 30.59,99.06 30.5,99.15 30.23,99.15 29.74,98.66 29.18,98.66 28.75,99.08 28.75,99.77 28.48,100.04 26.95,100.04 26.56,99.65 26.56,99.13 26.95,98.75 TA12.1
  L4_IN2 w0.102: TB13.1 27.18,87.89 27.1,87.97 27.1,88.89 26.62,89.37 26.62,98.34 TA12.1 27.03,98.75 27.03,99.02 26.95,99.11 26.5,99.11 26.38,99.23 26.38,99.49 26.49,99.59 27.13,99.59 27.23,99.69 27.23,99.89 27.13,100 26.49,100 26.38,100.1 26.38,100.3 26.49,100.4 27.13,100.4 27.23,100.5 27.23,100.71 27.13,100.81 27.01,100.81 26.92,100.9 26.92,101.13 27.01,101.21 27.12,101.21 27.23,101.33 27.23,103.8 27.5,104.07 27.5,106.41 TC13.1
  BOTTOM w0.102: U1635.R3 30.53,86.36 30.39,86.22 30.18,86.22 30.08,86.32 30.08,86.75 29.95,86.89 28.73,86.89 27.73,87.89 TB13.1 ; U1638.R3 30.53,104.9 30.39,104.76 30.18,104.76 30.08,104.86 30.08,105.3 29.95,105.43 28.73,105.43 27.73,106.43 TC13.1
  BOTTOM w0.229: TA12.1 27.07,98.67 27.89,99.48 R267.2
M_A_A3: length 99.3
  TOP w0.076: U11.BA50 72.77,86.99 72.89,86.87 72.99,86.87 73.05,86.93 73.05,88.82 72.5,89.36 72.5,90.08 72.46,90.12 72.46,91.12 72.17,91.4 72.17,91.55 72.35,91.72 72.35,91.93
  TOP w0.102: U1636.N7 32.13,86.78 31.19,87.73 31.19,88.17 TB11.1 ; TC11.1 31.19,106.71 31.19,106.27 32.13,105.32 U1637.N7
  TOP w0.229: 72.35,91.93 72.35,97.4 72.59,97.64 72.95,97.64 73.27,97.31 73.64,97.31 73.94,97.61 74.13,97.61 74.49,97.26 74.88,97.26 75.13,97.51 75.13,98.36 73.94,99.56 71.57,99.56 71.2,99.18 71.03,99.18 70.66,99.56 69.96,99.56 69.56,99.16 69.32,99.16 68.92,99.55 68.92,99.55 68.9,99.58 68.67,99.58 68.47,99.77 68.47,100.01 68.03,100.44 67.64,100.44 67.49,100.59 67.49,100.98 67.05,101.42 43.66,101.42 43.49,101.25 43.49,100.86 43.93,100.43 43.93,100.15 43.75,99.98 39.37,99.98 38.97,100.37 38.74,100.37 38.35,99.98 37.87,99.98 37.59,100.26 37.33,100.26 37.05,99.98 36.85,99.98 36.59,100.24 36.26,100.24 36,99.98 35.88,99.98 35.61,100.25 35.3,100.25 34.82,99.77 34.62,99.77 34.52,99.87 34.24,99.87 34.15,99.77 33.95,99.77 33.81,99.9 33.62,99.9 33.48,99.77 33.14,99.77 32.87,100.04 32.87,100.23 32.77,100.33 31.8,100.33 31.67,100.21 31.67,99.95 31.54,99.81 TA10.1 30.96,100.24 R269.2
  L4_IN2 w0.102: TB11.1 31.63,88.62 31.63,90.41 31.24,90.8 31.24,98.91 31.11,99.04 31.11,99.46 31.39,99.74 TA10.1 31.69,99.81 31.77,99.89 31.77,100.57 31.68,100.66 31.49,100.66 31.29,100.86 31.29,102.1 31.39,102.2 31.72,102.2 31.82,102.3 31.82,102.5 31.72,102.61 31.39,102.61 31.29,102.71 31.29,103.19 31.35,103.25 31.35,103.98 31.63,104.26 31.63,106.02 31.92,106.31 31.92,108.07 31.82,108.17 31.62,108.17 31.54,108.09 TC11.1
  BOTTOM w0.102: U1635.N7 31.99,89.6 31.99,89.49 32.29,89.19 32.29,88.96 32.19,88.86 31.98,88.86 31.77,89.08 31.67,89.08 31.49,88.89 31.49,88.58 TB11.1 ; U1638.N7 31.99,108.15 31.99,108.04 32.29,107.74 32.29,107.51 32.19,107.41 31.98,107.41 31.77,107.62 31.67,107.62 31.49,107.44 31.49,107.12 TC11.1
M_A_A4: length 93.1
  TOP w0.076: v2(69.47,92.74) 69.74,93.01 69.74,93.84 69.84,93.94 70.03,93.94 70.13,93.84 70.13,92.66 69.81,92.34 69.81,91.29 70.88,90.22 70.88,89.65 71.34,89.19 71.34,88 U11.BB52
  TOP w0.102: U1637.N3 32.13,108.06 31.49,107.42 31.39,107.42 30.97,107 30.97,106.88 TC4.1 ; TB4.1 30.97,88.34 30.97,88.46 31.39,88.88 31.49,88.88 32.13,89.52 U1636.N3
  TOP w0.229: TA5.1 29.76,95.7 R271.2
  L3_IN1 w0.292: v2(69.47,92.74) 70.27,91.94 70.57,91.94 70.87,92.23 70.87,92.54 69.81,93.59 69.11,93.59 68.67,94.03 68.67,94.74 68.21,95.19 67.98,95.19 67.78,94.98 67.78,94.54 67.52,94.28 67.08,94.28 66.82,94.54 66.82,95.49 66.58,95.73 66.16,95.73 65.87,95.44 65.87,94.26 65.71,94.09 65.31,94.09 64.7,94.7 64.7,95.44 64.41,95.73 38.79,95.73 38.5,95.44 36.33,95.44 35.68,96.09 35.15,96.09 34.64,95.58 34.3,95.58 33.45,96.42 32.93,96.42 32.5,96.86 32.18,96.86 31.96,96.63 31.96,96.19 31.76,95.99 31.47,95.99 31.07,96.39 30.44,96.39 30.31,96.25 30.31,95.75 30.18,95.62 29.93,95.62 TA5.1
  L4_IN2 w0.102: TB4.1 30.52,87.38 30.39,87.24 30.27,87.24 30.13,87.38 30.13,88.64 30.75,89.26 30.75,90.05 30.36,90.44 30.36,91.02 29.68,91.7 29.68,95.12 29.81,95.25 30.19,95.25 30.32,95.38 30.32,95.54 30.12,95.75 TA5.1 29.8,95.97 30.04,96.21 30.04,98.94 30.23,99.13 30.23,100.19 30.41,100.37 30.41,104.46 30.7,104.75 30.7,106.26 TC4.1
  BOTTOM w0.102: U1638.N3 32.13,105.34 31.16,106.31 31.16,106.52 31.07,106.6 30.69,106.6 TC4.1 ; TB4.1 30.69,88.06 31.07,88.06 31.16,87.97 31.16,87.77 32.13,86.8 U1635.N3
M_A_A5: length 107.2
  TOP w0.076: U11.BA51 72.11,86.61 72.05,86.55 71.94,86.55 71.86,86.63 71.86,87.08 71.96,87.18 71.96,87.28 71.86,87.38 71.86,87.42 71.84,87.48 71.84,87.68 71.87,87.77 71.87,88.13 71.68,88.32 71.68,88.75 71.75,88.82 71.88,88.82 71.95,88.9 71.95,88.98 71.68,89.26 71.68,89.36 71.84,89.53 71.84,89.79 71.69,89.94 71.34,89.94 71.26,90.02 71.26,90.38 71.08,90.56 71.02,90.56 70.87,90.7 70.87,90.77 70.68,90.96 70.61,90.96 70.49,91.08 70.49,91.15 70.33,91.31 70.26,91.31 70.16,91.41 70.16,92.03 70.29,92.16 70.36,92.16 70.52,92 70.62,92 70.68,92.05 70.68,92.25 70.72,92.3 70.92,92.3 70.98,92.35 70.98,92.55
  TOP w0.102: TB5.1 29,88.39 28.62,88.01 28.62,87.66 29.15,87.13 30.46,87.13 30.88,86.71 30.88,86.2 U1636.P8 ; TC5.1 29,106.94 28.62,106.55 28.62,106.2 29.15,105.67 30.46,105.67 30.88,105.25 30.88,104.74 U1637.P8
  TOP w0.229: 70.98,92.55 70.98,92.69 70.8,92.86 70.8,93.03 70.98,93.2 70.98,93.44 70.81,93.61 70.81,93.82 70.98,93.98 70.98,94.17 70.34,94.8 70.34,95.09 70.46,95.2 70.88,95.2 70.98,95.3 70.98,95.99 70.84,96.13 70.42,96.13 70.42,96.13 70.06,96.13 69.64,96.55 69.64,97.11 69.49,97.26 68.93,97.26 66.06,100.13 49.35,100.13 49.12,99.9 49.12,99.33 48.7,98.9 48.44,98.9 48.21,99.13 48.21,99.9 47.98,100.13 47.52,100.13 47.29,99.9 47.29,98.84 47.14,98.68 46.53,98.68 46.38,98.84 46.38,99.89 46.14,100.13 45.56,100.13 45.42,99.99 45.42,98.85 45.26,98.68 45.04,98.68 44.88,98.84 44.72,98.84 44.56,98.68 35.4,98.68 35.3,98.58 32.69,98.58 32.57,98.46 32.57,98.17 32.14,97.74 31.92,97.74 31.76,97.9 31.58,97.9 31.41,97.74 31.07,97.74 30.98,97.84 30.98,98.35 30.71,98.62 30.31,98.62 29.89,98.2 29.02,98.2 28.87,98.35 28.71,98.35 TA4.1
  L4_IN2 w0.102: TC5.1 29.38,106.69 29.38,103.68 29.28,103.57 29.07,103.57 28.95,103.45 28.95,102.69 29.09,102.55 29.37,102.55 29.47,102.45 29.47,102.25 29.37,102.14 28.77,102.14 28.69,102.07 28.69,98.76 28.56,98.62 TA4.1 29,98.2 29.17,98.03 29.17,97.09 29.06,96.98 28.91,96.98 28.81,96.88 28.81,90.31 29.08,90.04 29.08,88.6 TB5.1
  BOTTOM w0.102: TB5.1 29,88.51 29.18,88.33 29.28,88.33 29.36,88.4 29.36,89.01 29.46,89.11 29.99,89.11 30.2,89.32 30.62,89.32 31,89.71 31,89.91 31.07,89.98 31.07,90.22 30.87,90.42 30.87,90.71 31.07,90.92 31.26,90.92 31.33,90.84 U1635.P8 ; TC5.1 29,107.05 29.18,106.87 29.28,106.87 29.36,106.95 29.36,107.55 29.46,107.66 29.99,107.66 30.2,107.86 30.62,107.86 31,108.25 31,108.45 31.07,108.52 31.07,108.76 30.87,108.96 30.87,109.26 31.07,109.46 31.26,109.46 31.33,109.38 U1638.P8
  BOTTOM w0.229: R272.2 29.65,98.2 TA4.1
M_A_A6: length 101.3
  TOP w0.076: U11.BA52 71.44,87.47 71.18,87.74 71.18,89.12 70.72,89.58 70.72,90.15 70.54,90.33 69.47,91.4 v2(69.47,92.09)
  TOP w0.102: U1636.P2 31.25,90.55 30.97,90.26 30.97,89.45 30.81,89.29 30.21,89.29 30.01,89.09 28.97,89.09 28.62,88.74 28.62,88.3 28.24,87.92 TB1.1 ; TC1.1 28.24,106.46 28.62,106.84 28.62,107.28 28.97,107.63 30.01,107.63 30.21,107.83 30.81,107.83 30.97,107.99 30.97,108.8 31.25,109.09 U1637.P2
  TOP w0.229: R274.2 26.68,95.2 27.45,95.98 TA2.1
  L3_IN1 w0.292: TA2.1 27.45,96.15 27.19,95.88 26.14,95.88 25.87,96.15 25.87,96.6 26.23,96.95 26.23,97.38 26.58,97.73 27.31,97.73 28.53,96.51 28.53,96.41 29.09,95.86 29.09,94.78 29.33,94.54 29.68,94.54 30.19,95.05 30.99,95.05 31.45,95.5 32.34,95.5 32.78,95.94 33.25,95.94 34.15,95.05 34.79,95.05 35.08,95.33 35.45,95.33 35.83,94.96 38.7,94.96 38.99,95.25 63.4,95.25 65.51,93.14 65.93,93.14 66.52,93.73 68.31,93.73 68.6,93.44 68.6,92.15 68.92,91.84 69.22,91.84 v2(69.47,92.09)
  L4_IN2 w0.102: TB1.1 28.24,87.64 28.12,87.52 27.93,87.52 27.83,87.62 27.83,88.77 27.95,88.89 27.95,89.34 27.39,89.9 27.39,90.91 27.93,91.45 27.93,93.75 27.63,94.05 27.31,94.05 27.21,94.15 27.21,94.24 27.3,94.34 27.3,95.88 27.45,96.03 TA2.1 27.62,96.54 27.62,99.11 27.82,99.32 27.82,103.56 28.24,103.98 TC1.1
  BOTTOM w0.102: TC1.1 28.24,106.36 28.91,105.68 30.05,105.68 30.17,105.57 30.65,105.57 30.9,105.31 30.9,104.76 30.98,104.69 31.54,104.69 31.64,104.58 31.64,104.44 31.49,104.29 U1638.P2 ; TB1.1 28.24,87.81 28.91,87.14 30.05,87.14 30.17,87.03 30.65,87.03 30.9,86.77 30.9,86.22 30.98,86.14 31.54,86.14 31.64,86.04 31.64,85.9 31.49,85.75 U1635.P2
M_A_A7: length 121.7
  TOP w0.076: 69.3,93.14 69.11,92.95 69.11,91.53 70.55,90.08 70.55,89.51 71.01,89.05 71.01,87.22 71.22,87.01 71.22,86.46 71.54,86.14 U11.AW52
  TOP w0.102: U1636.R8 30.53,86.12 30.44,86.22 30.32,86.22 30.1,86 30.03,86 29.82,86.21 29.71,86.21 29.5,86 29.38,86 29.03,86.34 28.95,86.34 28.6,86 28.27,86 28.18,86.09 28.18,86.3 28.48,86.6 28.48,86.74 28.33,86.89 28.19,86.89 27.77,86.47 27.63,86.47 27.48,86.61 27.48,86.75 27.9,87.17 27.9,87.32 27.76,87.46 27.61,87.46 27.19,87.04 27.05,87.04 26.82,87.27 26.82,87.45 27.12,87.75 27.12,88.04 27.48,88.39 TB2.1 ; U1637.R8 30.53,104.54 30.23,104.83 30.08,104.83 29.87,104.62 29.68,104.62 29.52,104.78 29.33,104.78 29.03,104.49 28.83,104.49 28.75,104.58 28.75,105.04 28.65,105.14 28.44,105.14 28.34,105.04 28.34,104.7 28.21,104.56 27.96,104.56 27.66,104.87 27.66,105.01 28.17,105.52 28.17,105.66 28.02,105.81 27.88,105.81 27.37,105.3 27.22,105.3 27.13,105.39 27.13,105.59 27.01,105.71 26.81,105.71 26.73,105.8 26.73,105.93 27.09,106.3 27.09,106.55 27.48,106.94 TC2.1
  TOP w0.229: 69.3,93.14 69.48,93.32 69.48,95.44 65.65,99.26 50.28,99.26 49.97,98.95 49.97,98.09 49.69,97.82 35.76,97.82 35.65,97.71 35.51,97.71 35.37,97.57 35.37,97.41 35.04,97.08 34.57,97.08 34.38,97.27 34.38,97.52 34.18,97.71 33.33,97.71 32.5,96.88 30,96.88 29.54,97.34 28.83,97.34 28.72,97.23 27.81,97.23 27.64,97.4 27.64,97.62 27.45,97.81 26.34,97.81 26.19,97.66 26.19,96.76 26.34,96.61 26.48,96.61 26.59,96.72 26.59,96.72 27.01,97.14 TA1.1
  L4_IN2 w0.102: TB2.1 27.39,88.62 27.39,88.79 27.65,89.06 27.65,89.22 27.44,89.44 27.34,89.44 27.21,89.31 27.1,89.31 26.92,89.49 26.92,89.59 27.01,89.69 27.01,89.83 26.92,89.93 26.92,90.03 27.04,90.15 27.04,90.26 26.92,90.38 26.92,90.48 27.1,90.67 27.1,90.9 26.92,91.09 26.92,91.36 26.96,91.41 27.07,91.41 27.16,91.5 27.16,91.72 27.08,91.8 26.99,91.8 26.92,91.88 26.92,92.13 26.99,92.2 27.05,92.2 27.13,92.28 27.13,92.53 27.05,92.61 26.97,92.61 26.92,92.67 26.92,92.96 26.97,93.02 27.05,93.02 27.09,93.06 27.09,93.34 26.92,93.52 26.92,93.61 27.03,93.73 27.03,93.91 26.92,94.03 26.92,94.37 27.01,94.46 27.01,94.59 26.92,94.69 26.92,94.79 27.01,94.88 27.01,95.06 26.92,95.16 26.92,95.33 27.01,95.43 27.01,95.66 26.92,95.75 26.92,95.91 27.11,96.11 27.11,96.28 26.92,96.47 26.92,96.63 27.02,96.73 27.23,96.73 27.32,96.82 27.32,97.2 27.25,97.27 TA1.1 27.01,97.68 27.32,97.99 27.32,99.24 27.53,99.44 27.53,103.68 27.86,104.01 27.86,107.42 27.64,107.64 27.45,107.64 27.24,107.43 27.24,107.3 TC2.1
  BOTTOM w0.102: U1638.R8 30.2,109.09 29.74,108.64 29.3,108.64 28.67,108.01 28.52,108.01 28.36,108.17 28.36,108.32 28.53,108.49 28.53,108.63 28.39,108.77 28.24,108.77 28.07,108.6 27.93,108.6 27.72,108.81 27.57,108.81 27.43,108.67 27.43,108.53 28.24,107.72 28.24,107.58 28.09,107.43 27.95,107.43 27.14,108.24 26.95,108.24 26.77,108.06 26.77,107.78 TC2.1 ; TB2.1 27.48,88.39 27.24,88.15 27.15,88.15 27.07,88.23 27.07,89.33 27.23,89.49 27.36,89.49 27.76,89.09 27.76,88.79 27.83,88.72 27.93,88.72 28.09,88.88 28.34,88.88 28.39,88.94 28.39,89.02 27.88,89.54 27.88,89.65 28,89.78 28.21,89.78 28.62,89.37 28.8,89.37 29.02,89.59 29.02,89.73 28.71,90.05 28.71,90.19 28.85,90.34 28.99,90.34 29.31,90.02 29.45,90.02 29.52,90.09 29.74,90.09 30.14,90.49 30.14,90.59 30.2,90.66 30.42,90.66 U1635.R8
  BOTTOM w0.229: R276.2 27.19,97.09 TA1.1
M_A_A8: length 110.2
  TOP w0.076: 70.39,92.49 70,92.1 70,91.34 71.05,90.29 71.05,89.71 71.51,89.25 71.51,88.26 71.71,88.06 71.71,87.85 71.67,87.75 71.67,87.45 71.7,87.39 71.7,87.03 71.54,86.88 U11.AY52
  TOP w0.102: TB3.1 25.95,88.02 26.33,88.4 26.33,88.87 26.71,89.25 27.6,89.25 28.49,90.14 30.12,90.14 U1636.R2 ; U1637.R2 30.12,108.68 28.49,108.68 27.6,107.79 26.71,107.79 26.33,107.41 26.33,106.95 25.95,106.57 TC3.1
  TOP w0.229: TA3.1 24.98,97.48 24.62,97.48 24.29,97.81 24.29,98.31 24.44,98.45 24.71,98.45 24.98,98.71 24.98,99.73 25.15,99.91 25.74,99.91 25.94,99.7 25.94,98.42 26.13,98.24 27.16,98.24 27.52,98.6 27.88,98.6 28.11,98.37 28.11,98.05 28.39,97.77 29.72,97.77 30.18,97.31 32.32,97.31 33.15,98.15 35.48,98.15 35.58,98.25 45.44,98.25 45.79,98.6 46,98.6 46.34,98.25 47.32,98.25 47.72,98.66 48.05,98.66 48.45,98.25 49.39,98.25 49.53,98.39 49.53,99.13 49.55,99.15 49.55,99.58 49.67,99.7 65.88,99.7 68.75,96.83 69.05,96.83 69.2,96.68 69.2,96.38 69.91,95.67 69.91,94.62 70.39,94.14 70.39,92.49
  L4_IN2 w0.114: TC3.1 25.95,106.25 25.61,105.9 25.61,105.8 25.76,105.65 26.16,105.65 26.24,105.57 26.24,105.22 26.14,105.12 25.66,105.12 25.21,104.68 25.21,98.49 25.13,98.41 TA3.1 25.06,97.56 25.06,96.96 25.45,96.57 25.45,88.78 25.53,88.7 25.53,88.32 TB3.1
  BOTTOM w0.102: U1635.R2 30.2,85.75 29.81,86.13 27.71,86.13 27.04,86.8 27.04,86.94 27.16,87.06 27.16,87.21 27.02,87.35 26.88,87.35 26.76,87.23 26.61,87.23 TB3.1 ; U1638.R2 30.2,104.29 29.81,104.68 27.71,104.68 27.04,105.34 27.04,105.49 27.16,105.61 27.16,105.75 27.02,105.89 26.88,105.89 26.76,105.77 26.61,105.77 TC3.1
  BOTTOM w0.229: R279.2 24.82,97.93 TA3.1
M_A_A9: length 98.2
  TOP w0.076: 68.35,92.74 68.43,92.65 68.43,91.5 69.97,89.96 69.97,89.39 70.52,88.85 70.52,88 U11.BB54
  TOP w0.102: U1636.R7 30.15,86.93 28.7,86.93 27.86,87.77 27.86,88.12 28.24,88.5 TB9.1 ; U1637.R7 30.15,105.47 28.7,105.47 27.86,106.31 27.86,106.66 28.24,107.04 TC9.1 ; 68.35,92.74 68.35,93.02 v3(68.12,93.25)
  TOP w0.229: R281.2 27.54,95.45 28.03,95.94 TA8.1
  L3_IN1 w0.292: TA8.1 28.03,96.24 28.6,95.66 28.6,94.58 28.92,94.26 28.92,93.65 29.03,93.54 29.6,93.54 30.13,94.07 30.7,94.07 31.6,94.97 33.2,94.97 33.74,94.43 38.86,94.43 39.19,94.77 63.2,94.77 65.51,92.46 65.51,91.3 66.01,90.79 68.41,90.79 68.67,91.05 68.67,91.46 68.32,91.81 66.63,91.81 66.51,91.94 66.51,92.93 66.83,93.25 v3(68.12,93.25)
  L4_IN2 w0.102: TB9.1 28.24,88.91 28.49,89.16 28.49,89.8 28.37,89.92 27.78,89.92 27.68,90.02 27.68,90.23 27.78,90.33 28.12,90.33 28.22,90.43 28.22,94.14 28.06,94.3 27.78,94.3 27.68,94.4 27.68,94.61 27.78,94.71 28.15,94.71 28.22,94.78 28.22,94.95 28.1,95.08 27.67,95.08 27.59,95.15 27.59,95.76 27.71,95.87 28.1,95.87 28.18,95.95 28.18,96.23 TA8.1 27.91,96.5 27.91,98.99 28.11,99.2 28.11,103.44 28.62,103.95 28.62,106.69 TC9.1
  BOTTOM w0.102: TB9.1 28.49,88.53 29.13,89.17 29.13,89.43 29.2,89.51 29.37,89.51 29.46,89.42 29.87,89.42 30.08,89.63 30.08,90 30.3,90.22 30.62,90.22 30.7,90.14 30.7,89.88 30.56,89.75 U1635.R7 ; TC9.1 28.49,107.07 29.06,107.64 29.06,107.91 29.2,108.05 29.37,108.05 29.46,107.96 29.87,107.96 30.08,108.17 30.08,108.54 30.3,108.76 30.62,108.76 30.7,108.68 30.7,108.43 30.56,108.29 U1638.R7
M_A_A10/AP: length 96.4
  TOP w0.076: U11.AT50 73.05,84.44 v3(73.17,84.44)
  TOP w0.102: TC16.1 32.3,106.46 32.66,106.82 32.66,107.38 32.93,107.66 U1637.M3 ; U1636.M3 32.93,89.11 32.66,88.84 32.66,88.28 32.3,87.92 TB16.1
  L3_IN1 w0.076: 74.29,97.11 74.29,94.11 74.37,94.03 74.62,94.03 74.7,93.95 74.7,93.76 74.62,93.69 74.27,93.69 74.19,93.61 74.19,93.46 74.27,93.38 74.62,93.38 74.7,93.31 74.7,93.15 74.62,93.08 74.27,93.08 74.19,93 74.19,92.85 74.27,92.77 74.62,92.77 74.7,92.7 74.7,92.54 74.62,92.47 74.27,92.47 74.19,92.39 74.19,92.24 74.27,92.16 74.62,92.16 74.7,92.09 74.7,89.18 74.24,88.72 74.24,86.16 73.59,85.51 73.59,84.86 v3(73.17,84.44)
  L3_IN1 w0.292: 74.29,97.11 74.29,97.32 72.5,99.11 41.53,99.11 41.2,99.43 36.01,99.43 35.41,98.84 31.69,98.84 31.52,98.67 31.52,98.48 TA17.1
  L4_IN2 w0.102: TB16.1 32.49,87.7 32.49,87.16 32.42,87.08 32.06,87.08 31.92,87.21 31.92,90.53 31.53,90.93 31.53,98.23 TA17.1 31.64,98.6 31.75,98.7 32.43,98.7 32.53,98.81 32.53,99.01 32.43,99.11 31.53,99.11 31.42,99.21 31.42,99.36 31.55,99.49 31.96,99.49 32.06,99.59 32.06,100.89 32.11,100.94 32.11,103.39 32.41,103.68 32.41,103.82 32.3,103.93 32.16,103.93 32.05,104.03 32.05,104.23 32.16,104.33 32.3,104.33 32.41,104.43 32.41,104.64 32.3,104.74 32,104.74 31.9,104.84 31.9,105.04 32,105.15 32.3,105.15 32.41,105.25 32.41,105.45 32.3,105.55 31.94,105.55 31.84,105.65 31.84,105.86 31.94,105.96 32.3,105.96 32.41,106.06 32.41,106.33 TC16.1
  BOTTOM w0.102: TC16.1 32.48,106.62 32.64,106.62 32.71,106.54 32.71,106.15 32.58,106.03 32.58,105.61 32.93,105.26 U1638.M3 ; U1635.M3 32.93,86.72 32.58,87.07 32.58,87.48 32.71,87.61 32.71,88 32.64,88.07 32.48,88.07 TB16.1
  BOTTOM w0.229: TA17.1 31.64,98.16 32.15,97.65 R335.2
M_A_A11: length 110.2
  TOP w0.076: 68.6,93.47 68.6,91.57 70.22,89.94 70.22,89.37 70.68,88.91 70.68,87.73 70.41,87.46 U11.BA54
  TOP w0.102: TC8.1 25.42,107.07 25.75,107.39 25.75,107.54 25.66,107.62 25.66,107.77 25.81,107.91 25.95,107.91 26.04,107.83 26.18,107.83 26.41,108.06 27.55,108.06 28.58,109.09 U1637.T2 ; TB8.1 25.45,88.55 25.75,88.85 25.75,89 25.66,89.08 25.66,89.23 25.81,89.37 25.95,89.37 26.04,89.28 26.18,89.28 26.41,89.51 27.55,89.51 28.58,90.55 U1636.T2
  TOP w0.229: 68.6,93.47 68.6,94.99 65.18,98.4 55.8,98.4 52.25,94.85 49.18,94.85 48.86,95.16 48.86,96.12 48.86,96.12 48.86,96.47 48.86,96.62 48.53,96.96 47.57,96.96 47.18,96.57 46.94,96.57 46.55,96.96 44.25,96.96 43.92,96.62 43.58,96.62 43.24,96.96 42.42,96.96 42.1,96.63 41.74,96.63 41.41,96.96 40.59,96.96 40.24,96.6 39.94,96.6 39.58,96.96 38.77,96.96 38.43,96.62 38.15,96.62 37.82,96.96 36.42,96.96 35.68,96.22 33.86,96.22 33.63,96.45 31.72,96.45 31.47,96.2 31.31,96.2 31.06,96.45 30.72,96.45 30.43,96.16 29.87,96.16 29.71,96.32 29.71,96.55 29.47,96.8 29.11,96.8 28.74,96.42 28.58,96.42 28.2,96.8 27.28,96.8 27.02,96.54 27.02,96.16 26.62,95.76 25.66,95.76 25.54,95.88 25.54,96.81 25.29,97.05 24.5,97.05 24.27,96.82 24.27,96.61 24.39,96.49 TA9.1 24.87,95.58 R341.2
  L4_IN2 w0.102: TC8.1 25.57,106.69 25.57,106.33 24.91,105.67 24.91,98.68 24.76,98.53 24.76,96.6 TA9.1 25.07,96.49 25.15,96.41 25.15,96.1 25.07,96.02 24.86,96.02 24.76,95.92 24.76,95.72 24.86,95.62 25.07,95.62 25.15,95.54 25.15,95.29 25.07,95.21 24.86,95.21 24.76,95.11 24.76,94.91 24.86,94.8 25.07,94.8 25.15,94.73 25.15,94.47 25.07,94.4 24.86,94.4 24.76,94.3 24.76,94.09 24.86,93.99 25.07,93.99 25.15,93.92 25.15,93.66 25.07,93.59 24.86,93.59 24.76,93.48 24.76,93.28 24.86,93.18 25.07,93.18 25.15,93.1 25.15,92.82 25.09,92.76 24.91,92.76 24.82,92.67 24.82,92.54 24.92,92.44 25.1,92.44 25.15,92.4 25.15,88.57 TB8.1
  BOTTOM w0.102: TC8.1 25.57,106.69 25.57,106.26 27.55,104.29 U1638.T2 ; TB8.1 25.57,88.15 25.57,87.77 27.6,85.75 U1635.T2
M_A_A12/BC_N: length 102.6
  TOP w0.076: U11.AW54 70.31,86.14 70.65,86.48 70.65,86.96 70.85,87.16 70.85,88.98 70.39,89.44 70.39,90.01 68.85,91.55 68.85,92.95 69.05,93.14 69.05,93.47
  TOP w0.102: TC14.1 33.04,106.91 32.66,106.53 32.66,105.91 32.79,105.78 33.11,105.78 33.3,105.59 33.3,105.27 33.11,105.09 U1637.M7 ; TB14.1 33.06,88.39 32.66,87.99 32.66,87.36 32.79,87.24 33.11,87.24 33.3,87.05 33.3,86.73 33.11,86.55 U1636.M7
  TOP w0.229: TA15.1 33.18,96.89 33.55,97.26 33.78,97.26 34.04,97 34.04,96.76 34.15,96.65 35.51,96.65 35.69,96.84 35.69,97.12 35.96,97.39 38,97.39 38.2,97.19 38.38,97.19 38.59,97.39 39.76,97.39 40,97.15 40.18,97.15 40.42,97.39 41.59,97.39 41.81,97.16 42.02,97.16 42.24,97.39 43.42,97.39 43.67,97.14 43.83,97.14 44.07,97.39 46.73,97.39 46.97,97.14 47.14,97.14 47.39,97.39 49.35,97.39 49.48,97.26 49.48,96.66 49.29,96.47 49.29,95.48 49.5,95.28 50.17,95.28 50.4,95.51 50.4,98.67 50.56,98.83 51.15,98.83 51.31,98.67 51.31,95.44 51.45,95.3 52.09,95.3 52.83,96.04 52.83,96.34 52.23,96.95 52.23,98.7 52.36,98.83 53.01,98.83 53.14,98.7 53.14,97.39 53.56,96.97 53.76,96.97 54.34,97.55 54.34,97.75 54.06,98.04 54.06,98.71 54.18,98.83 54.54,98.83 54.82,98.55 54.99,98.55 55.28,98.83 65.36,98.83 69.05,95.15 69.05,93.47
  L4_IN2 w0.102: TB14.1 32.51,89.03 32.51,90.81 32.41,90.91 32.41,92.28 32.87,92.74 32.87,93.75 32.79,93.84 32.3,93.84 32.17,93.97 32.17,94.2 32.27,94.3 32.77,94.3 32.87,94.4 32.87,94.61 32.77,94.71 32.28,94.71 32.18,94.81 32.18,95.01 32.28,95.11 32.61,95.11 32.71,95.22 32.71,95.42 32.61,95.52 32.21,95.52 32.11,95.61 32.11,95.88 32.2,95.97 32.68,95.97 32.77,96.06 32.77,96.4 33.11,96.73 TA15.1 33.38,97.17 33.38,97.32 33.23,97.48 33.23,97.6 33.41,97.78 33.41,97.89 33.15,98.14 33.15,98.35 33.41,98.6 33.41,98.7 33.15,98.96 33.15,99.16 33.41,99.42 33.41,99.65 32.94,100.12 32.94,100.53 32.99,100.58 32.99,100.87 32.89,100.97 32.78,100.97 32.7,101.05 32.7,101.29 32.78,101.37 32.92,101.37 32.99,101.45 32.99,101.71 32.92,101.78 32.77,101.78 32.7,101.86 32.7,102.11 32.77,102.19 32.89,102.19 32.99,102.29 32.99,102.53 33.17,102.7 33.17,105.99 33.42,106.24 33.42,106.67 33.04,107.05 TC14.1
  BOTTOM w0.102: TB14.1 33.23,88.64 33.23,88.87 33.15,88.95 32.77,88.95 32.7,89.03 32.7,89.31 32.77,89.38 33.12,89.38 33.38,89.63 33.38,89.83 33.3,89.9 33.15,89.9 32.99,89.75 U1635.M7 ; U1638.M7 33.09,108.45 33.3,108.45 33.38,108.37 33.38,108.17 33.12,107.92 32.77,107.92 32.7,107.85 32.7,107.57 32.77,107.49 33.15,107.49 33.23,107.42 33.23,107.26 TC14.1
  BOTTOM w0.229: TA15.1 33.41,97.19 R342.2
M_A_A13: length 107.6
  TOP w0.076: v3(74.11,85.12) U11.AU46
  TOP w0.102: U1636.T8 27.8,85.75 26.33,87.21 26.33,88.12 26.71,88.5 TB7.1 ; TC7.1 26.71,106.94 26.33,106.56 26.33,105.76 27.8,104.29 U1637.T8
  L3_IN1 w0.076: v3(74.11,85.12) 74.46,85.75 74.77,86.61 74.93,87.47 75.02,87.89 75.16,88.27 75.16,95.4 75.26,97.11
  L3_IN1 w0.292: TA6.1 26.37,98.73 26.69,99.05 26.81,99.1 29.15,99.57 29.46,99.57 30.66,100.06 31.14,100.26 31.54,100.26 33.21,99.8 35.01,99.8 35.61,100.4 41.6,100.4 41.93,100.08 72.9,100.08 75.26,97.72 75.26,97.11
  L4_IN2 w0.102: TB7.1 26.64,88.79 26.56,89.02 26.33,89.25 26.33,98.69 TA6.1 26.09,99.01 26.09,101.7 26.21,101.82 26.65,101.82 26.75,101.92 26.75,102.13 26.65,102.23 26.23,102.23 26.16,102.3 26.16,102.96 26.25,103.05 26.7,103.05 26.92,103.28 26.92,103.9 27.12,104.1 27.12,106.66 TC7.1
  BOTTOM w0.102: TC7.1 26.61,106.96 26.4,106.96 26.31,107.05 26.31,107.39 26.16,107.54 26.16,107.7 26.26,107.8 26.26,108.04 27.43,109.22 29.3,109.22 29.32,109.2 29.62,109.2 U1638.T8 ; U1635.T8 29.62,90.66 28.66,90.66 28.09,90.08 26.81,90.08 26.26,89.53 26.26,89.31 26.21,89.26 26.21,89.01 26.26,88.96 26.26,88.73 26.47,88.53 TB7.1
  BOTTOM w0.229: R343.2 26.37,98.83 TA6.1
M_A_A14/WE_N: length 100.2
  TOP w0.076: v3(75.03,83.87) 74.84,83.87 U11.AT46
  TOP w0.102: U1636.L2 33.54,90.74 33.54,90.95 33.61,91.02 34.06,91.02 34.2,90.87 34.2,90.18 34.06,90.03 34.06,89.71 34.4,89.37 34.4,89.23 34.18,89.01 34.05,89.01 TB6.1 ; TC6.1 34.12,107.37 34.31,107.37 34.5,107.56 34.5,107.75 34.2,108.04 34.2,109.41 34.12,109.5 33.74,109.5 33.67,109.42 33.67,109.15 U1637.L2
  L3_IN1 w0.076: v3(75.03,83.87) 75.4,84.24 75.4,84.7 75.33,84.76 75.33,87.17 75.71,87.55 75.71,89.58 75.79,89.66 76.15,89.66 76.22,89.74 76.22,89.89 76.15,89.96 75.79,89.96 75.71,90.04 75.71,90.19 75.79,90.27 76.15,90.27 76.22,90.35 76.22,97.11
  L3_IN1 w0.292: 76.22,97.11 76.22,98.12 73.3,101.04 44.18,101.04 43.27,101.95 41.6,101.95 41.02,101.36 38.25,101.36 38.14,101.47 35.91,101.47 TA7.1
  L4_IN2 w0.102: TB6.1 33.84,89.25 33.84,94.54 34.1,94.81 34.44,94.81 34.59,94.96 34.59,100.15 TA7.1 34.88,100.25 35.07,100.06 35.07,99.15 35.15,99.07 35.45,99.07 35.53,99.15 35.53,100.57 35.24,100.86 35.24,101.93 35.1,102.07 34.74,102.07 34.52,102.29 34.52,103.28 34.33,103.47 34.33,107.15 TC6.1
  BOTTOM w0.102: U1635.L2 33.73,86.08 34.2,86.56 34.2,88.61 33.83,88.99 TB6.1 ; TC6.1 34.2,107.28 34.2,105.04 33.73,104.56 U1638.L2
  BOTTOM w0.229: R344.2 35.66,99.29 TA7.1
M_A_A15/CAS_N: length 99.2
  TOP w0.076: v3(73.2,85.12) U11.AU48
  TOP w0.102: TB24.1 32.3,88.39 31.92,88.01 31.92,87.72 32.56,87.09 32.56,86.33 32.93,85.95 U1636.M8 ; TC24.1 32.3,106.94 31.92,106.55 31.92,106.26 32.56,105.63 32.56,104.87 32.93,104.49 U1637.M8
  L3_IN1 w0.076: 73.81,92.06 73.94,91.94 74.37,91.94 74.44,91.86 74.44,91.12 74.34,91.01 73.91,91.01 73.83,90.94 73.83,90.71 73.91,90.63 74.43,90.63 74.51,90.56 74.51,90.41 74.43,90.33 73.91,90.33 73.83,90.25 73.83,90.1 73.91,90.02 74.43,90.02 74.51,89.95 74.51,89.8 74.43,89.72 73.91,89.72 73.83,89.64 73.83,89.45 73.91,89.38 74.33,89.38 74.4,89.3 74.4,89.15 74.33,89.07 73.91,89.07 73.83,88.99 73.83,86.05 73.43,85.65 73.11,85.65 72.98,85.52 72.98,85.33 v3(73.2,85.12)
  L3_IN1 w0.292: 73.81,92.06 73.81,97.12 72.3,98.63 39.36,98.63 39.04,98.95 36.21,98.95 35.32,98.07 34.11,98.07 33.83,98.35 32.16,98.35 TA24.1
  L4_IN2 w0.102: TC24.1 32.22,107.16 32.22,107.87 32.29,107.95 32.9,107.95 32.98,107.87 32.98,107.51 32.66,107.19 32.66,103.55 32.41,103.3 32.41,100.82 32.35,100.77 32.35,99.88 32.83,99.41 32.83,98.42 32.75,98.35 TA24.1 32.15,98.07 32.25,97.97 32.75,97.97 32.83,97.9 32.83,97.66 32.69,97.52 31.9,97.52 31.82,97.45 31.82,97.22 31.91,97.13 32.28,97.13 32.38,97.03 32.38,96.83 32.28,96.73 31.93,96.73 31.82,96.62 31.82,91.05 32.21,90.66 32.21,88.59 TB24.1
  BOTTOM w0.102: U1635.M8 32.98,90.5 32.98,90.17 32.9,90.09 32.79,90.09 32.55,90.33 32.38,90.33 32.3,90.25 32.3,90.08 32.49,89.88 32.49,88.94 32.66,88.78 32.66,88.63 32.52,88.5 TB24.1 ; TC24.1 32.55,107.07 32.66,107.18 32.66,107.32 32.49,107.49 32.49,108.42 32.3,108.62 32.3,108.79 32.38,108.87 32.55,108.87 32.79,108.63 32.9,108.63 32.98,108.71 32.98,109.04 U1638.M8
  BOTTOM w0.229: TA24.1 32.36,98.55 R354.2
M_A_A16/RAS_N: length 100.6
  TOP w0.076: v3(72.28,85.12) U11.AU50
  TOP w0.102: U1636.L8 33.73,86.02 34.06,86.35 34.06,87.34 34.55,87.83 34.55,88.79 TB27.1 ; U1637.L8 34.06,104.62 34.06,105.72 34.55,106.21 34.55,106.99 TC28.1
  L3_IN1 w0.076: 73.34,91.92 73.49,91.77 73.49,86.03 73.3,85.84 73,85.84 v3(72.28,85.12)
  L3_IN1 w0.292: TA28.1 35.52,97.59 36.41,98.47 38.84,98.47 39.16,98.15 69.84,98.15 70.13,97.85 70.13,96.79 71.68,95.24 72.09,95.24 72.35,95.49 72.35,96.19 71.3,97.24 71.3,97.85 71.59,98.15 72.1,98.15 73.34,96.9 73.34,91.92
  L4_IN2 w0.102: TB27.1 34.33,88.99 34.18,89.14 34.18,89.36 34.28,89.46 34.63,89.46 34.75,89.59 34.75,89.78 34.63,89.9 34.27,89.9 34.13,90.04 34.13,94.42 34.22,94.51 34.76,94.51 34.88,94.64 34.88,95.73 35.05,95.89 35.54,95.89 35.64,96 35.64,96.2 35.54,96.3 34.98,96.3 34.88,96.4 34.88,96.61 34.98,96.71 35.72,96.71 35.82,96.81 35.82,97.01 35.72,97.11 34.98,97.11 34.88,97.22 34.88,97.52 TA28.1 35.65,97.59 35.82,97.76 35.82,98.02 35.72,98.12 34.98,98.12 34.88,98.22 34.88,98.43 34.98,98.53 35.72,98.53 35.82,98.63 35.82,100.69 35.53,100.98 35.53,103.29 35.29,103.53 34.71,103.53 34.54,103.71 34.54,107.27 34.61,107.34 TC28.1
  BOTTOM w0.102: U1638.L8 33.37,109.09 33.29,109.01 33.29,108.77 33.36,108.7 34.14,108.7 34.21,108.63 34.21,108.33 34.11,108.23 34.11,107.76 34.52,107.34 TC28.1 ; U1635.L8 33.37,90.55 33.3,90.47 33.3,90.28 33.37,90.2 33.81,90.2 34.05,89.97 34.05,89.52 34.27,89.29 34.27,88.82 34.45,88.63 34.68,88.63 34.75,88.71 TB27.1
  BOTTOM w0.229: R345.2 35.24,97.3 TA28.1
M_A_DQ0: length 33.6
  TOP w0.076: 56.6,81.2 58.88,81.2 59.01,81.08 59.91,81.08 59.92,81.08 U11.AL71
  TOP w0.102: v3(37.45,92.46) 37.43,92.46 36.53,91.56 36.53,90.95 U1636.G2
  TOP w0.165: 56.6,81.2 47.29,81.2 v3(46.84,80.75)
  L4_IN2 w0.216: v3(46.84,80.75) 46.82,80.78 46.82,82.98 45.32,84.48 45.32,87.59 43.71,89.2 43.16,89.2 40.1,92.26 37.64,92.26 v3(37.45,92.46)
M_A_DQ1: length 34.2
  TOP w0.076: U11.AL68 62.33,81.73 62.12,81.94 61.87,81.94 61.79,82.01 61.27,82.01 61.11,81.96 60.97,81.96 60.75,82.02 60.63,82.02 60.55,81.99 60,81.99 59.77,82.22 55.09,82.22 54.71,82.6
  TOP w0.089: U1636.J3 35.33,89.51 36.36,88.48
  TOP w0.102: v3(36.8,88.29) 36.61,88.48 36.36,88.48
  TOP w0.165: v3(45.56,82.22) 46.01,82.67 54.64,82.67 54.71,82.6
  L4_IN2 w0.216: v3(45.56,82.22) 45.56,82.26 42.95,84.88 42.95,85.06 42.68,85.33 41.87,85.33 41.26,85.94 41.26,88.17 39.78,89.64 37.86,89.64 37.46,89.25 37.46,88.96 v3(36.8,88.29)
M_A_DQ2: length 33.9
  TOP w0.076: U11.AN68 61.75,82.6 61.25,82.6 61.02,82.84 60.08,82.84 60.04,82.88 58.73,82.88 58.24,83.37 55.95,83.37
  TOP w0.102: U1636.F7 37.73,86.48 v3(38.07,86.15)
  TOP w0.165: 55.95,83.37 55.23,84.09 45.34,84.09 43.84,82.59 43.18,82.59 42.23,81.64 42.23,81.1 v3(41.84,80.7)
  L4_IN2 w0.216: v3(41.84,80.7) 41.93,80.79 41.93,82.47 41.35,83.05 40.56,83.05 40.35,82.84 40.35,82.51 40.1,82.25 39.8,82.25 39.49,82.56 39.49,83.21 39.34,83.36 38.31,83.36 37.79,83.89 37.79,84.2 38.19,84.6 38.19,84.75 37.79,85.15 37.79,85.86 v3(38.07,86.15)
M_A_DQ3: length 35.3
  TOP w0.076: U11.AN69 61.57,82.21 61.32,82.21 61.1,82.13 60.97,82.13 60.74,82.2 60.6,82.2 60.54,82.17 60.51,82.15 60.07,82.15 59.84,82.38 58.39,82.38 58.25,82.52 55.29,82.52
  TOP w0.089: U1636.J7 35.33,86.62 36.26,87.56 36.26,87.59
  TOP w0.102: v2(37.56,87.61) 37.36,87.61 37.06,87.91 36.59,87.91 36.26,87.59
  TOP w0.165: 55.29,82.52 54.79,83.02 45.78,83.02 44.28,81.52 43.63,81.52 43.3,81.2 43.3,80.22 v3(43.43,80.09)
  L4_IN2 w0.216: v3(43.43,80.09) 43.43,80.09 43.07,80.44 43.07,82.47 41.76,83.79 40.05,83.79 39.68,84.15 39.68,86.55 39.13,87.11 38.06,87.11 v2(37.56,87.61)
M_A_DQ4: length 34.7
  TOP w0.076: 54.71,80.85 56.98,80.85 57.07,80.94 58.92,80.94 58.97,80.89 59.81,80.89 59.88,80.81 60.46,80.81 60.58,80.85 60.7,80.91 60.88,81.08 U11.AL70
  TOP w0.089: v3(37.25,90.14) 36.54,90.14 36.4,90.27
  TOP w0.102: 36.4,90.27 U1636.H2
  TOP w0.165: 54.71,80.85 47.65,80.85 47.11,80.31 46.51,80.31 v3(46.38,80.45)
  L4_IN2 w0.216: v3(46.38,80.45) 46.41,80.48 46.41,82.82 44.91,84.32 44.91,87.14 43.41,88.65 43.14,88.65 40.42,91.36 37.15,91.36 36.92,91.13 36.92,90.47 v3(37.25,90.14)
M_A_DQ5: length 34.3
  TOP w0.076: U11.AL69 61.47,81.08 61.21,80.81 61.04,80.81 60.85,80.74 60.85,80.74 60.72,80.7 60.64,80.69 60.57,80.67 60.51,80.66 60.44,80.63 59.83,80.63 59.74,80.72 59.46,80.72 59.29,80.56 59.06,80.56 58.85,80.77 57.24,80.77 56.96,80.49 54.71,80.49
  TOP w0.102: v3(36.91,89.17) 36.82,89.26 36.82,89.4 36.47,89.75 U1636.H3
  TOP w0.165: 54.71,80.49 47.79,80.49 47.24,79.93 45.82,79.93 v3(45.61,80.14)
  L4_IN2 w0.216: v3(45.61,80.14) 45.93,80.46 45.93,81.14 46,81.21 46,82.65 42.67,85.98 42.67,85.99 42.42,86.24 42.41,86.24 41.66,86.99 41.66,88.24 39.42,90.48 38,90.48 37.76,90.24 37.76,90.02 v3(36.91,89.17)
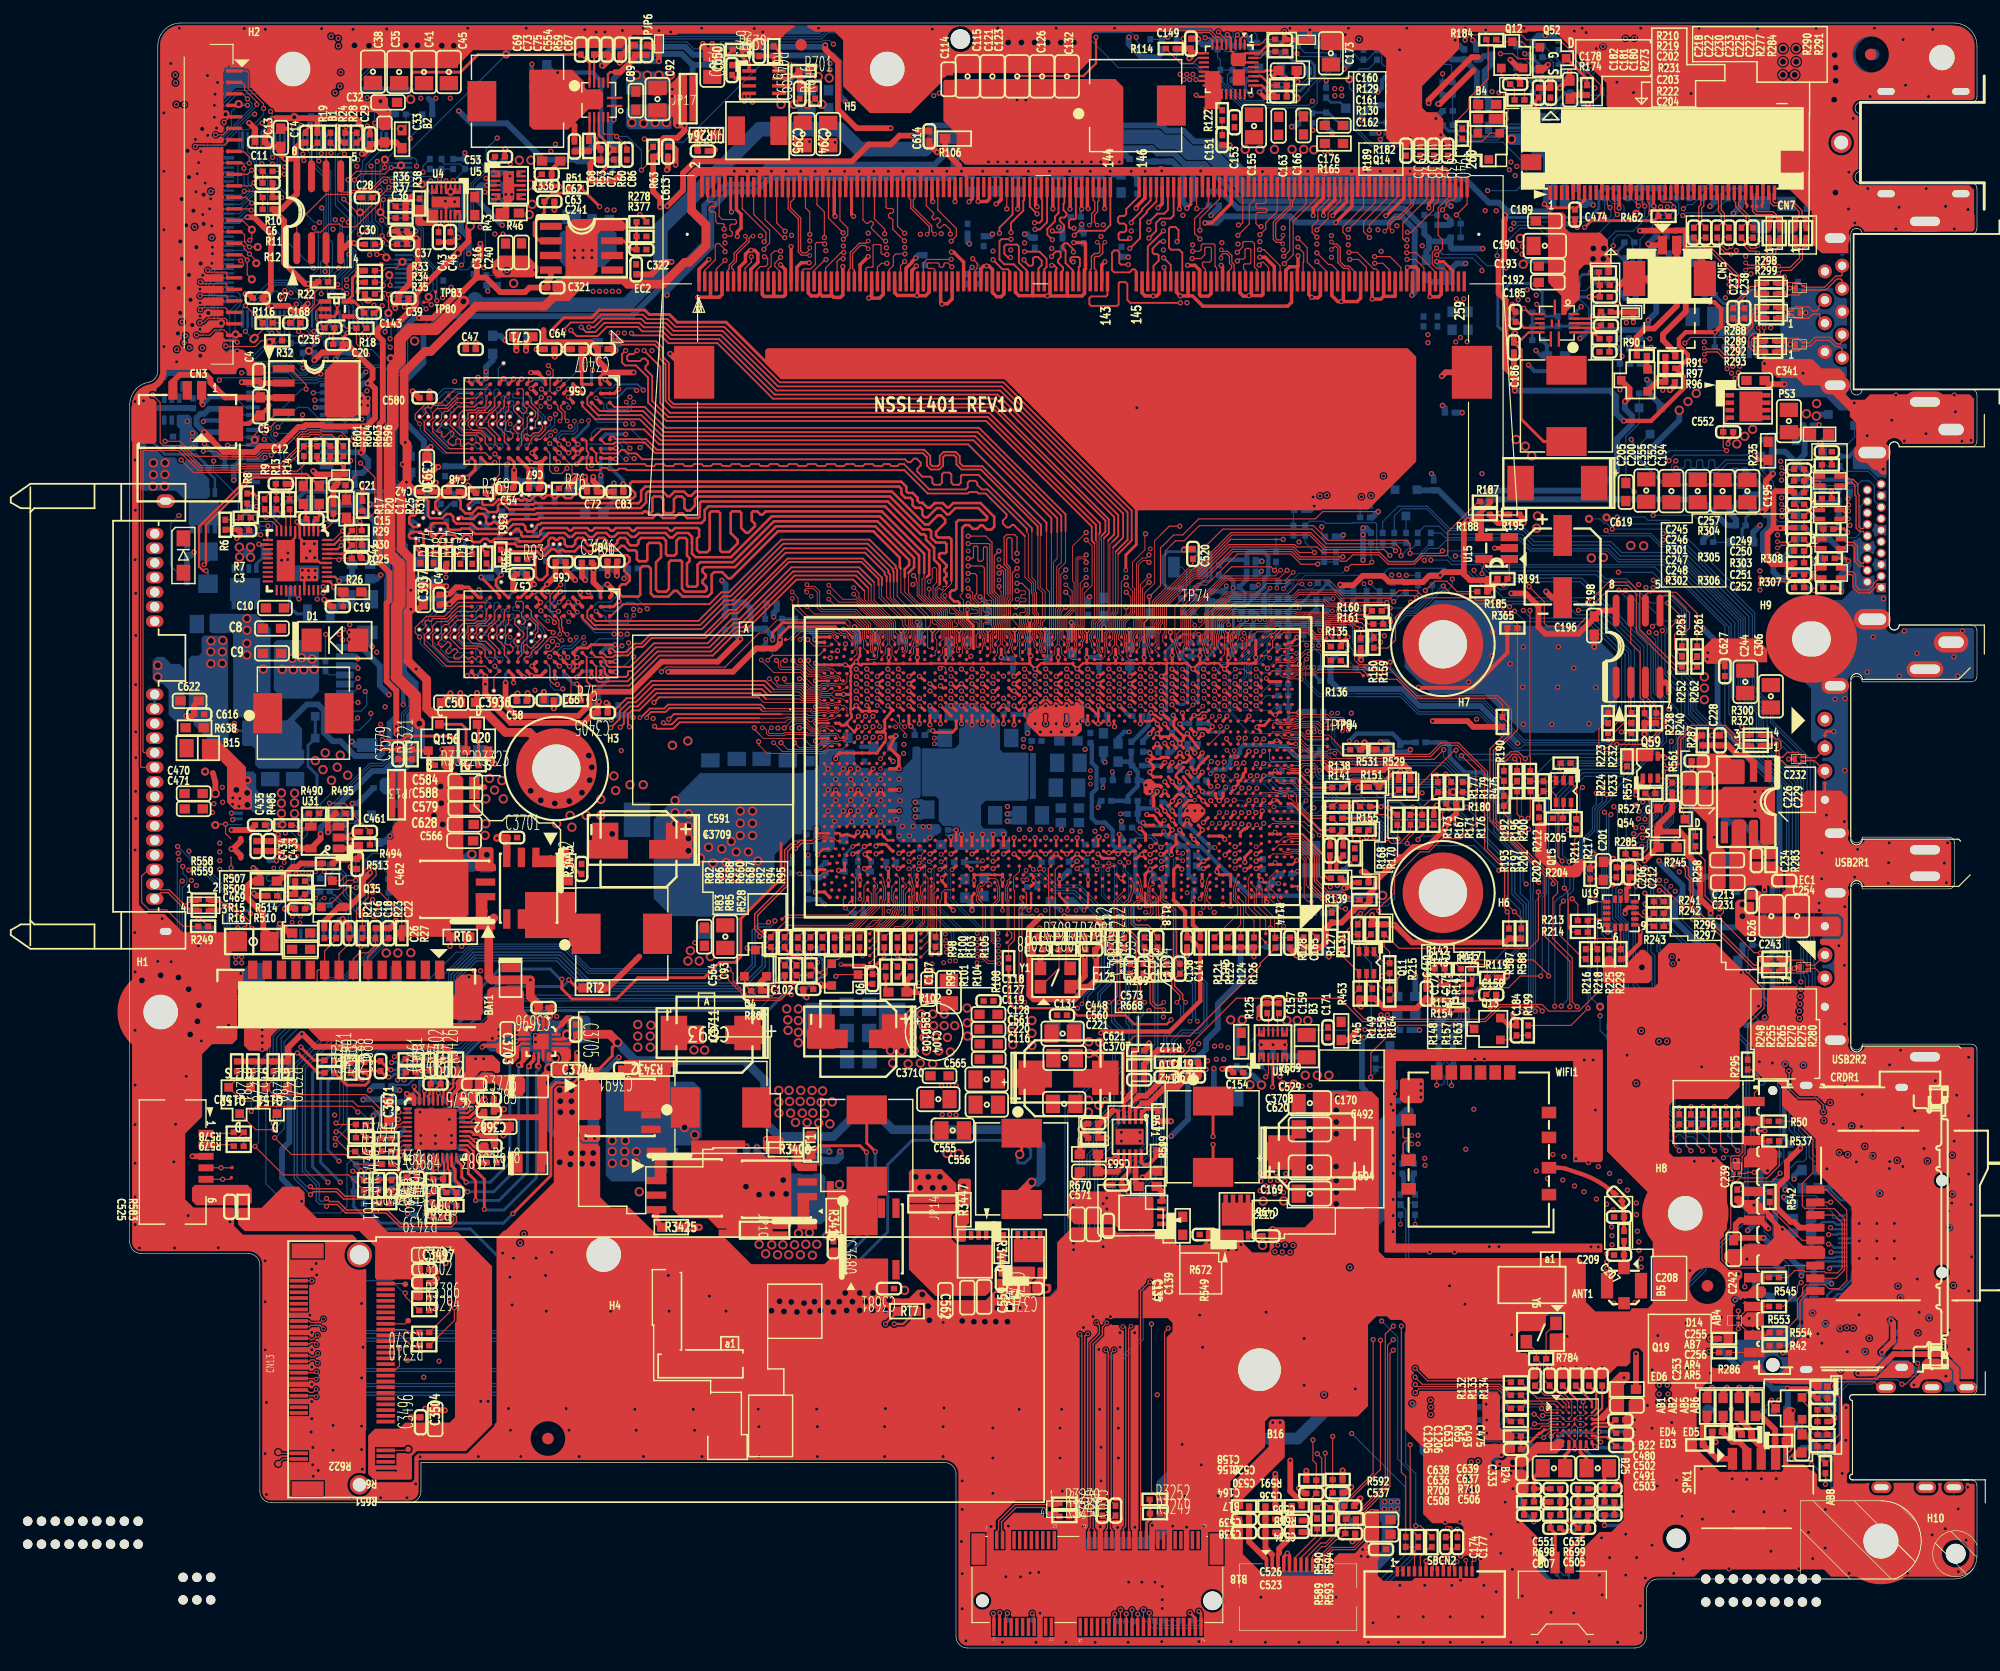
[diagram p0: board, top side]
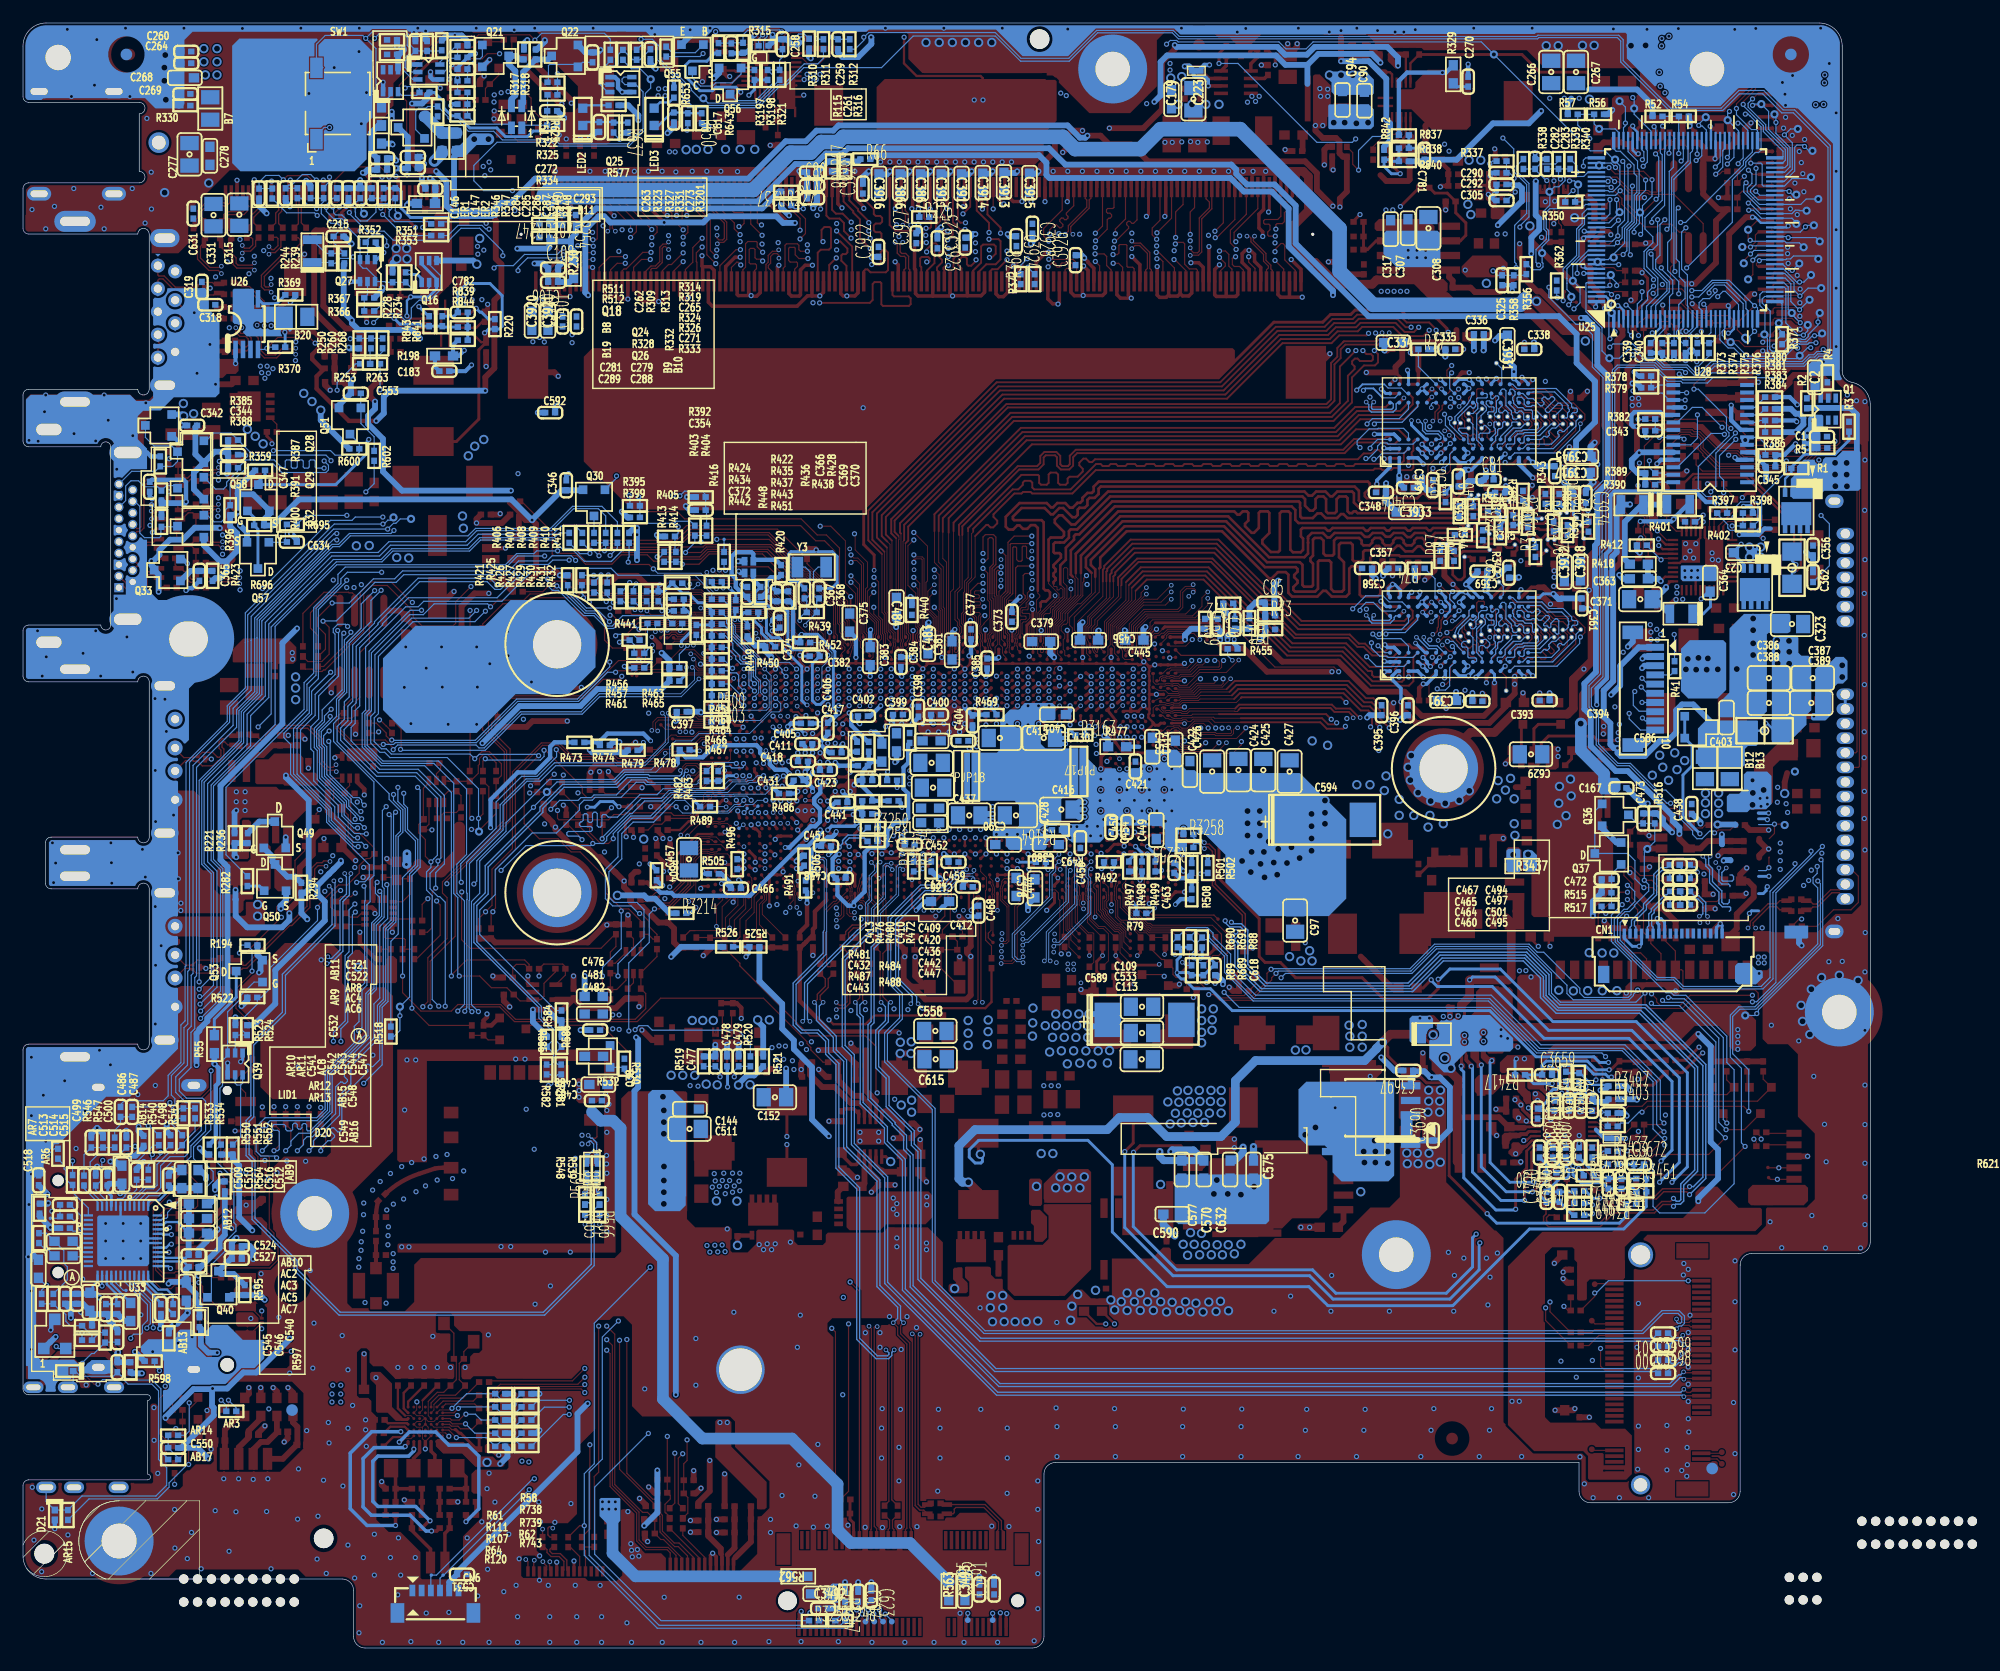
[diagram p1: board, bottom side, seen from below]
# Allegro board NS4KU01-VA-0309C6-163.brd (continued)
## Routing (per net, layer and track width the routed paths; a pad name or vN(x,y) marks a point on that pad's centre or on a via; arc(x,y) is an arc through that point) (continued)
M_A_DQ6: length 32
  TOP w0.076: 55.68,83.13 58.17,83.13 58.59,82.71 59.97,82.71 60.02,82.67 60.76,82.67 U11.AN70
  TOP w0.102: U1636.H8 36.49,85.38 36.49,84.17 36.87,83.79 37.16,83.79 v3(37.17,83.79)
  TOP w0.165: v3(41.8,80.02) 42.59,80.81 42.59,81.49 43.33,82.23 43.98,82.23 45.49,83.74 55.08,83.74 55.68,83.13
  L4_IN2 w0.216: v3(37.17,83.79) 37.03,83.64 37.03,83.39 37.54,82.88 38.18,82.88 38.43,82.62 38.43,81.99 38.71,81.71 41.22,81.71 41.35,81.58 41.35,80.4 41.73,80.02 v3(41.8,80.02)
M_A_DQ7: length 32.6
  TOP w0.076: U11.AN71 60.05,82.41 59.91,82.55 58.5,82.55 58.22,82.83 55.48,82.83
  TOP w0.102: v2(37.19,87.21) 37.14,87.21 36.59,86.66 36.25,86.66 U1636.H7
  TOP w0.165: 55.48,82.83 54.93,83.38 45.64,83.38 44.13,81.88 43.48,81.88 42.95,81.34 42.95,80.38 v3(42.63,80.06)
  L4_IN2 w0.216: v2(37.19,87.21) 37.61,86.79 38.82,86.79 39.33,86.28 39.33,83.82 39.79,83.36 41.61,83.36 42.4,82.57 42.4,80.29 v3(42.63,80.06)
M_A_DQ8: length 31.8
  TOP w0.076: U11.AR70 60.88,83.44 60.61,83.17 60.22,83.17 60.18,83.21 58.94,83.21 58.43,83.72 56.38,83.72 56.24,83.86 v3(56.24,84.28)
  L3_IN1 w0.216: v3(37.64,83.4) 37.78,83.55 37.99,83.55 38.12,83.43 38.12,83.11 38.25,82.98 41.36,82.98 42.07,82.27 42.38,82.27 42.77,82.66 42.99,82.66 43.33,82.31 43.64,82.31 43.98,82.66 44.19,82.66 44.51,82.34 44.88,82.34 45.19,82.66 45.93,82.66 46.06,82.79 46.06,83.05 46.22,83.21 46.7,83.21 46.92,82.99 46.92,82.5 47.14,82.28 47.78,82.28 48,82.5 48,82.99 48.22,83.21 55.83,83.21 56.24,83.62 v3(56.24,84.28)
  BOTTOM w0.089: U1635.H2 36.13,85.67 36.37,85.44
  BOTTOM w0.102: v3(37.64,83.4) 37.53,83.3 36.92,83.3 36.56,83.66 36.56,85.25 36.37,85.44
M_A_DQ9: length 32.9
  TOP w0.076: v2(55.59,84.28) 56.31,83.55 58.33,83.55 58.84,83.04 60.11,83.04 60.15,83 61.02,83 61.25,83.24 61.8,83.24 U11.AR68
  L3_IN1 w0.216: v2(55.59,84.28) 54.93,83.62 45.5,83.62 44.77,82.89 44.54,82.89 44.36,83.06 43.82,83.06 43.64,82.89 43.34,82.89 43.16,83.06 42.6,83.06 42.42,82.89 42.03,82.89 41.55,83.36 38.7,83.36 38.33,83.72 38.33,84.64 38.15,84.82 37.14,84.82 36.88,85.08 36.88,85.68 36.98,85.78 36.98,86.57 36.76,86.78 36.76,87.52 v3(36.75,87.53)
  BOTTOM w0.089: U1635.J3 35.9,87.11 35.9,87.19 36.24,87.53
  BOTTOM w0.102: 36.24,87.53 v3(36.75,87.53)
M_A_DQ10: length 30.1
  TOP w0.076: U11.AU71 60.27,84.86 59.1,84.86 58.49,85.48 58.03,85.48 v3(57.64,85.87)
  L3_IN1 w0.216: v3(57.64,85.87) 57.64,86.13 57.45,86.32 54.61,86.32 54.36,86.08 53.86,86.08 53.64,85.86 53.64,85.6 53.43,85.38 52.78,85.38 52.56,85.6 52.56,85.86 52.35,86.08 51.7,86.08 51.49,85.86 51.49,85.6 51.27,85.38 50.62,85.38 50.41,85.6 50.41,85.86 50.19,86.08 49.54,86.08 49.33,85.86 49.33,85.61 49.11,85.39 48.46,85.39 48.25,85.61 48.25,85.86 48.03,86.08 45.42,86.08 44.28,84.94 43.28,84.94 42.9,85.31 41.76,85.31 40.97,86.1 40.97,88.55 40.29,89.23 v2(38.14,89.23)
  BOTTOM w0.102: v2(38.14,89.23) 37.73,89.64 U1635.F7
M_A_DQ11: length 33.9
  TOP w0.076: v2(54.88,85.91) 55.97,84.82 58.27,84.82 59.39,83.71 59.99,83.71 60.15,83.87 60.52,83.87 60.55,83.85 60.63,83.82 60.75,83.82 60.97,83.88 61.11,83.88 61.27,83.83 61.86,83.83 61.88,83.81 62.12,83.81 62.33,84.01 U11.AU68
  L3_IN1 w0.216: v2(36.32,89.3) 36.28,89.26 36.28,88.99 36.54,88.73 40.12,88.73 40.59,88.26 40.59,85.78 41.95,84.43 44.35,84.43 45.59,85.67 47.37,85.67 48.07,84.98 53.95,84.98 v2(54.88,85.91)
  BOTTOM w0.089: U1635.J7 35.59,89.75 36.03,89.3 v2(36.32,89.3)
M_A_DQ12: length 30.1
  TOP w0.076: U11.AR71 60.32,83.37 59.04,83.37 58.54,83.88 57.03,83.88 56.89,84.02 v3(56.89,84.28)
  L3_IN1 w0.216: v3(56.89,84.28) 57.04,84.12 57.04,83.81 56.04,82.8 48.88,82.8 47.83,81.75 38.09,81.75 37.23,82.6 37.23,82.97 36.5,83.71 v3(36.5,86.2)
  BOTTOM w0.102: U1635.G2 36.93,85.76 v3(36.5,86.2)
M_A_DQ13: length 32.7
  TOP w0.076: U11.AR69 61.57,83.64 61.32,83.64 61.1,83.71 60.97,83.71 60.74,83.65 60.64,83.65 60.63,83.64 60.62,83.65 60.6,83.65 60.48,83.7 60.22,83.7 60.06,83.54 59.16,83.54 58.42,84.28 v3(58.21,84.28)
  L3_IN1 w0.216: v3(58.21,84.28) 56.28,82.35 49,82.35 47.99,81.35 37.92,81.35 36.79,82.47 36.79,82.97 36.06,83.7 36.06,86.82 v3(36.32,87.09)
  BOTTOM w0.089: v3(36.32,87.09) 36.13,86.9 U1635.H3
M_A_DQ14: length 31.2
  TOP w0.076: v3(58.29,85.87) 58.35,85.87 59.18,85.04 60.75,85.04 U11.AU70
  L3_IN1 w0.216: v3(58.29,85.87) 58.29,86.44 58,86.73 54.44,86.73 54.19,86.48 45.25,86.48 44.11,85.34 43.38,85.34 42.46,86.26 41.64,86.26 41.29,86.61 41.29,89.21 40.86,89.64 36.95,89.64 36.4,90.2 v3(35.73,90.2)
  BOTTOM w0.102: U1635.H7 36.13,89.8 v3(35.73,90.2)
M_A_DQ15: length 32.9
  TOP w0.076: v3(58.97,85.87) 58.97,85.63 59.38,85.22 60.83,85.22 60.91,85.14 61.09,85.14 61.47,84.76 U11.AU69
  L3_IN1 w0.216: v3(58.97,85.87) 58.97,86.27 58.11,87.14 54.27,87.14 54.02,86.89 45.08,86.89 43.95,85.76 43.59,85.76 42.77,86.58 42.21,86.58 41.66,87.13 41.66,89.63 39.92,91.36 36.8,91.36 v3(36.3,91.87)
  BOTTOM w0.102: v3(36.3,91.87) 36.55,91.61 36.55,91.23 36.13,90.81 U1635.H8
M_A_DQ16: length 31
  TOP w0.076: v2(58.85,90.56) 59.5,89.91 62.97,89.91 64.03,88.85 64.03,88 U11.BB65
  L3_IN1 w0.216: v2(58.85,90.56) 58.67,90.74 58.67,91.32 58.54,91.45 58.19,91.45 58.06,91.32 58.06,90.69 57.93,90.56 57.6,90.56 57.26,90.9 51.62,90.9 51.4,90.68 51.4,90.14 51.19,89.92 50.75,89.92 50.54,90.14 50.54,90.68 50.32,90.9 49.89,90.9 49.68,90.68 49.68,90.14 49.46,89.92 49.03,89.92 48.81,90.14 48.81,90.68 48.6,90.9 48.16,90.9 47.95,90.68 47.95,90.14 47.73,89.92 44.64,89.92 v3(44.34,90.22)
  BOTTOM w0.102: U1635.B8 41.31,90.16 42.43,90.16 43.18,90.92 43.82,90.92 44.34,90.4 v3(44.34,90.22)
M_A_DQ17: length 32.6
  TOP w0.076: v2(60.75,91.19) 61.26,90.69 63.16,90.69 65.21,88.64 65.21,88.31 65.03,88.13 65.03,87.76 65.07,87.65 65.07,87.53 65.01,87.31 65.01,87.17 65.06,87.01 65.06,86.83 64.99,86.67 64.99,86.16 64.78,85.95 U11.AW65
  L3_IN1 w0.216: v2(60.75,91.19) 60.75,90.28 59.68,89.2 55.08,89.2 54.95,89.33 52.52,89.33 51.71,88.51 43.58,88.51 v3(43.23,88.17)
  BOTTOM w0.102: U1635.C3 40.13,87.11 40.79,87.76 42.83,87.76 v3(43.23,88.17)
M_A_DQ18: length 33.9
  TOP w0.076: U11.AW63 65.36,86.17 65.67,86.48 65.67,87.02 65.89,87.25 65.89,88.89 63.37,91.41 63.37,91.75 v2(62.91,92.21)
  L3_IN1 w0.216: v2(62.91,92.21) 62.91,92.81 62.77,92.95 62.51,92.95 62.27,92.72 62.27,90.43 60.32,88.48 52.82,88.48 52.04,87.7 44.48,87.7 43.55,86.78 43.15,86.78 v3(42.78,87.15)
  BOTTOM w0.102: U1635.A3 42.17,86.55 v3(42.78,87.15)
M_A_DQ19: length 34.1
  TOP w0.076: U11.AY63 65.26,86.7 65.26,86.96 65.18,87.17 65.18,87.31 65.25,87.54 65.25,87.68 65.19,87.8 65.19,88.06 65.37,88.24 65.37,88.71 63.14,90.94 61.64,90.94 v2(60.75,91.83)
  L3_IN1 w0.216: v3(43.35,87.4) 44.05,88.11 51.88,88.11 52.68,88.91 59.89,88.91 61.34,90.36 61.34,91.24 v2(60.75,91.83)
  BOTTOM w0.102: U1635.D3 39.74,86.13 41.89,86.13 42,86.24 42.63,86.24 43.35,86.96 v3(43.35,87.4)
M_A_DQ20: length 31.7
  TOP w0.076: U11.BA65 64.13,87.4 63.99,87.54 63.99,87.55 63.98,87.55 63.87,87.8 63.87,88.73 62.85,89.74 58.9,89.74 58.08,90.56 58.08,91.32 v2(57.58,91.83)
  L3_IN1 w0.216: v3(42.67,88.15) 42.67,89.9 44.48,91.71 51.87,91.71 52.63,92.47 57.59,92.47 57.8,92.25 57.8,92.06 v2(57.58,91.83)
  BOTTOM w0.102: U1635.C7 40.13,89.16 40.75,88.55 42.27,88.55 v3(42.67,88.15)
M_A_DQ21: length 33.1
  TOP w0.076: U11.AY65 63.78,86.96 63.78,87.6 63.78,87.6 63.7,87.76 63.7,88.64 62.76,89.58 58.68,89.58 57.58,90.69 v2(57.58,91.27)
  L3_IN1 w0.216: v2(57.58,91.27) 57.4,91.27 57.36,91.31 55.82,91.31 55.6,91.52 55.6,91.85 55.39,92.06 54.96,92.06 54.74,91.85 54.74,91.52 54.52,91.31 54.09,91.31 53.88,91.52 53.88,91.85 53.66,92.06 53.23,92.06 53.01,91.85 53.01,91.52 52.8,91.31 47.54,91.31 47.33,91.09 47.33,90.54 47.11,90.33 46.68,90.33 46.46,90.54 46.46,91.09 46.25,91.31 44.65,91.31 44.52,91.17 44.52,90.82 v3(44.98,90.36)
  BOTTOM w0.102: v3(44.98,90.36) 43.85,91.49 42.34,91.49 41.81,90.96 40.68,90.96 40.27,90.55 U1635.C8
M_A_DQ22: length 33.9
  TOP w0.076: v2(62.91,91.64) 65.72,88.82 65.72,87.73 65.46,87.46 U11.BA63
  L3_IN1 w0.216: v2(62.91,91.64) 63.31,91.24 63.31,90.65 63.17,90.51 62.92,90.51 62.75,90.34 62.75,90.14 63.22,89.67 63.22,89.45 63.04,89.27 62.83,89.27 62.36,89.74 62.16,89.74 60.54,88.13 54.78,88.13 54.73,88.07 54.63,88.07 53.86,87.29 44.87,87.29 v3(43.77,86.2)
  BOTTOM w0.102: U1635.C2 40.53,85.35 42.93,85.35 v3(43.77,86.2)
M_A_DQ23: length 32.6
  TOP w0.076: v2(60.75,92.41) 61.97,91.19 63.12,91.19 65.54,88.78 65.54,87.98 U11.BB63
  L3_IN1 w0.216: v3(42.1,88.17) 42.09,88.18 42.09,89.89 44.43,92.24 51.83,92.24 52.46,92.88 60.29,92.88 v2(60.75,92.41)
  BOTTOM w0.102: U1635.D7 39.33,89.39 40.43,88.29 41.97,88.29 v3(42.1,88.17)
M_A_DQ24: length 35.6
  TOP w0.076: U11.BA61 66.49,87.46 66.22,87.73 66.22,89.05 64.18,91.09 64.18,92.18
  TOP w0.165: 64.18,92.18 63.1,93.26 57.79,93.26 53.29,88.75 52.63,88.75 50.53,86.65 45.86,86.65 43.26,84.06 41.61,84.06 41.57,84.02 40.7,84.02 40.53,84.19 40.53,85.34 U1636.C8
M_A_DQ25: length 38.3
  TOP w0.076: U11.AW61 66.59,86.04 66.25,86.38 66.25,87.03 66.05,87.23 66.05,88.96 63.85,91.17 63.85,91.92
  TOP w0.165: U1636.D7 39.71,86.17 39.71,84.06 40.09,83.68 43.39,83.68 46.01,86.3 50.68,86.3 52.78,88.4 53.44,88.4 57.94,92.9 62.87,92.9 63.85,91.92
M_A_DQ26: length 36.9
  TOP w0.076: U11.BB59 67.91,88 67.91,88.71 67.67,88.95 67.67,89.51 65.78,91.4 65.78,92.74
  TOP w0.165: U1636.D3 39.33,89.58 40.31,88.59 49.72,88.59 51.86,90.74 52.51,90.74 57.01,95.24 63.91,95.24 65.62,93.53 65.62,93.34 65.78,93.18 65.78,92.74
M_A_DQ27: length 38.2
  TOP w0.076: 66.69,92.74 66.69,91.44 68.84,89.29 68.84,88.98 68.65,88.79 68.65,87.74 68.68,87.71 68.75,87.56 68.75,87.38 68.5,87.13 68.37,87.13 68.37,87.13 68.33,87.13 68.12,86.91 68.12,86.49 67.81,86.19 U11.AW59
  TOP w0.165: U1636.A3 41.83,89.75 42.86,90.77 50.39,90.77 51.42,91.8 52.07,91.8 56.64,96.38 64.28,96.38 66.57,94.09 66.57,93.88 66.69,93.76 66.69,92.74
M_A_DQ28: length 34.3
  TOP w0.076: 64.43,92.43 64.43,91.09 66.39,89.14 66.39,88.02 66.49,87.92 U11.BB61
  TOP w0.165: 64.43,92.43 63.25,93.61 57.65,93.61 53.14,89.11 52.48,89.11 50.38,87.01 45.7,87.01 43.65,84.95 43.37,84.95 43.29,84.88 43.29,84.6 43.14,84.44 41.54,84.44 41.3,84.69 41.3,85.14 40.93,85.51 U1636.B8
M_A_DQ29: length 36.4
  TOP w0.076: U11.AY61 66.85,86.86 66.85,88.02 66.55,88.32 66.55,89.26 64.69,91.12 64.69,92.68
  TOP w0.165: 64.69,92.68 63.4,93.97 57.5,93.97 53,89.46 52.33,89.46 50.23,87.36 45.55,87.36 43.5,85.31 41.64,85.31 41.36,85.59 41.36,85.84 41.04,86.16 40.52,86.16 U1636.C7
M_A_DQ30: length 38.5
  TOP w0.076: U11.BA59 68.02,87.66 68.08,87.8 68.08,88.78 67.84,89.02 67.84,89.6 66.08,91.35 66.08,92.74
  TOP w0.165: U1636.C2 39.77,90.18 39.77,89.57 40.39,88.95 49.57,88.95 51.71,91.09 52.36,91.09 56.89,95.62 64.03,95.62 65.93,93.71 65.93,93.48 66.08,93.33 66.08,92.74
M_A_DQ31: length 38.3
  TOP w0.076: 66.39,92.74 66.39,91.29 68,89.68 68,89.09 68.24,88.85 68.24,87.77 68.21,87.7 68.08,87.27 68.08,87.1 67.95,86.98 67.95,86.88 67.81,86.74 U11.AY59
  TOP w0.165: 66.39,92.74 66.39,93.59 66.32,93.67 66.32,93.85 64.14,96.02 56.79,96.02 52.22,91.45 51.56,91.45 49.42,89.31 40.5,89.31 40.13,89.67 U1636.C3
M_A_DQ32: length 55.6
  TOP w0.076: 77.79,96.68 77.79,93.12 78.36,92.56 78.36,91.73 78.48,91.61 78.48,89.96 78.63,89.81 78.63,89.22 78.48,89.07 78.48,88.22 78.42,88.16 78.42,87.76 78.59,87.35 78.59,87.07 78.86,86.81 U11.AY39
  TOP w0.165: U1637.D7 39.56,105.09 39.71,104.94 39.71,104.12 39.86,103.97 39.86,103.72 39.71,103.58 39.71,102.6 39.89,102.42 40.86,102.42 41.05,102.61 41.45,102.61 41.64,102.42 42.39,102.42 42.52,102.55 43.07,102.55 43.2,102.42 67.31,102.42 69.35,100.39 72.84,100.39 72.97,100.52 73.63,100.52 73.76,100.39 74.38,100.39 76.2,98.57 76.2,98.35 75.87,98.02 75.87,97.79 76.22,97.44 76.46,97.44 76.68,97.66 76.82,97.66 77.79,96.68
M_A_DQ33: length 56.1
  TOP w0.076: 79.67,97.11 79.67,92.09 79.93,91.83 79.93,88.31 79.75,88.14 79.75,87.76 79.76,87.73 79.8,87.65 79.8,87.53 79.73,87.31 79.73,87.17 79.79,87.01 79.79,86.83 79.77,86.79 79.77,86.22 79.5,85.95 U11.AW39
  TOP w0.165: 79.67,97.11 79.67,97.85 72.86,104.66 46,104.66 44.69,105.97 41.01,105.97 U1637.C7
M_A_DQ34: length 56.9
  TOP w0.076: U11.AY37 79.98,86.7 79.98,86.96 79.91,87.17 79.91,87.31 79.97,87.54 79.97,87.68 79.92,87.8 79.92,88.07 80.1,88.25 80.1,96.98
  TOP w0.165: U1637.D3 39.33,108 40.48,106.85 44.32,106.85 46.15,105.02 73.32,105.02 80.1,98.24 80.1,96.98
M_A_DQ35: length 56.8
  TOP w0.076: 81.33,97.11 81.33,94.39 80.75,93.82 80.75,90.4 80.61,90.26 80.61,88.27 80.61,88.27 80.61,87.25 80.39,87.02 80.39,86.48 80.08,86.17 U11.AW37
  TOP w0.165: 81.33,97.11 81.33,98.58 73.82,106.1 46.58,106.1 44.76,107.91 42.11,107.91 U1637.A3
M_A_DQ36: length 54.6
  TOP w0.076: 78.4,97.11 78.4,93.07 78.71,92.77 78.71,91.85 78.81,91.75 78.81,90.1 78.96,89.95 78.96,89.08 78.82,88.94 78.82,87.94 U11.BB39
  TOP w0.165: 78.4,97.11 78.4,97.37 73.77,102.01 72.32,102.01 72.23,101.92 72.23,101.32 72.07,101.15 71.57,101.15 71.41,101.32 71.41,102.04 71.24,102.2 70.75,102.2 70.58,102.04 70.58,101.32 70.42,101.15 69.92,101.15 69.76,101.32 69.76,101.68 69.59,101.85 68.89,101.85 68.44,102.3 68.44,102.53 68.74,102.84 68.74,103.07 68.39,103.42 68.16,103.42 67.85,103.12 67.62,103.12 67.38,103.37 44.54,103.37 44.03,103.87 43.32,103.87 43.01,104.18 42.72,104.18 42.42,103.87 41.09,103.87 40.93,104.03 U1637.B8
M_A_DQ37: length 54.6
  TOP w0.076: U11.BA39 78.86,87.4 78.72,87.54 78.59,87.8 78.59,88.09 78.65,88.15 78.65,88.99 78.8,89.15 78.8,89.88 78.65,90.03 78.65,91.68 78.53,91.8 78.53,92.65 78.1,93.07 78.1,96.9 77.96,97.04 77.96,97.11
  TOP w0.165: 77.96,97.11 77.96,97.32 74.53,100.74 74.05,100.74 73.65,101.14 73.65,101.33 73.49,101.49 72.99,101.49 72.83,101.33 72.83,100.91 72.66,100.74 69.49,100.74 67.29,102.95 66.89,102.95 66.71,102.78 66.19,102.78 66.01,102.95 65.56,102.95 65.39,102.78 64.73,102.78 64.56,102.95 63.9,102.95 63.74,102.78 63.08,102.78 62.91,102.95 62.25,102.95 62.08,102.78 61.43,102.78 61.26,102.95 60.6,102.95 60.43,102.78 59.78,102.78 59.61,102.95 58.95,102.95 58.78,102.78 58.13,102.78 57.96,102.95 57.3,102.95 57.13,102.78 56.48,102.78 56.31,102.95 55.65,102.95 55.48,102.78 54.82,102.78 54.66,102.95 54,102.95 53.83,102.78 53.17,102.78 53,102.95 52.35,102.95 52.18,102.78 51.52,102.78 51.35,102.95 50.7,102.95 50.53,102.78 49.87,102.78 49.7,102.95 49.05,102.95 48.88,102.78 48.22,102.78 48.05,102.95 47.39,102.95 47.23,102.78 46.57,102.78 46.4,102.95 45.74,102.95 45.57,102.78 44.92,102.78 44.75,102.95 40.82,102.95 40.54,103.23 40.54,103.88 U1637.C8
M_A_DQ38: length 56.4
  TOP w0.076: 80.96,97.11 80.96,94.4 80.56,94.01 80.56,90.51 80.45,90.39 80.45,87.73 80.18,87.46 U11.BA37
  TOP w0.165: 80.96,97.11 80.96,98.45 73.68,105.73 46.44,105.73 44.61,107.56 40.86,107.56 U1637.C3
M_A_DQ39: length 56.5
  TOP w0.076: 80.6,97.05 80.6,94.74 80.28,94.42 80.28,88.2 80.18,88.1 U11.BB37
  TOP w0.165: U1637.C2 39.77,108.72 39.77,108.14 40.71,107.2 44.46,107.2 46.29,105.37 73.47,105.37 80.6,98.24 80.6,97.05
M_A_DQ40: length 66.5
  TOP w0.076: U11.AY35 81.41,86.7 81.41,86.97 81.48,87.15 81.48,87.36 81.44,87.45 81.44,87.71 81.48,87.8 81.48,88.37 81.27,88.57 81.27,89.62 81.9,90.25 81.9,91.89 v2(81.34,92.45)
  L3_IN1 w0.216: v3(43.84,103.43) 44.1,103.43 44.74,102.79 75.15,102.79 78.7,99.24 78.7,90.19 79.07,89.82 80.1,89.82 80.41,90.13 80.41,93.63 80.98,94.21 81.54,94.21 81.81,93.94 81.81,92.91 v2(81.34,92.45)
  BOTTOM w0.102: U1638.D3 39.74,104.68 41.89,104.68 42,104.78 42.55,104.78 42.82,104.51 42.82,104.22 43.61,103.43 v3(43.84,103.43)
M_A_DQ41: length 67.2
  TOP w0.076: U11.AW35 81.31,86.14 80.99,86.46 80.99,87.01 80.78,87.22 80.78,88.33 80.78,88.34 80.78,90.19 80.92,90.33 80.92,93.32 v3(81.34,93.75)
  L3_IN1 w0.216: v3(81.34,93.75) 80.86,93.26 80.86,90.35 81.38,89.82 81.38,88.63 81.06,88.3 80.48,88.3 79.75,89.04 79.15,89.04 78.25,89.93 78.25,99.11 74.98,102.39 44.57,102.39 43.97,102.99 43.51,102.99 v3(43.14,103.37)
  BOTTOM w0.102: U1638.C2 40.53,103.89 42.42,103.89 42.95,103.37 v3(43.14,103.37)
M_A_DQ42: length 67.8
  TOP w0.076: v3(83.12,96.35) 83.63,95.84 83.63,92.41 83.52,92.29 83.52,92.28 82.95,91.72 82.95,88.79 82.79,88.63 82.79,88.31 82.84,88.25 82.97,88.13 82.97,87.76 82.86,87.52 82.81,87.42 82.81,87.08 82.54,86.81 U11.AY33
  L3_IN1 w0.216: v3(83.12,96.35) 82.85,96.08 82.85,95.82 83,95.67 83.41,95.67 83.56,95.82 83.56,98.03 76.2,105.38 64.64,105.38 64.43,105.6 64.43,105.98 64.21,106.2 63.78,106.2 63.57,105.98 63.57,105.6 63.35,105.38 62.92,105.38 62.7,105.6 62.7,105.98 62.49,106.2 62.05,106.2 61.84,105.98 61.84,105.6 61.62,105.38 61.19,105.38 60.97,105.6 60.97,105.98 60.76,106.2 60.33,106.2 60.11,105.98 60.11,105.6 59.89,105.38 59.46,105.38 59.25,105.6 59.25,105.98 59.03,106.2 57.68,106.2 57.32,105.84 57.07,105.84 56.72,106.2 55.95,106.2 55.61,105.86 55.33,105.86 54.99,106.2 54.22,106.2 53.87,105.85 53.61,105.85 53.26,106.2 52.49,106.2 52.15,105.85 51.88,105.85 51.54,106.2 48.63,106.2 46.41,108.41 45.72,109.11 45.52,109.11 45.27,108.85 45.11,108.85 44.63,109.33 v3(44.63,109.38)
  BOTTOM w0.102: U1638.C8 40.27,109.09 40.74,109.56 41.91,109.56 42.23,109.88
  BOTTOM w0.165: v3(44.63,109.38) 44.13,109.88 42.23,109.88
M_A_DQ43: length 65.8
  TOP w0.076: U11.AW33 81.89,85.95 81.68,86.16 81.68,86.67 81.61,86.77 81.61,87.02 81.65,87.15 81.65,87.37 81.65,87.38 81.64,87.39 81.64,87.39 81.61,87.48 81.61,87.68 81.64,87.77 81.64,88.44 81.44,88.64 81.44,89.55 82.07,90.18 82.07,92.66 81.94,92.79 81.94,95.81 v3(83.12,97)
  L3_IN1 w0.216: v3(44.05,109.35) 44.05,109.34 44.94,108.45 45.8,108.45 45.82,108.43 48.46,105.79 51.37,105.79 51.58,105.57 51.58,105.19 51.8,104.98 52.23,104.98 52.45,105.19 52.45,105.57 52.66,105.79 53.09,105.79 53.31,105.57 53.31,105.19 53.53,104.98 53.96,104.98 54.17,105.19 54.17,105.57 54.39,105.79 54.82,105.79 55.04,105.57 55.04,105.19 55.25,104.98 55.69,104.98 55.9,105.19 55.9,105.57 56.12,105.79 56.55,105.79 56.76,105.57 56.76,105.19 56.98,104.98 57.41,104.98 57.63,105.19 57.63,105.57 57.84,105.79 58.28,105.79 58.49,105.57 58.49,105.19 58.71,104.98 76.03,104.98 83.12,97.89 v3(83.12,97)
  BOTTOM w0.102: U1638.B8 41.31,108.71 42.36,108.71
  BOTTOM w0.165: v3(44.05,109.35) 43.88,109.53 43.18,109.53 42.36,108.71
M_A_DQ44: length 65.1
  TOP w0.076: v3(81.34,91.8) 81.74,91.4 81.74,90.32 81.11,89.69 81.11,88.47 81.11,88.47 81.11,88 U11.BB35
  L3_IN1 w0.216: v3(81.34,91.8) 81.34,91.11 81.54,90.92 81.97,90.92 82.48,91.43 82.48,92.06 82.13,92.41 82.13,94.1 81.76,94.46 81.76,94.47 81.57,94.67 80.41,94.67 80.04,94.3 80.04,90.63 79.83,90.41 79.35,90.41 79.14,90.61 79.14,99.37 75.31,103.2 44.9,103.2 43.79,104.32 v3(43.47,104.32)
  BOTTOM w0.102: v3(43.47,104.32) 43.47,104.43 42.81,105.09 U1638.A3
M_A_DQ45: length 66
  TOP w0.076: U11.BA35 81.21,87.47 80.94,87.74 80.94,88.4 80.94,88.4 80.94,90.1 v3(81.34,90.5)
  L3_IN1 w0.216: v3(81.34,90.5) 82.05,89.79 82.41,89.79 82.97,90.35 82.97,91.98 82.94,92.01 82.68,92.27 82.68,92.27 82.44,92.51 82.44,94.31 81.65,95.11 79.97,95.11 79.79,95.29 79.79,95.83 80.01,96.05 81.59,96.05 81.8,96.26 81.8,96.69 81.59,96.91 80.01,96.91 79.79,97.12 79.79,97.44 80.01,97.66 80.72,97.66 80.93,97.87 80.93,98.16 80.57,98.52 80.01,98.52 79.79,98.74 79.79,99.3 75.47,103.62 45.11,103.62 v3(44.34,104.38)
  BOTTOM w0.102: v3(44.34,104.38) 44.6,104.64 44.6,104.95 43.54,106.01 42.8,106.01 42.75,106.06 40.56,106.06 40.13,105.63 U1638.C3
M_A_DQ46: length 68
  TOP w0.076: U11.BA33 82.54,87.4 82.68,87.54 82.68,87.55 82.69,87.55 82.8,87.8 82.8,88.06 82.63,88.24 82.63,88.7 82.77,88.84 82.77,92.09 v3(83.12,92.45)
  L3_IN1 w0.216: v3(43.1,106.43) 42.05,107.48 42.05,109.65 42.73,110.33 45.64,110.33 48.96,107.01 64.58,107.01 65.39,106.2 76.54,106.2 84.37,98.36 84.37,93.7 v3(83.12,92.45)
  BOTTOM w0.102: U1638.D7 39.33,107.93 40.68,106.58 42.95,106.58 v3(43.1,106.43)
M_A_DQ47: length 65.1
  TOP w0.076: U11.BB33 82.54,88.04 82.46,88.11 82.46,88.77 82.6,88.91 82.6,92.58 v3(83.12,93.1)
  L3_IN1 w0.216: v3(83.12,93.1) 83.97,93.94 83.97,98.2 76.37,105.79 65.22,105.79 64.41,106.6 48.79,106.6 45.47,109.93 43.8,109.93 43.46,109.59 43.46,109.37 42.67,108.58 42.67,107.49 v3(43.73,106.43)
  BOTTOM w0.102: v3(43.73,106.43) 43.27,106.9 40.94,106.9 40.13,107.71 U1638.C7
M_A_DQ48: length 75.2
  TOP w0.076: U11.AY31 83.84,86.81 83.57,87.07 83.57,87.35 83.42,87.73 83.41,87.76 83.41,88.13 83.58,88.3 83.58,88.63 83.58,88.63 83.58,89.18 83.58,89.3 83.84,89.56 83.84,96.06
  TOP w0.102: v2(36.99,105.84) 36.42,105.84 35.67,105.09 U1637.J7
  TOP w0.165: 83.84,96.06 83.61,96.29 83.61,97.51 74.43,106.69 46.65,106.69 45.04,108.3 45.04,110.48 44,111.53 43.04,111.53 42.78,111.79 42.78,112.5 v3(43.1,112.82)
  L4_IN2 w0.216: v3(43.1,112.82) 43.1,112.73 42.44,112.07 41.99,112.07 41.8,112.26 41.48,112.26 40.73,111.5 40.73,110.99 40.28,110.54 40.28,109.05 39.91,108.68 39.91,108.24 40.47,107.68 40.47,106.22 40.02,105.77 37.06,105.77 v2(36.99,105.84)
M_A_DQ49: length 77.2
  TOP w0.076: U11.AW31 84.48,85.95 84.75,86.22 84.75,87.06 84.72,87.14 84.72,87.34 84.75,87.45 84.75,87.71 84.74,87.73 84.74,88.3 85.03,88.58 85.03,96.29
  TOP w0.102: U1637.H7 36.23,105.09 v2(36.59,105.45)
  TOP w0.165: v3(43.6,114.32) 43.79,114.13 46.15,114.13 46.82,113.46 51.08,113.46 55.9,108.64 75.27,108.64 85.55,98.35 85.55,96.82 85.03,96.29
  L4_IN2 w0.216: v2(36.59,105.45) 36.62,105.42 40.37,105.42 41.02,106.07 41.02,109.36 40.85,109.52 40.85,110.54 41.93,111.62 42.57,111.62 43.6,112.66 v3(43.6,114.32)
M_A_DQ50: length 75.4
  TOP w0.076: U11.AY29 84.96,86.7 84.96,86.96 84.89,87.17 84.89,87.31 84.92,87.42 84.92,87.75 84.91,87.77 84.91,88.23 85.19,88.51 85.19,95.97 85.43,96.21
  TOP w0.102: U1637.G2 36.72,109.09 36.53,109.28 36.53,110.35 36.79,110.62 36.79,111.1 v3(36.38,111.51)
  TOP w0.165: 85.43,96.21 85.91,96.69 85.91,98.5 75.42,108.99 56.05,108.99 51.22,113.82 46.97,113.82 46.3,114.49 44.54,114.49 44.16,114.87 41.46,114.87 40.66,114.08 38.84,114.08 v3(38.33,114.58)
  L4_IN2 w0.216: v3(36.38,111.51) 36.19,111.7 36.19,112.42 36.56,112.79 36.91,112.79 37.08,112.96 37.08,113.31 37.23,113.46 37.73,113.46 37.91,113.28 38.22,113.28 38.33,113.39 v3(38.33,114.58)
M_A_DQ51: length 77.2
  TOP w0.076: U11.AW29 85.06,86.17 85.37,86.48 85.37,87.02 85.6,87.25 85.6,88.2 85.69,88.29 85.69,89.86 85.89,90.06 85.89,95.12
  TOP w0.102: v3(35.78,109.47) 36.13,109.12 U1637.H2
  TOP w0.165: 85.89,95.12 87.08,96.31 87.08,98.9 75.92,110.06 56.49,110.06 51.66,114.88 47.42,114.88 46.74,115.56 44.98,115.56 44.6,115.94 40.96,115.94 40.28,115.26 38.33,115.26 37.73,114.66 v3(37.73,114.58)
  L4_IN2 w0.216: v3(37.73,114.58) 35.78,112.63 v3(35.78,109.47)
M_A_DQ52: length 75.3
  TOP w0.076: U11.BB31 83.91,87.97 83.91,89.12 84.24,89.45 84.24,96.91
  TOP w0.102: v3(38.01,102.58) 37.56,102.13 36.75,102.13 36.49,102.39 36.49,103.93 U1637.H8
  TOP w0.165: v3(44.71,112.82) 46.1,111.43 46.1,108.25 46.94,107.4 74.72,107.4 84.32,97.8 84.32,96.99 84.24,96.91
  L4_IN2 w0.216: v3(44.71,112.82) 44.71,112.6 42.5,110.4 42.5,110.22 41.87,109.59 41.87,105.69 39.59,103.41 38.56,103.41 38.01,102.86 v3(38.01,102.58)
M_A_DQ53: length 73.8
  TOP w0.076: 83.97,96.32 84.06,96.23 84.06,89.54 83.74,89.22 83.74,89.11 83.74,89.11 83.74,88.7 83.74,88.23 83.57,88.06 83.57,87.8 83.7,87.54 83.84,87.4 U11.BA31
  TOP w0.102: U1637.F7 v3(38.13,104.69)
  TOP w0.165: v3(44.1,112.82) 43.79,112.51 43.39,112.51 43.23,112.35 43.23,112.03 43.35,111.91 44.35,111.91 44.56,112.12 44.8,112.12 45.03,111.89 45.03,111.65 44.82,111.44 44.82,111.21 45.4,110.62 45.4,108.45 46.8,107.05 74.58,107.05 83.97,97.66 83.97,96.32
  L4_IN2 w0.216: v3(44.1,112.82) 44.1,112.57 42.7,111.18 42.06,111.18 41.74,110.86 41.74,110.04 41.43,109.72 41.43,105.73 40.8,105.1 38.55,105.1 v3(38.13,104.69)
M_A_DQ54: length 75.1
  TOP w0.076: U11.BA29 85.16,87.48 85.43,87.75 85.43,88.28 85.52,88.38 85.52,89.93 85.68,90.09 85.68,95.32
  TOP w0.102: U1637.H3 36.13,108.28 v3(36.49,107.92)
  TOP w0.165: 85.68,95.32 86.72,96.36 86.72,98.76 75.78,109.7 56.34,109.7 51.52,114.53 47.27,114.53 46.6,115.2 44.83,115.2 44.45,115.58 41.11,115.58 40.37,114.85 v3(39.9,114.85)
  L4_IN2 w0.216: v3(39.9,114.85) 39.31,114.26 39.31,112.24 37.95,110.88 37.95,110.14 37.68,109.86 37.68,109.1 v3(36.49,107.92)
M_A_DQ55: length 73.8
  TOP w0.076: 85.46,95.69 85.46,90.1 85.36,89.99 85.36,88.44 85.16,88.25 U11.BB29
  TOP w0.089: 35.49,108.47 35.49,108.45 U1637.J3
  TOP w0.102: 35.49,108.47 v3(35.77,108.74)
  TOP w0.165: v3(39.24,114.84) 39.65,114.43 40.46,114.43 41.26,115.23 44.3,115.23 44.68,114.85 46.45,114.85 47.12,114.17 51.37,114.17 56.2,109.35 75.63,109.35 86.33,98.65 86.33,96.56 85.46,95.69
  L4_IN2 w0.216: v3(35.77,108.74) 36.56,109.53 36.56,110.18 38.82,112.45 38.82,114.42 v3(39.24,114.84)
M_A_DQ56: length 81.4
  TOP w0.076: U11.AY27 86.39,86.7 86.39,86.97 86.46,87.15 86.46,87.36 86.42,87.45 86.42,87.71 86.46,87.8 86.46,88.06 86.35,88.17 86.35,89.2 87.16,90.01 87.16,91.89 v3(86.6,92.45)
  L3_IN1 w0.216: v3(86.6,92.45) 87.91,92.45 88.1,92.63 88.1,93.9 87.72,94.28 85.84,94.28 85.64,94.48 85.64,96.29 86.08,96.73 86.08,96.97 85.64,97.4 85.64,99.03 77.1,107.58 70.38,107.58 70.17,107.8 70.17,108.33 69.95,108.55 69.3,108.55 69.09,108.33 69.09,107.8 68.87,107.58 68.23,107.58 68.01,107.8 68.01,108.33 67.79,108.55 67.15,108.55 66.93,108.33 66.93,107.8 66.71,107.58 66.25,107.58 66.06,107.77 66.06,108.32 65.87,108.51 49.62,108.51 46.25,111.87 42.23,111.87 40.76,110.41 40.76,109.87 40.98,109.65 40.98,105.4 40.73,105.14 36.9,105.14 v3(36.5,104.74)
  BOTTOM w0.102: U1638.G2 36.93,104.3 v3(36.5,104.74)
M_A_DQ57: length 84.4
  TOP w0.076: v3(86.58,93.1) 86.18,92.69 86.18,89.73 85.85,89.41 85.85,88.22 85.76,88.13 85.76,87.22 85.97,87.01 85.97,86.46 86.29,86.14 U11.AW27
  L3_IN1 w0.216: v3(86.58,93.1) 86.15,93.1 86.03,92.98 86.03,90.77 85.88,90.62 85.47,90.62 85.24,90.86 85.24,98.86 76.93,107.18 65.87,107.18 64.98,108.06 49.48,108.06 46.08,111.47 43.09,111.47 41.64,110.02 41.64,103.59 41.47,103.41 40.77,103.41 40.55,103.62 40.55,104.42 40.33,104.64 39.71,104.64 39.5,104.42 39.5,103.62 39.28,103.41 38.22,103.41 37.32,102.51 v3(37.1,102.51)
  BOTTOM w0.089: 36.37,103.98 36.13,104.21 U1638.H2
  BOTTOM w0.102: v3(37.1,102.51) 36.56,103.05 36.56,103.79 36.37,103.98
M_A_DQ58: length 84.2
  TOP w0.076: U11.AY25 87.52,86.77 87.77,87.03 87.77,87.51 87.88,87.62 87.96,87.78 87.96,89.31 88.17,89.52 88.17,91.69 89.07,92.59 89.07,96.27 89.59,96.79
  TOP w0.102: v3(91.26,97.54) 90.34,97.54 89.59,96.79
  L3_IN1 w0.216: v2(35.73,107.96) 35.69,107.96 35.33,108.32 35.33,112.25 37.23,114.16 37.23,114.7 38.94,116.41 47.29,116.41 51.69,112 77.47,112 91.26,98.22 v3(91.26,97.54)
  BOTTOM w0.089: v2(35.73,107.96) 35.73,107.98 35.42,108.29 U1638.J7
M_A_DQ59: length 82.6
  TOP w0.076: U11.AW25 86.87,85.95 86.66,86.16 86.66,86.67 86.59,86.77 86.59,87.02 86.63,87.15 86.63,87.37 86.63,87.38 86.62,87.39 86.62,87.39 86.59,87.48 86.59,87.68 86.62,87.77 86.62,88.13 86.51,88.24 86.51,89.13 87.33,89.94 87.33,92.09 87.15,92.26 87.15,94.42 88.22,95.49 88.22,96.83 v3(88.28,96.89)
  L3_IN1 w0.216: v3(88.28,96.89) 88.22,96.94 88.22,97.03 87.62,97.63 87.32,97.63 86.85,97.17 86.55,97.17 86.24,97.47 86.24,97.78 86.71,98.24 86.71,98.55 77.26,107.99 73.23,107.99 73.02,108.2 73.02,108.78 72.8,109 72.15,109 71.94,108.78 71.94,108.2 71.72,107.99 71.07,107.99 70.86,108.2 70.86,108.74 70.64,108.95 49.93,108.95 46.57,112.32 42.06,112.32 40.35,110.61 40.35,109.13 40.09,108.87 40.09,107.94 40.28,107.74 40.28,106.1 39.95,105.77 37.69,105.77 36.55,106.91 v3(36.52,106.91)
  BOTTOM w0.089: U1638.J3 35.33,105.17 36.37,106.2
  BOTTOM w0.102: 36.37,106.2 36.56,106.39 36.56,106.87 v3(36.52,106.91)
M_A_DQ60: length 80.4
  TOP w0.076: U11.BB27 86.18,87.91 86.18,89.26 87,90.08 87,91.4 v3(86.6,91.8)
  L3_IN1 w0.216: v3(36.47,108.67) 36.53,108.73 36.53,110.13 36.9,110.5 36.9,111.54 39.53,114.16 39.87,114.16 41.3,115.59 46.95,115.59 51.35,111.19 77.14,111.19 90.37,97.96 90.37,93.19 89.11,91.94 88.48,91.94 87.65,91.11 86.76,91.11 86.6,91.27 v3(86.6,91.8)
  BOTTOM w0.102: v3(36.47,108.67) 36.13,108.33 U1638.H7
M_A_DQ61: length 81.7
  TOP w0.076: U11.BA27 86.19,87.47 85.93,87.74 85.93,88.06 86.02,88.15 86.02,89.33 86.6,89.92 v3(86.6,90.5)
  L3_IN1 w0.216: v3(36.39,110.88) 36.39,110.89 35.9,111.37 35.9,112 37.8,113.91 38.38,113.91 38.81,114.34 38.81,115.02 39.78,116 47.12,116 51.52,111.59 77.3,111.59 90.77,98.12 90.77,92.96 88.31,90.5 v3(86.6,90.5)
  BOTTOM w0.102: U1638.H8 36.55,109.51 36.55,110.71 v3(36.39,110.88)
M_A_DQ62: length 80.7
  TOP w0.076: U11.BA25 87.54,87.27 87.54,87.5 87.74,87.71 87.79,87.82 87.79,89.37 88.01,89.59 88.01,92.11 88.56,92.67 v3(88.59,92.67)
  L3_IN1 w0.216: v3(37,107.28) 37,108.64 37.68,109.32 37.68,109.97 37.96,110.25 37.96,110.46 37.31,111.1 37.31,111.37 39.68,113.74 40.02,113.74 41.47,115.19 46.78,115.19 51.18,110.78 76.97,110.78 89.96,97.79 89.96,93.42 89.21,92.67 v3(88.59,92.67)
  BOTTOM w0.089: U1638.H3 36.13,105.52 36.37,105.76
  BOTTOM w0.102: 36.37,105.76 36.93,106.32 36.93,107.21 v3(37,107.28)
M_A_DQ63: length 79.6
  TOP w0.076: U11.BB25 87.52,88.13 87.53,88.14 87.63,88.24 87.63,89.44 87.82,89.64 87.82,89.64 87.84,89.66 87.84,92.48 v3(88.59,93.23)
  L3_IN1 w0.216: v2(38.14,107.86) 37.79,107.5 37.54,107.5 37.35,107.69 37.35,108.23 37.49,108.37 38.42,108.37 38.51,108.45 38.51,109.65 38.82,109.95 38.82,110.67 38.66,110.83 38.47,110.83 38.25,111.05 38.25,111.54 38.44,111.73 38.87,111.73 39.21,112.07 39.21,112.69 39.85,113.33 40.19,113.33 41.63,114.78 43.87,114.78 44.08,114.56 44.08,114.44 44.3,114.22 44.73,114.22 44.95,114.44 44.95,114.56 45.16,114.78 45.57,114.78 45.74,114.6 45.74,114.41 45.99,114.17 46.31,114.17 46.62,114.48 46.91,114.48 51.02,110.38 76.8,110.38 89.55,97.62 89.55,96.04 89.2,95.68 89.2,95.32 89.55,94.97 89.55,94.64 89.3,94.38 89.3,94.14 89.55,93.88 89.55,93.71 89.07,93.23 v3(88.59,93.23)
  BOTTOM w0.102: U1638.F7 38.02,108.29 38.14,108.17 v2(38.14,107.86)
M_A_DQS0: length 32.8
  TOP w0.076: U11.AM69 61.84,81.64 61.51,81.31 61.21,81.31 61.13,81.35 60.92,81.35 60.81,81.29 60.59,81.29 60.48,81.35 59.92,81.35 59.84,81.27 59.36,81.27 59.16,81.47 55.24,81.47 55.2,81.44 55,81.44 54.97,81.47 54.9,81.54 54.9,81.57 54.89,81.58
  TOP w0.114: v2(37.38,88.15) 37.38,88.61 37.3,88.7 37.3,89.37 37.17,89.5 37.17,89.59 37.01,89.75 U1636.G3
  TOP w0.165: v2(44.94,80.88) 44.94,81.02 45.32,81.39 46.57,81.39 46.91,81.74 54.73,81.74 54.89,81.58
  L4_IN2 w0.203: v2(44.94,80.88) 44.94,81.9 42.45,84.39 42.11,84.39 40.9,85.6 40.9,87.66 39.73,88.82 37.86,88.82 37.55,88.52 37.55,88.31 v2(37.38,88.15)
M_A_DQS1: length 33.1
  TOP w0.076: v3(56.2,85.87) 56.37,85.7 56.37,85.28 56.55,85.09 58.26,85.09 58.85,84.5 59.86,84.5 60.02,84.33 60.51,84.33 60.65,84.38 60.76,84.38 60.89,84.33 61.16,84.33 61.24,84.36 61.46,84.36 61.59,84.3 61.6,84.29 61.6,84.14 61.56,84.1 U11.AT70
  L3_IN1 w0.203: v2(38.8,87.88) 39.21,88.29 39.86,88.29 40.28,87.87 40.28,86.49 39.65,85.86 39.65,84.25 39.9,84 41.93,84 42.02,83.91 44.58,83.91 45.13,84.46 54.44,84.46 55.32,85.34 56.28,85.34 56.43,85.48 56.43,85.65 v3(56.2,85.87)
  BOTTOM w0.114: v2(38.8,87.88) 38.8,87.63 38.31,87.14 37.63,87.14 37.03,86.55 U1635.G3
M_A_DQS2: length 34
  TOP w0.076: v2(58.85,91.81) 58.74,91.81 58.64,91.92 58.64,92.01 58.74,92.11 59.43,92.11 59.75,91.79 59.75,90.47 60.11,90.11 63.05,90.11 64.2,88.96 64.2,88.26 64.4,88.06 64.4,87.8 64.35,87.68 64.35,87.47 64.4,87.36 64.4,87.15 64.36,87.07 64.36,86.78 64.45,86.59 64.54,86.51 64.66,86.51 64.7,86.47 U11.AY64
  L3_IN1 w0.203: v2(58.85,91.81) 58.85,91.91 59.05,92.11 59.32,92.11 59.64,91.8 59.64,90.74 59,90.11 57.31,90.11 57.03,90.39 52.38,90.39 51.41,89.41 43.73,89.41 43.6,89.54 43.6,89.68 43.72,89.8 v2(43.81,89.8)
  BOTTOM w0.114: v2(43.81,89.8) 43.54,89.53 43.54,89.35 43.31,89.12 41.71,89.12 41.37,89.45 41.37,89.62 41.25,89.75 U1635.B7
M_A_DQS3: length 36.3
  TOP w0.076: U11.BA60 67.15,86.62 67.18,86.58 67.25,86.58 67.36,86.69 67.42,86.82 67.42,87.04 67.38,87.12 67.38,87.39 67.43,87.52 67.43,87.63 67.39,87.74 67.32,87.87 67.32,88.17 67.49,88.34 67.49,88.6 67.17,88.91 67.17,89.29 65.12,91.34 65.12,92.36 65.08,92.41
  TOP w0.165: 65.08,92.41 65.08,92.95 63.59,94.44 57.29,94.44 52.83,89.97 52.17,89.97 50.03,87.83 45.36,87.83 44.57,87.05 44.03,87.05 43.29,86.31 42.15,86.31 42,86.16 41.49,86.16 41.1,86.55 U1636.B7
M_A_DQS4: length 55.2
  TOP w0.076: 78.91,96.8 78.91,96.78 78.92,96.77 78.92,92.18 79.33,91.76 79.33,89.54 79.17,89.38 79.17,88.96 78.99,88.78 78.99,88.29 79.12,88.16 79.12,87.77 79.07,87.66 79.07,87.63 79.07,87.44 79.12,87.33 79.12,87.13 79.09,87.05 79.09,86.76 79.13,86.66 79.22,86.52 79.34,86.35 79.42,86.28 U11.AY38
  TOP w0.165: U1637.B7 41.32,104.7 42.05,104.7 42.18,104.83 44.76,104.83 45.68,103.9 68.92,103.9 69.28,103.55 69.28,102.81 69.61,102.48 70.35,102.48 70.69,102.81 70.69,103.54 70.85,103.71 71.66,103.71 71.84,103.52 71.84,102.92 72.28,102.48 73.97,102.48 78.91,97.54 78.91,96.8
M_A_DQS5: length 66.5
  TOP w0.076: U11.BA34 81.87,86.93 81.87,86.72 81.94,86.66 82.02,86.66 82.06,86.67 82.11,86.76 82.14,86.82 82.14,87.04 82.11,87.12 82.11,87.39 82.16,87.52 82.16,87.63 82.16,87.65 82.1,87.76 82.1,88.88 82.24,89.01 82.24,94.72 82.39,94.88 82.95,94.88 v3(83.12,95.05)
  L3_IN1 w0.203: v3(83.12,95.05) 83,94.93 82.81,94.93 82.47,95.28 82.47,97.82 75.82,104.46 51.26,104.46 51.05,104.67 51.05,104.88 50.66,105.28 49.77,105.28 49.38,104.88 49.38,104.67 49.17,104.46 48.33,104.46 48.09,104.7 48.09,105.33 47.46,105.97 46.88,105.97 45.61,104.69 45.23,104.69 44.84,105.08 44.84,105.37 46.21,106.75 46.21,107.31 45.59,107.93 45.03,107.93 44.48,107.39 44.19,107.39 43.81,107.77 v2(43.81,108.34)
  BOTTOM w0.114: v2(43.81,108.34) 43.58,108.11 43.58,107.69 43.37,107.47 41.47,107.47 41.2,107.73 41.2,108.17 41.09,108.29 U1638.B7
M_A_DQS6: length 76.4
  TOP w0.076: U11.AY30 84.33,86.37 84.31,86.36 84.07,86.75 84.07,87.09 84.1,87.15 84.1,87.36 84.03,87.51 84.03,87.67 84.1,87.81 84.1,89.05 84.33,89.28 84.46,89.41 84.46,96.35 84.41,96.4 84.41,96.6 84.44,96.64 84.44,96.7 84.45,96.71
  TOP w0.114: v2(37.38,106.69) 37.57,106.88 37.57,107.37 37.2,107.73 37.2,108.01 U1637.G3
  TOP w0.165: 84.45,96.71 84.79,97.05 84.79,98.03 74.95,107.87 47.14,107.87 46.57,108.45 46.57,111.62 46.03,112.16 46.03,112.92 45.61,113.33 42.76,113.33 42.64,113.46 42.28,113.46 42.02,113.71 42.02,114.15 v2(41.81,114.37)
  L4_IN2 w0.203: v2(41.81,114.37) 41.98,114.19 41.98,113.96 39.39,111.36 39.39,109.36 38.93,108.9 38.93,107.99 38.34,107.39 37.88,107.39 37.59,107.1 37.59,106.9 v2(37.38,106.69)
M_A_DQS7: length 82.9
  TOP w0.076: U11.BA26 86.85,86.93 86.85,86.72 86.92,86.66 87,86.66 87.05,86.67 87.1,86.76 87.12,86.82 87.12,87.04 87.09,87.12 87.09,87.39 87.14,87.52 87.14,87.63 87.09,87.77 87.09,88.22 87.25,88.39 87.25,89.53 87.5,89.78 87.5,94.29 87.98,94.78 88.33,94.78 88.58,95.03 v3(88.58,95.05)
  L3_IN1 w0.203: v3(88.58,95.05) 86.67,95.05 86.56,95.17 86.56,95.83 86.77,96.05 88.55,96.05 89.04,96.54 89.04,97.41 77.61,108.83 76.8,108.83 76.59,109.04 76.59,109.45 76.2,109.84 75.31,109.84 74.92,109.45 74.92,109.04 74.71,108.83 74.11,108.83 73.9,109.04 73.9,109.45 73.51,109.84 50.75,109.84 46.94,113.65 41.59,113.65 39.36,111.42 39.36,109.34 39.03,109 39.03,107.89 38.69,107.56 38.69,106.73 v2(38.65,106.69)
  BOTTOM w0.114: U1638.G3 37.07,105.23 37.07,105.41 37.48,105.82 38.52,105.82 38.67,105.97 38.67,106.66 v2(38.65,106.69)
M_A_DQS#0: length 32.8
  TOP w0.076: U11.AM70 61.35,81.76 61.43,81.84 61.54,81.84 61.61,81.76 61.61,81.65 61.44,81.48 61.24,81.48 61.16,81.51 60.89,81.51 60.76,81.46 60.65,81.46 60.51,81.51 59.85,81.51 59.77,81.43 59.43,81.43 59.17,81.69 55.2,81.69
  TOP w0.114: U1636.F3 37.7,89.78 37.55,89.78 37.45,89.67 37.45,89.56 37.54,89.47 37.54,88.8 37.62,88.71 37.62,88.42 37.9,88.15 v2(38.02,88.15)
  TOP w0.165: 55.2,81.69 54.85,82.03 46.79,82.03 46.45,81.69 45.2,81.69 44.42,80.91 v2(44.33,80.91)
  L4_IN2 w0.203: v2(38.02,88.15) 37.99,88.15 37.88,88.26 37.88,88.38 37.99,88.49 39.6,88.49 40.57,87.52 40.57,85.46 41.97,84.06 42.31,84.06 44.61,81.76 44.61,81.19 v2(44.33,80.91)
M_A_DQS#1: length 33
  TOP w0.076: v3(56.97,85.87) 56.69,85.87 56.57,85.75 56.57,85.36 56.64,85.3 58.36,85.3 58.99,84.67 59.92,84.67 60.09,84.49 60.48,84.49 60.59,84.55 60.81,84.55 60.92,84.49 61.13,84.49 61.21,84.53 61.5,84.53 61.69,84.44 61.69,84.44 61.77,84.36 61.77,84.15 61.82,84.1 U11.AT69
  L3_IN1 w0.203: v2(39.44,87.89) 39.44,87.92 39.49,87.96 39.72,87.96 39.95,87.74 39.95,86.63 39.32,86 39.32,84.11 39.76,83.67 41.79,83.67 41.88,83.58 44.71,83.58 45.26,84.13 54.57,84.13 55.45,85.01 56.42,85.01 56.76,85.35 56.76,85.65 v3(56.97,85.87)
  BOTTOM w0.114: U1635.F3 37.62,86.66 37.62,86.79 37.73,86.9 38.41,86.9 39.4,87.89 v2(39.44,87.89)
M_A_DQS#2: length 33.9
  TOP w0.076: U11.BA64 64.8,86.72 64.75,86.68 64.6,86.68 64.59,86.69 64.53,86.82 64.53,87.04 64.56,87.12 64.56,87.39 64.51,87.52 64.51,87.63 64.51,87.65 64.56,87.76 64.56,88.13 64.4,88.29 64.4,89.04 63.13,90.31 60.2,90.31 59.96,90.54 59.96,91.88 59.53,92.31 59,92.31 v2(58.85,92.46)
  L3_IN1 w0.203: v2(43.15,89.8) 43.27,89.67 43.27,89.4 43.6,89.08 51.54,89.08 52.52,90.06 56.89,90.06 57.17,89.78 59.14,89.78 59.97,90.6 59.97,91.94 59.46,92.44 58.87,92.44 v2(58.85,92.46)
  BOTTOM w0.114: v2(43.15,89.8) 43.3,89.64 43.3,89.45 43.21,89.36 41.81,89.36 41.62,89.55 41.62,89.66 41.7,89.75 U1635.A7
M_A_DQS#3: length 36.3
  TOP w0.076: U11.AY60 67.25,86.35 67.49,86.59 67.58,86.78 67.58,87.07 67.55,87.15 67.55,87.36 67.6,87.47 67.6,87.49 67.6,87.66 67.54,87.81 67.54,88.08 67.71,88.25 67.71,88.69 67.39,89 67.39,89.38 65.33,91.45 65.33,92.36 65.37,92.4 65.37,92.41
  TOP w0.165: U1636.A7 41.61,86.66 41.61,86.79 41.73,86.91 41.93,86.91 42.24,86.6 43.17,86.6 43.91,87.34 44.45,87.34 45.23,88.13 49.91,88.13 52.05,90.27 52.7,90.27 57.17,94.73 63.71,94.73 65.37,93.07 65.37,92.41
M_A_DQS#4: length 55.2
  TOP w0.076: U11.BA38 79.52,86.9 79.6,86.73 79.6,86.62 79.46,86.57 79.39,86.57 79.33,86.65 79.28,86.73 79.25,86.8 79.25,87.01 79.29,87.09 79.29,87.37 79.23,87.5 79.24,87.62 79.29,87.74 79.29,88.23 79.16,88.36 79.16,88.72 79.33,88.89 79.33,89.2 79.55,89.42 79.55,91.83 79.12,92.26 79.12,96.72 79.2,96.8
  TOP w0.165: 79.2,96.8 79.2,97.66 74.09,102.77 72.41,102.77 72.13,103.04 72.13,103.64 71.78,104 70.73,104 70.39,103.66 70.39,102.93 70.23,102.77 69.73,102.77 69.57,102.93 69.57,103.67 69.05,104.19 45.81,104.19 44.88,105.12 42.27,105.12 42.06,105.33 41.81,105.33 41.73,105.26 U1637.A7
M_A_DQS#5: length 66.4
  TOP w0.076: v3(83.12,94.4) 83.12,94.65 83.1,94.68 82.97,94.68 82.94,94.71 82.47,94.71 82.4,94.64 82.4,88.94 82.27,88.81 82.27,87.8 82.32,87.68 82.32,87.47 82.27,87.36 82.27,87.15 82.31,87.07 82.31,86.79 82.26,86.68 82.18,86.54 82.05,86.49 81.99,86.49 81.97,86.47 U11.AY34
  L3_IN1 w0.203: v2(43.15,108.34) 43.48,108.01 43.48,107.64 44.06,107.06 44.62,107.06 45.16,107.6 45.45,107.6 45.88,107.17 45.88,106.88 44.51,105.51 44.51,104.95 45.09,104.36 45.75,104.36 47.02,105.64 47.32,105.64 47.76,105.2 47.76,104.56 48.19,104.13 49.31,104.13 49.71,104.53 49.71,104.74 49.91,104.95 50.52,104.95 50.72,104.74 50.72,104.53 51.12,104.13 75.68,104.13 82.14,97.68 82.14,95.14 82.68,94.6 82.92,94.6 v3(83.12,94.4)
  BOTTOM w0.114: v2(43.15,108.34) 43.34,108.15 43.34,107.79 43.27,107.71 41.59,107.71 41.46,107.84 41.46,108.17 41.57,108.29 U1638.A7
M_A_DQS#6: length 76.4
  TOP w0.076: 84.66,96.5 84.66,89.33 84.47,89.14 84.27,88.94 84.27,87.76 84.22,87.65 84.22,87.63 84.22,87.52 84.27,87.39 84.27,87.12 84.23,87.04 84.23,86.82 84.26,86.76 84.34,86.63 84.38,86.58 84.53,86.6 84.55,86.75 U11.BA30
  TOP w0.114: U1637.F3 37.46,108.01 37.46,107.84 37.83,107.47 37.83,106.88 v2(38.02,106.69)
  TOP w0.165: v2(42.43,114.37) 42.31,114.25 42.31,113.83 42.4,113.75 42.76,113.75 42.88,113.63 45.74,113.63 45.82,113.54 46.32,113.04 46.32,112.28 46.86,111.74 46.86,108.57 47.26,108.17 75.07,108.17 85.08,98.15 85.08,96.92 84.66,96.5
  L4_IN2 w0.203: v2(38.02,106.69) 37.92,106.78 37.92,106.97 38.02,107.06 38.47,107.06 39.26,107.85 39.26,108.76 39.72,109.22 39.72,111.23 42.31,113.82 42.31,114.25 v2(42.43,114.37)
M_A_DQS#7: length 82.9
  TOP w0.076: U11.AY26 86.95,86.47 86.97,86.49 87.03,86.49 87.16,86.54 87.24,86.68 87.29,86.79 87.29,87.07 87.25,87.15 87.25,87.36 87.3,87.47 87.3,87.68 87.25,87.8 87.25,88.12 87.45,88.32 87.45,89.5 87.67,89.72 87.67,94.16 88.07,94.56 88.42,94.56 v3(88.58,94.4)
  L3_IN1 w0.203: v3(88.58,94.4) 88.26,94.72 86.54,94.72 86.23,95.03 86.23,95.97 86.64,96.38 88.41,96.38 88.71,96.68 88.71,97.27 77.48,108.5 76.66,108.5 76.26,108.9 76.26,109.31 76.06,109.51 75.45,109.51 75.25,109.31 75.25,108.9 74.85,108.5 73.97,108.5 73.57,108.9 73.57,109.31 73.37,109.51 50.61,109.51 46.8,113.32 41.73,113.32 39.69,111.29 39.69,109.2 39.36,108.86 39.36,107.75 39.02,107.42 39.02,106.93 39.26,106.69 v2(39.29,106.69)
  BOTTOM w0.114: v2(39.29,106.69) 39.16,106.69 38.91,106.44 38.91,105.87 38.62,105.58 37.58,105.58 37.31,105.31 37.31,105.17 37.39,105.09 U1638.F3
M_B_A0: length 50.9
  TOP w0.076: 75.06,91.7 75.39,91.36 75.39,89.53 75.4,89.04 75.49,88.94 75.49,87.7 75.23,87.43 U11.BA46
  TOP w0.102: 75.06,91.7 74.94,91.82 74.94,96.14 74.39,96.68 v3(72.87,96.68)
  TOP w0.165: CN11.144 85.22,123.73 84.73,123.24 82.48,123.24 v3(82.09,122.84)
  L4_IN2 w0.216: v3(82.09,122.84) 82.11,122.84 82.38,123.11 82.86,123.11 82.94,123.04 82.94,119.53 83.33,119.13 83.33,118.89 82.94,118.49 82.94,118.28 83.33,117.89 83.33,117.66 82.94,117.27 82.94,116.99 83.33,116.6 83.33,116.34 72.82,105.83 72.82,96.73 v3(72.87,96.68)
M_B_A1: length 51.3
  TOP w0.076: U11.AY46 75.13,86.86 75.03,86.96 74.95,87.17 74.95,87.31 75.02,87.54 75.02,87.68 74.96,87.8 74.96,88.06 75.16,88.26 75.16,88.81 75.06,88.91 75.06,88.93 75.06,91.14 74.56,91.65 74.56,91.66
  TOP w0.102: 74.56,91.66 74.52,91.7 74.52,95.67 74.44,95.75 74.27,95.75 74.19,95.67 74.19,94.65 74.04,94.5 73.81,94.5 73.7,94.6 73.7,95.73 73.63,95.81 73.4,95.81 73.32,95.73 73.32,94.83 73.22,94.73 v3(72.87,94.73)
  TOP w0.165: v3(82,120.53) 81.81,120.53 81.75,120.6 81.75,120.83 81.87,120.96 82.44,120.96 82.57,120.83 82.57,120.17 82.47,120.08 CN11.133
  L4_IN2 w0.216: v3(82,120.53) 82,116.96 82,116.54 81.78,116.32 81.36,116.32 80.77,115.73 80.77,115.37 80.55,115.15 80.19,115.15 79.55,114.51 79.55,114.1 79.33,113.88 78.92,113.88 78.33,113.29 78.33,112.86 78.13,112.66 77.7,112.66 77.11,112.07 77.11,111.63 76.92,111.43 76.47,111.43 75.89,110.85 75.89,110.45 75.65,110.21 75.25,110.21 74.67,109.63 74.67,109.03 74.45,108.81 73.85,108.81 73.45,108.41 73.45,108.04 73.31,107.91 72.95,107.91 72.82,107.78 72.82,107.37 72.68,107.23 72.27,107.23 71.88,106.84 71.88,95.72 72.11,95.49 72.11,95.29 71.99,95.17 71.99,94.95 72.44,94.51 72.64,94.51 v3(72.87,94.73)
M_B_A2: length 51.5
  TOP w0.076: 74.27,91.7 74.27,91.28 74.44,91.11 74.83,91.11 74.9,91.04 74.9,90.81 74.82,90.74 74.52,90.74 74.44,90.66 74.44,90.51 74.52,90.43 74.82,90.43 74.9,90.35 74.9,89.33 74.9,89 74.9,89 74.9,88.84 75,88.74 75,88.33 74.8,88.13 74.8,87.76 74.81,87.73 74.84,87.65 74.84,87.53 74.78,87.31 74.78,87.17 74.83,87.01 74.83,86.58 U11.AY47
  TOP w0.102: v3(72.87,94.08) 74.1,94.08 74.27,93.91 74.27,91.7
  TOP w0.165: CN11.132 82.22,124.32 82.13,124.23 81.78,124.23 81.62,124.07 81.62,123.56 81.73,123.45 v3(82.06,123.45)
  L4_IN2 w0.216: v3(82.06,123.45) 82.06,123.87 81.92,124.01 81.42,124.01 81.26,123.85 81.26,123.2 81.53,122.94 81.53,117.15 71.41,107.04 71.41,94.87 72.31,93.97 72.75,93.97 v3(72.87,94.08)
M_B_A3: length 49.3
  TOP w0.076: U11.BB46 75.33,88 75.33,88.88 75.23,88.97 75.23,89.47 75.23,89.47 75.23,91.26 74.79,91.7
  TOP w0.102: 74.79,91.7 74.75,91.74 74.75,95.96 74.67,96.03 v3(72.87,96.03)
  TOP w0.165: CN11.131 81.97,119.77 81.33,120.42 81.33,121.5 81.07,121.76 81.07,121.99 81.22,122.14 81.49,122.14 82.01,121.61 v3(82.01,121.39)
  L4_IN2 w0.216: v3(82.01,121.39) 82.01,121.53 82.13,121.65 82.32,121.65 82.47,121.5 82.47,116.76 82.47,116.46 82.47,116.14 82.18,115.85 81.56,115.85 81.25,115.54 81.25,114.94 80.94,114.63 80.33,114.63 80.02,114.32 80.02,113.72 79.71,113.41 79.11,113.41 78.8,113.1 78.8,112.48 78.51,112.19 77.89,112.19 77.58,111.88 77.58,111.27 77.27,110.96 76.67,110.96 76.36,110.65 76.36,110.05 76.05,109.74 75.45,109.74 75.14,109.43 75.14,108.83 74.65,108.34 74.05,108.34 73.92,108.21 73.92,107.61 73.69,107.38 73.5,107.38 73.22,107.1 73.22,106.91 73.07,106.76 72.47,106.76 72.35,106.65 72.35,95.91 72.47,95.79 72.63,95.79 v3(72.87,96.03)
M_B_A4: length 51.3
  TOP w0.076: U11.BA47 74.34,87.15 74.34,87.37 74.34,87.38 74.33,87.39 74.33,87.39 74.3,87.48 74.3,87.68 74.33,87.77 74.33,88.17 74.21,88.29 74.21,89.1 74.29,89.18 74.62,89.18 74.7,89.25 74.7,89.4 74.62,89.48 74.29,89.48 74.21,89.56 74.21,89.71 74.29,89.78 74.62,89.78 74.7,89.86 74.7,90.01 74.62,90.09 74.29,90.09 74.21,90.17 74.21,90.52 74.15,90.58 74.15,90.68 74.27,90.8 74.27,90.9 74.16,91.01 74.05,91.01 73.94,90.9 73.83,90.9 73.44,91.29 73.44,91.31
  TOP w0.102: 73.44,91.31 73.44,91.49 73.62,91.67 73.62,93.27 73.45,93.43 v3(72.87,93.43)
  TOP w0.165: CN11.128 81.22,125.66 81.14,125.58 81.14,125.03 81.41,124.77 81.41,124.55 81.24,124.38 80.92,124.38 80.83,124.29 80.83,124.08 81.2,123.71 81.2,123.36 80.93,123.1 80.26,123.1 80.18,123.17 v3(80.18,123.22)
  L4_IN2 w0.216: v3(80.18,123.22) 80.41,123.22 81.06,122.57 81.06,118.44 80.94,118.32 80.94,118.02 81.06,117.9 81.06,117.35 70.94,107.23 70.94,94.64 72.35,93.23 72.66,93.23 v3(72.87,93.43)
M_B_A5: length 51.1
  TOP w0.076: U11.AY48 74.1,86.8 74.1,86.97 74.17,87.15 74.17,87.36 74.13,87.45 74.13,87.71 74.17,87.8 74.17,88.06 74.05,88.18 74.05,90.45 73.26,91.24 73.26,91.74 v3(72.87,92.13)
  TOP w0.165: CN11.126 80.72,124.78 80.41,124.46 80.41,124.06 79.74,123.4 79.74,122.9 v3(80.18,122.46)
  L4_IN2 w0.076: 72.13,92.79 72.79,92.13 v3(72.87,92.13)
  L4_IN2 w0.216: v3(80.18,122.46) 80.59,122.05 80.59,118.64 80.25,118.3 80.25,117.94 80.46,117.74 80.46,117.43 80,116.98 79.69,116.98 79.46,117.21 79.16,117.21 78.85,116.9 78.85,116.6 79.06,116.39 79.06,116.08 78.75,115.78 78.45,115.78 78.24,115.98 77.94,115.98 77.63,115.68 77.63,115.37 77.84,115.17 77.84,114.86 77.53,114.55 77.23,114.55 77.02,114.76 76.71,114.76 76.41,114.46 76.41,114.15 76.62,113.94 76.62,113.64 76.31,113.33 76.01,113.33 75.8,113.54 75.49,113.54 75.19,113.24 75.19,112.93 75.4,112.72 75.4,112.35 70.47,107.43 70.47,94.45 72.13,92.79
M_B_A6: length 49.7
  TOP w0.076: v3(72.87,90.83) 73.11,90.83 73.19,90.76 73.19,90.35 73.26,90.27 73.64,90.27 73.72,90.2 73.72,90.04 73.64,89.97 73.11,89.97 73.03,89.89 73.03,89.57 73.38,89.22 73.61,89.22 73.72,89.11 73.72,88.22 73.55,88.06 73.55,87.1 73.63,87.02 73.81,87.02 73.9,87.12 U11.BA48
  TOP w0.165: v3(80.12,121) 80.12,121.07 80.49,121.44 80.8,121.44 80.91,121.33 80.91,120.94 80.67,120.7 80.67,120.49 81.11,120.05 81.11,119.8 80.97,119.67 CN11.127
  L4_IN2 w0.076: 70.6,92.66 70.44,92.51 70.44,91.43 72.24,89.64 72.4,89.64 72.58,89.82 72.58,89.93 72.09,90.41 72.09,90.54 72.39,90.83 v3(72.87,90.83)
  L4_IN2 w0.216: 70.6,92.66 70.6,93.18 69.53,94.24 69.53,108.91 79.61,118.99 79.61,121.1 79.71,121.21 79.91,121.21 v3(80.12,121)
M_B_A7: length 53.5
  TOP w0.076: U11.AP48 73.6,82.84 73.2,83.17 v3(73.2,83.21)
  TOP w0.165: CN11.122 79.72,123.98 79.1,123.35 v3(78.67,123.35)
  L4_IN2 w0.076: 69.88,92.74 69.88,91.46 73.7,87.64 73.7,85.45 73.57,85.31 73.57,83.51 73.27,83.21 v3(73.2,83.21)
  L4_IN2 w0.216: 69.88,92.74 69.88,92.94 68.59,94.23 68.59,109.3 78.67,119.38 78.67,121.49 78.96,121.78 78.96,122.03 78.83,122.16 78.44,122.16 78.25,122.36 78.25,122.66 78.38,122.79 79.1,122.79 79.18,122.87 79.18,123.2 79.03,123.35 v3(78.67,123.35)
M_B_A8: length 48.1
  TOP w0.076: U11.BB48 73.9,88.09 73.88,88.11 73.88,89.35 73.8,89.42 73.44,89.42 73.36,89.5 73.36,89.65 73.44,89.73 73.8,89.73 73.88,89.8 73.88,90.34 73.75,90.47 73.43,90.47 73.36,90.54 73.36,90.86 73.1,91.12 73.1,91.41 73.02,91.48 v3(72.87,91.48)
  TOP w0.165: v3(80.12,120.22) 80.34,120.22 80.54,120.02 80.54,119.88 80.47,119.81 CN11.125
  L4_IN2 w0.076: 71.08,92.84 71.15,92.76 71.57,92.76 71.65,92.68 71.65,92.43 71.57,92.36 71.09,92.36 71.01,92.28 71.01,92.07 71.09,92 71.65,92 71.78,91.87 71.78,91.31 71.85,91.24 72.09,91.24 72.16,91.3 72.16,91.68 72.22,91.74 72.61,91.74 v3(72.87,91.48)
  L4_IN2 w0.216: 71.08,92.84 71.08,93.27 70,94.34 70,108.13 70.28,108.41 70.79,108.41 70.99,108.61 70.99,108.91 70.72,109.18 70.72,109.44 71.01,109.72 71.31,109.72 71.56,109.48 71.86,109.48 72.17,109.79 72.17,110.09 71.93,110.33 71.93,110.64 72.23,110.94 72.54,110.94 72.78,110.7 73.08,110.7 73.39,111.01 73.39,111.31 73.15,111.56 73.15,111.86 73.45,112.17 73.76,112.17 74,111.92 74.31,111.92 74.61,112.23 74.61,112.54 74.37,112.78 74.37,113.08 75.3,114.01 75.73,114.01 75.94,114.22 75.94,114.65 76.52,115.23 76.88,115.23 77.16,115.51 77.16,115.87 77.74,116.45 78.14,116.45 78.38,116.69 78.38,117.1 80.08,118.79 80.08,120.18 v3(80.12,120.22)
M_B_A9: length 49.5
  TOP w0.076: v3(72.28,83.21) U11.AP50
  TOP w0.165: v3(77.77,121.42) 79.06,121.42 79.68,120.8 79.68,120.07 79.47,119.87 CN11.121
  L4_IN2 w0.076: v3(72.28,83.21) 72.67,83.6 72.67,88.42 71.22,89.87 71.14,89.87 69.06,91.96 69.06,92.74
  L4_IN2 w0.216: v3(77.77,121.42) 78.2,120.99 78.2,119.57 68.12,109.5 68.12,94.11 69.06,93.18 69.06,92.74
M_B_A10_AP: length 50.5
  TOP w0.076: 75.33,91.7 75.56,91.47 75.56,89.6 75.56,89.11 75.66,89.01 75.66,87.26 75.42,87.02 75.42,86.53 75.32,86.33 75.13,86.14 U11.AW46
  TOP w0.102: v3(75.53,95.38) 75.13,94.98 75.13,91.9 75.33,91.7
  TOP w0.165: v3(86.91,122.58) 86.75,122.42 86.05,122.42 85.94,122.54 85.94,122.99 86.06,123.11 86.45,123.11 86.6,123.27 86.6,123.7 86.44,123.86 86.04,123.86 85.87,124.03 85.87,124.36 86.04,124.52 86.44,124.52 86.6,124.69 86.6,125.13 87.72,126.25 CN11.146
  L4_IN2 w0.076: v3(75.53,95.38) 75.55,95.4 75.55,97.11
  L4_IN2 w0.216: 75.55,97.11 75.55,104.66 81.95,111.05 82.42,111.05 82.66,111.29 82.66,111.77 83.17,112.28 83.48,112.59 83.98,112.59 84.19,112.79 84.19,113.29 84.54,113.64 86.11,115.22 86.11,119.03 86.2,119.12 86.2,122.49 86.3,122.58 v3(86.91,122.58)
M_B_A11: length 53.3
  TOP w0.076: v3(73.2,82.58) U11.AN48
  TOP w0.165: CN11.120 79.22,126.02 79.29,125.95 79.29,124.15 79.07,123.93 v3(78.63,123.93)
  L4_IN2 w0.076: v3(73.2,82.58) 73.53,82.58 73.72,82.77 73.72,85.25 73.86,85.39 73.86,87.71 70.24,91.33 70.24,92.74
  L4_IN2 w0.216: 70.24,92.74 70.24,93.03 69.06,94.2 69.06,109.11 79.14,119.18 79.14,121.3 79.65,121.81 79.65,123.69 79.4,123.93 v3(78.63,123.93)
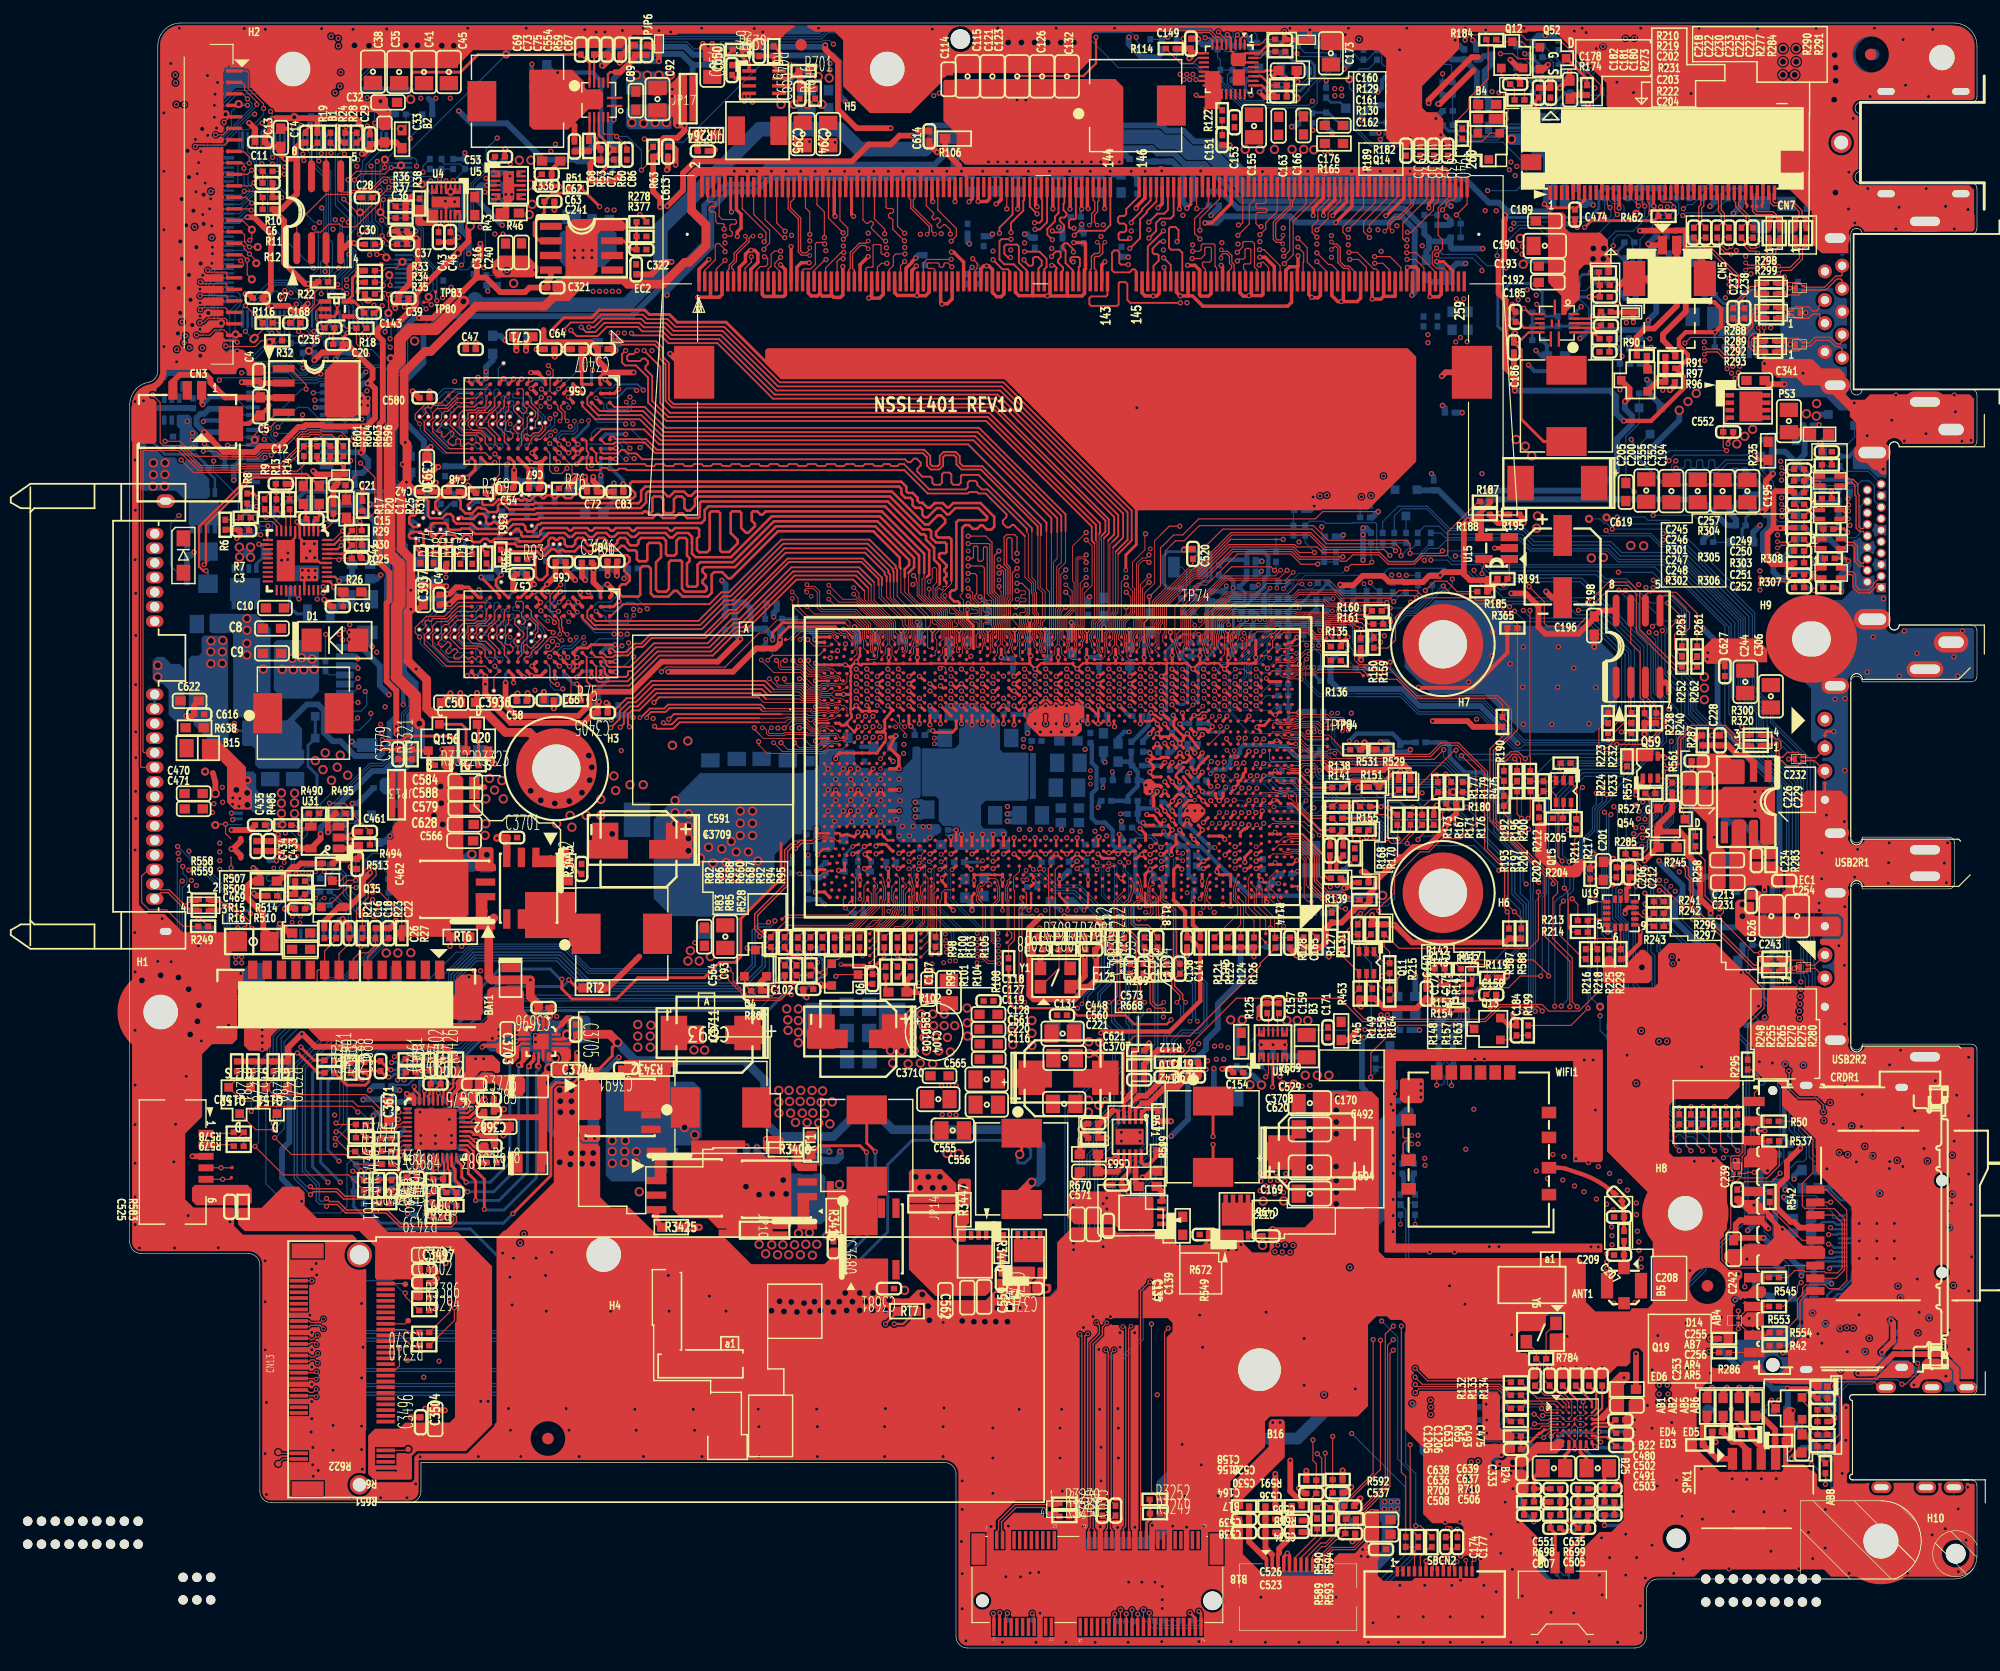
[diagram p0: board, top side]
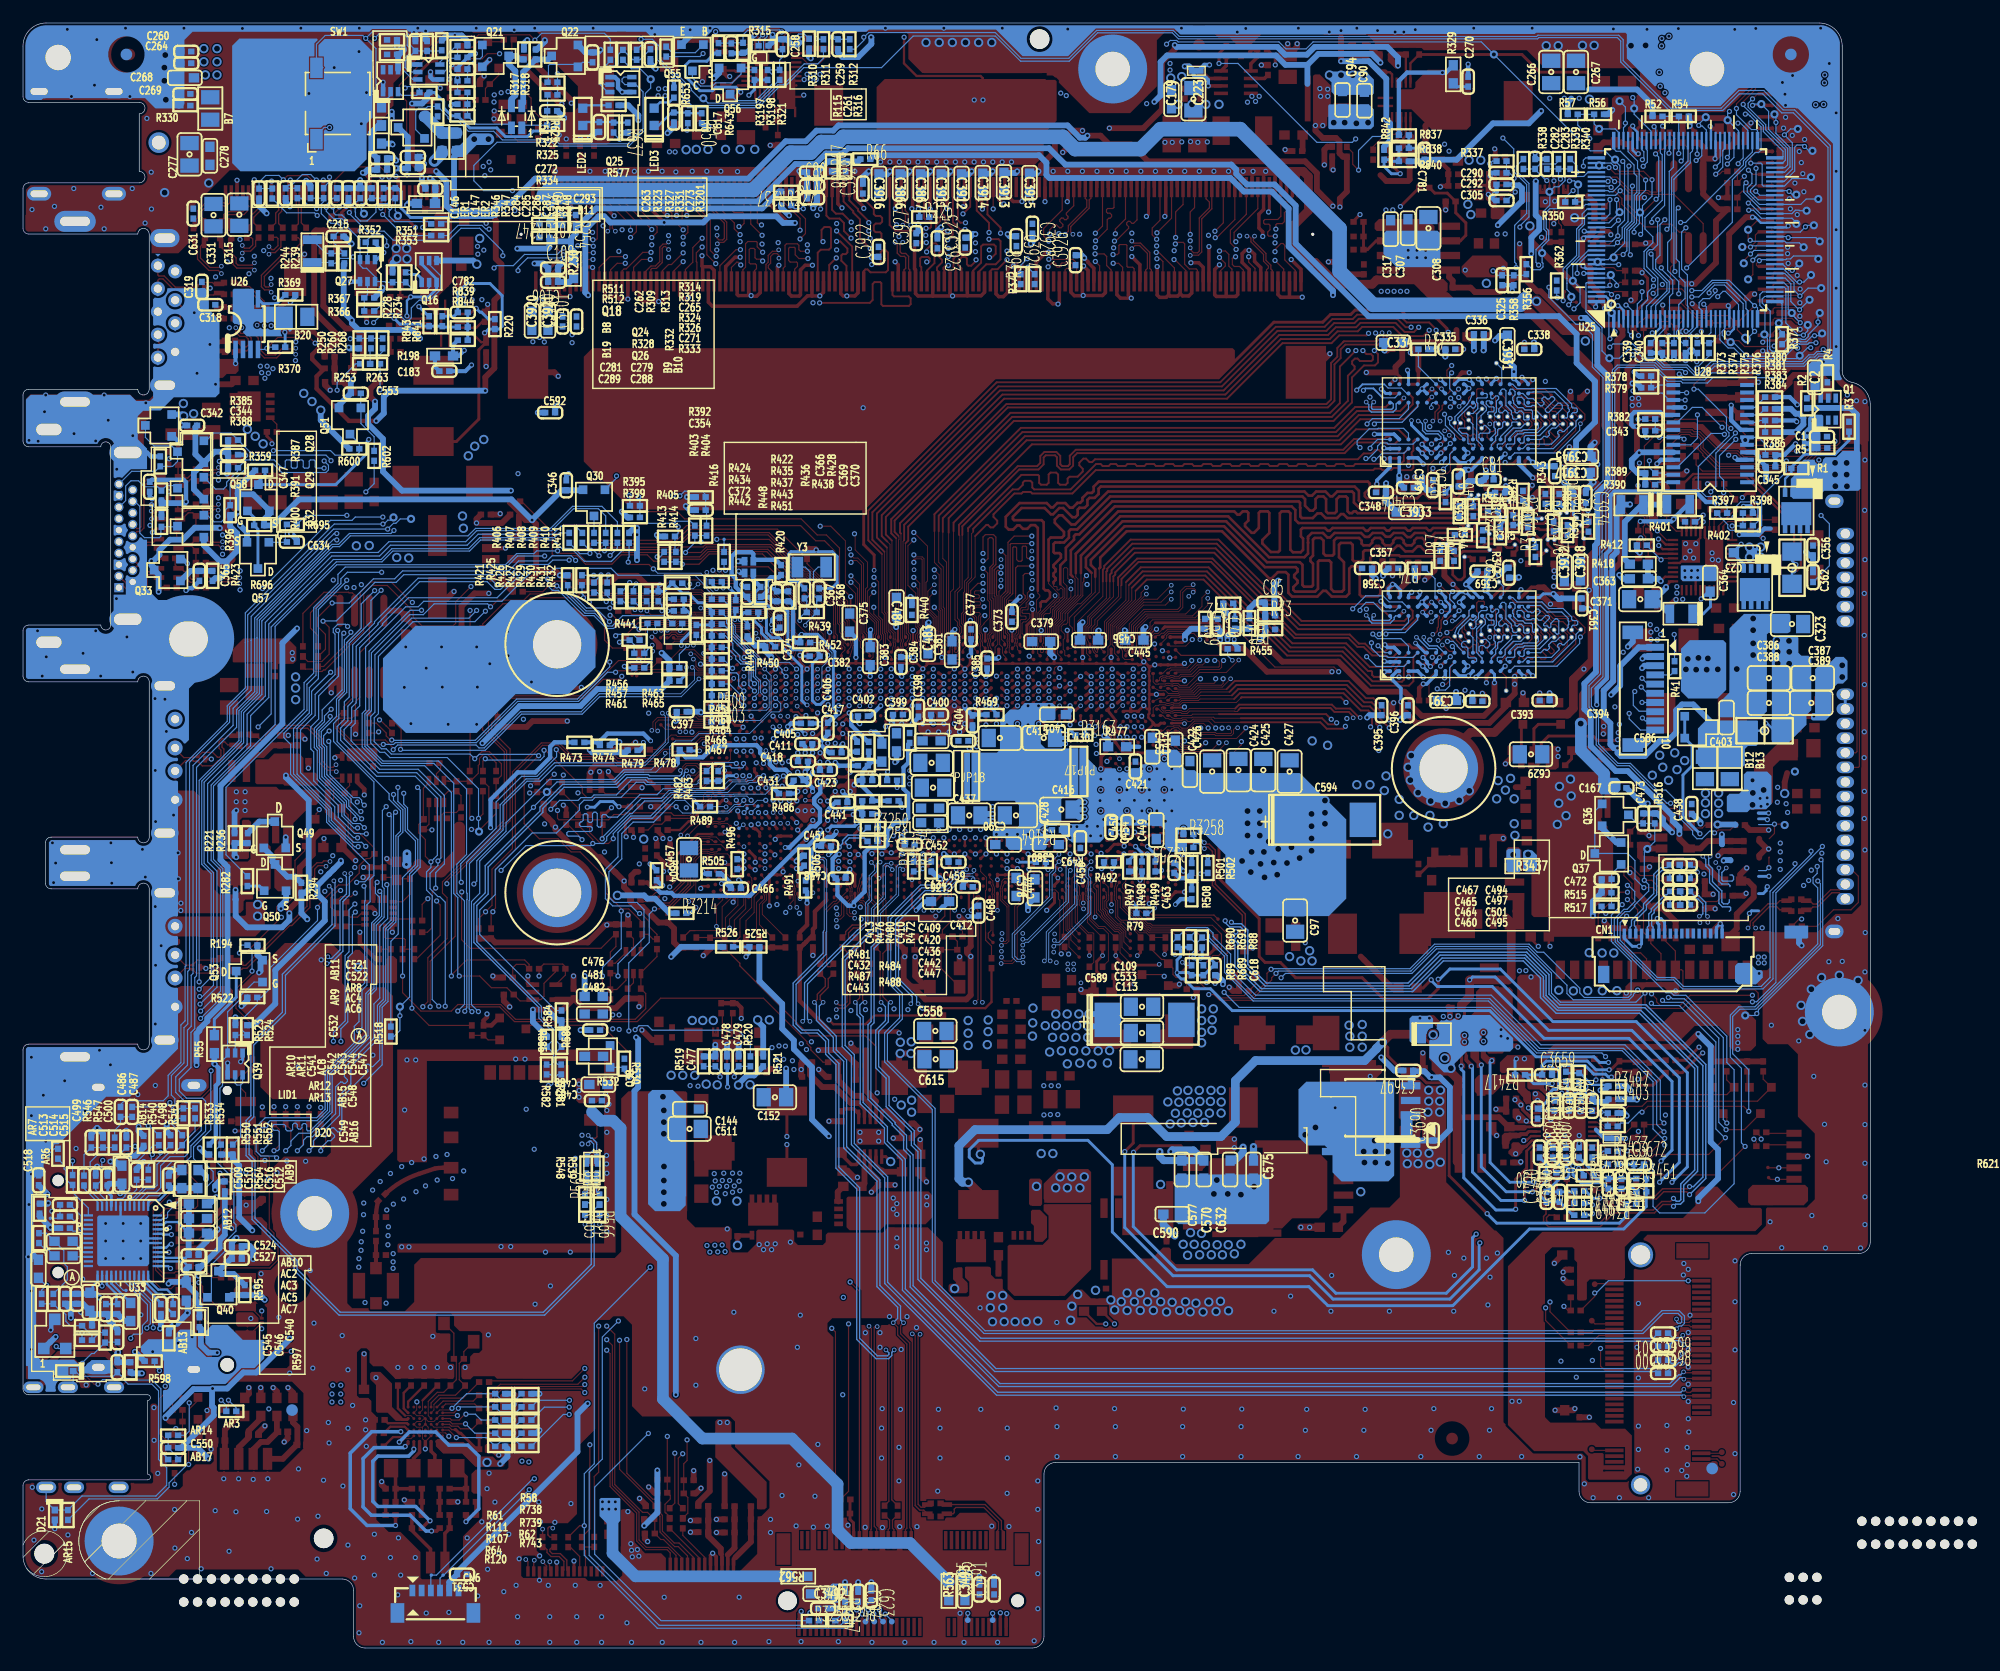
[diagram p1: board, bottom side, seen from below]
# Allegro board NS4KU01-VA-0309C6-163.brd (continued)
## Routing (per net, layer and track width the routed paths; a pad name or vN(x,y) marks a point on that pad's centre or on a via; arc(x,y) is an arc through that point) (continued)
M_B_A12: length 52.5
  TOP w0.076: v3(72.28,82.58) U11.AN50
  TOP w0.165: CN11.119 78.97,119.96 79.26,120.25 79.26,120.62 78.93,120.95 78.63,120.95 78.51,120.83 78.51,120.32 78.38,120.19 78.14,120.19 77.71,120.62 v3(77.71,120.71)
  L4_IN2 w0.076: 67.65,92.74 67.65,92.32 69.03,90.94 69.14,90.94 69.36,91.16 69.47,91.16 69.58,91.05 69.58,90.95 69.35,90.72 69.35,90.62 69.46,90.51 69.57,90.51 69.79,90.73 69.9,90.73 70.01,90.62 70.01,90.52 69.79,90.29 69.79,90.19 69.89,90.08 70,90.08 70.22,90.3 70.33,90.3 70.44,90.19 70.44,90.08 70.22,89.86 70.22,89.75 70.33,89.65 70.43,89.65 70.66,89.87 70.76,89.87 70.87,89.76 70.87,89.65 70.65,89.43 70.65,89.32 71.92,88.06 71.92,82.95 v3(72.28,82.58)
  L4_IN2 w0.216: v3(77.71,120.71) 77.49,120.49 77.49,120.25 77.73,120.02 77.73,119.77 67.65,109.69 67.65,92.74
M_B_A13: length 47.5
  TOP w0.076: U11.BA43 77.15,87.16 77.15,87.4 77.16,87.43 77.2,87.52 77.2,87.63 77.15,87.77 77.15,88.02 77.15,88.03 77.15,88.15 77.29,88.29 77.29,88.78 77.02,89.05 77.02,89.11 76.55,89.59 76.55,90.01 76.55,90.02 76.55,90.97 76.7,91.12 76.7,91.7
  TOP w0.102: 76.7,91.7 76.7,93.47 v3(77.11,93.88)
  TOP w0.165: v3(88.58,122.59) 89.2,123.22 89.2,123.92 89.58,124.3 90.47,124.3 90.72,124.56 CN11.158
  L4_IN2 w0.076: v3(77.11,93.88) 77.07,93.88 76.54,94.4 76.54,96.25 76.96,96.68 76.96,97.11
  L4_IN2 w0.216: 76.96,97.11 76.96,103.49 87.52,114.05 87.52,118.45 87.72,118.65 87.72,120.73 88.35,121.36 88.35,122.37 v3(88.58,122.59)
M_B_A14_MB_WE#: length 51.5
  TOP w0.076: 76.32,91.7 76.32,91.32 76.22,91.22 76.22,89.88 76.22,89.88 76.22,89.42 76.32,89.32 76.32,89.31 76.32,89.31 76.32,88.27 76.52,88.07 76.52,87.8 76.47,87.68 76.47,87.54 76.53,87.31 76.53,87.17 76.46,86.96 76.46,86.95 76.35,86.85 U11.AY44
  TOP w0.102: v3(77.11,95.18) 77.11,96.6 76.91,96.81 76.19,96.81 75.99,96.6 75.99,94.22 76.32,93.89 76.32,91.7
  TOP w0.165: CN11.151 88.97,120.18 89.42,120.63 89.42,121.09 89.31,121.2 89.04,121.2 88.89,121.35 88.89,121.69 89.52,122.31 v3(89.83,122.31)
  L4_IN2 w0.076: v3(77.11,95.18) 77.11,95.87 77.9,96.66 77.9,97.11
  L4_IN2 w0.216: v3(89.83,122.31) 89.62,122.31 89.29,121.98 89.29,120.97 88.66,120.34 88.66,118.26 88.46,118.06 88.46,117.39 88.91,116.95 88.91,116.74 88.46,116.3 88.46,116.1 88.95,115.61 88.95,115.26 88.59,114.89 88.59,114.7 88.95,114.34 88.95,114.15 80.41,105.61 80.41,105.26 80.22,105.06 79.86,105.06 77.9,103.1 77.9,97.11
M_B_A15_MB_CAS#: length 52.6
  TOP w0.076: 76.51,91.7 76.51,91.2 76.39,91.08 76.39,89.95 76.39,89.95 76.39,89.52 76.5,89.4 76.5,88.32 76.69,88.13 76.69,87.76 76.67,87.73 76.64,87.65 76.64,87.53 76.7,87.31 76.7,87.17 76.65,87.01 76.65,86.83 76.73,86.67 76.73,86.57 U11.AY43
  TOP w0.102: 76.51,91.7 76.51,93.96 76.21,94.26 76.21,96.42 76.35,96.55 76.54,96.55 76.68,96.42 76.68,94.73 76.88,94.53 v3(77.11,94.53)
  TOP w0.165: CN11.156 90.22,125.05 89.9,124.72 89.31,124.72 v3(88.56,123.98)
  L4_IN2 w0.076: 77.43,97.11 77.43,96.64 76.73,95.93 76.73,94.62 76.82,94.53 v3(77.11,94.53)
  L4_IN2 w0.216: 77.43,97.11 77.43,103.29 87.99,113.85 87.99,118.25 88.19,118.45 88.19,120.54 88.82,121.17 88.82,122.18 89.07,122.42 89.07,123.47 v3(88.56,123.98)
M_B_A16_MB_RAS#: length 51.2
  TOP w0.076: U11.AW44 76.35,86.11 76.19,86.28 76.08,86.49 76.06,86.56 76.06,87.02 75.82,87.26 75.82,89.08 75.73,89.18 75.73,89.67 75.73,89.67 75.73,91.88 75.56,92.04 v3(75.56,92.31)
  TOP w0.165: v3(86.91,121.69) 87.8,122.58 87.8,124.22 88.39,124.81 88.39,124.94 89.22,125.78 CN11.152
  L4_IN2 w0.076: v3(75.56,92.31) 75.56,91.71 75.71,91.55 76.14,91.55 76.31,91.72 76.31,96.63 76.49,96.82 76.49,97.11
  L4_IN2 w0.216: v3(86.91,121.69) 87.68,122.47 87.72,122.47 87.88,122.3 87.88,121.56 87.25,120.93 87.25,118.84 87.05,118.64 87.05,114.24 76.49,103.68 76.49,97.11
M_B_ACT#: length 51.7
  TOP w0.076: v3(70.45,82.58) U11.AN53
  TOP w0.165: v3(76.59,123.08) 76.59,123.92 77.65,124.99 77.65,125.84 77.72,125.91 CN11.114
  L4_IN2 w0.076: 66.24,92.74 66.24,92.53 69.03,89.75 69.03,87.99 69.94,87.09 69.94,83.08 70.43,82.58 v3(70.45,82.58)
  L4_IN2 w0.216: v3(76.59,123.08) 76.43,123.08 75.96,122.62 75.96,120.06 66.24,110.34 66.24,92.74
M_B_BA0: length 49.4
  TOP w0.076: U11.BB44 76.16,88 76.16,88.13 76.15,89.25 76.06,89.35 76.06,89.81 76.06,91.4 76.13,91.48 76.13,91.7
  TOP w0.102: 76.13,91.7 76.13,93.75 75.86,94.02 v3(75.53,94.02)
  TOP w0.165: CN11.150 88.72,125.87 87.97,125.11 87.97,124.99 87.04,124.06 v3(87.04,123.94)
  L4_IN2 w0.076: v3(75.53,94.02) 75.27,94.02 75.19,93.94 75.19,92.51 75.13,92.44 74.9,92.44 74.82,92.52 74.82,95.81 75.08,96.07 75.08,97.11
  L4_IN2 w0.216: 75.08,97.11 75.08,104.86 85.64,115.42 85.64,119.36 85.73,119.45 85.73,123.06 86.61,123.94 v3(87.04,123.94)
M_B_BA1: length 50.6
  TOP w0.076: 75.94,91.7 75.94,91.58 75.89,91.53 75.89,89.74 75.89,89.74 75.89,89.27 75.99,89.17 75.99,87.66 76.26,87.39 U11.BA44
  TOP w0.102: v3(75.56,93.45) 75.56,93.51 75.75,93.71 75.85,93.71 75.94,93.61 75.94,91.7
  TOP w0.165: v3(86.78,120.3) 86.13,120.3 86,120.42 86,121.4 85.87,121.53 85.56,121.53 85.37,121.34 85.37,119.81 85.56,119.62 86.89,119.62 87.14,119.88 87.33,119.88 87.47,119.73 CN11.145
  L4_IN2 w0.076: 76.02,97.11 76.02,96.69 75.77,96.43 75.77,96.32 76.13,95.96 76.13,95.84 75.9,95.62 75.9,95.36 76.14,95.13 76.14,94.96 75.89,94.71 75.89,94.55 76.14,94.3 76.14,94.14 75.88,93.88 75.88,93.73 76.16,93.46 76.16,93.02 76.09,92.96 75.94,92.96 75.78,93.12 75.78,93.33 75.65,93.45 v3(75.56,93.45)
  L4_IN2 w0.216: 76.02,97.11 76.02,104.47 76.18,104.62 76.77,104.62 76.92,104.77 76.92,105.36 77.09,105.53 77.67,105.53 77.84,105.7 77.84,106.08 77.98,106.22 78.37,106.22 78.55,106.4 78.55,106.99 79.02,107.46 79.6,107.46 80.07,107.93 80.07,108.52 80.55,108.99 81.13,108.99 81.6,109.46 81.6,110.04 82.07,110.52 82.66,110.52 83.13,110.99 83.13,111.57 83.6,112.04 84.18,112.04 84.66,112.51 84.66,113.1 85.13,113.57 85.71,113.57 86.18,114.04 86.18,114.63 86.58,115.03 86.58,118.84 86.78,119.04 v3(86.78,120.3)
M_B_BG0: length 51.9
  TOP w0.076: U11.AP52 71.75,82.84 v3(71.37,83.21)
  TOP w0.165: CN11.115 77.97,119.76 77.27,120.46 77.27,121.87 77.11,122.03 76.16,122.03 76.01,121.88 76.01,121.23 76.33,120.91 v3(76.55,120.91)
  L4_IN2 w0.076: 66.71,92.74 66.71,92.47 70.89,88.3 70.89,88.15 70.45,87.72 70.45,87.61 70.56,87.5 70.67,87.5 70.94,87.77 71.05,87.77 71.16,87.67 71.16,87.56 70.5,86.91 70.5,85.78 71,85.29 71,83.58 v3(71.37,83.21)
  L4_IN2 w0.216: 66.71,92.74 66.71,110.15 76.43,119.86 76.43,120.79 v3(76.55,120.91)
M_B_BG1: length 52.7
  TOP w0.076: U11.AN52 71.76,82.19 v3(71.37,82.58)
  TOP w0.165: CN11.113 77.47,119.67 76.83,120.32 76.01,120.32 75.59,120.74 75.59,122.33 75.76,122.51 76.58,122.51 v3(76.59,122.5)
  L4_IN2 w0.076: v3(71.37,82.58) 71.37,82.69 71.76,83.09 71.76,87.88 67.18,92.46 67.18,92.74
  L4_IN2 w0.216: v3(76.59,122.5) 77.02,122.06 77.02,119.73 67.18,109.89 67.18,92.74
M_B_DQ0: length 73.4
  TOP w0.076: v3(64.59,79.19) U11.AF65
  TOP w0.102: v3(51.66,123.38) 51.66,123.76 51.56,123.86 51.09,123.86 50.92,124.03 50.92,124.79 50.82,124.89 50.48,124.89 50.35,125.02 50.35,125.24 50.45,125.34 50.82,125.34 50.92,125.44 50.92,125.64 50.82,125.74 50.33,125.74 50.22,125.85 CN11.4
  L4_IN2 w0.076: v3(64.59,79.19) 64.07,78.67 61.83,78.67 58.03,74.87 54.71,74.87
  L4_IN2 w0.14: v3(51.66,123.38) 47.87,119.59 47.87,118.83 47.64,118.59 47.64,118.26 47.87,118.02 47.87,116.76 47.71,116.6 47.71,116.19 47.87,116.03 47.87,115.73 47.68,115.53 47.68,115.16 47.87,114.96 47.87,114.59 47.68,114.39 47.68,114.02 47.87,113.82 47.87,113.44 47.68,113.25 47.68,112.87 47.87,112.68 47.87,112.3 47.68,112.1 47.68,111.73 47.87,111.53 47.87,111.17 47.67,110.96 47.67,81.81 49.11,80.38 49.11,78.03 52.26,74.87 54.71,74.87
M_B_DQ1: length 71.6
  TOP w0.076: v3(65.23,79.19) U11.AF64
  TOP w0.102: CN11.7 50.97,119.9 v3(51.73,120.66)
  L4_IN2 w0.076: v3(65.23,79.19) 64.86,79.56 62.05,79.56 58.38,75.9 54.71,75.9
  L4_IN2 w0.14: v3(51.73,120.66) 49.88,118.8 49.88,118.61 50.28,118.2 50.28,117.99 50.1,117.81 49.89,117.81 49.35,118.35 49.12,118.35 48.94,118.17 48.94,116.93 49.08,116.79 49.44,116.79 49.57,116.65 49.57,116.37 49.44,116.23 49.08,116.23 48.94,116.09 48.94,115.81 49.08,115.67 49.44,115.67 49.57,115.53 49.57,115.25 49.44,115.11 49.08,115.11 48.94,114.97 48.94,114.7 49.08,114.56 49.44,114.56 49.57,114.42 49.57,114.14 49.44,114 49.08,114 48.94,113.86 48.94,113.58 49.08,113.44 49.44,113.44 49.57,113.3 49.57,113.02 49.44,112.88 49.08,112.88 48.94,112.74 48.94,112.46 49.08,112.32 49.44,112.32 49.57,112.18 49.57,111.9 49.44,111.76 49.14,111.76 48.99,111.61 48.99,111.36 49.14,111.2 49.44,111.2 49.57,111.06 49.57,107.81 48.7,106.93 48.7,82.24 50.13,80.81 50.13,78.45 52.69,75.9 54.71,75.9
M_B_DQ2: length 72.3
  TOP w0.076: v3(64.59,81.02) U11.AK65
  TOP w0.102: CN11.21 54.47,119.79 54.81,120.13 55.27,120.13 55.44,120.3 55.44,120.84 55.31,120.98 v3(55.16,120.98)
  L4_IN2 w0.076: 54.71,78.05 57.94,78.05 60.71,80.81 60.71,80.92 60.66,80.96 60.66,81.07 60.77,81.18 60.88,81.18 60.92,81.14 61.03,81.14 61.14,81.24 61.14,81.35 61.09,81.4 61.09,81.51 61.2,81.61 61.31,81.61 61.35,81.57 61.46,81.57 64.05,81.57 v3(64.59,81.02)
  L4_IN2 w0.14: 54.71,78.05 53.64,78.05 52.43,79.26 52.43,81.59 50.84,83.18 50.84,91.66 50.95,91.76 51.62,91.76 51.76,91.9 51.76,92.18 51.62,92.32 50.95,92.32 50.84,92.42 50.84,93.65 50.95,93.75 51.68,93.75 51.76,93.82 51.76,94.23 51.68,94.31 50.98,94.31 50.84,94.45 50.84,94.73 50.98,94.87 51.62,94.87 51.76,95.01 51.76,95.29 51.62,95.43 50.95,95.43 50.84,95.53 50.84,95.91 50.92,95.98 51.62,95.98 51.76,96.12 51.76,96.4 51.62,96.54 50.98,96.54 50.84,96.68 50.84,96.96 50.98,97.1 51.62,97.1 51.76,97.24 51.76,97.52 51.62,97.66 51.53,97.66 51.38,97.81 51.38,98.07 51.53,98.22 51.62,98.22 51.76,98.36 51.76,115.67 51.86,115.77 52.26,115.77 52.47,115.98 52.47,116.32 52.8,116.64 53.14,116.64 53.37,116.87 53.37,117.07 53.1,117.34 53.1,117.47 53.36,117.73 53.49,117.73 53.76,117.47 53.96,117.47 54.16,117.66 54.16,117.86 53.95,118.07 53.95,118.26 54.15,118.46 54.35,118.46 54.55,118.26 54.75,118.26 54.95,118.45 54.95,118.65 54.74,118.86 54.74,119.05 54.94,119.25 55.21,119.25 55.39,119.43 55.39,120.74 v3(55.16,120.98)
M_B_DQ3: length 73.6
  TOP w0.076: U11.AK64 65.17,80.32 v2(65.17,80.12)
  TOP w0.102: v3(55.14,122.28) 55.29,122.43 55.29,123.09 53.22,125.16 CN11.16
  L4_IN2 w0.076: 54.71,76.24 58.42,76.24 61.92,79.74 64.77,79.74 65.15,80.12 v2(65.17,80.12)
  L4_IN2 w0.14: 54.71,76.24 52.83,76.24 50.48,78.6 50.48,80.95 49.04,82.38 49.04,106.79 49.92,107.67 49.92,117.1 50.63,117.81 50.63,118.95 52.3,120.63 52.3,122.85 52.68,123.22 55.04,123.22 55.23,123.02 55.23,122.38 v3(55.14,122.28)
M_B_DQ4: length 72.9
  TOP w0.076: v3(63.96,79.19) U11.AF66
  TOP w0.102: v3(51.71,122.77) 52.27,122.77 52.37,122.87 52.37,123.12 52.17,123.32 52.17,123.71 52.27,123.81 52.62,123.81 52.72,123.91 52.72,124.11 52.62,124.21 51.5,124.21 51.22,124.49 CN11.8
  L4_IN2 w0.076: v3(63.96,79.19) 63.96,78.94 63.84,78.82 63.19,78.82 63.18,78.83 63.17,78.83 62.9,79.1 62.82,79.1 62.54,78.82 62.4,78.82 62.12,79.1 62.04,79.1 58.16,75.21 54.77,75.21 54.71,75.21
  L4_IN2 w0.14: v3(51.71,122.77) 51.53,122.77 51.26,122.5 51.26,122.16 50.76,121.66 50.56,121.66 49.82,120.92 49.82,120.42 49.68,120.28 49.19,120.28 48.22,119.31 48.22,110.76 48.03,110.57 48.03,110.16 48.19,109.99 48.19,109.73 48.03,109.56 48.03,109.19 48.22,109 48.22,108.6 48.04,108.43 48.04,108.03 48.22,107.86 48.22,107.58 48.01,107.37 48.01,81.96 49.45,80.52 49.45,78.17 52.41,75.21 54.71,75.21
M_B_DQ5: length 72.2
  TOP w0.076: v3(63.32,79.19) U11.AF67
  TOP w0.102: CN11.3 49.97,119.79 50.89,120.7 50.89,121.97 51.04,122.13 51.22,122.13 51.73,121.61 v3(51.73,121.42)
  L4_IN2 w0.076: 54.71,75.56 58.26,75.56 62.03,79.33 63.19,79.33 v3(63.32,79.19)
  L4_IN2 w0.14: 54.71,75.56 52.55,75.56 49.79,78.31 49.79,80.66 48.36,82.1 48.36,107.08 48.56,107.28 48.56,107.68 48.71,107.83 49.07,107.83 49.22,107.98 49.22,108.24 49.07,108.39 48.71,108.39 48.56,108.54 48.56,108.9 48.7,109.04 49.08,109.04 49.22,109.18 49.22,109.46 49.08,109.6 48.7,109.6 48.56,109.74 48.56,110.02 48.7,110.16 49.08,110.16 49.22,110.3 49.22,110.58 49.08,110.72 48.7,110.72 48.56,110.86 48.56,118.85 48.67,118.97 48.9,118.97 49.05,118.82 49.26,118.82 49.44,119 49.44,119.22 49.19,119.47 49.19,119.69 49.37,119.87 49.58,119.87 49.78,119.67 50.08,119.67 50.95,120.53 50.95,120.7 50.69,120.95 50.69,121.13 50.91,121.35 51.02,121.35 51.35,121.02 51.46,121.02 51.73,121.3 v3(51.73,121.42)
M_B_DQ6: length 70.5
  TOP w0.076: v3(63.32,81.02) U11.AK67
  TOP w0.102: v3(54.02,120.98) 54.02,120.51 53.47,119.97 CN11.17
  L4_IN2 w0.076: v3(63.32,81.02) 61.9,81.02 61.41,80.53 61.41,80.14 61.3,80.03 61.19,80.03 61.02,80.21 60.91,80.21 60.8,80.1 60.8,79.99 60.98,79.82 60.98,79.71 60.87,79.6 60.76,79.6 60.51,79.86 60.4,79.86 60.29,79.75 60.29,79.64 60.54,79.39 60.54,79.28 59.73,78.46 58.91,78.46 57.81,77.36 54.71,77.36
  L4_IN2 w0.14: v3(54.02,120.98) 53.91,120.98 53.68,120.74 53.68,120.55 53.81,120.42 54.34,120.42 54.42,120.34 54.42,119.76 51.07,116.42 51.07,107.05 50.96,106.93 50.77,106.93 50.62,106.78 50.62,106.53 50.77,106.37 50.93,106.37 51.07,106.23 51.07,105.95 50.93,105.81 50.31,105.81 50.16,105.66 50.16,105.41 50.31,105.26 50.93,105.26 51.07,105.12 51.07,104.84 50.93,104.7 50.3,104.7 50.16,104.56 50.16,104.28 50.3,104.14 50.93,104.14 51.07,104 51.07,103.72 50.93,103.58 50.3,103.58 50.16,103.44 50.16,103.16 50.3,103.02 50.93,103.02 51.07,102.88 51.07,102.6 50.93,102.46 50.3,102.46 50.16,102.32 50.16,102.04 50.3,101.9 50.93,101.9 51.07,101.76 51.07,101.51 50.92,101.35 50.38,101.35 50.16,101.14 50.16,82.9 51.75,81.31 51.75,78.97 53.36,77.36 54.71,77.36
M_B_DQ7: length 71.8
  TOP w0.076: v3(63.96,81.02) U11.AK66
  TOP w0.102: CN11.20 54.22,124.66 55.61,123.28 55.61,122.17 55.11,121.67 v3(55.11,121.61)
  L4_IN2 w0.076: 54.71,77.71 57.82,77.71 60.96,80.85 61.14,80.85 61.29,81 61.29,81.18 61.53,81.41 62,81.41 62.16,81.25 62.35,81.25 62.51,81.41 63.77,81.41 63.96,81.23 v3(63.96,81.02)
  L4_IN2 w0.14: v3(55.11,121.61) 54.73,121.99 54.55,121.99 54.44,121.89 54.44,121.14 54.76,120.83 54.76,119.62 52.55,117.41 52.55,117.21 52.61,117.14 52.61,116.94 52.32,116.65 52.12,116.65 52.05,116.71 51.85,116.71 51.42,116.28 51.42,100.85 51.28,100.71 50.63,100.71 50.5,100.58 50.5,100.28 50.63,100.15 51.31,100.15 51.42,100.04 51.42,99.69 51.31,99.59 50.6,99.59 50.5,99.49 50.5,99.18 50.65,99.03 51.29,99.03 51.42,98.91 51.42,98.63 51.22,98.44 50.64,98.44 50.5,98.3 50.5,98.05 50.86,97.7 50.86,97.5 50.5,97.14 50.5,92.27 50.67,92.1 50.67,91.99 50.5,91.82 50.5,83.04 52.09,81.45 52.09,79.11 53.5,77.71 54.71,77.71
M_B_DQ8: length 60
  TOP w0.076: U11.AF70 60.81,78.43 60.34,77.96 56.71,77.96 v2(55.95,78.72)
  TOP w0.102: CN11.25 55.47,119.89 55.75,120.16 55.75,121.18 56.04,121.47 v3(56.56,121.47)
  L4_IN2 w0.076: 54.71,79.24 55.43,79.24 v2(55.95,78.72)
  L4_IN2 w0.14: 54.71,79.24 53.9,79.24 53.46,79.68 53.46,82.02 51.87,83.61 51.87,90.35 52.92,91.39 52.92,98.2 53.41,98.69 53.41,98.99 52.92,99.48 52.92,99.76 53.06,99.9 53.67,99.9 53.81,100.04 53.81,100.32 53.67,100.46 53.06,100.46 52.92,100.6 52.92,100.89 53.11,101.08 53.68,101.08 53.91,101.31 53.91,105.36 52.79,106.48 52.79,114.84 57.11,119.16 57.11,119.43 56.92,119.62 56.92,120 57.11,120.19 57.11,120.97 56.6,121.47 v3(56.56,121.47)
M_B_DQ9: length 62.1
  TOP w0.076: 54.71,78.49 55.4,77.79 60.41,77.79 60.73,78.11 61.37,78.11 61.43,78.18 61.97,78.18 U11.AF68
  TOP w0.102: v3(54.65,78.82) 54.65,78.54 54.71,78.49 ; CN11.29 56.47,119.75 56.05,120.17 56.05,120.4 v3(56.56,120.91)
  L4_IN2 w0.14: v3(54.65,78.82) 53.84,78.82 53.12,79.54 53.12,81.88 51.53,83.47 51.53,90.49 52.48,91.44 52.48,101.88 52.64,102.03 53.17,102.03 53.31,102.17 53.31,102.45 53.17,102.59 52.58,102.59 52.45,102.73 52.45,103.01 52.58,103.15 53.36,103.15 53.5,103.29 53.5,103.57 53.36,103.71 52.58,103.71 52.45,103.85 52.45,104.13 52.58,104.27 53.42,104.27 53.56,104.4 53.56,104.68 53.42,104.82 52.58,104.82 52.45,104.96 52.45,114.98 56.13,118.67 56.13,120.55 56.49,120.91 v3(56.56,120.91)
M_B_DQ10: length 58.8
  TOP w0.076: v3(58.19,80) 58.21,80.02 58.85,80.02 59.21,79.65 59.88,79.65 60.02,79.65 60.12,79.75 U11.AH71
  TOP w0.102: v3(60.51,120.73) 60.44,120.73 59.47,119.77 CN11.41
  L4_IN2 w0.076: 54.93,84.07 58.19,80.81 v3(58.19,80)
  L4_IN2 w0.14: v3(60.51,120.73) 60.29,120.51 60.29,120.18 60.44,120.03 60.57,120.03 60.66,119.94 60.66,119.54 60.54,119.43 60.41,119.43 60.29,119.3 60.29,118.77 57.13,115.6 57.13,115.11 56.99,114.97 56.56,114.97 56.41,114.82 56.41,114.56 56.56,114.41 56.99,114.41 57.13,114.27 57.13,113.99 56.99,113.85 55.57,113.85 55.42,113.7 55.42,113.45 55.57,113.29 56.99,113.29 57.13,113.15 57.13,112.87 56.99,112.73 55.59,112.73 55.44,112.58 55.44,112.33 55.59,112.18 56.99,112.18 57.13,112.04 57.13,111.76 56.99,111.62 56.56,111.62 56.41,111.46 56.41,111.21 56.56,111.06 56.99,111.06 57.13,110.92 57.13,110.64 56.99,110.5 56.56,110.5 56.39,110.33 56.39,109.99 56.68,109.7 56.68,109.29 56.39,109 56.39,92.84 56.12,92.57 56.12,91 54.91,89.79 54.91,86.56 54.36,86.02 54.36,84.64 54.93,84.07
M_B_DQ11: length 62.1
  TOP w0.076: 54.71,79.46 55.08,79.09 58.55,79.09 59.18,78.46 59.75,78.46 60.15,78.86 60.51,78.86 60.51,78.86 60.6,78.83 60.8,78.83 60.89,78.86 60.89,78.86 60.89,78.86 60.9,78.87 61.13,78.87 61.25,78.83 61.57,78.83 61.67,78.9 62.12,78.9 62.33,79.1 U11.AH68
  TOP w0.102: 54.71,79.46 54.27,79.89 v3(54.27,80.02) ; CN11.38 58.72,125.24 59.1,124.87 v3(59.1,122.92)
  L4_IN2 w0.14: v3(59.1,122.92) 58.18,122.92 57.96,122.69 57.96,121.61 57.79,121.45 57.79,118.87 53.47,114.56 53.47,106.76 54.59,105.65 54.59,93.6 53.83,92.84 53.83,92.45 54.27,92.01 54.27,91.78 52.56,90.07 52.56,83.89 54.27,82.18 v3(54.27,80.02)
M_B_DQ12: length 59.4
  TOP w0.076: v3(56.6,78.72) 57.2,78.12 60.07,78.12 U11.AF71
  TOP w0.102: v3(56.93,122.63) 56.8,122.63 55.22,124.21 CN11.24
  L4_IN2 w0.076: v3(56.6,78.72) 55.74,79.59 54.71,79.59
  L4_IN2 w0.14: 54.71,79.59 54.05,79.59 53.81,79.83 53.81,82.16 52.22,83.75 52.22,90.21 53.29,91.28 53.29,93.01 54.25,93.97 54.25,105.5 53.13,106.62 53.13,114.7 57.45,119.02 57.45,121.28 56.85,121.88 56.85,122.56 v3(56.93,122.63)
M_B_DQ13: length 61
  TOP w0.076: v3(57.76,78.72) 58.19,78.29 59.81,78.29 60.22,78.7 60.48,78.7 60.57,78.66 60.58,78.66 60.83,78.66 60.92,78.7 61.13,78.7 61.21,78.67 61.31,78.63 61.57,78.63 U11.AF69
  TOP w0.102: CN11.28 56.22,123.93 v3(56.96,123.19)
  L4_IN2 w0.076: 54.71,78.39 55.61,78.39 55.65,78.35 57.39,78.35 v3(57.76,78.72)
  L4_IN2 w0.14: 54.71,78.39 53.78,78.39 52.78,79.4 52.78,81.73 51.19,83.32 51.19,90.63 52.1,91.55 52.1,115.12 55.79,118.81 55.79,122.25 56.73,123.19 v3(56.96,123.19)
M_B_DQ14: length 60
  TOP w0.076: v3(57.54,80) 57.94,80.4 58.7,80.4 59.28,79.82 59.81,79.82 59.95,79.82 60.15,80.02 60.48,80.02 60.73,79.9 60.73,79.9 60.74,79.9 60.88,79.75 U11.AH70
  TOP w0.102: CN11.37 58.47,119.8 58.59,119.92 59.18,119.92 59.58,120.33 59.58,122.1 59.71,122.22 60.26,122.22 v3(60.39,122.09)
  L4_IN2 w0.076: v3(57.54,80) 57.54,80.98 54.71,83.81
  L4_IN2 w0.14: 54.71,83.81 54.02,84.5 54.02,86.16 54.57,86.7 54.57,89.93 55.78,91.14 55.78,92.71 56.05,92.98 56.05,109.42 55.91,109.56 55.32,109.56 55.16,109.71 55.16,109.96 55.32,110.12 55.91,110.12 56.05,110.26 56.05,110.54 55.91,110.68 55.15,110.68 55.01,110.82 55.01,111.09 55.15,111.23 55.91,111.23 56.05,111.37 56.05,111.62 55.9,111.77 55.15,111.77 55.01,111.91 55.01,113.97 59.95,118.91 59.95,122.01 60.1,122.16 60.32,122.16 v3(60.39,122.09)
M_B_DQ15: length 61.1
  TOP w0.076: U11.AH69 61.47,79.75 61.08,80.15 60.59,80.15 60.52,80.19 60.05,80.19 59.84,79.98 59.75,79.98 59.35,79.98 58.73,80.6 57.49,80.6 v3(56.89,80)
  TOP w0.102: CN11.42 59.72,125.51 60.37,124.87 v3(60.37,122.65)
  L4_IN2 w0.076: v3(56.89,80) 56.89,81.14 54.71,83.33
  L4_IN2 w0.14: v3(60.37,122.65) 60.09,122.92 59.83,122.92 59.61,122.7 59.61,119.05 54.63,114.08 54.63,109.28 54.73,109.18 55.56,109.18 55.71,109.02 55.71,108.78 55.57,108.64 55.1,108.64 54.96,108.5 54.96,108.22 55.1,108.08 55.57,108.08 55.71,107.95 55.71,107.67 55.57,107.53 55.22,107.53 55.08,107.39 55.08,107.11 55.22,106.97 55.57,106.97 55.71,106.83 55.71,93.12 55.44,92.85 55.44,91.32 54.22,90.11 54.22,86.84 53.68,86.3 53.68,84.36 54.71,83.33
M_B_DQ16: length 48.8
  TOP w0.076: v3(63.14,84.48) 63.49,84.14 U11.AT66
  TOP w0.102: CN11.50 61.72,124.15 62.4,123.47 62.4,122.88 v3(62.02,122.5)
  L4_IN2 w0.076: v3(63.14,84.48) 63.14,84.48 62.67,84.48 61.55,85.6 61.55,86.03 60.98,86.6 60.98,87.33 57.19,91.12 57.19,91.8
  L4_IN2 w0.14: v3(62.02,122.5) 62.07,122.5 62.53,122.04 62.53,119.55 58.15,115.17 58.15,96.58 57.42,95.85 57.42,92.41 57.19,92.18 57.19,91.8
M_B_DQ17: length 47.9
  TOP w0.076: v3(63.14,85.12) U11.AU66
  TOP w0.102: v3(62,123.06) 60.72,124.33 CN11.46
  L4_IN2 w0.076: 57.77,92.37 57.77,92.23 58.06,91.93 58.06,90.73 62.77,86.02 62.77,85.6 63.14,85.23 v3(63.14,85.12)
  L4_IN2 w0.14: 57.77,92.37 57.77,95.52 58.5,96.25 58.5,115.03 62.91,119.44 62.91,122.39 62.24,123.06 v3(62,123.06)
M_B_DQ18: length 51.3
  TOP w0.076: v3(64.05,83.21) 64.43,82.84 U11.AP65
  TOP w0.102: CN11.59 63.97,119.94 64.1,120.07 64.52,120.07 64.6,120.14 64.6,121.96 64.68,122.03 65.22,122.03 65.3,121.96 65.3,121.29 65.43,121.17 v3(65.81,121.17)
  L4_IN2 w0.076: v3(64.05,83.21) 64.37,83.21 64.45,83.29 64.45,84.7 64.66,84.91 64.66,86.59 63.49,87.77 63.49,88.18 63.29,88.38 62.88,88.38 62.56,88.7 62.56,88.8 60.69,90.67 60.54,90.67 60.03,91.18 60.03,92.74
  L4_IN2 w0.14: 60.03,92.74 60.03,92.89 60.3,93.16 60.3,114.28 64.12,118.1 64.41,118.1 64.73,117.78 65.22,117.78 65.37,117.93 65.37,118.23 65.23,118.37 65.03,118.37 64.89,118.51 64.89,118.79 65.03,118.93 65.23,118.93 65.37,119.07 65.37,121.09 65.51,121.23 65.75,121.23 v3(65.81,121.17)
M_B_DQ19: length 51.7
  TOP w0.076: U11.AN65 64.45,82.19 64.11,82.53 v3(64.11,82.53)
  TOP w0.102: CN11.63 64.97,120.06 65.32,120.4 v3(65.8,120.4)
  L4_IN2 w0.076: v3(64.11,82.53) 64.47,82.53 64.6,82.66 64.6,84.64 64.81,84.85 64.81,86.66 63.67,87.8 63.67,88.63 63.03,89.27 62.37,89.27 60.81,90.83 60.6,90.83 60.37,91.05 60.37,92.74
  L4_IN2 w0.14: v3(65.8,120.4) 65.8,117.87 64.42,116.5 64.24,116.5 63.72,117.02 63.52,117.02 63.32,116.82 63.32,116.62 63.84,116.1 63.84,115.91 63.63,115.71 63.45,115.71 62.93,116.23 62.73,116.23 62.53,116.03 62.53,115.83 63.05,115.31 63.05,115.12 62.84,114.92 62.66,114.92 62.14,115.43 61.94,115.43 61.74,115.24 61.74,115.04 62.26,114.52 62.26,114.33 61.98,114.06 61.8,114.06 61.44,114.42 61.24,114.42 60.64,113.82 60.64,93.02 60.37,92.74
M_B_DQ20: length 51
  TOP w0.076: U11.AN66 63.53,82.19 v3(63.14,82.58)
  TOP w0.102: v3(62.05,121.36) 61.83,121.36 60.47,120 CN11.45
  L4_IN2 w0.076: 56.61,91.22 60.34,87.49 60.34,85.45 63.14,82.66 v3(63.14,82.58)
  L4_IN2 w0.14: v3(62.05,121.36) 61.89,121.36 61.67,121.58 61.26,121.58 61.07,121.39 61.07,119.06 57.47,115.46 57.47,102.92 57.19,102.64 56.88,102.64 56.74,102.5 56.74,102.22 56.88,102.08 57.33,102.08 57.47,101.94 57.47,101.66 57.33,101.52 56.88,101.52 56.74,101.38 56.74,101.1 56.88,100.97 57.33,100.97 57.47,100.83 57.47,100.55 57.33,100.41 56.88,100.41 56.74,100.27 56.74,92.7 56.46,92.42 56.46,91.37 56.61,91.22
M_B_DQ21: length 50.1
  TOP w0.076: U11.AP66 63.6,82.85 63.15,83.21 v3(63.14,83.21)
  TOP w0.102: CN11.49 61.47,120.56 61.72,120.8 v3(62,120.8)
  L4_IN2 w0.076: v3(63.14,83.21) 62.84,83.21 60.5,85.56 60.5,87.6 56.92,91.18 56.92,91.49 56.9,91.51
  L4_IN2 w0.14: v3(62,120.8) 61.81,120.99 61.52,120.99 61.41,120.88 61.41,119.95 61.78,119.58 61.78,119.28 57.81,115.31 57.81,100.13 57.73,100.04 57.22,100.04 57.08,99.9 57.08,99.62 57.22,99.48 57.67,99.48 57.81,99.34 57.81,99.06 57.67,98.92 57.22,98.92 57.08,98.78 57.08,98.5 57.22,98.36 57.66,98.36 57.81,98.22 57.81,97.95 57.67,97.81 57.22,97.81 57.08,97.67 57.08,97.39 57.22,97.25 57.73,97.25 57.81,97.16 57.81,96.77 57.73,96.69 57.22,96.69 57.08,96.55 57.08,92.56 56.81,92.28 56.81,91.6 56.9,91.51
M_B_DQ22: length 49.8
  TOP w0.076: v3(64.05,84.48) 64.4,84.14 U11.AT65
  TOP w0.102: CN11.58 63.72,124.18 64.02,123.88 64.17,123.88 64.34,124.06 64.48,124.06 64.63,123.91 64.63,123.77 64.45,123.59 64.45,123.45 65.57,122.33 v3(65.68,122.33)
  L4_IN2 w0.076: v3(64.05,84.48) 64.05,84.52 64.51,84.98 64.51,86.53 62.41,88.63 62.41,88.74 60.63,90.52 60.47,90.52 59.87,91.12 59.87,92.15 59.68,92.34 59.68,92.74
  L4_IN2 w0.14: 59.68,92.74 59.68,93.03 59.9,93.25 59.9,93.4 59.7,93.59 59.7,93.76 59.96,94.02 59.96,114.42 65.03,119.5 65.03,122.08 65.28,122.33 v3(65.68,122.33)
M_B_DQ23: length 49.1
  TOP w0.076: U11.AU65 64.39,84.79 v3(64.05,85.12)
  TOP w0.102: v3(65.61,122.97) 65.61,123.38 64.72,124.26 CN11.62
  L4_IN2 w0.076: 59.34,92.74 59.34,92.05 59.65,91.74 59.65,91.05 61.27,89.42 61.27,89.32 61.09,89.14 61.09,89.03 61.2,88.92 61.31,88.92 61.59,89.2 61.7,89.2 61.81,89.1 61.81,88.99 61.47,88.65 61.47,88.54 61.89,88.12 62.63,88.12 64.05,86.7 v3(64.05,85.12)
  L4_IN2 w0.14: 59.34,92.74 59.34,93.89 59.61,94.16 59.61,114.57 64.62,119.57 64.62,122.18 65.41,122.97 v3(65.61,122.97)
M_B_DQ24: length 48.5
  TOP w0.076: v3(65.88,84.48) 66.23,84.14 U11.AT61
  TOP w0.102: v3(67.37,121.22) 66.58,121.22 66.36,121 66.36,120.21 65.97,119.82 CN11.67
  L4_IN2 w0.076: 61.67,92.74 61.67,91.61 62.09,91.19 62.09,91.08 62.06,91.06 62.06,90.95 62.17,90.84 62.28,90.84 62.3,90.87 62.41,90.87 62.52,90.76 62.52,90.65 62.49,90.63 62.49,90.52 62.6,90.41 62.71,90.41 62.73,90.44 62.84,90.44 62.95,90.33 62.95,90.22 62.92,90.2 62.92,90.09 63.03,89.98 63.14,89.98 63.17,90.01 63.27,90.01 63.38,89.9 63.38,89.79 63.34,89.75 63.34,89.65 63.46,89.54 63.56,89.54 63.6,89.58 63.7,89.58 63.82,89.46 63.82,89.36 63.77,89.32 63.77,89.23 63.9,89.1 63.99,89.1 64.03,89.14 64.14,89.14 64.26,89.02 64.26,88.18 64.62,87.82 65.38,87.82 65.45,87.75 65.45,87.7 65.45,87.7 65.45,85.03 65.88,84.6 v3(65.88,84.48)
  L4_IN2 w0.14: v3(67.37,121.22) 67.09,121.22 66.92,121.05 66.92,120.14 67.06,120 67.94,120 68.03,119.91 68.03,119.53 67.94,119.44 67.06,119.44 66.83,119.21 66.83,117.44 61.67,112.29 61.67,92.74
M_B_DQ25: length 47.9
  TOP w0.076: U11.AU61 66.22,84.79 v3(65.88,85.12)
  TOP w0.102: CN11.71 66.97,120.19 v3(67.35,120.57)
  L4_IN2 w0.076: 62.01,92.74 62.01,91.48 64.43,89.07 64.43,88.33 64.66,88.1 65.53,88.1 65.6,88.02 65.6,87.76 65.6,87.76 65.6,87.71 65.82,87.49 65.97,87.49 66.06,87.4 66.06,87.28 65.97,87.19 65.82,87.19 65.73,87.1 65.73,86.97 65.82,86.88 65.95,86.88 66.03,86.8 66.03,86.67 65.95,86.58 65.76,86.58 65.6,86.42 65.6,85.4 v3(65.88,85.12)
  L4_IN2 w0.14: v3(67.35,120.57) 67.67,120.57 67.88,120.77 67.88,121.69 68.03,121.84 68.89,121.84 69.05,121.69 69.05,119.98 67.26,118.19 67.26,117.39 62.01,112.15 62.01,92.74
M_B_DQ26: length 51.2
  TOP w0.076: U11.AP60 67.18,82.84 v3(66.8,83.21)
  TOP w0.102: v3(71.39,120.75) 71.38,120.74 69.28,120.74 68.97,120.44 CN11.79
  L4_IN2 w0.076: 63.82,92.74 63.82,92.6 64.01,92.41 64.01,91.7 64.23,91.48 64.23,91.37 64.05,91.19 64.06,91.06 64.14,90.98 64.27,90.98 64.46,91.17 64.59,91.17 64.68,91.08 64.68,90.95 64.35,90.62 64.35,90.4 67.16,87.59 67.16,87.35 67.24,87.27 67.33,87.27 67.41,87.19 67.41,87.04 67.33,86.97 67.24,86.97 67.16,86.89 67.16,86.77 67.27,86.67 67.77,86.67 67.86,86.58 67.86,86.45 67.77,86.36 67.27,86.36 67.18,86.26 67.18,86.13 67.27,86.04 67.78,86.04 67.86,85.96 67.86,85.84 67.78,85.76 67.27,85.76 67.16,85.66 67.16,85.57 67.28,85.45 67.61,85.45 67.66,85.4 67.66,85.19 67.17,84.69 67.17,83.51 66.87,83.21 v3(66.8,83.21)
  L4_IN2 w0.14: v3(71.39,120.75) 71.01,120.37 71.01,118.57 63.82,111.37 63.82,92.74
M_B_DQ27: length 51.7
  TOP w0.076: v3(66.8,82.58) 67.19,82.19 U11.AN60
  TOP w0.102: v3(71.45,120.1) 71.11,120.44 70.85,120.44 70.75,120.34 70.75,120.17 70.65,120.07 70.45,120.07 70.35,120.17 70.35,120.34 70.25,120.44 69.41,120.44 69.31,120.34 69.31,120.05 69.41,119.96 69.85,119.96 69.97,119.84 CN11.83
  L4_IN2 w0.076: v3(66.8,82.58) 67.33,83.11 67.33,84.64 68.07,85.38 68.07,86.9 65.05,89.92 65.05,90.06 65.72,90.74 65.72,90.85 65.62,90.96 65.51,90.96 64.9,90.35 64.79,90.35 64.68,90.46 64.68,90.56 65.29,91.17 65.29,91.28 65.19,91.39 65.08,91.39 64.93,91.24 64.82,91.24 64.71,91.35 64.71,91.45 64.86,91.6 64.86,91.71 64.75,91.82 64.65,91.82 64.5,91.67 64.39,91.67 64.28,91.78 64.28,91.89 64.43,92.04 64.43,92.14 64.16,92.41 64.16,92.74
  L4_IN2 w0.14: v3(71.45,120.1) 71.45,118.52 64.16,111.23 64.16,92.74
M_B_DQ28: length 50.7
  TOP w0.076: U11.AN61 66.28,82.19 v3(65.88,82.58)
  TOP w0.102: CN11.70 66.72,123.64 v3(67.34,123.02)
  L4_IN2 w0.076: v3(65.88,82.58) 65.88,82.39 65.78,82.29 65.51,82.29 65.36,82.43 65.36,84.69 65.15,84.9 65.15,86.77 64.97,86.95 64.97,86.96 63.82,88.11 63.82,88.7 61.12,91.41 61.12,92.53 60.99,92.66 60.99,92.74
  L4_IN2 w0.14: 60.99,92.74 60.99,112.57 66.14,117.73 66.14,119.97 66.24,120.07 66.24,121.91 v3(67.34,123.02)
M_B_DQ29: length 50.4
  TOP w0.076: U11.AP61 66.26,82.84 v3(65.88,83.21)
  TOP w0.102: v3(67.33,122.36) 66.32,123.37 66.32,124.19 66.19,124.32 66.07,124.32 65.93,124.46 65.93,124.62 66.07,124.76 66.28,124.76 66.38,124.87 66.38,125.07 66.28,125.17 65.83,125.17 65.72,125.27 CN11.66
  L4_IN2 w0.076: v3(65.88,83.21) 65.51,83.58 65.51,84.75 65.3,84.97 65.3,86.93 63.98,88.25 63.98,88.81 61.33,91.45 61.33,92.74
  L4_IN2 w0.14: v3(67.33,122.36) 67.21,122.36 66.58,121.73 66.58,119.92 66.48,119.83 66.48,117.59 61.33,112.43 61.33,92.74
M_B_DQ30: length 50.5
  TOP w0.076: v3(66.8,84.48) 67.15,84.14 U11.AT60
  TOP w0.102: CN11.84 70.22,125.05 71.84,123.43 71.84,122.78 v3(71.39,122.33)
  L4_IN2 w0.076: v3(66.8,84.48) 66.8,84.54 67.17,84.91 67.17,85.27 66.97,85.46 66.97,87.56 63.86,90.68 63.86,92.35 63.48,92.73 63.48,92.74
  L4_IN2 w0.14: v3(71.39,122.33) 71.47,122.41 71.96,122.41 72.09,122.27 72.09,121.98 71.92,121.8 70.97,121.8 70.63,121.46 70.63,118.68 63.48,111.52 63.48,92.74
M_B_DQ31: length 49.8
  TOP w0.076: U11.AU60 67.13,84.79 v3(66.8,85.12)
  TOP w0.102: CN11.80 69.22,125.41 69.87,124.77 69.87,124.63 69.73,124.49 69.73,124.34 69.87,124.2 70.01,124.2 70.15,124.34 70.3,124.34 70.44,124.2 70.44,124.05 70.17,123.78 70.17,123.64 70.31,123.5 70.46,123.5 70.73,123.77 70.87,123.77 71.32,123.31 v3(71.32,122.94)
  L4_IN2 w0.076: v3(66.8,85.12) 66.8,87.52 63.7,90.62 63.7,92.15 63.13,92.72 63.13,92.74
  L4_IN2 w0.14: 63.13,92.74 63.13,111.66 70.29,118.82 70.29,121.83 71.32,122.87 v3(71.32,122.94)
M_B_DQ32: length 49.4
  TOP w0.076: v3(77.77,85.12) U11.AU40
  TOP w0.102: CN11.174 94.72,126.03 93.01,124.31 v3(93.01,123.28)
  L4_IN2 w0.076: 82.14,97.11 82.14,96.54 82.06,96.31 81.14,95.13 80.6,94.45 80.49,94.2 80.49,90.01 79.17,88.7 77.92,86.3 v3(77.77,85.12)
  L4_IN2 w0.14: v3(93.01,123.28) 93.44,122.85 93.44,122.53 93.44,112.64 89.01,108.21 89.01,107.22 82.34,100.55 82.14,99.88 82.14,97.11
M_B_DQ33: length 50
  TOP w0.076: v3(77.77,84.48) U11.AT40
  TOP w0.102: v3(93.01,122.52) 92.54,122.99 92.54,124.28 93.72,125.46 CN11.170
  L4_IN2 w0.076: v3(77.77,84.48) 77.39,85 77.39,85.25 77.74,86.35 77.84,86.61 78.23,87.27 79,88.74 79.01,88.75 79.1,88.91 80.33,90.14 80.33,94.23 80.51,94.61 81.28,95.6 81.8,96.42 81.8,97.11
  L4_IN2 w0.14: 81.8,97.11 81.8,99.95 81.97,100.67 88.67,107.37 88.67,108.35 93.1,112.78 93.1,122.43 v3(93.01,122.52)
M_B_DQ34: length 50.8
  TOP w0.076: v3(79.6,84.48) U11.AT37
  TOP w0.102: CN11.186 97.72,125.91 97.29,125.48 97.29,123.82 v3(96.31,122.84)
  L4_IN2 w0.076: v3(79.6,84.48) 79.6,84.59 79.97,84.95 79.97,87.11 81.32,88.46 81.32,89.68 81.92,90.27 81.92,90.44 83.98,92.5 83.98,96.77 84.15,96.95 84.15,97.11
  L4_IN2 w0.14: 84.15,97.11 84.15,100.27 90.53,106.66 90.53,107.56 94.93,111.95 94.93,118.9 95.84,119.8 95.84,122.73 95.95,122.84 v3(96.31,122.84)
M_B_DQ35: length 50.2
  TOP w0.076: v3(79.6,85.13) U11.AU37
  TOP w0.102: v3(96.36,123.74) 96.53,123.74 96.72,123.93 CN11.182
  L4_IN2 w0.076: v3(79.6,85.13) 79.6,86.95 81.17,88.53 81.17,89.75 81.73,90.3 81.73,90.53 83.81,92.61 83.81,97.21
  L4_IN2 w0.14: v3(96.36,123.74) 95.52,123.74 95.42,123.64 95.42,119.87 94.58,119.04 94.58,112.09 90.19,107.7 90.19,106.8 83.81,100.42 83.81,97.48 83.81,97.21
M_B_DQ36: length 50.7
  TOP w0.076: v3(77.77,83.85) U11.AR40
  TOP w0.102: CN11.173 94.47,119.97 94.32,120.13 94.32,121.97 94.19,122.1 93.24,122.1 93.11,121.97 93.11,121.59 92.98,121.45 v3(92.37,121.45)
  L4_IN2 w0.076: 81.46,97.11 81.46,96.35 80.16,95.04 80.16,90.35 77.95,88.14 77.21,85.98 77.21,84.87 77.38,84.7 77.38,84.24 v3(77.77,83.85)
  L4_IN2 w0.14: 81.46,97.11 81.46,100.64 88.33,107.51 88.33,108.5 92.75,112.92 92.75,121.31 92.61,121.45 v3(92.37,121.45)
M_B_DQ37: length 51.4
  TOP w0.076: v3(77.77,83.21) U11.AP40
  TOP w0.102: CN11.169 93.47,119.9 93.23,120.14 93.23,120.44 93.31,120.51 93.87,120.51 94,120.65 94,121.71 93.92,121.79 93.51,121.79 93.43,121.72 93.43,121.15 93.1,120.82 v3(92.33,120.82)
  L4_IN2 w0.076: 81.12,97.11 81.12,96.38 80.75,96.02 80.43,96.02 80,95.59 80,90.51 77.06,87.56 77.06,84.8 77.22,84.64 77.22,83.32 77.33,83.21 v3(77.77,83.21)
  L4_IN2 w0.14: 81.12,97.11 81.12,100.78 87.99,107.65 87.99,108.64 92.38,113.03 92.38,120.77 v3(92.33,120.82)
M_B_DQ38: length 52.4
  TOP w0.076: v3(79.6,83.21) U11.AP37
  TOP w0.102: CN11.187 97.97,119.84 97.75,120.07 97.75,122.1 97.55,122.3 96.81,122.3 96.73,122.23 96.73,121.84 v3(96.26,121.37)
  L4_IN2 w0.076: 84.84,97.11 84.84,97 84.37,96.53 84.37,91.62 82.44,89.69 82.44,89.02 80.27,86.85 80.27,84.81 80.14,84.68 80.14,83.35 80.01,83.21 v3(79.6,83.21)
  L4_IN2 w0.14: 84.84,97.11 84.84,99.99 91.22,106.37 91.22,107.27 95.61,111.66 95.61,118.31 95.8,118.5 96.49,118.5 96.71,118.72 96.71,121.23 96.57,121.37 v3(96.26,121.37)
M_B_DQ39: length 51.9
  TOP w0.076: v3(79.6,83.85) U11.AR37
  TOP w0.102: CN11.183 96.97,119.76 96.8,119.94 96.8,120.26 96.89,120.35 97.33,120.35 97.43,120.46 97.43,121.6 97.33,121.7 97.02,121.7 96.93,121.6 96.93,120.89 96.8,120.76 96.42,120.76 v3(96.26,120.61)
  L4_IN2 w0.076: v3(79.6,83.85) 79.6,83.7 79.67,83.62 79.78,83.62 79.99,83.83 79.99,84.76 80.12,84.89 80.12,86.91 82.29,89.09 82.29,89.76 82.89,90.36 82.89,90.47 82.61,90.75 82.61,90.85 82.87,91.11 82.97,91.11 83.25,90.83 83.36,90.83 84.17,91.64 84.17,96.64 84.5,96.97 84.5,97.11
  L4_IN2 w0.14: v3(96.26,120.61) 96.37,120.5 96.37,119 96.23,118.87 96.03,118.87 95.78,119.11 95.63,119.11 95.27,118.75 95.27,111.81 90.88,107.41 90.88,106.51 84.5,100.13 84.5,97.11
M_B_DQ40: length 54.1
  TOP w0.076: v3(81.43,84.48) 81.61,84.35 U11.AT33
  TOP w0.102: CN11.195 99.97,120.19 98.57,121.59 v3(98.19,121.59)
  L4_IN2 w0.076: 85.87,97.11 85.87,96.95 85.03,96.11 85.03,91.64 82.9,89.5 82.9,88.83 81.43,87.36 81.43,85.86 81.06,85.49 81.06,84.97 81.43,84.6 v3(81.43,84.48)
  L4_IN2 w0.14: 85.87,97.11 85.87,99.56 93.05,106.75 93.05,107.65 95.31,109.91 95.46,109.91 95.67,109.7 95.87,109.7 96.06,109.9 96.06,110.09 95.87,110.29 95.87,110.46 96.09,110.68 96.26,110.68 96.46,110.49 96.66,110.49 96.85,110.69 96.85,110.88 96.64,111.1 96.64,111.29 96.64,112.87 96.78,113.01 96.97,113.01 97.11,113.15 97.11,113.43 96.97,113.57 96.78,113.57 96.64,113.71 96.64,113.99 96.78,114.13 97.35,114.13 97.49,114.27 97.49,114.55 97.35,114.69 96.78,114.69 96.64,114.83 96.64,115.11 96.78,115.25 97.35,115.25 97.49,115.39 97.49,115.67 97.35,115.81 96.78,115.81 96.64,115.95 96.64,116.19 96.77,116.31 97.37,116.31 97.49,116.44 97.49,117.07 97.74,117.32 97.74,121.45 97.88,121.59 v3(98.19,121.59)
M_B_DQ41: length 53.6
  TOP w0.076: U11.AU33 81.61,84.99 v3(81.43,85.12)
  TOP w0.102: v3(98.16,120.26) 98.4,120.5 98.51,120.5 98.97,120.04 CN11.191
  L4_IN2 w0.076: 86.21,96.91 85.24,95.93 85.24,91.63 83.55,89.94 83.55,88.32 83.18,87.95 83.08,87.95 82.78,88.25 82.67,88.25 82.56,88.14 82.56,88.03 82.86,87.73 82.86,87.62 82.75,87.52 82.64,87.52 82.35,87.81 82.23,87.81 82.1,87.69 82.1,87.62 82.43,87.3 82.43,87.19 82.32,87.08 82.21,87.08 81.91,87.38 81.81,87.38 81.7,87.28 81.7,87.17 82,86.87 82,86.76 81.58,86.34 81.58,85.8 81.43,85.65 v3(81.43,85.12)
  L4_IN2 w0.14: 86.21,96.91 86.21,99.42 93.62,106.83 93.62,107.08 93.39,107.31 93.39,107.5 93.59,107.7 93.79,107.7 94.05,107.44 94.2,107.44 94.45,107.68 94.45,107.83 94.18,108.1 94.18,108.29 94.38,108.49 94.58,108.49 94.84,108.23 95.02,108.23 95.24,108.45 95.24,108.63 94.97,108.89 94.97,109.08 95.17,109.28 95.46,109.28 95.66,109.08 95.87,109.08 97.43,110.64 97.43,110.79 97.07,111.15 97.07,111.43 97.17,111.52 97.77,111.52 97.84,111.59 97.84,111.9 97.71,112.03 97.08,112.03 96.98,112.13 96.98,112.44 97.13,112.59 97.71,112.59 97.84,112.72 97.84,113.02 97.71,113.15 97.6,113.15 97.46,113.29 97.46,113.57 97.6,113.71 97.71,113.71 97.84,113.84 97.84,116.93 98.08,117.17 98.08,119.44 98.44,119.81 98.44,120.19 98.38,120.26 v3(98.16,120.26)
M_B_DQ42: length 52.9
  TOP w0.076: v3(83.26,85.12) U11.AU30
  TOP w0.102: v3(100.3,121.01) 100.81,121.52 100.81,124.16 102.22,125.58 CN11.204
  L4_IN2 w0.076: 87.35,97.48 87.35,96.76 85.87,95.28 85.87,91.4 84.25,89.77 84.25,88.2 83.55,87.5 83.55,85.95 83.26,85.66 v3(83.26,85.12)
  L4_IN2 w0.14: 87.35,97.48 87.35,98.98 98.96,110.58 98.96,116.45 99.17,116.66 99.82,116.66 99.94,116.78 99.94,117.09 99.82,117.21 99.35,117.21 99.21,117.35 99.21,117.64 99.35,117.77 99.74,117.77 99.88,117.91 99.88,118.19 99.74,118.33 99.27,118.33 99.21,118.39 99.21,118.83 99.27,118.89 99.74,118.89 99.88,119.03 99.88,120.59 v3(100.3,121.01)
M_B_DQ43: length 54.1
  TOP w0.076: v3(83.26,84.48) U11.AT30
  TOP w0.102: CN11.208 103.22,126.15 101.11,124.03 101.11,121.15 v3(100.34,120.38)
  L4_IN2 w0.076: 87.69,97.11 87.69,96.77 86.05,95.13 86.05,89.64 85.92,89.51 85.82,89.51 85.6,89.73 85.5,89.73 85.39,89.62 85.39,89.51 85.6,89.3 85.6,89.19 83.71,87.3 83.71,84.98 83.26,84.52 v3(83.26,84.48)
  L4_IN2 w0.14: 87.69,97.11 87.69,98.83 99.3,110.44 99.3,114.67 99.56,114.93 100.15,114.93 100.29,115.07 100.29,115.35 100.15,115.49 99.44,115.49 99.3,115.63 99.3,115.87 99.42,116 100.18,116 100.34,116.15 v3(100.34,120.38)
M_B_DQ44: length 55.1
  TOP w0.076: v3(81.43,83.85) 81.61,83.71 U11.AR33
  TOP w0.102: CN11.194 99.72,124.92 98.72,123.92 98.72,123.4 v3(98.22,122.9)
  L4_IN2 w0.076: 85.52,97.11 85.52,96.98 84.83,96.29 84.83,91.65 82.75,89.57 82.75,88.9 81.27,87.42 81.27,85.92 80.88,85.53 80.88,84.86 81.06,84.67 81.06,84.33 81.17,84.22 81.17,84.12 81.06,84.01 81.06,83.7 81.19,83.56 81.31,83.56 81.43,83.68 v3(81.43,83.85)
  L4_IN2 w0.14: v3(98.22,122.9) 97.39,122.07 97.39,118.43 96.77,117.81 96.39,117.81 96.3,117.72 96.3,117.29 96.39,117.2 97.05,117.2 97.15,117.11 97.15,116.77 97.05,116.67 96.43,116.67 96.3,116.54 96.3,111.38 92.48,107.56 92.48,107.37 92.66,107.18 92.66,106.85 92.59,106.77 92.38,106.77 92.15,106.99 92,106.99 91.91,106.9 91.91,106.54 92,106.44 92,106.18 85.52,99.71 85.52,97.11
M_B_DQ45: length 56
  TOP w0.076: U11.AP33 81.61,83.07 v3(81.43,83.21)
  TOP w0.102: CN11.190 98.72,125.7 98.62,125.6 97.95,125.6 97.88,125.52 97.88,125.27 97.95,125.19 98.73,125.19 98.83,125.09 98.83,124.91 98.74,124.83 98,124.83 97.88,124.7 97.88,123.87 98.14,123.6 v3(98.32,123.6)
  L4_IN2 w0.076: v3(81.43,83.21) 81.33,83.21 80.88,83.66 80.88,84.64 80.71,84.81 80.71,85.57 81.12,85.99 81.12,87.49 82.59,88.96 82.59,89.63 84.6,91.64 84.6,96.38 85.18,96.96 85.18,97.11
  L4_IN2 w0.14: 85.18,97.11 85.18,99.85 91.56,106.23 91.56,107.13 95.96,111.52 95.96,118.02 96.1,118.16 96.63,118.16 97.05,118.58 97.05,122.25 97.37,122.57 97.37,122.78 97.05,123.1 97.05,123.42 97.23,123.6 v3(98.32,123.6)
M_B_DQ46: length 54.1
  TOP w0.076: v3(83.26,83.85) U11.AR30
  TOP w0.102: v3(101.52,122.58) 102.33,121.77 102.33,120.5 102.97,119.86 CN11.207
  L4_IN2 w0.076: 87.91,97.11 87.91,96.71 86.2,95 86.2,89.54 83.86,87.21 83.86,84.91 83.65,84.7 83.65,84.24 v3(83.26,83.85)
  L4_IN2 w0.14: v3(101.52,122.58) 101.45,122.58 101.1,122.94 100.9,122.94 100.76,122.8 100.76,115.05 100.16,114.45 99.86,114.45 99.72,114.31 99.72,114.03 99.86,113.89 100.62,113.89 100.76,113.75 100.76,113.47 100.62,113.33 99.83,113.33 99.64,113.14 99.64,110.3 88.03,98.69 88.03,97.23 87.91,97.11
M_B_DQ47: length 54.9
  TOP w0.076: v3(83.26,83.21) U11.AP30
  TOP w0.102: v3(101.52,121.82) 102.03,121.31 102.03,120.55 101.97,120.5 CN11.203
  L4_IN2 w0.076: 88.67,97.11 88.67,96.43 88.51,96.27 88.08,96.27 86.97,95.16 86.97,90.1 84.07,87.19 84.07,84.9 83.8,84.64 83.8,83.11 83.63,82.94 83.53,82.94 v3(83.26,83.21)
  L4_IN2 w0.14: v3(101.52,121.82) 101.33,121.82 101.11,121.59 101.11,113.26 100.67,112.83 100.12,112.83 99.98,112.69 99.98,112.41 100.12,112.27 100.97,112.27 101.11,112.13 101.11,111.87 100.99,111.75 100.16,111.75 99.98,111.57 99.98,111.32 100.12,111.19 100.91,111.19 101.05,111.05 101.05,110.77 100.91,110.63 100.31,110.63 100.06,110.38 100.06,110.24 88.67,98.84 88.67,97.11
M_B_DQ48: length 54.2
  TOP w0.076: v3(85.09,85.13) U11.AU27
  TOP w0.102: CN11.211 103.97,119.75 v3(103.17,120.55)
  L4_IN2 w0.076: 89.89,96.49 89.45,96.06 89.45,92.3 89.08,91.93 87.71,91.93 87.65,91.87 87.65,91.61 87.71,91.55 88.09,91.55 88.18,91.45 88.18,91.32 88.09,91.22 87.71,91.22 87.58,91.09 87.58,90.84 87.66,90.76 88.08,90.76 88.16,90.69 88.16,90.54 88.08,90.46 87.66,90.46 87.58,90.38 87.58,89.79 84.78,86.99 84.78,85.44 v3(85.09,85.13)
  L4_IN2 w0.14: 89.89,96.49 90.05,96.65 90.05,98.28 97.11,105.34 97.3,105.34 97.54,105.1 97.77,105.1 97.94,105.27 97.94,105.52 97.68,105.78 97.68,105.91 97.9,106.12 98.1,106.12 98.47,105.75 98.79,105.75 102.57,109.53 102.57,115.29 102.72,115.45 103.16,115.45 103.3,115.59 103.3,115.88 103.16,116.02 102.71,116.02 102.57,116.16 102.57,116.45 102.71,116.59 103.15,116.59 103.3,116.74 103.3,118.03 103.16,118.17 102.71,118.17 102.57,118.31 102.57,118.59 102.71,118.73 103.16,118.73 103.3,118.87 103.3,119.15 103.16,119.29 102.71,119.29 102.57,119.43 102.57,119.71 102.71,119.85 103.16,119.85 103.3,119.98 103.3,120.42 v3(103.17,120.55)
M_B_DQ49: length 54.8
  TOP w0.076: v3(85.09,84.48) U11.AT27
  TOP w0.102: CN11.215 104.97,119.76 104.44,120.3 104.18,120.3 v3(103.17,121.31)
  L4_IN2 w0.076: v3(85.09,84.48) 85.09,84.51 84.86,84.74 84.86,84.75 84.63,84.98 84.63,87.05 87.43,89.85 87.43,92.01 87.5,92.08 89.02,92.08 89.3,92.36 89.3,96.39 89.65,96.74
  L4_IN2 w0.14: v3(103.17,121.31) 102.64,120.79 102.64,120.39 102.22,119.97 102.22,109.67 101.29,108.74 101.09,108.74 100.68,109.15 100.48,109.15 100.29,108.95 100.29,108.75 100.7,108.34 100.7,108.15 100.5,107.95 100.3,107.95 99.89,108.36 99.69,108.36 99.5,108.16 99.5,107.96 99.91,107.55 99.91,107.36 99.54,106.99 99.34,106.99 98.96,107.38 98.77,107.38 98.56,107.16 98.56,106.98 98.95,106.59 98.95,106.4 98.75,106.2 98.55,106.2 98.09,106.66 97.94,106.66 89.71,98.42 89.71,96.79 89.65,96.74
M_B_DQ50: length 53.1
  TOP w0.076: v3(86,84.48) U11.AT25
  TOP w0.102: CN11.224 107.22,125.35 105.43,123.56 105.43,123.11 v3(105.9,122.65)
  L4_IN2 w0.076: v3(86,84.48) 86.22,84.7 86.22,84.81 86.37,84.97 86.37,86.65 88.39,88.67 88.39,89.5 90.65,91.77 90.65,95.12 90.96,95.43
  L4_IN2 w0.14: v3(105.9,122.65) 105.26,122.01 105.26,120.5 104.78,120.03 104.78,114.75 104.12,114.09 104.12,108.94 97.52,102.33 96.16,102.33 92.1,98.26 92.1,96.91 91.65,96.47 91.65,96.13 90.96,95.43
M_B_DQ51: length 52.7
  TOP w0.076: v3(86,85.12) U11.AU25
  TOP w0.102: v3(105.9,123.35) 108.22,125.67 CN11.228
  L4_IN2 w0.076: 90.71,95.67 90.42,95.38 90.42,91.77 88.21,89.56 88.21,88.77 86.05,86.61 86.05,85.17 v3(86,85.12)
  L4_IN2 w0.14: v3(105.9,123.35) 105.54,123.35 104.91,122.72 104.91,120.65 104.44,120.17 104.44,114.89 103.78,114.24 103.78,109.08 97.37,102.67 96.02,102.67 91.68,98.33 91.68,97.08 91.31,96.71 91.31,96.27 90.71,95.67
M_B_DQ52: length 55.1
  TOP w0.076: v3(85.09,83.21) U11.AP27
  TOP w0.102: v3(103.17,122.68) 102.76,123.08 102.76,123.62 103.26,124.11 103.26,125.03 104.22,126 CN11.212
  L4_IN2 w0.076: v3(85.09,83.21) 84.89,83.21 84.7,83.4 84.7,84.69 84.45,84.94 84.45,87.09 87.28,89.92 87.28,92.26 87.35,92.34 88.08,92.34 88.18,92.24 88.92,92.24 89.15,92.46 89.15,96.48 89.36,96.69 89.36,97.02
  L4_IN2 w0.14: 89.36,97.02 89.36,98.57 100.49,109.69 101.75,109.69 101.88,109.82 101.88,120.26 102.3,120.68 102.3,121.81 v3(103.17,122.68)
M_B_DQ53: length 55.6
  TOP w0.076: v3(85.09,82.58) U11.AN27
  TOP w0.102: v3(103.17,123.31) 104.15,124.29 104.15,124.77 105.22,125.85 CN11.216
  L4_IN2 w0.076: 89.02,97.11 89.02,96.57 88.57,96.12 88.2,96.12 87.12,95.04 87.12,89.98 84.25,87.1 84.25,84.93 84.55,84.63 84.55,83.11 v3(85.09,82.58)
  L4_IN2 w0.14: v3(103.17,123.31) 102.08,123.31 101.96,123.19 101.96,120.88 101.54,120.46 101.54,110.11 101.46,110.03 100.34,110.03 89.02,98.71 89.02,97.11
M_B_DQ54: length 55.5
  TOP w0.076: v3(86,82.58) U11.AN25
  TOP w0.102: v3(106.03,120.74) 106.79,120.74 107.47,120.05 CN11.225
  L4_IN2 w0.076: 91.8,94.59 90.95,93.74 90.95,91.64 88.69,89.38 88.69,88.53 86.67,86.51 86.67,84.84 86.52,84.69 86.52,83.21 86,82.69 v3(86,82.58)
  L4_IN2 w0.14: v3(106.03,120.74) 106.11,120.66 106.11,116.63 105.47,115.99 105.47,111.24 105.33,111.1 105.05,111.1 104.91,110.96 104.91,110.67 105.05,110.53 105.23,110.53 105.37,110.39 105.37,110.13 105.2,109.97 105.01,109.97 104.88,109.84 104.88,108.73 97.46,101.3 97.26,101.3 96.92,101.64 96.73,101.64 96.53,101.45 96.53,101.25 96.87,100.91 96.87,100.71 96.67,100.51 96.47,100.51 96.13,100.85 95.94,100.85 95.74,100.66 95.74,100.46 96.08,100.12 96.08,99.92 95.88,99.72 95.68,99.72 95.34,100.06 95.14,100.06 94.95,99.87 94.95,99.67 95.29,99.33 95.29,99.13 95.03,98.87 94.83,98.87 94.43,99.27 94.23,99.27 92.84,97.88 92.84,96.68 92.38,96.22 92.38,95.17 91.8,94.59
M_B_DQ55: length 54.6
  TOP w0.076: v3(86,83.21) U11.AP25
  TOP w0.102: CN11.229 108.47,119.75 108.31,119.92 108.11,119.92 106.67,121.36 v3(105.96,121.36)
  L4_IN2 w0.076: 91.4,94.68 90.8,94.07 90.8,91.7 88.54,89.44 88.54,88.6 86.52,86.58 86.52,84.9 86.37,84.75 86.37,83.7 86,83.33 v3(86,83.21)
  L4_IN2 w0.14: v3(105.96,121.36) 105.71,121.36 105.6,121.25 105.6,120.34 105.77,120.18 105.77,119.81 105.59,119.63 105.26,119.63 105.12,119.49 105.12,119.21 105.26,119.07 105.63,119.07 105.77,118.93 105.77,118.65 105.63,118.51 105.26,118.51 105.12,118.37 105.12,118.09 105.26,117.95 105.59,117.95 105.73,117.81 105.73,116.74 105.12,116.14 105.12,114.17 104.99,114.03 104.68,114.03 104.54,113.89 104.54,113.58 105.03,113.09 105.03,112.77 104.54,112.27 104.54,108.87 97.66,101.99 96.31,101.99 92.45,98.13 92.45,96.78 92.04,96.37 92.04,95.31 91.4,94.68
M_B_DQ56: length 56.3
  TOP w0.076: U11.AT22 v3(87.83,84.48)
  TOP w0.102: v3(108.2,120.4) 108.9,120.4 109.47,119.83 CN11.233
  L4_IN2 w0.076: 91.53,92.79 91.41,92.67 91.41,91.42 91.53,91.31 91.53,91.01 91.46,90.94 91.39,90.94 91.22,91.11 91.09,91.11 90.97,90.98 90.97,90.87 91.22,90.62 91.22,90.5 91.13,90.41 91,90.41 90.8,90.61 90.67,90.61 90.58,90.52 90.58,90.4 90.8,90.18 90.8,90.05 90.71,89.96 90.59,89.96 90.36,90.19 90.23,90.19 90.14,90.1 90.14,89.98 90.37,89.75 90.37,89.62 90.28,89.53 90.15,89.53 89.92,89.76 89.8,89.76 89.71,89.67 89.71,89.55 89.96,89.29 89.96,89.19 89.85,89.08 89.74,89.08 89.58,89.24 89.47,89.24 89.24,89.01 89.24,88.39 87.45,86.6 87.45,84.95 87.6,84.79 87.6,84.71 v3(87.83,84.48)
  L4_IN2 w0.14: v3(108.2,120.4) 107.14,119.34 107.14,115.1 106.96,114.92 106.62,114.92 106.5,114.8 106.5,114.53 106.64,114.39 107.01,114.39 107.15,114.25 107.15,113.98 107.01,113.84 106.64,113.84 106.5,113.7 106.5,108.88 105.91,108.3 105.91,108.1 105.96,108.05 105.96,107.86 105.77,107.66 105.57,107.66 105.52,107.71 105.32,107.71 105.12,107.51 105.12,107.31 105.17,107.26 105.17,107.07 104.97,106.87 104.78,106.87 104.73,106.92 104.53,106.92 104.33,106.72 104.33,106.52 104.38,106.47 104.38,106.28 104.18,106.08 103.99,106.08 103.94,106.13 103.74,106.13 103.54,105.93 103.54,105.73 103.59,105.68 103.59,105.49 103.39,105.29 103.2,105.29 103.15,105.34 102.95,105.34 102.75,105.14 102.75,104.94 102.8,104.89 102.8,104.69 102.6,104.5 102.41,104.5 102.36,104.55 102.16,104.55 101.96,104.35 101.96,104.15 102.01,104.1 102.01,103.9 101.81,103.71 101.62,103.71 101.57,103.76 101.37,103.76 101.17,103.56 101.17,103.36 101.22,103.31 101.22,103.11 101.02,102.92 100.83,102.92 100.77,102.97 100.58,102.97 100.38,102.77 100.38,102.57 100.43,102.52 100.43,102.32 100.23,102.13 100.03,102.13 99.98,102.18 99.79,102.18 99.59,101.98 99.59,101.78 99.64,101.73 99.64,101.53 99.44,101.33 99.24,101.33 99.19,101.39 99,101.39 98.8,101.19 98.8,100.99 98.85,100.94 98.85,100.74 98.65,100.54 98.45,100.54 98.4,100.59 98.21,100.59 98.01,100.4 98.01,100.2 98.06,100.14 98.06,99.95 93.41,95.29 93.41,94.67 91.53,92.79
M_B_DQ57: length 55.7
  TOP w0.076: v3(87.83,85.13) U11.AU22
  TOP w0.102: CN11.237 110.47,120.04 109.53,120.99 v3(108.19,120.99)
  L4_IN2 w0.076: 91.72,92.5 91.72,90.64 87.6,86.52 87.6,86.01 87.7,85.91 87.83,85.91 87.93,85.81 87.93,85.68 87.83,85.58 87.7,85.58 87.6,85.48 87.6,85.3 87.77,85.13 v3(87.83,85.13)
  L4_IN2 w0.14: 91.72,92.5 93.75,94.53 93.75,95.15 106.88,108.27 106.88,108.74 106.98,108.84 107.46,108.84 107.6,108.98 107.6,109.26 107.46,109.4 106.98,109.4 106.84,109.54 106.84,109.82 106.98,109.96 107.46,109.96 107.6,110.1 107.6,110.38 107.46,110.52 106.98,110.52 106.84,110.66 106.84,110.94 106.98,111.08 107.46,111.08 107.6,111.22 107.6,111.5 107.46,111.64 106.98,111.64 106.84,111.78 106.84,112.06 106.98,112.2 107.46,112.2 107.6,112.34 107.6,112.65 107.46,112.79 106.98,112.79 106.84,112.93 106.84,113.21 106.98,113.35 107.47,113.35 107.55,113.43 107.55,117.76 107.69,117.9 107.84,117.9 107.98,118.04 107.98,118.46 107.84,118.6 107.69,118.6 107.55,118.74 107.55,119.2 108.1,119.75 108.28,119.75 108.67,120.14 108.67,120.73 108.41,120.99 v3(108.19,120.99)
M_B_DQ58: length 54.8
  TOP w0.076: v3(88.74,85.13) U11.AU21
  TOP w0.102: CN11.249 113.47,119.64 111.79,121.33 v3(110.98,121.33)
  L4_IN2 w0.076: 92.42,91.51 92.42,90.53 92.35,90.46 90.82,88.93 90.82,88.17 90.54,87.89 90.52,87.89 88.92,86.29 88.92,85.31 v3(88.74,85.13)
  L4_IN2 w0.14: 92.42,91.51 95.07,94.16 95.07,94.73 108.74,108.4 108.74,115.37 108.87,115.49 109.24,115.49 109.38,115.63 109.38,115.93 109.24,116.07 108.91,116.07 108.77,116.21 108.77,116.49 108.91,116.63 109.24,116.63 109.38,116.77 109.38,119.06 109.95,119.63 109.95,122.81 110.11,122.96 110.44,122.96 110.55,122.84 110.55,121.42 110.65,121.33 v3(110.98,121.33)
M_B_DQ59: length 55.7
  TOP w0.076: v3(88.74,84.48) U11.AT21
  TOP w0.102: CN11.245 112.47,120.01 111.74,120.74 v3(111.01,120.74)
  L4_IN2 w0.076: 92.65,91.26 92.65,90.53 90.98,88.86 90.98,88.11 90.81,87.94 90.81,87.84 90.91,87.74 90.91,87.67 90.62,87.38 90.55,87.38 90.43,87.5 90.35,87.5 90.07,87.23 90.07,87.14 90.19,87.03 90.19,86.95 89.9,86.67 89.83,86.67 89.73,86.76 89.63,86.76 89.54,86.67 89.54,86.37 89.43,86.26 89.2,86.26 89.12,86.18 89.12,84.97 88.74,84.59 v3(88.74,84.48)
  L4_IN2 w0.14: v3(111.01,120.74) 110.81,120.94 110.49,120.94 110.29,120.74 110.29,119.63 110.43,119.49 110.92,119.49 111.12,119.28 111.12,119.05 110.75,118.67 110.51,118.67 110.25,118.93 109.95,118.93 109.72,118.7 109.72,115.15 109.56,114.99 109.21,114.99 109.09,114.86 109.09,114.56 109.23,114.42 109.71,114.42 109.85,114.28 109.85,114 109.71,113.86 109.23,113.86 109.09,113.72 109.09,113.44 109.23,113.3 109.71,113.3 109.85,113.16 109.85,112.89 109.71,112.75 109.23,112.75 109.09,112.61 109.09,112.33 109.23,112.19 109.5,112.19 109.64,112.05 109.64,111.77 109.5,111.63 109.23,111.63 109.09,111.49 109.09,108.26 95.46,94.63 95.46,94.06 92.65,91.26
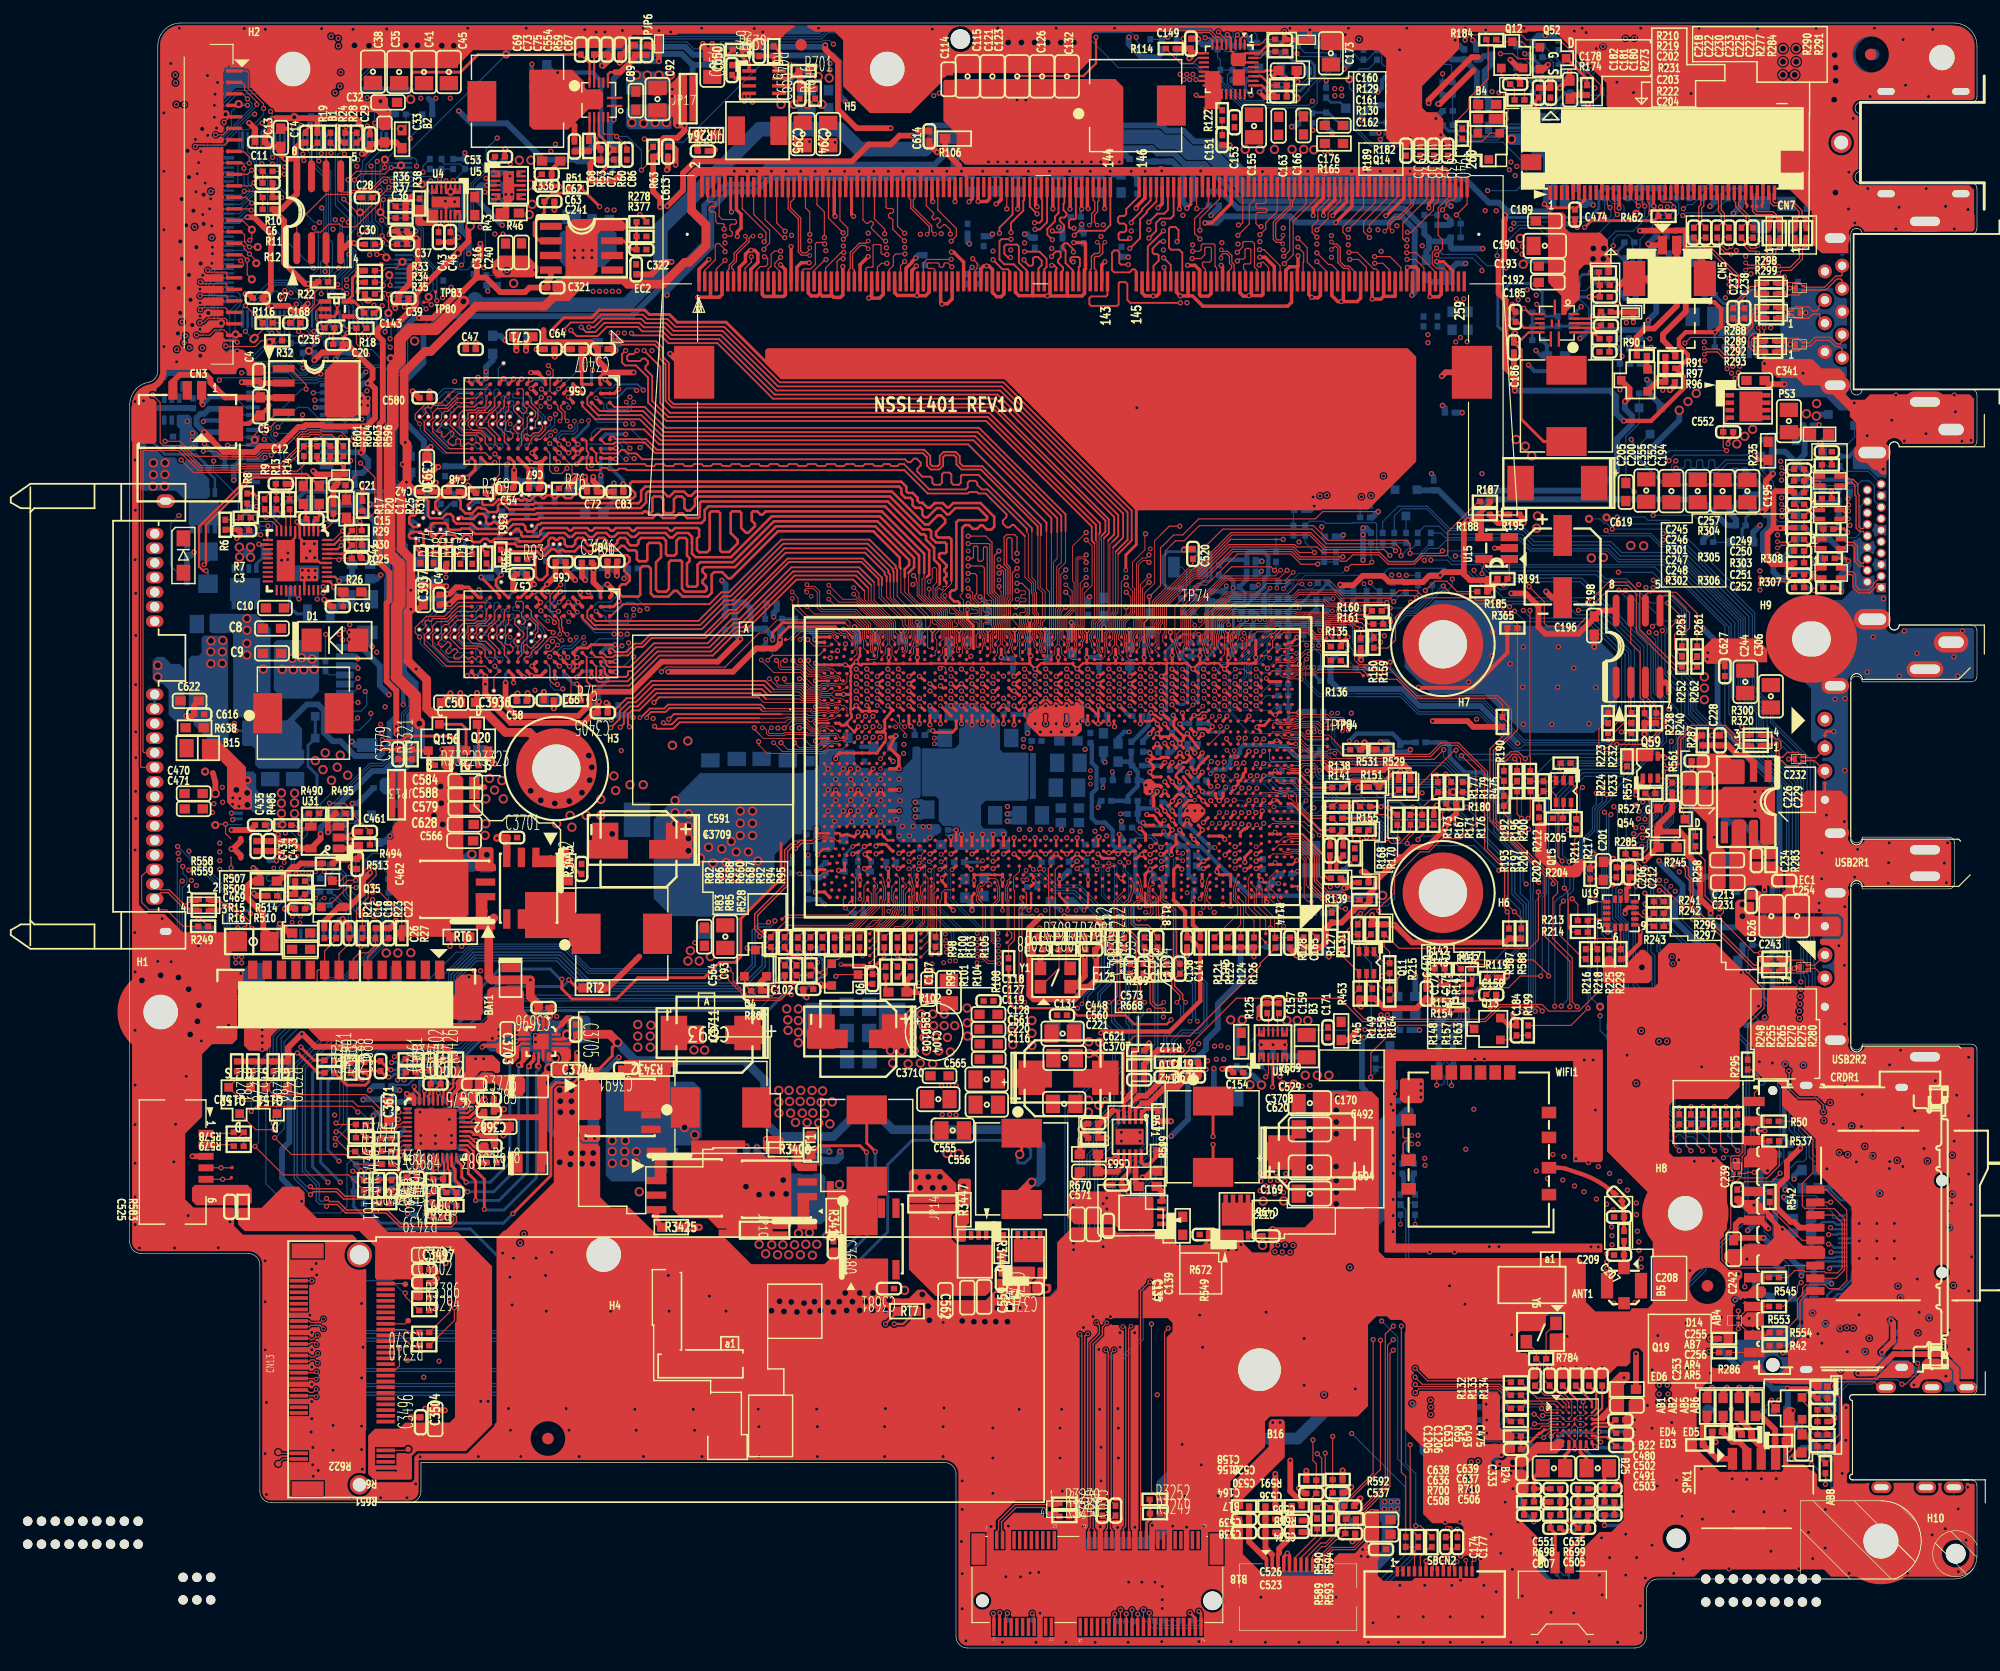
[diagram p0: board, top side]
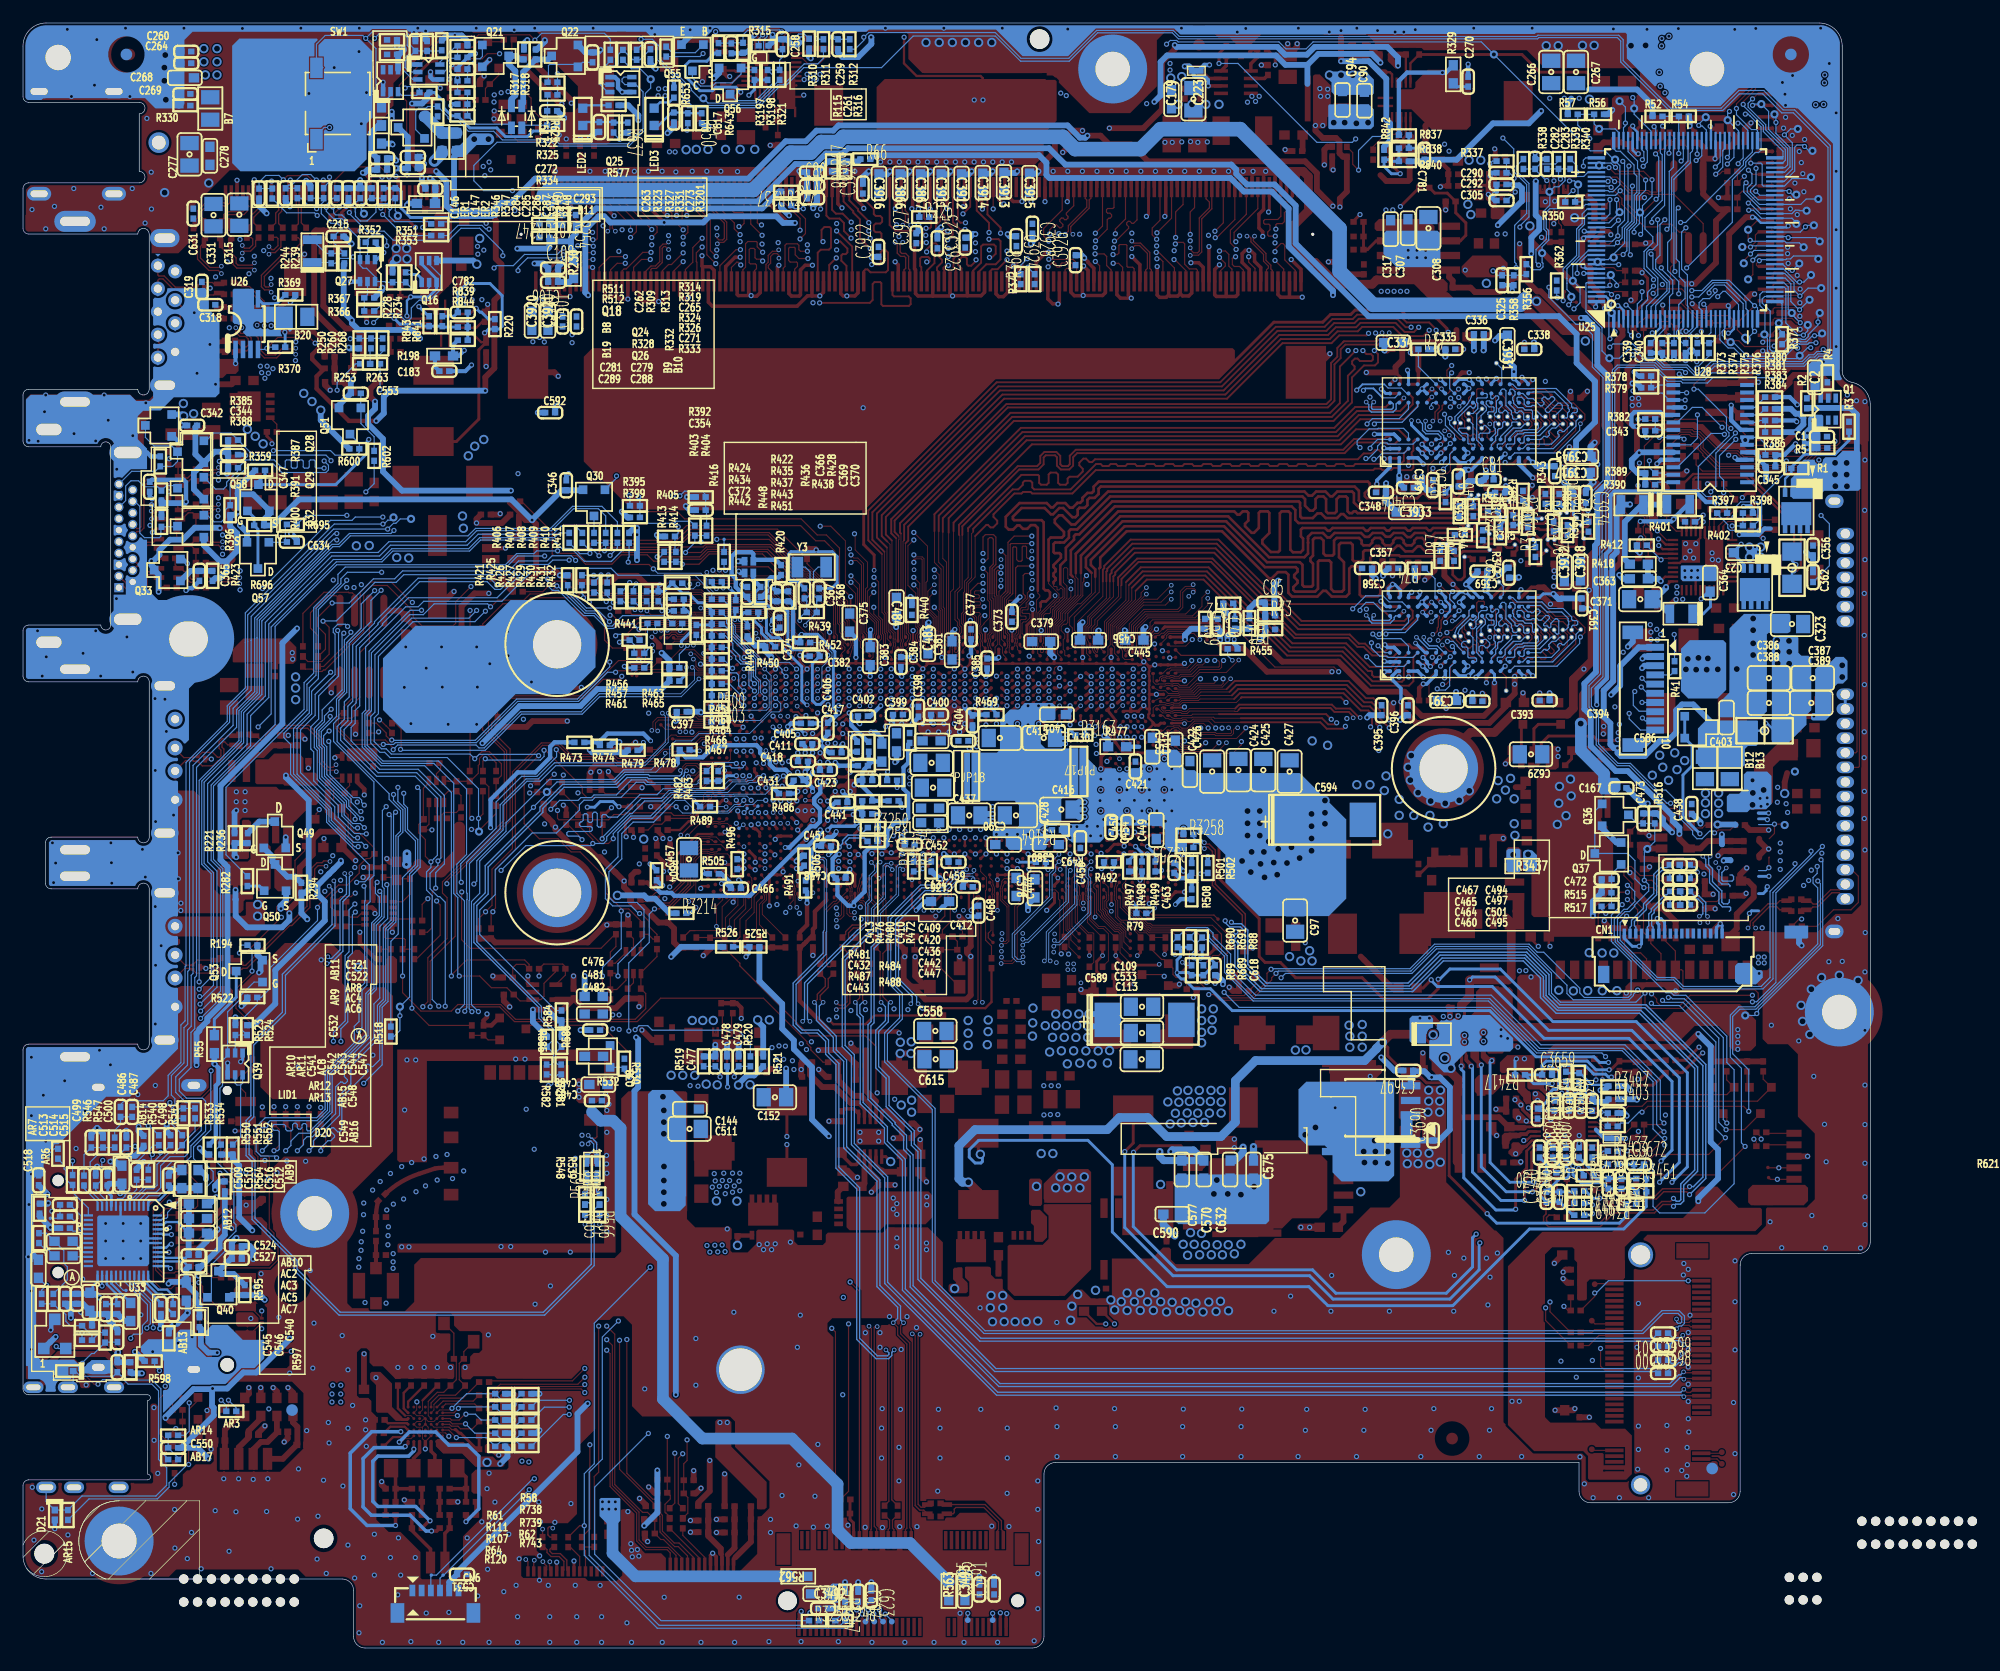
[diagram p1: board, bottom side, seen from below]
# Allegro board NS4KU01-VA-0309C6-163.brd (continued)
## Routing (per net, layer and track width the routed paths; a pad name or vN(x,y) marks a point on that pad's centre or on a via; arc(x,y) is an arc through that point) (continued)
M_B_DQ60: length 58
  TOP w0.076: U11.AN22 v3(87.83,82.58)
  TOP w0.102: v3(107.74,123.28) 107.74,123.75 110.22,126.23 CN11.236
  L4_IN2 w0.076: 92.08,94.31 91.1,93.34 91.1,91.55 88.86,89.3 88.86,88.46 87.12,86.73 87.12,84.84 87.3,84.67 87.3,82.66 87.38,82.58 v3(87.83,82.58)
  L4_IN2 w0.14: 92.08,94.31 92.72,94.96 92.72,96.08 93.54,96.9 93.54,97.1 93.18,97.47 93.18,97.66 93.38,97.86 93.57,97.86 93.94,97.5 94.14,97.5 94.33,97.69 94.33,97.89 93.93,98.29 93.93,98.49 94.13,98.69 94.33,98.69 94.73,98.29 94.93,98.29 105.81,109.17 105.81,109.34 105.61,109.54 105.61,109.75 105.81,109.95 105.81,115.85 106.45,116.49 106.45,121.99 v3(107.74,123.28)
M_B_DQ61: length 57.7
  TOP w0.076: U11.AP22 v3(87.83,83.21)
  TOP w0.102: CN11.232 109.22,126.02 107.23,124.03 107.23,123.16 v3(107.74,122.65)
  L4_IN2 w0.076: v3(87.83,83.21) 87.53,83.21 87.45,83.29 87.45,84.73 87.28,84.91 87.28,86.65 89.02,88.4 89.02,89.25 91.26,91.49 91.26,93.01 92.32,94.07
  L4_IN2 w0.14: 92.32,94.07 93.07,94.82 93.07,95.94 93.65,96.52 93.85,96.52 93.9,96.47 94.1,96.47 94.3,96.66 94.3,96.86 94.24,96.92 94.24,97.11 94.48,97.35 94.67,97.35 94.73,97.29 94.93,97.29 95.12,97.49 95.12,97.69 95.07,97.75 95.07,97.94 95.27,98.14 95.46,98.14 95.52,98.08 95.72,98.08 95.92,98.28 95.92,98.48 95.86,98.54 95.86,98.73 96.06,98.93 96.25,98.93 96.31,98.88 96.51,98.88 96.71,99.07 96.71,99.27 96.65,99.33 96.65,99.52 96.85,99.72 97.05,99.72 97.1,99.67 97.3,99.67 97.5,99.86 97.5,100.06 97.44,100.12 97.44,100.31 106.15,109.03 106.15,115.71 106.79,116.35 106.79,120.37 106.93,120.51 107.39,120.51 107.53,120.65 107.53,120.92 107.39,121.06 106.93,121.06 106.79,121.2 106.79,121.4 106.98,121.59 107.53,121.59 107.74,121.8 v3(107.74,122.65)
M_B_DQ62: length 56.9
  TOP w0.076: v3(88.74,83.21) 89.1,83.21 89.2,83.13 U11.AP21
  TOP w0.102: v3(111,122.45) 110.73,122.45 110.64,122.54 110.64,123.9 112.72,125.99 CN11.246
  L4_IN2 w0.076: v3(88.74,83.21) 89.11,83.58 89.11,84.68 89.3,84.87 89.3,85.85 91.13,87.68 91.13,88.78 92.86,90.51 92.86,90.97
  L4_IN2 w0.14: v3(111,122.45) 111.32,122.45 111.47,122.3 111.47,118.86 110.83,118.22 110.33,118.22 110.19,118.08 110.19,111.84 109.59,111.23 109.57,111.23 109.43,111.09 109.43,110.75 109.57,110.61 109.99,110.61 110.13,110.47 110.13,110.19 109.99,110.05 109.57,110.05 109.43,109.91 109.43,108.12 95.8,94.48 95.8,93.92 92.86,90.97
M_B_DQ63: length 57.9
  TOP w0.076: v3(88.74,82.58) 89.04,82.58 89.2,82.44 U11.AN21
  TOP w0.102: v3(111.04,123.1) 111.37,123.1 113.31,125.04 113.31,125.42 113.72,125.84 CN11.250
  L4_IN2 w0.076: v3(88.74,82.58) 88.96,82.58 89.11,82.73 89.11,83.37 89.26,83.52 89.26,84.62 89.45,84.81 89.45,85.78 91.28,87.61 91.28,88.7 93.06,90.48 93.06,90.69
  L4_IN2 w0.14: 93.06,90.69 96.14,93.77 96.14,94.34 109.78,107.98 109.78,108.43 109.92,108.57 110.31,108.57 110.45,108.71 110.45,108.99 110.31,109.13 109.92,109.13 109.78,109.27 109.78,109.52 109.92,109.65 110.45,109.65 110.56,109.76 110.56,117.36 111.87,118.67 111.87,122.39 111.16,123.1 v3(111.04,123.1)
M_B_DQS0: length 72
  TOP w0.076: v3(64.59,80.11) U11.AH65
  TOP w0.107: v2(54.17,122.77) 54,122.77 53.82,122.59 53.82,122.27 52.73,121.18 52.73,120.58 52.3,120.15 52.3,120.01 52.47,119.83 CN11.13
  L4_IN2 w0.076: 58.31,76.93 58.34,76.9 58.5,76.9 62.26,80.65 62.6,80.65 62.73,80.52 62.91,80.52 63.03,80.65 63.55,80.65 63.55,80.65 64.2,80.65 64.41,80.44 64.41,80.29 v3(64.59,80.11)
  L4_IN2 w0.127: 58.31,76.93 53.17,76.93 51.31,78.79 51.31,81.12 49.72,82.71 49.72,106.51 50.6,107.38 50.6,116.79 51.01,117.21 51.24,117.21 51.66,117.63 51.66,117.97 51.31,118.33 51.31,118.47 51.5,118.67 51.65,118.67 51.98,118.34 52.38,118.34 52.68,118.64 52.68,118.97 52.24,119.41 52.24,119.52 52.43,119.71 52.53,119.71 53,119.24 53.27,119.24 53.61,119.57 53.61,119.95 53,120.56 53,120.68 53.38,121.07 53.38,121.42 53.03,121.78 53.03,121.95 53.13,122.06 53.67,122.06 53.89,122.27 53.89,122.48 v2(54.17,122.77)
M_B_DQS1: length 60.6
  TOP w0.076: v2(54.98,80.02) 55.18,80.02 55.34,79.86 55.34,79.51 55.52,79.33 56.89,79.33 56.99,79.43 58.79,79.43 58.91,79.32 60.04,79.32 60.04,79.32 60.52,79.32 60.62,79.37 60.78,79.37 60.89,79.32 61.16,79.32 61.24,79.36 61.34,79.36 61.39,79.31 61.39,79.13 U11.AG70
  TOP w0.107: CN11.34 57.72,126.02 57.43,125.72 57.43,125.23 58.31,124.35 58.31,121.47 58.46,121.32 58.81,121.32 59.1,121.61 v2(59.1,121.75)
  L4_IN2 w0.127: v2(54.98,80.02) 55.15,80.18 55.15,81.93 53,84.07 53,86.62 53.49,87.12 53.49,90.34 54.71,91.57 54.71,93.09 55.03,93.41 55.03,106.15 53.93,107.24 53.93,114.34 58.36,118.76 58.36,121.02 58.72,121.39 59.09,121.75 v2(59.1,121.75)
M_B_DQS2: length 50.1
  TOP w0.076: U11.AR65 64.42,83.49 v3(64.05,83.85)
  TOP w0.107: CN11.55 62.97,119.81 62.83,119.95 62.83,121.27 63.51,121.95 63.9,121.95 v2(64.18,121.68)
  L4_IN2 w0.076: 58.48,92.12 58.48,91.68 59.41,90.75 59.41,90.11 61.55,87.97 62.43,87.97 63.69,86.71 63.69,84.08 63.53,83.93 63.53,83.7 63.64,83.6 63.9,83.6 64.05,83.75 v3(64.05,83.85)
  L4_IN2 w0.127: 58.48,92.12 58.48,93.92 58.59,94.03 58.87,94.03 59.18,94.34 59.18,94.75 58.9,95.03 58.71,95.03 58.63,95.11 58.63,95.41 58.71,95.49 58.96,95.49 59.18,95.7 59.18,114.75 63.72,119.3 63.72,120.56 63.65,120.64 63.65,121.69 63.82,121.87 64,121.87 64.18,121.68 v2(64.18,121.68)
M_B_DQS3: length 50.1
  TOP w0.076: v3(66.8,83.85) 67.16,83.49 U11.AR60
  TOP w0.107: CN11.76 68.22,126.05 68.09,125.91 68.09,125.28 69.69,123.68 69.69,123.2 v2(69.96,122.93)
  L4_IN2 w0.076: 62.69,92.74 62.69,92.66 62.66,92.63 62.66,92.44 62.55,92.34 62.55,91.49 62.76,91.28 63.33,91.28 63.51,91.1 63.51,90.52 64.59,89.44 64.66,89.44 66.54,87.56 66.54,85.91 66.45,85.83 66.45,85.72 66.54,85.63 66.54,85.39 66.43,85.27 66.43,84.01 66.59,83.85 v3(66.8,83.85)
  L4_IN2 w0.127: 62.69,92.74 62.69,111.87 67.94,117.11 67.94,117.91 69.76,119.74 69.76,122.74 v2(69.96,122.93)
M_B_DQS4: length 50.8
  TOP w0.076: v3(78.68,83.85) 78.69,83.85 79.14,83.49 U11.AR38
  TOP w0.107: v2(94.86,121.57) 94.99,121.45 95.41,121.45 95.78,121.08 95.78,120.49 95.97,120.3 CN11.179
  L4_IN2 w0.076: v3(78.68,83.85) 78.52,84.01 78.32,84.01 78.14,84.2 78.14,85.41 78.7,85.96 78.7,86.79 80.71,88.8
  L4_IN2 w0.127: 80.71,88.8 80.71,94.2 81.05,94.54 82.26,94.54 82.45,94.73 82.45,97.24 83.13,97.91 83.13,98.14 83.02,98.24 82.81,98.24 82.58,98.47 82.58,99.21 82.83,99.46 82.99,99.46 83.1,99.57 83.1,99.73 82.95,99.87 82.95,100.52 89.49,107.06 89.49,108.07 93.88,112.45 93.88,121.02 94.34,121.48 94.77,121.48 v2(94.86,121.57)
M_B_DQS5: length 54.2
  TOP w0.076: v3(82.34,83.85) U11.AR32
  TOP w0.107: CN11.200 101.22,126.01 101.06,125.84 101.06,125.36 99.59,123.9 99.59,122.58 99.73,122.44 100.06,122.44 100.22,122.6 v2(100.22,122.84)
  L4_IN2 w0.076: v3(82.34,83.85) 82.34,83.85 82.2,84 81.98,84 81.8,84.18 81.8,86.25 83.84,88.3 83.84,89.95 85.24,91.35 85.44,91.55
  L4_IN2 w0.127: v2(100.22,122.84) 99.31,122.84 98.88,122.41 98.88,119.62 98.53,119.27 98.53,117.01 98.28,116.75 98.28,110.87 86.65,99.24 86.65,96.89 85.44,95.68 85.44,91.55
M_B_DQS6: length 54.3
  TOP w0.076: v3(85.09,83.85) U11.AR27
  TOP w0.107: v2(104.44,122.26) 104.62,122.08 104.92,122.08 105.2,121.8 105.2,120.55 105.58,120.17 105.96,120.17 106.47,119.66 CN11.221
  L4_IN2 w0.076: v3(85.09,83.85) 85.15,83.85 85.45,84.16 85.45,85.37 85.07,85.75 85.07,86.9 85.79,87.63 86.58,87.63 87.87,88.91 87.87,89.7 89.92,91.76 89.92,95.81 90.19,96.07 90.19,96.09 90.23,96.14 90.23,96.14 90.23,96.16
  L4_IN2 w0.127: v2(104.44,122.26) 104.31,122.13 104,122.13 103.73,121.86 103.73,115.31 103.04,114.61 103.04,109.47 103.04,109.47 103.04,109.38 98.34,104.69 98.32,104.69 98.3,104.67 97.3,104.67 96.89,104.26 96.89,103.91 97.07,103.73 97.07,103.57 96.92,103.41 96.76,103.41 96.45,103.72 96.11,103.72 90.53,98.14 90.53,96.46 90.23,96.16
M_B_DQS7: length 56.3
  TOP w0.076: v3(88.74,83.85) U11.AR21
  TOP w0.107: v2(109.72,123.2) 109.54,123.38 109.54,123.83 109.92,124.22 110.3,124.22 111.56,125.47 111.56,125.9 111.72,126.07 CN11.242
  L4_IN2 w0.076: 92.18,91.99 92.18,90.53 90.71,89.06 90.65,89.06 89.94,88.35 89.94,87.62 89.3,86.98 88.57,86.98 88.38,86.8 88.38,86.69 88.72,86.36 88.72,85.83 88.37,85.49 88.37,84.22 v3(88.74,83.85)
  L4_IN2 w0.127: 92.18,91.99 94.5,94.32 94.5,94.87 108.28,108.65 108.28,116.66 108.77,117.14 108.77,119.25 109.46,119.95 109.46,121.96 109.24,122.18 108.62,122.18 108.52,122.28 108.52,122.49 108.62,122.59 109.33,122.59 109.51,122.77 109.51,122.99 v2(109.72,123.2)
M_B_DQS#0: length 72
  TOP w0.076: U11.AH66 63.69,79.66 63.97,80.05 v3(63.96,80.11)
  TOP w0.107: v2(53.51,122.77) 53.62,122.66 53.62,122.36 52.52,121.26 52.52,120.67 52.09,120.24 52.09,119.91 51.97,119.8 CN11.11
  L4_IN2 w0.076: v3(63.96,80.11) 64.14,80.11 64.22,80.19 64.22,80.38 64.12,80.48 63.11,80.48 62.98,80.35 62.65,80.35 62.52,80.48 62.35,80.48 58.58,76.71 58.35,76.71 58.32,76.68 58.31,76.68
  L4_IN2 w0.127: v2(53.51,122.77) 53.65,122.63 53.65,122.37 53.57,122.3 53.03,122.3 52.79,122.05 52.79,121.68 53.14,121.32 53.14,121.17 52.76,120.78 52.76,120.46 53.37,119.85 53.37,119.67 53.17,119.48 53.1,119.48 52.63,119.95 52.33,119.95 52,119.62 52,119.31 52.44,118.87 52.44,118.74 52.28,118.58 52.08,118.58 51.75,118.91 51.4,118.91 51.06,118.57 51.06,118.23 51.42,117.87 51.42,117.73 51.14,117.45 50.91,117.45 50.36,116.89 50.36,107.48 49.48,106.61 49.48,82.61 51.07,81.02 51.07,78.69 53.07,76.68 58.31,76.68
M_B_DQS#1: length 60.6
  TOP w0.076: U11.AG69 62,79.16 61.94,79.1 61.74,79.1 61.6,79.24 61.6,79.34 61.42,79.52 61.21,79.52 61.13,79.49 60.92,79.49 60.82,79.54 60.58,79.54 60.48,79.49 59.95,79.49 59.87,79.49 58.99,79.49 58.87,79.61 56.91,79.61 56.81,79.51 55.6,79.51 55.52,79.59 55.52,79.77 v2(55.77,80.02)
  TOP w0.107: v2(59.1,121.09) 59.08,121.11 58.38,121.11 58.1,121.39 58.1,124.26 57.22,125.14 CN11.32
  L4_IN2 w0.127: v2(55.77,80.02) 55.7,79.94 55.47,79.94 55.39,80.02 55.39,82.03 53.24,84.17 53.24,86.52 53.73,87.02 53.73,90.24 54.95,91.47 54.95,92.99 55.27,93.31 55.27,106.25 54.17,107.34 54.17,114.24 58.6,118.66 58.6,120.92 58.82,121.15 59.04,121.15 v2(59.1,121.09)
M_B_DQS#2: length 50.1
  TOP w0.076: v3(63.14,83.85) 63.5,83.49 U11.AR66
  TOP w0.107: CN11.53 62.47,119.81 62.62,119.95 62.62,121.35 63.43,122.16 64,122.16 v2(64.18,122.34)
  L4_IN2 w0.076: v3(63.14,83.85) 63.2,83.85 63.51,84.16 63.51,86.64 62.35,87.79 61.46,87.79 59.22,90.03 59.22,90.67 58.29,91.6 58.29,92 58.24,92.05
  L4_IN2 w0.127: 58.24,92.05 58.24,94.02 58.49,94.27 58.77,94.27 58.93,94.44 58.93,94.65 58.8,94.79 58.61,94.79 58.39,95.01 58.39,95.51 58.61,95.73 58.86,95.73 58.93,95.8 58.93,114.85 63.48,119.4 63.48,120.46 63.41,120.54 63.41,121.79 63.72,122.11 63.95,122.11 v2(64.18,122.34)
M_B_DQS#3: length 50.1
  TOP w0.076: U11.AR61 66.25,83.49 v3(65.88,83.85)
  TOP w0.107: CN11.74 67.72,126.07 67.88,125.91 67.88,125.2 69.49,123.59 69.49,123.12 v2(69.3,122.93)
  L4_IN2 w0.076: 62.45,92.74 62.47,92.73 62.47,92.52 62.36,92.42 62.36,91.41 62.67,91.11 63.25,91.11 63.33,91.03 63.33,90.45 64.51,89.26 64.59,89.26 66.36,87.49 66.36,85.99 66.28,85.9 66.28,85.64 66.36,85.55 66.36,85.46 66.25,85.35 66.25,83.96 66.14,83.85 v3(65.88,83.85)
  L4_IN2 w0.127: 62.45,92.74 62.45,111.97 67.7,117.21 67.7,118.01 69.52,119.84 69.52,122.71 v2(69.3,122.93)
M_B_DQS#4: length 50.8
  TOP w0.076: U11.AT38 78.95,84.11 78.72,84.29 v3(78.68,84.55)
  TOP w0.107: CN11.177 95.47,119.71 95.77,120 95.77,120.21 95.57,120.41 95.57,121 95.33,121.24 95,121.24 94.85,121.09 v2(94.85,120.85)
  L4_IN2 w0.076: 80.95,88.8 80.95,88.79 80.92,88.77 80.92,88.71 80.8,88.59 80.76,88.59 78.89,86.71 78.89,85.88 78.32,85.31 78.32,84.29 78.4,84.2 78.58,84.2 78.68,84.31 v3(78.68,84.55)
  L4_IN2 w0.127: 80.95,88.8 80.95,94.1 81.15,94.3 82.36,94.3 82.73,94.67 82.73,97.17 83.37,97.81 83.37,98.24 83.12,98.48 82.91,98.48 82.82,98.57 82.82,99.11 82.93,99.22 83.09,99.22 83.34,99.47 83.34,99.83 83.19,99.97 83.19,100.42 89.73,106.96 89.73,107.97 94.12,112.35 94.12,120.92 94.44,121.24 94.67,121.24 94.85,121.06 v2(94.85,120.85)
M_B_DQS#5: length 54.2
  TOP w0.076: U11.AT32 v3(82.34,84.48)
  TOP w0.107: v2(100.2,122.1) 100.07,122.23 99.64,122.23 99.38,122.49 99.38,123.99 100.85,125.45 100.85,125.91 100.72,126.03 CN11.198
  L4_IN2 w0.076: v3(82.34,84.48) 82.42,84.41 82.42,84.3 82.34,84.22 82.19,84.22 82.15,84.17 82.05,84.17 81.97,84.25 81.97,86.18 84.02,88.22 84.02,89.88 85.39,91.25 85.42,91.25 85.46,91.3 85.49,91.3 85.66,91.47
  L4_IN2 w0.127: v2(100.2,122.1) 100.2,122.35 99.94,122.6 99.41,122.6 99.12,122.31 99.12,119.52 98.77,119.17 98.77,116.91 98.52,116.65 98.52,110.77 86.89,99.14 86.89,96.79 85.68,95.58 85.68,91.49 85.66,91.47
M_B_DQS#6: length 54.4
  TOP w0.076: U11.AR25 86.3,83.49 86,83.72 v3(86,83.85)
  TOP w0.107: CN11.219 105.97,119.86 105.88,119.96 105.49,119.96 104.99,120.47 104.99,121.71 104.84,121.87 104.71,121.87 v2(104.44,121.6)
  L4_IN2 w0.076: 90.4,95.99 90.39,95.98 90.36,95.98 90.11,95.73 90.11,91.68 88.06,89.62 88.06,88.83 86.66,87.43 85.87,87.43 85.26,86.83 85.26,85.81 85.53,85.54 85.63,85.44 85.63,84.08 85.54,83.99 85.54,83.75 85.64,83.65 85.9,83.65 86,83.75 v3(86,83.85)
  L4_IN2 w0.127: v2(104.44,121.6) 104.44,121.75 104.3,121.89 104.1,121.89 103.98,121.76 103.98,115.21 103.28,114.51 103.28,109.37 103.28,109.37 103.28,109.28 98.44,104.45 98.42,104.45 98.4,104.42 97.4,104.42 97.14,104.16 97.14,104.01 97.32,103.83 97.32,103.47 97.02,103.17 96.66,103.17 96.35,103.48 96.21,103.48 90.77,98.04 90.77,96.36 90.4,95.99
M_B_DQS#7: length 56.3
  TOP w0.076: U11.AR22 88.21,83.55 v3(87.83,83.85)
  TOP w0.107: v2(109.06,123.2) 109.33,123.46 109.33,123.92 109.84,124.43 110.22,124.43 111.35,125.56 111.35,125.9 111.22,126.03 CN11.240
  L4_IN2 w0.076: 91.96,92.11 91.96,90.62 90.55,89.21 90.53,89.21 89.76,88.44 89.76,87.69 89.23,87.16 88.49,87.16 88.21,86.87 88.21,86.62 88.54,86.29 88.54,85.91 88.2,85.57 88.2,84.18 87.87,83.85 v3(87.83,83.85)
  L4_IN2 w0.127: v2(109.06,123.2) 109.11,123.2 109.27,123.04 109.27,122.87 109.23,122.83 108.52,122.83 108.28,122.59 108.28,122.18 108.52,121.94 109.14,121.94 109.22,121.86 109.22,120.05 108.52,119.35 108.52,117.24 108.04,116.76 108.04,108.75 94.26,94.97 94.26,94.42 91.96,92.11
M_VREF_CA_MD0: length 110.4
  TOP w0.254: v3(33.36,110.35) 33.36,110.31 U1637.M1 ; U1636.M1 32.87,91.35 31.84,92.38 31.84,92.86 v3(32.28,93.31)
  TOP w0.508: v3(53.07,87.74) 51.1,85.77 46.23,85.77 43.61,83.15 40.47,83.15 39.96,82.64 39.96,82.03 38.99,81.05 33.57,81.05 32.66,81.97 v3(32.66,83.93)
  L3_IN1 w0.305: v3(32.66,83.93) 33.57,84.85 33.57,86.49 34.28,87.21 34.28,89.49 32.85,90.92 32.85,93.01 32.56,93.31 v3(32.28,93.31)
  L3_IN1 w0.381: v3(32.79,102.92) 32.79,104.19 34.38,105.78 34.38,108.64 33.36,109.65 v3(33.36,110.35)
  L3_IN1 w0.508: v3(33.36,110.35) 33.36,112 32.85,112.51 25.1,112.51 22.84,110.25 22.84,98.72 22.57,98.45 22.57,87.98 23.68,86.86 23.68,84.53 26.56,81.65 31.9,81.65 32.66,82.41 v3(32.66,83.93)
  BOTTOM w0.254: U1635.M1 32.66,84.67 v3(32.66,83.93) ; v3(32.79,102.92) 32.93,103.06 U1638.M1
  BOTTOM w0.381: C81.2 32.74,102.87 v3(32.79,102.92)
  BOTTOM w0.508: C82.2 31.65,93.93 v3(32.28,93.31) ; v3(53.07,87.74) 53.02,87.74 52.59,88.18 R71.2 R73.1 52.59,90.86 C85.1 53.43,90.92 53.96,90.39 R70.1
M_VREF_CB_DIMM0: length 9.5
  TOP w0.254: v3(91.86,125.19) 92.22,125.55 CN11.164
  BOTTOM w0.508: v3(91.86,125.19) 91.86,125.38 91.54,125.7 C78.2 C80.2 C79.1 90.6,129.26 R68.1 R67.2 87.97,129.26 R66.1
MA_ACT_N: length 101.5
  TOP w0.076: 67.35,93.14 67.35,91.82 69.58,89.6 69.58,88.93 69.35,88.7 69.35,87.01 69.43,86.93 U11.BA55
  TOP w0.102: TB29.1 34.25,88.02 34.25,88.25 33.47,89.03 33.47,89.49 33.72,89.75 U1636.L3 ; TC29.1 34.18,106.48 34.18,106.79 33.36,107.62 33.36,107.92 33.72,108.29 U1637.L3
  TOP w0.229: R361.2 32.27,95.49 TA29.1 33.2,95.36 35.4,95.36 35.79,94.97 36.08,94.97 36.66,95.55 36.92,95.55 37.11,95.36 37.34,95.36 37.47,95.48 37.69,95.48 37.82,95.36 38.67,95.36 39.12,95.8 39.32,95.8 39.77,95.36 40.4,95.36 40.89,95.84 41.11,95.84 41.51,95.45 42.32,95.45 42.71,95.83 42.95,95.83 43.34,95.45 43.93,95.45 44.07,95.31 44.07,94.67 44.25,94.49 44.86,94.49 44.98,94.62 44.98,95.93 45.15,96.09 46.01,96.09 46.17,95.93 46.17,94.85 45.74,94.41 45.74,92.03 45.91,91.86 46.63,91.86 46.86,92.09 46.86,94.39 47.02,94.56 47.89,94.56 48,94.45 48,92.11 48.25,91.86 49.99,91.86 50.14,92.01 50.14,92.25 49.78,92.61 49.78,92.82 50.06,93.11 50.06,93.3 49.78,93.59 49.78,93.83 49.93,93.98 52.6,93.98 56.16,97.54 64.8,97.54 67.74,94.61 67.74,94.17 67.35,93.79 67.35,93.14
  L4_IN2 w0.102: TB29.1 33.64,87.4 33.5,87.4 33.42,87.48 33.42,88.03 33.42,88.03 33.42,88.04 33.33,88.13 33.33,88.23 33.42,88.33 33.42,88.64 33.11,88.94 33.11,89.14 33.15,89.18 33.15,89.33 33.1,89.38 32.87,89.38 32.8,89.46 32.8,89.71 32.87,89.79 33.09,89.79 33.15,89.85 33.15,90.13 33.09,90.2 32.88,90.2 32.8,90.27 32.8,90.52 32.88,90.6 33.08,90.6 33.15,90.67 33.15,91.01 33.06,91.1 32.77,91.1 32.7,91.18 32.7,91.44 32.78,91.53 32.78,91.75 32.7,91.84 32.7,92.16 33.17,92.62 33.17,94.96 33.24,95.03 33.5,95.03 34.01,95.54 34.01,96.21 33.91,96.32 33.68,96.32 33.55,96.19 33.55,95.68 33.36,95.49 TA29.1 32.9,95.66 32.9,95.77 33.07,95.94 33.07,96.28 34.01,97.22 34.01,97.71 33.6,98.11 33.6,98.35 33.7,98.45 33.93,98.45 34.01,98.53 34.01,98.79 33.93,98.86 33.8,98.86 33.67,99 33.67,99.13 33.8,99.27 33.94,99.27 34.01,99.34 34.01,99.61 33.94,99.67 33.8,99.67 33.7,99.78 33.7,100.56 33.56,100.71 33.36,100.71 33.28,100.78 33.28,101.81 33.36,101.89 33.68,101.89 33.79,101.99 33.79,102.81 33.42,103.17 33.42,105.72 TC29.1
  BOTTOM w0.102: TB29.1 33.6,87.7 33.37,87.7 33.07,87.39 33.07,87.16 33.26,86.97 33.41,86.97 33.61,87.17 33.87,87.17 34,87.04 34,86.71 33.84,86.55 U1635.L3 ; U1638.L3 33.83,105.09 34,105.26 34,105.52 33.89,105.63 33.14,105.63 33.06,105.71 33.06,105.93 33.44,106.3 33.55,106.3 TC29.1
MA_BA0: length 98.8
  TOP w0.076: v3(71.37,85.12) U11.AU52
  TOP w0.102: U1637.N2 31.73,108.69 31.73,107.95 31.41,107.62 31.31,107.62 31.11,107.42 30.38,107.42 30.14,107.19 30.14,106.84 29.76,106.46 TC15.1 ; U1636.N2 31.73,90.14 31.73,89.41 31.41,89.08 31.31,89.08 31.11,88.88 30.38,88.88 30.14,88.65 30.14,88.3 29.76,87.92 TB15.1
  L3_IN1 w0.076: 71.37,89.81 71.37,88.11 71.45,88.04 71.95,88.04 72.03,87.96 72.03,87.81 71.95,87.73 71.45,87.73 71.37,87.66 71.37,87.5 71.45,87.43 71.95,87.43 72.03,87.35 72.03,87.2 71.95,87.12 71.45,87.12 71.37,87.05 71.37,86.89 71.45,86.82 71.95,86.82 72.03,86.74 72.03,86.59 71.95,86.51 71.45,86.51 71.37,86.44 v3(71.37,85.12)
  L3_IN1 w0.292: TA14.1 29.3,96.43 28.83,96.89 28.83,97.06 29.04,97.27 29.62,97.27 30.01,96.87 30.79,96.87 31.26,97.34 33.48,97.34 33.77,97.05 33.77,96.79 34.21,96.35 34.73,96.35 34.95,96.57 35.87,96.57 36.81,97.5 38.43,97.5 38.76,97.18 68.37,97.18 72.02,93.53 72.02,90.47 71.37,89.81
  L4_IN2 w0.102: TB15.1 29.37,88.29 29.37,89.03 29.47,89.13 29.8,89.13 29.9,89.24 29.9,89.44 29.8,89.54 29.47,89.54 29.37,89.64 29.37,89.85 29.47,89.95 29.68,89.95 29.79,90.05 29.79,90.25 29.68,90.35 29.18,90.35 29.1,90.43 29.1,90.66 29.36,90.92 29.36,91.19 29.1,91.45 29.1,96.18 TA14.1 29.46,96.54 29.46,98.28 28.99,98.75 28.99,100.2 29.21,100.42 29.59,100.42 29.76,100.59 TC15.1
  BOTTOM w0.102: U1638.N2 32.31,104.29 32.42,104.39 32.42,104.63 32.34,104.7 31.96,104.7 31.73,104.93 31.73,105.37 31.03,106.08 30.38,106.08 30.02,106.43 TC15.1 ; TB15.1 30.02,87.89 30.38,87.54 31.03,87.54 31.73,86.83 31.73,86.39 31.96,86.16 32.34,86.16 32.42,86.08 32.42,85.85 32.31,85.75 U1635.N2
  BOTTOM w0.229: R357.2 29.1,96.19 TA14.1
MA_BA1: length 101.5
  TOP w0.076: v3(74.11,84.51) 74.02,84.51 U11.AT48
  TOP w0.102: U1637.N8 31.73,104.69 31.73,105.25 30.9,106.08 30.38,106.08 30.14,106.31 30.14,106.55 30.52,106.94 TC10.1 ; U1636.N8 31.73,86.15 31.73,86.71 30.9,87.54 30.38,87.54 30.14,87.77 30.14,88.01 30.52,88.39 TB10.1
  L3_IN1 w0.076: v3(74.11,84.51) 73.74,84.87 73.74,85.43 74.43,86.12 74.43,87.81 75,88.37 75,94.11 74.77,94.34 74.77,97.11
  L3_IN1 w0.292: 74.77,97.11 74.77,97.52 72.7,99.59 41.73,99.59 41.4,99.92 35.81,99.92 35.21,99.32 30.36,99.32 29.89,98.85 29.89,98.39 TA11.1
  L4_IN2 w0.102: TB10.1 30.62,88.53 31.05,88.96 31.05,90.17 30.65,90.56 30.65,91.46 30.47,91.64 30.15,91.64 29.98,91.82 29.98,93.55 30.08,93.66 30.3,93.66 30.37,93.73 30.37,93.99 30.3,94.06 30.08,94.06 29.98,94.16 29.98,94.69 30.21,94.93 30.53,94.93 30.65,95.05 30.65,95.62 30.44,95.84 TA11.1 30.44,98.92 30.52,99.01 30.52,100.07 30.7,100.25 30.7,104.34 30.99,104.63 30.99,107.63 30.92,107.71 30.6,107.71 30.52,107.63 TC10.1
  BOTTOM w0.102: U1635.N8 32.13,90.78 31.99,90.92 31.8,90.92 31.66,90.78 31.66,89.5 31.18,89.02 31.18,88.72 31.09,88.63 31.09,88.4 31.01,88.32 30.74,88.32 TB10.1 ; TC10.1 30.74,106.86 31.01,106.86 31.09,106.94 31.09,107.18 31.18,107.26 31.18,107.56 31.66,108.04 31.66,109.32 31.8,109.46 31.99,109.46 32.13,109.32 U1638.N8
  BOTTOM w0.229: R360.2 30.64,97.64 TA11.1
MA_BG0: length 104.1
  TOP w0.076: U11.AY55 69.94,86.28 70,86.34 70,86.7 70.14,86.84 70.14,87.67 70,87.8 70,88.15 70.32,88.46 70.32,88.81 70.11,89.02 69.89,89.02 69.74,89.17 69.74,89.96 68.9,90.8 68.62,90.8 67.67,91.75 67.67,93.48
  TOP w0.102: U1637.M2 32.56,108.71 32.56,107.95 31.92,107.32 31.92,106.84 31.54,106.46 TC20.1 ; U1636.M2 32.56,90.17 32.56,89.41 31.92,88.78 31.92,88.3 31.54,87.92 TB20.1
  TOP w0.229: 67.67,93.48 68.17,93.98 68.17,94.78 64.98,97.97 55.98,97.97 52.43,94.41 49.57,94.41 49.35,94.19 49.35,92.42 49.21,92.29 48.55,92.29 48.43,92.41 48.43,94.28 48.65,94.51 48.65,94.76 48.43,94.98 48.43,96.38 48.29,96.52 47.75,96.52 47.52,96.29 47.52,95.17 47.34,94.99 46.74,94.99 46.6,95.12 46.6,96.29 46.37,96.52 44.43,96.52 44.2,96.29 44.2,96.03 44.05,95.88 43.52,95.88 43.29,96.11 43.29,96.29 43.06,96.52 42.6,96.52 42.37,96.29 42.37,96.11 42.15,95.88 41.69,95.88 41.46,96.11 41.46,96.29 41.23,96.52 40.77,96.52 40.55,96.29 40.55,96.11 40.32,95.88 39.86,95.88 39.63,96.11 39.63,96.29 39.4,96.52 38.95,96.52 38.72,96.29 38.72,96.02 38.49,95.79 37.99,95.79 37.8,95.98 37.8,96.36 37.64,96.52 37.35,96.52 37.18,96.36 37.01,96.36 36.85,96.52 36.6,96.52 36.41,96.33 36.41,95.91 36.05,95.55 35.81,95.55 35.58,95.79 35.51,95.79 33.68,95.79 33.45,96.02 31.89,96.02 31.65,95.77 31.64,95.77 31.55,95.68 31.14,95.68 TA21.1 30.69,95.75 30.69,95.48 R355.2
  L4_IN2 w0.102: TB20.1 31.54,87.01 31.05,86.52 30.79,86.52 30.6,86.71 30.6,87 31.11,87.51 31.11,87.72 30.9,87.93 30.9,88.39 31.34,88.83 31.34,90.29 30.95,90.68 30.95,91.58 30.78,91.74 30.78,91.85 30.95,92.01 30.95,92.16 30.84,92.27 30.65,92.27 30.53,92.39 30.53,92.57 30.63,92.67 30.84,92.67 30.95,92.77 30.95,93.39 30.77,93.57 30.77,93.8 30.95,93.98 30.95,94.2 30.77,94.38 30.77,94.61 30.95,94.79 30.95,95.87 TA21.1 30.82,96 30.82,96.11 30.95,96.24 30.95,96.36 30.88,96.42 30.79,96.42 30.73,96.48 30.73,96.68 30.94,96.89 30.94,97.03 30.73,97.24 30.73,97.36 30.95,97.57 30.95,97.71 30.82,97.83 30.82,97.95 30.95,98.07 30.95,98.15 30.73,98.37 30.73,98.49 30.95,98.7 30.95,98.79 30.82,98.92 30.82,99.58 30.93,99.7 30.93,99.77 30.83,99.88 30.83,99.97 30.99,100.13 31.23,100.13 31.38,100.28 31.38,100.36 31.2,100.54 31.05,100.54 30.99,100.59 30.99,102.22 31.14,102.36 31.14,102.44 30.99,102.59 30.99,103.31 31.06,103.37 31.06,103.55 30.99,103.61 30.99,103.8 31.06,103.87 31.06,104.03 30.99,104.09 30.99,104.22 31.15,104.38 31.33,104.38 31.42,104.47 31.42,104.74 31.29,104.87 31.29,105.06 31.42,105.19 31.42,105.35 31.29,105.49 31.29,105.64 31.42,105.78 31.42,105.94 31.29,106.08 31.29,106.36 31.36,106.43 TC20.1
  BOTTOM w0.102: TB20.1 31.73,88.08 31.85,88.08 31.95,87.98 31.95,87.63 32.09,87.49 32.28,87.49 32.38,87.39 32.38,86.94 32.56,86.77 32.56,86.46 32.93,86.08 U1635.M2 ; U1638.M2 32.93,104.62 32.56,105 32.56,105.31 32.38,105.49 32.38,105.93 32.28,106.03 32.09,106.03 31.95,106.17 31.95,106.53 31.85,106.62 31.73,106.62 TC20.1
MA_CKE0: length 98.2
  TOP w0.076: U11.BA56 69.09,87.4 68.95,87.54 68.82,87.8 68.82,87.8 68.82,88.15 69.17,88.51 69.17,89.65 67.01,91.81 67.01,93.88
  TOP w0.102: U1637.K2 34.91,108.71 34.91,108.25 35.48,107.68 35.48,106.9 35.25,106.68 35.25,106.15 35.17,106.07 TC18.1 ; U1636.K2 34.91,90.17 34.91,89.66 35.48,89.09 35.48,88.36 35.25,88.13 35.25,87.87 TB18.1
  TOP w0.229: 67.01,93.88 66.92,93.96 66.92,94.81 64.62,97.11 56.34,97.11 52.24,93.01 52.02,93.01 51.48,93.55 50.79,93.55 50.57,93.33 50.57,91.75 50.25,91.43 48.05,91.43 47.56,91.92 47.3,91.92 46.81,91.43 45.55,91.43 45.28,91.7 45.28,93.86 45.07,94.06 44.57,94.06 44.37,93.86 44.37,91.59 44.2,91.43 42.81,91.43 42.57,91.67 42.57,92.3 42.76,92.49 43.11,92.49 43.45,92.83 43.45,93.2 42.98,93.67 42.98,94.02 43.45,94.49 43.45,94.8 43.23,95.02 40.95,95.02 40.86,94.92 36.64,94.92 36.29,94.57 36.29,93.32 35.84,92.88 35.55,92.88 35.26,93.16 TA20.1 34.77,94.88 R93.2
  L4_IN2 w0.102: TB18.1 34.91,87.38 34.83,87.3 34.51,87.3 34.44,87.38 34.44,88.42 34.63,88.61 34.91,88.61 35.16,88.87 35.16,89.78 34.42,90.52 34.42,93.27 34.52,93.37 35.06,93.37 35.17,93.47 35.17,93.67 35.06,93.77 34.52,93.77 34.42,93.88 34.42,94.08 34.57,94.22 35.48,94.22 35.63,94.37 35.63,94.81 35.55,94.88 TA20.1 35.26,95.21 36.11,96.06 36.11,100.81 35.83,101.1 35.83,103.6 34.91,104.52 TC18.1
  BOTTOM w0.102: TB18.1 35.35,87.53 35.52,87.36 35.52,87.13 35.42,87.03 35.08,87.03 34.97,86.92 34.97,86.18 34.88,86.09 34.29,86.09 34.21,86.02 34.21,85.82 34.29,85.75 U1635.K2 ; U1638.K2 34.47,104.29 34.37,104.39 34.37,104.63 34.44,104.7 34.91,104.7 34.97,104.76 34.97,105.48 35.07,105.59 35.47,105.59 35.78,105.89 35.78,106 35.7,106.07 TC18.1
MA_CLK0: length 85.9
  TOP w0.076: U11.AT53 70.86,84.13 v3(70.5,84.4)
  TOP w0.102: TC26.1 35.64,106.51 35.86,106.29 35.86,106.03 35.49,105.67 35.09,105.67 34.82,105.4 34.71,105.4 34.56,105.55 34.4,105.55 34.26,105.41 34.26,105.26 34.43,105.09 U1637.K7 ; TB26.1 35.72,87.86 35.72,87.75 34.9,86.94 34.8,86.94 34.48,87.25 34.34,87.25 34.26,87.18 34.26,86.62 34.34,86.55 U1636.K7
  L3_IN1 w0.076: 70.96,89.63 70.91,89.58 70.91,86.9 70.51,86.49 70.51,86.04 71,85.54 71,84.87 70.52,84.4 v3(70.5,84.4)
  L3_IN1 w0.267: TA26.1 36.92,96.07 36.92,96.44 37.44,96.97 38.21,96.97 38.54,96.65 68.15,96.65 71.67,93.13 71.67,90.81 70.96,90.11 70.96,89.63
  L4_IN2 w0.114: TC26.1 35.72,106.4 35.72,104.62 36.48,103.86 36.48,102 37.19,101.29 37.19,100.92 36.81,100.54 36.81,99.73 37.16,99.39 37.71,99.39 37.83,99.27 37.83,98.82 37.71,98.7 37.33,98.7 37,98.38 37,96.16 TA26.1 37.04,95.76 37.04,95.59 36.99,95.53 36.55,95.53 36.31,95.28 36.31,94.75 36.55,94.5 37.61,94.5 37.83,94.28 37.83,93.33 37.62,93.12 37.19,93.12 36.72,93.59 36.22,93.59 35.62,92.99 35.62,91.67 36.18,91.11 36.18,90.06 35.73,89.62 35.73,88.11 TB26.1
  BOTTOM w0.102: TB26.1 35.84,88.21 35.84,88.23 35.7,88.56 34.8,89.46 34.69,89.46 34.59,89.35 34.48,89.35 34.26,89.57 34.26,89.7 34.34,89.78 34.5,89.78 U1635.K7 ; TC26.1 35.6,106.53 35.84,106.77 35.84,106.95 34.83,107.97 34.72,107.97 34.57,107.82 34.45,107.82 34.31,107.96 34.31,108.15 34.45,108.29 U1638.K7
  BOTTOM w0.229: R81.2 36.24,95.39 TA26.1
MA_CLK#0: length 86
  TOP w0.076: v3(70.43,85.18) 70.52,85.31 70.72,85.34 70.89,85.22 70.95,84.84 U11.AU53
  TOP w0.102: U1636.K8 34.32,85.96 34.32,86.11 34.43,86.22 34.7,86.22 34.89,86.4 34.89,86.56 35.97,87.65 35.97,87.84 TB25.1 ; TC25.1 36.11,105.93 35.6,105.42 35.2,105.42 34.9,105.12 34.56,104.3 U1637.K8
  L3_IN1 w0.076: 70.58,89.63 70.69,89.52 70.69,86.95 70.32,86.57 70.32,85.96 70.81,85.46 70.81,84.96 70.61,84.76 70.18,84.76 70.04,84.9 70.04,85.08 70.15,85.18 v3(70.43,85.18)
  L3_IN1 w0.267: TA25.1 37.3,96.07 37.3,96.29 37.6,96.59 38.06,96.59 38.38,96.27 67.89,96.27 71.29,92.87 71.29,90.97 70.58,90.26 70.58,89.63
  L4_IN2 w0.114: TC25.1 35.95,106.37 35.95,104.71 36.71,103.95 36.71,102.1 37.42,101.38 37.42,100.83 37.04,100.44 37.04,99.83 37.25,99.62 37.81,99.62 38.06,99.36 38.06,98.73 37.81,98.48 37.44,98.48 37.23,98.27 37.23,96.13 TA25.1 37.27,95.87 37.27,95.49 37.08,95.3 36.65,95.3 36.53,95.19 36.53,94.84 36.65,94.73 37.71,94.73 38.06,94.37 38.06,93.24 37.72,92.89 37.09,92.89 36.63,93.36 36.31,93.36 35.85,92.9 35.85,91.76 36.41,91.21 36.41,89.97 35.96,89.52 35.96,88.13 TB25.1
  BOTTOM w0.102: TB25.1 36.09,88 36.09,88.28 35.91,88.7 34.87,89.75 34.87,90.21 U1635.K8 ; U1638.K8 34.57,109.05 34.8,108.49 34.82,108.47 35.08,108.08 36.1,107.06 36.1,106.55 TC25.1
  BOTTOM w0.229: TA25.1 37.2,95.8 37.2,95.57 R87.2
MA_CS#0: length 94.9
  TOP w0.076: v3(75.94,84.51) 75.76,84.51 U11.AU45
  TOP w0.102: U1637.L7 33.73,105.61 33.38,105.96 33.38,106.2 TC21.1 ; U1636.L7 33.73,87.05 33.38,87.4 33.38,87.7 TB21.1
  L3_IN1 w0.076: 76.7,97.11 76.7,96.48 76.53,96.3 76.53,85.09 v3(75.94,84.51)
  L3_IN1 w0.292: 76.7,97.11 76.7,98.32 73.43,101.59 44.31,101.59 43.47,102.43 40.7,102.43 40.62,102.36 38.46,102.36 38.08,101.98 35.73,101.98 34.06,100.3 TA19.1
  L4_IN2 w0.102: TC21.1 34.05,106.65 34.13,106.57 34.13,105.41 34.04,105.32 33.73,105.32 33.63,105.22 33.63,105.01 33.73,104.91 33.98,104.91 34.08,104.81 34.08,104.61 33.98,104.51 33.73,104.51 33.63,104.41 33.63,104.2 33.73,104.1 33.98,104.1 34.08,104 34.08,103.8 33.98,103.69 33.73,103.69 33.63,103.59 33.63,103.39 33.73,103.29 34.13,103.29 34.23,103.19 34.23,102.33 34.08,102.18 34.08,101.88 34.18,101.78 34.84,101.78 34.95,101.67 34.95,101.49 34.87,101.41 33.65,101.41 33.57,101.34 33.57,101.12 33.68,101.02 34.87,101.02 34.95,100.94 34.95,100.7 34.86,100.61 34.16,100.61 34.06,100.51 TA19.1 34.3,100.01 34.3,95.42 33.46,94.57 33.46,92.5 33.08,92.12 33.08,91.5 33.44,91.13 33.44,89.11 33.76,88.79 33.76,88.16 TB21.1
  BOTTOM w0.102: TB21.1 33.83,88.14 33.83,88.67 33.44,89.06 33.44,89.36 33.73,89.64 U1635.L7 ; TC21.1 33.83,107.16 33.36,107.62 33.36,107.87 33.73,108.24 U1638.L7
  BOTTOM w0.229: R140.2 34.5,99.81 TA19.1
MA_ODT0: length 93.2
  TOP w0.076: U11.AT45 75.37,84.14 v3(75.03,84.48)
  TOP w0.102: U1636.K3 34.53,89.74 35.27,89 35.27,88.6 TB23.1 ; TC22.1 35.26,107.13 35.26,107.49 34.53,108.22 U1637.K3
  L3_IN1 w0.076: v3(75.03,84.48) 75.08,84.53 75.08,87.36 75.46,87.74 75.46,90.55 75.54,90.62 75.89,90.62 75.97,90.7 75.97,90.85 75.89,90.93 75.54,90.93 75.46,91.01 75.46,91.16 75.54,91.23 75.89,91.23 75.97,91.31 75.97,91.46 75.89,91.54 75.54,91.54 75.46,91.62 75.46,91.77 75.54,91.84 75.89,91.84 75.97,91.92 75.97,95.47 75.74,95.7 75.74,97.11
  L3_IN1 w0.292: 75.74,97.11 75.74,97.92 73.1,100.56 43.98,100.56 43.65,100.89 43.24,100.89 42.91,100.56 42.13,100.56 41.8,100.88 36.54,100.88 TA22.1
  L4_IN2 w0.102: TC22.1 34.91,106.84 35.26,107.2 35.26,107.49 34.06,108.69 34.06,108.88 34.26,109.08 34.5,109.08 35.22,108.36 35.99,108.36 36.09,108.25 36.09,107.11 35.9,106.92 35.51,106.92 35.25,106.66 35.25,106.36 35.26,106.35 35.26,104.57 36.12,103.72 36.12,101.3 TA22.1 36.41,95.94 35.92,95.45 35.92,93.81 34.71,92.6 34.71,90.64 35.41,89.94 35.41,88.66 34.99,88.23 TB23.1
  BOTTOM w0.102: TB23.1 34.53,87.86 U1635.K3 ; TC22.1 34.53,106.4 U1638.K3
  BOTTOM w0.229: R256.2 36.92,100.51 TA22.1
MB_CKE0: length 49.9
  TOP w0.076: v3(68.63,82.58) U11.AN56
  TOP w0.165: v3(75.03,120.71) 75.84,119.89 76.31,119.89 76.47,119.73 CN11.109
  L4_IN2 w0.076: 65.3,92.74 65.3,92.54 68.02,89.83 68.02,89.03 68.62,88.43 68.62,87.89 68.99,87.52 68.99,82.95 v3(68.63,82.58)
  L4_IN2 w0.216: 65.3,92.74 65.3,110.73 73.76,119.18 73.76,121.67 73.96,121.88 74.31,121.88 74.52,121.67 74.52,120.91 74.72,120.71 v3(75.03,120.71)
MB_CKE1: length 50.5
  TOP w0.076: v3(69.54,83.21) U11.AP55
  TOP w0.165: CN11.110 76.72,124.65 75.58,123.51 v3(75.58,123.02)
  L4_IN2 w0.076: v3(69.54,83.21) 69.17,83.58 69.17,87.57 68.82,87.93 68.82,89.5 65.77,92.54 65.77,92.74
  L4_IN2 w0.216: 65.77,92.74 65.77,110.54 75.49,120.25 75.49,122.92 v3(75.58,123.02)
MB_CLK0: length 54.2
  TOP w0.076: v3(75.03,82.58) 75.23,82.58 U11.AP45
  TOP w0.114: CN11.137 83.47,119.83 83.57,119.93 83.57,121.01 83.83,121.26 84.17,121.26 84.31,121.4 84.31,122.01 v2(84.09,122.24)
  L4_IN2 w0.076: v3(75.03,82.58) 74.98,82.58 74.91,82.5 74.91,82.39 75,82.3 75.31,82.3 75.4,82.39 75.4,85.27 74.96,85.7 74.96,86.59 75.14,86.77 76.09,86.77 76.17,86.85 76.17,87.13 76.09,87.2 75.27,87.2 75.09,87.38 75.09,87.93 75.27,88.11 75.84,88.11 75.92,88.18 75.92,88.41 75.84,88.49 75.33,88.49 75.15,88.67 75.15,89.09 74.35,89.89 74.35,91.46 73.88,91.93 73.88,96.25 73.95,96.31 73.95,97.08 73.93,97.1 73.93,97.11
  L4_IN2 w0.114: 73.93,97.11 73.93,105.34 84.45,115.86 84.45,119.84 84.04,120.25 84.04,120.89 84.5,121.35 84.5,121.51 84.32,121.69 84.32,122 v2(84.09,122.24)
MB_CLK1: length 53.2
  TOP w0.076: U11.AP46 74.49,82.84 v3(74.11,83.21)
  TOP w0.114: v2(83.4,123.73) 83.6,123.92 83.6,124.73 83.86,125 83.86,125.76 83.72,125.9 CN11.138
  L4_IN2 w0.076: v3(74.11,83.21) 74.06,83.16 74.06,83.05 74.18,82.92 74.38,82.92 74.48,83.03 74.48,87.45 73.57,88.36 73.57,88.8 73.75,88.98 74.11,88.98 74.19,89.06 74.19,89.24 74.05,89.38 73.2,89.38 73.01,89.56 73.01,90.01 73.19,90.19 73.75,90.19 73.82,90.27 73.82,90.5 73.75,90.57 73.5,90.57 73.31,90.77 73.31,97.08 73.29,97.1 73.29,97.11
  L4_IN2 w0.114: 73.29,97.11 73.29,105.62 83.8,116.12 83.8,119.47 83.41,119.86 83.41,122.85 83.7,123.14 83.7,123.47 83.44,123.73 v2(83.4,123.73)
MB_CLK#0: length 54.2
  TOP w0.076: U11.AN45 75.28,82.19 v3(75.03,81.93)
  TOP w0.114: v2(84.75,122.24) 84.56,122.05 84.56,121.29 84.28,121.01 83.94,121.01 83.83,120.9 83.83,119.98 83.97,119.83 CN11.139
  L4_IN2 w0.076: v3(75.03,81.93) 75.03,81.98 75.18,82.13 75.38,82.13 75.57,82.32 75.57,85.34 75.14,85.78 75.14,86.52 75.22,86.59 76.17,86.59 76.35,86.77 76.35,87.2 76.17,87.38 75.34,87.38 75.27,87.46 75.27,87.85 75.34,87.93 75.91,87.93 76.09,88.11 76.09,88.48 75.91,88.66 75.41,88.66 75.33,88.74 75.33,89.16 74.53,89.96 74.53,91.53 74.06,92 74.06,96.17 74.12,96.23 74.12,97.08 74.14,97.1 74.14,97.11
  L4_IN2 w0.114: v2(84.75,122.24) 84.54,122.03 84.54,121.78 84.72,121.6 84.72,121.26 84.26,120.8 84.26,120.33 84.67,119.93 84.67,115.77 74.14,105.25 74.14,97.11
MB_CLK#1: length 53.2
  TOP w0.076: U11.AN46 74.2,82.56 v3(74.11,82.56)
  TOP w0.114: CN11.140 84.22,125.87 84.12,125.76 84.12,124.89 83.85,124.62 83.85,123.96 v2(84.09,123.73)
  L4_IN2 w0.076: 73.51,97.11 73.51,97.1 73.49,97.08 73.49,90.84 73.58,90.75 73.82,90.75 74,90.57 74,90.19 73.82,90.01 73.26,90.01 73.18,89.94 73.18,89.64 73.27,89.55 74.12,89.55 74.37,89.31 74.37,88.98 74.19,88.8 73.82,88.8 73.75,88.73 73.75,88.43 74.66,87.52 74.66,82.95 74.45,82.75 74.3,82.75 74.11,82.56 v3(74.11,82.56)
  L4_IN2 w0.114: v2(84.09,123.73) 83.91,123.56 83.91,123.05 83.62,122.76 83.62,119.95 84.02,119.56 84.02,116.04 73.51,105.53 73.51,97.11
MB_CS#0: length 50.9
  TOP w0.076: v3(77.02,90.54) 77.05,90.51 77.71,90.51 77.83,90.39 77.83,90.11 77.75,90.04 77.43,90.04 77.35,89.96 77.35,89.85 77.48,89.72 77.48,89.06 77.62,88.92 77.62,87.94 U11.BB42
  TOP w0.165: v3(89.83,123.22) 88.47,121.86 CN11.149
  L4_IN2 w0.076: v3(77.02,90.54) 77.1,90.54 77.35,90.79 77.81,90.79 78.91,91.89 78.91,96.25 79.31,96.65 79.31,97.11
  L4_IN2 w0.216: 79.31,97.11 79.31,101.53 86.17,108.38 86.17,109.37 90.36,113.56 90.36,117.95 90.89,118.48 90.89,120.41 90.32,120.98 90.32,122.41 90.79,122.89 91.24,122.89 91.36,123.01 91.36,123.7 91.04,124.01 90.65,124.01 89.85,123.22 v3(89.83,123.22)
MB_CS#1: length 52.7
  TOP w0.076: 77.84,89.55 77.84,89.17 77.95,89.05 77.95,88.31 78.01,88.25 78.01,87.76 78,87.73 77.91,87.52 77.85,87.35 77.85,86.87 U11.AY42
  TOP w0.102: v3(77.11,92.57) 77.55,92.57 78.18,91.94 78.18,89.9 77.84,89.55
  TOP w0.165: CN11.157 90.47,120.26 v3(89.86,120.87)
  L4_IN2 w0.076: v3(77.11,92.57) 77.11,92.74 77.21,92.84 78.24,92.84 78.32,92.92 78.32,93.1 78.24,93.18 77.61,93.18 77.51,93.27 77.51,93.41 77.61,93.51 78.33,93.51 78.43,93.61 78.43,93.74 78.33,93.84 77.6,93.84 77.51,93.93 77.51,94.06 77.6,94.15 78.31,94.15 78.4,94.24 78.4,94.36 78.31,94.45 77.58,94.45 77.49,94.54 77.49,94.67 77.58,94.76 78.31,94.76 78.4,94.85 78.4,94.97 78.31,95.06 77.58,95.06 77.49,95.15 77.49,95.28 77.58,95.37 78.05,95.37 78.15,95.46 78.15,95.64 78.07,95.72 77.69,95.72 77.62,95.8 77.62,95.95 77.69,96.02 78.07,96.02 78.37,96.33 78.37,97.11
  L4_IN2 w0.216: v3(89.86,120.87) 89.13,120.15 89.13,118.03 89.42,117.75 89.42,113.95 80.88,105.41 80.88,105.11 81.07,104.92 81.07,104.61 80.76,104.31 80.46,104.31 80.27,104.5 79.96,104.5 79.66,104.19 79.66,103.89 79.85,103.7 79.85,103.39 79.54,103.09 79.24,103.09 79.05,103.28 78.74,103.28 78.44,102.98 78.44,102.6 78.6,102.45 78.6,102.22 78.37,102 78.37,97.11
MB_ODT0: length 52
  TOP w0.076: U11.BA42 77.58,87.4 77.72,87.54 77.73,87.55 77.73,87.55 77.85,87.8 77.85,88.13 77.78,88.19 77.78,88.99 77.66,89.11 77.66,89.62 77.99,89.96 77.99,90.54 77.86,90.67 77.4,90.67 77.33,90.75 77.33,90.9 77.4,90.98 77.81,90.98 77.89,91.05 77.89,91.21 77.81,91.28 77.51,91.28 77.44,91.36 77.44,91.51 77.51,91.59 77.77,91.59 77.85,91.66 77.85,91.85 77.77,91.92 v3(77.11,91.92)
  TOP w0.165: v3(89.89,120.04) 89.97,119.96 CN11.155
  L4_IN2 w0.076: v3(77.11,91.92) 77.42,91.92 77.5,91.85 77.5,91.12 77.57,91.05 77.73,91.05 77.8,91.12 77.8,91.21 77.88,91.29 78.09,91.29 78.17,91.37 78.17,91.52 78.09,91.59 77.88,91.59 77.8,91.67 77.8,91.85 77.88,91.92 78.5,91.92 78.62,92.04 78.62,92.17 78.54,92.25 77.54,92.25 77.46,92.32 77.46,92.48 77.54,92.55 78.48,92.55 78.72,92.8 78.72,96.57 78.84,96.69 78.84,97.11
  L4_IN2 w0.216: 78.84,97.11 78.84,101.72 81.89,104.77 81.89,105.07 81.7,105.26 81.7,105.57 82,105.87 82.31,105.87 82.5,105.68 82.8,105.68 83.11,105.99 83.11,106.29 82.92,106.48 82.92,106.79 83.23,107.09 83.53,107.09 83.72,106.91 84.03,106.91 84.33,107.21 84.33,107.52 84.14,107.71 84.14,108.01 84.45,108.32 84.75,108.32 84.94,108.13 85.25,108.13 85.55,108.43 85.55,108.74 85.36,108.93 85.36,109.23 89.89,113.76 89.89,118.15 90.18,118.44 90.18,118.68 90.03,118.83 89.69,118.83 89.6,118.92 89.6,119.35 89.75,119.49 90.26,119.49 90.42,119.66 90.42,120.21 90.3,120.33 90.01,120.33 89.89,120.21 v3(89.89,120.04)
MB_ODT1: length 53
  TOP w0.076: v3(76.95,89.77) 77.18,89.77 77.32,89.63 77.32,88.99 77.45,88.85 77.45,88.22 77.32,88.08 77.32,88 77.31,88 77.31,87.8 77.35,87.71 77.37,87.69 77.37,87.47 77.31,87.36 77.31,87.15 77.35,87.07 77.35,86.79 77.31,86.76 77.31,86.45 77.35,86.41 77.35,86.18 U11.AW42
  TOP w0.165: v3(91.02,122.29) 91.14,122.42 91.14,123.3 90.89,123.56 90.45,123.56 90.32,123.43 90.32,121.77 90.5,121.59 91.21,121.59 91.47,121.32 CN11.161
  L4_IN2 w0.076: v3(76.95,89.77) 76.95,89.55 76.82,89.42 76.3,89.42 76.22,89.49 76.22,90.09 76.3,90.17 77.35,90.17 77.62,90.44 77.71,90.44 79.14,91.87 79.14,96.12 79.78,96.77 79.78,97.11
  L4_IN2 w0.216: v3(91.02,122.29) 90.79,122.06 90.79,121.17 91.36,120.6 91.36,118.29 90.83,117.76 90.83,113.37 86.64,109.17 86.64,108.19 79.78,101.33 79.78,97.11
ME_WE#: length 137.1
  TOP w0.102: v3(18.87,117.79) 18.47,118.18 16.39,118.18 16.05,117.84 16.05,116.84 15.06,115.86 12.31,115.86 11.99,115.54 11.99,114.9 12.17,114.71 12.62,114.71 13.25,114.09 R32.2
  L4_IN2 w0.102: v3(18.87,117.79) 19.43,118.35 20.08,118.35 20.81,119.08 28.57,119.08 30.34,120.85 34.01,120.85 35.65,122.49 45.53,122.49 48.83,125.79 69.03,125.79 69.44,125.38 74.57,125.38 75.79,126.6 93.95,126.6 95.19,125.36 111.2,125.36 114.66,121.9 114.66,120.28 113.8,119.42 113.8,112.33 111.86,110.4 111.86,107 108.96,104.1 v3(108.96,101.91)
  BOTTOM w0.102: Q30.G 109.96,100.73 108.96,101.73 v3(108.96,101.91)
MIC1_JD_SENSE#: length 37.7
  L4_IN2 w0.102: v3(158.39,42.85) 158.95,42.3 158.95,37.76 159.76,36.95 159.76,34.8 159.48,34.52 159.48,32.25 158.92,31.69 158.92,30.97 159.5,30.39 159.5,28.9 158.92,28.32 158.92,26.5 157.76,25.34 152.94,25.34 152.35,24.75 149.87,24.75 148.42,23.3 148.17,23.3 146.69,21.82 145.96,21.82 145.61,21.47 143.39,21.47 v3(143.32,21.55)
  BOTTOM w0.102: AR3.1 142.87,21.1 v3(143.32,21.55) ; v3(158.39,42.85) 157.83,43.41 AR6.2
MIC1_JD_SENSE#_0: length 2.1
  TOP w0.102: Q19.D 143.05,20.87 142.68,21.23 v3(142.68,21.55)
  BOTTOM w0.102: v3(142.68,21.55) 142.01,20.87 AR3.2
MIC1_JD_SENSE_MB#: length 17.1
  TOP w0.102: Q19.G C253.1 145.54,18.58 146.15,17.97 v3(146.15,15.96)
  BOTTOM w0.102: AR15.1 154.81,12.96 148.86,12.96 147.85,13.98 147.85,14.36 146.25,15.96 v3(146.15,15.96)
MIC1_L: length 1.8
  BOTTOM w0.102: U33.21 155.28,34.41 AC4.1
MIC1_R: length 1.4
  BOTTOM w0.102: AC6.1 156.15,34.01 U33.22
MIC1_VREF_L: length 12.5
  L4_IN2 w0.102: v3(155.41,27.4) 155.2,27.61 151.86,27.61 v3(151.17,26.93)
  BOTTOM w0.102: v3(151.17,26.93) 151.17,27.03 150.92,27.29 150.29,27.29 150.16,27.41 150.16,28.05 149.73,28.48 149.73,29.87 151.66,31.81 U33.31 ; AR13.2 v3(155.41,27.4)
MIC2_L: length 3
  BOTTOM w0.102: C521.1 155.5,37.58 155.5,36.68 155.23,36.41 U33.16
MIC2_R: length 2.4
  BOTTOM w0.102: C522.1 155.72,36.79 155.72,36.48 155.26,36.01 U33.17
MIC2_VREFO: length 1.8
  BOTTOM w0.102: U33.29 152.46,31.74 151.81,31.09 TP78.1
MIC_JD_IN#: length 33.8
  TOP w0.102: v3(155.38,24.75) 155.5,24.64 155.5,24.08 154.35,22.94 v3(154.02,22.94)
  BOTTOM w0.102: C548.2 153.37,26.6 AB15.2 154.36,25.61 154.58,25.61 155.31,24.88 155.31,24.83 v3(155.38,24.75) ; v3(154.02,22.94) 153.63,23.33 151.8,23.33 151.41,22.94 149.35,22.94 148.76,22.36 148.76,16.39 148.05,15.68 148.05,14.16 148.99,13.22 155.41,13.22 AR15.2 D21.C 158.53,12.75 AUDR1.1
MSATA_MPCIE_DET_N: length 123.5
  TOP w0.076: U11.G4 99.32,69.05 100.46,69.05 100.57,69 100.79,69 100.9,69.05 101.06,69.12 101.46,69.12 102.07,68.5 102.07,65.24 102.41,64.9
  TOP w0.102: 102.41,64.9 102.69,64.9 v2(102.69,64.91) ; v3(26.62,29.71) 26.27,29.35 R3294.2 R3386.2
  L3_IN1 w0.076: 102.41,63.69 102.16,63.43 102.16,62.39
  L3_IN1 w0.102: v3(89.25,30.49) 83.64,30.49 78,24.85 30.84,24.85 26.62,29.07 v3(26.62,29.71) ; 102.41,63.69 102.69,63.97 v2(102.69,64.91) ; 102.16,62.39 102.16,58.99 103.07,58.08 103.07,54.44 102.61,53.98 93.74,53.98 93.11,53.35 92.78,53.35 92.15,52.71 v3(92.02,52.71)
  L4_IN2 w0.102: v3(89.25,30.49) 89.35,30.49 89.53,30.67 89.53,51.24 91,52.71 v3(92.02,52.71)
MUTE: length 10.5
  BOTTOM w0.102: U33.4 150.86,38.94 149.87,39.93 149.2,39.93 148.89,40.24 148.89,42.04 147.88,43.06 147.37,43.06 R541.2 146.7,43.82 145.59,44.94 R534.1
Net_2: length 3.2
  BOTTOM w0.102: 11.71,71.57 13.25,71.57 v1(13.28,71.61)
  BOTTOM w0.508: 11.71,71.57 11.74,71.61 v1(13.28,71.61)
Net_3: length 106.4
  TOP w0.114: 89.2,69.3 88.97,69.3 v3(88.68,69)
  L4_IN2 w0.114: v3(88.68,69) 88.68,68.99 87.9,68.21 87.9,67.57 86,65.67 69.49,65.67 69.22,65.4 68.13,65.4 66.07,63.34 56.96,63.34 51.47,57.85 38.96,57.85 38.71,57.59 30.92,57.59 28.72,55.39 17.92,55.39 16.34,56.97 16.34,59.49 19.22,62.37 19.22,64.17 18.23,65.16 18.23,69.03 17.31,69.94 13.06,69.94 11.67,68.55 11.67,67.54 12.14,67.07 12.7,67.07 12.7,67.07 12.77,67.07 13.03,67.32 13.03,67.7 v2(13.15,67.83)
  BOTTOM w0.114: 12.19,66.2 12.19,66.3 12.32,66.43 12.91,66.43 13.15,66.68 v2(13.15,67.83)
Net_4: length 106.4
  TOP w0.114: 89.2,68.65 88.96,68.65 v3(88.68,68.37)
  L4_IN2 w0.114: v3(88.68,68.37) 88.36,68.37 88.12,68.12 88.12,67.49 87.92,67.28 87.92,67.12 88.09,66.95 88.09,66.77 87.95,66.62 87.77,66.62 87.59,66.8 87.43,66.8 86.09,65.46 69.58,65.46 69.31,65.18 68.22,65.18 66.16,63.13 57.05,63.13 51.56,57.64 39.05,57.64 38.8,57.38 31.01,57.38 28.8,55.17 17.83,55.17 16.12,56.88 16.12,59.58 19.01,62.46 19.01,64.08 18.01,65.07 18.01,68.94 17.22,69.73 13.15,69.73 11.88,68.46 11.88,67.63 12.23,67.28 12.61,67.28 12.77,67.45 12.77,67.55 12.52,67.81 v2(12.52,67.83)
  BOTTOM w0.114: 12.19,67.22 12.01,67.22 11.88,67.09 11.88,66.81 12.01,66.68 12.8,66.68 12.9,66.78 12.9,67.43 12.52,67.81 v2(12.52,67.83)
Net_5: length 104.7
  TOP w0.076: v2(88.28,63.97) 88.41,63.84 88.61,63.84 88.72,63.94 88.72,64.8 88.49,65.03 88.49,65.42 88.5,65.45 88.5,65.76 88.49,65.79 88.49,66.1 88.52,66.13 88.52,66.15 88.52,66.47 88.69,66.98 88.92,67.23
  L4_IN2 w0.114: v2(13.92,68.84) 14.09,69.02 14.09,69.04 14.36,69.31 16.6,69.31 17.59,68.31 17.59,61.95 15.56,59.92 15.56,56.85 17.65,54.76 28.98,54.76 31.17,56.94 39.35,56.94 39.45,57.04 51.55,57.04 57.29,62.77 67.74,62.77 70.21,65.25 86.22,65.25 87.44,64.03 87.91,64.03 88.08,63.85 88.17,63.85 v2(88.28,63.97)
  BOTTOM w0.114: v2(13.92,68.84) 13.92,68.77 14.04,68.64 14.04,68.11 13.71,67.78 13.71,66.64 12.9,65.83 12.9,64.86 12.75,64.7 12.39,64.7 12.25,64.84 12.25,65.07
Net_6: length 104.7
  TOP w0.076: 88.92,66.58 88.98,66.58 89.06,66.49 89.06,66.38 88.96,66.28 88.76,66.28 88.69,66.21 88.69,66.12 88.66,66.04 88.65,66.03 88.65,65.82 88.67,65.79 88.67,65.41 88.65,65.38 88.65,65.12 88.94,64.84 88.94,63.86 88.7,63.62 88.42,63.62 v2(88.26,63.46)
  L4_IN2 w0.114: v2(14.55,68.84) 14.8,69.09 16.51,69.09 17.38,68.22 17.38,62.04 15.34,60 15.34,56.76 17.56,54.54 29.07,54.54 31.25,56.72 39.44,56.72 39.54,56.82 51.64,56.82 57.38,62.56 67.83,62.56 70.3,65.03 86.13,65.03 87.35,63.81 87.82,63.81 87.99,63.64 88.08,63.64 v2(88.26,63.46)
  BOTTOM w0.114: 12.25,64.05 12.14,64.17 12.14,64.37 12.21,64.45 12.85,64.45 13.15,64.75 13.15,65.73 13.97,66.54 13.97,67.68 14.3,68.01 14.3,68.57 14.55,68.82 v2(14.55,68.84)
NFC_CLK_REQ: length 123.7
  TOP w0.076: v2(96.7,87.74) 96.7,87.73 96.7,86.95 U11.BA8
  TOP w0.102: v3(111.71,23.55) 112.32,22.94 119.06,22.94 120.02,21.98 R741.1
  L3_IN1 w0.076: v2(96.7,87.74) 98.17,87.74 99.65,89.22 103.45,89.22 103.93,88.74 103.93,87.55 103.77,87.39 103.77,84.74 106.62,81.88
  L3_IN1 w0.102: 106.62,81.88 107.69,80.82 107.69,78.2 106.86,77.37 104.52,77.37 104.19,77.7 103.17,77.7 102.68,77.22 102,77.22 101.18,76.4 101.18,75.13 101.53,74.79 104.18,74.79 104.61,75.21 106.95,75.21 107.27,74.9 107.27,73.73 105.59,72.06 103.26,72.06 102.17,70.97 102.17,70.45 103.7,68.91 103.7,66.27 104.31,65.67 104.84,65.67 105.14,65.37 105.14,65 102.97,62.83 102.97,59.35 103.96,58.36 103.96,54.18 102.88,53.1 95.55,53.1 94.84,52.38 v3(94.84,52.36)
  L4_IN2 w0.102: v3(111.71,23.55) 112.16,23.99 112.16,28.58 106.09,34.64 106.09,49.59 105.22,50.47 105.22,50.47 103.86,51.83 97.86,51.83 97.1,52.59 95.07,52.59 v3(94.84,52.36)
NFC_DWL_REQ: length 88.5
  TOP w0.076: v3(97.96,74.76) 97.93,74.76 U11.U7
  TOP w0.102: R745.1 119.54,21.33 119.54,22.17 118.98,22.73 111.9,22.73 v3(111.72,22.91)
  L3_IN1 w0.076: 102.41,69.63 102.4,69.63 101.5,70.53 101.5,72.83 101.29,73.03 101.29,73.05 99.56,74.78 97.97,74.78 v3(97.96,74.76)
  L3_IN1 w0.102: v3(94.28,52.33) 94.31,52.36 94.31,52.59 95.07,53.35 102.84,53.35 103.76,54.26 103.76,58.25 102.77,59.24 102.77,63.08 103.7,64.02 103.7,65.41 102.84,66.28 102.84,69.2 102.41,69.63
  L4_IN2 w0.102: v3(111.72,22.91) 112.42,23.62 112.42,28.69 106.3,34.82 106.3,49.68 105.3,50.67 105.3,50.67 103.89,52.08 98.18,52.08 97.44,52.82 94.54,52.82 94.31,52.59 94.31,52.36 v3(94.28,52.33)
NFC_EN: length 127.3
  TOP w0.076: U11.AY8 96.68,86.53 97.05,86.9 97.05,88.03 v2(96.84,88.24)
  TOP w0.102: R742.1 119.93,23.23 112.8,23.23 v3(111.72,24.31)
  L3_IN1 w0.076: 106.62,82.17 103.92,84.87 103.92,87.33 104.21,87.62 104.21,88.68 103.48,89.41 99.58,89.41 98.41,88.24 v2(96.84,88.24)
  L3_IN1 w0.102: 106.62,82.17 107.89,80.9 107.89,78.12 106.94,77.16 104.48,77.16 104.11,77.53 103.34,77.53 102.86,77.04 102.07,77.04 101.36,76.33 101.36,75.2 101.57,74.99 103.95,74.99 104.4,75.44 107.01,75.44 107.47,74.98 107.47,73.52 105.58,71.63 103.12,71.63 102.43,70.95 102.43,70.47 102.64,70.26 102.67,70.26 106.12,66.81 106.12,65.32 103.43,62.63 103.43,59.47 104.37,58.53 104.37,54.01 102.75,52.39 101.06,52.39 100.62,51.95 95.73,51.95 95.61,51.83 94.43,51.83 v3(93.67,51.06)
  L4_IN2 w0.102: v3(111.72,24.31) 111.72,28.7 105.89,34.53 105.89,49.51 105.14,50.26 105.13,50.26 103.77,51.62 97.78,51.62 97.63,51.78 94.73,51.78 94.53,51.57 94.28,51.57 93.77,51.06 v3(93.67,51.06)
NFC_I2C1_CLK: length 89.2
  TOP w0.076: v3(96.64,74.78) U11.U9
  L3_IN1 w0.076: v3(96.64,74.78) 97.28,74.14 99.65,74.14 101.15,72.64 101.15,70.26
  L3_IN1 w0.102: 101.15,70.26 102.2,69.21 102.2,69.2 102.44,68.97 102.44,66.11 103.29,65.25 103.29,64.18 102.36,63.25 102.36,59.07 103.32,58.11 103.32,54.41 102.7,53.78 93.83,53.78 93.15,53.11 92.92,53.11 92.45,52.64 v3(92.45,52.04)
  L4_IN2 w0.102: v3(92.45,52.04) 92.45,52.77 92.78,53.1 93.29,53.1 93.42,53.23 103.38,53.23 106.7,49.91 106.7,35.05 113.05,28.7 v3(113.05,21.54)
  BOTTOM w0.102: v3(113.05,21.54) 115.78,21.54 R738.1
NFC_I2C1_CLK_R: length 7.4
  TOP w0.102: U1634.B1 123.09,20.45 v3(122.7,20.84)
  BOTTOM w0.102: v3(122.7,20.84) 122.58,20.96 R111.1 119.07,20.53 117.65,20.53 R738.2
NFC_I2C1_DATA: length 87.4
  TOP w0.076: v3(97.29,74.78) U11.U8
  L3_IN1 w0.076: v3(97.29,74.78) 97.29,74.75 97.66,74.38 99.73,74.38 101.35,72.76 101.35,70.35
  L3_IN1 w0.102: v3(92.9,52.55) 93.02,52.67 93.02,52.7 93.22,52.9 93.24,52.9 93.91,53.58 102.78,53.58 103.53,54.32 103.53,58.19 102.56,59.16 102.56,63.16 103.5,64.1 103.5,65.33 102.64,66.19 102.64,69.05 101.35,70.35
  L4_IN2 w0.102: v3(92.9,52.55) 93.19,52.84 93.32,52.84 93.51,53.03 103.3,53.03 106.5,49.83 106.5,34.96 112.63,28.84 112.63,21.39 v3(113.07,20.94)
  BOTTOM w0.102: v3(113.07,20.94) 115.23,20.94 R739.1
NFC_I2C1_DATA_R: length 7.8
  TOP w0.102: U1634.C1 123.42,19.95 123.29,19.82 122.64,19.82 122.13,20.33 v3(122.05,20.33)
  BOTTOM w0.102: v3(122.05,20.33) 121.23,20.33 120.72,19.82 R107.1 119,19.31 117.73,19.31 R739.2
NFC_INT#: length 125.1
  TOP w0.076: v2(104.56,88.5) 104.5,88.55 103.92,88.55 103.58,88.89 99.57,88.89 99.04,88.36 97.95,88.36 97.55,87.96 97.55,87.68 97.3,87.42 U11.BA7
  TOP w0.102: v3(111.72,22.21) 112.04,22.53 118.89,22.53 119.34,22.09 119.34,20.39 R740.1
  L3_IN1 w0.076: 106.62,82.55 104.08,85.1 104.08,87.27 104.56,87.75 v2(104.56,88.5)
  L3_IN1 w0.102: 106.62,82.55 108.1,81.08 108.1,78.03 107.02,76.96 104.43,76.96 104.04,77.35 103.41,77.35 102.93,76.86 102.14,76.86 101.77,76.49 101.77,75.96 102.52,75.22 103.7,75.22 104.14,75.65 107.13,75.65 107.67,75.11 107.67,73.44 105.55,71.32 104.38,71.32 103.73,70.66 103.73,69.49 106.33,66.89 106.33,64.62 106.04,64.33 106.04,64.1 103.63,61.69 103.63,60.16 103.63,60.16 103.63,59.62 104.57,58.68 104.57,53.93 102.83,52.19 101.15,52.19 100.66,51.7 95.77,51.7 95.69,51.62 94.96,51.62 94.53,51.19 v3(94.43,51.19)
  L4_IN2 w0.102: v3(111.72,22.21) 111.29,22.64 111.29,28.85 105.69,34.45 105.69,49.43 105.05,50.06 105.05,50.06 103.69,51.42 97.69,51.42 97.54,51.57 94.81,51.57 v3(94.43,51.19)
NFC_RST: length 120.7
  TOP w0.076: v2(105.07,88.49) 105.07,88.62 104.85,88.84 103.86,88.84 103.63,89.07 99.52,89.07 98.99,88.54 97.58,88.54 97.3,88.27 U11.BB7
  L3_IN1 w0.076: v2(105.07,88.49) 105.07,88.05 104.26,87.23 104.26,85.23 106.62,82.87
  L3_IN1 w0.102: v3(95.07,51.19) 95.3,51.42 95.78,51.42 95.85,51.5 100.78,51.5 101.27,51.99 102.92,51.99 104.77,53.84 104.77,58.76 103.83,59.7 103.83,60.07 103.83,60.07 103.83,61.61 106.24,64.02 106.24,64.25 106.55,64.56 106.55,66.96 103.93,69.58 103.93,70.52 104.52,71.11 105.64,71.11 107.88,73.35 107.88,75.2 107.21,75.87 103.93,75.87 103.48,75.42 102.56,75.42 101.95,76.04 101.95,76.42 102.22,76.68 103,76.68 103.49,77.17 103.96,77.17 104.38,76.75 107.13,76.75 108.3,77.93 108.3,81.19 106.62,82.87
  L4_IN2 w0.102: v3(113.07,20.31) 111.08,22.3 111.08,28.76 105.48,34.36 105.48,49.34 103.61,51.22 97.61,51.22 97.46,51.37 95.25,51.37 v3(95.07,51.19)
  BOTTOM w0.102: v3(113.07,20.31) 113.58,20.31 R743.1
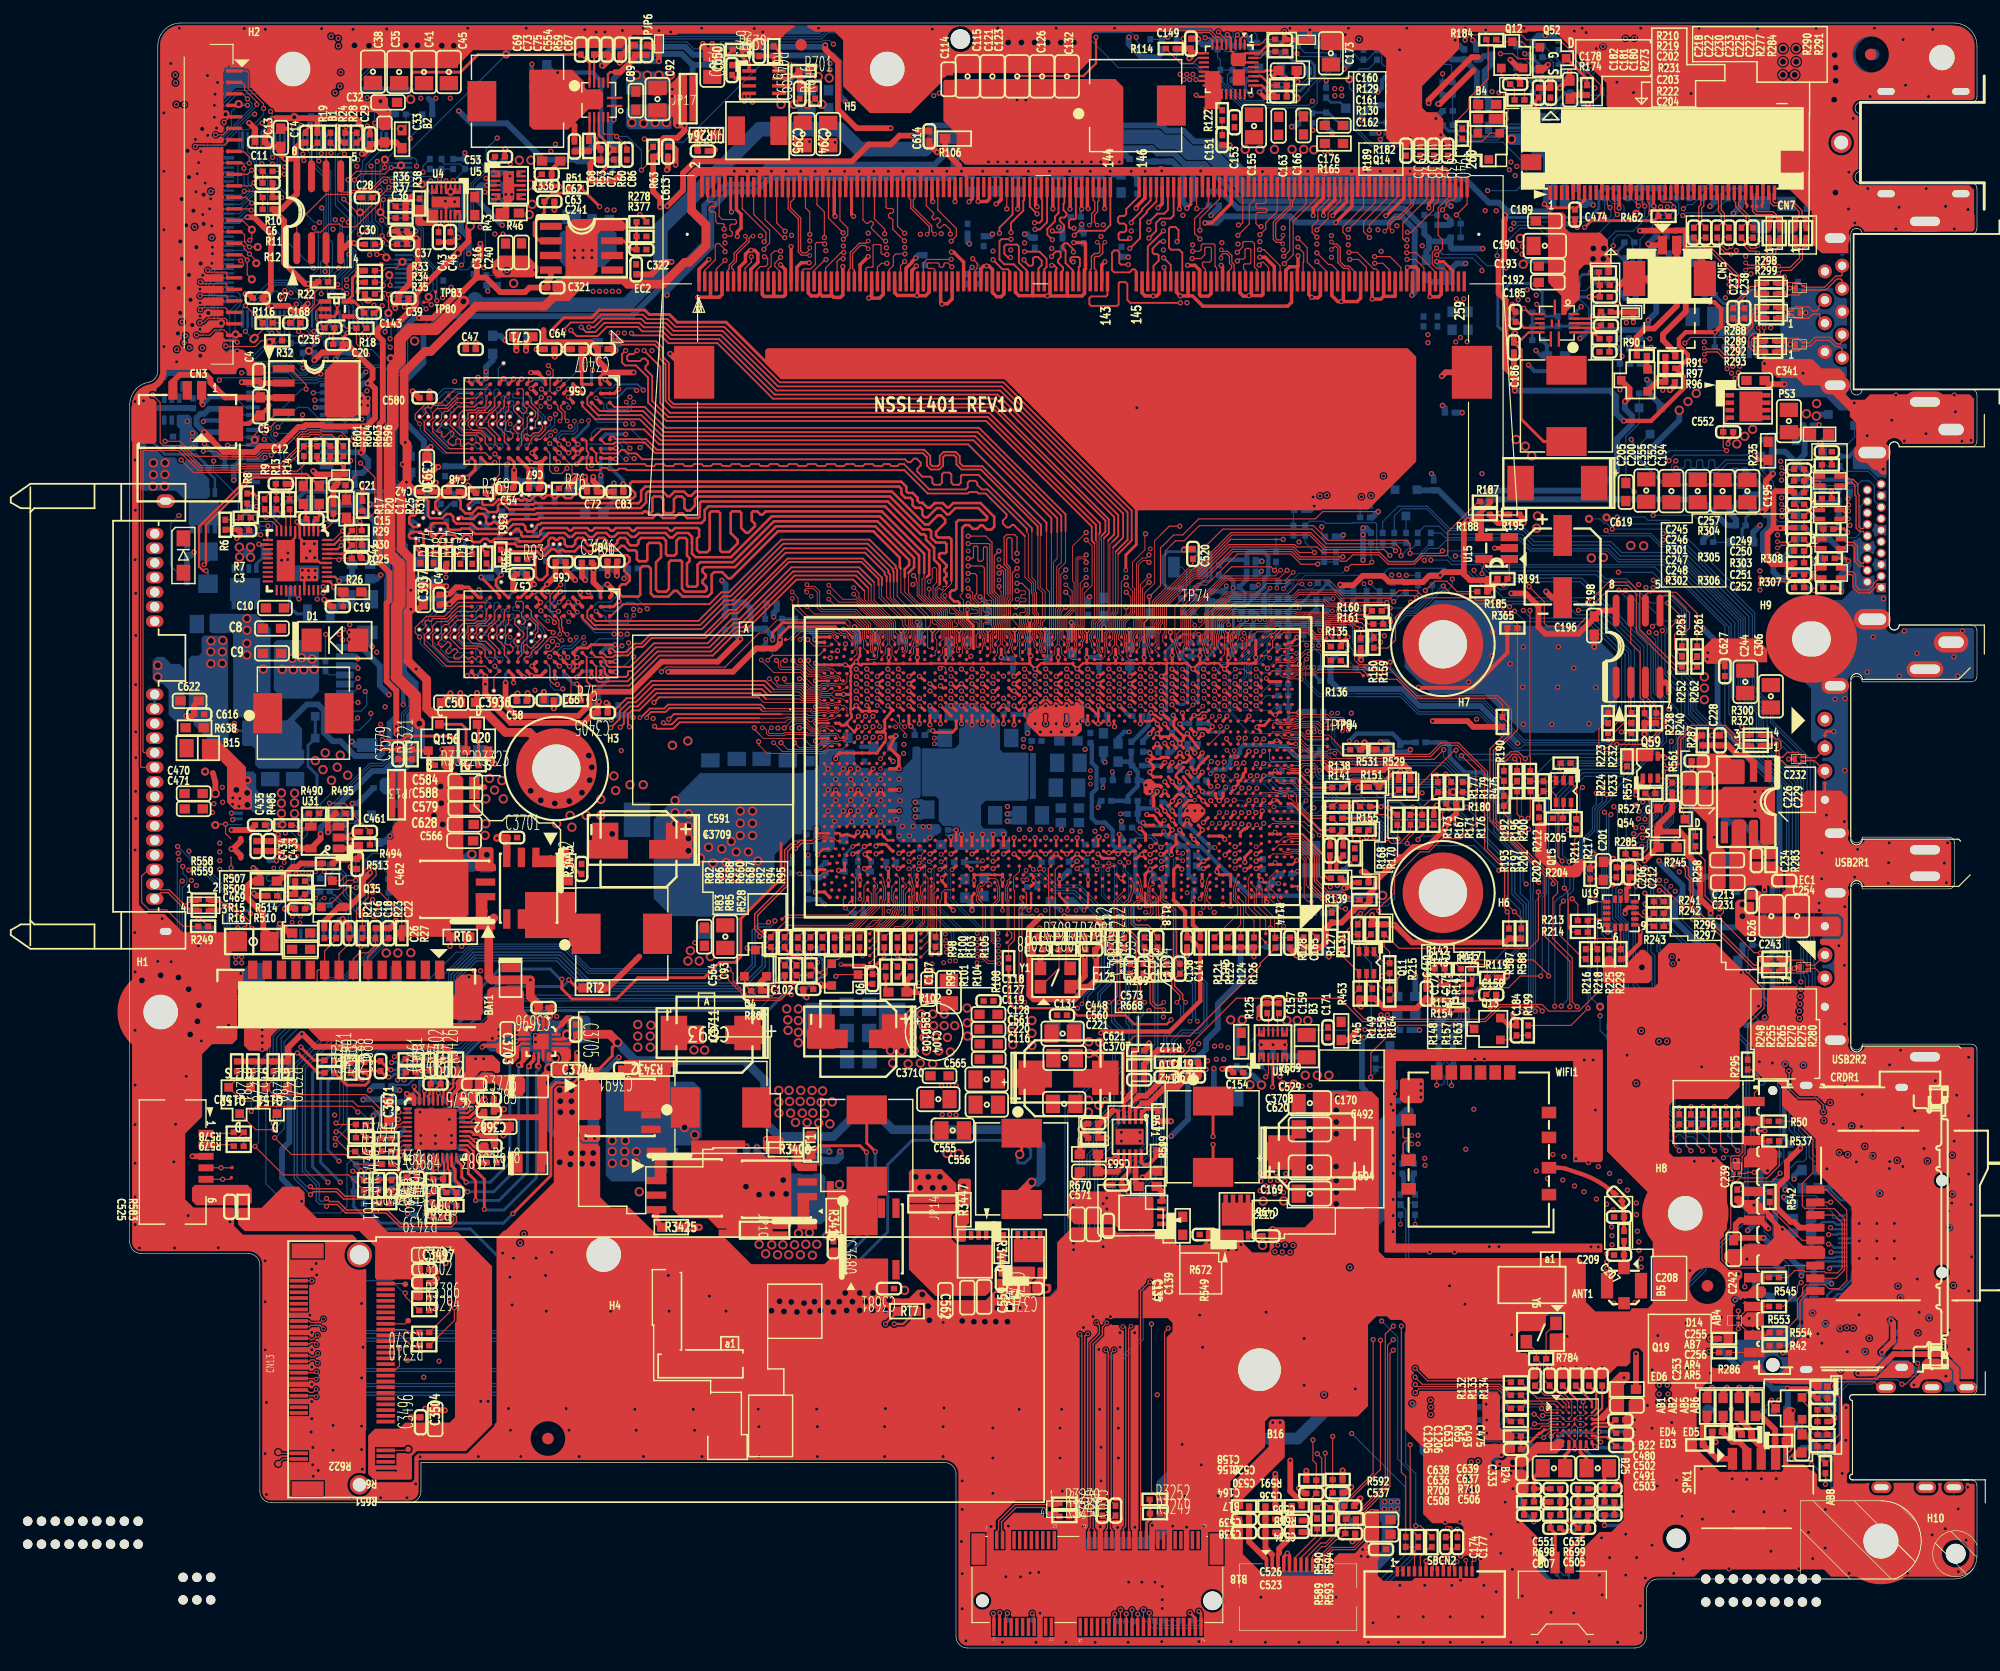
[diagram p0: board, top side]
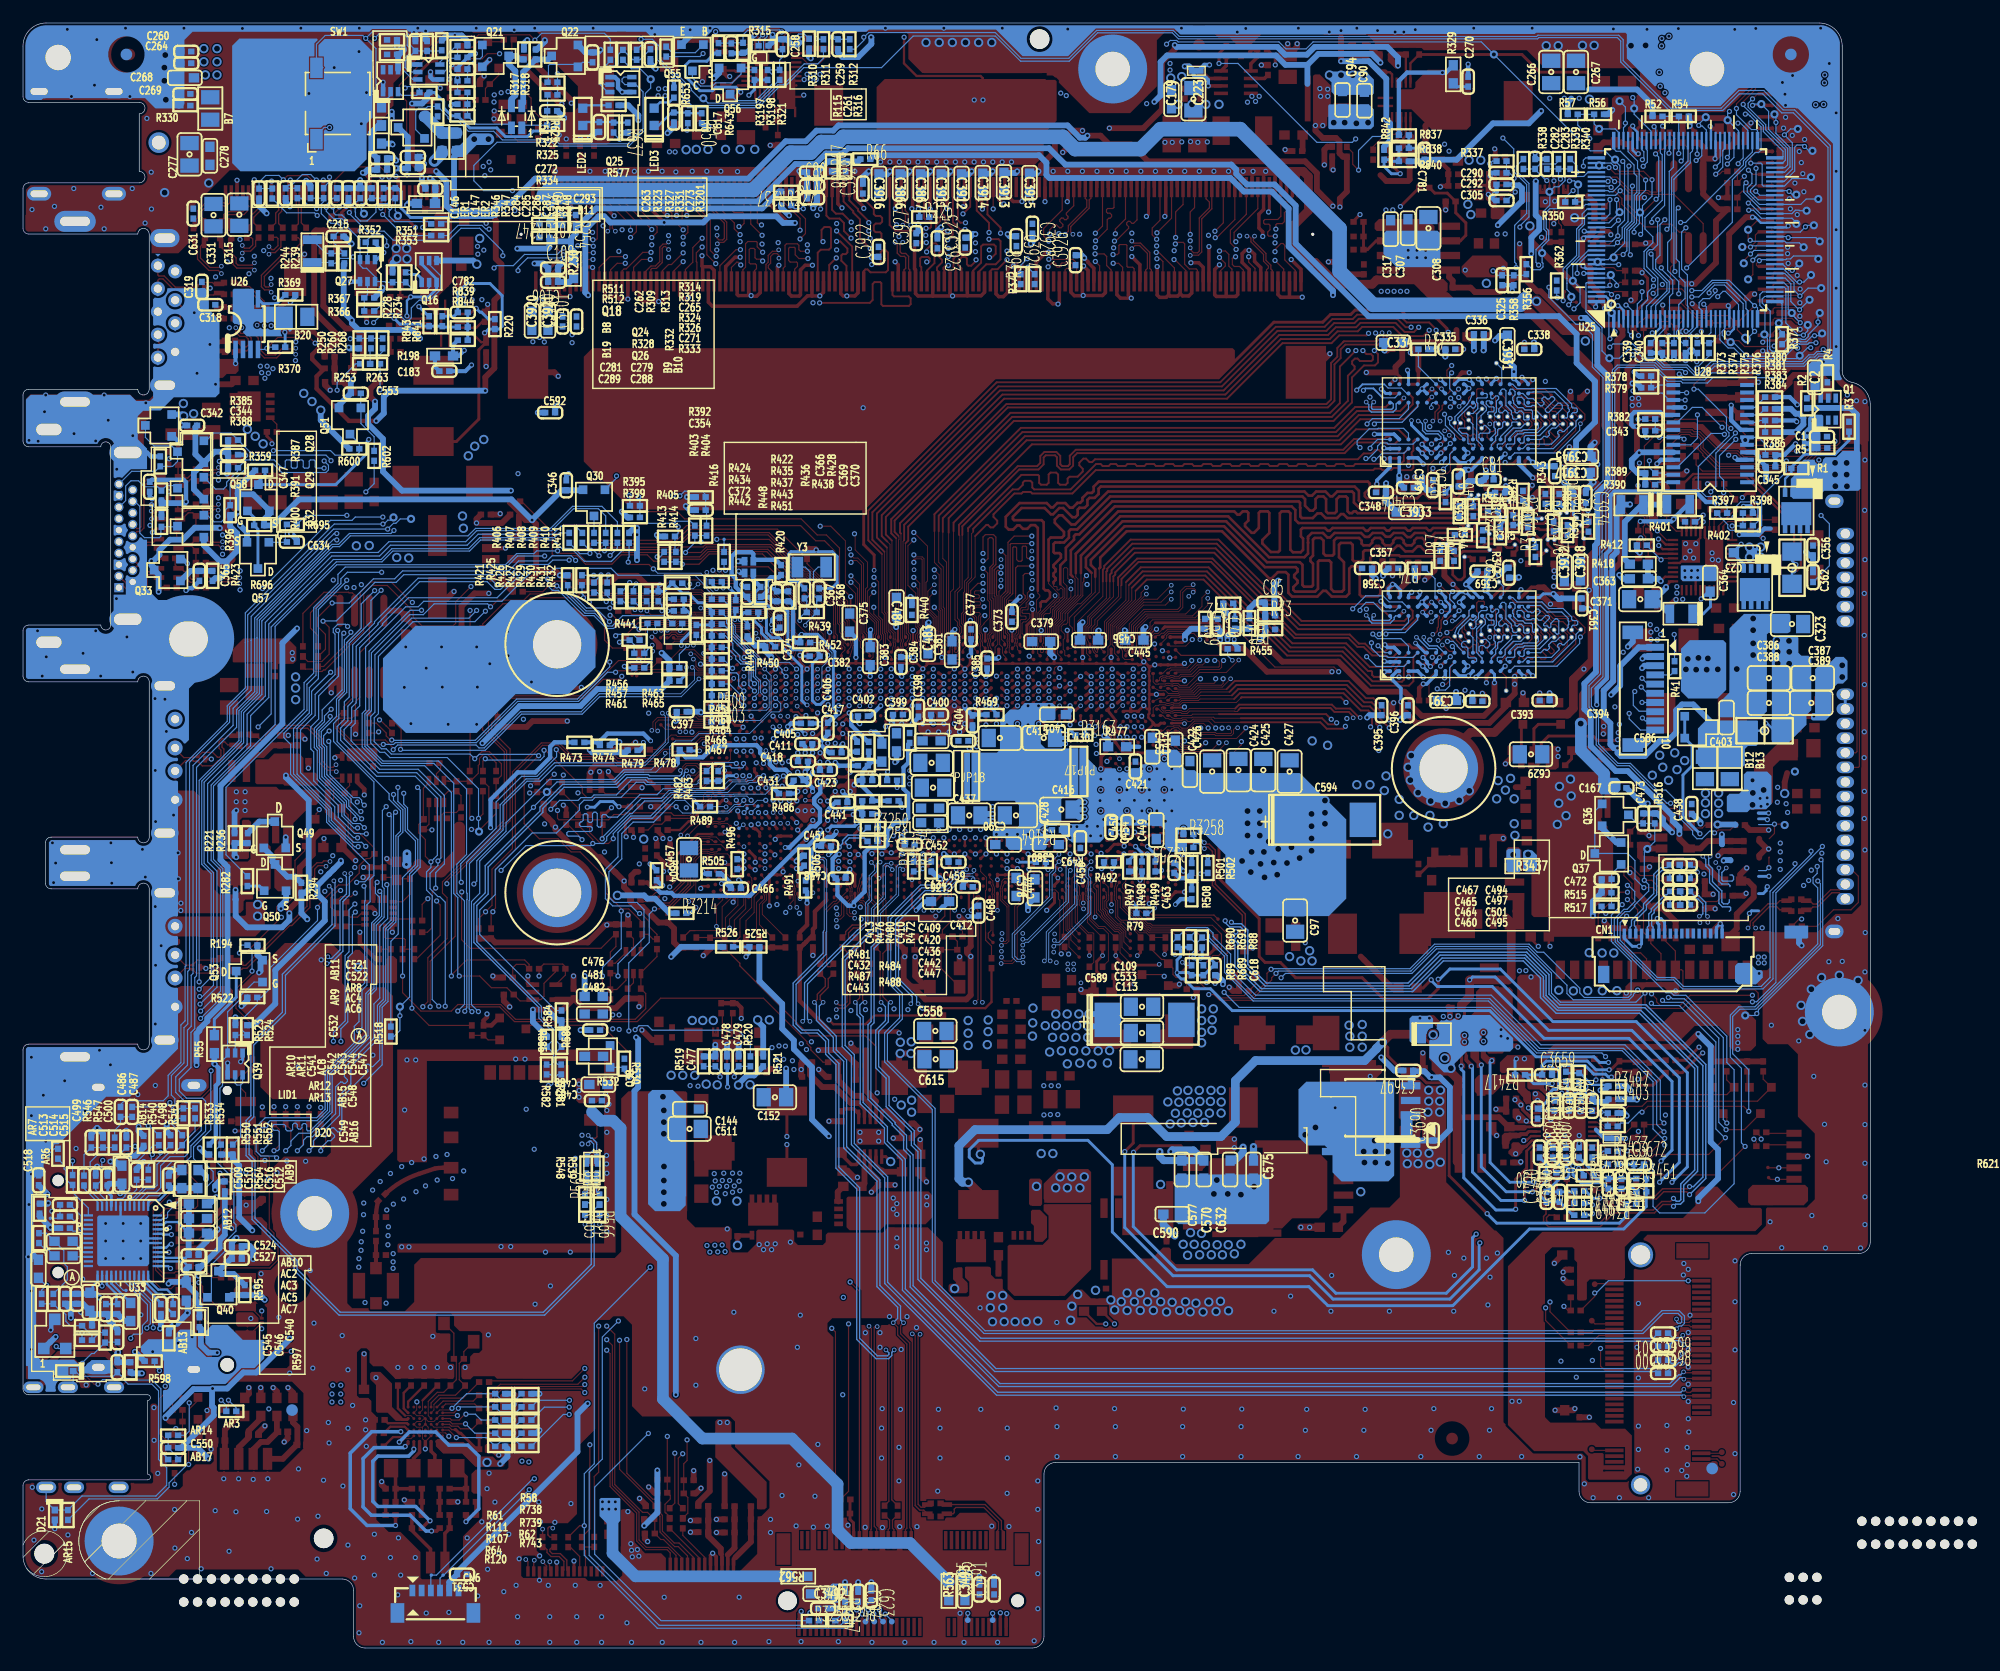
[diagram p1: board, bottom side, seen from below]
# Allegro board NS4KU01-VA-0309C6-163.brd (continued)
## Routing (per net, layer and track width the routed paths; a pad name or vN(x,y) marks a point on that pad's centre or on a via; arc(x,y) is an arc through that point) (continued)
NFC_VBAT: length 22.8
  TOP w0.254: 127.78,20.05 127.59,19.86 127.16,19.86 U1634.C7 ; U1634.G2 U1634.G1 124.06,17.95 123.52,17.41
  TOP w0.508: v3(129.87,23.5) 129.36,23 129.36,22.59 129.33,22.57 B22.2 C480.1
  L4_IN2 w0.508: v3(129.87,23.5) 121.58,23.5 120.21,22.14 v4(120.21,16.14)
  BOTTOM w0.508: R120.2 118.44,17.33 118.44,16.65 v3(119.07,16.01)
OZ8127_HDR11: length 2.4
  TOP w0.635: R3406.2 58.06,43.07 58.06,42.02 58.29,41.79 Q43.4
OZ8283_HDR1: length 33.1
  TOP w0.203: v3(29.1,48.18) 28.66,48.18 28.38,47.9 U109.31
  L4_IN2 w0.762: v3(55.27,43.51) 55.27,43.04 54.7,42.47 52.73,42.47 46.63,48.56 41.23,48.56 39.14,50.66 37.98,50.66 36.46,49.14 30.18,49.14 29.23,48.18 v3(29.1,48.18) 29.1,47.8 v3(28.91,47.61)
  vias: v3(55.27,44.25)
OZ8283_HDR2: length 26.1
  TOP w0.203: v3(30.12,44.13) 29.87,44.13 29.49,44.51 U109.24
  TOP w0.635: R3425.2 v3(48.73,36.59) v3(49.49,36.59)
  L4_IN2 w0.762: v3(30.12,44.13) 31.76,44.13 32.22,43.68 33.93,43.68 36.66,40.94 41.42,40.94 41.55,41.07 45.17,41.07 48.73,37.52 v3(48.73,36.59) v3(49.49,36.59)
OZ8283_HDR2R: length 1.7
  TOP w0.508: Q60.4 45.78,37.08 R3425.1
OZ8283_HDR3: length 27.4
  TOP w0.254: v3(35.81,54.97) 35.93,54.84 U110.2
  L3_IN1 w0.762: v4(29.74,69.01) 29.72,69.03 29.72,72.3 30.18,72.76 32.34,72.76 35.81,69.29 v3(35.81,54.97)
  BOTTOM w0.762: v4(29.74,69.01) 29.74,68.27 R3437.2
OZ8283_HDR3R: length 1
  BOTTOM w0.762: R3437.1 v4(31.03,68.97)
OZ8283_HDR4: length 44.8
  TOP w0.254: v4(37.99,53.31) 37.99,53.34 37.97,53.37 37.95,53.37 37.53,52.94 U110.15
  TOP w0.508: R3447.2 v4(72.46,40.14)
  L3_IN1 w1.016: v4(72.46,40.14) 72.46,39.03 71.4,37.96 53.87,37.96 38.46,53.37 38.02,53.37 37.99,53.34 v4(37.99,53.31)
OZ8283_LDR1: length 46.5
  TOP w0.203: v3(30.37,47.22) 30.25,47.1 30.25,46.85 29.51,46.11 U109.28
  TOP w0.508: v3(30.37,47.22) 30.37,47.29 30.78,47.7 C3773.1
  L4_IN2 w0.762: v4(67.33,31.1) 67.33,31.48 60.66,38.15 51.33,38.15 43.68,45.8 39.14,45.8 38.85,45.52 36.85,45.52 34.69,47.68 v3(30.88,47.68)
OZ8283_LDR2: length 25.6
  TOP w0.203: 29.76,45.71 U109.27
  TOP w0.254: v3(29.9,45.82) 29.87,45.82 29.76,45.71
  TOP w0.508: C3783.1 30.78,46.3 v3(30.57,46.09)
  TOP w0.635: v3(39.65,44.31) 39.65,44.8 Q62.4
  L4_IN2 w0.762: v3(30.57,46.09) 30.88,45.77 31.84,45.77 31.9,45.71 34.38,45.71 35.9,44.18 39.52,44.18 v3(39.65,44.31) v3(40.41,44.31)
  BOTTOM w0.508: v3(39.65,44.31) 39.47,44.13 C3690.1 37.47,44.13 36.53,45.07 36.53,48.76 37.4,49.62 v3(38.12,49.62) 38.15,49.64 38.25,49.64 38.76,50.15 39.66,50.15 C3697.1 39.72,49.76 39.95,49.53 Q63.4
OZ8283_LDR3: length 21.2
  TOP w0.254: U110.5 33.79,53.34 v3(33.61,53.52)
  TOP w0.635: v3(31.9,70.41) 31.96,70.47 C3701.1 32.76,70.44 Q46.4
  L3_IN1 w0.762: v3(31.9,70.41) 31.96,70.41 33.61,68.76 33.61,53.52 v3(33.61,53.52)
OZ8283_LDR4: length 55.7
  TOP w0.254: U110.12 36.46,51.41 36.86,51.41 v4(36.98,51.3)
  TOP w0.381: Q42.4 79.13,32.14 78.69,31.7 78.69,31.3 C3713.1
  TOP w0.508: v4(79.57,31.25) 79.45,31.12 78.86,31.12 C3713.1
  L3_IN1 w1.016: v4(36.98,51.3) 37.89,51.3 51.14,38.05 51.14,35.67 53.93,32.88 78.07,32.88 79.57,31.38 v4(79.57,31.25)
OZ8283_LX1: length 42.9
  TOP w0.203: U109.32 27.98,48.05 30.39,50.47
  L4_IN2 w0.762: v3(30.06,51.23) v3(30.76,51.23) 31.49,51.97 35.87,51.97 36.22,52.31 38.4,52.31 38.97,52.88 39.65,52.88 41.89,50.63 50.59,50.63 60.92,40.31 v4(61.68,40.31)
  BOTTOM w0.254: R3417.2 30.87,51.12 v3(30.76,51.23)
OZ8283_LX2: length 35.8
  TOP w0.203: U109.23 29.43,44.11 29.87,43.68
  TOP w0.254: R3431.1 19.78,49.45 v3(20.21,49.45) ; 29.87,43.68 29.93,43.61 30.77,43.61 C3683.2
  TOP w0.508: C3683.2 30.83,42.99 v3(30.82,42.98) ; R3432.1 46.58,49.12 46.63,49.07
  L4_IN2 w0.254: v3(20.21,49.45) 21.29,49.45 24.23,46.52 24.23,43.16 24.41,42.98 v3(30.82,42.98)
  L4_IN2 w0.762: v3(30.82,42.98) 34.57,39.23 43.84,39.23 v4(44.28,39.67)
  vias: v3(46.5,46.98) v4(41.93,44.12) v4(41.93,43.17) v4(41.93,42.15) v4(43.01,43.17) v4(43.01,42.21) v4(43.07,44.12) v4(44.03,43.17) v4(43.96,42.21) v4(48.22,45.26) v4(49.11,44.63)
OZ8283_LX3: length 53
  TOP w0.254: U110.3 35.54,54.6 35.26,54.87 35.26,55.41 C3696.2
  TOP w0.762: C3696.2 35.53,55.92 34.82,56.63 v3(34.82,58.09) 31.45,58.09 31.2,58.34 31.2,63.04 31.64,63.49
  L4_IN2 w0.254: v3(18.31,40.5) 20.53,38.28 23.9,38.28 v3(24.15,38.53)
  BOTTOM w0.254: v3(24.15,38.53) 24.28,38.66 R3444.2 ; v3(18.31,40.5) 16.6,42.21 16.6,49.58 20.72,53.71 27.96,53.71 32.6,58.34 34.57,58.34 v3(34.82,58.09)
OZ8283_LX4: length 89.8
  TOP w0.254: U110.14 38.22,52.54 38.82,53.14 38.82,53.37 ; v4(42.4,52.67) 41.93,52.2 41.93,51.49 40.09,49.64 39.07,49.64 38.58,49.15 37.05,49.15 36.6,48.69 36.6,41.07 v3(33.3,37.77)
  TOP w0.762: v4(42.4,52.67) 41.7,53.37 39.14,53.37 ; L26.2 77.51,39.63 v4(78.38,40.5)
  BOTTOM w0.254: v3(33.3,37.77) 32.47,36.94 21.8,36.94 21.22,37.53 R3449.2
  BOTTOM w0.762: v4(78.38,40.5) 78.89,40.5 79.21,40.82 79.21,43.68 77.81,45.07 66.31,45.07 65.26,46.13 62.8,46.13 61.15,44.48 56.43,44.48 55.18,45.73 55.18,49.33 53.42,51.08 43.94,51.08 42.92,52.1 42.92,52.15 v4(42.4,52.67)
PA: length 3.5
  TOP w0.254: U1.12 11.25,95.95 v3(11.22,95.98)
  BOTTOM w0.254: v3(11.22,95.98) 11.86,95.34 C23.1 11.86,95.13 11,94.27 Q34.4
PANEL_3.3V_ON: length 165.8
  BOTTOM w0.102: U25.124 24.66,118.72 24.71,118.67 24.71,116.21 23.31,114.81 23.31,112.79 v1(22.68,112.15) 21.79,112.15 21.03,112.91 20.5,112.91 19.54,111.96 18.59,111.96 17.99,111.36 15.98,111.36 15.29,110.68 14.62,110.68 13.63,111.66 5.84,111.66 5.25,112.25 4.83,112.25 4.55,112.53 3.86,112.53 3.68,112.71 3.68,130.49 6.68,133.49 7.69,133.49 9.34,135.14 11.38,135.14 12.82,133.69 17.47,133.69 21.69,137.91 21.69,139.73 21.99,140.03 28.81,140.03 28.92,139.92 60.13,139.92 60.66,140.45 67.14,140.45 69.62,137.98 73.84,137.98 76.03,140.17 83.18,140.17 85.93,137.42 92.69,137.42 94.39,135.72 94.85,135.72 96.64,133.94 102.77,133.94 103.2,134.36 103.2,136.05 103.83,136.68 103.98,136.68 105.43,138.13 105.43,139.18 105.78,139.53 106.66,139.53 R331.1
PANEL_DETECT: length 144.5
  TOP w0.102: v3(131.11,125.4) 130.94,125.58 CN7.16
  L4_IN2 w0.102: v3(11.5,132.59) 12.5,132.59 13.9,133.99 18.05,133.99 18.05,133.99 20.7,133.99 20.7,133.99 21.73,133.99 23.22,135.49 23.22,139.36 23.77,139.92 28.56,139.92 29.23,139.25 42.08,139.25 42.89,138.44 61.34,138.44 62.38,139.48 68.94,139.48 70.3,138.12 72.98,138.12 73.34,138.48 88.28,138.48 88.41,138.62 100.76,138.62 101.11,138.26 101.81,138.26 102.59,139.05 109.15,139.05 109.86,139.75 113.4,139.75 113.73,139.43 121.51,139.43 122.48,138.47 124.53,138.47 126.56,136.43 128.32,136.43 130.52,134.23 130.52,127.75 131.11,127.16 v3(131.11,125.4)
  BOTTOM w0.102: U25.67 10.65,131.96 11.28,132.59 v3(11.5,132.59) ; v1(130.91,124.72) 131.14,124.95 131.14,125.38 v3(131.11,125.4) 130.45,126.07 C287.1 R349.2
PANEL_DETECT 2: length 175.4
  TOP w0.102: v3(131.67,125.38) 131.44,125.61 CN7.17
  L4_IN2 w0.102: v3(21.86,120.29) 21.22,120.29 20.72,120.78 16.74,120.78 v3(15.96,120) ; v3(131.67,125.38) 131.67,125.44 131.72,125.48 131.72,134.94 129.99,136.66 126.62,136.66 124.61,138.67 122.56,138.67 121.6,139.63 117.57,139.63 116.96,140.24 110.06,140.24 109.07,139.25 100.32,139.25 100.1,139.02 88.92,139.02 88.47,139.48 83.78,139.48 83.22,138.92 73.2,138.92 72.81,138.53 70.48,138.53 69.12,139.89 62.21,139.89 61.17,138.84 43.3,138.84 42.49,139.66 29.48,139.66 28.81,140.33 23.61,140.33 22.81,139.53 22.81,135.66 21.56,134.4 20.53,134.4 20.53,134.4 18.22,134.4 13.73,134.4 12.53,133.2 11.04,133.2 v3(10.86,133.38)
  BOTTOM w0.102: v1(127.96,124.54) 127.96,124.75 128.19,124.98 R348.2 128.4,126.07 128.88,125.59 129.6,125.59 129.87,125.32 129.87,124.85 130.63,124.09 131.23,124.09 131.65,124.51 131.65,124.85 131.67,124.88 v3(131.67,125.38) 131.72,125.43 131.72,125.58 C286.1 ; v3(21.86,120.29) 21.9,120.32 U25.120 ; v3(10.86,133.38) 10.61,133.38 10.46,133.22 10.45,133.22 9.49,132.27 9.49,130.25 9.71,130.04 10,130.04 10.82,129.22 10.82,128.85 11.99,127.68 11.99,123.97 v3(15.96,120)
PANEL_VCC: length 94.2
  TOP w0.102: v3(132.18,124.82) 132.05,124.95 132.05,125.6 131.94,125.71 CN7.18
  L3_IN1 w0.102: v3(118.84,121.06) 118.79,121.06 118,120.27 118,119.13 117.02,118.15 117.02,105.84 121.7,101.16 122.86,101.16 125.01,99.02 125.01,94.28 129.88,89.42 129.88,82.8 131.24,81.44 131.24,78.99 128.34,76.1 v3(128.34,74.22)
  BOTTOM w0.102: v3(128.34,74.22) 128.34,73.7 127.53,72.89 127.53,70.94 127.93,70.54 127.93,62.08 128.57,61.45 R518.1 ; v3(118.84,121.06) 118.84,121.45 120.85,123.45 122.47,123.45 123.51,122.41 128.37,122.41 129.16,123.2 130.65,123.2 132.18,124.72 v3(132.18,124.82)
PCH_BL_PWM: length 1.4
  BOTTOM w0.102: R263.1 130.38,112.93 R260.1
PCH_PCIE_WAKE#: length 138.3
  TOP w0.076: v2(93.26,81.9) 92.9,81.54 U11.AM15
  TOP w0.102: v3(108.51,84.49) 108.51,84.44 108.71,84.23 110.13,84.23 111.77,82.59 118.7,82.59 119.3,82 R190.2 119.82,80.44 119.82,79.78 118.21,78.17 118.21,71.92 122.98,67.14 122.98,61.89 125.16,59.71 v3(125.16,55.76) ; R132.2 110.9,14.91 110.51,15.29 v3(110.51,27.99)
  L3_IN1 w0.102: v3(125.16,55.76) 125.16,55.94 125.49,56.27 127.87,56.27 132.91,51.22 132.91,42.75 134.86,40.8 136.69,40.8 137.99,39.5 137.99,33.7 133.01,28.71 111.23,28.71 v3(110.51,27.99)
  L4_IN2 w0.076: v2(93.26,81.9) 93.75,81.9 94.26,81.4 98.15,81.4 98.9,82.15 100.02,82.15 101.54,83.68 102.51,83.68 102.92,84.08 106.4,84.08 106.4,84.09 106.6,84.09
  L4_IN2 w0.102: 106.6,84.09 108.11,84.09 v3(108.51,84.49)
PCH_PWROK: length 114
  L3_IN1 w0.102: v3(103.45,100.19) 102.76,100.87 93.54,100.87 78.86,115.56 54.76,115.56 50.22,120.1 49.08,120.1 48.26,120.91 45.49,120.91 44.88,120.31 36.19,120.31 35.78,120.71 30,120.71 29.16,119.87 28.67,119.87 27.78,120.76 23.83,120.76 22.21,119.13 18.99,119.13 v3(18.84,118.98)
  BOTTOM w0.102: v3(18.84,118.98) 18.84,119.14 19.66,119.96 19.66,121.43 19.63,121.45 18.9,122.19 18.9,122.71 19.58,123.39 19.58,124.38 18.08,125.88 18.08,129.84 18.25,130.01 U25.86 ; v3(103.45,100.19) 103.04,100.59 101.52,100.59 101.21,100.29 R392.1 C354.2 101.14,98.86 R404.1
PCH_PWROK_R: length 21.7
  TOP w0.076: U11.BA20 89.77,87.52 89.77,88.06 89.91,88.2 89.91,89.03 89.94,89.06 89.94,90.64 92.43,93.14 93,93.14 93.45,93.58
  TOP w0.102: 93.45,93.58 95.61,95.74 101.15,95.74 101.64,95.26 v3(102.97,95.26)
  BOTTOM w0.102: R404.2 R403.1 102.15,96.12 102.97,95.31 v3(102.97,95.26)
PCH_SMB_CLK: length 114.2
  TOP w0.102: Q11.1 108.14,60.47 109.07,59.54 R215.2 109.5,60.51 109.01,61 R163.2 109.09,62.06 110.31,60.84 121.67,60.84 122.42,61.59 122.42,65.73 v3(122.41,65.74) ; CN11.253 114.47,119.72 114.22,119.98 113.57,119.98 113.2,120.35 113.2,121.35 v3(113.57,121.72) ; v3(124.68,66.08) 124.98,65.78 124.98,65.02 125.02,64.98 125.02,62.62 125.39,62.24 R214.1
  L4_IN2 w0.102: v3(116.83,93.71) 116.83,94.24 114.93,96.15 114.93,104.07 117.67,106.81 117.67,118.6 119.07,120 v3(119.6,120) ; v3(124.68,66.08) 124.3,66.08 123.99,65.77 122.44,65.77 v3(122.41,65.74)
  BOTTOM w0.102: v3(113.57,121.72) 114.12,121.18 116.96,121.18 117.93,120.2 119.4,120.2 v3(119.6,120) ; v3(124.68,66.08) 124.68,67.42 123.92,68.17 123.92,74.13 126.2,76.41 129.55,76.41 132.02,78.88 132.02,80.05 131.67,80.4 131.67,81.52 131.28,81.92 131.28,86.97 129.28,88.97 129.28,89.08 127.04,91.32 119.34,91.32 117.61,93.05 117.32,93.05 116.83,93.54 v3(116.83,93.71)
PCH_SMB_CLK_R: length 33.8
  TOP w0.076: v3(97.9,73.71) U11.R7
  TOP w0.102: v3(108.83,58.43) 109.08,58.68 R215.1 R164.1 108.94,57.26 108.14,58.06 Q11.6
  BOTTOM w0.076: 104.08,73.46 103.84,73.71 103.01,73.71 102.07,72.77 99.3,72.77 98.72,73.34 98.27,73.34 97.9,73.71 v3(97.9,73.71)
  BOTTOM w0.102: v3(108.83,58.43) 108.83,59.5 106.57,61.76 106.57,64.22 107.18,64.83 109.17,64.83 109.62,65.29 109.62,67.5 108.5,68.62 108.5,70.82 107.51,71.81 105.73,71.81 104.08,73.46
PCH_SMB_DATA: length 113.7
  TOP w0.102: v3(113.58,121.15) 114.09,121.65 114.09,122.46 113.71,122.84 113.71,125.22 114.72,126.23 CN11.254 ; R453.2 105.45,60.12 106.84,58.73 Q11.4 106.84,57.35 R149.2 106.42,56.91 106.42,55.58 107.34,54.67 117.74,54.67 119.03,55.95 122.74,55.95 123.32,55.38 125.95,55.38 127.55,56.99 v3(127.55,58.43) R218.1
  L3_IN1 w0.102: v3(117.52,119.77) 117.52,119.15 116.82,118.44 116.82,105.76 121.61,100.96 122.78,100.96 124.81,98.93 124.81,94.18 129.68,89.32 129.68,82.71 131.02,81.37 131.02,79.15 127.96,76.1 v3(127.96,74.83)
  BOTTOM w0.102: v3(127.55,58.43) 127.55,66.99 126.44,68.1 126.44,70.19 127.32,71.08 127.32,72.97 127.96,73.61 v3(127.96,74.83) ; v3(113.58,121.15) 113.86,120.87 116.69,120.87 117.52,120.04 v3(117.52,119.77)
PCH_SMB_DATA_R: length 29.2
  TOP w0.076: v3(97.26,73.71) U11.R8
  TOP w0.102: v3(106.95,63.86) 106.81,63.86 106.12,63.17 106.12,62.73 105.45,62.06 R453.1 105.79,61.63 106.22,62.06 R148.1 106.84,61.95 Q11.3
  BOTTOM w0.076: 104.31,73.69 103.97,74.04 99.6,74.04 99.58,74.06 98.72,74.06 98.7,74.08 97.63,74.08 v3(97.26,73.71)
  BOTTOM w0.102: 104.31,73.69 105.86,72.14 107.61,72.14 108.83,70.92 108.83,68.8 109.93,67.7 109.93,65.16 109.29,64.53 107.69,64.53 107.03,63.86 v3(106.95,63.86)
PCH_SPI0_IO2: length 4.8
  TOP w0.076: R136.2 103.45,86.8 102.2,86.8 101.52,86.11 101.39,86.11 101.13,85.85 100.48,85.85 U11.AW2
PCH_SPI_CLK: length 9.6
  TOP w0.102: R261.2 136.21,89.97 134.38,91.8 132.26,91.8 132.2,91.75 131.92,91.75 131.72,91.55 U20.6
PCH_SPI_CLK_E: length 163.4
  TOP w0.102: v3(121.61,92.3) 122.93,90.97 122.93,89.1 123.18,88.86 125.85,88.86 126.63,89.64 126.63,90.15 128.88,92.39 130.21,92.39 130.93,91.67 130.93,88.4 134.29,85.04 134.43,85.04 134.56,84.91 135.21,84.91 135.42,85.12 135.99,85.12 R262.2
  L4_IN2 w0.102: v3(24.93,128.85) 24.93,127.08 25.67,126.35 26.05,126.35 26.21,126.5 28.95,126.5 29.59,125.86 31.57,125.86 32.66,126.96 35.84,126.96 36.17,126.62 44.72,126.62 45.95,127.84 47.72,127.84 47.9,128.02 68.63,128.02 69.66,129.06 70.59,129.06 71.14,129.6 72.78,129.6 73.55,130.37 88.37,130.37 89.14,129.6 94.11,129.6 96.11,127.6 114.97,127.6 115.18,127.39 116.8,127.39 117.84,126.34 118.44,126.34 121.66,123.12 121.66,120.06 118.59,116.99 118.59,101.68 121.61,98.66 v3(121.61,92.3)
  BOTTOM w0.102: v3(24.93,128.85) 24.94,128.85 24.94,129.37 24.73,129.57 U25.97
PCH_SPI_CLK_R: length 49.3
  TOP w0.076: v2(102.28,85.99) 102.26,85.99 102.05,85.78 102.05,85.39 101.8,85.13 100.82,85.13 100.53,85.42 100.09,85.42 U11.AV2
  TOP w0.102: R262.1 135.78,85.78 134.58,85.78 133.94,86.42 133.94,88.76 v3(134.47,89.29)
  L4_IN2 w0.076: 105.76,85.83 103.63,85.83 103.47,85.99 v2(102.28,85.99)
  L4_IN2 w0.102: v3(113.07,94.6) 113.07,94.39 110.82,92.13 110.82,90.81 110.26,90.25 110.26,87.63 109.2,86.57 107.15,86.57 106.41,85.83 105.76,85.83
  BOTTOM w0.102: v3(113.07,94.6) 114.5,94.6 114.88,94.22 117.34,94.22 118.23,93.33 127.45,93.33 128.12,92.66 129.95,92.66 133.3,89.31 134.44,89.31 v3(134.47,89.29)
PCH_SPI_CS#0: length 3
  TOP w0.102: U20.1 129.18,82.61 128.47,81.91 R223.2
PCH_SPI_CS#0_E: length 161.4
  TOP w0.102: R224.1 128.47,79.68 128.98,80.18 128.98,80.18 129.51,80.7 v3(129.56,80.7) ; v3(21.48,121.17) 22.04,121.17 v1(22.3,120.91)
  L3_IN1 w0.102: v3(21.48,121.17) 22.21,121.17 22.82,121.78 26.92,121.78 29.47,124.33 33.31,124.33 34.17,123.48 37.74,123.48 40.29,126.03 49.88,126.03 51.42,124.48 52.98,124.48 53.62,125.13 69.02,125.13 69.44,124.71 75.27,124.71 76.62,126.07 110.58,126.07 114.17,122.47 114.17,112.35 114.73,111.78 114.73,106.4 121.19,99.94 122.36,99.94 123.79,98.51 123.79,93 128.86,87.93 128.86,81.4 v3(129.56,80.7)
  BOTTOM w0.102: U25.96 22.3,130.37 22.08,130.15 21.72,130.15 20.53,128.95 20.53,128.23 20.29,127.99 20.29,126.57 20.52,126.35 20.52,123.98 21.15,123.34 21.15,121.5 v3(21.48,121.17)
PCH_SPI_CS#0_R: length 33.6
  TOP w0.076: U11.AU3 99.91,84.7 100.17,84.43 100.46,84.43 100.87,84.26 v2(101.8,84.26)
  TOP w0.102: v3(127.73,78.14) 127.68,78.19 127.68,79.92 128.19,80.42 R223.1
  BOTTOM w0.076: v2(101.8,84.26) 103.34,82.72 106.62,82.72
  BOTTOM w0.102: v3(127.73,78.14) 127.65,78.06 120.37,78.06 117.22,81.2 111.94,81.2 110.43,82.72 106.62,82.72
PCH_SPI_HOLD#: length 51.2
  TOP w0.076: U11.AU4 99.32,84.96 101.87,84.96 102.18,85.28 v2(102.38,85.28)
  TOP w0.102: v3(128.37,78.11) 128.37,78.27 129.05,78.95 132.06,78.95 133.14,80.04 133.14,80.7 132.98,80.86 131.97,80.86 131.65,81.18 R238.1 131.65,82.28 131.26,82.67 131.26,86.55 130.45,87.36 U20.7
  BOTTOM w0.076: 106.62,82.98 103.38,82.98 102.18,84.18 102.18,85.07 v2(102.38,85.28)
  BOTTOM w0.102: v3(128.37,78.11) 128.37,78.13 127.98,78.52 121.16,78.52 120.91,78.27 120.45,78.27 117.31,81.41 112.03,81.41 110.46,82.98 106.62,82.98
PCH_SPI_SI: length 7.5
  TOP w0.102: R251.2 134.89,88.02 135.56,88.69 135.56,90.02 134.08,91.5 133.32,91.5 132.99,91.17 U20.5
PCH_SPI_SI_E: length 161.8
  TOP w0.102: R252.2 134.42,85.34 131.24,88.53 131.24,91.54 131.24,91.79 130.33,92.7 128.55,92.7 126.77,90.92 v3(126.7,90.92) ; v3(19.53,127.65) 20.06,128.18 22.17,128.18 v3(22.71,128.72) 23.38,128.72 v1(23.57,128.91)
  L3_IN1 w0.102: v3(126.7,90.92) 124.2,93.42 124.2,98.68 122.53,100.35 121.36,100.35 115.14,106.57 115.14,111.95 114.58,112.52 114.58,122.64 110.74,126.47 75.66,126.47 74.33,125.14 69.58,125.14 69.19,125.53 50.95,125.53 50.01,126.47 40.12,126.47 37.53,123.88 34.33,123.88 33.48,124.74 29.3,124.74 26.75,122.18 22.48,122.18 22.12,121.83 21.81,121.83 v3(20.52,123.11)
  BOTTOM w0.102: U25.99 v3(22.71,128.72) ; v3(19.53,127.65) 19.53,126.76 20.07,126.22 20.07,123.85 20.52,123.4 v3(20.52,123.11)
PCH_SPI_SI_R: length 48.6
  TOP w0.076: U11.AV3 99.67,85.68 101.19,85.68 101.46,85.95 101.63,85.95 102.13,86.44 v2(102.51,86.44)
  TOP w0.102: v3(133.67,90.86) 134.96,89.58 134.96,88.84 134.26,88.14 134.26,86.84 R252.1
  L4_IN2 w0.076: 106.6,86.54 106.06,86 103.94,86 103.5,86.44 v2(102.51,86.44)
  L4_IN2 w0.102: 106.6,86.54 106.93,86.88 109.07,86.88 109.95,87.76 109.95,90.46 110.44,90.94 110.44,92.18 112.49,94.23 112.49,94.55 v3(112.52,94.57)
  BOTTOM w0.102: v3(133.67,90.86) 132.19,90.86 130.09,92.97 128.24,92.97 127.55,93.66 118.33,93.66 117.47,94.52 115.01,94.52 114.55,94.98 112.9,94.98 112.52,94.6 v3(112.52,94.57)
PCH_SPI_SO: length 2.7
  TOP w0.102: R232.2 130.45,81.35 U20.2
PCH_SPI_SO_E: length 162.7
  TOP w0.102: v3(129.64,79.66) 129.74,79.56 R233.1 ; v3(18.97,127.67) 19.7,128.41 21.81,128.41 v3(22.14,128.74) 22.14,129.39 v1(22.18,129.42)
  L3_IN1 w0.102: v3(19.96,122.92) 21.33,121.55 22.14,121.55 22.56,121.98 26.83,121.98 29.39,124.54 33.4,124.54 34.25,123.68 37.61,123.68 40.19,126.26 49.94,126.26 50.86,125.33 69.11,125.33 69.52,124.91 75.18,124.91 76.54,126.27 110.66,126.27 114.37,122.56 114.37,112.43 114.93,111.87 114.93,106.49 121.27,100.15 122.44,100.15 124,98.59 124,93.09 129.07,88.02 129.07,81.85 129.94,80.97 129.94,79.97 v3(129.64,79.66)
  BOTTOM w0.102: v3(19.96,122.92) 19.8,123.09 19.8,125.41 18.97,126.24 v3(18.97,127.67) ; U25.98 22.53,129.12 v3(22.14,128.74)
PCH_SPI_SO_R: length 35.8
  TOP w0.076: v2(101.39,86.49) 100.65,86.49 100.5,86.33 100.11,86.33 U11.AW3
  TOP w0.102: v3(128.49,78.95) 128.62,78.95 128.98,79.31 128.98,79.56 129.84,80.42 R233.2
  L4_IN2 w0.076: 106.6,85.51 103.67,85.51 103.55,85.63 102.13,85.63 101.37,86.39 101.37,86.51 v2(101.39,86.49)
  L4_IN2 w0.102: v3(109.55,85.73) 109.41,85.88 109.34,85.88 109.1,86.12 107.9,86.12 107.29,85.51 106.6,85.51
  BOTTOM w0.102: v3(109.55,85.73) 109.55,85.32 112.36,82.52 117.64,82.52 121.23,78.93 128.47,78.93 v3(128.49,78.95)
PCH_SPI_WP: length 36.5
  TOP w0.076: R136.1 105.81,85.3 106.6,85.3
  TOP w0.102: U20.3 131.72,82.79 132.67,81.84 R240.2 132.91,81.29 133.34,80.86 133.34,79.95 131.96,78.57 v3(129.23,78.57) ; 106.6,85.3 107.32,85.3 107.64,84.97 108.91,84.97 v3(109.04,84.85)
  BOTTOM w0.102: v3(129.23,78.57) 128.33,78.57 128.18,78.72 121.14,78.72 117.55,82.31 112.27,82.31 109.74,84.85 v3(109.04,84.85)
PCH_TCK: length 7.8
  TOP w0.076: R104.1 67.48,59.62 67.48,62.11 67.56,62.19 67.94,62.19 68.91,63.15 68.91,64.55 68.91,64.55 68.91,65.04 68.83,65.12 68.83,65.38 68.89,65.5 68.89,65.72 U11.B56
PCH_TDI: length 6.2
  TOP w0.076: R100.2 66.73,61.78 68.04,63.09 68.04,64.11 68.03,64.13 68.03,64.9 68.18,65.05 68.18,65.42 68.16,65.45 68.16,65.76 68.18,65.79 68.18,66.04 68.17,66.06 68.16,66.08 68.12,66.24 68.04,66.52 68.04,66.63 67.96,66.9 U11.D59
PCH_TDO: length 4
  TOP w0.076: R103.2 67.86,61.86 69.1,63.09 U11.A56
PCH_TMS: length 8.6
  TOP w0.076: R101.2 66.21,59.75 66.21,62.11 66.67,62.57 67.1,62.57 67.88,63.35 67.88,64.04 67.86,64.06 67.86,64.97 68.01,65.12 68.01,65.38 67.95,65.5 67.95,65.65 68.01,65.84 68.01,66.01 67.93,66.26 U11.C59
PCH_VRALERT#: length 18.5
  TOP w0.076: v3(94.23,81.94) 94.64,81.54 U11.AM11
  L4_IN2 w0.076: v3(94.23,81.94) 94.76,82.48 94.76,85.43 95.1,85.76 95.86,85.76 96.41,86.32 96.88,86.32 97.22,86.66 99.93,86.66 100.63,87.36 101.64,87.36 102.01,87.73 102.97,87.73 103.02,87.67 104.81,87.67 v2(105.81,86.67)
  BOTTOM w0.102: v2(105.81,86.67) 105.86,86.62 105.86,85.91 R461.2
PCH_XATL24_OUT: length 4.6
  TOP w0.102: R3095.2 83.05,61.76 C133.1 R109.1 81.38,60.71 81.38,59.45 Y1.3
PCH_XTAL24_IN: length 6.6
  TOP w0.102: R3087.2 79.34,61.45 C125.1 R109.2 80.77,59.11 79.15,57.5 Y1.1
PCIE_CLKREQ4#: length 132.7
  TOP w0.076: v2(96.08,84.46) 96.41,84.79 U11.AU8
  TOP w0.102: v3(88.66,31.82) 87.85,31.02 CN14.53
  L3_IN1 w0.076: v2(96.08,84.46) 97.2,85.58 99.54,85.58 101.48,83.64 103.13,83.64 104.47,82.31 v2(104.47,81.29)
  L3_IN1 w0.102: v3(121.53,55.34) 120.73,54.54 113.59,54.54 112.17,53.12 111.38,53.12 110.46,52.21 109.21,52.21 106.84,49.84 106.84,32.99 105.67,31.82 v3(88.66,31.82)
  BOTTOM w0.076: 106.62,76.72 106.5,76.72 104.47,78.75 v2(104.47,81.29) ; R500.2 99.46,81.8 99.21,81.54 95.94,81.54 95.69,81.79 95.69,84.07 v2(96.08,84.46)
  BOTTOM w0.102: 106.62,76.72 114.25,76.72 115.59,75.37 116.74,75.37 118.82,73.29 118.82,71.13 121.74,68.21 121.74,65.02 121.77,64.99 121.77,55.58 v3(121.53,55.34)
PCIE_N0: length 5.5
  TOP w0.076: U11.D42 76.53,66.97 76.25,66.69 76.25,66.43 76.2,66.33 76.1,66.04 76.1,65.73 76.16,65.54 76.1,65.42 76.1,65.05 76.25,64.9 76.25,62.24
  TOP w0.102: TP16.1 76.25,61.99 76.25,62.24
PCIE_P0: length 5.6
  TOP w0.076: 76.57,62.24 76.41,62.39 76.41,64.97 76.26,65.12 76.26,65.38 76.32,65.5 76.32,65.65 76.26,65.84 76.26,66.01 76.35,66.26 U11.C42
  TOP w0.102: 76.57,62.24 76.65,62.15 76.65,61.76 TP17.1
PCIE_RCOMPN: length 1.2
  TOP w0.254: v3(97.89,68.41) U11.F5
  BOTTOM w0.254: R496.2 98.07,68.59 v3(97.89,68.41)
PCIE_RCOMPP: length 1.1
  TOP w0.254: v3(97.89,67.77) U11.E5
  BOTTOM w0.254: R496.1 97.94,67.72 v3(97.89,67.77)
PCIE_RXN6: length 65.3
  TOP w0.076: v2(91.51,69.1) 91.3,69.01 91.02,69.01 90.96,69.14 U11.G18
  TOP w0.114: v2(85.54,25.92) 85.29,25.66 85.29,12.76 C695.2
  BOTTOM w0.076: v2(91.51,69.1) 91.51,68.93 91.34,68.76 90.93,68.76 90.69,68.52 90.69,62.29 90.75,62.24
  BOTTOM w0.114: v2(85.54,25.92) 85.29,25.66 85.29,25.54 85.42,25.41 86.3,25.41 87.83,26.94 87.83,40.02 89.64,41.83 89.64,50.84 90.53,51.74 90.53,52.86 91.41,53.73 92.82,53.73 93.35,54.27 93.35,57.71 90.75,60.32 90.75,62.24
PCIE_RXN10: length 79.9
  TOP w0.076: U11.F25 v2(86.81,68.31)
  TOP w0.114: C174.2 114.73,9.64 114.92,9.83 114.92,10.42 114.8,10.55 114.63,10.55 114.52,10.44 114.52,10.44 v2(114.5,10.42)
  L4_IN2 w0.114: v2(114.5,10.42) 114.52,10.44 114.52,10.44 114.88,10.8 114.88,11.37 114.26,12 114.26,28.98 107.77,35.46 107.77,48.65 108.33,49.21 108.33,49.82 102.85,55.29 93.13,55.29 92.78,54.95 v2(92.78,54.49)
  BOTTOM w0.076: 88.03,62.42 88.03,62.42 88.01,62.42 88.01,62.42 87.95,62.47 87.93,62.47 87.33,63.07 87.33,63.16 87.33,64.77 87,65.1 87,67.16 86.55,67.61 86.55,68.04 v2(86.81,68.31)
  BOTTOM w0.114: 88.03,62.42 88.48,61.98 88.66,61.79 92.62,57.83 92.62,54.66 v2(92.78,54.49)
PCIE_RXN11: length 115.7
  TOP w0.076: U11.E28 v2(85.09,68.23)
  TOP w0.114: v2(16.2,21.85) 16.12,21.93 CN13.29
  BOTTOM w0.076: v2(85.09,68.23) 85.57,68.23 85.8,68.01 85.8,65.31 86.81,64.3 86.81,62.46 86.85,62.42
  BOTTOM w0.114: v2(16.2,21.85) 16.33,21.98 75.94,21.98 85.65,31.7 85.65,40.88 88.54,43.77 88.54,51.49 89.35,52.29 89.35,59.93 86.85,62.42
PCIE_RXP6: length 65.3
  TOP w0.076: U11.F18 v2(91.51,68.46)
  TOP w0.114: v2(84.83,25.92) 85.04,25.71 85.04,12.89 C696.2
  BOTTOM w0.076: v2(91.51,68.46) 91.51,68.47 91.44,68.55 91.02,68.55 90.91,68.43 90.91,62.41 90.99,62.34 90.99,62.27 91,62.25 91,62.24
  BOTTOM w0.114: v2(84.83,25.92) 85.04,25.71 85.04,25.43 85.31,25.16 86.4,25.16 88.08,26.84 88.08,39.92 89.89,41.72 89.89,50.73 90.79,51.63 90.79,52.75 91.51,53.48 92.92,53.48 93.61,54.16 93.61,57.82 91,60.42 91,62.24
PCIE_RXP10: length 80
  TOP w0.076: U11.E25 v2(86.05,68.34)
  TOP w0.114: v2(115.39,10.34) C177.2
  L4_IN2 w0.114: v2(92.15,54.49) 92.15,54.62 93.04,55.51 102.94,55.51 108.55,49.91 108.55,49.12 107.98,48.56 107.98,35.55 114.47,29.06 114.47,12.09 115.1,11.46 115.1,10.62 v2(115.39,10.34)
  BOTTOM w0.076: 87.85,62.24 87.12,62.98 87.12,63.25 87.12,64.68 86.79,65.01 86.79,67.07 86.33,67.52 86.33,68.24 86.23,68.34 v2(86.05,68.34)
  BOTTOM w0.114: v2(92.15,54.49) 92.16,54.49 92.36,54.7 92.36,57.73 88.48,61.61 88.3,61.8 87.85,62.24
PCIE_RXP11: length 115.7
  TOP w0.076: v2(85,67.67) 85,67.82 85.07,67.89 85.23,67.89 85.34,68 U11.E27
  TOP w0.114: v2(16.2,22.5) 15.92,22.22 15.63,22.22 15.42,22.43 CN13.31
  BOTTOM w0.076: 86.67,62.24 86.6,62.31 86.6,64.21 85.58,65.22 85.58,67.92 85.48,68.02 85.36,68.02 85.23,67.89 85.07,67.89 85,67.82 v2(85,67.67)
  BOTTOM w0.114: 86.67,62.24 89.09,59.82 89.09,52.4 88.29,51.6 88.29,43.87 85.4,40.98 85.4,31.8 75.83,22.24 16.46,22.24 16.2,22.5 v2(16.2,22.5)
PCIE_TXN6: length 53.5
  TOP w0.114: v2(91.77,56.14) 91.77,56.15 91.51,56.4 91.51,56.84 90.81,57.54 90.81,58.19 C694.1 ; CN14.37 83.85,10.29 83.73,10.42 83.73,26.43 84.53,27.23 84.53,27.9 v2(84.91,28.28)
  BOTTOM w0.114: v2(84.91,28.28) 84.53,28.67 84.53,29.62 86.32,31.42 86.32,40.6 89.22,43.49 89.22,51.01 90.12,51.91 90.12,53.1 91.59,54.57 91.59,55.96 v2(91.77,56.14)
PCIE_TXN10: length 75.8
  TOP w0.114: v2(116.85,7.7) 116.66,7.51 SBCN2.14 ; v2(89.86,56.14) 89.69,55.97 89.67,55.97 89.59,55.89 89.23,55.89 88.93,56.19 88.93,60.52 C141.1
  L4_IN2 w0.114: v2(116.85,7.7) 116.66,7.88 116.66,11.04 115.11,12.59 115.11,29.33 108.62,35.82 108.62,48.3 109.27,48.94 109.27,50.08 103.21,56.14 102.68,56.14 92.66,56.14 91.89,55.38 90.8,55.38 90.21,55.97 90.03,55.97 v2(89.86,56.14)
PCIE_TXN10_C: length 7.4
  TOP w0.076: U11.D23 87.68,67.05 87.79,66.9 87.86,66.63 87.86,66.52 87.94,66.24 87.99,66.08 88,66.04 88,65.79 87.97,65.7 87.97,65.51 88,65.41 88,65.04 87.77,64.81 87.63,64.81 87.23,64.41 87.23,63.06 87.23,63.06 87.43,62.87 87.61,62.87
  TOP w0.114: 87.61,62.87 88.47,62.87 89.05,62.29 89.05,62.06 C141.2
PCIE_TXN11: length 102.8
  TOP w0.114: v2(16.2,23.38) 16.15,23.43 CN13.35 ; v2(88.21,56.14) 87.83,56.52 87.83,58.38 C3535.1
  BOTTOM w0.114: v2(88.21,56.14) 88.06,56 88.06,55.07 87.78,54.79 87.78,47.33 85.67,45.22 85.67,43.95 84.11,42.39 84.11,31.11 75.74,22.74 17.31,22.74 16.54,23.5 16.33,23.5 v2(16.2,23.38)
PCIE_TXN11_C: length 8.4
  TOP w0.076: U11.D24 87.04,66.86 87.3,66.28 87.3,65.99 86.98,65.02 86.52,64.56 86.52,63.33 86.51,63.32 86.51,62.77 86.81,62.47 86.83,62.47 86.89,62.42 86.89,62.42 86.91,62.42 86.92,62.42
  TOP w0.114: 86.92,62.42 87.7,61.63 87.7,59.88 C3535.2
PCIE_TXP6: length 53.5
  TOP w0.114: v2(84.02,28.28) 84.27,28.03 84.27,27.33 83.47,26.53 83.47,10.46 83.35,10.34 CN14.35 ; C693.1 90.56,58.19 90.56,57.44 91.26,56.74 91.26,56.4 v2(91,56.14)
  BOTTOM w0.114: v2(84.02,28.28) 84.27,28.54 84.27,29.73 86.07,31.53 86.07,40.7 88.96,43.6 88.96,51.12 89.86,52.02 89.86,53.2 91.33,54.67 91.33,55.82 v2(91,56.14)
PCIE_TXP10: length 75.8
  TOP w0.114: v2(89.86,55.51) 89.73,55.64 89.12,55.64 88.67,56.08 88.67,60.43 C138.1 ; SBCN2.13 116.16,7.58 v2(116.11,7.63)
  L4_IN2 w0.114: v2(89.86,55.51) 89.99,55.64 90.24,55.64 90.71,55.17 91.98,55.17 92.75,55.93 103.12,55.93 109.05,49.99 109.05,49.03 108.4,48.39 108.4,35.73 114.89,29.24 114.89,12.5 116.44,10.95 116.44,7.92 116.35,7.84 116.35,7.83 116.15,7.63 v2(116.11,7.63)
PCIE_TXP10_C: length 7.4
  TOP w0.076: 87.61,62.61 87.6,62.61 87.58,62.63 87.51,62.63 87.49,62.65 87.34,62.65 87.09,62.9 87.02,62.96 87.02,64.5 87.49,64.97 87.69,64.97 87.84,65.11 87.84,65.38 87.78,65.5 87.78,65.65 87.84,65.84 87.84,66.01 87.75,66.26 U11.C23
  TOP w0.114: C138.2 88.37,61.59 88.61,61.59 88.79,61.77 88.79,62.19 88.37,62.61 87.61,62.61
PCIE_TXP11: length 102.7
  TOP w0.114: v2(16.23,24.01) 16.15,24.01 16.07,23.93 CN13.37 ; C3883.1 87.58,58 87.58,56.36 v2(87.36,56.14)
  BOTTOM w0.114: v2(87.36,56.14) 87.58,56.14 87.81,55.91 87.81,55.18 87.53,54.89 87.53,47.44 85.42,45.33 85.42,44.06 83.86,42.5 83.86,31.22 75.63,22.99 17.41,22.99 16.65,23.76 16.48,23.76 v2(16.23,24.01)
PCIE_TXP11_C: length 8.4
  TOP w0.076: U11.C24 87.08,66.18 87.08,66.03 86.79,65.14 86.31,64.65 86.31,63.42 86.3,63.41 86.3,62.68 86.74,62.24
  TOP w0.114: 86.74,62.24 87.45,61.52 87.45,59.28 87.38,59.22 87.22,59.22 C3883.2
PCIE_WAKE#: length 219.4
  TOP w0.102: v3(111.28,17.68) 111.28,10.35 R133.2
  L3_IN1 w0.102: v3(111.28,17.68) 97.34,17.68 91.72,23.3 30.67,23.3 25,28.97 25,32.82 21.79,36.04 14.21,36.04 6.94,43.31 6.94,57.92 4.52,60.33 4.52,65.67 3.5,66.68 3.5,68.72 3.89,69.11 v3(4.21,69.11)
  L4_IN2 w0.102: v3(4.21,69.11) 4.54,69.44 4.54,69.86 4.12,70.28 4.12,92.98 3.99,93.11 3.99,97.65 5.25,98.91 5.25,102.39 7.08,104.21 7.08,111.38 6.96,111.5 6.96,113.87 7.08,113.99 7.16,114.07 7.16,118.36 8.38,119.58 8.38,122.44 9.68,123.74 10.52,123.74 11.48,124.7 v3(11.48,129.06)
  BOTTOM w0.102: U25.68 11.05,129.57 11.48,129.13 v3(11.48,129.06)
PCIE_WAKE#_CN: length 3.3
  TOP w0.102: SBCN2.4 111.66,8.46 R133.1 110.9,8.78 R132.1
PID_1_CHG_R_LED: length 328.3
  TOP w0.102: v3(109.81,26.81) 109.32,26.31 109.32,14.13 107.01,11.82 107.01,9.39 106.36,8.75 104.48,8.75 103.79,8.06 SBCN1.11
  L3_IN1 w0.102: v3(109.81,26.81) 114.98,26.81 116.22,28.05 133.58,28.05 138.78,33.25 138.78,39.8 137.06,41.51 135.16,41.51 133.52,43.15 133.52,49.01 136.6,52.08 136.6,60.68 136.61,60.69 136.61,64.22 136.73,64.34 136.73,74.17 135.23,75.68 135.23,90.15 133.68,91.7 132.28,91.7 v3(131.77,92.21)
  L4_IN2 w0.102: v3(131.77,92.21) 131.77,92.85 129.69,94.93 129.69,96.23 130.76,97.29 130.76,97.54 130.76,98.05 130.76,98.05 130.76,98.29 130.76,99.14 131.73,100.12 131.73,104.6 131.9,104.77 131.9,106.48 132.28,106.86 132.28,110.28 133.96,111.95 133.96,121.44 131.01,124.39 130.73,124.39 130.12,124.99 130.12,127 129.71,127.41 129.71,133.44 128.27,134.88 123.77,134.88 121.48,137.17 114.38,137.17 v3(114.1,136.88) 113.15,137.83 103.1,137.83 102.31,137.04 100.3,137.04 100,137.33 94.46,137.33 92.85,135.72 91.45,135.72 90.76,136.41 74.12,136.41 71.26,133.54 67.8,133.54 66.88,132.61 50.69,132.61 50.06,133.24 43.04,133.24 42.19,132.38 41.55,132.38 40.34,131.17 32.63,131.17 32.15,130.69 28.24,130.69 26.63,132.29 22.13,132.29 21.44,132.98 21.12,132.98 21.12,132.98 14.83,132.98 14.47,132.62 14.47,132.01 13.79,131.33 10.08,131.33 8.3,129.55 8.3,123.91 7.41,123.02 6.83,123.02 5.43,121.62 5.43,115.32 5.43,115.31 5.43,114.83 5.43,114.83 5.43,113.32 v3(5.18,113.07)
  BOTTOM w0.102: v3(114.1,136.88) 114.1,136.88 114.09,136.88 R322.1 R325.1 ; U25.24 13.07,115.55 13.07,113.76 12.35,113.04 11.86,113.04 10.94,112.12 6.39,112.12 v1(6.13,112.37) 5.44,113.07 v3(5.18,113.07)
PID_1_CHG_R_LED0: length 5.6
  BOTTOM w0.102: C263.1 111.92,137.88 Q22.B 112.53,137.7 114.77,137.7 114.88,137.6 114.88,136.23 R322.2
PID_2_PWR_LED: length 328.8
  TOP w0.102: SBCN1.8 102.29,7.9 103.53,9.13 103.94,9.13 104.97,10.17 104.97,11.54 105.13,11.69 105.13,12.66 105.41,12.94 105.81,12.94 108.06,15.19 v3(108.06,26.82)
  L3_IN1 w0.102: v3(132.41,92.21) 133.55,92.21 135.43,90.33 135.43,77.5 136.93,76 136.93,64.26 136.81,64.14 136.81,60.61 136.8,60.6 136.8,51.9 133.73,48.83 133.73,43.23 135.24,41.72 137.15,41.72 138.98,39.88 138.98,33.16 133.67,27.85 116.3,27.85 114.8,26.34 108.54,26.34 v3(108.06,26.82)
  L4_IN2 w0.102: v3(4.85,114.11) 5.23,114.49 5.23,121.79 6.71,123.27 7.29,123.27 8.07,124.06 8.07,129.7 9.95,131.58 12.64,131.58 14.24,133.18 21.04,133.18 21.04,133.18 21.52,133.18 22.21,132.5 26.72,132.5 28.32,130.89 32.07,130.89 32.55,131.37 39.59,131.37 41.66,133.45 50.5,133.45 51.13,132.82 66.77,132.82 67.7,133.74 71.17,133.74 74.04,136.61 90.84,136.61 91.53,135.92 92.76,135.92 94.37,137.53 100.09,137.53 100.38,137.24 102.22,137.24 103.01,138.03 114.08,138.03 114.7,137.42 121.59,137.42 122.47,136.53 v3(122.78,136.53) 122.78,136.51 124.15,135.14 128.32,135.14 129.92,133.54 129.92,127.5 130.32,127.09 130.32,125.08 130.81,124.59 131.09,124.59 134.16,121.52 134.16,111.87 132.54,110.25 132.54,106.83 132.11,106.4 132.11,104.69 131.94,104.52 131.94,100.03 130.96,99.05 130.96,98.38 130.96,98.13 130.96,97.46 130.96,97.46 130.96,97.16 129.89,96.1 129.89,95.23 132.03,93.1 132.03,92.59 v3(132.41,92.21)
  BOTTOM w0.102: v3(122.78,136.53) R324.1 R326.1 ; U25.34 9.17,117.52 9.39,117.31 9.39,116.95 8.7,116.26 8.7,114.01 8.74,113.97 8.74,113.05 8.73,113.05 8.73,112.96 8.53,112.75 7.53,112.75 6.66,113.62 6.1,113.62 6.05,113.58 5.55,113.58 5.03,114.11 v3(4.85,114.11) 4.39,114.11 v1(4.19,114.31)
PID_2_PWR_LED0: length 3.9
  BOTTOM w0.102: Q21.B 120.62,138.39 120.82,138.18 121.2,138.18 121.91,137.47 C265.1 R324.2
PID_3_RF_LED_ON#: length 277.4
  TOP w0.102: v3(108.7,26.76) 108.7,15.54 105.56,12.4 C535.1 105.56,11.83 105.18,11.45 105.18,10.08 103.91,8.81 103.59,8.81 102.79,8.02 SBCN1.9
  L3_IN1 w0.102: v3(131.14,92.47) 131.14,92.21 132.53,90.81 132.66,90.81 133.3,90.18 134.31,90.18 135.02,89.47 135.02,77.67 135.02,77.34 135.02,77.34 135.02,75.5 136.53,74 136.53,64.43 136.4,64.3 136.4,60.78 136.39,60.77 136.39,52.38 133.32,49.31 133.32,43.06 135.07,41.31 136.98,41.31 138.58,39.71 138.58,33.36 133.47,28.25 116.14,28.25 115.08,27.2 109.14,27.2 v3(108.7,26.76)
  L4_IN2 w0.102: v3(131.14,92.47) 131.14,93.1 129.31,94.93 129.31,96.19 130.55,97.44 130.55,97.62 130.55,98.21 130.55,99.22 131.53,100.2 131.53,104.69 131.7,104.86 131.7,106.57 131.72,106.59 131.72,109.88 131.47,110.13 131.47,113.81 132.87,115.21 132.87,120.77 132.09,121.54 131.9,121.54 129.87,123.58 128.86,123.58 127.56,124.88 127.56,125.63 127.06,126.12 124.82,126.12 121.08,129.86 115.79,129.86 115.01,130.64 109.23,130.64 v3(108.69,131.18) 108.62,131.25 106.28,131.25 105.01,132.51 102.19,132.51 101.28,131.6 89.74,131.6 89.13,132.2 72.79,132.2 72.06,131.47 69.4,131.47 68.44,130.52 52.01,130.52 51.45,131.07 49.54,131.07 48.98,130.52 45.58,130.52 44.69,129.63 36.39,129.63 35.22,130.79 32.54,130.79 32.19,130.44 28.14,130.44 26.49,132.09 21.56,132.09 21.28,132.36 v3(21.28,132.6)
  BOTTOM w0.102: v3(108.69,131.18) 109.21,131.7 R625.1 ; U25.94 21.45,132.2 21.28,132.36 v3(21.28,132.6) 21.28,133.99 v1(21.79,134.5)
PLATFORM_ID1: length 6.7
  TOP w0.102: v3(22.04,118.47) 21.76,118.75 R34.1 R33.2 22.04,119.77 22.3,120.02 23.19,120.02 v1(23.69,120.53)
  BOTTOM w0.102: U25.123 22.46,119.12 22.04,118.7 v3(22.04,118.47)
PLATFORM_ID2: length 4.7
  TOP w0.102: R12.2 R11.1 11.55,126.25 11.13,126.67 v3(9.95,126.67)
  BOTTOM w0.102: v3(9.95,126.67) 9.61,126.32 U25.56
PLATFORM_ID3: length 2.9
  TOP w0.102: R28.2 R24.1 18.71,132.21 v3(18.79,132.29)
  BOTTOM w0.102: U25.87 18.65,132.15 v3(18.79,132.29)
PLT_RST#: length 471.9
  TOP w0.076: U11.AN10 95.54,82.19 v3(95.14,82.58)
  TOP w0.102: CN14.52 v3(87.6,2.95) ; v3(111.76,10.63) 112.17,10.63 R134.2 ; v3(28.22,29.58) 28.22,28.48 R3310.1
  L3_IN1 w0.102: v3(28.22,29.58) 31.88,25.92 77.29,25.92 83.77,32.39 105.33,32.39 v3(106.03,33.1) 106.64,33.71 106.64,49.93 109.17,52.46 110.18,52.46 112.47,54.75 120.37,54.75 v3(120.97,55.34) ; v3(133.85,81) 130.49,84.36 130.49,89.67 125.62,94.54 125.62,99.27 123.09,101.8 121.92,101.8 117.63,106.09 117.63,117.16 120.19,119.72 120.19,120.52 119.81,120.9 119.81,122.76 119.45,123.11 119.45,123.99 119.15,124.29 119.15,126.56 118.21,127.49 92.08,127.49 91.34,128.23 90.87,128.23 89.48,129.62 74.48,129.62 73.6,128.74 73.6,127.81 72.83,127.03 67.71,127.03 67.23,126.55 51.41,126.55 48.21,129.75 38.57,129.75 35.59,126.78 34.21,126.78 33.18,125.75 28.85,125.75 28.43,125.33 25.29,125.33 24.69,124.74 19.32,124.74 19.07,124.99 17.27,124.99 16.93,124.64 16.14,124.64 14.85,123.35 14.85,119.16 14.59,118.9 14.59,117.5 14.09,117.01 14.09,116.69 14.47,116.31 14.47,116.03 15.26,115.24 15.26,114.27 v3(15.07,114.08)
  L4_IN2 w0.102: v3(17.04,88.13) 16.49,88.68 14.25,88.68 8.52,94.41 8.52,96.97 9.57,98.03 9.57,99.6 11.22,101.25 13.05,101.25 15.6,103.8 15.6,105.9 15.71,106 15.71,108.89 v3(15.96,109.14) 15.96,109.84 15.46,110.34 15.46,112.83 15.07,113.23 v3(15.07,114.08) ; v3(131.68,72.07) 131.32,71.71 130.58,71.71 130.07,71.2 126.11,71.2 125.13,72.19 122.07,72.19 121.69,72.57 117.82,72.57 117.3,73.1 v3(116.18,73.1)
  BOTTOM w0.076: v3(95.14,82.58) 94.69,82.12 94.69,81.54 94.84,81.4 95.51,81.4 97.39,79.51 101.8,79.51 102.43,78.88 103.83,78.88 104.34,78.37 104.34,77.35 105.54,76.16 106.62,76.16
  BOTTOM w0.102: v3(131.68,72.07) 131.64,72.1 131.64,72.34 132.43,73.13 132.43,73.63 134.56,75.76 134.56,78.21 134.82,78.47 134.82,79.77 133.85,80.75 v3(133.85,81) ; U28.16 15.99,109.17 v3(15.96,109.14) ; U25.22 13.85,114.37 14.14,114.08 v3(15.07,114.08) ; 106.62,76.16 108.25,76.16 109.1,75.31 114.13,75.31 115,74.44 v1(115.02,74.44) 115.02,74.29 116.18,73.13 v3(116.18,73.1) 120.85,68.43 120.85,65.62 121.56,64.91 121.56,55.94 v3(120.97,55.34) ; v3(17.04,88.13) 17.01,88.1 R41.2 ; v3(106.03,33.1) 110.89,28.24 110.89,16.02 111.76,15.15 v3(111.76,10.63) 111.76,8.07 105.41,1.72 88.92,1.72 87.69,2.95 v3(87.6,2.95) 87.6,3.36 C623.2
PLT_RST#_CN: length 2.6
  TOP w0.102: SBCN2.5 112.16,7.95 112.98,8.77 R134.1
PM_BATLOW#: length 22.7
  TOP w0.076: U11.AU13 93.65,84.79 v3(93.31,85.12)
  TOP w0.102: v3(107.94,94.42) 107.74,94.22 106.14,94.22 v3(105.76,93.84)
  BOTTOM w0.076: 105.51,93.58 105.38,93.45 101.62,93.45 101.11,92.95 101.11,92.39 100.44,91.71 99.37,91.71 99.02,91.36 99.02,89.27 98.64,88.9 98.64,88.26 96.09,85.71 93.95,85.71 93.36,85.12 v3(93.31,85.12)
  BOTTOM w0.102: v3(105.76,93.84) 105.51,93.58 ; v3(107.94,94.42) 107.94,94.8 107.87,94.88 R411.2
PM_CLKRUN#: length 158
  TOP w0.102: R185.1 115.36,91.85 114.45,92.77 113.41,92.77 v3(112.59,91.96) ; v3(109.54,90.43) 109.06,90.43 R160.2
  L4_IN2 w0.102: v3(20.85,121.14) 21.28,121.57 23.59,121.57 23.97,121.95 29.25,121.95 29.83,122.54 34.08,122.54 35.1,123.55 44.32,123.55 45.14,124.37 45.14,125.31 45.9,126.07 47.67,126.07 48.41,126.8 69.14,126.8 69.4,127.07 71.16,127.07 71.71,127.62 94.37,127.62 95.61,126.38 114.47,126.38 115.69,125.16 115.69,119.87 114.81,119 114.81,111.91 112.92,110.02 112.92,106.62 110.26,103.96 110.26,101.5 109.52,100.76 109.52,98.33 108.99,97.8 108.99,93.68 108.86,93.56 108.86,90.76 109.18,90.43 v3(109.54,90.43)
  BOTTOM w0.102: v3(112.59,91.96) 112.72,91.83 112.72,91.57 111.58,90.43 v3(109.54,90.43) ; U25.93 21.05,130.12 20.23,129.29 20.23,128.65 20.09,128.51 20.09,126.49 20.31,126.26 20.31,123.9 20.95,123.26 20.95,121.24 v3(20.85,121.14)
PM_CLKRUN#_SOC: length 16.9
  TOP w0.076: 106.6,89.87 106.58,89.87 106.38,89.67 104.2,89.67 103.97,89.9 102.52,89.9 102.52,89.9 102.09,89.9 102.09,89.9 101.34,89.9 101.27,89.97 95.98,89.97 95.05,89.05 95.05,88.3 95.15,88.21 95.15,86.41 94.83,86.1 U11.AW11
  TOP w0.102: 106.6,89.87 107.64,89.87 R160.1
PM_H_SLP_S0#: length 10.3
  TOP w0.076: U11.AT11 94.58,84.14 v3(94.23,84.48)
  BOTTOM w0.102: v3(94.23,84.48) 94.58,84.84 94.58,85.1 95.02,85.53 96.16,85.53 98.82,88.19 98.82,88.82 99.19,89.2 99.19,90.65 99.74,91.19 R435.1
PM_RSMRST#: length 114.1
  TOP w0.102: v1(10.87,113.93) 11.55,114.62 R116.2 11.55,115.22 v3(10.06,116.72)
  L3_IN1 w0.102: v3(15.51,118.04) 15.62,118.14 17.8,118.14 18.54,117.41 19.93,117.41 21.41,118.88 22.27,118.88 23.94,120.56 27.69,120.56 28.58,119.67 29.24,119.67 30.09,120.51 35.69,120.51 36.1,120.1 44.96,120.1 45.01,120.15 48.74,120.15 48.99,119.9 50.13,119.9 54.67,115.36 78.77,115.36 96.64,97.49 v3(103.6,97.49)
  BOTTOM w0.102: U25.32 9.8,116.54 9.98,116.72 v3(10.06,116.72) 12.26,118.92 13.75,118.92 14.63,118.04 v3(15.51,118.04) ; v3(103.6,97.49) 103.6,96.96 103.88,96.68 R405.1 103.88,95.38 R414.1
PM_RSMRST#_R: length 20.2
  TOP w0.076: U11.AY17 91.26,86.76 91.16,86.87 91.06,86.98 90.99,87.19 90.99,87.31 91.05,87.54 91.05,87.68 91,87.8 91,88.17 91.35,88.52 91.35,90.42 92.27,91.34 92.27,91.7 93,92.43 93.57,92.43 94.72,93.58
  TOP w0.102: v3(103.25,94.24) 101.79,94.24 100.9,95.13 96.27,95.13 94.72,93.58
  BOTTOM w0.102: v3(103.25,94.24) 103.25,94.32 103.37,94.45 R414.2 R413.1
PM_SLP_S0#: length 81.5
  TOP w0.102: Q10.2 116.95,57.03 117.98,58.06 R119.1 117.98,59.14 117.67,59.45 116.94,59.45 R117.1 116.55,59.44 116.94,59.83 121.99,59.83 123.31,58.51 v3(123.31,58.43)
  BOTTOM w0.076: R435.2 100.68,91.64 101.29,92.25 101.29,92.42 102.15,93.28 106.1,93.28
  BOTTOM w0.102: v3(123.31,58.43) 123.31,74.39 125.63,76.72 129.43,76.72 131.06,78.35 131.06,81.27 130.77,81.57 130.77,87.05 127.28,90.54 126.2,90.54 125.72,91.02 118.93,91.02 116.34,93.6 114.64,93.6 114.35,93.89 109.43,93.89 108.82,93.28 106.1,93.28
PM_SLP_S3#: length 115.4
  TOP w0.076: U11.AP15 92.78,82.84 v2(92.4,83.21)
  TOP w0.102: v3(26.21,116.8) 25.98,117.02 TP80.1
  L3_IN1 w0.076: v2(102.58,92.51) 102.58,92.67 102.1,93.15 98.27,93.15 97.83,93.58
  L3_IN1 w0.102: v3(26.21,116.8) 27.48,115.53 32.21,115.53 33.05,116.37 33.76,116.37 35.3,117.91 35.8,117.91 36.27,118.37 45.83,118.37 45.88,118.42 47.74,118.42 48.08,118.08 49.37,118.08 53.82,113.63 78.06,113.63 97,94.69 97,94.42 97.83,93.58
  L4_IN2 w0.076: v2(102.58,92.51) 102.58,92.44 99.17,89.02 96.51,89.02 95.12,87.63 94.94,87.63 92.77,85.45 92.77,83.46 92.52,83.21 v2(92.4,83.21)
  BOTTOM w0.102: v3(26.21,116.8) 25.98,117.02 v1(25.98,117.48) 25.98,117.74 26.36,118.12 26.36,118.67 26.36,118.67 26.36,119.09 26.36,119.09 26.36,119.95 25.32,121 25.32,123.3 24.84,123.78 24.84,124.42 24.53,124.72 U25.109
PM_SLP_S4#: length 108.8
  TOP w0.076: U11.BA16 91.86,86.95 91.86,89.88 95.2,93.23 99.52,93.23 99.88,93.58
  TOP w0.102: TP83.1 26.57,117.27 v3(26.69,117.15) ; v2(100.02,93.72) 99.88,93.58
  L3_IN1 w0.102: v3(26.69,117.15) 26.69,116.92 27.88,115.73 32.13,115.73 32.97,116.57 33.68,116.57 35.22,118.11 35.72,118.11 36.18,118.58 45.74,118.58 45.79,118.63 47.82,118.63 48.16,118.28 49.46,118.28 53.91,113.83 78.14,113.83 96.97,95 98.83,95 100.02,93.81 v2(100.02,93.72)
  BOTTOM w0.102: v3(26.69,117.15) 26.69,119.91 25.52,121.08 25.52,123.38 25.37,123.54 25.37,123.55 25.04,123.88 25.04,124.7 24.61,125.12 U25.108
PM_SLP_S5#: length 14.2
  TOP w0.076: U11.AY16 91.56,86.56 91.56,87.04 91.7,87.18 91.7,89.95 95.32,93.58
  TOP w0.102: 95.32,93.58 95.76,94.01 99.18,94.01 v3(99.49,93.71)
  BOTTOM w0.102: v3(99.49,93.71) 99.61,93.84 R416.1
PM_SLP_SUS#: length 16.8
  TOP w0.076: v2(92.4,82.58) U11.AN15
  L4_IN2 w0.076: v2(103.43,88.47) 103.33,88.57 103.33,88.57 102.59,89.32 99.97,89.32 99.45,88.8 96.51,88.8 95.18,87.47 95,87.47 92.92,85.39 92.92,83.1 92.4,82.58 v2(92.4,82.58)
  BOTTOM w0.076: R442.1 103.25,88.66 103.43,88.47 v2(103.43,88.47)
PM_SLP_SUS#_R: length 261.1
  TOP w0.102: v3(114.15,92.35) 114.85,91.65 116.48,91.65 117.02,91.11 119.28,91.11 119.85,90.54 v3(119.91,90.54) ; v3(122.75,55.38) 122.39,55.75 119.11,55.75 117.83,54.47 107.16,54.47 105.12,56.5 96.19,56.5 92.4,52.71 92.4,52.56 92.07,52.23 92.07,52.01 91,50.93 R576.1
  TOP w0.254: R336.1 v3(40.84,125.34)
  L3_IN1 w0.102: v3(17.67,123.37) 17.77,123.37 20.44,120.7 22.17,120.7 23.04,121.57 28.47,121.57 v3(30.45,123.55) 30.84,123.55 31.41,124.13 33.18,124.13 34.04,123.27 37.84,123.27 39.9,125.34 v3(40.84,125.34) 41.29,125.79 49.83,125.79 51.34,124.28 53.06,124.28 53.71,124.93 68.94,124.93 69.48,124.39 76.96,124.39 78.44,125.86 110.49,125.86 113.97,122.39 113.97,112.26 114.49,111.73 114.49,105.14 v3(117.52,102.12)
  L4_IN2 w0.102: v3(117.52,102.12) 120.47,99.17 120.47,91.09 v3(119.91,90.54)
  BOTTOM w0.076: 106.6,89.77 104.79,89.77 R442.2
  BOTTOM w0.102: U25.83 17.11,131.01 17.11,128.75 17.47,128.4 17.47,123.57 v3(17.67,123.37) ; v3(114.15,92.35) 114.07,92.35 111.69,89.97 110.85,89.97 109.73,88.86 109.34,88.86 108.43,89.77 106.6,89.77 ; v3(30.45,123.55) 30.45,123.66 29.66,124.44 29.66,127.35 30.75,128.44 30.75,128.86 R338.1 ; v3(122.75,55.38) 122.17,55.96 122.17,64.96 122.84,65.62 122.84,68.15 121.99,68.99 121.99,74.69 124.43,77.12 129.26,77.12 130.63,78.49 130.63,81.13 130.26,81.5 130.26,86.53 126.94,89.85 125.75,89.85 124.81,90.79 120.16,90.79 v3(119.91,90.54)
PM_SUS_STAT#: length 111.4
  TOP w0.076: U11.BA11 94.61,87.52 94.61,88.07 94.71,88.17 94.71,89.22 95.8,90.3 101.52,90.3 v2(101.64,90.43)
  L3_IN1 w0.076: 97.22,93.58 97.98,92.82 100.05,92.82 101.64,91.22 v2(101.64,90.43)
  L3_IN1 w0.102: v3(15.08,111.85) 16.81,113.58 20.75,113.58 22.13,114.97 32.23,114.97 33.22,115.96 33.93,115.96 35.34,117.36 45.39,117.36 46.04,118.02 47.57,118.02 47.91,117.67 48.32,117.67 52.78,113.22 77.7,113.22 96.34,94.59 96.34,94.46 97.22,93.58
  BOTTOM w0.102: R375.2 15.08,112.56 v3(15.08,111.85)
PME#: length 0.6
  TOP w0.076: U11.AU11 94.35,85.12 v2(94.23,85.12)
PMON: length 2.6
  TOP w0.102: U109.10 23.66,43.31 23.58,43.23 v3(23.58,42.83)
  BOTTOM w0.102: R3415.2 23.98,42.83 v3(23.58,42.83) 23.2,43.21 R3433.1
PMON_20464516: length 2.6
  TOP w0.102: U1.4 15.17,97.55 14.9,97.82 14.9,98.1 14.52,98.48 v3(14.52,98.51)
  BOTTOM w0.102: R401.2 15.11,97.92 v3(14.52,98.51)
PMUVCC: length 3
  TOP w0.076: U1634.B5 125.83,20.7 125.83,21.53
  TOP w0.203: C633.1 125.83,21.53
PROC_TCK: length 5.1
  TOP w0.076: TP7.1 64.31,62.16 65.1,62.95 65.38,62.95 66.22,63.79 66.22,63.85 66.3,63.92 66.3,64.08 66.52,64.3 66.52,64.95 66.36,65.11 66.36,65.41 66.41,65.5 66.41,65.72 U11.B61
PROC_TDO: length 5
  TOP w0.076: TP8.1 64.7,61.87 64.7,62.32 65.17,62.79 65.45,62.79 66.39,63.73 66.39,63.78 66.47,63.86 66.47,64.01 66.7,64.24 66.7,65.19 U11.A61
PROCHOT#: length 127.1
  TOP w0.102: R83.1 55.87,60.44 55.87,60.79 R82.1 54.63,60.94 Q4.D 53.84,60.69 v3(53.67,60.87) ; v3(12.59,44.37) 14.06,42.91 18.75,42.91 19.6,42.06 R3160.1
  L4_IN2 w0.102: v3(53.67,60.87) 52.98,60.87 50.76,58.65 34.81,58.65 34.29,58.13 29.9,58.13 27.83,56.06 v3(19.02,56.06) 18.5,56.58 18.5,58.85 20.72,61.07 20.72,65.14 20.08,65.79 20.08,69.57 20.34,69.84 20.34,80.03 21.41,81.1 21.41,84.94 21.94,85.47 21.94,91.03 21.04,91.94 21.04,94.31 21.33,94.6 21.33,97.61 19.55,99.4 13.89,99.4 12.77,98.28 11.89,98.28 v3(11.84,98.33)
  BOTTOM w0.102: v3(19.02,56.06) 19.01,56.06 18.82,55.87 16.6,55.87 13.42,52.69 13.42,45.14 12.72,44.44 12.66,44.44 v3(12.59,44.37) ; v3(11.84,98.33) 11.63,98.55 11.63,99.3 11.27,99.65 9.85,99.65 9.77,99.58 9.77,97.95 10.13,97.59 R402.1
PROCHOT#_H: length 3.3
  TOP w0.102: U1.11 v3(12,97.57)
  BOTTOM w0.102: v3(12,97.57) 11.09,97.57 R402.2 R398.2
PSYS_H: length 85.4
  TOP w0.102: U1.40 17.7,96.35 v3(18.5,97.14) 18.94,97.59 19.26,97.59 19.4,97.72 19.4,98.36 19.93,98.89 R31.1
  L3_IN1 w0.102: v3(21.9,79.59) 20.47,81.02 20.47,81.58 20.95,82.07 20.95,85.42 19.5,86.86 19.5,96.14 v3(18.5,97.14)
  L4_IN2 w0.102: v3(21.9,79.59) 21.56,79.25 21.56,66.77 v3(21.1,66.31)
  BOTTOM w0.102: R3433.2 21.95,43.13 21.31,42.48 19.27,42.48 18.88,42.09 18.88,38.4 18.31,37.83 14.37,37.83 11.83,40.37 11.83,50.28 12.47,50.91 12.47,53.2 16.02,56.76 17.07,56.76 17.29,56.98 17.75,56.98 22.17,61.4 22.17,61.89 22.25,61.96 22.25,63.39 21.4,64.24 21.13,64.24 20.47,64.9 20.47,65.77 21,66.31 v3(21.1,66.31)
PWMB: length 17.6
  TOP w0.203: U110.7 34.02,52.54 33.68,52.2 33.68,51.44
  TOP w0.254: U109.20 28.38,42.42 28.59,42.21 28.6,42.21 28.85,41.96 28.85,40.94 29.23,40.56 v3(29.23,40.5)
  BOTTOM w0.254: v3(29.23,40.5) 31.33,40.5 33.04,42.21 33.04,50.93 v3(32.89,51.08)
PWMC: length 22.9
  TOP w0.203: 29.87,43.21 29.36,43.71 U109.22
  TOP w0.254: 29.87,43.21 29.87,41.71 30.82,40.75 v3(30.82,38.15) ; v3(35.56,50.6) 35.54,50.62 35.54,50.64 35.51,50.67 35.51,51.39 U110.10
  BOTTOM w0.254: v3(30.82,38.15) 30.88,38.09 32.53,38.09 35.33,40.88 35.33,50.09 35.56,50.32 v3(35.56,50.6)
PWR_B_LED: length 6.4
  BOTTOM w0.102: R326.2 C271.1 R333.2 121.18,132.5 118.19,132.5 118.09,132.4 LED1.2
PWR_B_LED_GND: length 6.2
  BOTTOM w0.508: LED1.3 118.09,134.68 117.75,135.01 117.75,137.12 118.33,137.7 Q21.C 117.69,138.44 117.69,138.44 117.38,138.13 R317.1
PWR_GATE#: length 0.6
  TOP w0.076: U11.AM10 95.55,81.54 v3(95.14,81.94)
PWR_R_LED_GND: length 6.1
  BOTTOM w0.508: LED1.4 117.19,134.24 117.07,134.36 117.07,137.04 116.4,137.71 116.4,137.73 R318.1 114.9,138.13 Q22.C
PWR_REQ: length 5.6
  TOP w0.076: 124.83,21.18 124.83,20.7 U1634.B3
  TOP w0.102: R742.2 122.3,21.73 124.28,21.73 124.83,21.18
PWR_USB#: length 171.4
  TOP w0.102: v3(135.15,113.47) 135.64,113.96 138.4,113.96 v3(139.35,113.02)
  L4_IN2 w0.102: v3(135.15,113.47) 134.57,114.05 134.57,123.05 133.32,124.29 132.15,124.29 131.44,125 130.98,125 130.73,125.25 130.73,126.92 130.73,127.25 130.32,127.66 130.32,134.05 128.14,136.23 126.48,136.23 124.44,138.26 122.3,138.26 121.33,139.23 113.64,139.23 113.32,139.55 109.94,139.55 109.24,138.84 102.68,138.84 101.89,138.06 100.91,138.06 100.61,138.36 92.76,138.36 92.23,137.83 89.58,137.83 89.17,137.42 73.7,137.42 70.83,134.56 67.36,134.56 66.47,133.67 52.88,133.67 52.28,134.27 40.63,134.27 39.55,133.18 22.39,133.18 21.78,133.79 20.79,133.79 20.78,133.79 17.97,133.79 13.99,133.79 12.38,132.19 9.7,132.19 7.46,129.95 7.46,125.89 7.1,125.52 6.59,125.52 5.63,124.57 v3(5.63,123.58)
  BOTTOM w0.102: U25.48 6.08,123.12 v3(5.63,123.58) 5.5,123.71 v1(4.9,123.71) ; R370.2 139.25,113.11 v3(139.35,113.02) 139.45,112.92 U26.4
PWRBTN#: length 115.4
  TOP w0.076: v2(101.11,93.53) 100.43,92.84 95.29,92.84 92.19,89.75 92.19,87.74 92.46,87.48 U11.BA15
  L3_IN1 w0.102: v3(14.47,116.85) 15.67,115.65 23.54,115.65 25.94,118.05 27.27,118.05 27.97,117.36 27.97,116.77 28.39,116.34 28.6,116.34 32.16,116.34 32.8,116.98 33.51,116.98 35.05,118.52 35.55,118.52 36.01,118.98 45.57,118.98 45.62,119.03 47.99,119.03 48.33,118.69 49.63,118.69 54.08,114.24 78.31,114.24 97.11,95.44 99.14,95.44 100.43,94.14 100.68,94.14 101.11,93.71 v2(101.11,93.53)
  BOTTOM w0.102: U25.21 14.25,116.62 v3(14.47,116.85)
PWRON#: length 198.3
  TOP w0.102: SBCN1.12 104.29,8.28 104.56,8.55 106.45,8.55 107.21,9.31 107.21,11.73 109.52,14.05 109.52,25.6 v3(109.81,25.9)
  L3_IN1 w0.102: v3(133.58,92.86) 135.63,90.8 135.63,77.59 137.13,76.09 137.13,64.17 137.01,64.05 137.01,51.73 133.93,48.65 133.93,43.32 135.33,41.92 137.23,41.92 139.19,39.97 139.19,33.08 133.75,27.65 116.39,27.65 114.64,25.9 v3(109.81,25.9)
  L4_IN2 w0.102: v3(133.58,92.86) 133.58,96.12 133.65,96.19 133.65,97.07 133.39,97.34 133.39,103.4 134.11,104.12 134.11,107.94 136.34,110.18 136.34,114.21 135.66,114.89 135.66,127.33 135.56,127.43 135.56,128.04 133.9,129.7 v3(133.9,132.21) 133.9,134.02 130.25,137.68 130.25,139.46 v3(130.76,139.96)
  BOTTOM w0.102: v3(130.76,139.96) 131.01,140.22 134.28,140.22 135.04,139.45 SW1.2 ; v3(130.76,139.96) 129.87,139.07 129.87,135.01 129.61,134.76 128.85,134.76 128.6,135.01 Q18.2 ; v3(130.76,139.96) 130.12,140.6 127.33,140.6 126.95,140.22 126.95,139.46 126.44,138.95 C262.1 ; Q24.2 126.94,137.04 127.1,137.19 127.1,137.19 127.32,137.42 127.32,137.42 127.33,137.42 127.33,137.98 C262.1 ; v3(133.9,132.21) 134.36,132.21 135.04,131.54 SW1.1 ; C262.1 R309.2 124.21,138.87 R313.1
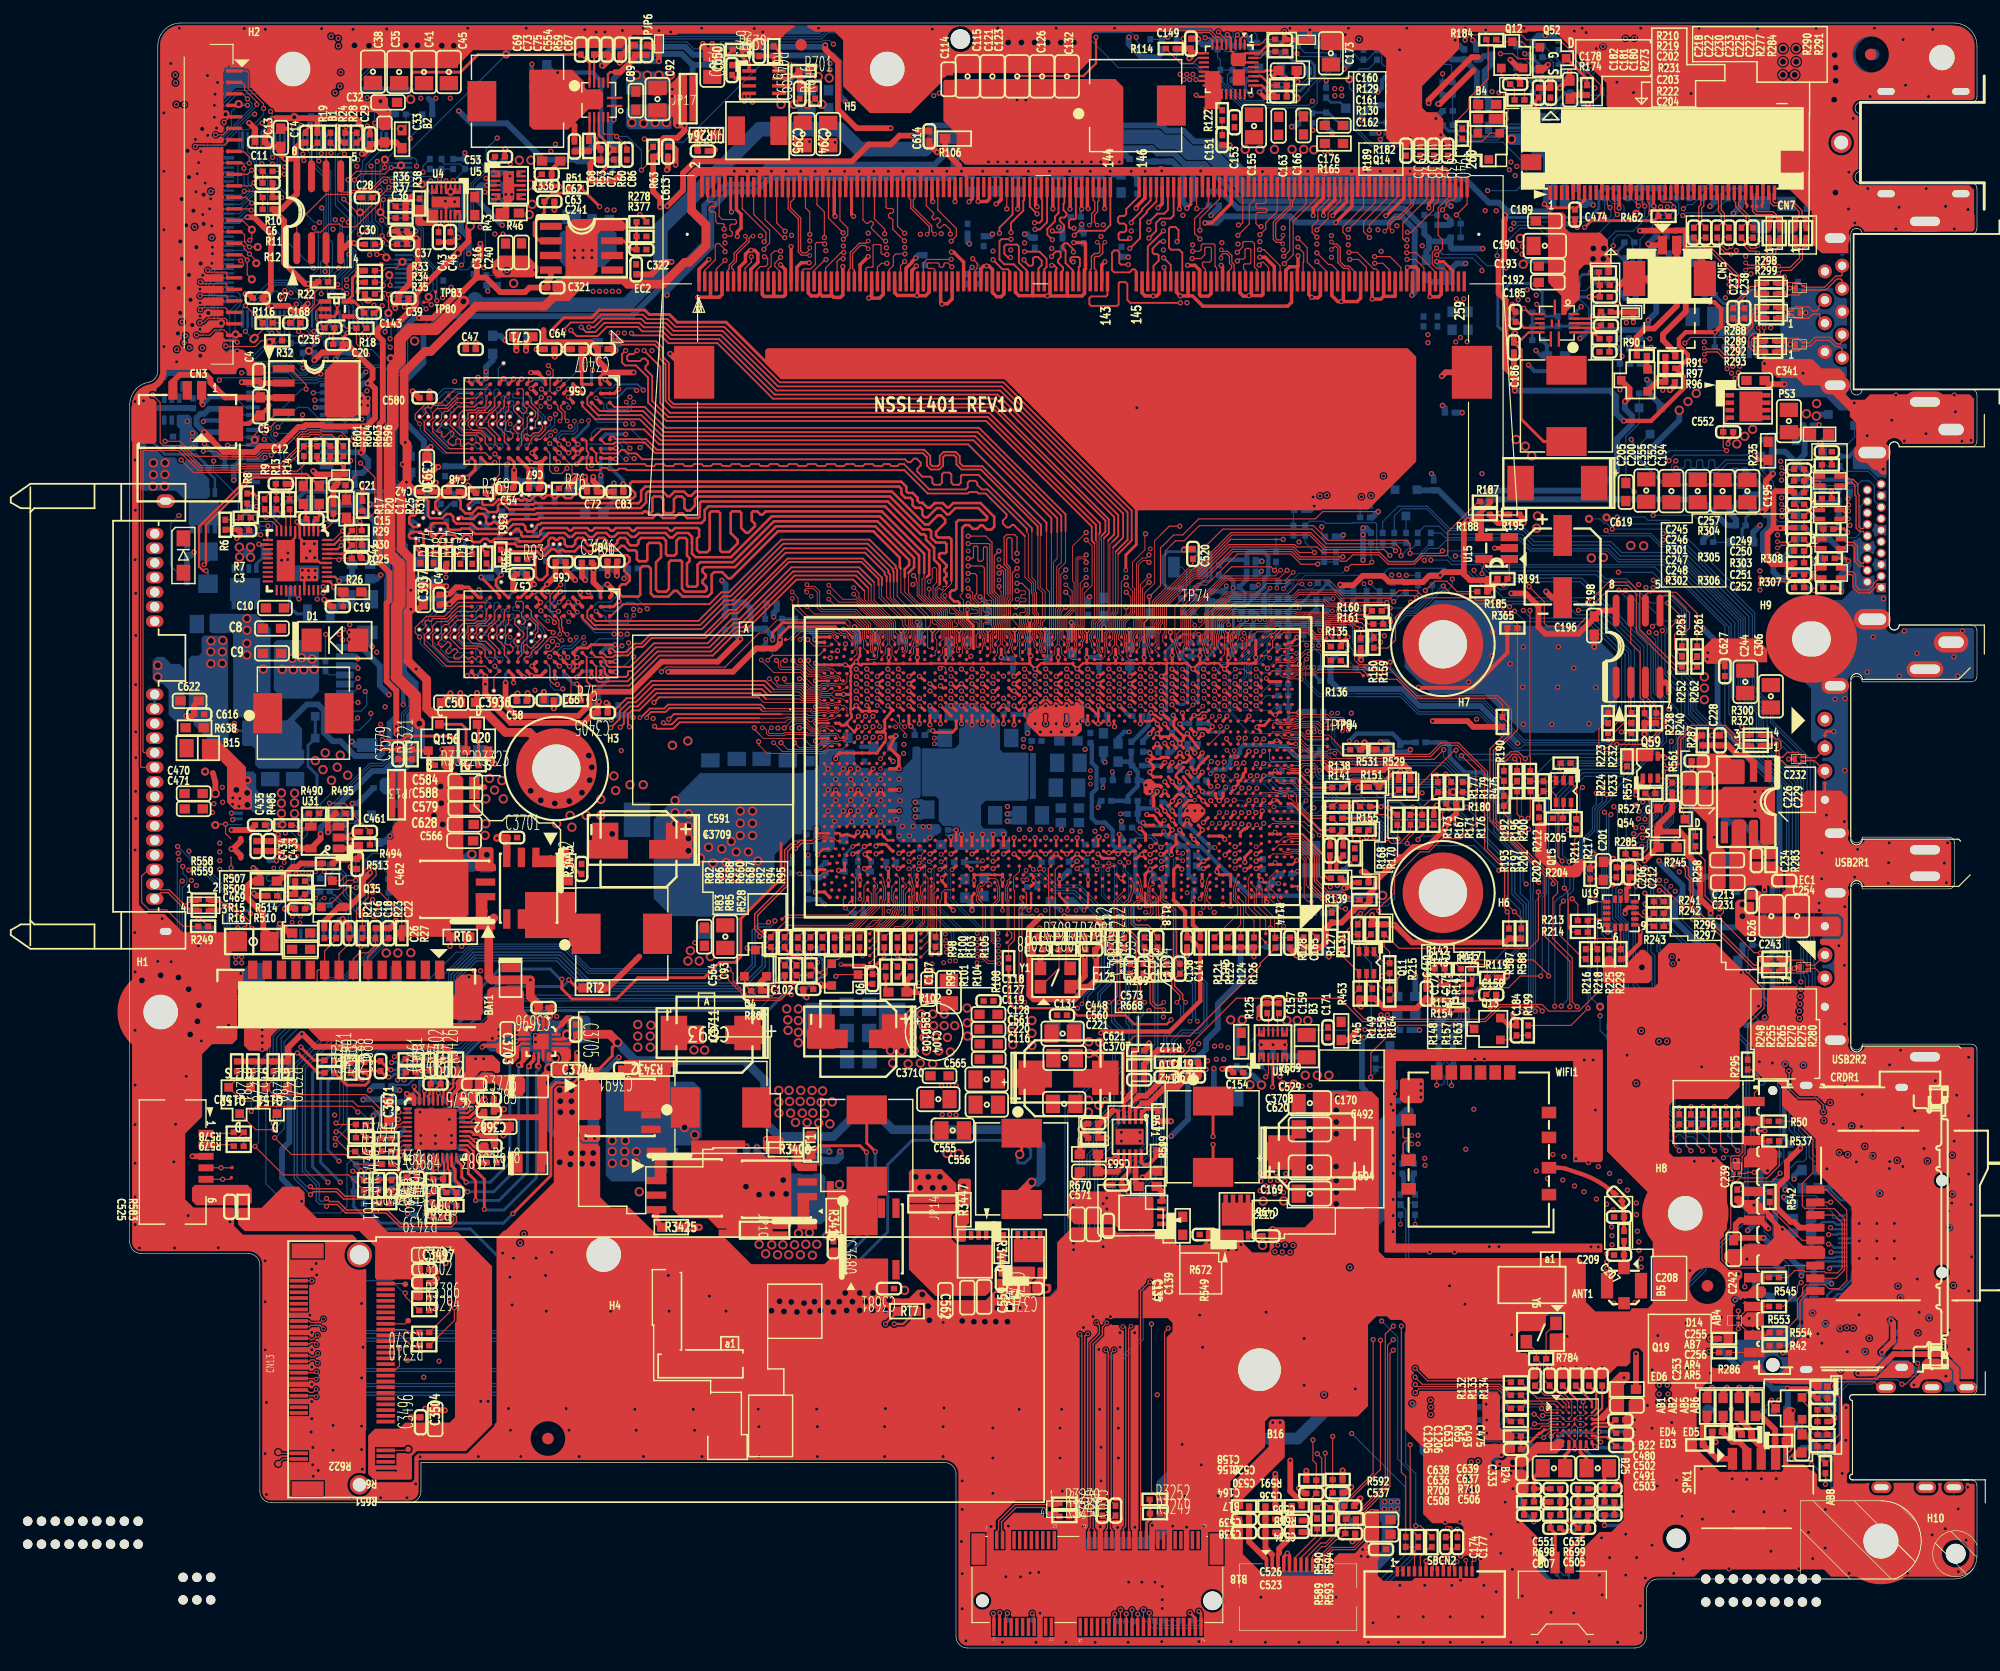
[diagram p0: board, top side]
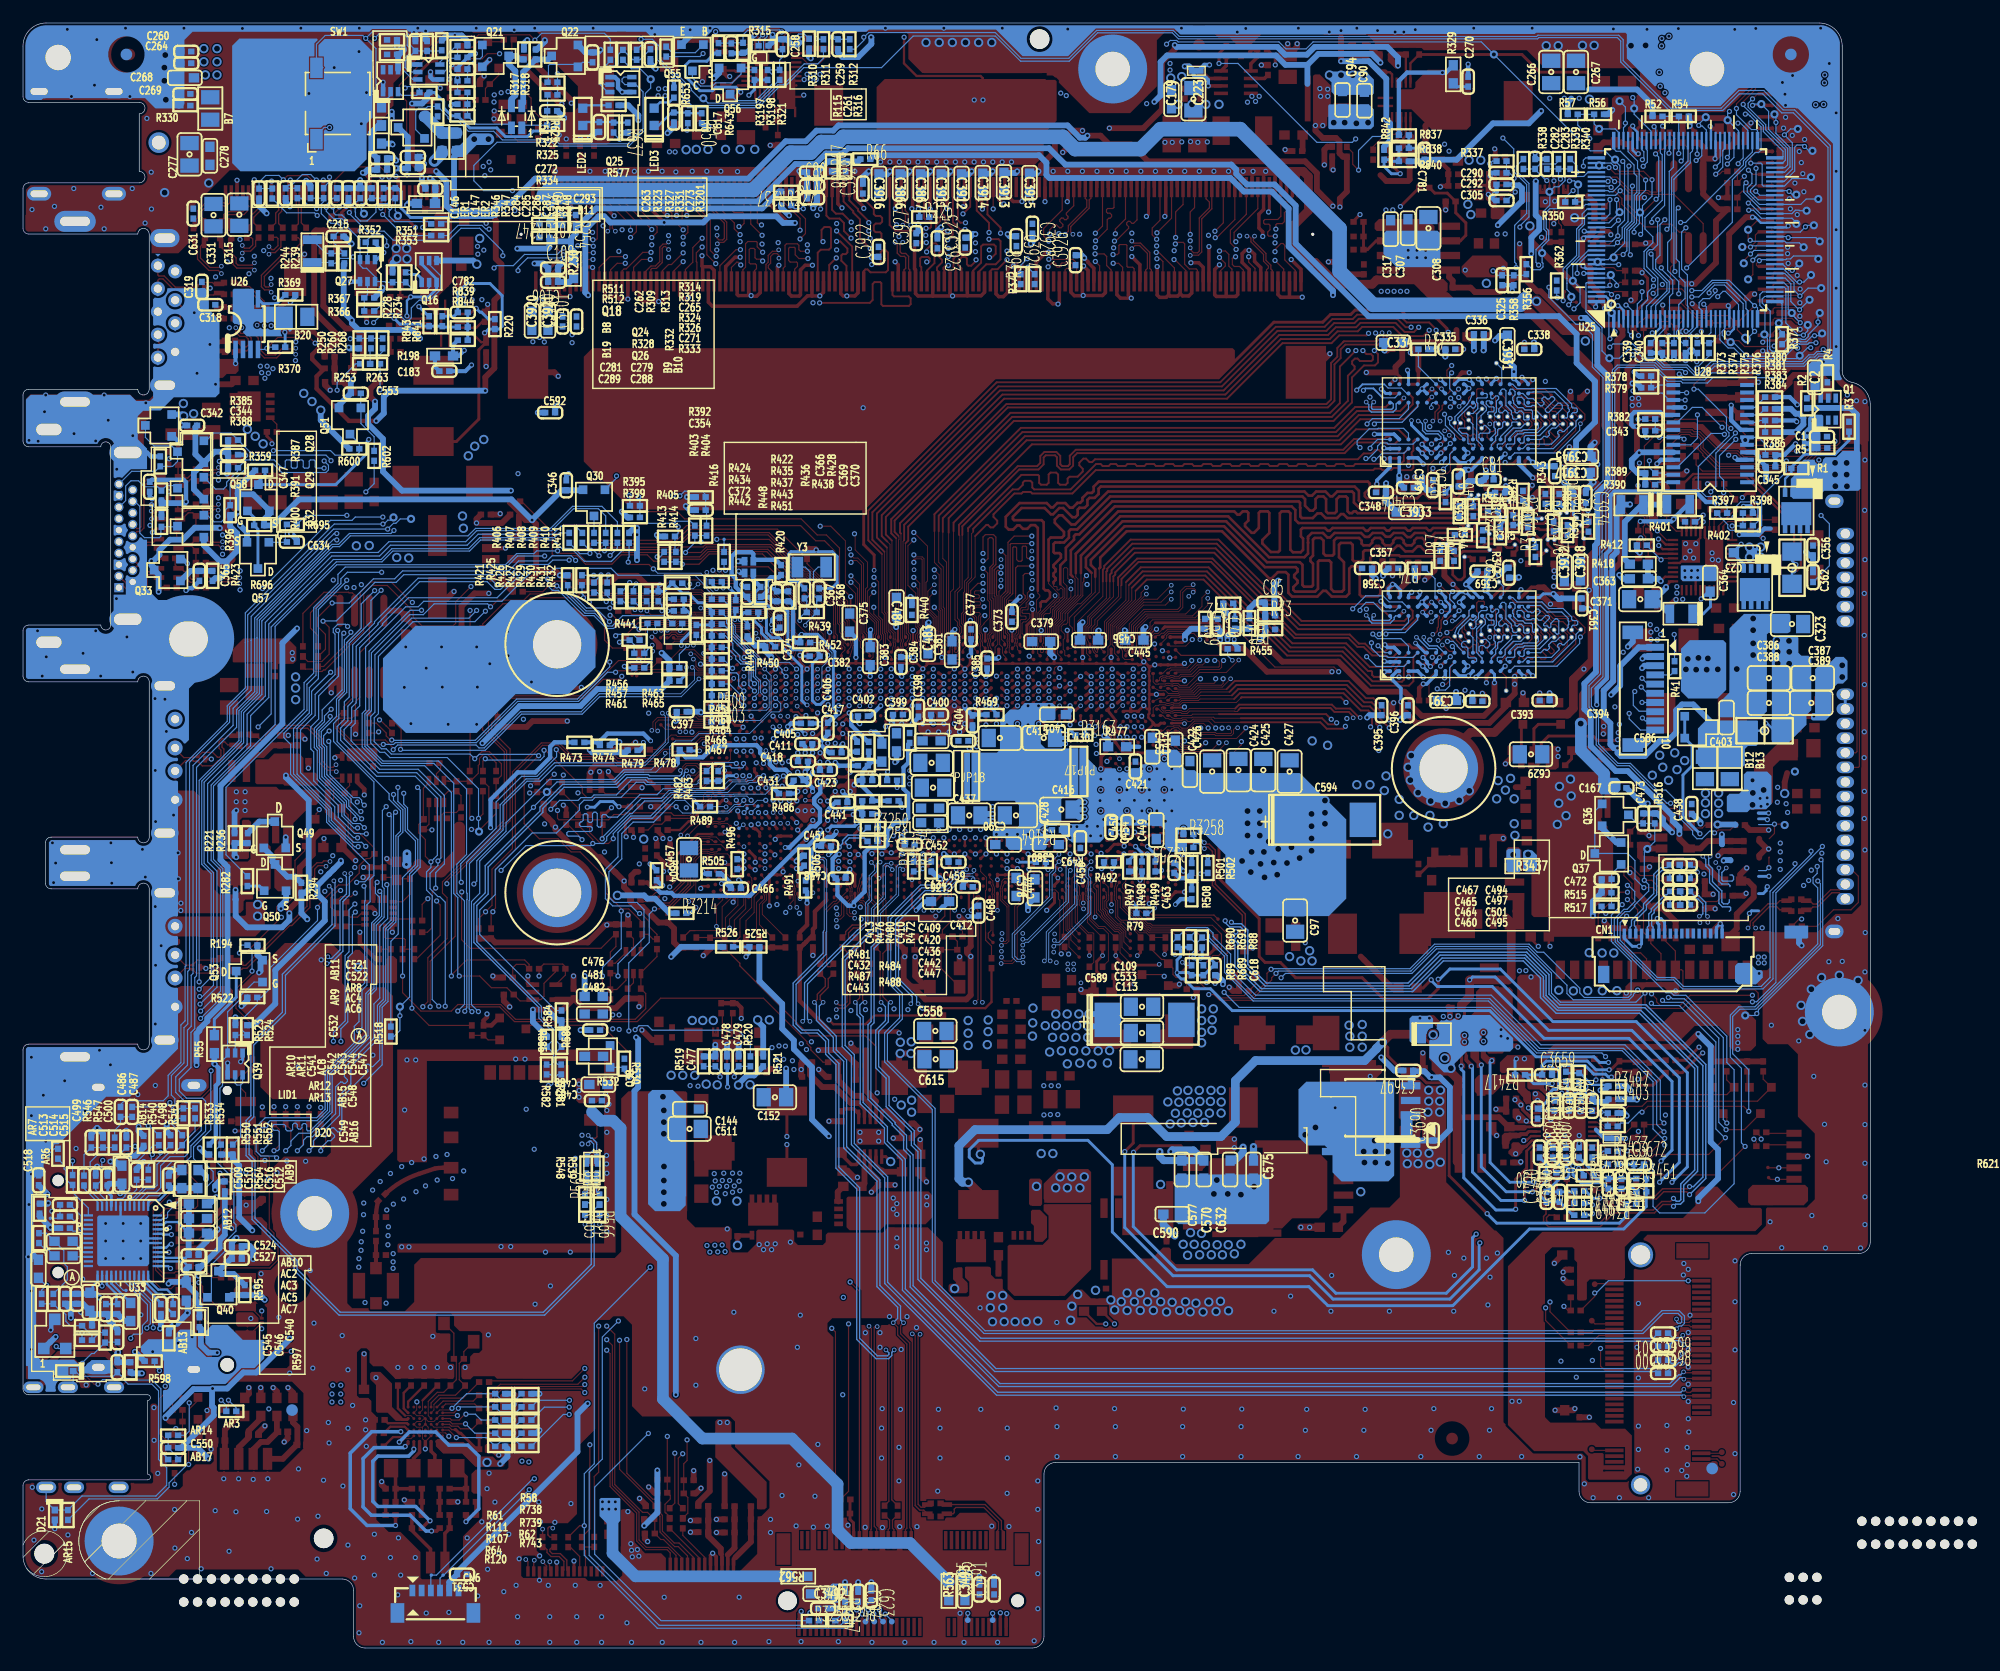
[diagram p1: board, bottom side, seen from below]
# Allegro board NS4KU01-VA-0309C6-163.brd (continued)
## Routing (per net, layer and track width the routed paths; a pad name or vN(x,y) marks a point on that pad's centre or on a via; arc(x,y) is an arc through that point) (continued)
PWRSW: length 128
  TOP w0.102: v1(22.55,119.39) 22.63,119.32 v3(22.63,118.5)
  L4_IN2 w0.102: v3(127.33,135.65) 125.04,135.65 123.52,137.17 122.16,137.17 121.71,137.62 114.78,137.62 114.16,138.23 102.93,138.23 102.14,137.45 100.47,137.45 100.17,137.74 93,137.74 92.48,137.22 89.83,137.22 89.43,136.81 73.95,136.81 71.09,133.95 67.61,133.95 66.69,133.02 51.45,133.02 50.82,133.65 41.42,133.65 39.35,131.58 32.21,131.58 v3(31.93,131.3) ; v3(30.78,120.02) 28.54,117.79 27.91,117.79 27.2,118.5 v3(22.63,118.5)
  BOTTOM w0.102: v3(22.63,118.5) 22.8,118.32 U25.125 ; Q18.3 127.63,135.01 126.33,135.01 R328.1 126.08,135.56 126.29,135.77 127.2,135.77 v3(127.33,135.65) ; v3(31.93,131.3) 30.98,130.35 30.98,128.38 29.86,127.26 29.86,124.75 30.91,123.71 30.91,120.51 30.78,120.38 v3(30.78,120.02)
R42_XTAL24_IN: length 28.7
  TOP w0.076: v2(100.28,62.75) 100.28,64.52 99.73,65.06 99.73,65.45 99.59,65.59 99.21,65.97 99.19,65.97 99.03,66.14 99.03,66.96 99.26,67.2 99.27,67.2 99.62,67.55 U11.E3 ; v2(79.07,62.62) 79.07,62.5 78.89,62.32 78.89,62.24
  TOP w0.102: R3087.1 78.89,62.24
  L4_IN2 w0.076: 89.88,62.24 90.42,62.77 98.8,62.77 98.99,62.96 99.28,62.96 99.49,62.75 v2(100.28,62.75) ; 86,62.24 85.24,63 82.06,63 81.68,62.62 v2(79.07,62.62)
  L4_IN2 w0.102: 86,62.24 86.1,62.14 89.78,62.14 89.88,62.24
R42_XTAL24_OUT: length 21.3
  TOP w0.076: v2(83.82,62.62) 83.82,62.24 ; U11.C7 97.48,66.43 97.9,66.01 97.9,64.61 99.13,63.38 v2(99.13,62.62)
  TOP w0.102: 83.82,62.24 R3095.1
  L4_IN2 w0.076: v2(99.13,62.62) 90.7,62.62 90.32,62.24 ; v2(83.82,62.62) 85.31,62.62 85.69,62.24
  L4_IN2 w0.102: 85.69,62.24 86.01,61.92 90,61.92 90.32,62.24
RSNA: length 4.1
  TOP w0.203: U109.37 25.98,48.06 26.06,48.14 26.06,48.96 C3662.1 26.14,50.19 C3661.1 25.05,50.27 R3405.2
RSNB: length 6.3
  TOP w0.203: U109.18 27.58,42.35 27.64,42.28 27.64,41.64 27.77,41.52 27.77,40.23 C3695.1 28.39,39.33 R3442.2 26.59,38.47 C3694.1
RSNC: length 4.6
  TOP w0.127: U109.11 24.78,42.33 24.66,42.21 24.66,41.47 C3684.1 23,40.92 C3689.1 R3436.2
RSP_LLA: length 3.1
  TOP w0.203: R3402.1 27.01,50.09 C3662.2 26.38,48.42 U109.36
RSP_LLB: length 3.3
  TOP w0.203: C3695.2 27.24,39.9 R3440.1 27.33,40.87 27.33,42.17 27.18,42.32 U109.17
RSP_LLC: length 3
  TOP w0.127: R3429.1 24.98,39.88 C3684.2 24.93,40.97 24.93,42.1 25.18,42.35 U109.12
RTC_RST#: length 22.6
  TOP w0.076: U11.AM16 92.4,81.99 v2(92.4,82)
  BOTTOM w0.254: v2(92.4,82) 92.47,82 92.86,82.39 92.86,85.33 94.54,87.01 94.54,87.55 94.85,87.86 95.48,87.86 95.93,88.31 95.93,90.28 96.21,90.56 96.92,90.56 97.58,91.22 C366.1
  BOTTOM w0.381: C366.1 97.73,91.4 98.6,92.26 98.6,93 98.95,93.35 98.95,94.9 98.57,95.29 97.23,95.29 97.07,95.13 JP11.1 96.95,94.62 95.12,94.62 R420.2
RTC_X1: length 15.5
  TOP w0.102: v3(90.57,82.02) 90.57,81.94 U11.AM18
  L4_IN2 w0.102: v2(93.03,89.34) 93.03,89.19 93.31,88.91 93.31,87.97 91.09,85.74 91.09,82.47 90.65,82.02 v3(90.57,82.02)
  BOTTOM w0.102: Y3.1 92.55,93.99 92.15,93.58 92.15,91.6 92.48,91.27 C367.2 92.42,91.07 R439.1 92.55,90.05 93.03,89.57 v2(93.03,89.34)
RTC_X2: length 15.6
  TOP w0.14: v3(89.66,81.94) U11.AM20
  L4_IN2 w0.14: v3(89.66,81.94) 89.73,81.94 90.16,82.38 90.16,85.38 90.7,85.91 90.77,85.91 92.25,87.39 92.25,88.63 v2(92.55,88.93)
  BOTTOM w0.102: Y3.2 91.43,93.99 91.84,93.58 91.84,91.57 91.54,91.27 C368.2 91.56,91.07 R439.2 92.53,89.09 92.53,88.93 92.55,88.91 v2(92.55,88.93)
RUN_ON_CPU_R: length 28.3
  TOP w0.102: U14.5 99.76,49.87 v3(99.96,49.67) ; v3(115.69,58.43) R117.2 115.28,59.47 113.63,59.47 113.41,59.24 R113.2 113.41,58.51 Q10.4
  L3_IN1 w0.102: v3(115.69,58.43) 115,58.43 109.89,53.32 108.88,53.32 105.99,50.43 101.93,50.43 101.47,49.97 100.26,49.97 v3(99.96,49.67)
  BOTTOM w0.102: R519.1 C477.1 99.96,50.16 v3(99.96,49.67)
RXN: length 17.2
  TOP w0.076: U1634.F5 126.33,18.7 127.6,18.7 v3(127.71,18.81)
  TOP w0.305: C505.1 v3(128.17,10.66)
  BOTTOM w0.305: v3(127.71,18.81) 130.23,18.81 132.1,16.94 132.1,12.12 130.64,10.66 v3(128.17,10.66)
RXP: length 16.4
  TOP w0.076: v3(127.84,17.91) 127.64,17.91 127.35,18.2 126.83,18.2 U1634.F6
  TOP w0.305: C507.1 v3(122.04,10.98)
  BOTTOM w0.305: v3(122.04,10.98) 120.93,12.1 120.93,16.69 121.88,17.64 123.53,17.64 124.67,18.78 126.96,18.78 v3(127.84,17.91)
SA0_DIM1: length 4.4
  TOP w0.102: CN11.256 115.22,126.07 115.04,125.89 114.66,125.89 114.41,125.63 114.41,125.38 v3(114.09,125.06)
  BOTTOM w0.102: R254.1 R246.2 113.65,124.62 v3(114.09,125.06)
SA1_DIM1: length 4.9
  TOP w0.102: CN11.260 116.22,125.54 v3(115.3,124.62)
  BOTTOM w0.102: v3(115.3,124.62) 115.66,124.25 R247.2 R207.1
SA2_DIM1: length 4.3
  TOP w0.102: CN11.166 v3(92.72,125.16)
  BOTTOM w0.102: v3(92.72,125.16) 93.5,125.16 R227.2 R237.1
SAFTY_PROTECT: length 40.9
  TOP w0.102: v3(12.31,103.72) 12.31,103.72 12.13,103.9 11.59,103.9 11.08,103.39 7.91,103.39 7.68,103.62 5.67,103.62 4.36,104.93 v3(3.07,104.93)
  L4_IN2 w0.102: v3(12.31,103.72) 12.31,104.33 13.26,105.29 13.26,108.52 12.65,109.14 12.65,111.82 11.96,112.5 11.96,117.92 13.46,119.42 13.46,120.98 15.19,122.71 17.88,122.71 18.74,123.57 19.13,123.57 19.71,124.15 v3(21.89,124.15)
  BOTTOM w0.102: v3(21.89,124.15) 22.52,123.52 U25.112
SATA_5V:
  vias: v3(7.82,69.99) v3(7.82,69.22) v3(7.82,68.46) v3(7.82,67.7) v3(9.22,60.08) v3(9.22,59.57) v3(9.72,60.08) v3(9.72,59.57)
SATA_DET#: length 8.2
  TOP w0.076: U11.H2 100.26,69.22 100.49,69.22 100.62,69.16 100.73,69.16 101.03,69.28 101.58,69.28 102.23,68.63 102.23,66.35 102.41,66.17
  TOP w0.102: 102.41,66.17 104.47,64.11 R144.1
SATA_ODD_PRSNT_R_N: length 11.2
  TOP w0.076: U11.H3 99.46,69.45 99.87,69.86 101.58,69.86 102.41,69.03
  TOP w0.102: 102.41,69.03 102.75,68.69 102.75,66.41 104.38,64.78 105.07,64.78 105.2,64.91 106.73,64.91 R154.1
SATA_RXN0: length 97.5
  TOP w0.114: U11.F20 90.11,68.64 89.88,68.41 v3(89.66,68.41)
  L4_IN2 w0.114: v3(89.66,68.41) 89.66,68.4 89.86,68.2 90.1,68.2 90.37,67.93 90.37,65.86 88.97,64.46 88.97,63.18 88.55,62.76 87.13,62.76 85.35,64.54 70.57,64.54 68.02,61.99 57.71,61.99 51.9,56.18 39.8,56.18 39.7,56.09 31.52,56.09 29.33,53.9 17.27,53.9 16.9,54.27 14.68,56.49 14.68,60.32 16.15,61.8 v2(16.15,65.21)
  BOTTOM w0.114: C464.2 16.53,65.58 v2(16.15,65.21)
SATA_RXN0_C: length 4.6
  BOTTOM w0.114: C464.1 17.69,65.49 17.82,65.49 17.94,65.36 18.11,65.19 19.03,64.27 19.03,64.04 19.25,63.82 19.25,62.8 19.37,62.68 CN1.5
SATA_RXN0_R: length 45.5
  L4_IN2 w0.114: v2(14.14,63.61) 14.3,63.76 14.3,64.4 13.93,64.77 4.21,64.77 3.58,64.13 1.6,64.13 1.03,64.71 1.03,90.94 1.31,91.22 1.58,91.22 CN9.S5
  BOTTOM w0.114: C501.1 15.29,65.41 14.9,65.41 14.3,64.81 14.3,64.27 14.3,63.76 v2(14.14,63.61)
SATA_RXN2: length 108.4
  TOP w0.076: U11.E30 v2(84.07,67.68)
  BOTTOM w0.076: v2(84.07,67.68) 84.07,67.7 84.27,67.9 84.38,67.9 84.44,67.84 84.44,65.45 86.03,63.86 86.03,62.35 86.01,62.34 86.01,62.27 85.99,62.25 85.99,62.24
  BOTTOM w0.114: 85.99,62.24 85.99,61.44 86.58,60.85 86.58,54.37 86.85,54.1 86.85,47.8 84.74,45.69 84.74,45.56 83.76,44.58 83.76,43.44 83.18,42.87 83.18,31.5 75.99,24.3 18.44,24.3 18.31,24.43 18.31,24.9 C3499.1
SATA_RXP0: length 97.5
  TOP w0.114: v3(89.66,67.77) 89.66,67.92 89.76,68.03 90.08,68.03 U11.E20
  L4_IN2 w0.114: v3(89.66,67.77) 89.66,67.9 89.73,67.98 89.99,67.98 90.15,67.81 90.15,67.6 90.09,67.54 90.04,67.48 90.04,67.02 90.09,66.97 90.15,66.91 90.15,66.59 90.04,66.48 90.04,66.22 90.15,66.11 90.15,65.95 89.92,65.71 89.75,65.71 89.51,65.47 89.51,65.3 89.2,65 89.01,65 88.75,64.74 88.75,63.27 88.46,62.98 87.22,62.98 85.44,64.75 70.48,64.75 67.93,62.2 57.62,62.2 51.81,56.4 39.71,56.4 39.61,56.31 31.43,56.31 29.24,54.12 17.36,54.12 14.89,56.58 14.89,60.24 16.37,61.71 16.37,64.88 16.69,65.21 v2(16.91,65.21)
  BOTTOM w0.114: C495.2 16.53,65.06 16.67,65.21 v2(16.91,65.21)
SATA_RXP0_C: length 4.6
  BOTTOM w0.114: C460.1 17.39,65.09 17.53,65.24 17.71,65.24 17.77,65.18 17.93,65.01 18.78,64.17 18.78,63.93 19,63.72 19,62.8 18.87,62.68 CN1.6
SATA_RXP0_R: length 45.5
  L4_IN2 w0.114: v2(14.85,63.63) 14.76,63.63 14.55,63.84 14.55,64.45 14.02,64.98 4.12,64.98 3.49,64.35 1.69,64.35 1.24,64.8 1.24,90.85 1.4,91 2.06,91 2.17,90.89 CN9.S6
  BOTTOM w0.114: v2(14.85,63.63) 14.76,63.63 14.55,63.84 14.55,64.38 14.55,64.71 14.98,65.14 15.62,65.14 15.77,64.98 15.77,64.72 C495.1
SATA_RXP2: length 108.4
  TOP w0.076: U11.F30 v2(84.08,68.31)
  BOTTOM w0.076: v2(84.08,68.31) 84.27,68.12 84.47,68.12 84.65,67.93 84.65,65.54 86.24,63.95 86.24,62.24
  BOTTOM w0.114: C3498.1 18.59,24.04 76.09,24.04 83.44,31.39 83.44,42.77 84.01,43.34 84.01,44.47 85,45.46 85,45.59 87.11,47.69 87.11,54.2 86.83,54.47 86.83,60.95 86.24,61.54 86.24,62.24
SATA_TXN0: length 98.6
  TOP w0.076: v2(89.8,63.8) 89.6,63.6 89.57,63.6 89.41,63.75 89.41,64.89 89.41,64.89 89.41,65.31 88.92,65.8 U11.B21
  L4_IN2 w0.114: v2(89.8,63.8) 89.64,63.64 89.56,63.64 89.26,63.34 89.26,63.04 88.77,62.54 86.89,62.54 85.8,63.64 81.77,63.64 81.35,63.22 77.91,63.22 77.43,63.7 70.19,63.7 68.1,61.62 57.93,61.62 52.08,55.77 39.97,55.77 39.88,55.67 31.69,55.67 29.46,53.43 17.13,53.43 14.24,56.33 14.24,60.63 15.6,61.99 15.6,65.27 16.52,66.19 16.52,67.21 16.81,67.49 v2(16.91,67.49)
  BOTTOM w0.114: C465.2 16.55,67.24 16.8,67.49 v2(16.91,67.49)
SATA_TXN0_C: length 7.7
  BOTTOM w0.114: C465.1 17.42,67.31 17.71,67.61 18.12,67.61 18.56,67.16 18.56,65.49 19.45,64.61 19.45,64.21 20.5,63.17 20.5,62.8 20.37,62.68 CN1.3
SATA_TXN0_R: length 44
  L4_IN2 w0.114: CN9.S3 2.17,94.62 2.3,94.75 2.78,94.75 3.12,94.41 3.12,92.8 3.29,92.63 3.29,66.34 4.17,65.45 9.64,65.45 10.4,66.22 14.97,66.22 15.36,66.61 15.36,67.12 15.57,67.32 v2(15.57,67.45)
  BOTTOM w0.114: C497.1 15.57,67.03 v2(15.57,67.45)
SATA_TXN2: length 97.8
  TOP w0.102: v2(85.97,56.14) 86.05,56.23 86.05,60.54 R3232.1
  BOTTOM w0.114: C3500.2 18.88,26.68 77.39,26.68 82.77,32.05 82.77,43.15 83.34,43.72 83.34,44.88 85.53,47.07 85.53,49.55 86.43,50.45 86.43,53.71 85.59,54.55 85.59,55.76 v2(85.97,56.14)
SATA_TXP0: length 98.6
  TOP w0.076: v2(89.86,63.28) 89.76,63.38 89.48,63.38 89.2,63.66 89.2,64.8 89.2,64.8 89.2,65.22 89.08,65.33 88.98,65.33 U11.A21
  L4_IN2 w0.114: v2(16.15,67.49) 16.31,67.34 16.31,66.28 15.38,65.36 15.38,62.08 14.02,60.72 14.02,56.24 17.04,53.22 29.55,53.22 31.78,55.45 39.97,55.45 40.06,55.55 52.17,55.55 58.02,61.4 68.19,61.4 70.28,63.48 77.34,63.48 77.82,63 81.44,63 81.86,63.42 85.71,63.42 86.8,62.33 88.86,62.33 89.51,62.98 89.51,63.28 89.61,63.38 89.76,63.38 v2(89.86,63.28)
  BOTTOM w0.114: v2(16.15,67.49) 16.15,67.52 16.55,67.93 C494.2
SATA_TXP0_C: length 7.7
  BOTTOM w0.114: CN1.2 20.87,62.68 20.75,62.8 20.75,63.27 19.71,64.32 19.71,64.71 18.82,65.6 18.82,67.27 18.23,67.86 17.67,67.86 C467.1
SATA_TXP0_R: length 44
  L4_IN2 w0.114: v2(15.01,67.45) 15.1,67.35 15.1,66.65 14.88,66.43 10.31,66.43 9.55,65.67 4.26,65.67 3.5,66.43 3.5,92.72 3.34,92.89 3.34,94.5 2.21,95.62 CN9.S2
  BOTTOM w0.114: C494.1 15.5,67.91 15.24,67.91 15.01,67.68 v2(15.01,67.45)
SATA_TXP2: length 97.8
  TOP w0.102: v2(85.13,56.14) 85.32,56.14 85.81,56.63 85.81,60.4 R3152.1
  BOTTOM w0.114: v2(85.13,56.14) 85.28,56.14 85.33,56.09 85.33,54.45 86.18,53.6 86.18,50.56 85.28,49.65 85.28,47.18 83.08,44.98 83.08,43.82 82.51,43.25 82.51,32.16 77.29,26.93 18.88,26.93 C3501.2
SCL_OZ8690: length 1.9
  TOP w0.102: U1.7 13.97,98.93 R14.2
SD3_CD#: length 91.2
  TOP w0.076: v3(96.18,75.85) 95.72,75.39 U11.W10
  TOP w0.102: v3(137.23,25.79) 137.41,25.79 137.51,25.68 R286.1 ; R173.1 110.2,71.54 110.2,70.37 v3(110.21,70.37)
  L4_IN2 w0.102: v3(138.5,42.63) 137.92,42.04 137.92,29.62 136.98,28.68 136.98,26.04 v3(137.23,25.79) ; v3(110.21,70.37) 111.16,70.37 112.42,69.11 117.43,69.11 118.24,68.29 122.2,68.29 123.18,67.31 127.45,67.31 128.9,65.86 129.04,65.86 129.38,66.2 130.86,66.2 v3(130.91,66.25)
  BOTTOM w0.076: v3(96.18,75.85) 96.71,75.85 97.12,75.44 97.53,75.44 97.66,75.31 98.89,75.31 99.64,74.56 104.41,74.56 104.79,74.18
  BOTTOM w0.102: v3(130.91,66.25) 130.8,66.14 130.8,64.98 130.85,64.92 130.85,57.82 131.34,57.33 131.34,54.47 131.75,54.06 131.75,52.63 134.28,50.1 134.28,46.84 135.01,46.11 139.49,46.11 140.28,45.32 140.28,43.19 139.87,42.78 138.66,42.78 v3(138.5,42.63) ; v3(110.21,70.37) 110.21,70.47 106.79,73.88 105.09,73.88 104.79,74.18
SD3_CLK: length 77.3
  TOP w0.076: U11.W8 97.1,75.39 97.39,75.85 v3(97.4,75.85)
  TOP w0.102: R265.1 136.23,45.08 136.23,43.71 v3(136.7,43.24) ; R176.2 113.18,71.59 111.96,70.37 v3(111.96,70.29)
  L4_IN2 w0.14: v3(128.92,66.38) 127.57,67.73 123.73,67.73 122.7,68.76 118.41,68.76 117.65,69.52 112.7,69.52 111.96,70.26 v3(111.96,70.29)
  BOTTOM w0.076: 105.13,74.51 104.91,74.72 99.92,74.72 99.16,75.48 97.79,75.48 97.42,75.85 v3(97.4,75.85)
  BOTTOM w0.102: v3(128.92,66.38) 128.85,66.3 128.85,63.42 129.53,62.74 129.53,56.51 130.04,56.01 130.04,53.02 132.61,50.46 132.61,49.68 132.35,49.42 132.35,49.28 132.53,49.09 132.67,49.09 132.79,49.21 132.94,49.21 133.37,48.78 133.37,46.46 135.37,44.46 135.86,44.46 136.16,44.15 136.16,43.77 v3(136.7,43.24) ; v3(111.96,70.29) 112.26,70.59 113.16,70.59 113.28,70.71 113.28,70.88 113.16,71 111.19,71 111.07,71.13 111.07,71.31 111.19,71.43 112.06,71.43 112.19,71.56 112.19,71.71 112.06,71.84 111.98,71.84 111.86,71.97 111.86,72.43 111.74,72.55 111.57,72.55 111.45,72.43 111.45,71.91 111.33,71.79 111.16,71.79 111.04,71.91 111.04,72.56 110.92,72.68 110.76,72.68 110.64,72.56 110.64,71.5 110.52,71.38 110.35,71.38 110.23,71.5 110.23,72.37 110.13,72.47 109.9,72.47 109.67,72.25 108.88,72.25 106.93,74.2 105.44,74.2 105.13,74.51
SD3_CMD: length 75.9
  TOP w0.076: U11.AB11 95.02,76.95 v3(95.12,77.05)
  TOP w0.102: R270.1 137.26,45.1 137.26,43.69 v3(137.71,43.24) ; v3(114.37,75.98) 114.83,75.52 R179.1
  L4_IN2 w0.076: 106.62,76.32 104.55,76.32 103.21,74.98 99.57,74.98 99.1,75.45 96.81,75.45 96.78,75.48 96.03,75.48 95.82,75.7 95.82,76.17 95.12,76.87 v3(95.12,77.05)
  L4_IN2 w0.102: v3(114.37,75.98) 114.07,76.28 111.88,76.28 111.3,75.7 109.36,75.7 108.74,76.32 106.62,76.32
  L4_IN2 w0.14: v3(128.98,73.16) 128.97,73.16 128.93,73.21 126.53,73.21 125.64,74.09 118.75,74.09 117.08,75.76 114.59,75.76 v3(114.37,75.98)
  BOTTOM w0.102: v3(137.71,43.24) 137.26,43.7 137.26,44.08 136.57,44.76 135.5,44.76 133.67,46.59 133.67,49.84 130.35,53.17 130.35,56.74 129.84,57.25 129.84,62.86 129.15,63.55 129.15,66.05 129.31,66.2 129.31,72.83 v3(128.98,73.16)
SD3_D0: length 75.9
  TOP w0.076: U11.AB13 93.72,76.82 v3(94,77.1)
  TOP w0.102: v3(116.43,74.97) 116.11,75.29 R475.1 ; R255.1 135.24,45.11 135.24,43.68 v3(135.68,43.24)
  L4_IN2 w0.076: v3(94,77.1) 94,77.01 94.79,76.22 95.33,76.22 95.51,76.04 95.51,75.57 95.91,75.17 96.59,75.17 96.62,75.15 98.41,75.15 98.88,74.67 103.49,74.67 104.59,75.78 106.39,75.78
  L4_IN2 w0.14: v3(128.72,72.47) 128.52,72.27 126.74,72.27 125.4,73.61 118.55,73.61 117.19,74.97 v3(116.43,74.97) 116.35,74.97 116.35,74.98 115.56,74.98 115.08,74.51 113.91,74.51 112.92,75.5 111.91,75.5 111.58,75.17 108.94,75.17 108.33,75.78 106.39,75.78
  BOTTOM w0.102: v3(135.68,43.24) 135.3,43.62 135.3,44.1 134.74,44.66 134.6,44.66 134.39,44.44 134.24,44.44 134.11,44.58 134.11,44.74 134.29,44.92 134.29,45.06 133.03,46.32 133.03,48.07 132.04,49.05 132.04,50.58 129.74,52.89 129.74,55.88 129.23,56.39 129.23,62.61 128.54,63.3 128.54,72.3 v3(128.72,72.47)
SD3_D1: length 75.7
  TOP w0.076: U11.AB12 94.56,76.64 v3(94.56,76.97)
  TOP w0.102: R177.1 113.69,75.8 v3(113.58,75.9) ; v3(134.66,43.24) 134.23,43.67 134.23,45.11 R248.1
  L4_IN2 w0.076: 106.62,76.11 104.58,76.11 103.29,74.82 99.35,74.82 98.87,75.3 96.75,75.3 96.73,75.33 95.97,75.33 95.66,75.64 95.66,76.11 95.33,76.44 95.09,76.44 v3(94.56,76.97)
  L4_IN2 w0.102: 106.62,76.11 108.66,76.11 109.3,75.47 111.42,75.47 111.98,76.03 113.46,76.03 v3(113.58,75.9)
  L4_IN2 w0.14: v3(128.16,72.68) 126.71,72.68 125.54,73.85 118.65,73.85 117.13,75.37 115.1,75.37 114.89,75.17 114.09,75.17 113.58,75.67 v3(113.58,75.9)
  BOTTOM w0.102: v3(128.16,72.68) 128.34,72.5 128.34,63.21 129.03,62.53 129.03,56.3 129.53,55.79 129.53,51.16 130.15,50.55 130.29,50.55 130.5,50.76 130.64,50.76 130.79,50.62 130.79,50.47 130.58,50.26 130.58,50.12 132.83,47.87 132.83,45.08 133.03,44.87 133.18,44.87 133.55,45.24 133.69,45.24 133.83,45.1 133.83,44.95 133.46,44.58 133.46,44.44 133.79,44.11 134.04,44.11 134.66,43.48 v3(134.66,43.24)
SD3_D2: length 78.3
  TOP w0.076: U11.W12 94.37,75.74 v3(94.46,75.83)
  TOP w0.102: R280.1 139.23,45.06 139.23,43.76 v3(139.74,43.24) ; v3(109.24,70.37) 109.66,69.96 110.34,69.96 111.3,70.92 R167.1
  L4_IN2 w0.14: v3(109.24,70.37) 109.69,70.82 112.02,70.82 112.98,69.86 117.79,69.86 117.85,69.8 117.86,69.8 118.45,69.22 126.03,69.22 126.67,68.58 127.48,68.58 129.48,66.58 v3(129.76,66.58)
  BOTTOM w0.076: v3(94.46,75.83) 94.94,75.34 95.28,75.34 95.61,75.02 95.61,74.65 96.01,74.25 98.77,74.25 98.79,74.23 104.11,74.23 104.48,73.86
  BOTTOM w0.102: v3(129.76,66.58) 129.92,66.43 129.92,65.64 129.57,65.3 129.57,63.7 130.25,63.03 130.25,57.42 130.75,56.91 130.75,53.34 134.08,50.01 134.08,46.76 134.98,45.85 139.07,45.85 139.27,45.65 139.27,45.34 139.37,45.24 139.87,45.24 139.97,45.14 139.97,44.93 139.87,44.83 139.04,44.83 138.9,44.69 138.9,44.52 139.28,44.14 139.28,43.71 v3(139.74,43.24) ; 104.48,73.86 105.99,72.35 107.72,72.35 109.24,70.82 v3(109.24,70.37)
SD3_D3: length 77.5
  TOP w0.076: v3(95.02,75.8) 95.02,75.79 U11.W11
  TOP w0.102: R275.1 138.25,45.08 138.25,43.71 v3(138.73,43.24) ; R171.1 111.02,70.29 v3(111.02,69.96)
  L4_IN2 w0.14: v3(118.99,67.62) 119.36,67.99 120.45,67.99 120.67,67.77 120.67,67.51 120.87,67.32 121.06,67.32 121.23,67.49 121.23,67.86 121.36,67.99 122.19,67.99 123.09,67.09 127.36,67.09 128.83,65.62 129.36,65.62 v3(129.53,65.79)
  BOTTOM w0.076: v3(95.02,75.8) 95.07,75.85 95.32,75.85 95.71,75.47 96.6,75.47 96.82,75.24 97.43,75.24 97.54,75.13 98.56,75.13 99.3,74.39 104.26,74.39 104.64,74.02
  BOTTOM w0.102: 104.64,74.02 105,73.65 106.52,73.65 107.62,72.55 107.8,72.55 109.81,70.54 109.81,70.22 110.08,69.96 v3(111.02,69.96) 111.2,69.77 116.84,69.77 v3(118.99,67.62) ; v3(129.53,65.79) 129.37,65.63 129.37,63.62 130.04,62.95 130.04,57.33 130.55,56.82 130.55,53.25 133.88,49.93 133.88,46.67 135.58,44.97 135.79,44.97 135.89,45.07 135.89,45.48 136.01,45.6 136.17,45.6 136.29,45.48 136.29,45.24 136.41,45.12 136.58,45.12 136.7,45.24 136.7,45.51 136.82,45.63 136.99,45.63 137.11,45.51 137.11,45.09 137.23,44.97 137.58,44.97 137.71,45.1 137.71,45.4 137.84,45.52 138.73,45.52 138.86,45.4 138.86,45.14 138.73,45.02 138.4,45.02 138.27,44.89 138.27,43.37 138.4,43.24 v3(138.73,43.24)
SD3_PWREN0: length 7.7
  BOTTOM w0.102: 141.63,48.95 141.94,48.95 142.11,49.11 Q39.5 ; 141.63,48.95 141.63,44.45 R552.2 ; 141.63,48.95 141.46,49.12 Q39.6
SD3_PWREN1: length 31.3
  BOTTOM w0.102: Q40.G 144.17,30.83 144.17,33.33 143,34.5 143,35.28 142.03,36.25 142.03,36.81 142.21,36.99 142.21,40.77 143.76,42.31 143.76,43.34 R551.2 143.43,43.87 143.43,48.67 143.2,48.9 143.2,51.08 142.76,51.53 Q39.3 142.76,55.31 141.63,56.44 141.63,56.73 140.46,57.9 Q53.G
SD3_PWREN#: length 92.2
  TOP w0.076: 106.6,85.76 106.45,85.92 106.45,88.63 106.06,89.01 103.93,89.01 103.7,89.24 99.45,89.24 98.93,88.72 96.82,88.72 96.47,88.37 96.47,88.09 96.36,87.98 96.36,87.68 96.11,87.42 U11.BA9
  TOP w0.102: 106.6,85.76 106.86,85.5 107.67,85.5 108.02,85.86 108.78,85.86 111.85,82.8 118.91,82.8 120.09,81.61 120.09,79.6 118.51,78.03 118.51,71.9 123.7,66.71 v3(123.7,66.46) ; v3(134.95,64.4) 134.95,64.52 133.12,66.35 132.35,66.35 131.32,67.38 131.32,68.03 130.71,68.65 130.4,68.65 R285.1 129.99,69.54 131.33,70.88 131.64,70.88 132.06,71.29 132.06,74.02 131.77,74.3 R527.1
  L4_IN2 w0.102: v3(123.7,66.46) 123.91,66.66 127.18,66.66 128.66,65.19 130.02,65.19 130.39,65.57 131.05,65.57 131.74,66.25 133.19,66.25 133.75,65.69 133.78,65.69 134.95,64.53 v3(134.95,64.4)
  BOTTOM w0.102: Q39.2 142.11,53.27 R523.2 R524.2 141.63,53.86 141.63,54.54 140.18,55.99 R522.1 139.85,56.57 139.09,57.33 139.09,59.11 134.95,63.26 v3(134.95,64.4)
SD3_WP: length 75.9
  TOP w0.076: U11.W7 97.63,75.48 97.98,75.84 v3(97.98,75.85)
  TOP w0.102: R295.1 140.61,54.21 142.03,55.63 142.03,57.31 140.64,58.7 v3(140.64,58.86) ; R258.1 136.07,69.32 136.9,68.48 136.9,65.42 137.65,64.67 138.27,64.67 138.5,64.45 138.5,63.95 v3(138.08,63.54) 138.22,63.4 138.23,63.4 141.17,60.46 141.7,60.46 v3(141.73,60.43)
  L3_IN1 w0.076: v3(97.98,75.85) 98.63,75.19 99.55,75.19 101.73,73.01 101.73,70.6 102.41,69.92
  L3_IN1 w0.102: v3(104.76,65.16) 104.34,65.16 103.45,66.05 103.45,68.87 102.41,69.92
  L4_IN2 w0.102: v3(104.76,65.16) 104.78,65.16 104.91,65.02 105.61,65.02 106.24,64.39 106.24,63.76 107.86,62.14 120.99,62.14 121.54,62.69 137.6,62.69 138.08,63.18 v3(138.08,63.54)
  BOTTOM w0.102: v3(140.64,58.86) 140.64,60.69 141.03,61.08 R194.2 141.58,61.12 141.73,60.97 v3(141.73,60.43)
SD_1P8_SEL: length 75.1
  TOP w0.076: 106.6,88.83 106.25,89.17 104,89.17 103.77,89.4 99.38,89.4 98.86,88.89 96.59,88.89 96.22,88.51 96.22,88.22 96.11,88.11 U11.BB9
  TOP w0.102: 106.6,88.83 106.78,88.83 107,88.6 v3(107,88.58) 106.98,88.55 R150.2
  L4_IN2 w0.102: v3(115.21,94.95) 115.21,93.21 v3(114.94,92.95)
  BOTTOM w0.102: v3(114.94,92.95) 114.94,92.37 114.54,91.97 114.02,91.97 111.82,89.77 110.93,89.77 109.81,88.65 109.21,88.65 108.81,89.06 107.49,89.06 v3(107,88.58) ; v3(115.21,94.95) 117.56,94.95 118.53,93.99 132.54,93.99 133.17,93.35 133.17,92.58 135.28,90.47 135.28,84.77 136.12,83.93 136.12,81.62 142.9,74.84 142.9,68.97 R282.1
SD_CD#_CN: length 4
  TOP w0.102: R286.2 139,25.7 CRDR1.1 142.33,25.7 142.52,25.89 R42.1
SD_CLK_CN: length 30.2
  TOP w0.102: v3(136.7,47.07) R265.2 ; v3(143.43,41.28) 142.69,40.54 140.36,40.54 139.7,39.88 C239.2 139.85,39.7 CRDR1.7 142.5,39.7 R542.1
  L4_IN2 w0.14: v3(136.7,47.07) 136.7,47.86 136.89,48.06 141.63,48.06 142.36,47.33 145.06,47.33 145.18,47.2 145.18,46.92 145.06,46.79 144.28,46.79 144.15,46.67 144.15,46.43 144.29,46.29 145.29,46.29 145.47,46.11 145.47,45.91 145.29,45.73 144.6,45.73 144.46,45.59 144.46,45.31 144.6,45.17 145.13,45.17 145.26,45.04 145.26,44.74 145.13,44.61 144.6,44.61 144.46,44.47 144.46,44.19 144.6,44.05 144.69,44.05 144.82,43.91 144.82,43.66 144.66,43.49 144.6,43.49 144.46,43.35 144.46,43.07 144.6,42.93 145.21,42.93 145.33,42.81 145.33,42.5 145.21,42.38 144.62,42.38 144.04,41.79 143.55,41.79 143.43,41.66 v3(143.43,41.28)
SD_CMD_CN: length 30.1
  TOP w0.102: R545.1 142.45,32.2 CRDR1.4 140.63,32.2 140.36,31.93 v3(140.36,31.4) ; R270.2 v3(137.71,47.07)
  L4_IN2 w0.14: v3(137.71,47.07) 138.35,47.72 141.36,47.72 142.11,46.97 143.39,46.97 143.53,46.83 143.53,46.55 143.39,46.41 143.11,46.41 142.97,46.27 142.97,46 143.11,45.86 143.54,45.86 143.68,45.72 143.68,42.35 143.55,42.22 143.12,42.22 143,42.1 143,40.72 143.36,40.36 144.17,40.36 144.32,40.22 144.32,38.51 143.89,38.08 142.8,38.08 141.63,36.91 141.63,36.17 140.99,35.54 140.99,32.03 v3(140.36,31.4)
SD_D0_CN: length 30.3
  TOP w0.102: v3(135.68,47.07) R255.2 ; v3(141.17,41.36) 140.56,41.36 140.46,41.26 D7.1 140.13,41.55 140.13,42.73 140.38,42.98 140.38,43.74 140.76,44.12 CRDR1.9 142.47,44.12 R537.1
  L4_IN2 w0.14: v3(135.68,47.07) 135.56,47.07 135.28,46.79 135.28,46.59 135.38,46.49 140.86,46.49 141.31,46.04 141.31,43.89 141.07,43.65 141.07,43.34 141.19,43.21 141.32,43.21 141.45,43.09 141.45,42.83 141.32,42.71 140.58,42.71 140.46,42.58 140.46,40.11 140.58,39.99 140.96,39.99 141.09,39.86 141.09,39.58 140.94,39.43 140.55,39.43 140.31,39.19 140.31,37.91 140.55,37.68 140.89,37.68 141.98,38.76 141.98,38.9 141.84,39.04 141.75,39.04 141.57,39.22 141.57,39.49 141.71,39.63 141.87,39.63 142.01,39.77 142.01,40.05 141.87,40.19 141.71,40.19 141.57,40.33 141.57,41.22 141.43,41.36 v3(141.17,41.36)
SD_D1_CN: length 30.1
  TOP w0.102: R50.1 142.42,45.82 CRDR1.10 140.71,45.82 140.13,45.24 140.13,43.08 139.85,42.8 139.27,42.8 139.14,42.68 139.14,41.63 139.46,41.31 D7.2 139.46,41.04 v3(139.21,40.8) ; R248.2 v3(134.66,47)
  L4_IN2 w0.14: v3(134.66,47) 134.66,46.75 135.23,46.19 139.02,46.19 139.16,46.05 139.16,45.46 139.3,45.32 139.58,45.32 139.72,45.46 139.72,46.05 139.86,46.19 140.53,46.19 140.91,45.8 140.91,43.87 140.68,43.64 140.68,43.09 140.56,42.96 140.3,42.96 140.18,42.83 140.18,41.13 139.9,40.85 139.9,38.68 139.76,38.54 138.34,38.54 138.2,38.68 138.2,38.97 138.3,39.07 138.66,39.07 138.83,39.25 138.83,39.58 138.69,39.72 138.39,39.72 138.25,39.86 138.25,40.14 138.39,40.28 138.69,40.28 138.83,40.42 138.83,40.66 138.97,40.8 v3(139.21,40.8)
SD_D2_CN: length 30.1
  TOP w0.102: R554.1 142.28,27.2 CRDR1.2 140.88,27.2 D8.2 v3(139.79,27.77) ; R280.2 139.74,46.44 v3(139.74,47.05)
  L4_IN2 w0.14: v3(139.79,27.77) 139.01,28.55 139.01,33.22 139.15,33.35 139.31,33.35 139.45,33.49 139.45,33.77 139.31,33.91 139.15,33.91 139.01,34.05 139.01,34.33 139.15,34.47 139.31,34.47 139.45,34.61 139.45,34.89 139.31,35.03 139.15,35.03 139.01,35.17 139.01,35.47 139.15,35.61 139.84,35.61 139.98,35.75 139.98,36.03 139.84,36.17 139.53,36.17 139.39,36.31 139.39,36.55 139.93,37.09 140.84,37.09 142.36,38.61 142.36,40.31 141.88,40.8 141.88,41.74 141.75,41.87 141.75,42.45 142.01,42.71 142.01,44.15 141.69,44.47 141.69,46.19 140.84,47.05 v3(139.74,47.05)
SD_D3_CN: length 29.9
  TOP w0.102: v3(139.79,29.31) D8.1 140.83,29.7 CRDR1.3 142.46,29.7 R553.1 ; R275.2 v3(138.73,47.07)
  L4_IN2 w0.14: v3(138.73,47.07) 139.13,47.47 141.2,47.47 142.52,46.16 142.52,44.1 142.74,43.87 142.74,40.52 143.31,39.96 143.31,39.04 141.09,36.83 141.09,36.1 139.93,34.93 139.93,33.76 140.41,33.28 140.41,32.39 139.6,31.58 139.6,30.97 139.84,30.73 140.78,30.73 140.92,30.59 140.92,29.86 140.37,29.31 v3(139.79,29.31)
SD_WP_CN: length 3.6
  TOP w0.102: R295.2 140.92,50.3 141.63,49.58 141.63,48.7 141.19,48.26 CRDR1.11
SDA_OZ8690: length 2.2
  TOP w0.102: R13.2 13.57,98.19 U1.8
SEC_BAT: length 1.3
  BOTTOM w0.254: CN9.P1 CN9.P2
SENBAT_V: length 82.6
  TOP w0.102: v3(21.17,63.63) 21.43,63.88 v3(22.98,63.88)
  L4_IN2 w0.102: v3(6.54,68.2) 6.54,70 6.04,70.49 6.04,75.93 6.71,76.6 6.71,82.75 5.64,83.82 5.64,93.47 5.41,93.7 5.41,94.58 5.97,95.14 5.97,97.62 6.68,98.32 6.68,100.91 10.51,104.74 10.51,111.21 10.13,111.59 10.13,114.41 v3(10.06,114.48)
  BOTTOM w0.102: v3(22.98,63.88) 23.35,64.25 R517.2 ; v3(21.17,63.63) 21.74,63.07 21.74,61.54 18.5,58.3 17.01,58.3 16.23,57.52 9.48,57.52 8.71,58.3 8.71,65.8 6.54,67.97 v3(6.54,68.2) ; v1(10.74,113.8) 10.74,113.8 v3(10.06,114.48) 10.06,114.51 10.25,114.71 U25.31
SENBAT_V_R: length 4
  BOTTOM w0.102: R517.1 R515.1 22.49,66.85 C472.1 22.48,67.31 Q37.G
SENSEA: length 6.1
  BOTTOM w0.102: U33.13 154.86,38.26 156.18,39.57 156.18,40.21 AR7.1 156.32,40.26 156.8,40.74 156.8,41.49 156.97,41.66 156.97,41.99 157.5,42.52 AR6.1
SHDDLED#: length 230.7
  TOP w0.076: 102.41,68.74 101.7,69.45 U11.H1
  TOP w0.102: v3(105.66,64.27) 105.66,64.27 105.23,64.27 104.92,64.58 104.29,64.58 102.55,66.32 102.55,68.6 102.41,68.74 ; SBCN1.10 103.29,7.85 104.87,9.43 105.11,9.43 C534.1 105.63,11.16 R658.2 106.27,11.8 106.7,11.8 109.11,14.21 109.11,27.29 v3(109.81,27.99)
  L3_IN1 w0.102: v3(109.81,27.99) 110.19,27.61 115.2,27.61 116.05,28.46 133.17,28.46 138.25,33.54 138.25,39.63 136.85,41.03 135.07,41.03 133.12,42.98 133.12,51.91 v3(131.37,53.66)
  L4_IN2 w0.102: v3(107.89,53.65) 108.39,53.15 130.85,53.15 v3(131.37,53.66) ; v3(129.98,91.95) 129.98,93.8 129.09,94.7 129.09,96.26 130.35,97.52 130.35,98.12 130.35,99.31 131.33,100.28 131.33,109.99 131.26,110.05 131.26,113.9 132.67,115.3 132.67,120.68 132.01,121.34 131.73,121.34 129.69,123.38 128.67,123.38 126.13,125.92 124.74,125.92 121.01,129.65 115.67,129.65 114.88,130.43 106.8,130.43 104.93,132.31 103.16,132.31 v3(102.83,131.98)
  BOTTOM w0.102: v3(129.98,91.95) 131.15,90.78 131.15,88.68 132.41,87.43 132.41,83.1 133.09,82.41 133.09,80.85 133.55,80.39 133.55,78.83 130.05,75.32 130.05,67.16 130.38,66.83 130.38,64.9 130.65,64.62 130.65,57.62 131.09,57.19 131.09,53.94 v3(131.37,53.66) ; v3(102.83,131.98) 102.76,132.04 R643.1 ; v3(107.89,53.65) 107.9,53.66 107.9,59.57 106.12,61.35 106.12,63.81 v3(105.66,64.27)
SIO_I2C0_CLK: length 31.3
  TOP w0.076: U11.N3 99.61,71.87 99.84,71.87 99.97,71.82 100.04,71.82 100.09,71.83 100.2,71.86 100.23,71.87 100.49,71.87 100.62,71.82 100.75,71.82 100.95,71.91 101.19,71.91 101.25,71.84 102.07,71.84 102.41,71.51
  TOP w0.102: v3(125.36,65.16) 125.85,64.66 R213.1 ; v2(103.37,70.69) 102.55,71.51 102.41,71.51
  L4_IN2 w0.102: v2(103.37,70.69) 103.4,70.69 104.31,69.78 106.74,69.78 107.81,68.71 116.67,68.71 118.62,66.76 120.32,66.76 121.92,65.16 124.1,65.16 124.44,65.5 125.02,65.5 v3(125.36,65.16)
SIO_I2C0_DATA: length 34.7
  TOP w0.076: 102.41,71 101.74,71.67 101.2,71.67 101.13,71.73 100.95,71.73 100.79,71.65 100.57,71.65 100.46,71.7 100.27,71.7 100.07,71.65 99.93,71.65 99.8,71.7 99.32,71.7 U11.M4
  TOP w0.102: v2(102.79,70.62) 102.41,71 ; R216.1 126.36,59.9 124.29,61.97 124.29,64.61 124.59,64.92 v3(124.59,64.96)
  L4_IN2 w0.102: v3(124.59,64.96) 124.59,64.95 121.84,64.95 120.23,66.56 118.38,66.56 116.44,68.5 107.73,68.5 106.65,69.58 103.83,69.58 v2(102.79,70.62)
SLP_A#: length 122.5
  TOP w0.076: v2(91.49,82.58) U11.AN16
  L3_IN1 w0.102: v3(28.82,120.25) 29.21,120.25 29.87,120.91 35.86,120.91 36.27,120.51 44.78,120.51 45.39,121.12 48.35,121.12 49.16,120.3 50.3,120.3 54.84,115.76 78.94,115.76 93.34,101.37 102.9,101.37 v3(104.03,100.24)
  L4_IN2 w0.076: 101.9,93.58 100.69,92.37 100.69,91.66 99.92,90.89 96.07,90.89 94.02,88.84 94.02,88.17 91.88,86.02 91.88,82.83 91.63,82.58 v2(91.49,82.58)
  L4_IN2 w0.102: 101.9,93.58 102.03,93.7 102.03,97.19 103.82,98.98 103.82,100.02 v3(104.03,100.24)
  BOTTOM w0.102: U25.100 24.53,128.32 24.9,127.95 26.45,127.95 26.52,127.88 26.52,127.59 27.06,127.06 27.46,127.06 v1(27.89,126.63) 27.85,126.59 27.85,125.47 28.37,124.95 28.37,123.38 28.15,123.16 28.15,122.5 29.05,121.6 29.05,120.48 v3(28.82,120.25)
SM_INTRUDER#: length 6.7
  TOP w0.076: v2(91.49,83.21) U11.AP16
  BOTTOM w0.076: v2(91.49,83.21) 91.1,83.6 91.1,85.3 90.23,86.17 90.23,86.53 91.13,87.43 R452.2
SMB_3.3V: length 81.8
  TOP w0.102: R148.2 106.72,63.1 107.9,64.27 108.37,64.27 v3(108.55,64.09) 108.55,64.32 109.9,65.67 109.9,67 112.13,69.22 112.9,69.22 114.04,70.37 115.67,70.37 116.99,71.69 116.99,76.33 v3(115.73,77.59) ; R193.2 R192.2 118.97,75.85 118.97,76.89 120.01,77.94 120.67,77.94 v3(121.28,77.33) ; v3(110.18,58.43) 110.18,57.08 R164.2
  TOP w0.508: R195.2 121.13,98.18 v3(121.13,97.82) 118.92,97.82 118.21,98.53 R188.2
  L4_IN2 w0.102: v3(120.35,90.16) 120.8,90.6 120.8,97.49 v3(121.13,97.82)
  BOTTOM w0.102: v3(115.73,77.59) 115.85,77.71 120.9,77.71 v3(121.28,77.33) 121.69,77.73 128.52,77.73 128.98,78.19 129.39,78.19 130.02,78.82 130.02,80.88 129.65,81.24 129.65,86.23 126.64,89.24 121.27,89.24 v3(120.35,90.16) ; v3(108.55,64.09) 108.55,60.82 110.18,59.19 v3(110.18,58.43)
SMBALERT#: length 12.5
  TOP w0.076: v3(95.99,73.71) U11.R10
  TOP w0.102: R155.2 106.52,73.57 104.9,73.57 104.52,73.19 R141.1 v3(103.78,73.16)
  BOTTOM w0.076: v3(95.99,73.71) 96.72,73.71 97.1,73.33 97.77,73.33 97.94,73.16 98.65,73.16 99.21,72.6 103.22,72.6 v3(103.78,73.16)
SMBCLK_C: length 6.1
  TOP w0.102: CN7.11 128.41,126.52 128.41,125.49 v3(128.65,125.26)
  BOTTOM w0.102: R351.1 125.26,124.03 128.24,124.03 128.72,124.51 128.72,124.93 128.65,125.01 v3(128.65,125.26)
SMBCLK_EC: length 289.7
  TOP w0.102: v3(120.95,72.14) 120.57,72.52 R197.2 ; Q151.D 12.47,46.15 v3(12.47,45.64) ; C37.2 22.68,122.05 v3(21.94,122.79)
  L4_IN2 w0.102: v3(17.55,56.57) 18,57.01 18,60.17 19.76,61.94 19.76,64.82 18.77,65.81 18.77,66.92 19.57,67.72 19.57,69.78 19.83,70.04 19.83,80.24 20.23,80.63 20.23,82.41 19.97,82.67 19.11,82.67 17.75,84.03 17.75,85.73 15.92,87.56 13.79,87.56 7.4,93.95 7.4,97.44 8.46,98.49 8.46,100.06 10.8,102.41 12.63,102.41 14.18,103.96 14.18,108.9 13.69,109.39 13.69,112.07 13.46,112.3 13.46,116.68 14.55,117.76 14.55,120.28 16.06,121.79 18.25,121.79 19,122.54 20.72,122.54 20.97,122.79 v3(21.94,122.79) ; v3(121.12,90.22) 121.12,91.11 122.9,92.9 122.9,98.92 119.05,102.77 119.05,116.91 121.96,119.83 121.96,123.48 117.75,127.69 115.31,127.69 115.1,127.9 96.24,127.9 94.24,129.91 89.27,129.91 88.5,130.67 73.42,130.67 72.65,129.91 71.01,129.91 70.47,129.36 69.45,129.36 69.08,128.99 48.44,128.99 47.6,128.15 45.82,128.15 44.6,126.93 38.13,126.93 37.62,127.44 35.71,127.44 35.54,127.26 32.73,127.26 31.77,128.23 26.54,128.23 25.32,129.45 25.32,129.45 25.09,129.67 21.91,129.67 v3(21.51,129.27)
  BOTTOM w0.102: v3(12.47,45.64) 12.77,45.95 12.77,53.07 16.15,56.45 17.2,56.45 17.31,56.57 v3(17.55,56.57) ; v3(121.12,90.22) 121.79,89.55 126.76,89.55 129.96,86.36 129.96,81.37 130.32,81 130.32,78.69 129.51,77.88 129.11,77.88 128.65,77.43 123.67,77.43 120.95,74.71 v3(120.95,72.14) 120.95,71.03 v1(120.91,70.99) ; v3(21.51,129.27) 21.36,129.12 21.36,124.15 21.94,123.56 v3(21.94,122.79) 22.41,122.32 U25.115
SMBCLK_EC_D: length 252
  TOP w0.102: v3(125.09,68.36) 125.57,68.84 125.57,70.3 126.14,70.87 126.14,71.61 R211.2 125.75,72.12 125.75,74.75 125.26,75.24 Q15.1 ; v3(119.37,92.43) 119.73,92.79 R191.2 119.89,93.13 U15.1 ; v3(9.48,44.25) 9.48,44.42 R578.2
  L3_IN1 w0.102: v3(124.41,55.81) 122.2,53.6 114.04,53.6 112.64,52.21 111.76,52.21 110.69,51.14 109.67,51.14 108.55,50.03 108.55,49.35 107.6,48.4 107.6,32.52 105.95,30.87 83.45,30.87 77.74,25.16 31.16,25.16 27.07,29.24 27.07,32.85 22.56,37.36 15.3,37.36 9.48,43.18 v3(9.48,44.25)
  L4_IN2 w0.102: v3(120.29,123.88) 120.49,123.68 120.49,123.1 119.96,122.56 119.96,120.73 120.29,120.4 120.29,119.39 118.28,117.38 118.28,106.54 115.54,103.79 115.54,96.55 119.37,92.72 v3(119.37,92.43)
  BOTTOM w0.102: v3(124.41,55.81) 124.41,55.82 124.98,56.38 124.98,65.41 125.47,65.9 125.47,67.49 125.09,67.87 v3(125.09,68.36) 124.86,68.59 124.86,68.59 124.53,68.92 124.53,73.88 126.45,75.8 129.81,75.8 132.94,78.93 132.94,80 132.31,80.63 132.31,81.89 131.89,82.32 131.89,87.23 129.99,89.12 129.99,89.23 126.21,93.02 119.96,93.02 v3(119.37,92.43) ; v3(120.29,123.88) 120.42,124.01 124.02,124.01 R351.2
SMBCLK_EC_S0: length 16.5
  TOP w0.102: U109.4 23.71,45.71 23.52,45.52 23.26,45.52 22.96,45.21 22.04,45.21 21.9,45.35 21.9,46.75 20.53,48.12 12.47,48.12 Q151.S 12.48,49.4 R3280.2
SMBCLK_PCH: length 25.1
  TOP w0.076: U11.W3 99.9,75.21 100.06,75.21 100.28,75.14 100.41,75.14 100.64,75.2 100.77,75.2 100.9,75.15 101.05,75.15 101.52,74.69 101.93,74.69 102.66,73.95 104.57,73.95
  TOP w0.102: v3(115.26,78.06) 115.13,78.06 111.93,74.86 111.93,74.35 111.53,73.95 104.57,73.95 ; v3(120.36,77.33) 120.57,77.12 R196.1
  BOTTOM w0.102: v3(115.26,78.06) 115.26,77.52 115.57,77.21 120.25,77.21 v3(120.36,77.33)
SMBCLK_PCH_EC: length 12.7
  TOP w0.102: v3(121.57,71.18) 120.83,71.18 120.82,71.17 119.42,72.57 R193.1 119.42,73.29 120.06,73.92 120.06,74.89 R196.2 ; v3(125,71.14) 125.63,71.14 R211.1 125.26,71.63 Q15.6
  L4_IN2 w0.102: v3(125,71.14) 124.96,71.18 v3(121.57,71.18)
SMBDAT_C: length 7
  TOP w0.102: CN7.12 128.94,125.91 129.05,125.79 129.05,124.88 v3(129.28,124.65)
  BOTTOM w0.102: v3(129.28,124.65) 127.45,122.82 R353.1
SMBDAT_EC: length 272.3
  TOP w0.102: R200.2 121.72,77.47 121.69,77.5 v3(121.69,90.22) ; v3(21.97,122.21) 21.81,122.05 C30.2 ; v3(12.53,45.07) 10.94,45.07 Q152.D
  L4_IN2 w0.102: v3(18.06,56.31) 18.3,56.56 18.3,60.05 20.06,61.81 20.06,64.95 19.07,65.94 19.07,66.79 19.87,67.59 19.87,69.65 20.13,69.91 20.13,80.11 20.53,80.51 20.53,82.54 20.1,82.97 19.24,82.97 18.06,84.15 18.06,85.86 16.04,87.87 13.92,87.87 7.71,94.08 7.71,97.31 8.76,98.36 8.76,99.94 10.93,102.11 12.76,102.11 14.48,103.83 14.48,109.03 14,109.52 14,112.19 13.77,112.42 13.77,115.01 14.85,116.1 14.85,120.15 16.12,121.42 18.31,121.42 18.52,121.63 20.24,121.63 20.82,122.21 v3(21.97,122.21) ; v3(121.69,90.22) 121.69,91.11 123.4,92.82 123.4,99.11 119.78,102.73 119.78,114.22 119.37,114.64 119.37,116.8 122.27,119.7 122.27,123.76 118.03,128 115.45,128 115.42,128.04 115.4,128.04 114.65,128.79 95.79,128.79 94.37,130.21 89.4,130.21 88.63,130.98 73.29,130.98 72.53,130.21 70.88,130.21 70.34,129.67 69.32,129.67 68.95,129.3 48.31,129.3 47.59,128.57 47.21,128.57 46.84,128.93 46.18,128.93 44.47,127.23 38.26,127.23 37.75,127.74 35.58,127.74 35.46,127.62 32.81,127.62 31.9,128.53 26.67,128.53 25.62,129.58 25.62,129.58 25.22,129.98 21.68,129.98 20.97,129.27 v3(20.97,128.86)
  BOTTOM w0.102: U25.116 22.25,121.92 v3(21.97,122.21) 21.56,122.61 21.56,123.51 21.05,124.02 21.05,128.79 v3(20.97,128.86) ; v3(18.06,56.31) 17.89,56.15 16.28,56.15 13.17,53.04 13.17,45.71 v3(12.53,45.07)
SMBDAT_EC_D: length 251.5
  TOP w0.102: Q15.4 123.96,74.12 123.57,74.5 R212.2 122.47,74.12 R202.2 122.47,73.06 122.88,72.65 123.93,72.65 124.12,72.46 124.12,68.79 v3(124.48,68.44) ; v3(10.12,44.25) 9.9,44.03 R579.2 ; U15.5 117.69,94.03 117.52,93.86 v3(117.52,93.43)
  L3_IN1 w0.102: v3(10.12,44.25) 10.12,43.04 15.49,37.66 22.69,37.66 27.38,32.97 27.38,29.37 31.29,25.46 77.61,25.46 83.32,31.18 105.82,31.18 107.29,32.65 107.29,48.52 108.25,49.48 108.25,50.16 109.54,51.44 110.56,51.44 111.63,52.51 112.51,52.51 113.91,53.91 121.95,53.91 v3(123.85,55.8)
  L4_IN2 w0.102: v3(120.03,123.38) 120.01,123.38 119.65,123.02 119.65,120.61 119.98,120.28 119.98,119.69 117.98,117.69 117.98,106.68 115.23,103.94 115.23,96.27 117.52,93.99 v3(117.52,93.43)
  BOTTOM w0.102: R353.2 123.62,122.82 122.73,123.71 120.65,123.71 120.34,123.4 120.06,123.4 v3(120.03,123.38) ; v3(117.52,93.43) 117.66,93.43 119.04,92.05 119.53,92.05 120.2,92.72 126.08,92.72 129.69,89.11 129.69,88.99 131.58,87.1 131.58,82.19 131.98,81.79 131.98,80.52 132.63,79.87 132.63,79.06 129.68,76.11 126.32,76.11 124.23,74.01 124.23,68.69 v3(124.48,68.44) 124.48,68.05 125.17,67.36 125.17,66.03 124.47,65.34 124.33,65.34 123.85,64.86 v3(123.85,55.8)
SMBDAT_EC_S0: length 19.6
  TOP w0.102: U109.5 23.35,45.31 23.04,45.01 21.93,45.01 21.7,45.24 21.7,46.44 21.04,47.1 19.83,47.1 19.39,47.55 9.8,47.55 Q152.S 9.3,49.47 R3281.2
SMBDAT_PCH: length 28.2
  TOP w0.076: 103.01,72.39 102.59,72.39 101.4,73.58 101.4,74.16 101.07,74.5 100.57,74.5 100.46,74.54 100.32,74.54 100.31,74.54 100.08,74.48 99.95,74.48 99.74,74.55 99.58,74.55 U11.V3
  TOP w0.102: R201.1 121.72,72.33 v3(121.53,72.14) ; v3(114.09,72.83) 114.09,72.14 113.96,72.02 109.65,72.02 109.19,72.47 108.32,72.47 108.17,72.62 104.21,72.62 103.98,72.39 103.01,72.39
  L4_IN2 w0.102: v3(121.53,72.14) 121.1,71.71 120.7,71.71 120.04,72.37 115.82,72.37 114.83,73.36 114.4,73.36 114.09,73.05 v3(114.09,72.83)
SMBDAT_PCH_EC: length 7.3
  TOP w0.102: R192.1 119.42,76.97 120.16,77.71 120.52,77.71 120.87,77.36 120.87,76.84 120.97,76.74 120.97,76.06 121.63,75.4 ; R200.1 121.63,75.4 ; 121.63,75.4 121.66,75.37 R201.2 121.72,75.37 R212.1 123.58,75.37 123.6,75.38 123.91,75.38 Q15.3
SMC_WAKE_SCI#: length 232.8
  TOP w0.076: v3(96.63,72.65) 96.37,72.26 U11.N9
  L3_IN1 w0.102: v3(15.08,111.29) 14.17,112.2 14.17,116.32 13.89,116.61 13.89,117.09 14.39,117.59 14.39,118.99 14.64,119.24 14.64,123.43 16.05,124.84 16.84,124.84 17.19,125.19 19.16,125.19 19.41,124.94 24.61,124.94 25.21,125.53 26.43,125.53 27.09,126.2 28.56,126.2 28.8,125.96 31.7,125.96 32.73,126.98 35.51,126.98 38.48,129.96 48.29,129.96 51.49,126.75 67.15,126.75 67.63,127.24 72.74,127.24 73.4,127.89 73.4,128.84 74.51,129.95 89.55,129.95 91,128.51 91.35,128.51 92.16,127.69 118.29,127.69 119.91,126.08 119.91,124.34 119.65,124.09 119.65,123.2 120.01,122.84 120.01,120.99 120.39,120.6 120.39,119.62 117.83,117.06 117.83,106.18 122.01,102 123.18,102 125.83,99.35 125.83,94.62 130.69,89.76 130.69,84.69 v3(133.76,81.63)
  L4_IN2 w0.076: 104.27,73.66 103.95,73.66 103.86,73.56 102.73,73.56 101.95,72.78 99.79,72.78 v2(99.44,73.13) 99.26,73.13 99.05,73.34 98.26,73.34 98.11,73.2 97.19,73.2 96.64,72.65 v3(96.63,72.65)
  L4_IN2 w0.102: v3(130.88,71.33) 130.58,71.33 130.25,71 126.03,71 125.08,71.95 122.19,71.95 121.95,71.71 121.47,71.71 121.21,71.45 120.6,71.45 119.89,72.17 115.1,72.17 114.85,72.42 113.74,72.42 112.62,73.54 106.81,73.54 106.69,73.66 104.27,73.66
  BOTTOM w0.076: R489.1 99.46,73.16 v2(99.44,73.13)
  BOTTOM w0.102: v3(15.08,111.29) 14.01,112.36 R376.2 ; v3(133.76,81.63) 134.34,81.05 134.34,80.54 135.02,79.86 135.02,78.38 134.77,78.13 134.77,75.64 132.63,73.51 132.63,72.44 131.87,71.69 131.24,71.69 v3(130.88,71.33)
SML0ALERT#: length 10.9
  TOP w0.076: 104.9,74.28 102.84,74.28 102.18,74.94 101.52,74.94 101.04,75.42 U11.W1
  TOP w0.102: 104.9,74.28 109.93,74.28 R168.1 R170.2
SML1ALERT#: length 12.6
  TOP w0.076: U11.AM7 97.38,81.54 v3(96.97,81.94)
  L4_IN2 w0.076: v3(96.97,81.94) 97.38,82.35 97.38,85.25 97.7,85.57 99.63,85.57
  L4_IN2 w0.102: 99.63,85.57 100.9,86.84 102.51,86.84 102.79,87.12 v2(102.79,87.17)
  BOTTOM w0.102: v2(102.79,87.17) 102.79,87.13 103.5,86.42 R463.2
SOC_3.3V_ON: length 250.7
  TOP w0.076: v3(94.56,74.94) 93.94,74.32 U11.U13
  L3_IN1 w0.102: v3(133.97,78.83) 133.3,79.51 133.3,79.89 130.08,83.1 130.08,89.5 125.22,94.37 125.22,99.1 122.95,101.37 121.78,101.37 117.22,105.92 117.22,117.92 118.18,118.88 118.18,119.02 118.21,119.05 118.21,119.69 119.4,120.89 119.4,122.59 118.99,123 118.99,123.58 118.18,124.39 118.18,126.55 v3(118,126.72) 117.64,127.08 91.91,127.08 91.39,127.6 74.2,127.6 73.15,126.55 67.81,126.55 67.4,126.14 51.24,126.14 49.14,128.24 47.14,128.24 46.97,128.07 46.31,128.07 45.15,129.23 38.66,129.23 35.8,126.37 34.38,126.37 33.35,125.35 29.02,125.35 28.59,124.93 25.47,124.93 24.53,123.99 23.34,123.99 23.04,123.68 21.82,123.68 21.17,124.33 19.15,124.33 18.9,124.58 17.44,124.58 16.82,123.95 v3(16.48,123.95)
  L4_IN2 w0.076: 106.09,75.47 104.62,75.47 103.66,74.52 103.39,74.52 103.27,74.4 95.1,74.4 v3(94.56,74.94)
  L4_IN2 w0.102: v3(130.88,73.29) 129.41,71.81 126.49,71.81 125.12,73.18 118.34,73.18 117.57,73.95 115.34,73.95 115.14,74.15 113.69,74.15 112.65,75.19 111.99,75.19 111.64,74.84 108.89,74.84 108.25,75.47 106.09,75.47
  BOTTOM w0.102: R327.1 108.4,138.05 107.67,137.32 106.9,137.32 v1(105.99,136.41) 105.99,135.64 106.45,135.18 106.45,132.03 107.89,130.59 114.2,130.59 114.54,130.93 119.34,130.93 121.36,128.91 121.36,127.58 120.5,126.72 v3(118,126.72) ; v3(133.97,78.83) 133.85,78.71 133.85,75.94 131.85,73.94 131.34,73.94 131.11,73.72 131.11,73.52 v3(130.88,73.29) ; v3(16.48,123.95) 16.05,123.95 11.02,128.98 11.02,129.3 10.25,130.08 U25.66
SPI_CE#: length 13.1
  TOP w0.102: v3(22.22,127.52) 21.91,127.52 20.92,126.53 19.34,126.53 19.21,126.39 17.05,126.39 14.52,123.86 U3.1
  BOTTOM w0.102: v3(22.22,127.52) 22.63,127.92 U25.101
SPI_CLK: length 12.7
  TOP w0.102: v3(18.66,129.92) 18.27,130.31 18.03,130.31 17.45,130.89 B1.1 ; v3(18.61,125.98) 19.76,124.83 v1(20.01,124.83) 20.37,124.83 21.05,125.51 C28.1 21.14,126.12 v3(21.74,126.72)
  BOTTOM w0.102: v3(21.74,126.72) 22.13,126.32 22.81,126.32 22.81,126.32 U25.105 ; v3(18.66,129.92) 18.39,129.64 18.39,126.2 v3(18.61,125.98)
SPI_CLK_EC: length 4
  TOP w0.102: B1.2 16.97,131.29 16.97,130.34 17.06,130.25 U3.6
SPI_HOLD#: length 3.1
  TOP w0.102: R19.1 15.79,130.39 U3.7
SPI_SI: length 7.4
  TOP w0.102: U3.5 18.33,126.82 18.55,126.6 19.13,126.6 19.26,126.73 20.84,126.73 22.01,127.9 22.42,127.9 v3(22.79,127.52)
  BOTTOM w0.102: U25.102 v3(22.79,127.52)
SPI_SO: length 11.4
  TOP w0.102: U3.2 15.79,122.85 16.06,123.12 16.6,123.12 17.29,123.81 18.25,123.81 18.49,123.57 19.62,123.57 21.59,125.54 21.59,126.03 22.52,126.97 v3(22.52,127.01)
  BOTTOM w0.102: U25.103 22.64,127.12 v3(22.52,127.01)
SPI_WP#: length 3.1
  TOP w0.102: U3.3 17.06,120.36 17.36,120.06 17.36,118.94 R22.1
SPK_L+: length 5.6
  TOP w0.254: S37.1 143.07,15.79
  TOP w0.508: AB6.2 141.8,20.18 143,18.98 ED6.1 143,16.49 SPK1.4 143.07,16.41 143.07,15.79
SPK_L-: length 5.4
  TOP w0.254: S35.1 141.85,15.88
  TOP w0.508: 141.85,15.88 141.85,16.38 SPK1.3 141.79,17.45 140.94,18.3 ED5.1 140.94,18.88 139.87,19.95 AB5.2
SPK_R+: length 6.6
  TOP w0.254: S31.1 139.29,15.89
  TOP w0.508: AB1.2 137.08,19.62 136.7,19.24 136.7,17.71 ED3.1 137.96,16.45 SPK1.1 139.29,15.89
SPK_R-: length 5.8
  TOP w0.254: 140.48,16.02 S32.1
  TOP w0.508: 140.48,16.02 140.48,16.39 SPK1.2 140.54,17.25 139.87,17.91 139.29,17.91 ED4.1 138.47,18.88 AB2.2
SPKL1+: length 18.3
  TOP w0.508: v3(140.91,22.64) 140.91,22.11 AB6.1
  L4_IN2 w0.508: v3(140.91,22.64) 141.55,23.27 141.55,24.87 144.06,27.38 144.06,33.31 145.06,34.3 147.62,34.3 147.74,34.41 v3(147.86,34.41)
  BOTTOM w0.203: v3(147.86,34.41) U33.40
SPKL1-: length 19.5
  TOP w0.508: v3(139.88,22.64) 139.87,22.63 AB5.1
  L4_IN2 w0.508: v3(139.88,22.64) 140.89,23.65 140.89,25.18 143.3,27.59 143.3,33.46 144.9,35.06 147.59,35.06 v3(147.64,35.11)
  BOTTOM w0.203: U33.41 148.1,34.81 147.8,35.11 v3(147.64,35.11)
SPKR1+: length 22.3
  TOP w0.508: v3(137.51,22.64) 137.08,22.21 AB1.1
  L4_IN2 w0.508: v3(137.51,22.64) 139.24,24.37 139.24,25.87 142.03,28.66 142.03,33.97 144.72,36.66 147.7,36.66 v3(147.8,36.56)
  BOTTOM w0.203: v3(147.8,36.56) 147.95,36.41 U33.45
SPKR1-: length 20.8
  TOP w0.508: AB2.1 138.47,22.31 v3(138.81,22.64)
  L4_IN2 w0.508: v3(138.81,22.64) 140,23.84 140,25.43 142.67,28.09 142.67,33.71 144.9,35.95 v3(147.64,35.95)
  BOTTOM w0.203: U33.44 148.44,36.01 148.38,35.95 v3(147.64,35.95)
SRCCLKREQ0#: length 0.6
  TOP w0.076: v2(95.14,83.85) 95.23,83.85 U11.AR10
SRTC_RST#: length 18.8
  TOP w0.254: v3(90.6,82.58) 90.7,82.58 91.03,82.25 U11.AN18
  BOTTOM w0.254: R428.2 96.91,91.79 96.91,91.03 96.78,90.9 96.07,90.9 95.55,90.39 94.32,90.39 94.07,90.14 94.07,87.24 93.63,86.8 91.66,86.8 91.31,86.44 C382.1 91.94,85.61 91.94,82.39 91.6,82.05 91.23,82.05 90.7,82.58 v3(90.6,82.58)
  BOTTOM w0.381: JP12.1 97.07,92.9 R428.2
SSD_CLKREQ5#: length 182.2
  TOP w0.076: v2(96.08,85.12) 96.83,85.12 97.16,84.79 U11.AU7
  TOP w0.102: R3370.1 27.83,29.24 v3(27.83,30.09)
  L3_IN1 w0.076: v2(104.97,81.29) 104.97,82.05 103.13,83.89 101.48,83.89 99.64,85.73 96.7,85.73 v2(96.08,85.12)
  L3_IN1 w0.102: v3(27.83,30.09) 27.83,29.32 31.49,25.66 77.53,25.66 83.24,31.38 105.74,31.38 107.09,32.73 107.09,49.8 109.29,52 110.55,52 111.46,52.92 112.26,52.92 113.68,54.34 121.12,54.34 v3(122.15,55.37)
  BOTTOM w0.076: v2(104.97,81.29) 104.72,81.04 104.72,78.75 106.5,76.97 106.62,76.97 ; R503.2 99.72,80.65 96.48,80.65 95.52,81.61 95.52,84.56 v2(96.08,85.12)
  BOTTOM w0.102: 106.62,76.97 114.35,76.97 115.75,75.57 116.82,75.57 119.07,73.32 119.07,71.24 121.99,68.31 121.99,65.67 121.94,65.62 121.94,65.1 121.97,65.08 121.97,55.66 122.15,55.48 v3(122.15,55.37)
SSD_DET: length 11.7
  TOP w0.102: CN13.69 v3(15.82,31.93) ; R3294.1 23.95,30.57 v3(23.95,30.87)
  BOTTOM w0.102: v3(15.82,31.93) 22.76,31.93 23.82,30.87 v3(23.95,30.87)
SSD_DEVSLP: length 138.2
  TOP w0.076: 102.41,69.89 101.75,70.55 100.93,70.55 100.93,70.54 100.86,70.54 100.81,70.52 100.3,70.52 99.89,70.11 U11.J3
  TOP w0.102: CN13.38 23.1,24.18 23.44,24.52 v3(23.44,26.04) ; 102.41,69.89 102.41,69.89 103.37,68.93 103.37,67.16 104.34,66.19 v3(104.34,66.18)
  L3_IN1 w0.102: v3(104.34,66.18) 104.59,65.92 104.97,65.92 105.48,65.41 105.48,65.03 103.22,62.77 103.22,59.39 104.16,58.45 104.16,54.09 102.96,52.89 95.75,52.89 95.45,52.59 v3(95.45,52.21) ; v3(23.44,26.04) 26.77,26.04 30.33,22.49 88.84,22.49 v3(89.3,22.02)
  L4_IN2 w0.102: v3(89.3,22.02) 89.73,22.45 89.73,51.16 91.04,52.46 91.64,52.46 92.07,52.03 92.07,51.88 92.3,51.66 92.31,51.66 92.4,51.57 93.54,51.57 93.8,51.83 94.49,51.83 94.65,51.98 95.22,51.98 v3(95.45,52.21)
SUS_ACK#: length 99.3
  L3_IN1 w0.076: v2(105.58,88.37) 105.58,88.71 105.37,88.93 105.37,90.32 104.84,90.85 104.44,90.85 103.53,91.76 103.53,93.38 103.33,93.58
  L3_IN1 w0.102: 103.33,93.58 102.42,94.49 101.52,94.49 99.78,96.23 97.32,96.23 78.6,114.95 54.5,114.95 49.97,119.49 48.68,119.49 48.43,119.74 45.19,119.74 45.14,119.7 35.72,119.7 35.46,119.43 33.24,119.43 32.53,118.73 28.78,118.73 27.98,119.53 v3(25.47,119.53)
  BOTTOM w0.076: R441.2 105.58,88.91 v2(105.58,88.37)
  BOTTOM w0.102: v3(25.47,119.53) 25.47,120.22 24.57,121.12 U25.118
SUS_ACK#_R: length 19.4
  TOP w0.076: U11.AP11 94.66,82.84 v3(94.28,83.21)
  L4_IN2 w0.076: v3(94.28,83.21) 94.61,83.55 94.61,85.85 95.23,86.47 96.81,86.47 97.46,87.11 100.13,87.11 100.53,87.51 101.58,87.51 101.95,87.88 103.03,87.88 103.09,87.83 104.92,87.83 105.34,87.41 105.66,87.41 v2(105.86,87.21)
  BOTTOM w0.102: v2(105.86,87.21) 106.24,86.82 106.24,86.8 R457.1 106.55,87.13 106.27,87.41 R441.1
SUSWARN#: length 155.2
  L4_IN2 w0.102: v3(109.04,88.02) 109.04,88.7 108.25,89.49 108.25,93.81 108.38,93.94 108.38,98.05 108.91,98.59 108.91,101.02 109.65,101.75 109.65,104.21 112.31,106.88 112.31,110.27 114.21,112.16 114.21,119.25 115.06,120.11 115.06,122.07 111.36,125.77 95.36,125.77 94.12,127.01 71.96,127.01 71.42,126.46 69.66,126.46 69.39,126.2 48.66,126.2 45.36,122.89 35.48,122.89 33.85,121.26 30.17,121.26 29.77,120.86 23.74,120.86 22.37,119.49 21.15,119.49 20.67,119.97 19.22,119.97 18.89,119.64 17.04,119.64 v3(16.98,119.7)
  BOTTOM w0.102: v3(109.04,88.02) 108.91,88.15 107.51,88.15 107.01,87.64 R456.2 ; v3(16.98,119.7) 17.07,119.78 17.07,127.72 15.64,129.14 15.64,129.98 15.45,130.18 U25.79
SUSWARN#_R: length 21.4
  TOP w0.076: v3(93.31,83.85) 93.44,83.85 93.77,83.52 U11.AR13
  L4_IN2 w0.076: 106.6,87.82 106.48,87.82 106.22,87.56 105.4,87.56 104.98,87.98 103.15,87.98 102.87,88.25 101.04,88.25 100.05,87.27 97.39,87.27 96.75,86.62 95.17,86.62 94.41,85.86 94.28,85.86 93.84,85.42 93.84,84.15 93.54,83.85 v3(93.31,83.85)
  L4_IN2 w0.102: v3(108.71,87.46) 108.35,87.82 106.6,87.82
  BOTTOM w0.102: R457.2 107.41,86.77 107.44,86.8 107.44,87.26 R456.1 108.53,87.64 v3(108.71,87.46)
SYS_PWROK: length 199.1
  TOP w0.102: 98.27,59.57 99.57,60.87 99.57,60.88 R128.2 ; v3(19.58,56.95) 19.58,55.93 19.26,55.61 16.34,55.61 15.77,56.18 v3(10.25,56.18)
  TOP w0.114: 98.27,59.57 98.24,59.54 98.24,59.32 93.25,54.32 93.25,54.3 92.98,54.03 92.95,54.03 92.15,53.22 87.32,53.22 86.41,52.31 86.41,48.37 v3(86.31,48.27)
  L3_IN1 w0.102: v3(86.31,48.27) 86.31,47.89 84.15,45.73 70.08,45.73 65.6,41.25 53.25,41.25 51.14,43.36 51.14,58.22 51.19,58.28 v3(51.2,58.28)
  L4_IN2 w0.102: v3(4.16,69.7) 3.91,69.95 3.91,92.89 3.75,93.06 3.75,98.61 4.85,99.7 4.85,104.25 4.54,104.56 4.54,113.14 4.14,113.54 4.14,123.73 v3(7.06,126.65)
  BOTTOM w0.102: v3(10.25,56.18) 10.24,56.19 9.87,56.19 8.2,57.87 8.2,65.66 v3(4.16,69.7) ; v3(51.2,58.28) 50.82,58.66 39.84,58.66 37.7,60.79 29.81,60.79 27.71,58.69 27.71,56.95 26.92,56.16 20.37,56.16 v3(19.58,56.95) ; v1(6.42,126.37) 6.78,126.37 v3(7.06,126.65) 7.13,126.72 U25.57
SYS_PWROK_R: length 7.6
  TOP w0.076: 99.5,62.24 99.5,63.5 98.41,64.59 98.41,66 U11.B6
  TOP w0.102: R127.2 100.86,61.78 C165.2 R128.1 99.5,61.82 99.5,62.24
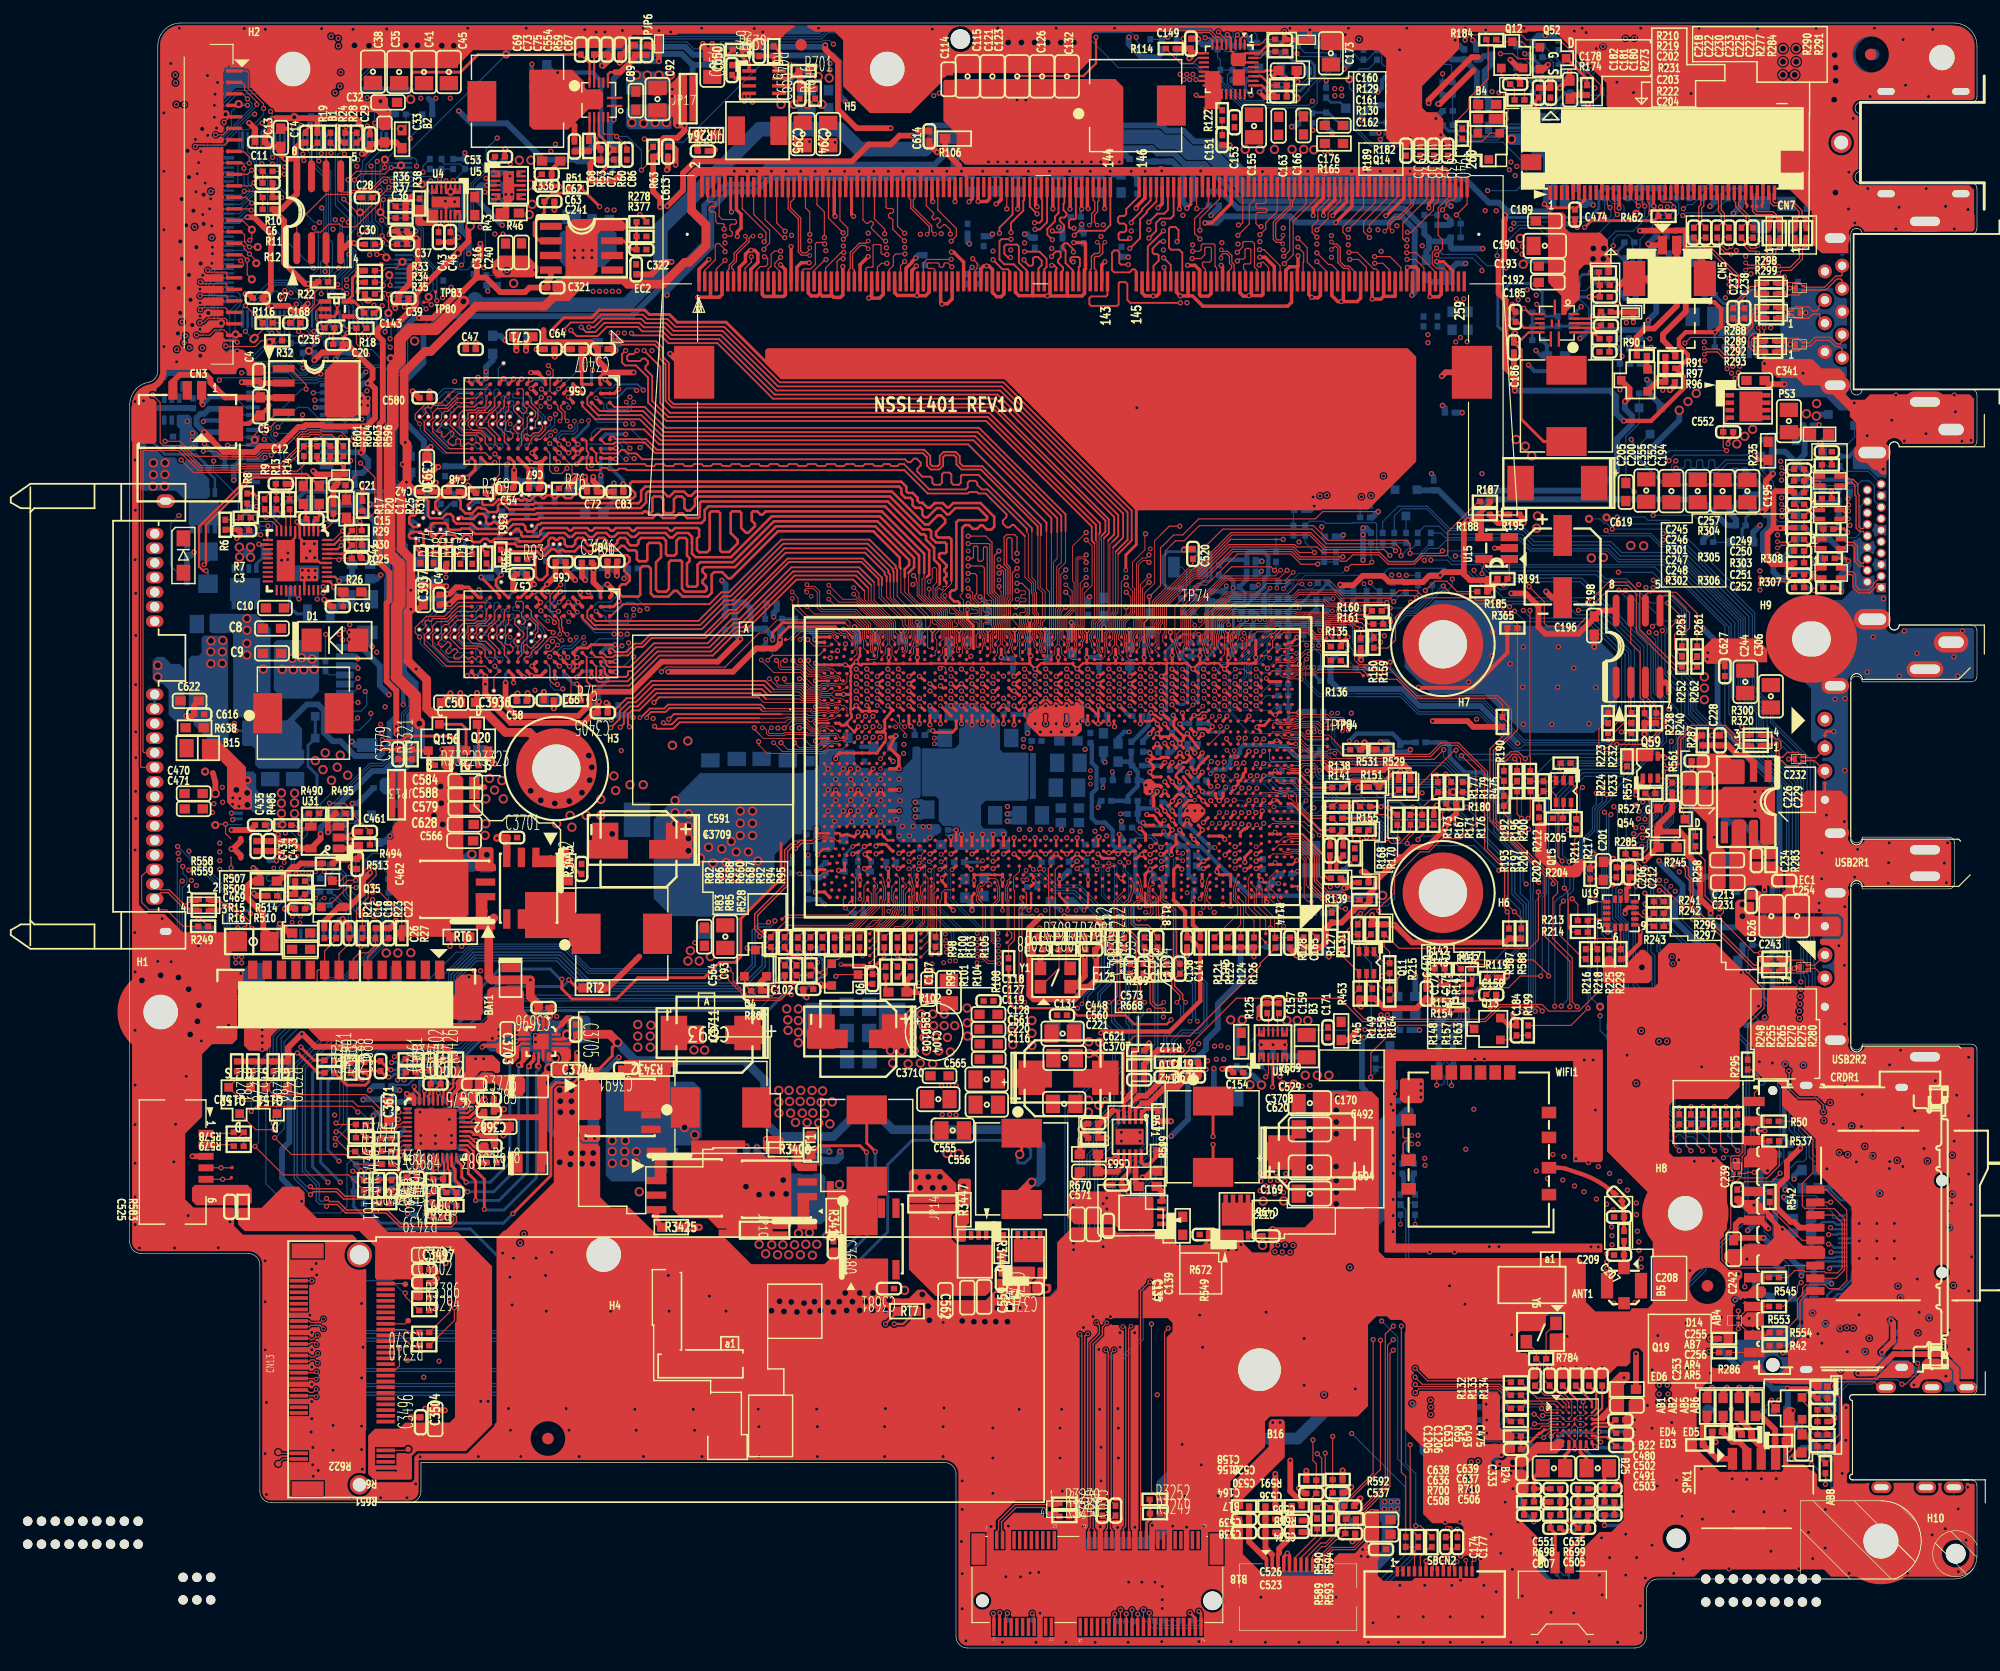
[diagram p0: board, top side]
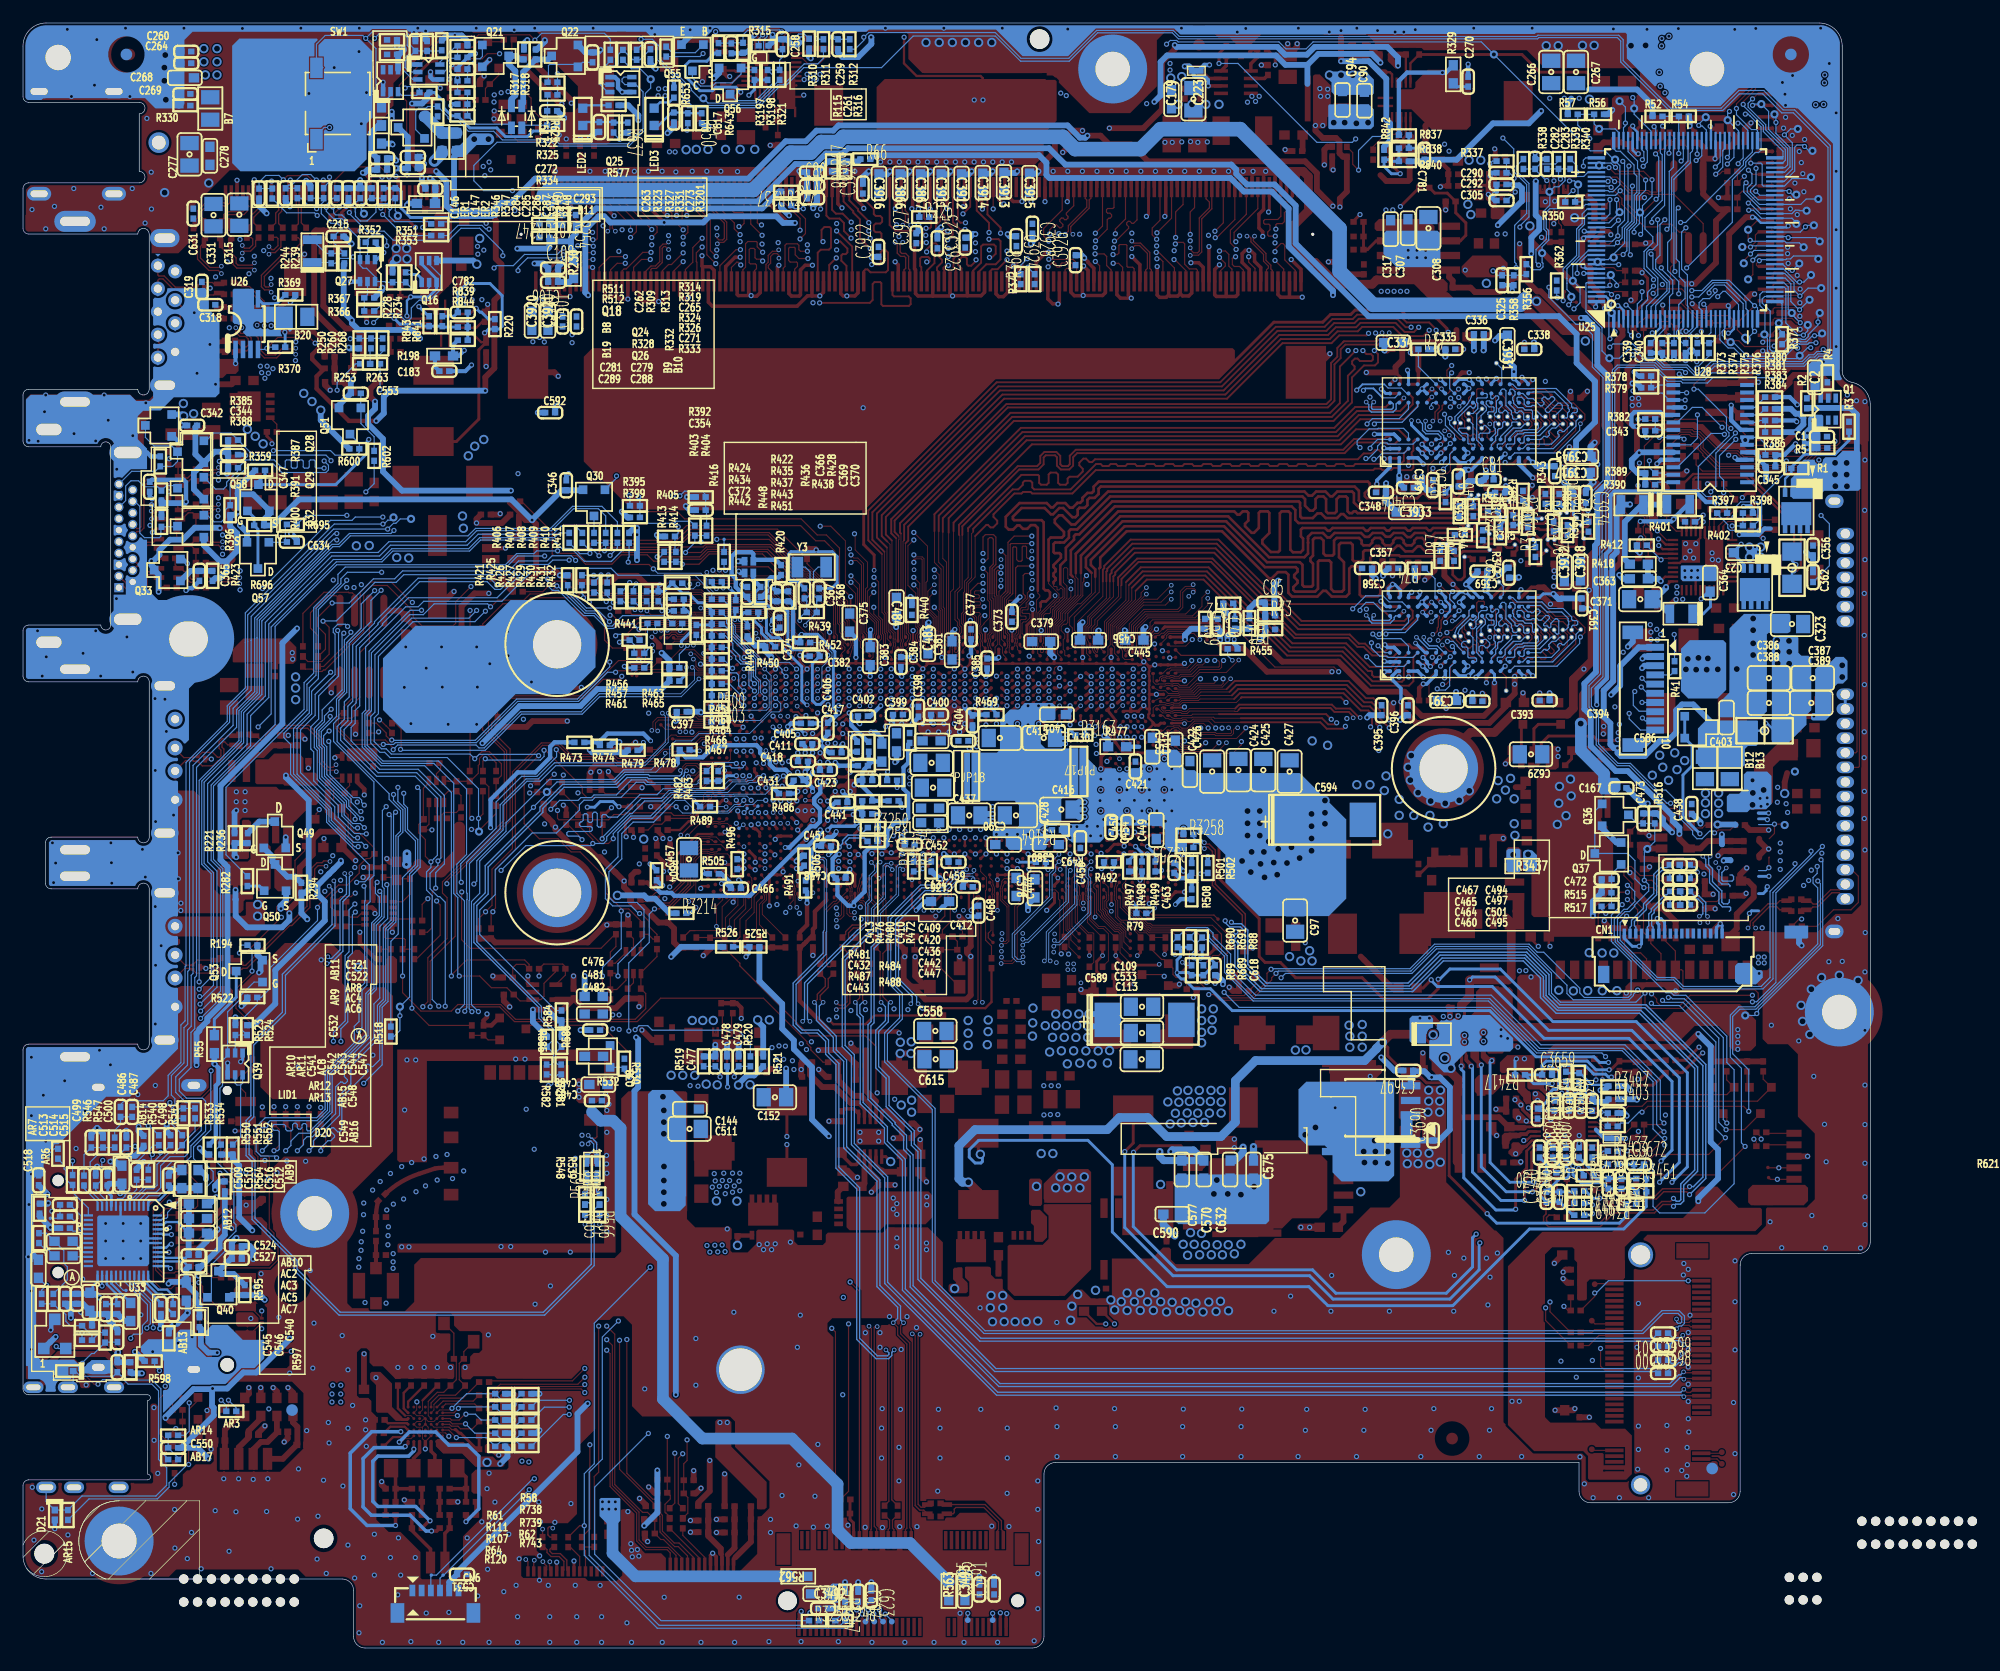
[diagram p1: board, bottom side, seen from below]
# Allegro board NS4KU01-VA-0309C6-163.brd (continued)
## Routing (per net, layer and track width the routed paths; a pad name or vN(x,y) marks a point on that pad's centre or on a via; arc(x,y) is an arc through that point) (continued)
SYS_RESET#: length 7.5
  TOP w0.076: U11.B5 99.03,65.63 99.03,65.19 99.78,64.45 99.78,62.61 100.01,62.38 102.14,62.38
  TOP w0.102: R131.1 102.57,62.38 102.14,62.38
TEMPA: length 65.5
  TOP w0.203: U109.38 25.58,48.39 v3(25.62,48.44) ; v3(66.44,28.18) 67.23,28.18 RT7.2
  L3_IN1 w0.203: v3(25.62,48.44) 24.02,46.84 24.02,41.26 24.47,40.82 25.61,40.82 30.69,35.74 30.69,30.15 33.17,27.67 65.93,27.67 v3(66.44,28.18)
  BOTTOM w0.203: v3(25.62,48.44) 25.62,48.16 C3673.2 26.31,47.73 26.31,49.11 R3408.2
TEMPB: length 22.2
  TOP w0.203: v3(28.85,61.01) 29.51,61.67 RT6.2 ; v3(24.72,48.82) 24.72,48.56 25.18,48.11 U109.39
  L3_IN1 w0.203: v3(24.72,48.82) 24.72,49.64 31.52,56.44 31.52,59.25 29.75,61.01 v3(28.85,61.01)
  BOTTOM w0.203: v3(24.72,48.82) 24.72,48.03 C3674.2 25.18,49 R3410.2
TEST1: length 49.7
  TOP w0.102: CN9.P6 1.03,76.57 0.95,76.65 0.95,104.24 1.04,104.33 4.39,104.33 6.09,102.63 9.34,102.63 9.47,102.75 13.19,102.75 14.73,104.29 14.73,105.1 14.99,105.35 15.57,105.35 15.73,105.52 16.42,105.52 17.42,104.52 R603.1 17.63,104.5 18.49,103.64 R596.1
TEST2: length 44
  TOP w0.102: CN9.P5 1.26,77.84 1.15,77.95 1.15,104.05 1.23,104.12 4.24,104.12 5.94,102.42 9.43,102.42 9.54,102.54 13.38,102.54 14.55,103.7 14.55,103.83 15.14,104.41 R601.1 R604.1
TEST3: length 9.4
  TOP w0.102: CN9.P13 1.61,67.68 1.04,67.11 1.04,64.83 1.67,64.19 3.2,64.19 4.63,62.75 R249.1
TESTB1/BADD: length 2.7
  BOTTOM w0.102: U28.9 9.77,106.57 9.6,106.74 R383.1 R384.2
TMDSB_CLK+: length 136.3
  TOP w0.076: U11.G56 68.87,69.09 68.87,69 v2(68.63,68.76)
  TOP w0.114: C246.1 144.68,101.51 144.68,101.88 144.56,102 144.13,102 143.94,102.19 143.63,102.19 v2(143.55,102.12)
  L4_IN2 w0.114: v2(71.78,59.74) 71.65,59.62 71.65,58.98 73.79,56.85 103.72,56.85 106.02,54.54 113.81,54.54 114.58,53.78 128.43,53.78 129.06,54.41 138.92,54.41 146.11,61.6 146.11,81.57 143.71,83.98 143.71,89.8 144.61,90.7 144.61,101.79 144.08,102.32 143.76,102.32 v2(143.55,102.12)
  BOTTOM w0.076: v2(68.63,68.76) 69.16,68.23 69.16,64.7 71.61,62.25 71.61,59.91 v2(71.78,59.74)
TMDSB_CLK+_C: length 3.1
  TOP w0.114: R301.2 C246.2 145.51,101.63 145.61,101.73 145.87,101.73 146.12,101.48 146.82,101.48 146.9,101.4 L18.4
TMDSB_CLK-: length 136.3
  TOP w0.076: U11.F56 68.69,68.25 v2(68.6,68.25)
  TOP w0.114: C245.1 144.6,102.45 143.76,102.45 v2(143.55,102.65)
  L4_IN2 w0.114: v2(143.55,102.65) 143.66,102.54 144.17,102.54 144.82,101.88 144.82,90.61 143.92,89.71 143.92,84.07 146.33,81.66 146.33,61.51 139.01,54.19 129.15,54.19 128.52,53.56 114.49,53.56 113.72,54.33 105.93,54.33 103.63,56.63 73.7,56.63 71.43,58.89 71.43,59.58 v2(71.27,59.74)
  BOTTOM w0.076: v2(68.6,68.25) 68.83,68.25 68.95,68.14 68.95,64.61 71.4,62.16 71.4,59.87 v2(71.27,59.74)
TMDSB_CLK-_C: length 3
  TOP w0.114: R304.2 147.06,102.05 L18.1 146.55,101.88 146.4,101.73 146.23,101.73 145.97,101.99 145.69,101.99 145.51,102.17 C245.2
TMDSB_D0+: length 129
  TOP w0.076: v2(70.51,69.02) 70.63,69.02 U11.G53
  TOP w0.114: v2(143.58,98.94) 143.66,99.02 143.91,99.02 144.24,98.69 144.57,98.69 144.65,98.61 C248.1
  L4_IN2 w0.114: v2(143.58,98.94) 143.45,99.07 142.83,99.07 142.67,98.9 142.67,94.93 143.24,94.36 143.24,91.23 142.48,90.47 142.48,81.95 144.91,79.52 144.91,62.12 138.51,55.72 129.84,55.72 129.26,56.3 105.97,56.3 104.35,57.92 104.35,57.92 104.22,58.05 74.87,58.05 74.05,58.87 74.05,59.48 73.93,59.6 v2(73.63,59.6)
  BOTTOM w0.076: v2(73.63,59.6) 73.71,59.68 74.17,59.68 74.57,60.07 74.57,62.09 71.32,65.34 71.32,67.32 71,67.64 71,68.52 v2(70.51,69.02)
TMDSB_D0+_C: length 2.7
  TOP w0.114: R302.2 C248.2 145.79,98.71 146.17,98.71 146.72,98.16 L19.4
TMDSB_D0-: length 129
  TOP w0.076: v2(70.51,68.38) 70.65,68.38 U11.F53
  TOP w0.114: v2(143.55,99.45) 143.73,99.27 144.01,99.27 144.34,98.94 144.88,98.94 145,99.07 145,99.32 144.88,99.45 C247.1
  L4_IN2 w0.114: v2(73.63,60.1) 73.73,60.1 74.26,59.57 74.26,58.96 74.96,58.27 104.31,58.27 104.44,58.14 106.06,56.52 129.35,56.52 129.93,55.93 138.42,55.93 144.69,62.21 144.69,79.43 142.26,81.86 142.26,90.56 143.02,91.32 143.02,94.27 142.45,94.84 142.45,98.99 142.74,99.28 143.39,99.28 v2(143.55,99.45)
  BOTTOM w0.076: v2(70.51,68.38) 70.79,68.1 70.79,67.55 71.1,67.23 71.1,65.25 74.36,62 74.36,60.16 74.09,59.89 73.84,59.89 v2(73.63,60.1)
TMDSB_D0-_C: length 2.8
  TOP w0.114: R305.2 147.09,99.93 147.09,99.15 L19.1 146.78,98.84 146.4,98.84 146.28,98.97 145.99,98.97 C247.2
TMDSB_D1+: length 128.9
  TOP w0.076: U11.F58 67.9,68.38 v2(67.71,68.38)
  TOP w0.114: C250.1 144.65,95.77 144.52,95.89 143.55,95.89 143.39,95.73 143.27,95.73 v2(143.2,95.66)
  L4_IN2 w0.114: v2(143.2,95.66) 143.26,95.66 143.42,95.82 143.71,95.82 143.9,95.63 143.9,91.13 142.97,90.21 142.97,83.71 145.4,81.28 145.4,61.9 138.63,55.13 128.73,55.13 128.09,54.49 114.94,54.49 113.66,55.76 107.75,55.76 107.24,55.25 106.32,55.25 105.56,56.02 104.01,57.56 74.6,57.56 72.87,59.29 72.87,60.53 71.93,61.47 70.97,61.47 v2(70.91,61.53)
  BOTTOM w0.076: v2(67.71,68.38) 68.17,67.92 68.17,67.06 67.97,66.86 67.97,63.91 70.52,61.36 70.75,61.36 v2(70.91,61.53)
TMDSB_D1+_C: length 2.8
  TOP w0.114: L20.4 146.85,95.79 145.87,95.79 145.51,95.44 C250.2 R303.2
TMDSB_D1-: length 129
  TOP w0.076: v2(67.71,67.75) 67.92,67.75 U11.E58
  TOP w0.114: v2(143.2,96.2) 143.25,96.15 144.29,96.15 144.55,96.4 C249.1
  L4_IN2 w0.114: v2(143.2,96.2) 143.31,96.2 143.48,96.03 143.8,96.03 144.11,95.72 144.11,91.04 143.19,90.12 143.19,83.8 145.62,81.37 145.62,61.81 138.72,54.91 128.82,54.91 128.17,54.27 114.85,54.27 113.57,55.55 107.84,55.55 107.33,55.04 106.23,55.04 105.47,55.8 103.92,57.34 74.51,57.34 72.65,59.2 72.65,60.39 71.83,61.21 71.16,61.21 v2(70.96,61.02)
  BOTTOM w0.076: v2(70.96,61.02) 70.84,61.15 70.43,61.15 67.75,63.82 67.75,66.95 67.96,67.15 67.96,67.68 67.89,67.75 v2(67.71,67.75)
TMDSB_D1-_C: length 2.8
  TOP w0.114: R306.2 147.19,96.58 L20.1 146.65,96.05 145.87,96.05 C249.2
TMDSB_D2+: length 120.1
  TOP w0.076: U11.F55 69.73,68.38 v2(69.49,68.38)
  TOP w0.114: C252.1 144.72,92.29 144.72,92.62 144.62,92.72 141.8,92.72 141.7,92.62 v2(141.7,92.54)
  L4_IN2 w0.114: v2(141.7,92.54) 141.85,92.69 142.18,92.69 142.28,92.59 142.28,91.75 141.55,91.02 141.55,81.57 142.75,80.37 142.75,77.19 143.84,76.1 143.84,63.59 136.9,56.64 130.23,56.64 129.64,57.23 106.36,57.23 106.04,57.54 104.6,58.98 103.75,58.98 103.75,58.98 102.83,58.98 102.83,58.98 75.3,58.98 74.97,59.31 74.97,61 74.34,61.63 v2(73.65,61.63)
  BOTTOM w0.076: v2(69.49,68.38) 69.49,68.3 69.78,68.03 69.9,67.92 69.9,64.93 73.25,61.58 73.61,61.58 v2(73.65,61.63)
TMDSB_D2+_C: length 3.4
  TOP w0.114: C252.2 145.51,92.51 145.66,92.67 146,92.67 146.27,92.94 146.27,93.28 146.35,93.35 146.53,93.35 146.8,93.08 L21.4 147.19,92.92 R307.2
TMDSB_D2-: length 120
  TOP w0.076: U11.E55 69.62,67.62 v2(69.52,67.62)
  TOP w0.114: v2(141.7,93.07) 141.7,93.1 141.83,92.97 144.22,92.97 144.6,93.35 C251.1
  L4_IN2 w0.114: v2(141.7,93.07) 141.7,93.05 141.84,92.91 142.27,92.91 142.5,92.68 142.5,91.66 141.77,90.93 141.77,81.65 142.96,80.46 142.96,77.28 144.06,76.18 144.06,63.5 136.99,56.43 130.14,56.43 129.55,57.01 106.27,57.01 105.95,57.33 104.52,58.76 103.66,58.76 103.66,58.76 102.92,58.76 102.92,58.76 75.21,58.76 74.85,59.13 74.76,59.22 74.76,60.85 74.22,61.39 73.93,61.39 73.66,61.12 v2(73.65,61.12)
  BOTTOM w0.076: v2(69.52,67.62) 69.68,67.46 69.68,64.84 73.16,61.37 73.41,61.37 v2(73.65,61.12)
TMDSB_D2-_C: length 3.5
  TOP w0.114: C251.2 145.51,93.05 145.64,92.92 145.89,92.92 146.02,93.05 146.02,93.38 146.24,93.61 146.53,93.61 146.8,93.88 L21.1 147.31,94.17 R308.2
TP_5V: length 5.7
  TOP w0.305: SBCN1.1 98.79,7.72 98.62,7.88
  TOP w0.508: B18.2 C528.1 C530.1 97.28,9.23 98.62,7.88
TP_CLK: length 214.3
  TOP w0.102: 104.34,11.29 104.34,11.42 104.64,11.72 104.66,11.72 104.75,11.81 104.75,12.5 104.29,12.96 104.29,13.24 C536.1 R591.2 v3(104.55,18.4)
  L3_IN1 w0.102: v3(104.55,18.4) 104.47,18.48 97.94,18.48 92.48,23.93 30.76,23.93 25.51,29.18 25.51,33.03 22,36.55 14.59,36.55 7.56,43.57 7.56,58.18 5.23,60.51 5.23,63.19 5.66,63.62 5.66,66.17 v3(5.79,66.3)
  L4_IN2 w0.102: v3(5.79,66.3) 5.79,66.39 7.18,67.78 7.18,69.99 6.42,70.75 6.42,75.8 7.03,76.41 7.03,82.86 5.95,83.95 5.95,93.59 5.72,93.82 5.72,94.45 6.28,95.01 6.28,97.49 6.98,98.2 6.98,100.78 10.82,104.62 10.82,111.33 10.44,111.71 10.44,118.55 11.94,120.05 11.94,121.61 19.17,128.84 v3(19.74,128.84)
  BOTTOM w0.102: U25.89 19.45,130.31 19.37,130.23 19.37,129.2 v3(19.74,128.84)
TP_CLK_CN: length 4.2
  TOP w0.102: R593.1 101.79,7.85 SBCN1.7
TP_DATA: length 212.6
  TOP w0.102: v3(102.83,18.1) 102.83,16.31 103.12,16.02 R592.2 C537.1 102.76,13.09 102.76,11.72 103.2,11.29
  L3_IN1 w0.102: v3(5.35,66.74) 5.35,63.74 4.9,63.29 4.9,60.41 7.26,58.05 7.26,43.45 14.46,36.24 21.87,36.24 25.21,32.91 25.21,29.05 30.63,23.63 92.03,23.63 97.56,18.1 v3(102.83,18.1)
  L4_IN2 w0.102: v3(19.81,129.41) 19.31,129.41 11.63,121.74 11.63,120.24 9.67,118.29 9.67,114.32 9.93,114.07 9.93,111.5 10.31,111.12 10.31,104.83 6.47,100.99 6.47,98.41 5.21,97.14 5.21,93.61 5.44,93.38 5.44,83.74 6.41,82.76 6.41,76.76 5.77,76.12 5.77,70.32 6.16,69.93 6.16,67.54 v3(5.35,66.74)
  BOTTOM w0.102: v3(19.81,129.41) 19.68,129.54 19.68,130.11 19.85,130.27 U25.90
TP_DATA_CN: length 4
  TOP w0.102: SBCN1.6 101.29,7.88 103.2,9.79 R589.1
TP_USB_PN1_R: length 4.9
  TOP w0.114: L13.3 145.61,124.15 145.34,124.42 145.34,125 144.68,125.66 142.94,125.66 142.82,125.78 142.82,126.42 CN7.40
TP_USB_PP1_R: length 4.9
  TOP w0.114: CN7.39 142.56,126.42 142.56,125.68 142.84,125.4 144.57,125.4 145.08,124.89 145.08,124.47 144.81,124.2 L13.2
TX1: length 2.5
  TOP w0.305: B24.1 124.75,16.77 125.07,17.1 U1634.G3
TX2: length 2.5
  TOP w0.305: U1634.G5 126.07,17.01 126.61,16.48 B25.1
U22_XTAL24_IN: length 6.6
  TOP w0.102: R3058.1 80.64,62.44 79.96,63.13 79.96,64.69 79.86,64.78 79.86,66.37 79.83,66.41 79.83,66.75 79.86,66.78 79.86,67.02 79.83,67.06 79.83,67.77 U11.E37
U22_XTAL24_OUT: length 7.2
  TOP w0.102: U11.E35 80.76,68 80.43,67.66 80.43,63.65 82.06,62.01 R3085.1
UART0_CTS: length 17.5
  TOP w0.076: v2(102.71,75.78) 102.71,75.8 102.62,75.89 102.11,75.89 101.7,76.31 100.87,76.31 100.46,76.47 100.17,76.47 99.91,76.74 U11.AB3
  TOP w0.102: R180.2 114.42,73.19 v3(114.68,72.93)
  BOTTOM w0.076: 105.9,75.28 105.89,75.27 102.86,75.27 102.74,75.4 102.74,75.75 v2(102.71,75.78)
  BOTTOM w0.102: v3(114.68,72.93) 113.9,73.71 112.3,73.71 112.06,73.95 111.14,73.95 110.92,74.18 108.98,74.18 107.67,75.48 106.43,75.48 106.23,75.28 105.9,75.28
UART0_RST: length 40.3
  TOP w0.076: U11.W4 99.32,75.68 101.38,75.68 v2(101.72,75.34)
  BOTTOM w0.076: v2(101.72,75.34) 101.75,75.34 101.99,75.1 105.67,75.1 105.7,75.08
  BOTTOM w0.102: 105.7,75.08 106.38,75.08 106.58,75.28 107.25,75.28 108.56,73.97 110.82,73.97 111.08,73.72 111.79,73.72 112.19,73.32 112.19,72.86 114.17,70.87 116.29,70.87 119.5,67.66 119.5,65.51 120.85,64.16 120.85,62.05 114.23,55.43 R584.2
UART0_RX: length 45.3
  TOP w0.076: U11.AB1 101.77,76.74 101.93,76.9 102.95,76.9 103.19,76.65 103.19,76.46 103.35,76.31 v2(103.4,76.31)
  BOTTOM w0.102: 115.71,54.78 114.5,53.57 114.5,52.84 115.01,52.33 R586.2 114.45,51.72 114.45,50.94 114.65,50.74 R582.1
  BOTTOM w0.114: 115.71,54.78 115.71,55.7 121.36,61.35 121.36,64.68 120.37,65.66 120.37,68.02 115.61,72.78 115.61,73.11 113.63,75.1 109.01,75.1 108.16,75.95 106.19,75.95 106.07,75.83 103.47,75.83 103.3,76 103.3,76.21 v2(103.4,76.31)
UART0_TX: length 45.6
  TOP w0.076: U11.AB2 100.5,76.74 100.64,76.6 100.65,76.6 100.65,76.59 100.9,76.47 101.81,76.47 102.06,76.72 102.86,76.72 103.02,76.56 103.02,76.44 v2(102.86,76.28)
  BOTTOM w0.102: R581.1 114.04,50.74 114.25,50.94 114.25,51.78 R585.2 113.74,52.33 114.25,52.84 114.25,53.62 115.49,54.87 115.49,55.79 115.9,56.2
  BOTTOM w0.114: 115.9,56.2 121.1,61.4 121.1,64.57 120.12,65.56 120.12,67.91 115.36,72.67 115.36,73.01 113.53,74.84 108.88,74.84 108.03,75.69 106.29,75.69 106.18,75.58 103.36,75.58 103.11,75.83 103.11,75.86 103.06,75.91 103.06,76.09 v2(102.86,76.28)
UART2_RX: length 135
  TOP w0.076: U11.AD1 101.08,78.07 101.5,77.64 104.05,77.64 104.34,77.35 106.62,77.35
  TOP w0.102: 106.62,77.35 108.84,77.35 109.2,77.71 112.95,77.71 113.94,78.7 113.95,78.7 113.95,78.7 115.49,78.7 118.01,76.18 118.01,69.5 119.78,67.72 119.78,64.58 v3(120.34,64.02) 120.94,63.42 R588.2
  L4_IN2 w0.102: v3(116.1,14.72) 115.71,15.11 115.71,18.04 116.15,18.49 116.15,22.32 115.52,22.95 115.52,29.5 109.03,35.99 109.03,48.13 109.71,48.8 109.71,51.44 110.4,52.13 132.31,52.13 v3(132.91,52.74) ; v3(131.66,64) 131.28,64.37 120.7,64.37 v3(120.34,64.02)
  BOTTOM w0.102: v3(131.66,64) 131.91,63.74 131.91,60.44 132.29,60.06 132.29,57.82 132.32,57.79 132.32,54.44 132.91,53.84 v3(132.91,52.74) ; CN6.3 125.1,6.29 TP76.1 124.61,6.34 116.23,14.72 v3(116.1,14.72)
UART2_TX: length 136.3
  TOP w0.076: 106.62,77.1 104.34,77.1 103.96,77.48 101.16,77.48 100.57,78.07 U11.AD2
  TOP w0.102: 106.62,77.1 108.87,77.1 109.28,77.51 113.04,77.51 114.03,78.5 114.35,78.5 114.36,78.49 115.4,78.49 117.75,76.14 117.75,69.45 119.48,67.72 119.48,64.35 119.71,64.11 v3(119.71,64.02) 119.86,63.87 R587.2
  L4_IN2 w0.102: v3(116.54,13.77) 116.54,14.85 115.91,15.48 115.91,17.96 116.35,18.4 116.35,22.4 115.72,23.03 115.72,29.58 109.24,36.07 109.24,48.04 109.91,48.72 109.91,51.36 110.48,51.93 132.74,51.93 v3(133.56,52.76) ; v3(119.71,64.02) 120.26,64.58 131.58,64.58 v3(131.7,64.69)
  BOTTOM w0.102: v3(131.7,64.69) 132.21,64.19 132.21,60.54 132.55,60.2 132.55,54.53 133.56,53.52 v3(133.56,52.76) ; CN6.4 124.3,6.08 TP75.1 123.97,6.34 v3(116.54,13.77)
UMA_DIS_DET: length 10.1
  TOP w0.076: 102.76,72.14 102.61,72.14 100.92,73.84 100.78,73.84 100.71,73.91 100.71,74.18 100.56,74.32 100.54,74.32 100.42,74.37 100.31,74.37 100.09,74.3 100.09,74.3 99.92,74.3 99.79,74.34 99.79,74.34 99.78,74.35 99.72,74.37 98.32,74.37 U11.U6
  TOP w0.102: 102.76,72.14 R142.1 105.02,71.64 105.71,71.64 106.22,71.13 R152.1
USB2_COMP: length 3.5
  TOP w0.076: U11.AB6 98.28,76.64 v3(98.55,76.91)
  BOTTOM w0.102: v3(98.55,76.91) 98.63,77 100.4,77 R482.2
USB30_RX_N: length 104.1
  TOP w0.076: v3(96.06,69.68) 96.25,69.68 U11.H8
  TOP w0.114: v2(141.52,114.81) 141.52,114.67 141.59,114.61 141.67,114.52 141.67,114.37 141.6,114.3 141.09,114.3 140.71,113.92 140.71,113.17 140.92,112.95 141.09,112.78 L14.2 142.02,112.78 R293.2
  L4_IN2 w0.114: v3(96.06,69.68) 96.2,69.54 96.83,69.54 97.61,70.32 98.22,70.32 99.32,69.22 102.53,69.22 103.25,68.5 104.9,68.5 105.74,67.67 109.34,67.67 111.12,65.89 111.12,63.73 112.08,62.77 120.13,62.77 120.67,63.32 134.65,63.32 136.14,64.81 136.14,73.38 135.54,73.99 135.54,75.49 136.78,76.74 136.78,80.32 137.97,81.5 137.97,90.76 137.74,91 137.74,99.14 138.05,99.45 138.05,101.99 137.31,102.74 137.31,106.46 141.26,110.41 141.26,113.2 141.82,113.76 141.82,114.06 141.83,114.3 141.71,114.41 141.59,114.41 141.52,114.49 v2(141.52,114.81)
USB30_RX_N_IN: length 7.3
  TOP w0.114: USB3R1.5 148.82,112.94 148.61,113.14 148.26,113.14 147.69,113.72 146.57,113.72 146.08,113.22 145.85,113.22 145.79,113.16 D10.2 145.06,112.78 L14.1 143.1,112.78 R293.1
USB30_RX_P: length 104.2
  TOP w0.076: U11.G8 96.3,69.3 v3(96.06,69.04)
  TOP w0.114: v2(142.05,114.8) 142.05,114.39 141.71,114.05 141.2,114.05 140.96,113.82 140.96,113.3 141.12,113.15 141.5,113.15 141.71,113.35 L14.3 142.02,113.58 R292.2
  L4_IN2 w0.114: v3(96.06,69.04) 96.34,69.32 96.92,69.32 97.7,70.1 98.13,70.1 99.23,69 102.44,69 103.16,68.29 104.81,68.29 105.65,67.45 109.25,67.45 110.91,65.8 110.91,63.64 111.99,62.56 120.22,62.56 120.76,63.1 134.74,63.1 136.36,64.72 136.36,73.47 135.75,74.08 135.75,75.41 137,76.65 137,80.23 138.19,81.41 138.19,90.85 137.95,91.09 137.95,99.05 138.27,99.36 138.27,102.08 137.52,102.82 137.52,106.37 141.47,110.32 141.47,113.11 142.04,113.67 142.04,114.06 v2(142.05,114.8)
USB30_RX_P_IN: length 7.3
  TOP w0.114: R292.1 143.1,113.58 L14.4 143.66,113.58 143.98,113.9 145.01,113.9 145.37,113.54 D10.1 145.79,113.54 145.85,113.48 145.97,113.48 146.47,113.97 147.8,113.97 148.37,113.4 148.65,113.4 148.76,113.51 148.76,114.14 USB3R1.6
USB30_TX_N: length 113.1
  TOP w0.076: U11.C13 93.69,66.26 93.61,66.01 93.61,65.84 93.67,65.65 93.67,65.5 93.61,65.38 93.61,64.99 93.88,64.72 v2(93.88,64.4)
  TOP w0.114: C238.1 140.04,115.64 139.86,115.47 139.86,115.36 v2(140.2,115.03)
  L4_IN2 w0.076: 102.41,63.82 102.39,63.82 102.37,63.84 101.34,63.84 101.16,64.02 96.21,64.02 96.03,63.84 95,63.84 94.94,63.89 94.81,63.89 94.69,64.02 94.69,64.15 94.44,64.4 94.31,64.4 94.25,64.46 94.25,64.59 94.11,64.73 93.75,64.73 93.67,64.66 93.67,64.6 v2(93.88,64.4)
  L4_IN2 w0.114: v2(140.2,115.03) 140.22,114.71 140.03,114.49 140.05,114.26 140.17,114.14 140.41,114.14 140.68,114.41 140.68,115.37 141.75,116.44 142.61,116.44 143.85,115.2 143.85,114.49 143.17,113.81 143.17,111.02 138.25,106.09 138.25,103 138.94,102.31 138.94,99.13 138.59,98.78 138.59,91.35 138.82,91.12 138.82,62.89 137.44,61.52 107.12,61.52 104.82,63.82 102.41,63.82
USB30_TX_N_C: length 4
  TOP w0.114: R299.2 142.11,117.82 L17.2 141.54,117.82 141.23,118.13 140.97,118.13 139.84,117.01 139.84,116.6 139.93,116.51 C238.2
USB30_TX_N_IN: length 7.2
  TOP w0.114: USB3R1.8 148.82,118.92 148.7,119.05 148.38,119.05 147.4,118.08 145.47,118.08 D13.2 145.04,117.65 143.98,117.65 143.82,117.82 L17.1 143.19,117.82 R299.1
USB30_TX_P: length 113.1
  TOP w0.076: v2(93.29,64.4) 93.44,64.55 93.44,65.41 93.48,65.51 93.48,65.7 93.44,65.79 93.44,66.04 93.58,66.52 93.58,66.63 93.66,66.9 U11.D13
  TOP w0.114: v2(139.58,114.98) 139.58,115.41 C237.1
  L4_IN2 w0.076: 102.41,64.03 102.4,64.03 102.38,64.02 101.42,64.02 101.24,64.2 96.14,64.2 95.96,64.02 95.07,64.02 94.18,64.91 93.67,64.91 93.42,64.65 93.42,64.53 v2(93.29,64.4)
  L4_IN2 w0.114: 102.41,64.03 104.9,64.03 107.21,61.73 137.35,61.73 138.61,62.98 138.61,91.03 138.37,91.26 138.37,98.87 138.72,99.22 138.72,102.22 138.03,102.91 138.03,106.18 142.96,111.1 142.96,113.9 143.63,114.58 143.63,115.11 142.52,116.22 141.84,116.22 140.89,115.28 140.89,114.32 140.5,113.92 140.08,113.92 139.84,114.17 139.82,114.48 139.6,114.66 v2(139.58,114.98)
USB30_TX_P_C: length 4
  TOP w0.114: R298.2 142.11,118.62 L17.3 141.57,118.39 140.86,118.39 139.59,117.11 139.59,116.74 C237.2
USB30_TX_P_IN: length 7.3
  TOP w0.114: R298.1 143.19,118.62 L17.4 143.95,118.62 144.07,118.74 145.09,118.74 145.39,118.43 D13.1 145.55,118.33 147.3,118.33 148.27,119.3 148.73,119.3 148.82,119.39 USB3R1.9
USB_5N: length 4.1
  TOP w0.102: L16.4 145.38,59.81 D12.1 146.44,59.38 USB2R2.2
USB_5P: length 4.2
  TOP w0.102: L16.1 144.06,59.01 144.39,58.68 145.49,58.68 D12.2 145.91,59.1 146.48,59.1 USB2R2.3
USB_5VOUT: length 0.9
  TOP w0.102: v4(140.15,63.64) 140.15,63.3 140.28,63.43 140.57,63.43 140.66,63.33
  vias: v4(136.85,84.44) v4(136.85,83.47) v4(136.85,82.46) v4(139.67,104.7) v4(140.15,64.65) v4(140.36,105.36) v4(141.04,105.97)
USB_8N: length 7.6
  TOP w0.114: L29.4 142.74,79.33 143.02,79.06 143.24,79.06 143.5,78.79 143.5,78.23 143.34,78.06 143.34,77.58 143.47,77.45 143.63,77.45 144.07,77.88 144.96,77.88 D11.1 145.72,77.48 145.78,77.42 146.56,77.42 147.32,78.18 USB2R1.2
USB_8P: length 7.6
  TOP w0.114: L29.1 142.74,78.53 143.02,78.8 143.13,78.8 143.25,78.69 143.25,78.33 143.08,78.17 143.08,77.47 143.4,77.16 143.59,77.16 144.04,76.7 144.96,76.7 D11.2 145.72,77.11 145.78,77.17 146.41,77.17 USB2R1.3
USB_PN1: length 85.9
  TOP w0.076: U11.AB9 96.32,76.54 96.76,76.97 v3(96.82,76.97)
  TOP w0.114: v2(136.83,113.02) 136.9,112.95 137.04,112.95 137.04,112.95 138.09,112.95 138.6,112.44 139.46,112.44 139.84,112.81 139.84,114 140.78,114.94 140.78,116.1 141.19,116.51 L12.3 142.11,116.51 R288.2
  L4_IN2 w0.076: 99.41,80.45 96.6,80.45 95.91,79.76 95.91,78.91 96.54,78.28 96.54,77.24 v3(96.82,76.97)
  L4_IN2 w0.114: 99.41,80.45 100.05,80.45 102.48,82.88 103.25,82.88 103.83,83.46 108.75,83.46 111.21,85.92 111.21,89.12 112.87,90.79 118.05,90.79 121.3,87.54 133.28,87.54 133.91,88.16 133.91,89.47 135.33,90.89 135.33,106.99 137.27,108.93 137.27,111.31 137.77,111.8 137.77,112.66 137.4,113.02 v2(136.83,113.02)
USB_PN2: length 124.6
  TOP w0.076: U11.AD6 98.42,77.76 v3(98.55,77.98)
  L4_IN2 w0.076: v3(98.55,77.98) 98.37,77.8 98.37,77.55 98.44,77.48 100.7,77.48 100.85,77.33 103.14,77.33 104.52,78.71 104.52,79.72 105.11,80.31 106.16,80.31 106.38,80.1 106.59,80.1 106.61,80.12 106.62,80.12
  L4_IN2 w0.114: v2(133.93,66.25) 133.93,66.46 134.24,66.77 134.95,66.77 135.69,67.51 135.69,69.16 135.09,69.76 135.09,70.68 133.89,71.87 133.89,74.93 132,76.82 131.49,76.82 120.16,76.82 117.51,79.47 109.92,79.47 109.27,80.12 106.62,80.12
  BOTTOM w0.114: v2(133.93,66.25) 133.68,66 133.68,62.9 138,58.58 138,55.27 140.74,52.53 140.74,46.29 141.15,45.88 141.15,42.81 140.63,42.3 140.63,37.26 136.98,33.6 136.98,32.85 133.07,28.94 115.21,28.94 110.9,33.25 110.9,38.1 R568.1
USB_PN2_LGA: length 2
  BOTTOM w0.114: R568.2 110.7,39.69 L25.2 110.7,41.15 R539.1
USB_PN2_M.2: length 52.1
  TOP w0.114: v2(83.26,27.31) 83.17,27.31 83,27.15 83,12.39 82.6,11.99 82.26,11.99 L49.3 81.71,11.44 R3243.2
  L3_IN1 w0.114: v2(83.26,27.31) 83.04,27.31 82.95,27.23 82.95,26.96 83.11,26.81 88.29,26.81 91.8,30.32 106.21,30.32 110.96,35.08 110.96,36.81 110.83,36.94 110.54,36.94 v2(110.44,36.84)
  BOTTOM w0.114: R566.2 v2(110.44,36.84)
USB_PN2_W: length 7.7
  TOP w0.114: R3243.1 80.56,11.67 L49.4 79.71,11.67 79.61,11.78 79.61,12.07 79.46,12.22 77.03,12.22 75.76,10.95 75.76,10.3 75.85,10.21 CN14.5
USB_PN4: length 200.3
  TOP w0.076: U11.AD9 96.32,77.43 96.22,77.32 96.06,77.32 95.98,77.4 v2(95.98,78.04)
  TOP w0.114: v2(9.96,62.61) 10.18,62.82 10.18,63.06 8.78,64.46 8.13,64.46 7.85,64.18 L32.3 6.98,64.18 R559.2
  L4_IN2 w0.076: 100.28,75.97 100.26,75.97 100.24,75.96 100.06,75.96 99.94,75.84 99.46,75.84 98.89,76.41 96.04,76.41 95.74,76.71 95.74,77.87 95.93,78.04 v2(95.98,78.04)
  L4_IN2 w0.114: v2(9.96,62.61) 10.17,62.81 10.17,63.14 10.41,63.38 11.12,63.38 13.6,60.91 13.6,56.02 16.82,52.8 29.72,52.8 31.86,54.94 34.31,54.94 35.04,54.22 39.46,54.22 40.37,55.13 52.34,55.13 58.19,60.98 68.33,60.98 70.52,63.16 76.92,63.16 78,62.08 84.98,62.08 85.55,61.5 90.25,61.5 90.98,62.23 104.91,62.23 106.68,60.46 131.81,60.46 132.44,59.83 133.77,59.83 v2(134.05,60.1) ; v2(132.58,67.34) 132.58,67.5 132.41,67.67 132.41,69.73 132.5,69.82 132.5,73.63 130.59,75.53 119.51,75.53 118.01,77.04 104.64,77.04 103.01,75.41 102.52,75.41 101.95,75.97 100.28,75.97
  BOTTOM w0.114: v2(132.58,67.34) 132.58,67.2 132.43,67.05 132.43,65.57 132.99,65.01 132.99,60.7 133.73,59.96 133.92,59.96 v2(134.05,60.1)
USB_PN4_CN_R: length 4.7
  TOP w0.114: R559.1 5.89,64.18 L32.4 5.24,64.18 4.98,64.43 4.57,64.43 3.34,65.67 2.7,65.67 CN9.P15
USB_PN5: length 57.2
  TOP w0.076: v2(105.38,79.74) 105.58,79.94 105.58,80.42 105.32,80.69 104.28,80.69 104.02,80.95 102.04,80.95 101.86,80.76 101.37,80.76 101.31,80.82 101.07,80.82 101,80.75 U11.AJ1
  TOP w0.114: v2(133.86,68.39) 133.91,68.44 134.4,68.44 134.56,68.28 134.99,68.28 135.45,67.82 135.45,67.19 135.86,66.78 135.86,64.5 137.29,63.08 137.47,63.08 141.19,59.36 141.39,59.36 141.45,59.41 141.45,59.64 141.62,59.81 L16.3
  L4_IN2 w0.076: v2(105.38,79.74) 105.47,79.74 105.6,79.61 105.6,79.47 105.79,79.28 106.42,79.28 106.46,79.24 106.62,79.24
  L4_IN2 w0.114: v2(133.86,68.39) 133.91,68.44 134.37,68.44 134.43,68.5 134.43,68.95 133.04,70.34 133.04,74.58 131.66,75.95 119.68,75.95 117.02,78.62 113.76,78.62 113.66,78.52 113.32,78.52 113.22,78.62 112.88,78.62 112.78,78.52 112.44,78.52 112.34,78.62 111.11,78.62 111.01,78.52 110.49,78.52 110.39,78.62 110.1,78.62 110,78.52 109.67,78.52 108.92,79.27 106.65,79.27 106.62,79.24
USB_PN6: length 83.1
  TOP w0.076: U11.AF6 98.28,78.77 v3(98.55,79.05)
  TOP w0.114: v2(140.43,119.81) 140.61,119.99 141.96,119.99 142.27,120.3 142.27,120.76 142.53,121.02 142.78,121.02 143.05,121.28 143.05,121.53 143.32,121.81 L11.4
  L4_IN2 w0.114: v3(98.55,79.05) 98.38,79.21 98.38,79.49 98.57,79.67 100.93,79.67 104.09,82.83 129.47,82.83 134.54,87.9 134.54,88.36 136.01,89.83 136.01,106.76 137.9,108.66 137.9,111.02 138.44,111.56 138.44,113.02 137.18,114.27 137.18,116.25 136.8,116.64 136.8,118.92 138.39,120.52 139.37,120.52 139.86,120.02 140.22,120.02 v2(140.43,119.81)
USB_PN7: length 85.1
  TOP w0.076: v2(103.45,79.66) 103.45,79.71 103.21,79.95 103.21,80.01 103.03,80.19 101.44,80.19 101.36,80.11 100.73,80.11 U11.AH1
  TOP w0.114: v2(143.3,119.51) 143.57,119.79 144.39,119.79 145.38,120.77 145.38,121.95 L13.4
  L4_IN2 w0.114: v2(143.3,119.51) 143.3,119.61 143.1,119.82 142.62,119.82 141.57,118.76 140.2,118.76 139.22,119.74 138.68,119.74 138.15,119.21 138.15,115.05 138.49,114.7 138.49,114.39 139.16,113.72 139.64,113.72 140.62,112.74 140.62,110.48 136.76,106.61 136.76,89.68 135.18,88.1 135.18,87.63 129.73,82.19 104.3,82.19 104.09,81.98 104.09,81.67 103.79,81.38 103.49,81.38 103.24,81.13 103.24,79.92 103.45,79.71 v2(103.45,79.66)
USB_PN8: length 51.7
  TOP w0.076: v3(96.95,79.12) 96.77,78.95 96.77,78.74 96.92,78.59 U11.AF8
  TOP w0.114: v2(133.34,76.8) 133.34,76.79 133.45,76.67 133.51,76.67 133.6,76.58 134,76.58 134.54,77.12 134.54,79.07 135.7,80.23 138.62,80.23 139.47,79.38 139.47,79.18 139.72,78.93 139.87,78.93 140.27,79.33 L29.3
  L4_IN2 w0.076: v3(96.95,79.12) 96.91,79.12 96.67,78.88 96.67,78.78 96.89,78.56 100.07,78.56 100.37,78.85
  L4_IN2 w0.114: 100.37,78.85 100.75,79.24 103.72,79.24 103.94,79.45 103.94,80.04 104.77,80.88 106.44,80.88 106.55,80.77 109.64,80.77 110.3,80.11 118.49,80.11 120.57,78.03 121.57,78.03 122.08,77.52 132.2,77.52 132.92,76.8 v2(133.34,76.8)
USB_PN9: length 3.2
  TOP w0.076: U11.AG1 101.81,79.39 102.18,79.02 104.06,79.02 TP81.1
USB_PP1: length 85.9
  TOP w0.076: U11.AB10 95.72,76.46 v3(96.18,76.92)
  TOP w0.114: v2(136.85,112.49) 137.05,112.7 137.98,112.7 138.5,112.18 139.57,112.18 140.09,112.71 140.09,113.89 141.03,114.84 141.03,115.99 141.18,116.14 141.62,116.14 141.8,115.95 L12.2 142.11,115.71 R289.2
  L4_IN2 w0.076: 99.41,80.67 99.4,80.67 99.38,80.65 99.33,80.65 99.31,80.63 96.53,80.63 95.73,79.84 95.73,78.84 96.37,78.2 96.37,77.1 v3(96.18,76.92)
  L4_IN2 w0.114: v2(136.85,112.49) 137.16,112.81 137.31,112.81 137.55,112.57 137.55,111.89 137.05,111.4 137.05,109.02 135.12,107.08 135.12,90.98 133.69,89.56 133.69,88.25 133.19,87.75 121.39,87.75 118.14,91 112.78,91 110.99,89.21 110.99,86.01 108.66,83.68 103.74,83.68 103.16,83.1 102.39,83.1 99.96,80.67 99.41,80.67
USB_PP2: length 124.6
  TOP w0.076: v3(97.9,77.98) 97.76,77.76 U11.AD7
  L4_IN2 w0.076: 106.62,79.9 106.61,79.9 106.59,79.92 106.3,79.92 106.09,80.13 105.19,80.13 104.7,79.65 104.7,78.64 103.21,77.15 100.78,77.15 100.63,77.31 98.36,77.31 98.19,77.48 98.19,77.9 98.11,77.98 v3(97.9,77.98)
  L4_IN2 w0.114: v2(133.53,66.7) 133.53,66.71 133.87,66.71 134.15,66.99 134.86,66.99 135.47,67.6 135.47,69.08 134.87,69.67 134.87,70.59 133.68,71.78 133.68,74.84 131.91,76.61 131.49,76.61 120.07,76.61 117.42,79.26 109.83,79.26 109.18,79.9 106.62,79.9
  BOTTOM w0.114: R565.1 111.53,38.72 111.34,38.72 111.15,38.54 111.15,33.36 115.32,29.2 132.97,29.2 136.73,32.96 136.73,33.71 140.38,37.36 140.38,42.4 140.89,42.92 140.89,45.77 140.48,46.18 140.48,52.43 137.73,55.18 137.73,58.49 133.43,62.8 133.43,66.61 v2(133.53,66.7)
USB_PP2_LGA: length 2
  BOTTOM w0.114: R548.1 111.5,41.15 L25.3 111.5,39.64 R567.2
USB_PP2_M.2: length 51.9
  TOP w0.114: R3239.2 81.84,12.58 L49.2 82.18,12.24 82.49,12.24 82.75,12.5 82.75,27.12 v2(82.58,27.28)
  L3_IN1 w0.114: v2(111.71,36.84) 111.29,36.84 111.18,36.73 111.18,34.99 106.3,30.11 91.89,30.11 88.38,26.59 83.02,26.59 82.74,26.87 82.74,27.13 v2(82.58,27.28)
  BOTTOM w0.114: R565.2 v2(111.71,36.84)
USB_PP2_W: length 7.7
  TOP w0.114: CN14.3 75.35,10.14 75.51,10.3 75.51,11.06 76.93,12.47 L49.1 80.69,12.47 R3239.1
USB_PP4: length 200.3
  TOP w0.076: v2(95.35,78.06) 95.67,77.73 U11.AD10
  TOP w0.114: v2(10.62,62.61) 10.61,62.61 10.43,62.79 10.43,63.16 8.88,64.71 8.13,64.71 7.85,64.98 L32.2 6.98,64.98 R558.2
  L4_IN2 w0.076: v2(95.35,78.06) 95.36,78.06 95.56,77.84 95.56,76.64 95.97,76.23 98.81,76.23 99.39,75.66 100.01,75.66 100.13,75.78 100.24,75.78 100.26,75.76 100.28,75.76
  L4_IN2 w0.114: v2(132.05,67.34) 132.05,67.52 132.19,67.67 132.19,69.82 132.28,69.91 132.28,73.54 130.5,75.32 119.42,75.32 117.92,76.82 104.73,76.82 103.1,75.19 102.43,75.19 101.87,75.76 100.28,75.76 ; v2(134.12,59.52) 134.03,59.61 132.35,59.61 131.72,60.25 106.59,60.25 104.82,62.02 91.07,62.02 90.34,61.29 85.46,61.29 84.89,61.86 77.91,61.86 76.83,62.95 70.61,62.95 68.42,60.76 58.28,60.76 52.43,54.91 40.46,54.91 39.54,54 34.95,54 34.22,54.72 31.95,54.72 29.81,52.58 16.73,52.58 13.39,55.93 13.39,60.82 11.03,63.17 10.5,63.17 10.38,63.05 10.38,62.85 v2(10.62,62.61)
  BOTTOM w0.114: v2(134.12,59.52) 133.97,59.52 133.78,59.71 133.62,59.71 132.74,60.59 132.74,64.91 132.18,65.47 132.18,67.05 132.05,67.18 v2(132.05,67.34)
USB_PP4_CN_R: length 4.7
  TOP w0.114: R558.1 5.88,64.98 L32.1 5.26,64.98 4.97,64.69 4.68,64.69 3.44,65.93 2.66,65.93 CN9.P14
USB_PP5: length 57.3
  TOP w0.076: U11.AJ2 100.5,80.72 100.65,80.87 101.01,81.04 101.4,81.04 101.46,80.98 101.77,80.98 101.95,81.17 104.11,81.17 104.37,80.9 105.41,80.9 105.8,80.51 105.8,79.89 v2(105.89,79.79)
  TOP w0.114: v2(134.21,67.98) 134.26,68.03 134.89,68.03 135.2,67.72 135.2,67.09 135.61,66.68 135.61,64.39 137.18,62.82 137.37,62.82 141.09,59.11 141.43,59.11 141.52,59.01 L16.2
  L4_IN2 w0.076: 106.62,79.48 106.56,79.48 106.53,79.46 106.5,79.46 106.5,79.45 106.5,79.46 105.87,79.46 105.78,79.54 105.78,79.68 v2(105.89,79.79)
  L4_IN2 w0.114: 106.62,79.48 109.01,79.48 109.66,78.83 117.11,78.83 119.77,76.17 131.75,76.17 133.26,74.67 133.26,70.43 134.64,69.04 134.64,68.41 v2(134.21,67.98)
USB_PP6: length 83.1
  TOP w0.076: v3(97.9,79.05) U11.AF7
  TOP w0.114: v2(140.43,120.45) 140.63,120.25 141.86,120.25 142.02,120.41 142.02,120.87 142.43,121.27 142.68,121.27 142.79,121.39 142.79,121.49 142.52,121.75 L11.1
  L4_IN2 w0.114: v2(140.43,120.45) 140.22,120.24 139.95,120.24 139.46,120.73 138.3,120.73 136.58,119.01 136.58,116.55 136.97,116.16 136.97,114.18 138.22,112.93 138.22,111.65 137.69,111.11 137.69,108.75 135.79,106.85 135.79,89.92 134.33,88.45 134.33,87.99 129.38,83.04 104,83.04 100.84,79.89 98.48,79.89 98.17,79.58 98.17,79.23 97.98,79.05 v3(97.9,79.05)
USB_PP7: length 85.1
  TOP w0.076: U11.AH2 100.26,79.82 100.49,79.82 100.62,79.77 100.72,79.77 100.97,79.86 101.14,79.95 101.43,79.95 101.5,80.02 102.96,80.02 103.04,79.94 103.04,79.87 103.03,79.86 103.03,79.75 v2(102.94,79.66)
  TOP w0.114: v2(143.3,120.15) 143.41,120.04 144.29,120.04 145.12,120.87 145.12,121.87 L13.1
  L4_IN2 w0.114: v2(143.3,120.15) 143.18,120.03 142.53,120.03 141.48,118.98 140.29,118.98 139.31,119.96 138.59,119.96 137.93,119.3 137.93,114.96 138.27,114.61 138.27,114.3 139.07,113.5 139.55,113.5 140.41,112.65 140.41,110.57 136.54,106.7 136.54,89.77 134.96,88.19 134.96,87.72 129.64,82.41 104.21,82.41 103.03,81.22 103.03,79.75 v2(102.94,79.66)
USB_PP8: length 51.7
  TOP w0.076: v3(96.39,79.12) 96.39,78.65 U11.AF9
  TOP w0.114: L29.2 140.23,78.53 140.08,78.68 139.62,78.68 139.22,79.08 139.22,79.28 138.52,79.98 135.8,79.98 134.79,78.97 134.79,77.02 134.1,76.33 133.43,76.33 v2(133.31,76.21)
  L4_IN2 w0.076: 100.52,78.7 100.2,78.38 96.81,78.38 96.49,78.71 96.49,79.02 v3(96.39,79.12)
  L4_IN2 w0.114: 100.52,78.7 100.84,79.02 103.81,79.02 104.15,79.36 104.15,79.95 104.86,80.66 106.35,80.66 106.46,80.56 109.55,80.56 110.21,79.89 118.4,79.89 120.48,77.81 121.48,77.81 121.99,77.3 132.11,77.3 132.96,76.46 133.02,76.46 133.28,76.21 v2(133.31,76.21)
USB_PP9: length 4.1
  TOP w0.076: TP82.1 103.96,78.49 102.31,78.49 101.62,79.18 101.27,79.18 101.23,79.14 100.87,79.14 100.7,79.26 U11.AG2
V_ADPATER: length 4
  TOP w0.203: R29.2 19.02,96.88 19.02,96.17 R30.1 18.55,95.15 U1.37
V_DDR_CB_VREF: length 101.2
  TOP w0.076: 61.48,88.62 61.88,88.22 62.22,88.22 62.42,88.02 62.42,87.8 62.79,87.42 U11.BA67
  TOP w0.254: v2(56.5,87.66) 56.5,88.02 57.27,88.79 61.31,88.79 61.48,88.62
  TOP w0.508: v2(56.5,87.66) 56.5,87.31 56.11,86.92 54.45,86.92 52.43,84.89 v3(46.79,84.89)
  L4_IN2 w0.508: v3(46.69,117.64) 46.31,117.26 46.31,112.13 46.79,111.65 v3(46.79,84.89)
  BOTTOM w0.508: C76.2 56.5,88.44 v2(56.5,87.66) ; v3(46.69,117.64) 46.69,118.01 50.55,121.87 50.55,125.17 52.02,126.65 54.43,126.65 55.61,127.82 71.34,127.82 71.6,128.08 71.6,129.16 72.24,129.8 86.56,129.8 R66.2
VAC: length 30
  TOP w0.203: v3(18.21,92.77) 17.83,93.15 U1.32
  TOP w0.254: R3323.1 29,76.74 28.6,77.14 28.6,78.66 27.96,79.3 24.09,79.3 23.71,78.92 22.02,78.92 v3(21.95,78.98)
  L3_IN1 w0.254: v3(21.95,78.98) 22.5,79.53 22.5,80.57 22.75,80.82 22.75,81.46 22.71,81.5 22.71,82.03 22.04,82.69 22.04,86.01 v3(21.47,86.59)
  L4_IN2 w0.254: v3(18.21,92.77) 19.19,92.77 21.61,90.35 21.61,86.73 v3(21.47,86.59)
  BOTTOM w0.508: v3(18.21,92.77) 18.41,92.97 C363.1 R418.2
VAD: length 145
  TOP w0.508: v3(113.71,134.27) 113.86,134.27 116.77,137.18
  L3_IN1 w0.508: v4(10.5,94.84) 11.37,94.84 12.72,96.19 12.72,98.54 12.15,99.11 12.15,101.13 15.13,104.11 15.13,105.82 14.44,106.51 14.44,111.05 13.61,111.88 13.61,115.61 13.41,115.81 13.41,116.49 12.44,117.47 12.44,118.48 13.63,119.66 13.63,123.85 16.74,126.97 19.69,126.97 20.83,128.11 23.03,128.11 23.6,128.68 23.6,128.92 24.52,129.84 28.01,129.84 28.66,129.19 32.31,129.19 33.27,130.15 v3(36.61,130.15)
  L4_IN2 w0.508: v3(36.61,130.15) 44.53,130.15 45.56,131.19 48.78,131.19 49.18,131.6 61.89,131.6 62.56,130.92 68.27,130.92 69.23,131.88 71.9,131.88 72.62,132.61 89.3,132.61 89.9,132 99.85,132 100.77,132.92 105.18,132.92 106.44,131.65 107.56,131.65 109.62,133.72 113.16,133.72 v3(113.71,134.27)
  vias: v4(9.52,95.73) v4(9.55,94.86) v4(10.5,95.73)
VB: length 38.2
  L4_IN2 w0.102: v3(133.63,125.31) 133.63,126.17 132.64,127.15 132.64,135 129.99,137.64 v3(129.99,139.96)
  BOTTOM w0.102: v3(133.63,125.31) 133.55,125.23 133.55,124.8 133.36,124.61 132.83,124.61 132.35,124.13 132.35,123.57 131.25,122.48 Q27.3 131.25,120.23 130.99,119.97 130.68,119.97 129.95,119.25 Q27.6 129.07,118.81 129,118.75 R228.2 R234.2 126.57,118.04 125.5,118.04 125.24,118.29 Q16.2 ; Q24.3 126.67,136.39 127.53,137.25 127.53,138.07 126.95,138.65 126.95,139.14 127.15,139.34 127.15,140.04 127.45,140.34 129.61,140.34 v3(129.99,139.96)
VCHG: length 74.9
  TOP w0.203: v3(18.41,96.43) 18.26,96.43 17.78,95.95 U1.39
  TOP w0.254: v3(11.12,100.03) 10.76,100.39 R8.1 ; C3579.2 22.07,78.14 v3(21.97,78.25)
  L3_IN1 w0.203: v3(18.41,96.43) 18.59,96.43 19.07,95.94 19.07,91.42 17.78,90.13 17.78,84.8 13,80.02 9.49,80.02 v3(9.24,79.77)
  L4_IN2 w0.254: v3(11.12,100.03) 12.41,100.03 12.57,99.88 20.44,99.88 v3(20.87,99.45)
  BOTTOM w0.203: R471.2 9.24,79.76 v3(9.24,79.77)
  BOTTOM w0.508: v3(20.87,99.45) 20.9,99.42 D17.A 22.04,99.07 22.04,95.28 22.42,94.9 22.42,92.92 22.35,92.84 22.35,84.09 23.16,83.27 23.16,80.98 22.59,80.4 22.59,78.56 22.28,78.25 v3(21.97,78.25) 21.97,77.83 21.69,77.56 19.6,77.56 18.31,78.85 17.63,78.85 16.87,79.62 16.87,81.54 16.36,82.05 15.38,82.05 13.28,79.94
VCLK_R: length 4
  TOP w0.102: U109.6 23.48,44.91 23.35,44.78 21.26,44.78 R622.2
VCORE_ON: length 108.7
  TOP w0.102: v3(10.56,46.66) 11.01,47.1 19.33,47.1 v3(19.83,46.6)
  L4_IN2 w0.102: v3(4.56,66.69) 4.72,66.69 5.96,67.93 5.96,69.85 5.57,70.24 5.57,76.2 6.21,76.85 6.21,82.68 5.24,83.65 5.24,93.3 5.01,93.53 5.01,97.23 6.27,98.49 6.27,101.07 10.11,104.91 10.11,111.04 9.72,111.42 9.72,113.99 9.43,114.28 9.43,118.33 11.43,120.33 11.43,122.32 17.49,128.39 v3(17.49,129.98)
  BOTTOM w0.102: R621.2 21.68,45.64 21.04,45.64 20.09,46.6 v3(19.83,46.6) ; U25.84 17.45,130.03 v3(17.49,129.98) ; v3(10.56,46.66) 10.56,50.28 11.96,51.68 11.96,54.91 11.32,55.55 9.94,55.55 4.34,61.16 4.34,66.47 4.56,66.69 v3(4.56,66.69)
VCORE_VCCSENSE: length 72.8
  TOP w0.102: v3(82.34,67.77) 82.57,68 U11.E32
  TOP w0.127: v3(23.28,49.4) 23.28,50.5 R3401.1
  L3_IN1 w0.127: v3(29.93,58.9) 30.08,58.75 30.08,58.74 30.12,58.7 30.12,56.85 23.45,50.18 23.45,49.58 v3(23.28,49.4)
  L4_IN2 w0.102: v3(82.34,67.77) 82.14,67.98 81.51,67.98 81.41,68.08 76.61,68.08 75.64,67.11 73.11,67.11 72.37,66.36 68.92,66.36 68.72,66.16 66.93,66.16 66.72,65.95
  L4_IN2 w0.127: v3(29.93,58.9) 29.93,58.85 30.44,58.34 34.06,58.34 34.63,58.92 50.54,58.92 56.15,64.53 59.68,64.53 61.1,65.95 66.72,65.95
  BOTTOM w0.127: R3153.1 82.59,67.52 v3(82.34,67.77)
VCORE_VSSSENSE: length 70.7
  TOP w0.102: U11.E33 81.93,68 v3(82.34,68.41)
  TOP w0.127: v3(23.84,49.4) 23.84,49.92 R3405.1
  L3_IN1 w0.127: v3(23.84,49.4) 23.84,49.45 23.71,49.58 23.71,50.08 30.37,56.75 30.37,58.78 v3(30.49,58.89)
  L4_IN2 w0.102: 66.79,66.39 68.62,66.39 68.83,66.59 72.27,66.59 73.02,67.34 75.55,67.34 76.52,68.31 81.51,68.31 81.61,68.21 82.14,68.21 v3(82.34,68.41)
  L4_IN2 w0.127: 66.79,66.39 66.61,66.2 61,66.2 59.57,64.78 56.05,64.78 50.44,59.17 34.52,59.17 33.95,58.6 30.54,58.6 30.46,58.68 30.46,58.86 v3(30.49,58.89)
  BOTTOM w0.127: v3(82.34,68.41) 82.32,68.39 R3154.2
VDHF: length 2.2
  TOP w0.203: U1634.D7 127.17,19.55 128.82,19.55 C502.2
VDIO_R: length 1.8
  TOP w0.102: R651.2 23.66,44.11 U109.8
VEN: length 7.8
  TOP w0.102: U1634.E1 123.54,18.95 v3(122.88,18.3)
  BOTTOM w0.102: v3(122.88,18.3) 120.27,18.3 R120.1 119.45,17.54 119.05,17.94 117.62,17.94 R743.2
VIDALERT#: length 61.8
  TOP w0.076: R660.2 59.15,60.33
  TOP w0.102: 59.15,60.33 59.15,60.25 v2(59.79,59.62) ; v3(17.93,44.88) 18.25,44.88 19.26,43.87 21.41,43.87 R647.1
  BOTTOM w0.102: v3(17.93,44.88) 18.56,45.52 18.56,49.26 21.42,52.12 21.45,52.12 21.48,52.15 28.75,52.15 33.07,56.46 53.54,56.46 55.89,58.81 55.89,60.21 57.42,61.74 57.42,61.99 57.74,62.31 58.65,62.31 R691.1 58.67,61.32 58.67,60.69 59.18,60.18 59.18,59.57 R89.1 59.53,59.36 v2(59.79,59.62)
VIDSCLK: length 58.2
  TOP w0.076: R687.2 60.42,60.71 v2(60.42,60.28)
  TOP w0.102: v3(17.93,45.64) 18.06,45.52 R622.1 R3414.1
  BOTTOM w0.102: v2(60.42,60.28) 60.42,60.3 60.7,60.58 60.7,61.29 R690.1 59.36,62.64 57.59,62.64 57.12,62.17 57.12,61.87 55.59,60.34 55.59,58.94 53.42,56.77 32.94,56.77 28.62,52.45 21.32,52.45 18.25,49.38 18.25,45.96 v3(17.93,45.64)
VIDSOUT: length 60.1
  TOP w0.102: v3(58.8,60.02) 58.67,60.15 58.67,60.18 58.49,60.35 58.49,60.48 R688.2 ; R651.1 21.28,42.6 20.16,42.6 R3413.1 19.55,43.21 18.97,43.21 v3(17.87,44.31)
  BOTTOM w0.076: 57.88,61.6 R88.1
  BOTTOM w0.102: v3(17.87,44.31) 18.06,44.31 18.88,45.14 18.88,49.26 21.56,51.94 28.86,51.94 33.18,56.26 53.63,56.26 56.12,58.75 56.12,60.15 57.57,61.6 57.88,61.6 ; R88.1 58.47,61.37 58.47,60.38 58.67,60.18 58.67,60.15 v3(58.8,60.02) 58.67,59.9 58.67,59.85 58.42,59.59 58.19,59.59 R689.1
VMID: length 2.5
  TOP w0.203: U1634.F7 127.42,18.45 127.53,18.34 128.38,18.34 C503.1
VR_EN: length 2.5
  TOP w0.102: v3(23.39,46.6) 23.47,46.51 U109.2
  BOTTOM w0.102: v3(23.39,46.6) 23.37,46.57 22.88,46.57 C586.1 R621.1
VR_READY: length 3.1
  TOP w0.203: U109.33 27.58,48.24 28.11,48.78 28.11,49.42 28.47,49.77 R3426.1
WB_ANTA: length 6.3
  TOP w0.381: WIFI1.2 124.04,41.76 arc(124.39,41.74) 124.73,41.7 126.15,41.22 arc(127.7,40.51) C207.1
WEBCAM_+5V: length 8
  TOP w0.381: v3(131.01,128.28) 130.86,128.28 130.44,127.86 CN7.15
  BOTTOM w0.508: v3(131.01,128.28) 130.85,128.28 130.6,128.53 C289.1 C281.1 130.27,130.06 130.27,131.78 129.66,132.39 B19.1
WEBCAM_ON: length 169.2
  TOP w0.102: v3(133.04,125.31) 133.04,125.18 R462.2
  L4_IN2 w0.102: v3(61.16,139.46) 61.87,140.17 69.13,140.17 70.57,138.73 72.72,138.73 74.36,140.37 82.75,140.37 83.43,139.68 88.55,139.68 89.01,139.23 100.01,139.23 100.24,139.45 108.98,139.45 109.97,140.45 117.09,140.45 117.7,139.83 121.87,139.83 122.83,138.87 124.7,138.87 126.65,136.92 130.12,136.92 132,135.04 132,127.32 133.04,126.27 v3(133.04,125.31) 133.04,124.98 134.77,123.25 134.77,114.62 135.53,113.86 135.53,110.51 133.29,108.28 133.29,104.75 132.55,104 132.55,98.64 v3(132.39,98.49)
  BOTTOM w0.102: R695.2 135.95,98.49 v3(132.39,98.49) ; v3(61.16,139.46) 60.83,139.78 60.28,139.78 60.15,139.66 51.39,139.66 50.78,139.05 49.03,139.05 48.42,139.66 33.8,139.66 v1(32.71,138.57) 24.33,130.18 23.05,130.18 21.76,128.89 21.76,127.23 22.37,126.63 22.68,126.63 22.78,126.72 U25.104
WEBCAM_USB+: length 4.5
  TOP w0.114: 141.06,125.38 141.06,126.42 CN7.36 ; 141.06,125.38 141.04,125.36 S33.1 ; 141.06,125.38 141.06,124.92 141.34,124.64 142.72,124.64 142.83,124.53 142.83,124.38 142.52,124.07 L11.2
WEBCAM_USB-: length 4.5
  TOP w0.114: 141.32,125.41 141.37,125.36 S34.1 ; 141.32,125.41 141.32,126.42 CN7.37 ; 141.32,125.41 141.32,125.02 141.44,124.9 142.83,124.9 143.09,124.64 143.09,124.33 143.32,124.09 L11.3
WIFI_BT_ANT_CN: length 2.4
  TOP w0.356: ANT1.S2 C209.1 B5.2
WIFI_BT_ANT_R: length 2.6
  TOP w0.356: C208.1 B5.1
  TOP w0.381: C208.1 arc(129.82,38.17) C207.2
WLAN_3.3VDD: length 5.3
  TOP w0.254: v3(75.05,3) 75.1,2.94 CN14.2 ; v3(92.15,3.06) 92.6,2.6 CN14.72 ; CN14.4 75.6,3.06 v3(75.6,3.06) ; CN14.74 93.1,2.99 v3(92.91,3.18)
WLAN_HOST_WAKE_EC: length 270.3
  TOP w0.102: R3252.2 88.79,13.63 v3(88.79,28.18)
  L3_IN1 w0.102: v3(88.79,28.18) 91.18,30.57 106.07,30.57 107.9,32.39 107.9,48.27 108.86,49.23 108.86,49.9 109.79,50.84 110.82,50.84 111.88,51.9 112.77,51.9 114.16,53.3 122.33,53.3 124.01,54.98 v3(127.78,54.98) ; v3(127.45,74.32) 127.45,75.97 130.78,79.3 130.78,81.32 129.47,82.63 129.47,89.21 124.61,94.08 124.61,98.85 122.7,100.76 121.53,100.76 116.61,105.67 116.61,118.53 117.14,119.05 117.14,119.93 118.4,121.19 118.4,123.85 117.42,124.83 117.42,126.37 116.91,126.88 91.82,126.88 91.3,127.4 74.31,127.4 73.23,126.32 67.87,126.32 67.49,125.94 51.16,125.94 49.06,128.04 47.22,128.04 47.05,127.87 46,127.87 44.85,129.02 38.79,129.02 35.94,126.17 34.46,126.17 33.44,125.14 29.1,125.14 28.4,124.44 26.95,124.44 26.29,123.78 23.43,123.78 23.12,123.48 21.74,123.48 21.09,124.13 19.15,124.13 v3(18.99,123.97)
  BOTTOM w0.102: R518.2 128.31,53.17 127.78,53.69 v3(127.78,54.98) v1(127.78,55.76) 126.95,56.6 126.95,67.31 126.23,68.02 126.23,70.29 127.12,71.18 127.12,73.06 127.45,73.39 v3(127.45,74.32) ; U25.85 17.85,130.17 17.88,130.14 17.88,125.43 18.99,124.32 v3(18.99,123.97)
WLAN_HOST_WAKE_SOC: length 165.9
  TOP w0.076: U11.BB15 92.46,88.26 93.39,89.19 93.39,89.92 95.29,91.83 98.09,91.83 98.83,92.57 100.48,92.57 100.78,92.87 104.24,92.87 105.4,91.7 106.6,91.7
  TOP w0.102: v3(90.26,27.8) 89.93,27.48 89.93,12.1 R3249.2 ; v3(125.79,55.76) 125.36,56.19 125.36,60.02 123.69,61.69 123.69,65.25 124.09,65.65 124.09,66.61 118.72,71.98 118.72,77.94 120.6,79.83 R365.1 120.6,89.04 118.83,90.8 116.92,90.8 116.4,91.32 112.47,91.32 111.83,91.96 110.31,91.96 110.05,91.7 106.6,91.7
  L3_IN1 w0.102: v3(90.26,27.8) 108.99,27.8 110.15,28.97 132.97,28.97 137.79,33.78 137.79,39.42 136.61,40.6 134.78,40.6 132.71,42.67 132.71,51.14 127.83,56.02 126.05,56.02 v3(125.79,55.76)
WLAN_ON: length 302
  TOP w0.102: v3(126.74,55.64) 125.24,54.14 R199.1 ; CN14.56 v3(88.6,3.05)
  L3_IN1 w0.102: v3(108.8,28.44) 109.58,29.22 132.94,29.22 137.59,33.86 137.59,39.33 136.52,40.4 134.69,40.4 132.51,42.58 132.51,51.06 127.93,55.64 v3(126.74,55.64) ; v3(16.02,123.49) 16.72,123.49 17.04,123.82 18.56,123.82 18.81,123.57 19.37,123.57 19.73,123.92 21,123.92 21.65,123.27 23.21,123.27 23.51,123.58 26.38,123.58 27.04,124.24 28.48,124.24 29.19,124.94 33.56,124.94 34.42,124.09 37.44,124.09 40.03,126.68 50.13,126.68 51.07,125.74 69.27,125.74 69.63,125.38 74.21,125.38 75.51,126.68 110.83,126.68 114.78,122.73 114.78,112.6 115.34,112.04 115.34,106.66 121.44,100.55 122.61,100.55 124.4,98.76 124.4,94 129.27,89.13 129.27,81.93 130.14,81.06 130.14,78.95 126.25,75.05 v3(126.25,74.83)
  BOTTOM w0.102: v3(16.02,123.49) 16.39,123.12 16.39,119.9 15.89,119.4 15.89,116.72 15.85,116.67 U25.17 ; v3(108.8,28.44) 110.19,27.04 110.19,16.43 111.34,15.29 111.34,8.05 105.26,1.97 89.49,1.97 R3248.2 88.6,2.86 v3(88.6,3.05) ; v3(126.74,55.64) 126.74,67.18 126.03,67.89 126.03,74.61 v3(126.25,74.83)
XDP_TCK_JTAGX: length 4.7
  TOP w0.076: R98.1 66.53,62.73 67.03,62.73 67.71,63.42 67.71,63.98 67.7,63.99 67.7,65.04 67.74,65.09 U11.A59
XTAL_IN: length 8.5
  TOP w0.102: U1634.A3 125.07,21.31 124.41,21.98 122.96,21.98 C1205.2 122.63,23.33 122.63,24.75 R784.2 122.23,25.77 Y6.3
XTAL_OUT: length 10.2
  TOP w0.076: 125.32,21.44 125.32,20.2 U1634.C3
  TOP w0.102: 125.32,21.44 124.53,22.23 123.97,22.23 C1206.2 122.88,23.33 122.88,24.93 R784.1 123.09,27.37 Y6.1
N123255: length 9.2
  BOTTOM w0.203: Q31.4 7.4,101.67 6.86,102.21 R1.2
  BOTTOM w0.254: R3.1 1.85,105.01 3.06,103.8 5.73,103.8 6.86,102.67 R1.2
N123817: length 3
  BOTTOM w0.102: R378.2 R379.2 18.67,109.58 18.43,109.82 U28.15
N126703: length 1.7
  BOTTOM w0.102: R390.1 18.47,101.37 U28.28
N126765: length 2.8
  BOTTOM w0.102: U28.7 9.7,105.27 9.11,104.68 R386.2
N15641221: length 1.8
  BOTTOM w0.102: R381.2 9.67,107.22 U28.10
N15767439: length 2.6
  BOTTOM w0.102: U25.12 17.85,114.72 C339.1
N16053782: length 5.8
  BOTTOM w0.102: Q24.5 123.95,137.04 123.72,137.27 123.72,137.86 123.34,138.23 122.85,138.23 R319.2 R314.1 122.88,139.33 124.31,137.9 Q24.6
N17639924: length 2.7
  BOTTOM w0.102: R366.2 R367.2 130.6,117.69 Q27.5
N18176932: length 7.2
  BOTTOM w0.102: AR11.2 156.69,32.01 156.69,33.15 156.99,33.46 156.99,34.56 AC4.2 158.51,36.07 AR9.2
N18176934: length 1.8
  BOTTOM w0.102: AR9.1 158.67,34.73 158.44,34.73 AC6.2
N18775510: length 1.9
  BOTTOM w0.102: U28.11 10.04,107.87 R380.2
N18791800: length 25.6
  TOP w0.102: v3(147.19,46.62) 147.19,47.23 146.61,47.81 145.06,47.81 144.22,48.65 144.22,50.17 v3(144.19,50.19)
  BOTTOM w0.102: U33.47 148.51,37.21 148.36,37.37 148.08,37.37 147.98,37.47 147.98,37.88 146.53,39.32 144.7,39.32 144.6,39.42 144.6,40.06 144.02,40.64 144.02,41.43 144.89,42.3 145.46,42.3 145.72,42.56 145.72,43.57 144.22,45.06 144.22,50.17 v3(144.19,50.19) ; R534.2 R533.1 146.88,46.92 v3(147.19,46.62)
N20449136: length 83
  TOP w0.076: U11.R11 95.17,73.46 v3(95.36,73.71)
  L4_IN2 w0.076: 104.92,74.3 104.36,74.3 104.27,74.21 103.52,74.21 103.39,74.09 95.74,74.09 95.37,73.71 v3(95.36,73.71)
  L4_IN2 w0.102: v3(132.05,88.32) 132.05,88.57 131.95,88.67 131.95,88.99 132.13,89.16 132.13,90.84 132.79,91.5 132.79,96.28 131.9,97.16 131.9,99.42 132.34,99.86 132.34,104.35 133.05,105.06 133.05,109.18 v3(133.24,109.37) ; 104.92,74.3 107.01,74.3 107.13,74.18 109.29,74.18 109.42,74.3 111.72,74.3 112.15,74.73 112.47,74.73 112.97,74.24 112.97,74.23 113.46,73.74 114.93,73.74 115.19,73.49 117.45,73.49 118.16,72.78 124.91,72.78 126.28,71.41 129.87,71.41 130.56,72.1 v3(131.11,72.1)
  BOTTOM w0.102: v3(132.05,88.32) 132.05,88.22 132.61,87.66 132.61,83.18 133.3,82.49 133.3,81.01 134.62,79.69 134.62,78.55 134.34,78.28 134.34,75.83 132.23,73.71 132.23,73.21 v3(131.11,72.1) ; v3(133.24,109.37) 133.24,110.04 131.62,111.66 R253.2
N20451145: length 0.6
  TOP w0.076: v2(97.89,69.68) 98.08,69.68 U11.H5
N20451146: length 6.6
  TOP w0.076: 98.23,62.24 98.23,63.38 97.21,64.4 97.21,66.43 97.19,66.45 97.19,66.76 97.21,66.78 97.21,66.95 U11.D7
  TOP w0.102: TP20.1 98.23,61.84 98.23,62.24
N20451156: length 4.9
  TOP w0.076: U11.BA17 91.52,87.51 91.52,90.19 92.66,91.32 TP74.1
N20451171: length 3.3
  TOP w0.076: v3(97.92,76.91) 97.63,76.62 U11.AB7
  BOTTOM w0.102: v3(97.92,76.91) 97.92,76.63 98.02,76.53 98.95,76.53 99.09,76.67 99.7,76.67 R483.1
N20451217: length 17.8
  TOP w0.076: U11.AY21 89.41,86.47 89.11,86.77 89.11,87.02 89.28,87.18 89.28,88.26 89.41,88.4 89.41,89.01 89.58,89.17 89.58,90.75 92.3,93.47 92.76,93.47 92.87,93.58
  TOP w0.102: v3(100.25,96.4) 95.69,96.4 92.87,93.58
N20451220: length 8.5
  TOP w0.076: 76.88,62.24 76.88,65.85 76.81,65.92 76.81,67.02 77.31,67.51 U11.E42
  TOP w0.102: 76.88,62.24 76.88,61.54 76.37,61.03 R108.1
N20451227: length 1.5
  BOTTOM w0.102: R408.2 Q30.D
N20452140: length 1.7
  TOP w0.102: R157.2 107.49,61.68 Q11.2
N20452178: length 1.1
  BOTTOM w0.102: R416.2 TP34.1
N20452276: length 7
  TOP w0.076: 106.6,85.09 103.27,85.09 102.96,84.79 101.09,84.79 U11.AU1
  TOP w0.102: 106.6,85.09 107.11,85.09 TP29.1
N20452277: length 7.2
  TOP w0.076: U11.AU2 100.5,84.7 100.64,84.56 100.65,84.55 100.65,84.55 100.9,84.43 101.19,84.43 101.37,84.61 103.03,84.61 103.27,84.84 106.6,84.84
  TOP w0.102: TP28.1 106.91,84.84 106.6,84.84
N20453875: length 1.3
  TOP w0.254: v3(93.31,67.77) U11.E13
  BOTTOM w0.381: v3(93.31,67.77) 92.91,67.77 R506.1
N20453885: length 0.6
  TOP w0.076: v2(93.36,83.22) 93.39,83.22 U11.AP13
N20453922: length 8.9
  TOP w0.076: TP11.1 65.2,60.46 65.2,62.11 65.38,62.29 65.66,62.29 66.89,63.52 66.89,63.57 67.25,63.94 67.25,65.91 67.47,66.13 67.47,66.37 67.18,66.66 U11.D60
N20453925: length 2.1
  TOP w0.203: v2(62.83,69.69) U11.H66
  BOTTOM w0.254: R499.2 62.15,69.01 v2(62.83,69.69)
N20453926: length 9.5
  TOP w0.254: v2(91.49,85.12) U11.AU16
  L3_IN1 w0.203: v2(91.49,85.12) 91.49,85.4 91.97,85.88 93.28,85.88 95.42,88.02 95.6,88.02 95.6,88.02 95.82,88.02 96.52,88.73 97.24,88.73 97.71,89.19 v2(97.71,89.42)
  BOTTOM w0.254: R449.2 97.58,89.16 97.71,89.29 v2(97.71,89.42)
N20453927: length 13.4
  TOP w0.254: v2(91.49,84.48) U11.AT16
  L3_IN1 w0.203: v2(97.07,89.42) 96.67,89.01 96.18,89.01 95.65,89.53 95.21,89.53 93.77,88.09 93.77,87.33 93.47,87.03 92.72,87.03 91.04,85.35 91.04,84.93 v2(91.49,84.48)
  BOTTOM w0.254: v2(97.07,89.42) 96.36,88.7 96.36,88.25 R450.2
N20453928: length 2.1
  TOP w0.203: v3(63.85,69.69) U11.H65
  BOTTOM w0.254: R498.2 63.29,68.85 63.29,68.85 63.29,69.14 v3(63.85,69.69)
N20453936: length 54.3
  TOP w0.102: R3161.1 19.57,41.45 v3(19.39,41.45) ; Q4.G 53.43,57.72 R80.2 54.42,56.73 55.88,56.73 v3(56.16,57.01)
  L4_IN2 w0.102: v3(19.39,41.45) 18.92,41.92 18.92,50.01 18.94,50.04 18.94,50.34 20.02,51.42 v3(23.01,51.42)
  BOTTOM w0.102: v3(23.01,51.42) 23.33,51.74 28.98,51.74 32.95,55.7 54.85,55.7 v3(56.16,57.01)
N20453947: length 5.2
  TOP w0.102: R94.2 62.4,60.69 61.59,59.87 61.37,59.87 Q6.B 60.6,59.1 60.6,58.58 60.33,58.3 59.99,58.3 59.4,57.72 C102.2
N20453993: length 2.5
  TOP w0.076: U11.B59 67.42,65.6 67.42,63.61 v2(67.37,63.56)
N20453994: length 2.9
  TOP w0.076: v2(65.96,64.07) 66.03,64.14 66.08,64.14 66.36,64.43 66.36,64.88 66.19,65.05 66.19,65.42 66.2,65.45 66.22,65.51 66.22,66.12 66.23,66.13 66.23,66.19 U11.C61
N20453995: length 4.3
  TOP w0.076: 98.72,62.24 98.72,63.28 97.74,64.27 97.74,65.67 U11.B7
  TOP w0.102: TP19.1 98.72,62.24
N20453996: length 7.4
  TOP w0.076: U11.C60 67.09,66.16 67.09,64.16 66.8,63.87 66.8,63.72 66.72,63.64 66.72,63.59 65.59,62.46 65.31,62.46 65.03,62.18 65.03,60.93 TP10.1
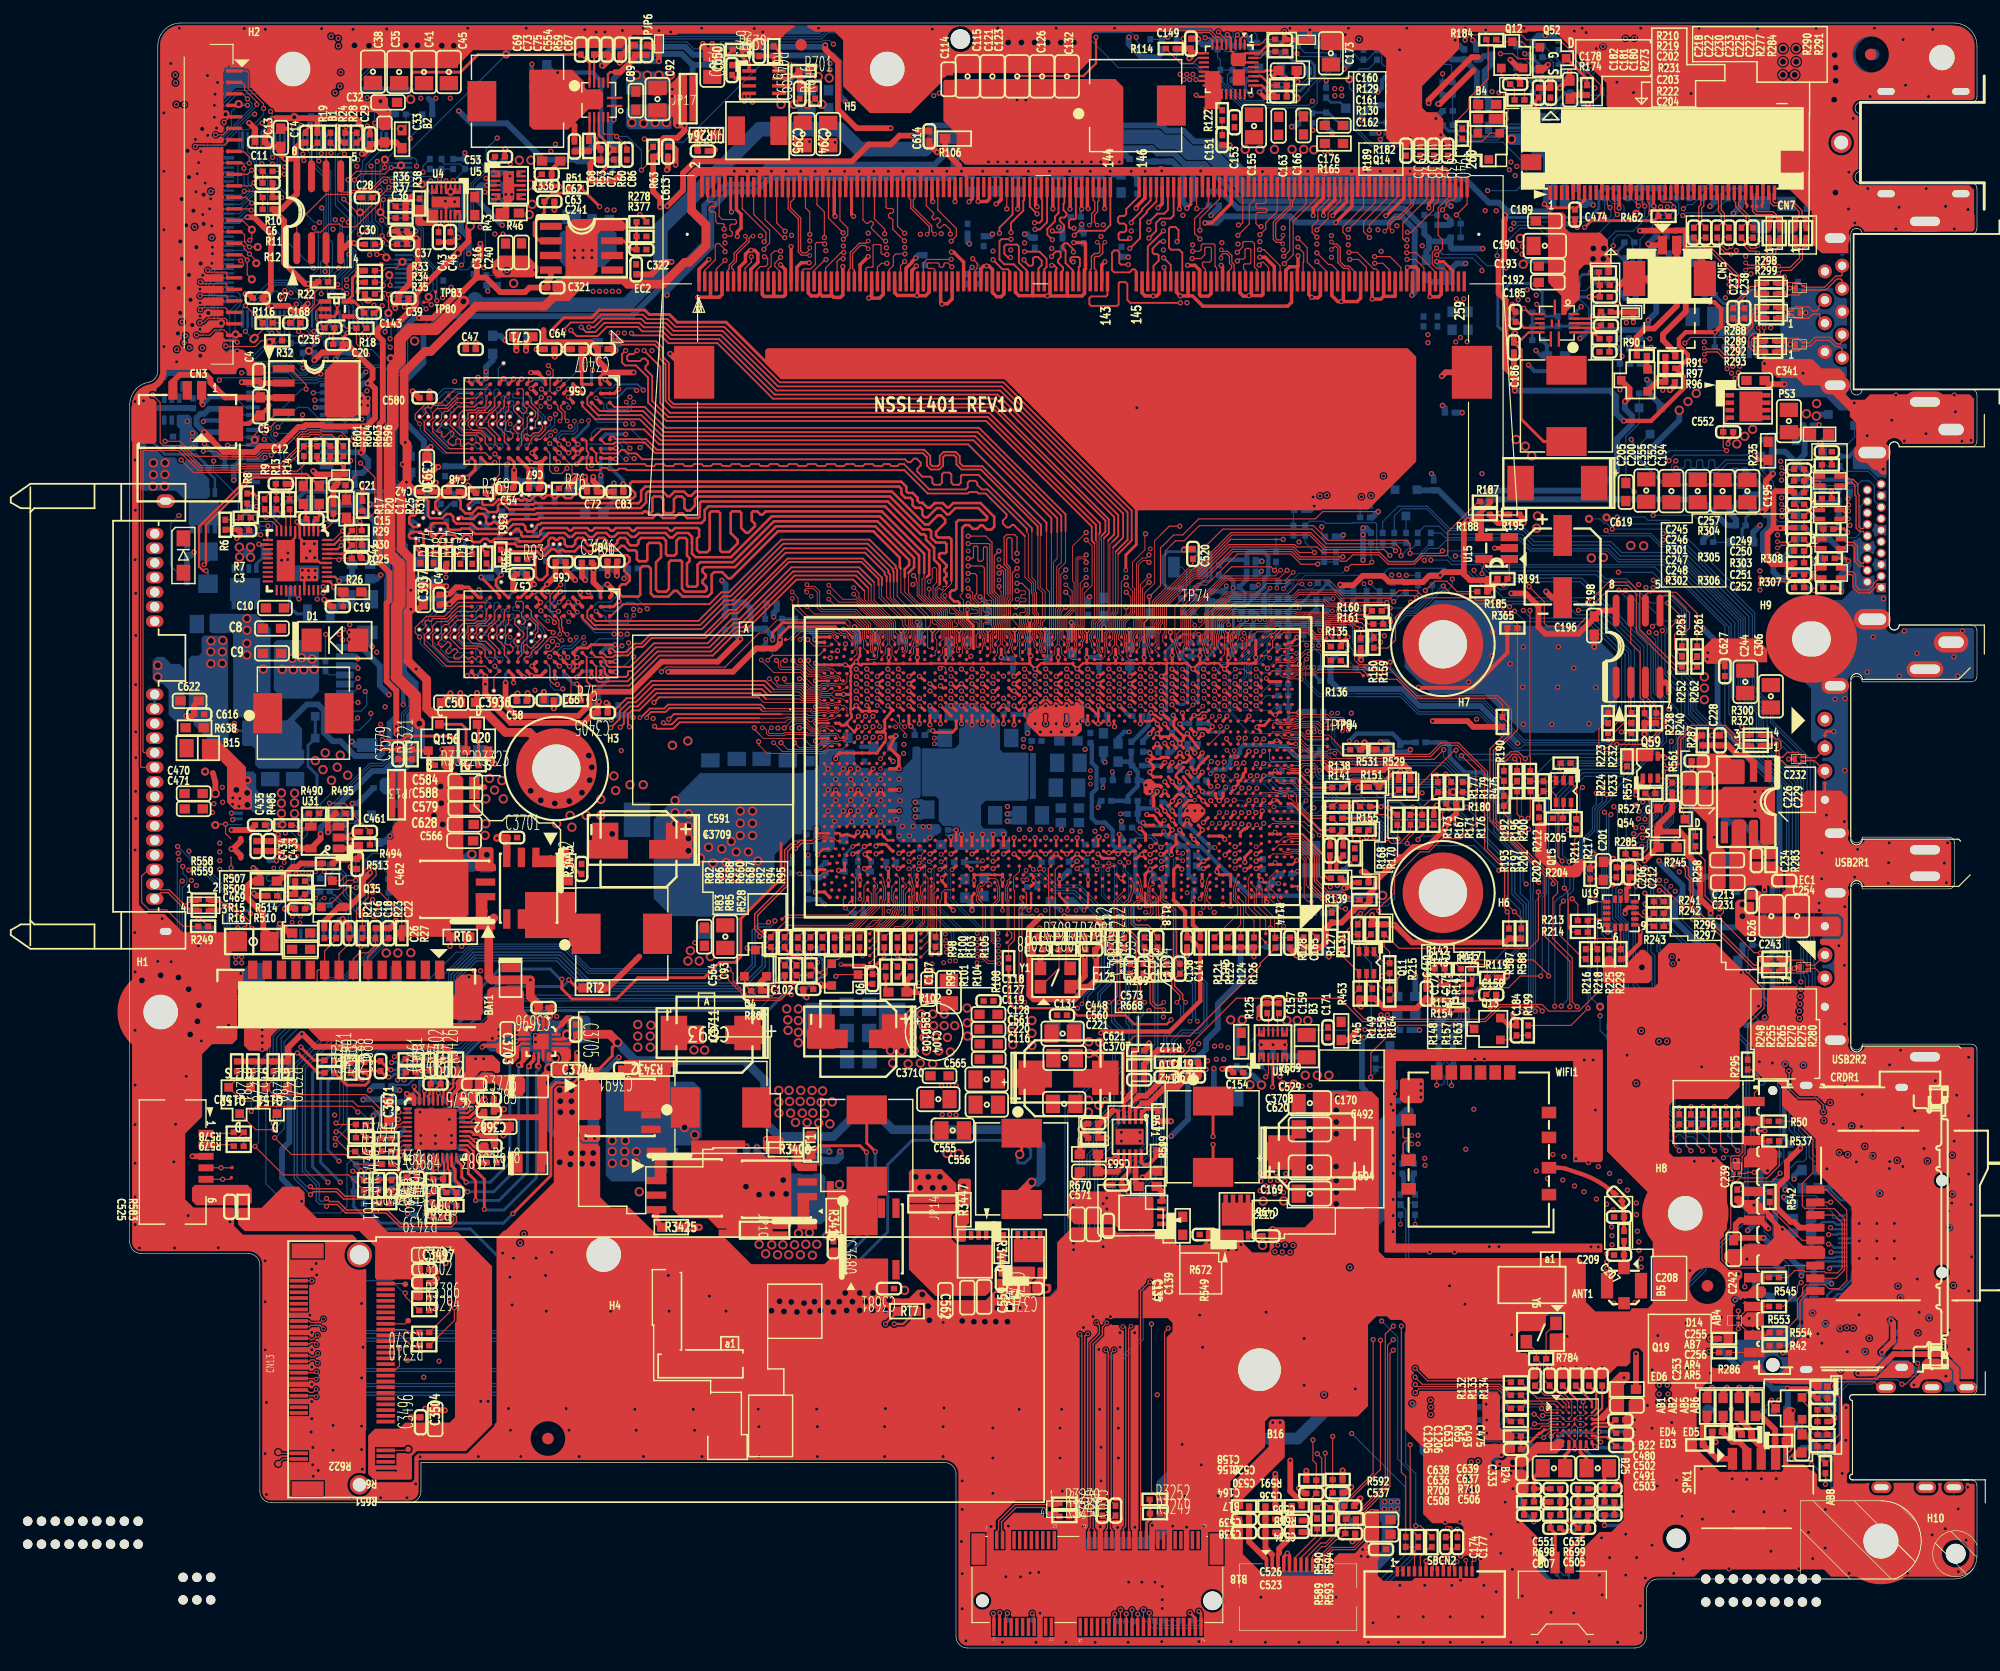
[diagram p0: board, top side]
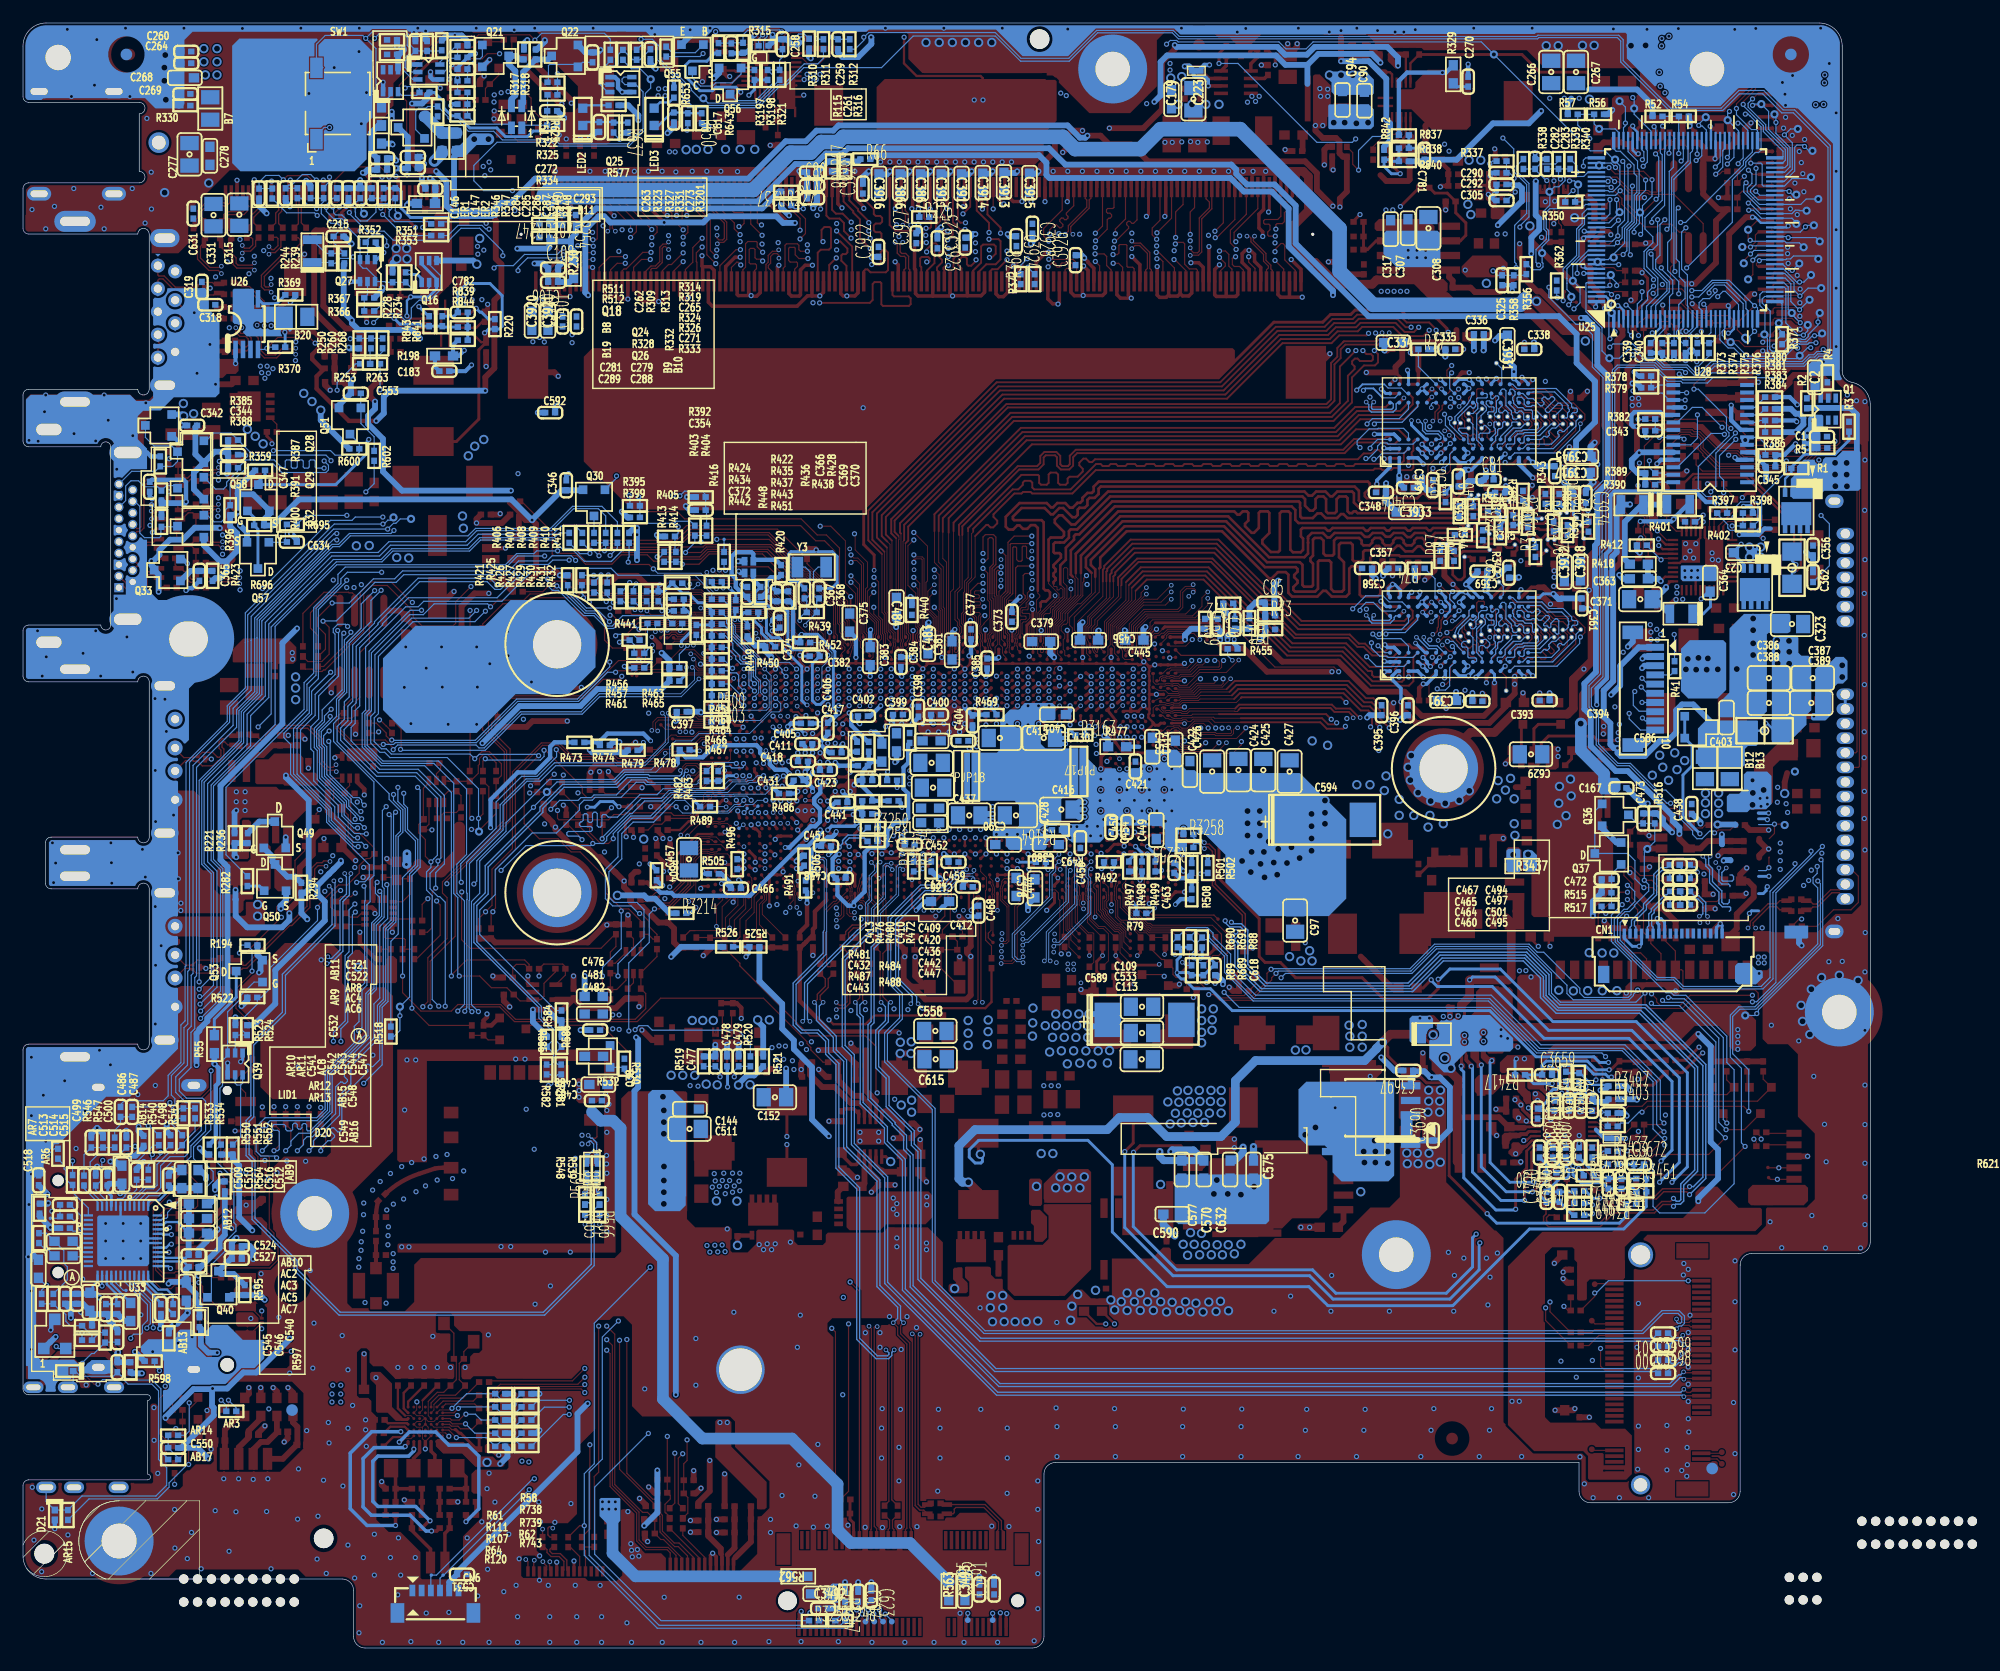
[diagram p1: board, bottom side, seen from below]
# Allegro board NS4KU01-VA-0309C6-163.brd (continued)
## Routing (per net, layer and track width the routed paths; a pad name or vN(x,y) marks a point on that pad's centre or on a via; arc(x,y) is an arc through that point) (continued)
N20454605: length 1.6
  TOP w0.254: U11.K52 v3(71.83,71.13)
  BOTTOM w0.254: v3(71.83,71.13) R3164.2
N20454815: length 3.7
  TOP w0.254: U11.AK52 71.83,79.97 71.48,79.62 69.95,79.62 v3(69.8,79.77)
  BOTTOM w0.254: v3(69.8,79.77) 69.47,79.77 R3163.1
N20465328: length 6.5
  TOP w0.102: v2(55.44,85.89) 55.87,86.31 59.9,86.31 U11.AY71
  BOTTOM w0.102: v2(55.44,85.89) 55.85,86.29 R455.1
N20465363: length 10.5
  TOP w0.076: U11.C64 64.7,66.07 64.61,65.98 64.61,64.59 62.87,62.85 62.64,62.85 62.47,62.68 57.79,62.68 57.3,62.19
  TOP w0.102: R86.1 57.3,62.19
N20465393: length 5.3
  TOP w0.076: U11.AY3 100.02,86.92 100.72,86.92 100.93,87.13 101.42,87.13 101.84,87.55 103.92,87.55 R135.1
N20465492: length 0.5
  TOP w0.076: v3(60.88,86.1) 60.84,86.14 U11.AW71
N20465512: length 0.6
  TOP w0.076: v3(61.52,86.72) 61.42,86.62 U11.AW70
N20465520: length 4.6
  TOP w0.102: TP21.1 103.9,87.74 102.88,87.74 102.29,88.33 100.32,88.33 U11.BB3
N20465522: length 7.3
  TOP w0.102: U11.AY4 99.32,86.99 99.32,87.56 99.59,87.82 99.59,88.03 100.08,88.52 102.45,88.52 103.04,87.93 103.66,87.93 103.87,88.13 104.13,88.13 104.42,87.84 TP24.1
N20465536: length 4.1
  TOP w0.076: U11.BA68 61.66,87.32 61.14,87.84 61.14,88.03 60.96,88.21 58.78,88.21 v2(58.26,87.69)
N20465538: length 2.4
  TOP w0.076: U11.BA70 61,87.27 60.85,87.12 59.49,87.12 v3(58.92,87.69)
N20465582: length 7.5
  TOP w0.102: U11.BB5 98.83,87.9 99.12,88.2 99.39,88.2 99.91,88.71 102.53,88.71 103.12,88.12 103.58,88.12 103.8,88.34 104.19,88.34 104.4,88.13 104.83,88.13 TP27.1
N20465590: length 0.6
  TOP w0.076: U11.AT5 97.99,84.49 v2(97.89,84.49)
N20465592: length 0.6
  TOP w0.076: U11.AU5 98.01,85.12 v2(97.89,85.12)
N20465606: length 5.8
  TOP w0.076: TP5.1 57.26,87.69 58.11,88.54 61.1,88.54 61.4,88.24 61.6,88.24 61.79,88.06 61.99,88.06 U11.BB68
N20465608: length 4.4
  TOP w0.076: U11.BB69 61.31,88.08 61.31,88.1 61.03,88.37 58.31,88.37 57.63,87.69 TP6.1
N20465622: length 0.6
  TOP w0.076: U11.AK13 94.08,80.95 v2(94.08,81.01)
N20465624: length 0.6
  TOP w0.076: U11.AK12 94.71,80.93 v2(94.71,81.03)
N20465636: length 0.6
  TOP w0.076: U11.E8 96.28,68 v2(96.06,67.78)
N20465638: length 2
  TOP w0.254: U11.G65 64.12,69.23 v3(63.9,69.02) 64.34,68.58 U11.F65
  BOTTOM w0.254: v3(63.9,69.02) 64.43,68.49 R497.2
N20465664: length 9.8
  TOP w0.102: U11.E68 63.08,66.93 63.08,64.41 62.41,63.73 57.04,63.73 TP4.1
N20465666: length 1.2
  TOP w0.254: v3(66.8,67.77) 66.87,67.81 U11.E60
  BOTTOM w0.381: v3(66.8,67.77) 66.59,67.98 R492.2
N20465674: length 3.7
  TOP w0.102: U11.E70 60.75,67.58 60.55,67.38 60.22,67.38 60,67.17 58.36,67.17 v2(58.21,67.32)
  BOTTOM w0.102: v2(58.21,67.32) 58.13,67.39 R502.2
N20477829: length 2.9
  TOP w0.102: R8.2 10.2,98.86 R7.1 9.44,98.1 R6.1
N20477836: length 4.2
  TOP w0.102: C3.1 10.38,98.18 R7.2 10.87,97.95 12.39,97.95 12.77,97.57 U1.10
N20477991: length 5.6
  TOP w0.508: U31.1 19.04,69.52 19.36,69.85 R494.1 20.01,68.84 C462.1 18.96,68.6 18.92,68.56 18,68.56 R513.1
N20478004: length 4.7
  TOP w0.102: U31.3 18.87,71.42 18.97,71.52 18.97,72.35 R495.1 18.31,73 16.89,73 R490.1
N20478029: length 3.1
  TOP w0.102: R490.2 15.74,72.42 U31.4 15.62,71.3 14.6,71.3 14.34,71.56 R485.2
N20478055: length 4.6
  TOP w0.508: R514.1 12.95,66.68 13.71,67.45 13.71,67.45 14.2,67.93 14.56,67.93 14.85,68.22 R513.2
N20478465: length 4.4
  TOP w0.203: v3(17.75,92.26) 17.75,92.34 17.34,92.75 U1.31
  BOTTOM w0.508: v3(17.75,92.26) 17.75,92.18 18.74,91.19 ; C371.2 18.74,91.19 ; 18.74,91.19 18.69,91.19 D18.A
N20478537: length 1.7
  TOP w0.102: R9.1 11.73,99.99 12.69,100.95 C12.1
N20478593: length 8.2
  BOTTOM w0.508: D16.C 17.7,99.42 D17.C 19.81,99.45 21.33,97.92 21.33,94.67 R418.1
N20478599: length 3.6
  TOP w0.102: R25.2 18.49,98.64 C17.2 17.7,97.95 16.86,97.12 U1.1
N20478786: length 1.3
  TOP w0.102: C19.1 18.56,90.61 R26.1
N20490831: length 3.3
  TOP w0.102: R174.1 120.35,135.61 C178.1 119.2,136.76 Q12.G
N20491024: length 13.7
  TOP w0.102: R184.1 118.06,139.7 118.06,136.44 116.38,134.77 116.38,133.86 115.26,132.73 115.26,131.78 R189.2 116.03,131.01 117.53,131.01 118.24,131.72 Q14.G
N20491118: length 4.1
  TOP w0.102: Q52.G 121.49,139.19 121.01,139.67 Q12.D 118.95,139.67 R184.2
N20491230: length 31.3
  BOTTOM w0.102: Q25.6 108.31,136.6 108.48,136.43 108.48,136.2 108.23,135.94 Q25.5 107.29,135.94 106.65,135.31 106.65,132.12 107.97,130.8 113.95,130.8 114.29,131.14 118.89,131.14 119.63,131.88 121.84,131.88 122.61,132.65 ; 122.75,132.8 122.74,132.8 122.61,132.66 122.61,132.65 ; 122.75,132.8 122.61,132.65 ; 122.75,132.8 123.39,132.8 123.6,133.01 123.6,133.14 R332.2 125.37,134.04 125.52,133.89 126.16,133.89 126.41,133.64 126.41,132.02 Q26.G
N20491272: length 3.7
  BOTTOM w0.102: R323.2 109.5,138 110.45,137.05 110.45,136.01 109.74,135.29 Q25.3
N20495877: length 1.5
  TOP w0.102: Q11.5 107.49,57.84 R158.2
N20517388: length 11.5
  TOP w0.508: R90.2 130.98,113.23 130.96,113.25 130.96,113.97 131.72,114.74 132.48,114.74 134.44,116.7 CN5.2
N20520101: length 6.7
  TOP w0.254: R126.1 v3(97.71,60.1)
  TOP w0.381: R121.1 R123.1 R124.1 R126.1
  BOTTOM w0.254: v3(97.71,60.1) 97.41,60.41 R525.1 R526.1
N20520130: length 10.6
  TOP w0.076: 106.62,77.6 105.41,77.6 104.86,78.15 104.26,78.15 104.09,77.97 102.55,77.97 101.5,79.01 101.34,79.01 101.3,78.97 100.81,78.97 100.53,79.1 100.23,79.1 99.93,79.39 U11.AG3
  TOP w0.102: R529.1 108.69,77.61 106.63,77.61 106.62,77.6
N20520132: length 7.9
  TOP w0.076: U11.AG4 99.32,79.66 100.46,79.66 100.54,79.63 100.56,79.61 100.57,79.61 100.79,79.61 100.81,79.62 100.92,79.67 101.84,79.67 102.25,79.26 103.66,79.26 103.79,79.38 104.21,79.38 105.48,78.11 R531.1
N20520144: length 5.5
  TOP w0.076: U11.D56 69.1,67.23 69.38,66.94 69.38,62.74 TP12.1
N20520146: length 7.7
  TOP w0.076: TP9.1 64.87,61.4 64.87,62.25 65.24,62.62 65.52,62.62 66.55,63.66 66.55,63.71 66.63,63.79 66.63,63.94 66.9,64.21 66.9,66.95 U11.D61
N20520298: length 7.6
  TOP w0.076: 102.41,69.32 101.61,70.11 U11.J1
  TOP w0.102: TP23.1 105.07,65.54 104.09,65.54 102.96,66.67 102.96,68.76 102.41,69.32
N20520302: length 9
  TOP w0.076: U11.J2 100.5,70.11 100.64,70.25 100.65,70.26 100.65,70.26 100.9,70.38 101.63,70.38 102.41,69.6
  TOP w0.102: TP26.1 105.55,65.69 105.38,65.69 105.32,65.75 104.17,65.75 103.16,66.75 103.16,68.85 102.41,69.6
N20520326: length 4.7
  TOP w0.076: 97.71,62.24 97.71,63.24 97,63.95 97,65.28 U11.B9
  TOP w0.102: 97.71,62.24 R126.2
N20520328: length 6.5
  TOP w0.076: U11.D9 96.14,66.9 96.06,66.63 96.06,66.52 95.98,66.24 95.94,66.08 95.92,66.04 95.92,65.79 95.96,65.7 95.96,65.51 95.92,65.41 95.92,65.05 96.29,64.68 96.29,63.79 94.74,62.24
  TOP w0.102: R121.2 94.74,62.24
N20520330: length 5.5
  TOP w0.076: 95.88,62.24 96.54,62.9 96.54,64.66 96.09,65.12 96.09,65.38 96.15,65.5 96.15,65.65 96.09,65.84 96.09,66.01 96.17,66.26 U11.C9
  TOP w0.102: R123.2 95.88,62.24
N20520332: length 3.8
  TOP w0.076: U11.A9 96.8,64.83 96.8,62.53 96.56,62.3 96.56,62.24
  TOP w0.102: R124.2 96.56,62.24
N20666125: length 4.4
  TOP w0.102: R10.2 12.85,128.4 13.11,128.15 v3(13.43,128.15)
  BOTTOM w0.102: U25.72 12.65,130.38 12.82,130.21 12.82,128.76 v3(13.43,128.15)
N20760284: length 1.5
  TOP w0.102: C46.2 27.88,123.15 27.88,123.93 27.88,123.94 U4.12
N20760306: length 1.6
  TOP w0.102: C43.2 26.84,123.66 26.87,123.68 26.87,123.71 27.08,123.92 U4.10
N20760742: length 3.9
  TOP w0.102: v3(98.72,49.67) 98.96,49.9 U14.3
  BOTTOM w0.102: R520.2 C479.1 98.72,50.2 v3(98.72,49.67)
N20760798: length 1.7
  TOP w0.102: U14.12 98.96,55.09 C157.2
N20760802: length 1.7
  TOP w0.102: U14.10 99.76,55.09 C159.2
N20761063: length 8.6
  TOP w0.102: U5.5 31.34,126.79 31.16,126.6 v3(30.86,126.6)
  L4_IN2 w0.102: v3(30.86,126.6) 30.55,126.91 26.03,126.91 25.85,126.73 v3(25.83,126.73)
  BOTTOM w0.102: v3(30.86,126.6) 31.59,125.86 C305.1 ; v3(25.83,126.73) 25.85,126.7 25.91,126.7 26.51,126.1 R350.2
N20761065: length 2.9
  TOP w0.102: U5.3 31.04,127.59 30.96,127.67 v3(30.96,127.8)
  BOTTOM w0.102: v3(30.96,127.8) 30.96,127.87 31.36,128.28 C290.1 R337.2
N20761089: length 1.9
  TOP w0.102: C63.2 35.1,127.13 34.75,126.79 U5.10
N20761094: length 2
  TOP w0.102: C62.2 35.73,128.15 35.17,127.59 U5.12
N20806808: length 36.8
  TOP w0.254: v3(147.87,100.54) 147.87,100.01 R305.1 ; R307.1 148.38,92.21 v3(148.76,91.84) ; R306.1 148.08,97.32 148.99,97.32 v3(149.3,97.01) ; v3(149.37,94.53) 149.15,94.75 R308.1 ; R304.1 147.92,103.31 v3(147.82,103.41)
  TOP w0.381: R302.1 144.04,97.42 144,97.38
  TOP w0.508: 144,97.38 v3(143.43,97.38) 142.85,97.38 ; R301.1 144.52,100.59 143.01,100.59 142.85,100.44 142.85,97.38 ; 142.85,97.38 142.34,96.86 142.34,94.64 142.74,94.24 144.52,94.24 R303.1
  L4_IN2 w0.254: v3(147.82,103.41) 147.82,103.39 147.87,103.34 v3(147.87,100.54) 147.87,98.46 149.3,97.04 v3(149.3,97.01) 149.27,96.99 149.27,94.63 v3(149.37,94.53)
  BOTTOM w0.508: v3(148.76,91.84) 148.76,93.35 Q33.D 149.14,93.91 149.37,94.14 v3(149.37,94.53) 149.21,94.53 148.69,95.05 148.69,95.46 147.78,96.37 146.66,96.37 145.62,97.41 143.47,97.41 v3(143.43,97.38)
N20806890: length 3.2
  BOTTOM w0.508: R423.1 C365.2 145.98,93.66 Q33.G
N21082318: length 2.1
  TOP w0.076: v2(94.79,80.14) 94.74,80.1 94.74,79.51 93.82,78.59 U11.AF13
N21109689: length 0.5
  TOP w0.076: v3(62.2,87.31) 62.15,87.26 U11.AY68
N22024249: length 2.6
  TOP w0.102: R199.2 C184.2 120.12,52.88 Q13.B
N22024263: length 14.5
  TOP w0.102: v3(107.84,49.61) 107.87,49.64 107.87,51.74 110.28,54.15 116.51,54.15 Q13.C
  BOTTOM w0.102: Q38.G 108.39,50.49 R530.2 108.28,50.05 v3(107.84,49.61)
N22305840: length 1.7
  TOP w0.102: Q15.2 124.61,76.02 124.25,76.38 124.25,76.84 R205.2
N22305920: length 1.4
  TOP w0.102: R204.2 124.56,72.56 124.61,72.61 Q15.5
N22401821: length 1
  TOP w0.381: C162.2 R130.1
N22401893: length 1.3
  TOP w0.102: R122.2 C151.1
N22401921: length 6.9
  TOP w0.102: U13.3 96.1,140.1 v3(96.26,140.27)
  BOTTOM w0.102: R315.1 96.62,139.91 v3(96.26,140.27) 96.66,140.67 97.56,140.67 97.97,140.26 R316.2 98.93,139.58 C261.2 99.01,139.55 R115.2
N22402176: length 2.1
  TOP w0.102: R129.2 98.8,138.82 98.25,138.27 U13.31
N22402238: length 2.6
  TOP w0.102: v3(93.47,140.01) 93.82,140.01 94.1,139.74 U13.8
  BOTTOM w0.102: v3(93.47,140.01) 93.14,140.34 92.64,140.34 R310.1
N22402256: length 4
  TOP w0.102: U13.10 92.84,138.27 92.35,137.78 91.33,137.78 R114.1
N22553007: length 6.6
  TOP w0.076: TP79.1 104.72,79.89 103.7,79.89 103.23,80.37 101.38,80.37 101.35,80.34 101.28,80.34 101.23,80.29 100.86,80.29 100.75,80.33 100.63,80.33 100.41,80.27 100.27,80.27 100.11,80.33 99.78,80.33 99.65,80.45 99.46,80.45 99.33,80.33 99.33,80.1 U11.AH3
N22553010: length 5.2
  TOP w0.076: U11.AJ3 99.93,80.49 100.14,80.49 100.3,80.43 100.39,80.43 100.61,80.5 100.78,80.5 100.9,80.45 101.16,80.45 101.29,80.58 103.27,80.58 103.7,80.15 104.34,80.15 TP84.1
N23119620: length 4.1
  TOP w0.508: D4.1 132.73,110.09 R96.1 133.46,110.13 R97.2 R91.2
N25111157: length 2.9
  BOTTOM w0.254: R369.2 138.5,116.89 139.7,116.89 U26.5
N25464769: length 1.5
  TOP w0.508: Q47.4 89.73,38.9 89.73,39.66 R672.1
N25488348: length 1
  TOP w0.076: v2(97.94,71.58) 97.65,71.25 U11.L7
  BOTTOM w0.076: TP73.1 v2(97.94,71.58)
N25568278: length 4.6
  TOP w0.102: U13.7 94.5,139.8 93.83,140.47 91.94,140.47 91.56,140.09 v3(91.56,139.94)
  BOTTOM w0.102: R311.2 91.46,139.89 91.56,139.99 v3(91.56,139.94)
N25568374: length 2.8
  TOP w0.102: U13.1 96.9,139.43 98.27,139.43 98.72,139.88 C160.1
N25663816: length 1.8
  BOTTOM w0.102: R41.1 17.34,84.62 CN8.4
N25665640: length 4.1
  BOTTOM w0.203: LED2.C 111.59,132.69 C517.1 109.26,132.69 R625.2 R637.1
N25665924: length 4.6
  BOTTOM w0.203: LED3.C 105.3,132.39 104.17,133.51 C617.1 102.83,133.51 R643.2 R650.1
N25687178: length 8.5
  TOP w0.076: R660.1 59.51,62.16 59.74,62.16 59.93,62.35 62.61,62.35 62.77,62.52 63.01,62.52 64.94,64.45 64.94,65.6 U11.B63
N25687185: length 7
  TOP w0.076: R687.1 60.58,62.19 62.68,62.19 62.84,62.35 63.13,62.35 65.18,64.41 65.18,65.19 65.18,65.2 U11.A63
N25687195: length 10.4
  TOP w0.076: U11.D64 64.7,66.66 64.98,66.38 64.98,66.12 64.78,65.91 64.78,64.52 62.94,62.68 62.7,62.68 62.54,62.52 59.18,62.52 59,62.34 58.62,62.34
  TOP w0.102: 58.62,62.34 R688.1
N25839152: length 21.2
  TOP w0.102: CRDR2.8 148.3,32.15 149.02,32.87 149.02,37.32 148.13,38.21 145.59,38.21 145.36,38.43 145.36,40.42 146.28,41.34 146.28,44.2 144.68,45.8 R50.2
N25839155: length 22.3
  TOP w0.102: CRDR2.7 143.86,33.25 143.66,33.05 139.09,33.05 138.38,33.76 138.38,35.36 138.73,35.72 138.73,36.07 139.14,36.48 139.14,40.09 139.93,40.87 142.29,40.87 143.36,41.94 R537.2
N25839158: length 5.6
  TOP w0.102: CRDR2.5 145.35,35.45 142.54,38.26 R542.2
N25839161: length 12.5
  TOP w0.102: R545.2 144.09,32.21 144.7,32.82 145.51,32.82 145.62,32.72 147.29,32.72 147.4,32.61 148.41,32.61 148.82,33.02 148.82,36.96 148.13,37.65 CRDR2.3
N25839164: length 13.8
  TOP w0.102: v3(145.26,31.78) 144.93,31.45 144.93,30.94 143.69,29.7 R553.2 ; CRDR2.2 146.5,38.76 v3(147.83,38.76)
  L3_IN1 w0.102: v3(147.83,38.76) 146,38.76 144.9,37.67 144.9,32.14 v3(145.26,31.78)
N25839167: length 18.9
  TOP w0.102: R554.2 143.69,27.44 144.93,28.68 144.93,30.31 145.39,30.76 145.39,31.32 145.64,31.58 147.34,31.58 147.67,31.25 148.54,31.25 149.22,31.93 149.22,38.07 147.44,39.85 CRDR2.1
N25839177: length 6.7
  TOP w0.102: R42.2 144.04,26.29 145.16,27.41 145.16,30.2 146,31.05 CRDR2.9
N26482662: length 2.8
  BOTTOM w0.508: R236.1 140,71.86 Q49.D
N26483213: length 4.8
  BOTTOM w0.508: R294.2 136.88,67.07 137.56,67.07 Q50.D 138.85,68.36 138.85,68.81 Q49.G
N26483218: length 1.6
  BOTTOM w0.254: Q50.G 139.99,66.25 R282.2
N26484019: length 6.4
  BOTTOM w0.254: R55.1 143.91,54.68 142.16,56.43 142.01,56.58 Q53.D
N26484324: length 9.4
  TOP w0.102: 133.98,75.32 R561.2 ; 133.98,75.32 133.67,75.64 Q59.3 ; 133.98,75.32 133.98,75.12 133.55,74.69 133.55,73.67 132.9,73.02 Q54.G 132.28,72.43 132.28,70.62 131.9,70.24 131.9,69.48 131.47,69.05 R285.2
N26516302: length 11.2
  TOP w0.508: CRDR2.4 145.14,36.55 144.63,37.06 144.36,37.06 143.15,38.26 143.15,40.06 144.02,40.93 144.02,42.3 v3(145.18,43.46)
  BOTTOM w0.508: v3(145.18,43.46) 144.63,42.91 R550.2
N26523035: length 7.3
  BOTTOM w0.102: R3197.1 97.43,137.21 97.61,137.39 Q56.G 98.14,136.87 98.91,136.1 100.34,136.1 100.62,135.82 101.65,135.82 102.36,136.53 Q55.C
N26526896: length 3.2
  BOTTOM w0.102: Q57.G 137.63,96.15 C634.2 137.74,96.3 137.74,97.56 R695.1
N26526935: length 5.4
  BOTTOM w0.254: Q57.D 140.12,97.29 R696.1 140.45,98.29 Q58.G
N26564205: length 5.3
  TOP w0.102: Q17.1 16.58,117.09 15.15,115.65 14.38,115.65 C168.1 R116.1
N26603686: length 2.5
  BOTTOM w0.254: R837.2 R838.1 38.9,130.42 C781.1
N26604940: length 2.4
  BOTTOM w0.254: C782.1 R839.1 R844.2
N26701011: length 3.1
  TOP w0.254: Q52.D 124.86,138.24 126.65,136.45 R273.1
N27282749: length 2
  TOP w0.305: U12.1 87.91,46.45 88.34,46.87 89.15,46.87 R599.2
N27388676: length 1.5
  TOP w0.102: Q59.2 132.15,74.99 132.58,74.56 R527.2
N27538533: length 4.7
  TOP w0.305: R698.2 C551.2 ; C551.2 122.04,14.88 B24.2 ; C551.2 C638.1
N27538535: length 4.5
  TOP w0.305: B25.2 128.17,15.24 C635.1 ; C635.1 C639.1 ; C635.1 R699.2
N27538543: length 2.3
  TOP w0.305: C638.2 C636.2 R700.1
N27538545: length 2.3
  TOP w0.305: R710.1 C637.1 C639.2
N27538569: length 4.3
  TOP w0.305: R700.2 C508.2 123.47,10.37 123.87,9.97 CN33.1
N27538571: length 4.8
  TOP w0.305: R710.2 C506.2 126.74,10.22 125.12,8.6 CN33.2
N27538743: length 1.1
  TOP w0.305: R699.1 C505.2
N27538964: length 2.4
  TOP w0.203: U1634.A7 127.07,21.42 R65.1
N27539034: length 3.7
  TOP w0.076: U1634.C6 126.83,20.2 127.33,20.2
  TOP w0.203: C475.1 127.96,20.84 127.33,20.2
N27539138: length 2.5
  TOP w0.203: U1634.E7 127.36,19.24 128.62,19.24 C491.2
N27539315: length 1.1
  TOP w0.305: R698.1 C507.2
N27647798: length 2.5
  TOP w0.127: R3429.2 22.77,39.8 C3689.2 22.55,39.61 R3434.2
N27647889: length 2.7
  TOP w0.203: U109.30 29.04,46.91 29.82,47.69
  TOP w0.635: C3675.1 30.36,48.55 29.82,48.01 29.82,47.69
N27647893: length 3.3
  TOP w0.203: U109.40 24.78,47.94 24.53,48.19 v3(24.09,48.19)
  BOTTOM w0.508: R3403.1 22.99,47.49 23.93,47.49 24.09,47.65 ; C3660.2 24.09,47.65 ; 24.09,47.65 v3(24.09,48.19)
N27647940: length 42.1
  TOP w0.254: v3(38.16,58.1) 38.87,57.39 RT2.1
  L4_IN2 w0.254: v3(18.18,42.34) 18.18,41.77 20.85,39.1 v3(23.52,39.1)
  BOTTOM w0.254: R3445.1 24.72,39.74 24.09,39.1 v3(23.52,39.1) ; v3(18.18,42.34) 17.23,43.29 17.23,49.26 20.98,53.01 28.34,53.01 32.85,57.52 37.63,57.52 38.19,58.08 v3(38.16,58.1)
N27648096: length 3.8
  TOP w0.203: R3440.2 26.37,39.7 C3694.2 25.8,39.13 25.8,38.04 R3439.2
N27648286: length 2.4
  TOP w0.203: R3401.2 25.99,51.21 C3661.2 27.19,51.13 R3402.2
N27648351: length 1.6
  TOP w0.508: R3448.2 C3714.1
N27648358: length 86
  TOP w0.254: v3(64.03,43.1) 63.46,43.68 59.93,43.68 RT1.1 ; v3(14.88,52.25) 16.02,51.1 R3421.1
  L4_IN2 w0.254: v3(34.25,35.99) 34.18,36.06 16.15,36.06 14.18,38.02 14.18,41.45 15.33,42.6 15.33,51.8 v3(14.88,52.25)
  BOTTOM w0.254: v3(64.03,43.1) 64.05,43.08 64.05,36.65 60.28,32.88 48.47,32.88 46.44,30.85 36.85,30.85 34.57,33.13 34.57,35.67 v3(34.25,35.99)
N27648790: length 1.4
  TOP w0.508: C3680.1 R3416.2
N27649020: length 1.5
  TOP w0.508: C3691.1 43.61,50.37 R3432.2
N27719031: length 1.4
  TOP w0.102: Q151.G 13.75,48.77 R3279.2
N27719037: length 1.5
  TOP w0.102: R3278.2 10.7,48.96 Q152.G
N27740374: length 21.4
  TOP w0.254: U11.U11 95.02,74.03 94.9,73.9 94.9,73.88 v3(94.69,73.67) 94.37,73.98 U11.U12
  L4_IN2 w0.254: v2(102.05,64.4) 101.14,65.31 93.9,65.31 92.66,66.56 92.66,68.97 93.04,69.35 93.04,70.62 92.66,71 92.66,71.89 93.04,72.27 93.42,72.27 94.69,73.54 v3(94.69,73.67)
  BOTTOM w0.254: v2(102.05,64.4) 102.56,63.89 R3214.2
N28022357: length 6.8
  TOP w0.102: CN14.54 v3(88.1,3.31)
  BOTTOM w0.102: R3253.2 R3248.1 89.1,3.23 R3247.2 C597.2 87.96,3.46 v3(88.1,3.31)
N28022719: length 2.6
  TOP w0.102: v3(87.1,3.31) CN14.50
  BOTTOM w0.102: TP188.1 87.1,2.52 v3(87.1,3.31)
N28022721: length 1.8
  TOP w0.102: CN14.48 v3(86.6,2.97)
  BOTTOM w0.102: v3(86.6,2.97) 86.6,2.34 TP187.1
N28022723: length 2.6
  TOP w0.102: CN14.46 v3(86.1,3.31)
  BOTTOM w0.102: TP186.1 86.1,2.6 v3(86.1,3.31)
N28022725: length 2
  TOP w0.102: CN14.44 v3(85.6,2.95)
  BOTTOM w0.102: TP185.1 85.04,2.38 v3(85.6,2.95)
N28022786: length 1.8
  TOP w0.102: CN14.16 78.6,2.85 v3(78.43,3.02)
  BOTTOM w0.102: TP184.1 v3(78.43,3.02)
N28022788: length 1.8
  TOP w0.102: v3(76.27,3.01) 76.1,2.84 CN14.6
  BOTTOM w0.102: TP183.1 v3(76.27,3.01)
N28022853: length 2.4
  TOP w0.114: C695.1 85.62,11.52 85.23,11.12 85.23,10.42 85.35,10.29 CN14.43
N28022855: length 2.4
  TOP w0.114: CN14.41 84.85,10.29 84.97,10.42 84.97,11.12 84.58,11.52 C696.1
N28025825: length 8.2
  TOP w0.076: 90.95,62.24 90.95,62.25 90.93,62.27 90.93,62.34 90.91,62.35 90.91,64.12 90.1,64.93 89.91,64.93 89.79,65.05 89.79,65.8 89.78,66.31 89.7,66.57 89.6,66.73 U11.D20
  TOP w0.114: C694.2 90.95,59.8 90.95,62.24
N28025828: length 8.2
  TOP w0.076: 90.7,62.24 90.7,64.03 90.01,64.71 89.82,64.71 89.58,64.96 89.58,65.8 U11.C20
  TOP w0.114: C693.2 90.37,59.24 90.58,59.24 90.7,59.36 90.7,62.24
N28033617: length 3.3
  TOP w0.114: v2(16.3,27.19) 15.92,26.81 15.74,26.81 15.62,26.93 CN13.49
  BOTTOM w0.114: C3501.1 17.17,26.98 16.51,26.98 v2(16.3,27.19)
N28033619: length 3.3
  TOP w0.114: CN13.47 15.62,26.43 15.74,26.56 16.04,26.56 v2(16.21,26.39)
  BOTTOM w0.114: v2(16.21,26.39) 16.54,26.72 17.09,26.72 C3500.1
N28033621: length 3.6
  TOP w0.114: CN13.41 15.62,24.93 15.74,25.06 16.03,25.06 v2(16.33,24.76)
  BOTTOM w0.114: C3498.2 17.57,24.09 17.17,24.5 16.96,24.5 16.64,24.82 16.38,24.82 v2(16.33,24.76)
N28033623: length 3.6
  TOP w0.114: CN13.43 15.62,25.43 15.74,25.31 16.03,25.31 v2(16.33,25.61)
  BOTTOM w0.114: C3499.2 17.3,24.75 17.07,24.75 16.33,25.49 v2(16.33,25.61)
N28034069: length 3.3
  TOP w0.102: R3310.2 24.46,26.3 23.57,27.18 CN13.50
N28034083: length 2.1
  TOP w0.102: CN13.54 23.93,28.18 TP209.1
N28034085: length 3
  TOP w0.102: R3370.2 24.2,27.44 23.96,27.68 CN13.52
N28034570: length 4.6
  TOP w0.076: U11.A25 86.32,65.39 86.27,65.39 85.8,64.92 85.8,62.29 85.8,62.24
  TOP w0.114: R3232.2 85.86,61.78 85.8,61.85 85.8,62.24
N28034572: length 4.6
  TOP w0.076: 85.54,62.24 85.54,64.97 86.44,65.87 U11.B25
  TOP w0.114: 85.54,62.24 85.54,62.04 R3152.2
N28172519: length 1.2
  TOP w0.254: R3321.1 C3579.1
N28172541: length 3
  TOP w0.254: R3321.2 24.65,78.03 Q156.B 25.96,77.32 R3322.1
N28172556: length 4.4
  TOP w0.254: Q156.C 28.85,80.31 29.23,79.93 Q20.G
N28172573: length 3.6
  TOP w0.254: Q20.D 30.32,80.18 R3323.2
N28287409: length 1.1
  BOTTOM w0.254: C76.1 R69.1
N28330696: length 1.4
  TOP w0.508: R264.2 49.34,130.2 C236.1
N28330751: length 3.1
  TOP w0.305: TP46.1 53.93,138.79 53.73,138.99 R639.2 53.24,138.94 53.24,138.35 53.83,137.76 U32.1
N28330775: length 4.9
  TOP w0.305: U32.7 57.47,136.48 R701.1
  TOP w0.508: R701.1 58.23,137.05 C653.2 R646.2
N28330789: length 2.8
  TOP w0.305: U32.8 55.97,137.6 R645.2 C649.1
N28330811: length 1.6
  TOP w0.305: U32.2 52.64,136.48 C654.1
N28361448: length 1.4
  BOTTOM w0.254: R72.1 55.23,90.69 C77.1
N28363524: length 2.9
  BOTTOM w0.102: R74.1 37.83,92.98 37.83,91.44 U1635.F9
N28388369: length 3.4
  TOP w0.089: 38.44,102.46 38.44,102.78 U1637.F9
  TOP w0.102: 38.44,102.46 38.44,101.96 R76.1
N28390577: length 3.7
  BOTTOM w0.102: R77.1 39.27,111.43 U1638.F9
N28397978: length 2.8
  TOP w0.089: U1636.F9 38.35,84.33 R75.1
N28437134: length 2.2
  TOP w0.102: CN11.95 72.97,119.82 v3(73.21,120.06)
  BOTTOM w0.102: v3(73.21,120.06) 72.62,119.47 R372.2
N28437143: length 3.8
  TOP w0.102: v3(73.26,120.81) 73.64,120.42 73.64,119.95 73.47,119.78 CN11.97
  BOTTOM w0.102: R368.2 73.83,120.23 v3(73.26,120.81)
N28576440: length 1.6
  BOTTOM w0.102: TC27.1 31.9,92.32 31.9,91.58 U1635.N9
N28576458: length 1.9
  TOP w0.102: TC30.1 31.64,84.46 U1636.N9
N28576472: length 2
  TOP w0.089: 32.13,103.06 U1637.N9
  TOP w0.102: TC31.1 32.13,102.03 32.13,103.06
N28576486: length 2.1
  BOTTOM w0.102: U1638.N9 32.03,109.99 32.03,111.26 TC32.1
N68041277: length 17.9
  TOP w0.102: U2.1 13.92,111.26 15.33,109.85 v3(15.33,109.46)
  BOTTOM w0.102: R397.2 12.44,99.27 13.29,100.13 14.26,100.13 14.95,100.81 14.95,102.73 12.28,105.4 12.28,105.67 12.5,105.89 12.5,107.01 14.94,109.46 v3(15.33,109.46)
N133129643: length 3.9
  BOTTOM w0.203: U33.27 153.26,31.63 152.42,30.79 152.42,30.01 C544.1 C543.1
N133129783: length 3.3
  BOTTOM w0.203: U33.34 150.46,31.9 148.76,30.2 148.56,30 C545.2
N133129846: length 2.4
  BOTTOM w0.102: U33.19 155.37,35.21 155.57,35.41 155.57,35.92 155.9,36.25 156.2,36.25 AR8.1
N133130060: length 3.1
  BOTTOM w0.203: C547.1 152.86,31.69 U33.28
N276491031: length 1.6
  TOP w0.254: R3443.2 39.15,67.31 C3702.1
N280337050: length 1.7
  TOP w0.102: TP190.1 23.9,31.68 CN13.68
N280338137: length 2
  TOP w0.102: CN13.7 13.32,16.43 TP200.1
N2803381310: length 2
  TOP w0.102: TP189.1 24.11,17.18 CN13.10
N2803381313: length 1.8
  TOP w0.102: CN13.9 12.99,16.93 TP201.1

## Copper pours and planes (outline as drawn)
3.3V_LCD_S on BOTTOM: 122.52,132.34 123.31,132.34 124.47,133.5 124.95,133.5 125.09,133.64 126,133.64 126.13,133.51 126.13,132.7 124.68,131.25 122.45,131.25 122.32,131.38 122.32,132.14
+0.6V_DDR on TOP: 25,94.71 29.95,94.71 30.46,95.22 34.08,95.22 34.14,95.15 34.14,94.33 32.56,92.74 27.54,92.74 26.9,93.37 25.06,93.37 24.87,93.56 24.87,94.58
+0.6V_DDR on TOP: 114.09,124.93 114.09,125.41 114.19,125.51 114.19,127.77 113.97,127.99 113.51,127.99 112.74,128.76 105.86,128.76 104.97,129.65 104.97,132.85 105.85,133.73 105.85,135.97 105.72,136.1 102.33,136.1 101.14,137.29 98.22,137.29 98.15,137.36 97.24,137.36 97.2,137.4 97.2,137.55 97.23,137.57 98.19,137.57 98.27,137.65 98.27,137.85 98.85,138.44 99.99,138.44 100.12,138.56 100.12,139.07 102.94,139.07 103.32,138.69 108.2,138.69 108.93,137.96 108.93,130.63 109.49,130.08 115.78,130.08 116.07,129.78 116.07,129.01 117.33,127.76 117.33,125 116.16,123.83 115.08,123.83 114.46,124.44 114.46,124.78 114.24,124.78
+0.6V_DDR on BOTTOM: outline of 86 points within 24.3,92.99 40.05,104.18
+1.00V_CPU on TOP: 103.45,52.87 103.22,52.64 101.21,52.64 100.71,53.14 100.68,53.12 100.17,53.12 100.04,53.25 100.04,54.67 100.63,55.25 104.9,55.25 104.9,55.25 105.41,55.25 105.71,54.96 105.71,54.45 105.66,54.4 105.66,53.82 105.56,53.72 103.74,53.72 103.45,53.43
+1.00V_CPU on BOTTOM: 84.09,79.03 83.99,79.13 83.23,79.13 83.19,79.14 83.18,79.18 83.18,79.76 83.53,80.12 83.53,80.19 83.54,80.2 83.59,80.37 83.54,80.54 83.49,80.61 83.44,80.65 83.18,80.91 83.18,81.36 83.05,81.49 82.37,81.49 82.24,81.62 82.24,82.02 82.25,82.06 82.29,82.07 84.4,82.07 84.45,82.02 84.45,80.22 84.63,80.04 85.05,80.04 85.09,80.04 85.13,80.04 85.19,79.99 85.19,79.1 85.11,79.03
+1.00V_CPU on L2_VCC: 83.84,79.18 83.84,80.63 82.95,81.51 82.95,82.04 83.26,82.35 84.81,82.35 86.13,81.03 86.13,79.61 85.7,79.18
+1.00V_CPU on L3_IN1: 97.75,54.2 96.36,55.58 96.23,55.58 95.22,56.6 95.22,63.38 95.83,63.99 95.83,64.75 94.66,65.92 88.31,65.92 87.23,67 87.23,69.67 85.6,71.31 85.13,71.31 83.56,72.88 83.56,80.93 82.72,81.77 82.72,82.18 82.88,82.33 83.91,82.33 86.43,79.81 86.43,79.71 88.21,77.93 88.21,76.05 88.92,75.34 88.92,74.6 89.61,73.92 90.02,73.92 90.68,73.26 99.55,73.26 100.66,72.15 100.66,70.49 102.03,69.12 102.03,56.04 102.76,55.31 102.76,54.38 102.57,54.2
+1.00V_CPU on L4_IN2: 84.63,80.12 84.63,81.97 84.28,82.32 76.78,82.32 76.57,82.1 76.57,80.97 76.78,80.75 82.34,80.75 83.08,80.02 84.53,80.02
+1.00VS_CPU on TOP: 98.67,54.64 98.67,53.12 97.81,53.12 97.4,52.71 95.73,52.71 95.04,53.4 95.04,54.95 95.12,55.02 98.29,55.02
+1.2VS on TOP (solid shape): 86.36,135.72 86.36,129.08 86.26,128.98 72.6,128.98 71.85,129.73 71.85,131.63 71.42,132.06 71.42,132.09 70.71,132.8 70.71,136.23 70.83,136.36 71.62,136.36 71.7,136.43 85.65,136.43
+1.2VS on L4_IN2 (solid shape): outline of 337 points within 38.37,90.01 44.15,103.81
+1.2VS on BOTTOM: outline of 670 points within 24.02,79 93.83,129.42 ; 4 cut-outs
+1.2VS on L4_IN2: 76.87,135.5 78.54,135.5 78.55,135.49 91.05,135.49 92.03,134.51 97.74,134.51 98.78,135.55 98.78,136.09 98.49,136.38 98.49,136.67 98.86,137.04 99.8,137.04 100.6,136.24 100.6,134.61 99.1,133.11 91.35,133.11 90.37,134.09 76.7,134.09 76.5,134.29 76.5,135.12
+1.8VA_FB on TOP (solid shape): 141.51,71.91 141.51,69.99 141.93,69.57 142.84,69.57 143.14,69.27 143.14,68.74 143,68.6 141.03,68.6 140.9,68.73 140.9,69.54 140.71,69.73 140.71,71.81 140.91,72.01 141.41,72.01
+1.8VA_PCH on TOP: 40.98,121.48 43.4,121.48 43.76,121.12 44.25,121.12 44.26,121.11 44.6,121.45 44.6,123.04 44.71,123.15 45,123.15 45.46,123.61 45.46,124.17 45.01,124.62 41.51,124.62 41.3,124.83 41.3,125.91 41.53,126.14 45.16,126.14 46.72,124.59 46.72,122.24 46.19,121.72 46.19,121.05 45.17,120.03 44.37,120.03 44.31,119.97 43.62,119.97 43,120.59 40.94,120.59 40.86,120.66 40.86,121.37
+1.8VA_PCH on BOTTOM: 42.15,126.51 42.44,126.23 42.44,124.14 41.93,123.63 38.22,123.63 38.22,123.63 37.52,123.63 37.03,123.14 37.03,123.1 35.9,121.97 35.9,118.54 35.1,117.74 33.52,117.74 32.92,118.35 32.92,122.86 36.56,126.51
+1.8VA_PCH on L3_IN1: 107.39,53.35 105.23,53.35 104.97,53.1 104.97,51.57 105.36,51.19 105.99,51.19 107.64,52.84 107.64,53.1
+1.8VA_PCH on L3_IN1: 108.28,65 108.28,65.67 108.91,66.3 108.91,66.68 108.19,67.41 108.19,71.1 108.72,71.63 109.36,71.63 110.39,72.65 110.39,73.64 110.08,73.95 109.9,73.95 109.29,74.56 109.29,76.27 109.5,76.48 110.02,76.48 110.18,76.32 110.18,75.29 111.3,74.18 111.3,71.84 109.7,70.24 109.7,68.84 109.93,68.62 109.93,64.53 109.8,64.4 108.88,64.4
+1.35VS_PHASE on TOP: 95.37,133.84 95.37,133.55 95.3,133.48 94.76,133.48 94.53,133.25 94.53,131.63 94.28,131.38 88.89,131.38 88.39,131.88 88.39,136 88.67,136.28 90.88,136.28 91.23,135.92 92.3,135.92 92.65,135.57 93.95,135.57 94,135.61 94,138.65 94.1,138.75 95.4,138.75 95.58,138.56 95.58,135.81 95.37,135.6
+2.5VS on TOP: 55.9,135.37 57.24,135.37 57.74,134.86 61.05,134.86 61.49,134.42 61.49,132.26 61.24,132 57.55,132 57.17,131.62 57.17,130.67 56.98,130.48 55.9,130.48 55.58,130.8 55.58,135.05
+2.5VS on TOP: 115.31,119.73 116.22,119.73 116.31,119.63 116.31,116.67 113.36,113.72 54.88,113.72 53,115.6 44.72,115.6 44.16,116.16 41.1,116.16 40.49,115.56 38.35,115.56 37.14,114.35 32.84,114.35 32.07,113.57 32.07,110.8 31.38,110.11 30.74,110.11 30.62,110.23 30.62,115.09 31.53,116 36.01,116 36.99,116.98 37.35,116.98 37.46,116.86 38.43,116.86 39.75,118.19 48.94,118.19 49.45,117.68 54.14,117.68 55.5,116.32 113.17,116.32 114.49,117.64 115.05,117.64 115.29,117.87 115.29,119.7
+2.5VS on BOTTOM: 114.59,117.65 117.17,117.65 117.54,117.28 117.54,115.74 117.27,115.47 112.33,115.47 112.11,115.69 112.11,116.89 112.26,117.03 113.97,117.03
+2.5VS on BOTTOM: 61.24,134.42 61.3,134.35 61.3,132.89 61.24,132.83 61.24,132.32 60.92,132 53.36,132 45.36,124 45.36,120.13 42.88,117.65 38.95,117.65 38.76,117.84 38.76,119.43 39.58,120.26 40.66,120.26 43.23,122.83 43.23,125.94 51.71,134.42
+2.5VS on L3_IN1: 32.07,102.71 31.55,102.19 27.23,102.19 26.19,101.14 26.19,99.18 24.64,97.64 24.64,95.57 27.92,92.3 30.57,92.3 30.75,92.12 30.75,89.83 30.27,89.35 25.18,89.35 24.91,89.08 24.91,87.95 25.22,87.64 25.23,87.64 26.85,86.02 30.94,86.02 31.3,85.66 31.3,83.63 31.01,83.35 25.57,83.35 24.11,84.81 24.11,87.06 22.87,88.3 22.87,98.26 23.16,98.56 23.16,109.56 24.99,111.39 31.7,111.39 32.07,111.02 32.07,109.13 31.81,108.87 25.32,108.87 24.89,108.44 24.89,106.1 25.43,105.56 31.46,105.56 32.07,104.96
+3.3V on TOP (solid shape): 119.08,21.98 119.08,19.23 119.47,18.85 120.05,18.85 120.34,18.55 120.34,18.17 120.21,18.04 117.93,18.04 117.55,18.42 117.55,22.11 117.67,22.23 118.83,22.23
+3.3V on TOP (solid shape): 132.28,60.09 132.28,58.1 132,57.81 128.17,57.81 128.03,57.95 128.03,59.87 128.25,60.09 128.77,60.09 128.95,59.91 128.95,59.46 129.05,59.36 129.95,59.36 131.3,60.72 131.65,60.72
+3.3V on TOP (solid shape): outline of 118 points within 9.42,14.63 31.49,40.12
+3.3V on L3_IN1 (solid shape): 128.07,69.19 128.07,67.81 127.63,67.38 126.57,67.38 125.74,68.21 125.74,69.16 126.06,69.48 127.78,69.48
+3.3V on L3_IN1 (solid shape): 32.03,22.3 32.46,22.3 32.57,22.19 32.57,21.3 32.53,21.26 31.78,21.26 31.7,21.18 30.28,21.18 30.2,21.26 30.2,22.31 32.03,22.31
+3.3V on L3_IN1 (solid shape): outline of 550 points within 99.08,13.43 134.44,23.85
+3.3V on TOP: 124,66.99 121.94,69.05 121.94,72.4 122.07,72.52 122.73,72.52 122.8,72.45 123.95,72.45 123.95,68.56 124.43,68.08 125.27,68.08 125.8,68.61 125.8,70.33 126.3,70.83 126.3,75.79 125.6,76.49 125.09,76.49 124.94,76.65 124.94,77.63 125.65,78.34 126.46,78.34 126.97,77.83 128.88,77.83 129.87,76.84 130.37,76.84 130.5,76.72 130.5,71.84 127.5,68.84 127.5,67.65 127.27,67.42 126.36,67.42 125.93,66.99
+3.3V on TOP: 36.37,129.85 36.37,128.84 36.27,128.74 35.38,128.74 35.27,128.63 35.27,128.05 35.15,127.92 33.6,127.92 33.57,127.95 33.57,128.46 33.19,128.84 33.19,129.95 33.29,130.06 36.16,130.06
+3.3V on L2_VCC: outline of 85 points within 20.42,20 144.85,133.2
+3.3V_LCD on TOP: 126.81,125.86 127.55,125.86 127.64,125.95 127.64,127.96 127.96,128.28 128.24,128.28 128.39,128.43 128.39,128.81 128.24,128.96 126.56,128.96 126.28,128.68 126.28,128.02 126.76,127.55 126.76,125.92
+3.3V_LCD on BOTTOM: 127.4,132.8 128.65,132.8 128.72,132.72 128.72,130.49 127.83,129.6 127.83,129.14 128.01,128.96 128.34,128.96 128.42,128.89 128.42,128.46 128.26,128.3 128.01,128.3 127.45,127.74 126.87,127.74 126.77,127.85 126.77,130.36 126.89,130.49 126.89,132.29
+3.3V_WIFI on TOP (solid shape): 112.47,49.41 112.47,48.65 112.46,48.65 112.46,47.61 112.23,47.37 111.58,47.37 111.58,47.38 110.69,47.38 110.39,47.68 110.39,49.36 110.56,49.54 112.34,49.54
+3.3V_WIFI on BOTTOM: 111.07,52.08 112.21,52.08 112.59,51.7 112.59,46.61 111.93,45.94 111.08,45.94 110.75,46.27 110.75,49.35 110.94,49.54 110.94,51.95
+3.3VA on TOP (solid shape): 26,125.08 26.77,125.08 26.82,125.03 26.82,123.91 26.69,123.78 26.69,123.76 26.59,123.66 25.04,123.66 24.81,123.88 24.81,125.48 25.6,125.48
+3.3VA on BOTTOM (solid shape): 23.64,75.59 23.64,74.48 23.39,74.22 22.09,74.22 21.71,74.6 21.71,75.4 21.98,75.67 23.56,75.67
+3.3VA on TOP: 106.9,96.58 113.84,96.58 117.82,100.57 117.82,103.31 119.32,104.8 119.32,116.95 118.64,117.64 118.64,120.48 119.15,120.99 119.15,125.1 118.81,125.44 117.77,125.44 117.43,125.1 117.43,122.02 116.81,121.39 116.81,116.76 112.52,112.47 112.52,103.11 109.39,99.98 109.39,98.92 108.83,98.36 106.95,98.36 106.75,98.15 106.75,96.73
+3.3VA on BOTTOM: 119.3,123.71 116.4,123.71 114.65,125.46 114.65,126.83 114.88,127.06 116.28,127.06 117.75,125.59 118.99,125.59 119.3,125.28
+3.3VA on BOTTOM: 107.39,94.34 106.5,94.34 106.32,94.52 106.32,97.32 106.67,97.67 107.46,97.67 107.56,97.57 107.56,96.63 107.51,96.58 107.51,94.47
+3.3VA on BOTTOM: 25.34,124.95 27.53,124.95 27.77,124.71 27.77,122.35 28.19,121.93 28.19,120 28.52,119.67 29,119.67 29.64,119.03 30.3,119.03 30.47,118.85 30.47,116.43 28.96,116.43 28.24,117.15 28.24,118.3 27.96,118.58 26.92,118.58 26.87,118.63 26.87,119.99 25.67,121.19 25.67,123.43 25.17,123.93 25.17,124.77
+3.3VA on BOTTOM: 110.56,56.91 108.66,56.91 108.28,56.52 108.28,53.35 107.77,52.84 107.77,51.19 107.9,51.06 110.56,51.06 110.69,51.19 110.69,56.78
+3.3VA on L3_IN1: 108.44,55.72 109.16,56.44 109.16,59.7 109.17,59.73 110.31,60.87 110.31,70.67 111.8,72.17 111.8,76 109.82,77.98 109.82,82.18 107.94,84.06 107.94,85.15 108.15,85.35 108.15,89.42 108.53,89.8 108.53,91.93 106.98,93.48 106.98,97.62 107.06,97.7 110.76,97.7 110.76,97.67 111.73,96.71 111.73,84.48 115.01,81.2 115.01,72.55 113.86,71.41 113.86,67.88 112.77,66.78 112.77,56.83 109.42,53.48 108.66,53.48 108.44,53.69
+3.3VA_PCH on TOP: 28.24,125.08 29.25,125.08 29.27,125.09 29.28,125.08 30.3,125.08 30.4,124.98 30.4,124.06 30.07,123.73 30.07,123.35 29.92,123.2 28.8,123.2 28.16,123.83 28.16,125
+3.3VA_PCH on BOTTOM: 104.01,78.04 104.01,77.35 104.21,77.14 104.21,76.48 104.19,76.46 103.78,76.46 103.45,76.79 101.21,76.79 100.71,77.3 97.76,77.3 97.5,77.05 97.5,76.41 97.23,76.13 94.36,76.13 94.08,75.85 93.72,75.85 93.64,75.93 93.64,76.28 96.34,78.98 100.32,78.98 101.62,77.68 102.81,77.68 103.04,77.91 103.04,78.34 103.09,78.39 103.65,78.39
+3.3VA_PCH on L2_VCC: 24.17,78.07 23.57,78.67 23.06,78.67 22.88,78.85 22.88,80.63 19.96,83.55 19.96,101.33 19.2,102.09 19.2,121.92 21.16,123.88 30.32,123.88 30.38,123.83 30.38,123.53 29.4,122.56 25.08,122.56 20.27,117.74 20.27,110.37 20.01,110.12 20.01,109.19 20.27,108.94 20.27,104.87 20.77,104.37 22.12,104.37 22.12,84.71 26.95,79.89 26.95,78.72 26.51,78.29 24.61,78.29 24.39,78.07
+3.3VA_PCH on L4_IN2: 59.99,69.96 58.31,71.64 56.13,71.64 54.5,73.26 50.46,73.26 47.59,76.13 42.51,76.13 39.67,78.98 27.22,78.98 26.02,77.78 23.6,77.78 22.93,78.45 22.93,80.62 22.95,80.63 23.64,80.63 23.9,80.38 39.97,80.38 42.82,77.53 48.73,77.53 51.93,74.33 64.18,74.33 66.14,72.37 67.61,72.37 69.95,74.71 73.25,74.71 73.25,72.78 70.05,69.58 66.19,69.58 65.81,69.96
+3.3VA_PCH on L4_IN2: 71.98,74.71 83.53,74.71 84.2,75.37 86.84,75.37 87.83,74.38 90.06,74.38 91.21,75.52 93.24,75.52 93.75,76.03 93.75,76.44 94.08,76.44 94.18,76.33 94.18,74.66 93.03,73.52 86.81,73.52 86.51,73.82 84.47,73.82 83.43,72.78 72.36,72.78 71.98,73.16
+3.3VAL on TOP: 30.73,122.59 30.73,123.78 30.55,123.96 30.55,125.97 30.63,126.04 31.46,126.04 31.64,125.86 31.64,123.99 32.25,123.37 33.85,123.37 35.64,121.59 37.52,121.59 37.71,121.4 37.71,120.73 37.57,120.59 35.46,120.59 34.48,121.57 31.74,121.57
+3.3VAL on TOP: outline of 146 points within 20.29,125.33 32.43,137.04
+3.3VAL on BOTTOM: 29,136.79 29,135.16 28.21,134.37 24.18,134.37 24.17,134.38 23.62,134.38 23.39,134.6 23.39,136.53 23.64,136.79
+3.3VAL on L3_IN1: 31.59,122.31 31.59,123.22 32.86,123.22 32.86,122.31
+3.3VAL_SW on TOP (solid shape): 39.54,136.16 39.54,135.72 39.71,135.54 39.94,135.54 39.94,135.54 40.83,135.54 41.14,135.24 41.14,134.06 40.87,133.8 39.88,133.8 38.11,132.03 35.06,132.03 34.72,132.37 34.72,137.17 34.79,137.24 38.45,137.24
+3.3VS on BOTTOM (solid shape): 110.44,12.92 110.44,11.47 109.82,10.85 108.84,10.85 108.62,11.07 108.62,12.97 108.7,13.05 110.31,13.05
+3.3VS on TOP: 109.17,6.1 111.22,6.1 111.35,6.23 111.35,7.12 111.32,7.12 110.44,8.01 110.44,12.96 110.31,13.09 108.91,13.09 108.78,12.96 108.78,6.48
+3.3VS on TOP: 33.55,125.74 33.55,126.55 35.27,126.55 35.38,126.45 35.38,125.33 35.2,125.15 35.2,124.54 34.92,124.26 33.32,124.26 33.24,124.34 33.24,125.43
+3.3VS on L2_VCC: 98.57,33.77 90.5,41.84 87.85,41.84 87.3,41.28 71.92,41.28 69.95,43.25 69.95,44.84 63.73,51.07 63.73,54.88 58.15,60.46 54.46,60.46 46.72,68.2 36.39,68.2 36.31,68.13 34.11,68.13 32.59,69.65 27.76,69.65 16.91,80.5 16.91,86.47 16.28,87.1 16.28,91.04 14.25,93.07 14.25,119.87 13.87,120.25 13.87,124.46 14.25,124.84 14.25,126.7 16.51,128.96 16.62,128.96 16.67,129.01 31.35,129.01 31.9,129.56 32.71,128.75 32.71,127.35 33.47,126.6 34.99,126.6 35.25,126.34 35.25,124.6 34.86,124.21 31.05,124.21 30.63,123.79 30.63,123.93 30.43,124.13 21.05,124.13 18.95,122.03 18.95,101.98 19.71,101.22 19.71,83.44 22.63,80.52 22.63,78.74 22.96,78.41 23.47,78.41 28.55,73.33 34.64,73.33 37.56,70.41 47.6,70.41 51.41,66.6 70.96,66.6 72.92,64.65 72.92,59.44 75.21,57.15 75.21,51.87 75.15,51.87 75.08,51.8 75.08,51.69 75.15,51.62 75.21,51.62 75.21,49.79 79.98,45.01 95.09,45.01 96.92,43.18 96.92,41.15 101.49,36.58 101.49,34.08 101.19,33.77
+3.3VS on L4_IN2: 109.07,11.52 110.47,11.52 110.82,11.87 110.82,25.68 101.2,35.3 99.6,35.3 99.29,34.99 99.29,31.9 108.21,22.98 108.21,12.38
+5V on TOP (solid shape): 28.22,78.28 28.22,76.44 28.15,76.38 27.33,76.38 27.07,76.63 27.07,78.28 27.2,78.41 28.09,78.41
+5V on TOP (solid shape): 100.38,19.7 100.38,16.59 96.76,12.97 96.76,12.13 96.69,12.06 96.07,12.06 95.91,12.22 95.91,14.43 98.98,17.5 98.98,19.64 99.22,19.89 100.2,19.89
+5V on TOP (solid shape): 10.1,76.59 10.1,75.07 10.61,74.56 10.61,73.03 10.49,72.91 9.09,72.91 8.45,73.54 8.45,76.59 7.87,77.18 6.3,77.18 6.3,78.88 6.42,79 7.69,79
+5V on TOP (solid shape): 34.27,57.06 34.27,55.44 35.24,54.47 35.24,53.67 35.21,53.64 34.83,53.64 34.15,54.32 33.31,54.32 33.24,54.24 33.24,53.4 32.98,53.14 32.19,53.14 31.94,52.88 31.9,52.88 31.77,52.76 16.6,52.76 15.26,54.09 13.17,54.09 12.28,53.2 12.28,52.31 11.9,51.93 10.37,51.93 9.93,52.37 9.93,54.6 11.32,55.99 15.52,55.99 16.21,55.3 17.1,55.3 18.06,54.34 30.76,54.34 31.07,54.66 31.07,57.2 31.33,57.45 33.87,57.45
+5V on TOP (solid shape): 38.34,51.96 38.34,51.2 38.12,50.98 38.12,50.28 37.61,49.77 36.4,49.77 36.11,50.06 36.11,50.7 36.26,50.85 36.68,50.85 37.39,50.95 37.36,51.67 37.36,51.69 37.23,51.82 37.1,51.82 36.98,51.83 36.86,51.82 36.8,51.82 36.65,51.96 36.65,52.22 36.68,52.25 38.05,52.25
+5V on BOTTOM (solid shape): 10.99,75.96 10.99,74.69 11.4,74.28 12.24,74.28 12.47,74.05 12.47,72.8 12.34,72.67 10.69,72.67 10.43,72.93 9.4,72.93 9.39,72.93 9.04,72.93 8.58,73.39 8.58,75.83 8.96,76.21 10.74,76.21
+5V on BOTTOM (solid shape): outline of 298 points within 31.03,50.05 38.32,55.04
+5V on TOP: 147.24,108.72 147.24,106.69 147.11,106.56 143.43,106.56 143.42,106.55 143.33,106.55 143.19,106.42 143.19,104.76 142.87,104.45 142.01,104.45 141.78,104.68 141.78,106.07 141.33,106.52 139.94,106.52 139.8,106.66 139.8,109.28 139.93,109.41 146.55,109.41
+5V on BOTTOM: 128.24,133.99 129.76,133.99 129.86,133.89 129.86,132.27 128.8,132.27 128.11,132.95 128.11,133.87
+5V on L3_IN1: outline of 126 points within 3.37,19.26 149.12,135.39 ; 4 cut-outs
+5V on L4_IN2: 128.67,134.04 126.97,134.04 123.57,130.64 123.57,130.59 123.54,130.56 123.54,128.76 123.64,128.66 125.11,128.66 125.29,128.84 125.29,129.88 127.25,131.83 128.49,131.83 128.82,132.16 128.82,133.89
+5V_CODECAVDD on L3_IN1: 146.35,30.28 148.43,28.2 154.32,28.2 154.32,30.61 154.22,30.72 151.2,30.72 151.17,30.69 149.23,30.69 147.71,32.22 147.34,32.22 146.35,31.24
+5VAL on TOP (solid shape): 48.41,136.7 48.41,132.38 48.15,132.13 47.46,132.13 47.2,132.38 47.2,133.08 46.88,133.4 46.88,135.88 47.84,136.83 48.28,136.83
+5VAL on TOP (solid shape): 139.21,77.27 140.23,77.27 140.36,77.14 140.36,75.24 140.23,75.11 137.94,75.11 137.82,74.98 135.02,74.98 134.9,75.11 134.9,75.87 135.15,76.13 136.17,76.13 136.17,77.4 136.55,77.78 138.71,77.78
+5VAL on L4_IN2 (solid shape): outline of 448 points within 46.82,134.04 70.95,139.18
+5VAL on TOP: 122.93,106.81 123.46,107.35 127.73,107.35 128.72,106.36 132.55,106.36 137.87,111.69 139.73,111.69 139.75,111.67 140.97,111.67 141.13,111.5 141.13,109.96 141,109.82 140.01,109.82 139.57,109.38 139.57,107.53 139.42,107.37 138.6,107.37 137.89,106.66 137.89,104.68 138.43,104.15 140.18,104.15 140.31,104.02 140.31,104.02 141.53,102.8 141.53,100.66 141.31,100.44 131.32,100.44 130.94,100.82 129.42,100.82 128.86,100.26 128.86,97.83 125.56,94.54 123.4,94.54 122.93,95.01
+5VAL on BOTTOM: 47.27,132.26 47.27,134.48 46.95,134.8 46.95,135.88 47.84,136.77 49.3,136.77 49.77,136.29 49.77,132.83 49.01,132.07 47.46,132.07
+5VAL on BOTTOM: 140.54,113.82 141.57,113.82 141.69,113.7 141.69,110.97 141.67,110.95 141.67,110.1 141.4,109.83 139.88,109.83 138.34,111.37 138.31,111.37 137.94,111.73 137.94,112.12 138.21,112.39 139.49,112.39 139.91,111.97 140.41,111.97 140.5,112.06 140.5,113.78
+5VAL on BOTTOM: 121.04,128.6 121.04,127.96 120.83,127.76 117.23,127.76 116.54,128.45 97.18,128.45 94.01,131.62 90.78,131.62 89.75,132.64 68.73,132.64 67.71,131.62 63.46,131.62 61.62,133.46 61.62,134.8 61.82,135 63.44,135 64.2,134.24 67.11,134.24 68.3,135.43 93.18,135.43 93.19,135.42 95.19,135.42 96.7,133.92 99.53,133.92 101.47,131.97 102.55,131.97 102.84,131.68 103.91,131.68 104.25,131.33 106.96,131.33 107.82,130.48 114.51,130.48 114.64,130.61 119.03,130.61
+5VAL on L3_IN1: 132.84,118.47 131.36,119.95 126.16,119.95 123.9,122.22 123.9,124.57 122.65,125.81 121.85,125.81 119.44,128.22 119.44,129.19 119.79,129.54 122.48,129.54 124.89,127.13 136.19,127.13 137.61,125.71 137.61,112.53 138.2,111.94 139.98,111.94 140.26,111.67 140.26,110.22 140.35,110.13 140.32,110.1 140.32,107.26 139.96,106.91 137.55,106.91 136.44,105.8 133.78,105.8 132.84,106.74
+5VAL_LX on TOP: 124.64,115.67 123.47,115.67 123.16,115.37 123.16,114.48 123.16,114.48 123.16,114.25 122.12,113.21 122.12,109.55 122.31,109.35 128.06,109.35 128.31,109.61 128.31,112.13 127.97,112.47 127.97,113.29 127.73,113.54 125.64,113.54 124.91,114.27 124.91,115.4
+VCCCLKX on BOTTOM: 87.29,73.92 87.29,71.51 87.93,70.87 90.72,70.87 90.85,71 90.85,71.76 89.33,73.29 88.18,73.29 88.18,74.05 88.06,74.18 87.55,74.18
+VCCMPHYGTAON_1P0_LS_SIP on TOP (solid shape): 93.49,72.91 93.49,72.55 92.7,71.76 92.42,71.76 92.25,71.94 92.25,72.09 92.02,72.32 91.76,72.32 91.66,72.22 91.54,72.22 91.43,72.32 91.43,72.51 91.44,72.53 91.45,72.55 91.52,72.61 91.56,72.7 91.57,72.71 91.66,72.8 91.66,72.93 91.89,73.16 91.89,73.24 92.07,73.41 92.98,73.41
+VCCMPHYGTAON_1P0_LS_SIP on TOP: 105.45,70.67 106.93,70.67 106.98,70.62 106.98,69.35 106.85,69.22 106.04,69.22 105.86,69.4 105.18,69.4 105.12,69.45 105.12,70.09 105.25,70.21 105.25,70.47
+VCCMPHYGTAON_1P0_LS_SIP on BOTTOM: 104.35,68.52 103.96,68.92 99.54,68.92 98.15,70.3 94.6,70.3 93.47,71.43 92.68,71.43 92.53,71.43 92.25,71.71 92.25,71.95 92.23,71.97 92.03,72.28 91.66,72.2 91.55,72.17 91.48,72.26 91.48,72.55 91.49,72.57 91.5,72.59 91.57,72.73 91.57,72.88 91.57,72.9 91.58,72.92 91.97,73.31 99.31,73.31 100.18,72.44 104.65,72.44 105.58,71.51 107.72,71.51 107.97,71.25 107.97,70.65 107.97,70.64 107.94,70.53 107.96,70.42 107.96,70.39 107.95,70.37 107.86,70.29 107.83,70.27 107.79,70.29 107.78,70.3 107.77,70.33 107.78,70.34 107.27,70.74 107.59,70.18 107.69,70.17 107.73,70.08 107.73,68.7 107.55,68.52
+VCCOPC on L4_IN2: 65.83,72.95 65.83,79.26 66.08,79.51 66.97,79.51 67.07,79.41 67.08,79.39 67.08,79.38 67.13,79.16 67.32,79.03 67.34,79.02 67.35,78.98 67.35,73.98 67.29,73.89 67.18,73.91 66.61,73.68 67.18,73.46 67.29,73.48 67.35,73.39 67.35,72.83 67.11,72.59 66.19,72.59
+VCCPDSW_3P3 on L3_IN1: 90.82,77.73 90.82,79.13 90.84,79.15 90.83,79.17 90.82,79.19 90.82,80.47 91.05,80.7 91.97,80.7 92.21,80.46 92.21,79.82 92.27,79.76 92.27,79.4 92.28,79.38 92.29,79.35 92.29,78.41 92.28,78.4 91.48,77.6 90.95,77.6
+VCCPGPPX on L4_IN2: 94.46,78.85 94.46,77.69 94.02,77.26 94.01,77.23 93.99,77.23 93.83,77.12 93.76,76.95 93.76,76.93 93.72,76.89 93.72,76.51 93.54,76.33 93.54,75.98 93.24,75.67 89.55,75.67 88.63,76.6 88.63,78.86 89.12,79.36 89.12,80.96 89.73,81.57 91.97,81.57 92.18,81.36 93.26,81.36 93.56,81.07 93.56,79.75
+VCCPRIM_1P0 on L3_IN1: 89.96,77.33 92.66,77.33 93.77,76.21 93.77,74.25 92.93,73.41 90.93,73.41 90.88,73.46 90.88,74.2 91.1,74.43 91.1,74.84 89.62,76.32 89.62,76.98
+VCCSA on TOP: 76.75,55.38 80.18,55.38 80.31,55.51 80.56,55.51 80.94,55.13 80.94,46.65 80.78,46.49 79.65,46.49 79.43,46.26 79.43,43.75 79.12,43.45 78.28,43.45 78.21,43.52 78.21,44.47 78.06,44.62 77.31,44.62 77.12,44.42 77.12,43.56 77.04,43.49 76,43.49 75.78,43.71 75.78,45.96 75.69,46.04 75.39,46.04 74.73,46.7 74.75,46.72 74.75,56.55 74.85,56.65 75.48,56.65
+VCCSA on TOP: outline of 89 points within 83.6,68.78 87.91,80.78
+VCCSA on BOTTOM: 76.32,55.22 78.86,55.22 78.99,55.1 78.99,52.2 78.86,52.07 76.43,52.07 76.1,52.4 76.1,55
+VCCSA on L2_VCC: 75.46,51.87 75.46,56.19 82.24,56.19 82.7,56.64 82.7,70.49 83.08,70.87 83.08,71.25 83.39,71.56 85.31,71.56 85.82,71.05 86.71,71.05 87.27,70.49 87.27,65.64 86.38,64.75 86.38,52.69 85.57,51.87
+VCCSA on L3_IN1: 76.69,51.48 76.12,52.05 76.12,55.51 76.37,55.76 79.29,55.76 83.99,60.46 83.99,69.22 83.56,69.65 83.56,71.33 83.71,71.48 84.63,71.48 84.98,71.13 85.47,71.13 87.17,69.43 87.17,68.82 86.94,68.59 86.94,65.86 87.28,65.52 87.28,65.01 86.94,64.67 86.94,56.17 85.42,54.64 83.52,54.64 80.35,51.48
+VCCSA on L4_IN2: 79.17,55 76.24,55 75.86,54.62 75.86,52.33 76.37,51.82 78.53,51.82 79.29,52.59 79.29,54.87
+VCCSRAM_1P0 on L3_IN1: 88.41,78.04 88.41,76.11 89.08,75.43 89.08,74.57 89.66,74 90.62,74 90.8,74.18 90.8,74.79 90.77,74.81 90.77,75.01 89.48,76.31 89.48,77.1 90.04,77.66 90.04,77.96 89.63,78.37 89.63,78.82 89.55,78.9 88.94,78.9 87.91,79.94 86.89,79.94 86.76,79.81 86.76,79.68
AGND_+1.35VS on TOP (solid shape): 97.02,138.6 97.02,137.75 96.86,137.59 95.84,137.59 95.69,137.75 95.69,138.56 95.84,138.71 96.92,138.71
AGND_+3.3VAL on TOP: 41.5,133.5 41.91,133.5 44.62,130.79 44.62,128.55 43.89,127.82 42.31,127.82 41.68,128.45 41.68,129.58 41.81,129.7 43.03,129.7 43.07,129.67 43.61,129.67 43.77,129.82 43.77,130.41 42.34,131.84 41.62,131.84 41.46,131.99 41.46,133.46
AGND_+5VAL on TOP: 128.66,118.77 129.1,118.77 130.12,117.76 130.12,114.91 129.86,114.66 128.5,114.66 128.43,114.72 128.43,116.4 128.27,116.56 127.29,116.56 126.62,115.89 125.19,115.89 125.12,115.96 125.12,116.14 126.09,117.11 128.13,117.11 128.32,117.31 128.32,118.43
GND POWER on TOP (solid shape): 33.26,52.63 33.26,51.78 33.16,51.69 31.98,51.69 31.83,51.83 31.83,52.5 32.01,52.67 33.22,52.67
GND POWER on TOP (solid shape): 142.02,29.05 142.02,28.1 141.86,27.94 140.4,27.94 140.07,28.26 140.07,28.69 140.57,29.19 141.88,29.19
GND POWER on TOP (solid shape): 110.04,35.18 127.89,35.18 127.99,35.07 127.99,34.43 127.94,34.38 109.05,34.38 109.04,34.39 109.04,52.04 110.04,52.04
GND POWER on TOP (solid shape): 142.31,86.85 142.31,85.75 142.26,85.7 138.83,85.7 138.71,85.58 137.05,85.58 136.79,85.84 136.79,87.04 137.54,87.79 141.37,87.79
GND POWER on TOP (solid shape): 128.02,42.42 127.84,42.24 125.47,42.24 125.44,42.26 125.44,51.04 109.04,51.04 109.04,52.04 128.02,52.04
GND POWER on TOP (solid shape): 119.8,133.75 119.8,132.74 119.6,132.53 118.18,132.53 118.09,132.62 118.09,133.32 118.18,133.4 119.25,133.4 119.42,133.57 119.42,133.73 119.52,133.83 119.72,133.83
GND POWER on TOP (solid shape): 143.18,43.26 143.18,42.01 142.34,41.17 142.11,41.17 141.46,41.83 140.51,41.83 140.31,42.03 140.31,42.65 140.56,42.91 140.56,43.29 140.75,43.48 142.95,43.48
GND POWER on TOP (solid shape): 20.01,111.72 20.01,109.36 20.01,109.36 20.52,108.85 20.77,108.85 20.9,108.72 20.9,107.45 20.62,107.17 19.61,107.17 19.43,106.99 17.18,106.99 16.93,107.24 16.93,111.04 17.76,111.87 19.86,111.87
GND POWER on TOP (solid shape): 108.59,11.96 108.59,7.72 108.34,7.47 107.03,7.47 106.77,7.73 106.77,8.42 106.77,8.43 106.77,8.57 107.46,9.26 107.46,11.68 107.83,12.06 108.49,12.06
GND POWER on TOP (solid shape): 43.08,123.88 43.08,123.39 42.9,123.22 40.94,123.22 40.66,122.93 40.66,119.69 38.76,117.78 36.98,117.78 36.73,118.04 36.73,118.67 37.11,119.05 37.49,119.05 37.87,119.43 37.87,123.63 38.5,124.26 42.69,124.26
GND POWER on TOP (solid shape): 28.7,125.26 27.71,125.26 27.6,125.15 27.6,124.14 27.68,124.06 27.68,123.68 27.6,123.6 27.35,123.6 27.32,123.63 27.32,124.11 27.38,124.16 27.38,125.15 27.27,125.26 26.26,125.26 26.26,126.2 28.7,126.2
GND POWER on TOP (solid shape): 33.4,128.4 33.4,127.36 33.45,127.31 34.39,127.31 34.41,127.29 34.41,127.08 34.39,127.06 33.47,127.06 33.42,127.01 33.42,125.97 32.99,125.53 32.99,124.37 32.86,124.24 31.9,124.24 31.85,124.29 31.85,125.18 32.33,125.18 32.48,125.33 32.48,128.43 33.37,128.43
GND POWER on TOP (solid shape): 142.99,74.66 142.99,70.06 142.77,69.85 141.88,69.85 141.7,70.03 141.7,71.99 141.48,72.2 138.16,72.2 137.93,71.97 137.93,70.08 138.13,69.88 138.13,69.84 138.17,69.84 138.7,69.31 138.7,66.12 138.38,65.8 137.44,65.8 137.19,66.05 137.19,69.29 137.04,69.43 137.04,71.74 135.73,73.05 135.73,73.15 135.58,73.29 135.07,73.29 134.78,73.58 134.78,74.41 135.01,74.64 138.28,74.64 138.53,74.89 142.76,74.89
GND POWER on TOP (solid shape): 140.35,38.95 141.51,38.95 142.9,37.57 142.9,37.32 143.51,36.71 143.7,36.71 145.41,35 147.08,35 147.35,34.73 147.35,34 147.17,33.82 143.85,33.82 143.26,33.23 139.16,33.23 138.55,33.83 138.55,34.29 138.95,34.69 139.98,34.69 140.33,35.03 142.26,35.03 142.88,35.66 142.88,36.75 142.2,37.44 142.2,37.71 140.71,37.71 139.99,38.43 139.81,38.43 139.44,38.8 139.44,39.19 139.58,39.33 139.98,39.33
GND POWER on TOP (solid shape): 158.36,24.07 158.36,23.37 158.09,23.09 157.58,23.09 157.33,23.3 157.01,23.38 156.26,23.38 155.78,23.18 155.56,22.71 155.45,22.59 154.85,22.59 154.7,22.75 154.7,23 155.77,24.07 155.77,24.86 156.09,25.18 157.25,25.18
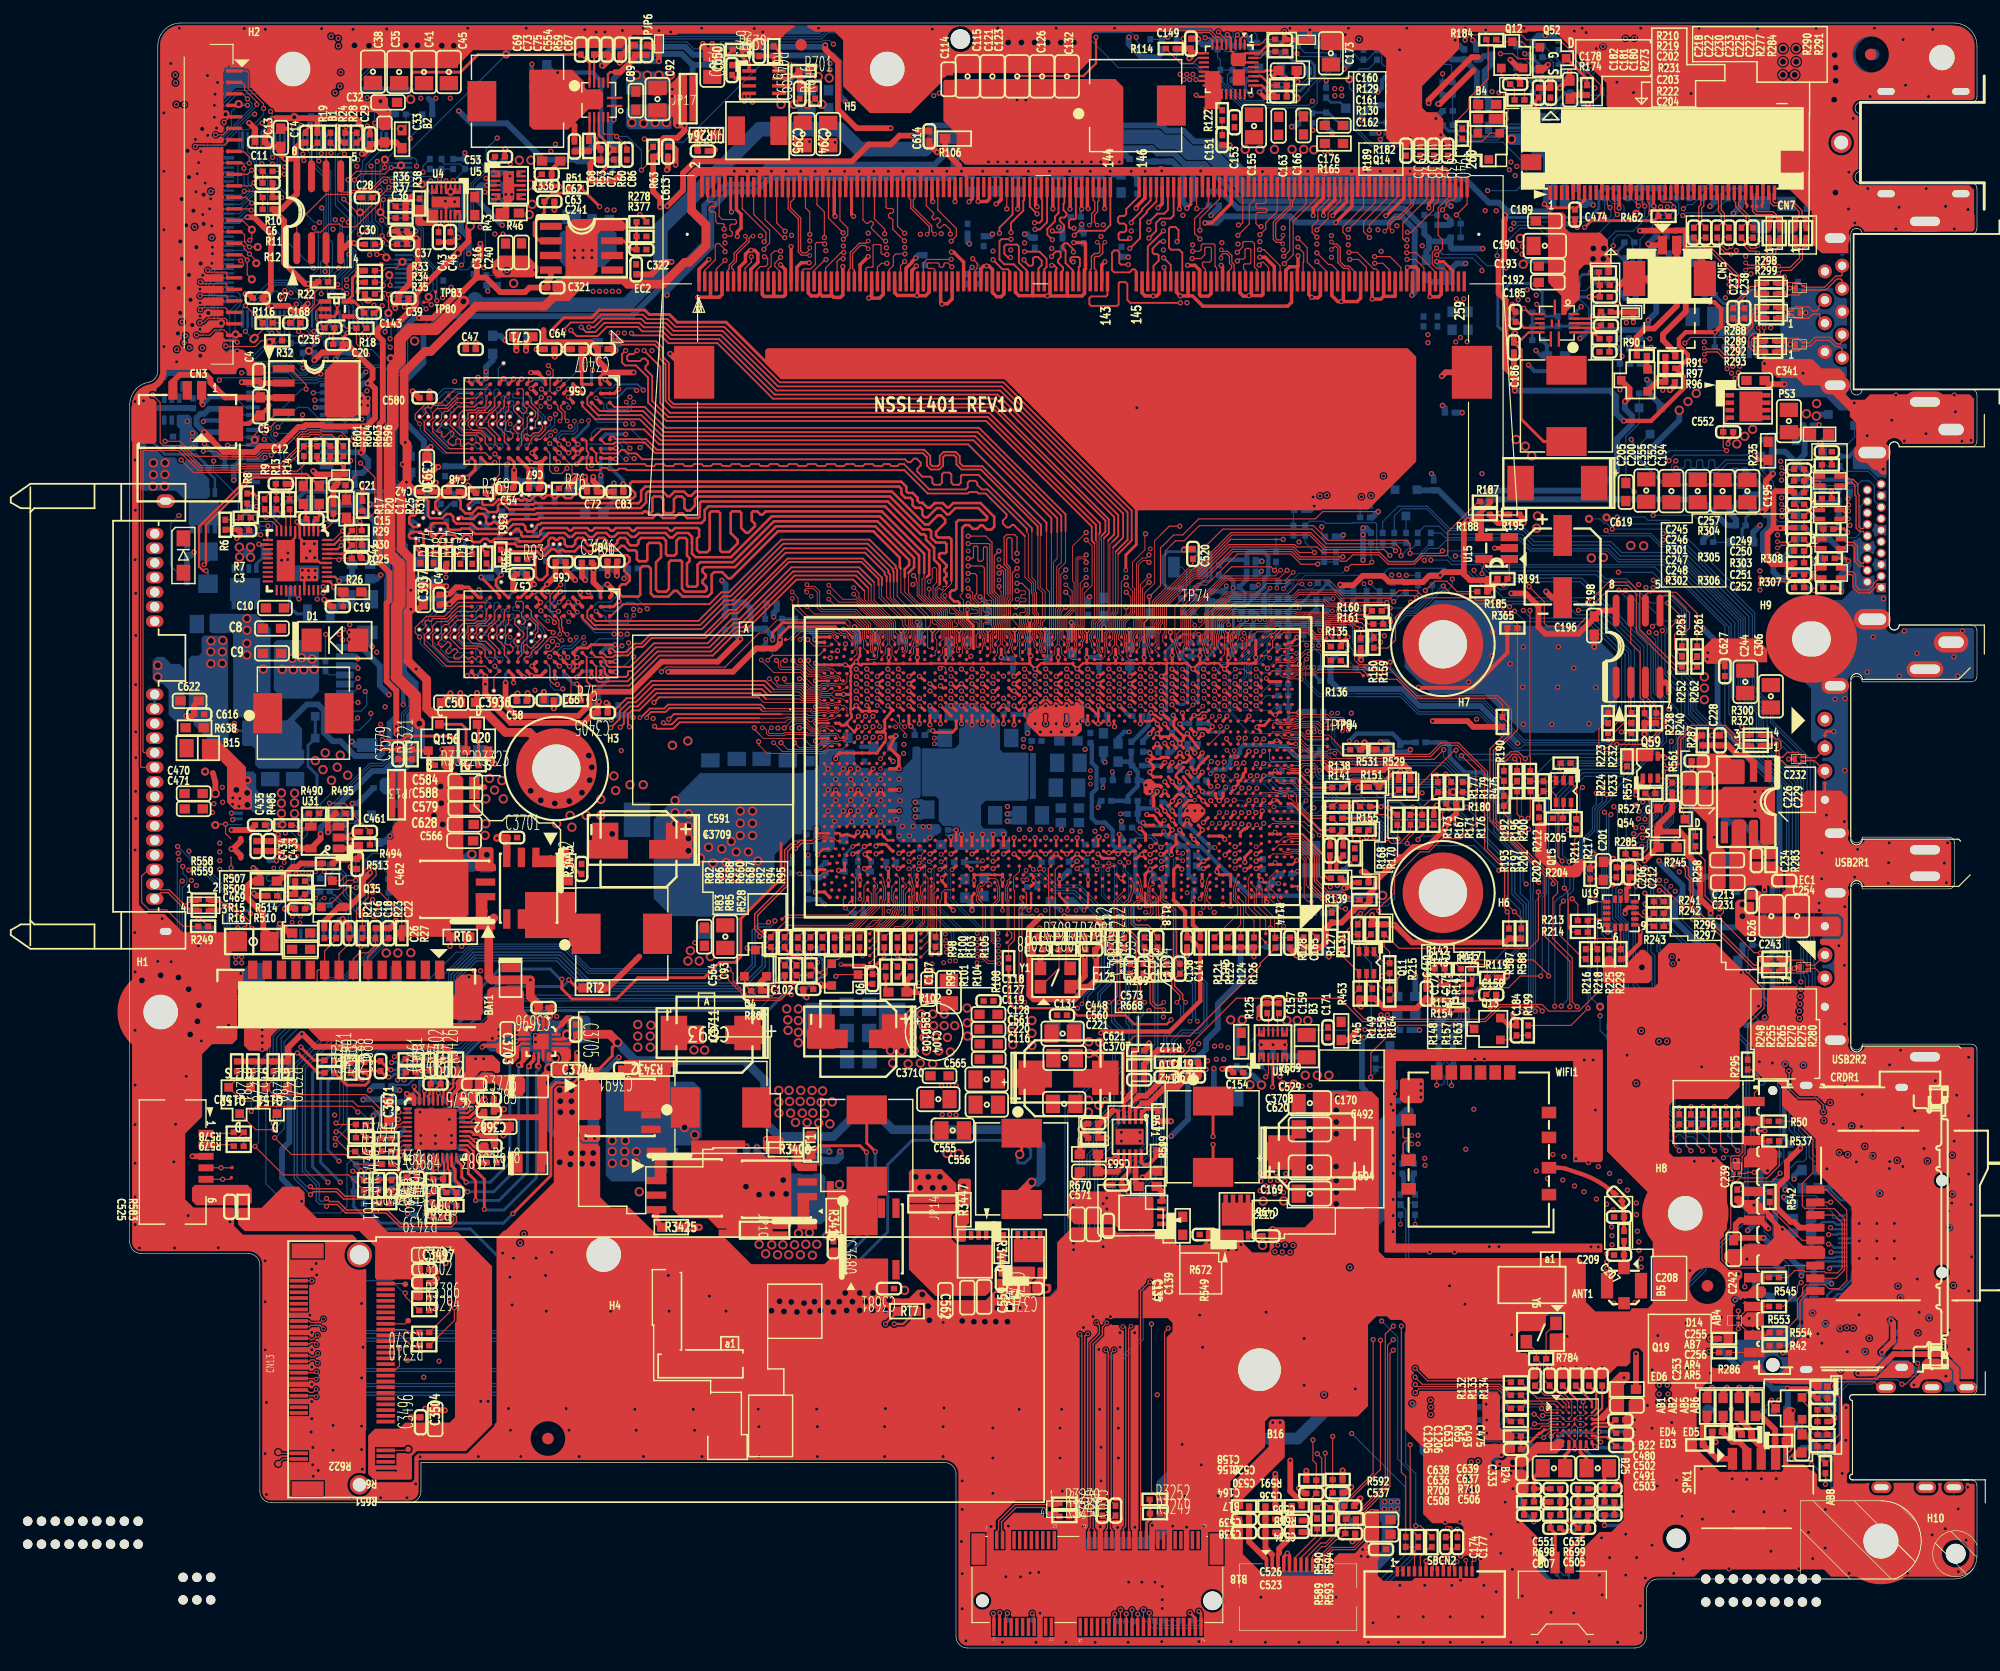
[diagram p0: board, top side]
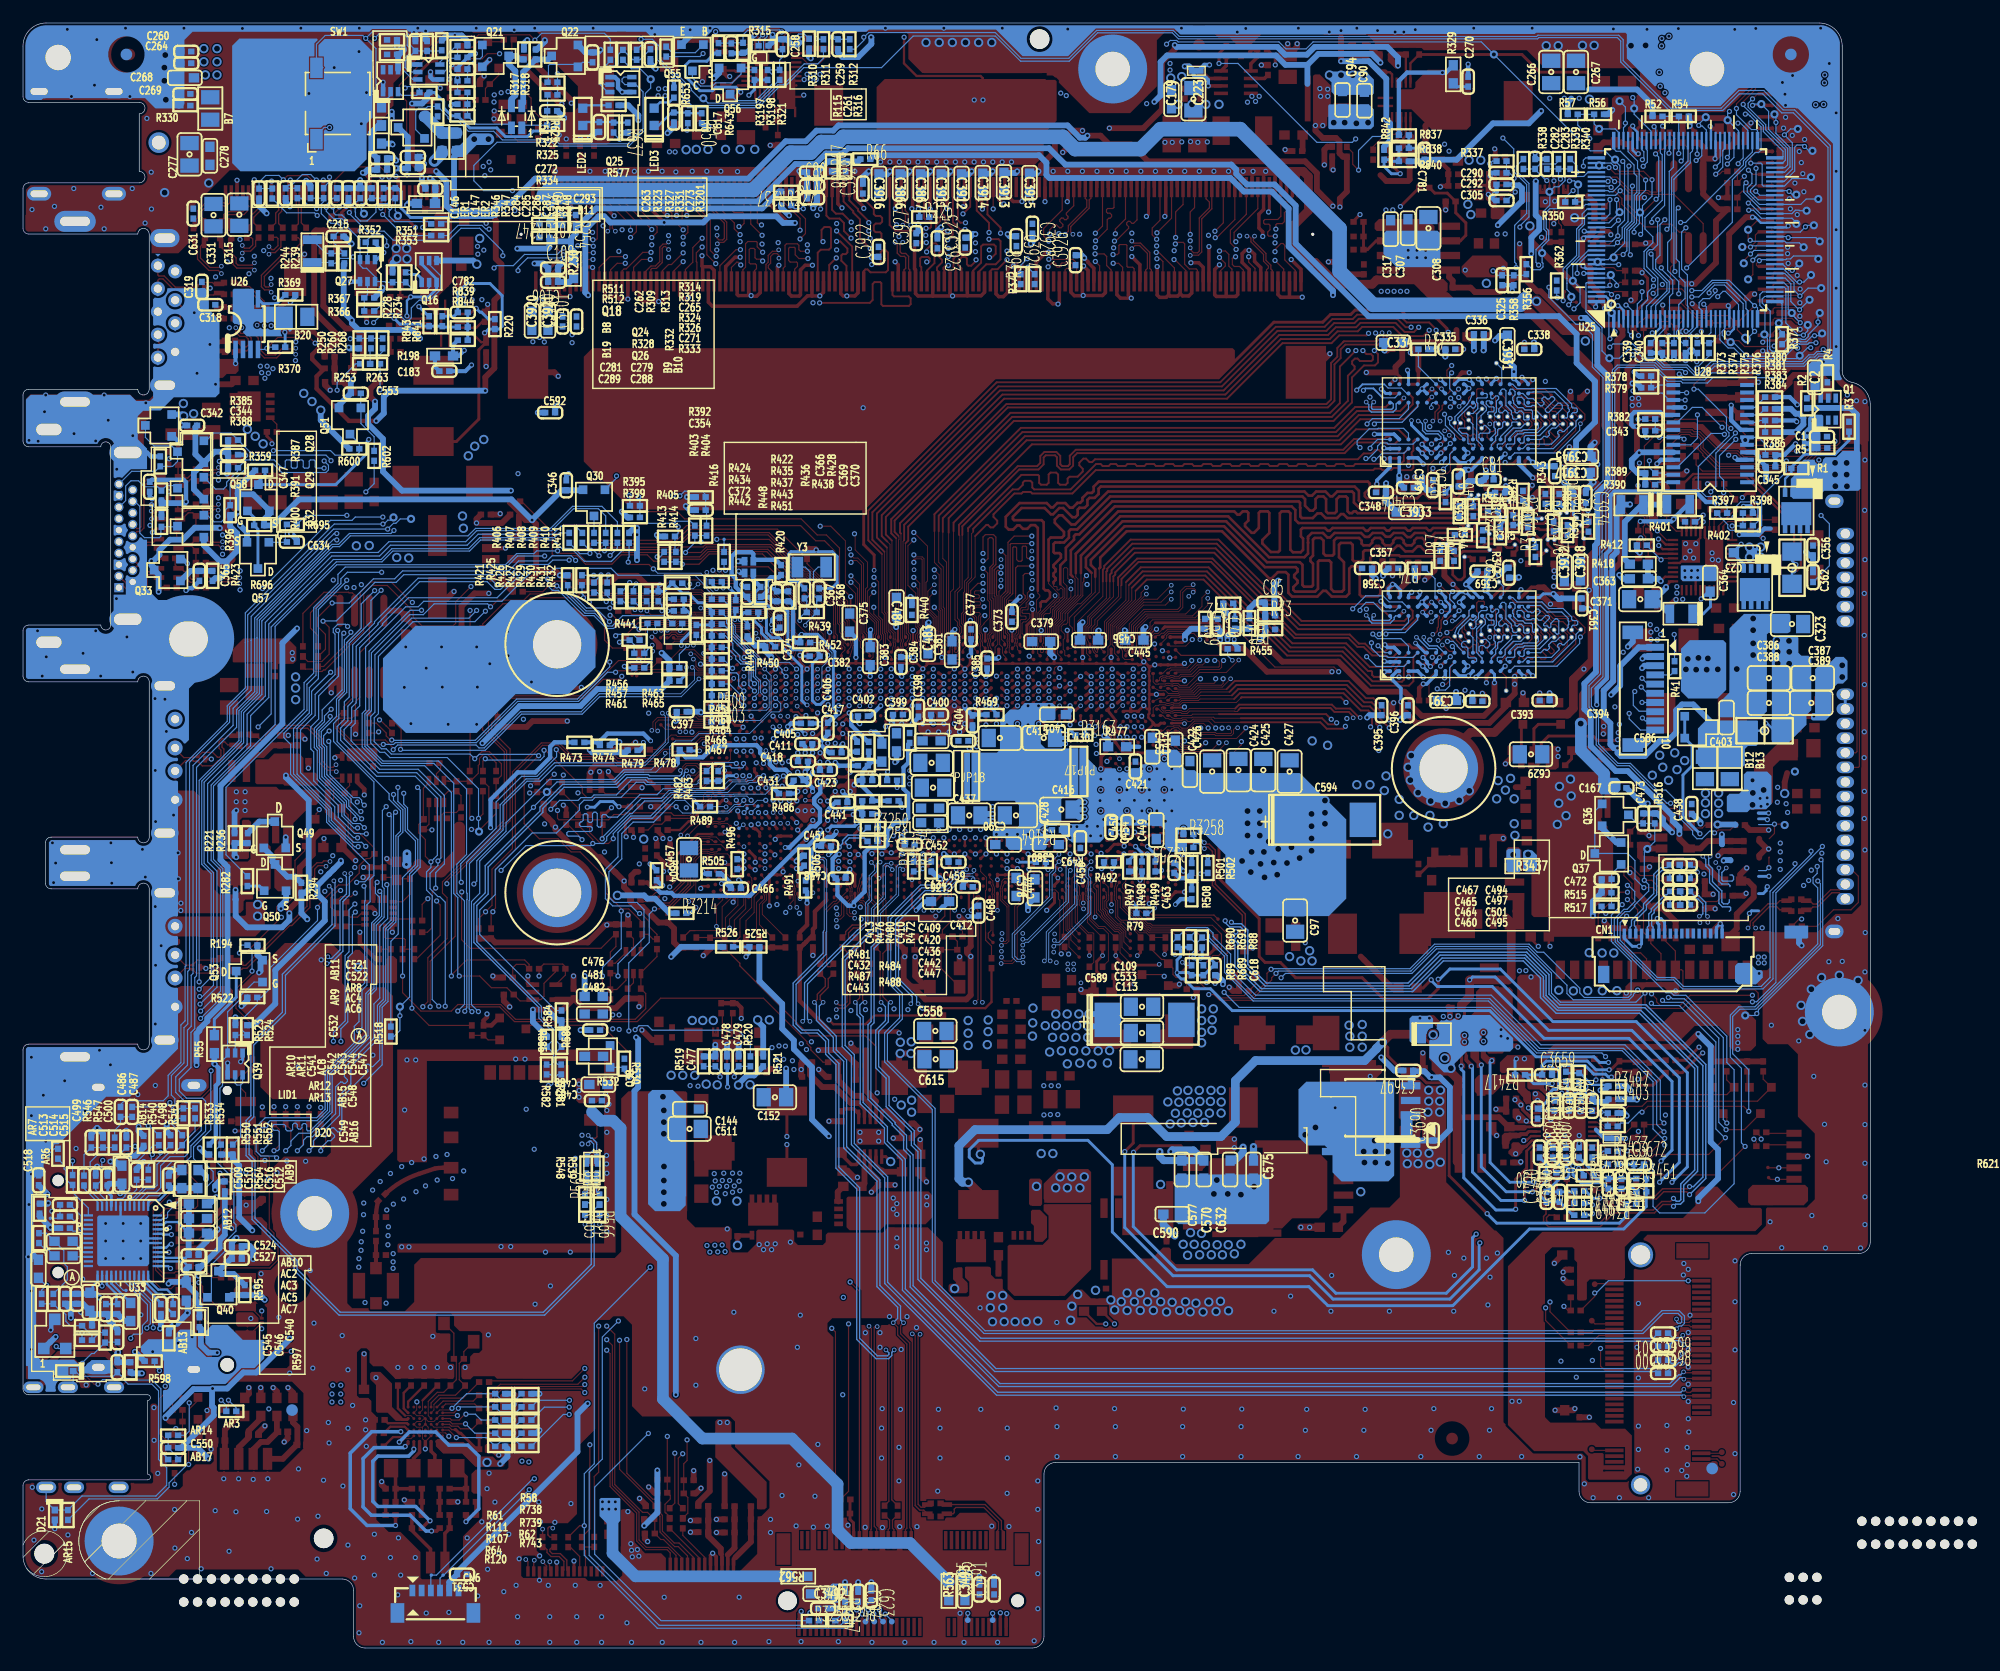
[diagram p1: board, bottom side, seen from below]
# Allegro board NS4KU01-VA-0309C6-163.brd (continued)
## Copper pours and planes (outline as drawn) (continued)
GND POWER on TOP (solid shape): 35.52,120.13 35.52,119.62 35.07,119.18 33.51,119.18 33.47,119.19 33.4,119.2 33.33,119.2 33.26,119.19 33.22,119.18 31.9,119.18 31.52,119.56 31.52,119.75 32.43,119.75 32.43,119.69 32.44,119.64 32.46,119.59 32.49,119.54 32.52,119.5 32.56,119.47 32.61,119.44 32.66,119.41 32.71,119.4 32.76,119.39 32.81,119.39 32.86,119.4 32.92,119.41 32.96,119.44 33.01,119.47 33.05,119.5 33.08,119.54 33.11,119.59 33.13,119.64 33.14,119.69 33.14,119.75 33.14,119.8 33.13,119.85 33.11,119.9 33.08,119.95 33.05,119.99 33.01,120.03 32.96,120.06 32.92,120.08 32.86,120.09 32.81,120.1 32.76,120.1 32.71,120.09 32.66,120.08 32.61,120.06 32.56,120.03 32.52,119.99 32.49,119.95 32.46,119.9 32.44,119.85 32.43,119.8 32.43,119.75 31.52,119.75 31.52,120.45 32.15,121.09 34.57,121.09
GND POWER on TOP (solid shape): 147.02,111.27 148.59,111.27 149.06,110.8 149.06,109.07 149.59,108.54 150.78,108.54 151.25,109.02 159.89,109.02 160.29,108.62 160.29,105.02 160.29,104.99 160.22,104.77 160,104.7 159.97,104.7 154.07,104.7 153.05,105.15 152.67,104.11 152.67,102.03 152.22,102.03 151.81,102.44 151.57,102.44 150.04,103.97 150.04,106.51 149.49,107.06 149.49,107.48 147.19,109.78 145.49,109.78 144.83,110.44 143.17,110.44 142.83,110.79 142.06,110.79 141.81,111.04 141.81,111.8 142.09,112.09 146.21,112.09
GND POWER on TOP (solid shape): 30.68,58.3 30.68,55.16 30.18,54.66 20.6,54.66 19.83,55.42 19.83,56.7 19.93,56.87 19.91,57.07 20.52,57.33 19.91,57.09 19.87,57.15 19.83,57.2 19.83,57.2 19.58,57.45 17.93,57.45 17.17,56.69 16.79,56.69 16.6,56.88 16.6,57.68 16.8,57.89 20.91,57.89 21.28,57.51 21.28,57.33 21.29,57.31 21.3,57.29 21.48,57.11 21.48,56.98 21.51,56.86 21.51,56.54 21.52,56.52 21.53,56.5 21.65,56.38 21.67,56.37 21.68,56.37 27.81,56.37 28.27,56.82 28.27,58.05 28.77,58.56 30.43,58.56
GND POWER on TOP (solid shape): outline of 222 points within 55.22,98.93 111.81,113.02
GND POWER on TOP (solid shape): outline of 1064 points within 58.87,121.27 160.34,141.1
GND POWER on TOP (solid shape): outline of 7402 points within 0.2,0.2 160.34,141.1
GND POWER on BOTTOM (solid shape): 42.31,122.99 42.31,121.21 41.17,120.07 37.87,120.07 37.36,120.58 37.36,122.99 37.61,123.24 42.06,123.24
GND POWER on BOTTOM (solid shape): 154.09,37.47 154.09,33.38 153.91,33.2 149.77,33.2 149.57,33.4 149.57,37.42 149.76,37.6 153.95,37.6
GND POWER on BOTTOM (solid shape): 7.46,61.72 7.43,61.68 5.49,61.68 5.39,61.78 5.39,62.82 7.46,62.82
GND POWER on BOTTOM (solid shape): 47.27,136.96 47.27,136.58 46.82,136.13 46.82,135.31 46.57,135.05 43.27,135.05 43.14,135.18 43.14,136.39 43.84,137.08 47.14,137.08
GND POWER on BOTTOM (solid shape): 11.76,59.32 11.76,57.95 11.5,57.7 9.93,57.7 9.34,58.29 9.34,58.81 9.47,58.94 9.85,58.94 10.49,59.57 11.5,59.57
GND POWER on BOTTOM (solid shape): 5.41,106.96 5.41,106.2 5.94,105.67 5.94,104.28 5.71,104.05 4.41,104.05 4.34,104.12 4.34,106 4.09,106.25 4.09,107.12 4.21,107.24 5.13,107.24
GND POWER on BOTTOM (solid shape): 120.4,88.88 126.43,88.88 129.26,86.05 129.26,81.56 127.26,79.57 121.11,79.57 117.74,82.94 113.12,82.94 110.79,85.27 110.79,88.48 113.43,91.12 118.16,91.12
GND POWER on BOTTOM (solid shape): 106.22,48.17 106.22,38.59 105.61,37.98 103.45,37.98 102.94,38.49 102.94,39.25 102.9,39.29 102.9,47.37 104.06,48.52 105.86,48.52
GND POWER on BOTTOM (solid shape): 3.6,85.58 4.34,85.58 4.79,85.12 4.79,81.31 4.77,81.29 5.03,81.29 5.15,81.16 5.15,80.78 5.03,80.65 3.88,80.65 3.37,81.16 3.37,83.32 2.85,83.85 2.38,83.85 1.98,84.25 1.98,85.84 2.32,86.18 3,86.18
GND POWER on BOTTOM (solid shape): 9.44,89.92 10.97,89.92 12.24,88.65 12.24,84.21 12.25,84.2 12.25,83.08 13.15,82.18 13.15,81.06 13.03,80.93 9.49,80.93 8.99,81.44 8.99,88.15 8.96,88.15 8.84,88.27 7.06,88.27 6.93,88.4 6.93,89.8 7.06,89.93 9.44,89.93
GND POWER on BOTTOM (solid shape): 151.78,97.78 151.79,97.77 152.13,97.6 152.51,97.68 152.52,97.69 152.55,97.69 152.64,97.63 152.66,97.62 152.67,97.59 152.67,96.81 152.66,96.78 152.64,96.77 152.55,96.72 152.52,96.72 152.51,96.72 152.13,96.8 151.79,96.63 151.78,96.62 151.75,96.61 151.63,96.66 151.61,96.69 151.61,96.7 151.57,96.93 151.44,97.13 151.42,97.15 151.42,97.25 151.44,97.27 151.57,97.47 151.61,97.7 151.61,97.71 151.63,97.74 151.75,97.79
GND POWER on BOTTOM (solid shape): 151.78,94.78 151.79,94.77 152.13,94.6 152.51,94.68 152.52,94.68 152.55,94.68 152.64,94.63 152.66,94.62 152.67,94.59 152.67,93.81 152.66,93.78 152.64,93.77 152.55,93.72 152.52,93.72 152.51,93.72 152.13,93.8 151.79,93.63 151.78,93.62 151.75,93.61 151.63,93.66 151.61,93.69 151.61,93.7 151.57,93.93 151.44,94.13 151.41,94.2 151.44,94.27 151.57,94.47 151.61,94.7 151.61,94.71 151.63,94.74 151.75,94.79
GND POWER on BOTTOM (solid shape): outline of 90 points within 130.17,128.4 142.36,139.95
GND POWER on BOTTOM (solid shape): outline of 165 points within 139.57,20.47 150.28,28.1
GND POWER on BOTTOM (solid shape): outline of 364 points within 143.46,101.72 160.29,118.26
GND POWER on BOTTOM (solid shape): outline of 766 points within 143.46,22.28 160.29,96.59
GND POWER on BOTTOM (solid shape): outline of 815 points within 2.46,110.24 160.34,141.1
GND POWER on L3_IN1 (solid shape): 78.61,31.13 78.61,28.71 76.94,27.04 69.1,27.04 68.44,27.71 68.44,31.77 68.77,32.1 77.64,32.1
GND POWER on L3_IN1 (solid shape): 130.2,52.06 130.23,52.05 132.15,50.13 132.17,50.09 132.17,42.41 132.18,42.38 133.5,41.06 133.5,41.05 133.78,40.78 134.46,40.1 134.5,40.08 136.51,40.08 136.55,40.07 137.26,39.36 137.27,39.32 137.27,33.82 137.26,33.79 133.53,30.06 133.49,30.04 132.89,30.04 132.85,30.06 132.5,30.42 132.5,39.36 132.49,39.4 128.28,43.6 128.28,49.13 130.6,49.13 130.6,49.08 130.61,49.02 130.63,48.98 130.65,48.93 130.68,48.89 130.72,48.85 130.76,48.82 130.81,48.8 130.86,48.78 130.91,48.77 130.96,48.77 131.01,48.78 131.06,48.8 131.11,48.82 131.15,48.85 131.19,48.89 131.22,48.93 131.24,48.98 131.26,49.02 131.26,49.08 131.26,49.13 131.26,49.18 131.24,49.23 131.22,49.28 131.19,49.32 131.15,49.35 131.11,49.38 131.06,49.41 131.01,49.42 130.96,49.43 130.91,49.43 130.86,49.42 130.81,49.41 130.76,49.38 130.72,49.35 130.68,49.32 130.65,49.28 130.63,49.23 130.61,49.18 130.6,49.13 128.28,49.13 128.28,51.93 128.27,51.95 128.27,51.97 128.33,52.05 128.35,52.06 128.36,52.06
GND POWER on L3_IN1 (solid shape): outline of 208 points within 60.15,32.9 85.5,45.28
GND POWER on L3_IN1 (solid shape): outline of 345 points within 40.92,42.24 60.89,61.53
GND POWER on L3_IN1 (solid shape): outline of 331 points within 109.02,34.49 127.92,52.06
GND POWER on L3_IN1 (solid shape): outline of 440 points within 72.37,120.28 160.34,141.1
GND POWER on L3_IN1 (solid shape): outline of 1214 points within 28.22,28.89 66.64,53.06
GND POWER on L3_IN1 (solid shape): outline of 7664 points within 0.2,0.2 160.29,141.1
GND POWER on L4_IN2 (solid shape): 120.84,87.5 121.1,87.5 121.12,87.49 121.13,87.48 121.22,87.39 121.24,87.38 121.26,87.38 131.86,87.38 132.25,86.99 132.25,86.14 129.33,83.22 129.31,83.21 129.29,83.2 113.42,83.2 111.39,85.23 111.39,88.84 111.39,88.86 111.4,88.87 112.43,89.91 112.45,89.92 112.47,89.92 118.41,89.92
GND POWER on L4_IN2 (solid shape): outline of 194 points within 105.75,79.3 137.53,87.5
GND POWER on L4_IN2 (solid shape): outline of 519 points within 145.79,14.49 160.29,72.62
GND POWER on L4_IN2 (solid shape): outline of 818 points within 72.62,119.61 160.29,141.1
GND POWER on L4_IN2 (solid shape): outline of 1025 points within 144.31,68.24 160.29,119.61
GND POWER on L4_IN2 (solid shape): outline of 6261 points within 0.2,0.2 160.34,141.1
GND POWER on TOP: 122.17,87.69 125.84,87.69 126.93,88.78 128.01,88.78 128.5,88.29 128.5,82.29 127.47,81.26 127.47,79.67 126.9,79.1 122.52,79.1 121.96,79.66 121.96,87.49
GND POWER on TOP: 40.58,78.9 40.81,79.13 52.5,79.13 52.88,78.75 52.88,76.59 51.1,74.81 44.56,74.81 42.75,73 42.75,68.74 42.13,68.12 36.95,68.12 36.72,67.89 34.02,67.89 33.42,68.48 33.42,71.09 33.12,71.39 31.95,71.39 30.17,69.62 29.73,69.62 29.47,69.89 29.47,75.74 29.78,76.06 30.5,76.06 30.88,76.44 30.88,78.66 31.12,78.9
GND POWER on TOP: 72.21,50.6 72.21,56.29 72.43,56.52 74.34,56.52 74.47,56.4 74.47,46.69 73.68,45.91 73.68,43.48 72.92,42.72 70.7,42.72 70.32,43.1 70.32,43.61 70.63,43.93 71.59,43.93 71.78,44.12 71.78,45.83 71.52,46.09 70.82,46.09 70.44,46.47 70.44,49.83 70.82,50.22 71.83,50.22
GND POWER on TOP: 57.68,131.37 61.55,131.37 61.74,131.18 61.74,130.16 61.43,129.84 57.68,129.84 57.43,130.1 57.43,131.11
GND POWER on TOP: 81.32,55.25 83.61,55.25 83.99,54.87 83.99,53.73 85.9,51.82 85.9,47.98 84.02,46.11 82.72,46.11 82.68,46.07 82.65,46.1 81.34,46.1 81.07,46.36 81.07,55
GND POWER on TOP: 43.93,57.57 51.96,57.57 53.28,56.25 58.44,56.25 58.73,55.96 61.64,55.96 62.44,55.16 62.44,52.31 62.32,52.18 56.22,52.18 55.58,52.82 55.58,54.83 55.09,55.32 51.6,55.32 50.5,54.22 50.5,52.03 50.21,51.73 43.41,51.73 42.88,52.26 42.88,56.52
GND POWER on TOP: 52.24,61.73 52.25,61.72 52.54,61.72 52.78,61.48 52.78,60.55 52.47,60.25 51.14,60.25 50.25,59.36 48.28,59.36 47.97,59.67 47.97,60.5 48.45,60.98 48.45,61.48 48.7,61.73
GND POWER on TOP: 103.67,132.9 104.43,132.9 104.61,132.71 104.61,129.8 104.4,129.59 103.59,129.59 103.32,129.85 103.32,132.55
GND POWER on TOP: 53.23,135.31 54.44,135.31 54.5,135.24 54.5,134.42 54.25,134.16 53.23,134.16 53.04,134.35 53.04,135.12
GND POWER on TOP: 16.33,92.4 16.37,92.41 16.41,92.43 16.45,92.46 17.11,92.46 17.27,92.31 17.27,91.04 17.16,90.94 16.12,90.94 15.5,91.56 15.5,92.4 15.5,92.4
GND POWER on TOP: 127.71,29.75 126.87,30.59 126.87,34.4 126.64,34.63 109.54,34.63 109.54,51.8 127.6,51.8 127.6,43.67 132.15,39.12 132.15,30.06 131.85,29.75 ; 2 cut-outs
GND POWER on TOP: 5.91,73.54 5.9,73.53 5.89,73.54 5.89,76.31 6.42,76.84 7.82,76.84 8.2,76.46 8.2,73.54 9.22,72.53 9.22,71.89 9.09,71.76 8.71,71.76 8.45,72.02 6.55,72.02 5.91,72.65
GND POWER on TOP: 97.85,84.53 99.95,84.53 100.36,84.11 102.34,84.11 102.66,84.44 106.74,84.44 107.45,83.72 110.15,83.72 111.42,82.45 118.14,82.45 118.67,81.92 118.67,80.78 118.19,80.29 116.73,80.29 116.33,80.7 112.98,80.7 111.13,78.85 109.07,78.85 108.95,78.74 108.95,78.16 108.61,77.81 106.67,77.81 106.38,78.1 106.38,80.36 105.14,81.6 100.78,81.6 98.57,79.39 97.59,79.39 96.56,80.42 96.56,81.01 96.99,81.44 98.55,81.44 98.71,81.6 98.71,82.63 97.46,83.87 97.46,84.15
GND POWER on TOP: 102.73,132.37 97.15,132.37 96.98,132.53 95.87,132.53 95.65,132.32 95.65,130.01 95.9,129.75 102.94,129.75 103.13,129.95 103.13,131.96
GND POWER on TOP: 97.73,52.51 98.14,52.92 99.08,52.92 99.23,53.07 99.23,53.96 99.28,54.01 99.46,54.01 99.49,53.98 99.49,53.07 99.64,52.92 100.58,52.92 101.01,52.48 101.01,52.51 103.42,52.51 103.8,52.88 103.8,53.32 103.9,53.43 105.61,53.43 105.84,53.2 105.84,51.67 105.66,51.49 103.83,51.49 103.14,52.18 101.21,52.18 101.09,52.05 101.06,52.05 100.96,51.95 97.33,51.95 97.25,51.87 97.25,51.27 97.17,51.19 95.68,51.19 95.19,51.67 95.19,52.43 95.27,52.51
GND POWER on TOP: 95.04,36.35 96.69,36.35 96.75,36.29 96.75,34.57 96.56,34.38 95.1,34.38 94.91,34.57 94.91,36.22
GND POWER on TOP: 12.29,90.71 12.29,85.02 12.06,84.79 11.24,84.79 9.83,86.21 9.83,89.89 10.9,90.96 12.03,90.96
GND POWER on TOP: 69.3,57.6 70.18,57.6 70.45,57.33 72.1,57.33 72.45,57.68 72.45,59.04 72.11,59.39 71.34,59.39 70.85,59.88 69.09,59.88 68.65,59.43 68.65,59.05 68.25,58.66 67.57,58.66 67.07,58.15 67.07,56.76 67.22,56.6 68.36,56.6 69.3,57.55
GND POWER on TOP: 81.9,36.54 85.26,36.54 85.39,36.41 85.39,34.45 85.13,34.19 82.09,34.19 81.77,34.51 81.77,36.41
GND POWER on TOP: 90.85,137.78 91.03,137.96 93.82,137.96 93.8,137.93 93.8,135.85 93.73,135.78 92.92,135.78 92.5,136.2 91.41,136.2 90.85,136.76
GND POWER on TOP: 141.86,83.08 141.71,83.23 141.71,83.82 141.13,84.4 139.59,84.4 138.94,85.04 138.43,85.04 137.77,85.7 137.77,89.18 133.72,93.23 131.38,93.23 131.15,92.99 128.07,92.99 126.31,91.23 126.31,90.66 126.13,90.48 126.13,89.9 125.62,89.4 123.59,89.4 123.44,89.54 123.44,90.86 122.61,91.69 122.61,92.23 121.58,93.26 121.58,99.07 121.46,99.19 120.19,99.19 119.56,99.83 119.56,104.98 120.17,105.6 121.34,105.6 122.77,104.17 122.77,94.98 123.4,94.35 126.07,94.35 129.26,97.54 129.26,99.86 129.65,100.25 141.47,100.25 141.76,99.95 141.76,99.24 140.91,98.39 140.91,95.9 142.03,94.77 142.03,92.69 143.81,90.91 152.68,90.91 152.68,89.21 152.6,89.13 152.6,88.65 153.03,88.22 153.64,88.22 154.1,88.68 159.72,88.68 160.01,88.36 160.11,87.95 160.11,85.01 159.98,84.55 159.63,84.23 151.31,84.23 150.71,84.83 149.65,84.83 149.24,84.42 149.24,82.35 149.01,82.11 148.11,82.11 147.14,83.08
GND POWER on TOP: 123.01,124.98 120.6,124.98 120.34,124.72 120.34,117.36 120.85,116.85 121.99,116.85 122.5,116.34 123.14,116.34 123.26,116.21 123.26,116.09 123.52,115.83 124.02,115.83 124.15,115.96 124.15,117.48 123.14,118.5 123.14,124.85
GND POWER on TOP: 41.46,134.62 41.39,134.69 41.39,135.11 43.82,137.55 47.31,137.55 47.58,137.27 47.58,136.77 46.76,135.94 46.76,135 46.69,134.93 43.34,134.93 43.02,134.62
GND POWER on BOTTOM: 25.01,60.38 25.01,61.37 24.53,61.84 24.53,63.13 24.77,63.36 29.18,63.36 29.44,63.63 29.44,77.88 29.82,78.25 39.81,78.25 40.05,78.49 46.53,78.49 49.32,81.29 58.59,81.29 58.72,81.16 58.72,80.02 58.97,79.76 66.11,79.76 66.11,79.77 67.76,79.77 67.89,79.64 67.89,77.61 67.13,76.84 63.67,76.84 63.3,77.21 63.3,78.13 63.06,78.37 60.02,78.37 59.64,77.99 59.64,76.84 59.38,76.59 49.7,76.59 45.23,72.12 45.23,64.91 45.28,64.91 46.94,63.26 50.75,63.26 51.13,62.87 51.13,61.37 51.11,61.35 51.11,59.1 50.78,58.77 45.7,58.77 44.34,60.12 40.34,60.12 38.19,62.28 31.6,62.28 31.59,62.27 29.6,62.27 25.23,57.9 23.07,57.9 22.63,58.34 22.63,59.42 23.07,59.87 24.5,59.87
GND POWER on BOTTOM: 8.21,73.4 8.86,72.75 10.04,72.75 10.1,72.68 10.1,72.54 10.06,72.49 9.19,72.49 9.15,72.45 9.15,72.3 9.2,72.25 10.03,72.25 10.1,72.18 10.1,72.02 10.03,71.95 4.97,71.95 4.52,72.4 4.52,76.84 4.77,77.1 7.69,77.1 8.21,76.59
GND POWER on BOTTOM: 143.43,37.57 143.43,36 144.98,34.45 144.98,33.92 145,33.89 145.59,33.89 145.59,35.39 145.18,35.8 145.18,37.65 145,37.83 143.68,37.83
GND POWER on BOTTOM: 124.86,130.06 126.44,130.06 126.51,129.98 126.51,128.38 126.46,128.33 125.83,128.33 125.65,128.51 124.89,128.51 124.73,128.66 124.73,129.93
GND POWER on BOTTOM: 61.51,69.86 61.51,70.87 61.89,71.25 64.18,71.25 64.19,71.24 66.25,71.24 66.37,71.13 66.37,70.24 65.98,69.86
GND POWER on BOTTOM: 112.19,115.25 116.8,115.25 117.07,114.98 117.07,113.53 116.71,113.17 112.63,113.17 112.08,113.71 112.08,115.15
GND POWER on BOTTOM: 94.21,124.1 110.46,124.1 111.28,123.28 111.28,113.95 112.28,112.95 115.3,112.95 119.53,108.72 128.37,108.72 128.44,108.65 128.44,102.8 126.79,101.15 117.82,101.15 117.04,100.37 115.17,100.37 114.17,101.37 93.38,101.37 91.8,102.95 91.8,121.69
GND POWER on BOTTOM: 146.9,122.83 146.9,124.58 146.5,124.98 145.56,124.98 145.53,124.95 140.76,124.95 140.42,125.29 140.42,126.55 143.57,129.71 150.24,129.71 150.24,128.57 149.74,127.8 150.44,127.2 160.04,127.2 160.25,127.11 160.34,126.9 160.34,123.45 160.25,123.24 160.04,123.15 150.74,123.15 149.97,123.65 149.37,122.95 149.37,121.12 149.36,121.12 149.27,121.02 148.71,121.02
GND POWER on BOTTOM: 24.37,93.41 26.84,93.41 27.09,93.16 27.09,92.39 26.58,91.89 24.93,91.89 24.66,91.62 24.66,90.26 24.67,90.26 24.67,90.19 24.48,90.01 24.27,90.01 24.15,90.12 24.15,93.19
GND POWER on BOTTOM: 89.58,8.1 98.99,8.1 99.58,7.5 107.5,7.5 108.37,8.37 108.37,15.31 106.17,17.51 106.17,19.97 108.01,21.81 108.01,23.59 107.09,24.51 106.23,24.51 105.58,23.86 105.58,21.07 101.84,17.33 93.91,17.33 89.71,13.13 89.71,8.23
GND POWER on BOTTOM: 34.46,67.83 34.46,77.1 45.13,77.1 45.13,67.83
GND POWER on BOTTOM: 53.3,44.31 55.46,44.31 55.84,43.93 61.62,43.93 62.12,43.42 62.12,42.28 61.81,41.96 53.04,41.96 52.66,42.34 52.66,43.68
GND POWER on BOTTOM: outline of 214 points within 0.2,0.2 160.34,111.13
GND POWER on BOTTOM: 84.76,52.76 84.76,51.32 83.48,50.04 81.74,50.04 81.48,50.3 81.48,54.49 81.73,54.75 82.77,54.75
GND POWER on BOTTOM: 75.76,79.89 76.91,79.89 77.54,80.53 78.18,80.53 78.3,80.4 78.3,79.77 78.81,79.26 78.81,78.37 78.43,77.99 76.15,77.99 75.76,78.37
GND POWER on BOTTOM: 94.69,50.68 92.78,50.68 92.66,50.56 92.66,47.25 92.91,47 94.81,47 94.94,47.13 94.94,50.43
GND POWER on BOTTOM: 74.37,73.42 77.92,73.42 78.05,73.29 78.05,71.64 77.92,71.51 74.62,71.51 74.24,71.89 74.24,73.29
GND POWER on BOTTOM: 110.56,59.32 112.21,59.32 112.34,59.19 112.34,54.62 112.21,54.49 111.32,54.49 111.07,54.75 111.07,57.92 110.44,58.56 110.44,59.06 110.56,59.19
GND POWER on BOTTOM: 92.87,135.61 93.15,135.89 93.15,136.68 92.77,137.07 85.48,137.07 82.72,139.83 76.3,139.83 73.43,136.96 69.49,136.96 66.32,140.14 63.31,140.14 62.08,138.91 60.93,138.91 60.16,138.13 60.16,137.34 58.95,136.13 58.19,136.13 58.12,136.07 58.12,135.12 58.4,134.84 60.52,134.84 60.61,134.75 61.24,135.37 62.95,135.37 64.05,134.27 67.1,134.27 68.43,135.61
GND POWER on BOTTOM: 23.41,137.17 23.41,139.71 28.75,139.71 28.75,137.17
GND POWER on BOTTOM: 63.21,56.62 59.02,56.62 58.65,56.25 56.79,56.25 55.65,55.11 44.66,55.11 43.77,54.22 43.77,52.25 44.41,51.61 53.74,51.61 55.06,50.3 63.16,50.3 63.34,50.48 63.34,56.5
GND POWER on BOTTOM: 37.19,49.34 38.63,49.34 38.94,49.02 38.94,48.23 39.16,48.02 40.81,48.02 40.9,47.93 40.9,41.27 46.67,35.51 46.67,32.05 36.38,32.05 34.55,33.89 34.55,44.89 36.64,46.98 36.64,48.79
GND POWER on BOTTOM: 109.14,49.46 110.23,49.46 110.56,49.14 110.56,47.03 109.96,46.44 109.46,46.44 108.96,46.93 108.96,49.29
GND POWER on BOTTOM: 103.88,66.89 102.76,65.77 100.81,65.77 100.55,66.02 100.55,66.66 100.73,66.84 101.42,66.84 101.78,67.2 101.78,67.84 101.7,67.93 99.33,67.93 99.16,68.11 99.16,68.69 99.26,68.79 103.7,68.79 103.88,68.61
GND POWER on BOTTOM: 130.91,48.77 131.59,48.77 132.53,47.82 132.53,44.73 134.6,42.66 139.41,42.66 139.74,42.32 139.74,36.52 132.64,29.42 115.31,29.42 112.12,32.61 112.12,42.7 111.7,43.12 111.7,45.37 116.27,49.94 116.27,52.36 117.27,53.35 126.32,53.35
GND POWER on BOTTOM: 81.96,71.51 81.96,73.57 81.66,73.87 81.66,79.03 81.96,79.33 81.96,79.51 82.47,80.02 82.47,81.16 82.59,81.29 82.98,81.29 83.48,80.78 83.48,80.27 83.23,80.27 83.1,80.14 83.1,79.13 83.36,78.87 83.36,76.7 83.77,76.29 83.77,74.68 83.36,74.27 83.36,71.51 83.23,71.38 82.09,71.38
GND POWER on BOTTOM: 74.54,66.56 67.23,66.56 66.34,67.44 66.34,69.1 67.1,69.86 69.57,69.86 70.13,70.41 70.84,70.41 71.36,69.9 71.36,69.44 71.57,69.22 75.26,69.22 75.38,69.35 75.38,70.24 75.51,70.37 76.25,70.37 76.5,70.62 77.01,70.62 77.51,70.11 77.51,69.53
GND POWER on L2_VCC: 127.72,29.67 126.79,30.6 126.79,33.9 126.2,34.5 109.94,34.5 109.4,35.04 109.4,40.63 109.52,40.76 109.52,51.05 110.52,52.04 127.27,52.04 127.63,51.68 127.63,41.77 128.61,40.8 130.77,40.8 132.46,39.11 132.46,30.6 131.53,29.67 ; 10 cut-outs
GND POWER on L2_VCC: outline of 121 points within 0.2,0.2 160.34,141.1 ; 3 cut-outs
GND POWER on L3_IN1: 11.02,94 17.61,94 18.16,93.44 18.16,92.16 16.73,90.72 16.73,85.58 12.2,81.06 9.07,81.06 8.31,80.3 8.31,79.44 8.86,78.89 12.39,78.89 18.43,84.93 18.43,86.47 18.5,86.54 19.98,86.54 20.43,86.09 20.43,82.35 19.08,81 15.48,81 12.91,78.43 8.32,78.43 6.65,80.11 6.65,89.62
GND POWER on L3_IN1: 44.64,122.48 47.63,125.47 49.92,125.47 51.24,124.15 53.48,124.15 54.1,124.78 68.91,124.78 69.41,124.28 111.11,124.28 112.94,122.45 112.94,122.17 113.68,121.43 113.68,112.22 114.34,111.56 114.34,102.25 113.53,101.45 103.59,101.45 103.03,102 93.06,102 78.85,116.22 55.15,116.22 50.18,121.19 48.96,121.19 48.65,121.49 45.64,121.49 44.76,120.61 38.48,120.61 38.24,120.85 38.24,121.68 39.03,122.48
GND POWER on L3_IN1: 130.57,29.6 130.54,29.6 127.84,29.6 126.83,30.6 126.83,33.56 127.41,34.14 127.41,35.42 121.64,41.19 121.64,43.13 121.82,43.31 127.89,43.31 132.15,39.04 132.15,30.01 131.74,29.6
GND POWER on L3_IN1: 112.45,84.42 112.47,84.42 116.96,79.92 127.14,79.92 127.94,80.73 127.94,87.9 123.23,92.61 123.23,98.48 122.77,98.94 114.32,98.94 112.13,96.75 112.13,84.74
GND POWER on L3_IN1: 130.35,118.48 131.36,117.47 131.36,110.99 128.71,108.34 128.71,102 132.94,97.77 132.94,96.02 132.91,96.02 130.82,93.92 127.01,93.92 126.54,94.39 126.54,96.08 127.31,96.85 128.63,96.85 128.93,97.15 128.93,98.21 119.06,108.08 119.06,116.62 120.92,118.48
GND POWER on L3_IN1: 133,128.44 141.43,128.44 142.61,127.26 142.61,107.34 141.93,106.66 140.93,106.66 140.68,106.92 140.68,111.52 140.09,112.11 138.28,112.11 137.86,112.53 137.86,126.19 136.53,127.52 133.16,127.52 132.83,127.85 132.83,128.27
GND POWER on L3_IN1: 95.35,47.28 95.5,47.13 96.01,46.62 96.01,41.1 97.36,39.75 102,39.75 102.73,40.48 102.73,47.33 103.76,48.36 105.25,48.36 106.29,47.33 106.29,41.44 106.34,41.38 106.34,36.74 106.37,36.71 105.48,35.82 98.48,35.82 96.97,34.31 87.73,34.31 85.54,36.5 85.54,44.71 86.17,45.35 90.42,45.35 90.62,45.55 90.62,46.87 91.03,47.28
GND POWER on L4_IN2: 122.78,123.03 126.02,123.03 126.08,122.97 126.08,117.46 126.79,116.75 126.79,105.02 128.89,102.92 128.89,95.08 128.12,94.31 125.54,94.31 125.06,94.79 125.06,97.7 119.87,102.89 119.87,113.75 119.94,113.82 119.94,116.97 122.49,119.52 122.49,122.73
GND POWER on L4_IN2: 110.22,51.78 143.26,51.78 144.33,50.71 144.33,50.57 142.65,48.9 135.04,48.9 134.07,47.92 134.07,46.72 135.69,45.09 139.45,45.09 139.96,44.58 139.96,42.01 137.81,39.85 137.81,29.71 138.69,28.83 138.69,24.14 137.43,22.89 136.09,22.89 132.89,26.09 119.99,26.09 117.45,23.56 115.9,23.56 115.09,24.37 115.09,30.08 108.87,36.3 108.87,48.26 109.71,49.1 109.71,51.27
GND POWER on L4_IN2: 23.55,135.55 23.55,138.97 24.33,139.74 28.27,139.74 28.86,139.15 41.98,139.15 42.76,138.38 61.41,138.38 62.33,139.3 68.81,139.3 70.04,138.07 70.04,136.36 68.05,134.38 40.8,134.38 39.99,133.57 39.76,133.57 39.56,133.37 22.42,133.37 22.11,133.68 22.11,134.11
GND POWER on L4_IN2: 27.93,78.77 38.98,78.77 42.11,75.64 47.56,75.64 53.93,69.27 70.43,69.27 73.33,72.18 83.61,72.18 84.56,73.14 91.71,73.14 92.63,72.22 92.63,71.34 92.52,71.23 88.08,71.23 87,70.14 76.07,70.14 72.59,66.66 58.86,66.66 53.98,61.78 52.79,61.78 50.47,59.45 36.37,59.45 35.77,58.85 31.2,58.85 30.72,59.33 29.97,59.33 24.47,64.82 24.47,76.19 25.56,77.27 26.44,77.27
GND POWER on L4_IN2: 145.61,49.39 149.84,49.39 151.72,47.51 151.72,41.77 156.47,37.02 156.47,28 156.33,27.87 151.61,27.87 150.9,27.15 150.36,27.15 147.71,29.81 147.71,37.02 145.2,39.53 145.2,48.99
GND POWER on L4_IN2: 25.63,86.69 27.79,86.69 27.81,86.69 27.82,86.67 28.01,86.48 28.03,86.47 28.05,86.47 31.1,86.47 31.12,86.47 31.13,86.48 31.6,86.95 31.62,86.96 31.64,86.97 35.12,86.97 35.14,86.96 35.15,86.95 36.44,85.66 36.45,85.65 36.46,85.63 36.46,82.62 35.42,81.58 25.49,81.58 23.04,84.04 23.04,111.05 27.43,115.45 31.66,115.45 34.11,117.9 44.43,117.9 45.67,116.65 45.67,93.84 44.29,92.45 42.65,92.45 42,93.1 42,93.33 44.38,95.71 44.38,107.09 43.2,108.27 43.2,109.1 44.98,110.88 44.98,113.39 42.9,115.47 38.36,115.47 36.83,113.95 35.33,112.45 35.33,110.09 34.87,109.63 29.86,109.63 27.8,107.57 25.24,107.57 24.43,106.77 24.43,92.3 24.69,92.04 24.69,87.63
GND POWER on L5_GND: outline of 121 points within 0.2,0.2 160.34,141.1 ; 15 cut-outs
GND_CN on TOP: 14.01,57.54 14.01,59.77 14.26,60.01 14.9,60.01 15.21,60.32 15.21,62.55 15.33,62.67 15.88,62.67 16.17,62.38 16.17,62.02 16.17,57.54
GND_OZ8690 on BOTTOM: 17.7,97.42 17.32,97.42 16.43,98.31 13.94,98.31 11.98,96.35 11.98,89.29 13.03,88.25 21.15,88.25 21.91,89.01 21.91,92.01 21.69,92.24 20.24,92.24 20.06,92.06 20.06,90.53 19.7,90.18 17.42,90.18 17.06,90.53 17.06,92.21 18.08,93.23 18.08,97.04 ; 1 cut-out
GND_OZ8690 on L3_IN1: 18.36,96.07 18.36,94.88 17.81,94.33 12.78,94.33 12.39,94.72 12.39,102.14 13.08,102.83 14.36,102.83 15.05,103.51 20.28,103.51 20.94,102.86 20.94,94.77 20.91,94.74 19.59,94.74 19.32,95 19.32,95.69 18.94,96.07
GND_OZ8690 on L4_IN2: 14.55,98.71 16.63,98.71 18.46,96.88 19.63,96.88 21.06,95.45 21.06,94.43 20.81,94.18 14.27,94.18 14.27,97.42 14.01,97.67 14.01,98.18
GND_SIGNAL on TOP (solid shape): 28.41,46.79 28.41,43.35 28.39,43.32 24.83,43.32 24.74,43.41 24.74,46.81 24.85,46.92 28.28,46.92
GND_SIGNAL on BOTTOM: 28.91,43.2 23.91,43.2 23.83,43.27 23.83,44.89 23.08,45.63 23.08,46.15 23.24,46.31 23.46,46.31 23.83,46.68 23.83,46.98 23.95,47.1 26.12,47.1 27.07,46.15 27.71,46.15 27.83,46.28 27.83,46.6 27.96,46.72 28.15,46.72 28.28,46.6 28.28,46.47 28.47,46.28 28.85,46.28 29.17,45.96 29.17,43.68 30.57,42.28 30.57,42.04 30.3,41.78 29.54,41.78 29.17,42.15 29.17,42.94
GND_SIGNAL on L3_IN1: 26.88,50.85 27.96,50.85 28.22,50.6 28.22,50.28 27.96,50.03 27.96,43.87 27.71,43.61 25.29,43.61 24.98,43.93 24.98,46.98 25.99,47.99 25.99,49.96
P1.24V_AUX_LX on TOP: 50.5,131.94 50.76,131.94 53.04,134.23 53.04,135.88 53.23,136.07 55.01,136.07 55.39,135.69 55.39,133.97 54.82,133.4 54.82,130.92 54.38,130.48 50.82,130.48 50.44,130.86 50.44,131.88
V1.00A on TOP (solid shape): 89.17,75.17 89.58,75.17 89.83,74.91 89.83,74.84 89.71,74.71 89.58,74.71 89.48,74.81 89.3,74.82 89.17,74.81 89.13,74.77 89.07,74.72 89.01,74.65 89,74.63 88.99,74.61 88.97,74.51 88.98,74.42 88.97,74.39 88.96,74.37 88.9,74.31 88.89,74.3 88.81,74.25 88.75,74.18 88.74,74.17 88.72,74.15 88.34,74.15 88.11,74.38 88.11,75.29 88.39,75.57 88.77,75.57
V1.00A on TOP: 107.11,68.92 107.11,67.37 106.93,67.19 106.09,67.19 105.89,67.39 105.89,68.94 105.99,69.05 106.98,69.05
V1.00A on TOP: 97.97,43.43 96.56,44.84 95.27,44.84 94.57,45.54 94.57,46.47 94.38,46.66 94,46.66 93.81,46.47 93.81,45.41 93.24,44.84 92.49,44.84 91.67,45.66 91.67,48.67 92.16,49.16 96.08,49.16 96.47,49.54 96.47,50.56 96.72,50.81 97.28,50.81 97.4,50.94 97.4,51.7 97.48,51.77 98.67,51.77 98.67,50.48 99.23,49.92 99.61,49.92 99.99,50.3 99.99,51.7 100.12,51.82 101.26,51.82 101.52,52.08 103.04,52.08 104.75,50.37 104.75,49.51 104.65,49.41 104.59,49.41 103.84,48.65 102.82,48.65 102.43,48.27 102.43,37.98 102.18,37.73 98.37,37.73 97.97,38.13
V1.00A on BOTTOM: 101.84,50.22 104.59,50.22 104.77,50.04 104.77,49.21 104.59,49.03 104.09,49.03 102.56,47.51 102.56,40.42 102.55,40.41 102.55,38.99 101.93,38.36 97.23,38.36 95.32,40.27 95.32,50.68 95.58,50.94 96.59,50.94 96.72,50.81 96.72,50.43 97.1,50.05 101.67,50.05
V1.00A on L2_VCC: 97.99,47.43 97.18,48.24 97.18,69.96 96.21,70.92 88.98,70.92 88.03,71.86 88.03,77.98 88.34,78.29 89.36,78.29 89.86,78.79 90.65,78.79 91.03,78.41 98.01,78.41 98.83,77.6 98.83,77.47 100.17,76.13 101.7,76.13 110,67.82 110,64.01 111.78,62.23 111.78,54.84 111.73,54.79 110.21,54.79 107.21,51.8 107.21,47.86 106.78,47.43
V1.00A on L3_IN1: 96.69,47.25 101.77,47.25 102.41,46.62 102.41,40.59 102.39,40.57 102.39,39.08 101.55,38.24 97.61,38.24 96.18,39.66 96.18,46.74
V1.00A on L4_IN2: 102.69,46.87 102.69,38.87 102.05,38.24 91.89,38.24 90.62,39.51 90.62,51.7 91.13,52.21 91.51,52.21 93.04,50.68 103.96,50.68 104.72,49.92 104.72,48.9
V1.00A_LX on TOP: 93.56,43.5 93.75,43.31 93.75,42.34 93.87,42.21 94.45,42.21 94.51,42.28 94.51,42.99 95.02,43.5 96.92,43.5 97.61,42.81 97.61,36.84 97.35,36.59 89.35,36.59 89.23,36.71 89.23,38.24 89.35,38.36 89.99,38.36 90.37,38.74 90.37,42.81 91.06,43.5
V1.00A_SN on TOP: 91.1,36.41 93.13,36.41 93.26,36.29 93.26,35.46 93.13,35.33 91.1,35.33 90.98,35.46 90.98,36.29
VDDA on TOP: 22.35,46.99 22.35,48.62 22.45,48.72 23.58,48.72 23.66,48.64 23.66,48.32 23.26,47.91 23.26,47.71 23.39,47.59 24.01,47.59 24.54,47.06 24.54,46.9 24.51,46.87 22.47,46.87
VIN on TOP (solid shape): 71.84,40.37 71.84,39.04 71.52,38.72 67.78,38.72 67.71,38.79 67.71,41.39 67.97,41.64 70.57,41.64
VIN on TOP (solid shape): 86.47,39.25 88.85,39.25 88.97,39.13 88.97,36.59 88.72,36.33 86.05,36.33 85.54,36.84 82.11,36.84 81.48,37.47 81.48,39.35 81.84,39.71 86.02,39.71
VIN on TOP (solid shape): 124.79,124.6 124.79,123.45 125.17,123.07 127.83,123.07 128.47,122.44 128.47,120.41 128.34,120.28 126.44,120.28 125.93,119.77 125.93,118.85 126.03,118.75 126.03,117.33 124.91,116.21 124.91,116.04 124.79,115.91 124.46,115.91 124.41,115.96 124.41,117.23 124.41,117.58 123.39,118.6 123.39,118.63 123.26,118.75 123.26,124.85 124.53,124.85
VIN on BOTTOM (solid shape): 16.46,86.88 16.46,83.19 15.82,82.56 13.28,82.56 12.52,83.32 12.52,87.39 12.77,87.64 15.69,87.64
VIN on BOTTOM (solid shape): 47.11,134.13 47.11,132.16 47.01,132.07 43.39,132.07 43.14,132.32 43.14,133.78 43.58,134.23 47.01,134.23
VIN on TOP: 102.31,135.81 103.54,135.81 103.55,135.8 105.43,135.8 105.61,135.62 105.61,134.12 104.57,133.08 103.45,133.08 103.04,132.67 95.9,132.67 95.6,132.98 95.6,135.54 95.85,135.8 95.85,137.27 96.92,137.27 96.92,135.59 97,135.52 97,135.26 97.01,135.25 97.01,134.85 97.46,134.4 100.9,134.4
VIN on TOP: 118.74,135.71 119.01,135.44 119.73,135.44 119.9,135.28 119.9,134.22 119.75,134.08 119.41,134.08 119.1,133.77 118.29,133.77 118.04,134.02 118.04,135.53 118.22,135.71
VIN on TOP: 46.88,131.33 44.43,131.33 42.76,132.99 42.65,133.1 42.07,133.68 41.53,133.68 41.43,133.78 41.43,134.28 41.58,134.43 43.08,134.43 43.33,134.68 46.51,134.68 47.13,134.07 47.13,131.57
VIN on TOP: 53.11,36.25 57.51,36.25 57.93,36.67 59.14,36.67 60.16,35.65 60.16,34.14 59.73,33.71 54.37,33.71 53.11,34.98
VIN on TOP: 14.35,96.35 14.35,92.51 14.47,92.39 14.47,91.04 14.55,90.97 14.55,90.97 14.55,89.28 15.13,88.7 15.14,88.7 15.21,88.64 16.52,88.64 16.66,88.5 16.66,85.1 16.2,84.64 13.33,84.64 12.47,85.5 12.47,91.3 12.67,91.5 12.67,92.41 12.77,92.51 12.77,96.35
VIN on TOP: 19.39,73.91 17.06,73.91 17.04,73.92 17.03,73.93 15.24,75.72 15.22,75.73 15.2,75.73 12.85,75.73 12.8,75.75 11.39,75.75 11.37,75.75 11.35,75.76 9.1,78.01 9.09,78.02 9.07,78.02 8.99,78.02 8.97,78.02 8.95,78.04 7.74,79.25 7.72,79.26 7.7,79.26 6.06,79.26 6.04,79.27 6.02,79.28 5.92,79.38 5.92,80.52 6.08,80.67 6.08,81.5 6.2,81.63 7.23,81.63 8.92,79.94 8.93,79.91 8.93,79.88 9.01,79.53 9.36,79.46 9.39,79.46 9.41,79.44 9.46,79.4 9.47,79.39 9.49,79.38 10.72,79.38 10.74,79.38 10.76,79.37 10.78,79.35 10.8,79.34 10.82,79.33 11.41,79.33 11.43,79.33 11.44,79.32 12.24,78.52 20.49,78.52 20.49,78.52 21.12,78.52 23.07,76.57 23.07,72.25 22.56,71.74 21.56,71.74
VIN on L2_VCC: 56.75,32.19 52.94,36 52.92,36 49.23,39.69 49.23,52.64 46.58,55.3 46.58,55.32 45.06,56.84 45.06,59.76 43.22,61.6 20.68,61.6 14.2,68.08 14.2,72.66 4.8,82.05 4.8,137.38 7.6,140.19 122.53,140.19 122.79,140.44 123.38,140.44 123.64,140.19 124.14,140.19 126.82,137.51 126.82,125.95 128.6,124.18 128.6,120.66 127.7,119.77 121.64,119.77 121.64,123.84 120.88,124.6 120.88,130.15 121.01,130.28 121.65,130.28 122.15,130.78 122.15,131.58 121.65,132.08 120.76,132.08 119.23,133.61 92.52,133.61 90.74,131.83 33.59,131.83 31.18,129.42 16.5,129.42 16.33,129.25 16.33,129.14 13.99,126.8 13.99,124.95 13.61,124.57 13.61,120.14 13.99,119.76 13.99,92.97 16.02,90.93 16.02,87 16.66,86.36 16.66,80.39 27.66,69.4 32.48,69.4 34.01,67.87 36.31,67.87 36.39,67.8 46.55,67.8 54.29,60.05 57.98,60.05 63.32,54.71 63.32,50.9 69.54,44.68 69.54,43.08 71.75,40.87 87.19,40.87 88.72,39.34 88.72,36.08 84.83,32.19
VIN on L4_IN2: 16.58,86.3 16.58,81.19 18.61,79.15 18.61,76.87 17.93,76.18 14.47,76.18 12.44,78.21 12.44,85.8 13.4,86.76 16.12,86.76
VIN_CPU_CORE on TOP (solid shape): 55.39,42.59 57.17,42.59 57.5,42.26 57.5,36.68 57.3,36.48 51.12,36.48 50.24,37.36 47.92,37.36 47.78,37.5 47.78,37.53 47.18,38.12 47.18,42.33 47.78,42.92 55.06,42.92
VIN_CPU_CORE on BOTTOM (solid shape): 60.46,40.99 60.46,37.18 60.14,36.86 52.51,36.86 52.23,37.14 52.23,40.75 52.67,41.18 60.27,41.18
VIN_CPU_VCCGT on TOP (solid shape): 28.99,75.62 28.99,68.71 29.45,68.25 29.45,63.76 29.25,63.56 24.75,63.56 22.34,65.96 22.34,70.2 22.45,70.3 22.47,70.3 22.49,70.3 22.9,70.42 22.83,70.85 22.83,71.44 23.39,72 23.39,76 23.58,76.19 28.42,76.19
VIN_CPU_VCCGT on BOTTOM: 24.48,63.97 24.48,76.12 24.53,76.12 26.88,78.47 28.66,78.47 29.01,78.12 29.01,64.02 28.57,63.57 24.88,63.57
VIN_CPU_VCCSA on TOP (solid shape): 71.52,38.59 71.78,38.59 71.84,38.53 71.84,38.02 71.42,37.6 71.42,35.57 71.93,35.06 74.85,35.06 74.97,34.93 74.97,31.2 74.4,30.62 70.02,30.62 67.71,32.92 67.71,38.53 67.78,38.6 71.51,38.6
VIN_LCD on TOP: 119.42,128.33 119,128.76 117.62,128.76 117.55,128.83 117.55,130.06 118.05,130.57 120.34,130.57 121.74,131.96 121.74,134.88 122.12,135.26 125.8,135.26 126.18,134.88 126.18,131.71 124.15,129.68 124.15,128.63 125.14,127.64 125.14,125.81 125.04,125.71 119.83,125.71 119.42,126.12
VIN_LCD_IN0 on TOP: 117.03,134.99 117.51,134.99 117.65,134.85 117.65,131.6 117.4,131.35 116.76,131.35 116.19,131.92 115.74,131.92 115.6,132.07 115.6,132.77 116.65,133.83 116.65,134.61
+CPU_CORE on TOP (solid shape): outline of 272 points within 77.92,79.26 82.96,82.26
+CPU_CORE on L4_IN2 (solid shape): 72.12,55.18 72.12,51.06 66.46,45.4 65.74,44.67 57.81,44.67 55.76,46.72 55.76,49.24 56.33,49.82 62.21,49.82 65.09,52.7 65.09,53.66 67.06,55.63 71.66,55.63
+CPU_CORE on TOP: 64.5,44.92 64.5,45.6 64.23,45.87 63.59,45.87 61.73,44.01 58.28,44.01 57.45,44.84 51.5,44.84 50.95,45.39 50.95,54.22 51.84,55.11 54.82,55.11 55.33,54.6 55.33,51.61 55.52,51.42 63.27,51.42 64.03,52.18 64.03,55.59 65.37,56.93 65.37,58.61 65.45,58.68 65.96,58.68 66.06,58.58 66.06,57.82 66.49,57.39 66.49,56.35 66.57,56.27 68.54,56.27 69.28,57.01 71.78,57.01 72.03,56.76 72.03,51.1 71.52,50.6 70.83,50.6 70.02,49.79 70.02,46.41 71.27,45.16 71.27,44.37 71.01,44.12 65.3,44.12
+CPU_CORE on TOP: outline of 87 points within 76.22,68.8 83.87,71.97
+CPU_CORE on BOTTOM: outline of 87 points within 55.9,45.14 83.64,82.18
+CPU_CORE on L2_VCC: 76.66,68.89 76.22,69.32 76.22,77.73 78,79.5 78,80.9 79.32,82.22 82.52,82.22 82.7,82.04 82.7,81.41 83.59,80.52 83.59,71.81 83.28,71.81 82.83,71.35 82.83,70.97 82.45,70.59 82.45,68.89
+CPU_CORE on L3_IN1: 83.48,69.35 83.74,69.1 83.74,60.71 83.67,60.65 83.67,60.4 79.8,56.52 75.86,56.52 75.1,55.76 75.1,54.76 70.73,50.38 69.59,50.38 65.74,46.53 62.7,46.53 61.49,45.33 57.3,45.33 56.16,46.47 56.16,48.56 56.54,48.95 59.58,48.95 64.92,54.28 64.92,56.06 65.55,56.69 65.55,59.55 66,59.99 66,60.9 65.13,61.77 65.13,63.31 65.45,63.63 73.7,63.63 75.17,65.1 75.17,69.31 76.37,70.52 76.37,73.54 78.02,75.19 78.02,81.8 78.53,82.3 81.96,82.3 83.48,80.78
+CPU_VCCGT on BOTTOM (solid shape): outline of 611 points within 45.54,63.64 70.43,78.38
+CPU_VCCGT on TOP: 67.51,82.18 70.56,82.18 71.57,81.16 71.57,80.02 71.32,79.77 67.64,79.77 67,80.4 67,81.67
+CPU_VCCGT on TOP: outline of 214 points within 42.39,59.7 71.07,77.12
+CPU_VCCGT on L3_IN1: 63.42,63.94 62.78,64.57 62.78,64.96 61,66.73 58.59,66.73 57.11,65.25 51.31,65.25 46.27,70.29 46.27,77.99 49.28,80.99 58.07,80.99 61.29,84.21 61.29,88.27 62.08,89.06 63.44,89.06 63.93,89.54 69.03,89.54 69.04,89.54 69.48,89.54 70.08,88.93 70.08,87.72 69.92,87.56 69.92,84.21 70.68,83.45 70.68,64.78 69.84,63.94
+CPU_VCCGTXR42 on BOTTOM (solid shape): outline of 214 points within 68.83,69.4 78,82.18
+CPU_VCCGTXR42 on TOP: 71.32,72.27 75.89,72.27 76.15,72.02 76.15,69.86 75.89,69.61 71.45,69.61 71.19,69.86 71.19,72.15
+CPU_VCCGTXR42 on TOP: 71.19,82.18 73.35,82.18 74.24,81.29 77.29,81.29 77.54,81.04 77.54,79.51 77.29,79.26 72.46,79.26 72.08,79.64 72.08,80.78 71.07,81.8 71.07,82.05
+CPU_VCCGTXR42 on L3_IN1: 70.94,82.31 76.91,82.31 77.29,81.92 77.29,79.89 76.91,79.51 76.91,75.07 75.38,73.54 75.38,70.62 73.61,68.84 73.61,67.45 73.67,67.38 73.67,64.08 73.48,63.89 71.32,63.89 70.94,64.27
+VSDIO on TOP (solid shape): 140.49,71.81 140.49,69.57 140.77,69.29 140.77,68.63 141.01,68.39 142.98,68.39 143.66,67.71 143.66,66.33 143.38,66.05 142.69,66.05 142.44,66.3 140.61,66.3 140.1,65.8 139.26,65.8 139.01,66.05 139.01,69.68 139.21,69.88 139.21,71.72 139.52,72.03 140.27,72.03
AC_IN+ on BOTTOM: 142.79,133.26 143.1,133.56 148.3,133.56 149.27,132.6 149.27,130.21 149.09,130.03 143.05,130.03 142.79,130.28
BAT+ on TOP: 21.48,56.75 21.74,56.5 27.27,56.5 27.55,56.78 27.55,59.95 26.52,60.99 21.71,60.99 21.48,60.76
BAT+ on BOTTOM: 11.38,76.23 15.2,76.23 15.97,75.47 15.95,75.45 15.95,73.21 15.82,73.08 15.33,73.08 15.07,72.83 15.07,72.64 14.5,72.06 12.98,72.06 12.77,72.27 12.77,74.3 12.52,74.56 11.63,74.56 11.25,74.94 11.25,76.1
BAT+ on L3_IN1: 12.65,74.68 22.27,74.68 27.58,69.37 27.58,59.36 28.03,58.92 28.03,57.14 27.2,56.32 18.19,56.32 13.62,60.89 13.62,63.4 12.48,64.54 12.48,74.51
BATT- on TOP: 13.62,61.48 14.49,61.48 14.74,61.23 14.74,60.56 14.39,60.21 14.14,60.21 13.63,59.7 13.63,57.54 13.51,57.41 10.36,57.41 10.03,57.75 10.03,59.65 10.44,60.07 10.44,61.64 11.16,62.36 12.98,62.36 13.24,62.1 13.24,61.86
BST1 on TOP: 32.41,58.98 32.03,59.36 32.03,60.38 32.22,60.57 35.96,60.57 37.3,59.23 37.3,54.6 37.23,54.53 37.22,54.53 36.63,53.94 36.26,53.94 36.19,54.01 36.19,54.56 36.34,54.71 36.34,55.17 36.15,55.36 36.15,57.14 36.06,57.23 36.06,58.18 35.26,58.98
BST2 on BOTTOM (solid shape): 40.05,54.74 40.05,52.77 39.9,52.63 38.75,52.63 38.64,52.75 38.64,53.32 38.53,53.43 38.37,53.77 38.03,53.92 37.99,53.96 37.99,54.72 38.25,54.98 39.81,54.98
BST2 on TOP: 39.14,54.22 39.07,54.22 38.75,53.9 37.74,53.9 37.49,53.64 37.49,53.33 37.42,53.26 36.72,53.26 36.66,53.33 36.66,53.84 38.03,55.21 39.07,55.21 39.39,54.89 39.39,54.47
BSTA2 on TOP (solid shape): 29.94,44.86 30.47,44.86 30.52,44.8 31.79,44.8 32.02,44.57 32.02,43.79 31.82,43.59 31.62,43.59 31.34,43.87 31.34,44.06 31.07,44.33 30.45,44.33 30.27,44.51 29.89,44.51 29.57,44.83 28.98,44.83 28.95,44.85 28.95,44.96 29.02,45.02 29.77,45.02
BSTA2 on TOP: 31.33,44.06 31.58,44.31 32.15,44.31 32.6,43.87 32.6,43.42 32.98,43.04 34.88,43.04 35.26,42.66 35.26,41.01 35.07,40.82 31.96,40.82 31.33,41.45
CHG_LX on BOTTOM (solid shape): 16.48,94.06 16.48,92.95 16.3,92.77 13.43,92.77 13.3,92.9 13.3,94.09 13.35,94.14 16.4,94.14
CHG_LX on TOP: 15.16,80.02 15.16,82.53 17.65,85.02 17.65,88.27 16.81,89.11 15.52,89.11 15.06,89.57 15.06,91.27 15.08,91.3 15.08,92.77 15.01,92.84 14.8,92.84 14.8,93.91 14.83,93.94 16.38,93.94 16.48,94.04 17.57,94.04 17.68,94.14 17.7,94.14 17.7,94.16 17.8,94.27 20.66,94.27 21.32,93.6 21.32,80.13 21.01,80.03 20.91,79.72 20.91,79.69 19.97,78.75 19.76,78.75 19.69,78.78 19.66,78.84 19.3,79.18 18.95,78.84 18.91,78.78 18.84,78.75 16.43,78.75 ; 1 cut-out
CHG_LX on L4_IN2: 14.41,93.99 18.21,93.99 20.43,91.76 20.43,87.52 20.08,87.17 18.4,87.17 17.7,87.87 17.7,88.41 16.77,89.35 14.78,89.35 13.84,90.29 13.84,93.41
CLICK_PAD_+3.3V on TOP (solid shape): 10.61,39.89 10.61,38.74 10.36,38.49 5.79,38.49 5.41,38.87 5.41,40.01 5.66,40.27 10.23,40.27
CODEC_GND on L5_GND: 149.66,26.24 148.94,26.95 147.17,26.95 147.06,27.06 147.06,27.49 146.83,27.72 146.83,28.05 146.56,28.33 144.7,28.33 144.55,28.48 144.55,29.75 145.26,30.46 145.26,32.39 144.96,32.7 144.96,33.38 145.08,33.51 146.1,33.51 146.33,33.74 148.56,33.74 148.64,33.66 149.2,33.66 149.3,33.58 149.3,33.25 149.55,33 154.05,33 154.35,33.3 154.35,38.46 155.82,39.93 155.85,40.57 156.54,40.57 156.74,40.77 156.74,41.8 156.99,42.18 156.99,42.55 157.3,42.85 157.76,42.85 158.15,42.46 158.6,42.04 158.6,41.08 158.57,40.37 157.48,39.3 157.48,36.96 157.73,36.71 159.15,36.71 159.41,36.45 159.41,34.91 159.23,34.73 158.97,34.73 158.26,34.02 158.26,31.98 158.01,31.73 158.01,31.24 158.26,30.99 158.26,30.38 158.42,30.23 159.15,30.23 159.18,30.2 159.18,29.47 159.1,29.39 157.32,29.39 156.99,29.06 156.99,28.05 155.85,26.9 155.85,26.52 155.8,26.47 154.13,26.47 154.07,26.52 154.07,26.9 153.87,27.11 151.74,27.11 150.87,26.24
DC_IN on BOTTOM: 5.44,93.25 7.26,93.25 7.46,93.05 11.47,93.05 11.47,90.33 11.34,90.19 7.05,90.19 7.04,90.18 6.8,90.18 6.55,89.93 6.55,88.27 6.42,88.15 5.03,88.15 4.71,88.46 4.71,92.87 4.83,92.98 5.17,92.98
DC_IN+ on BOTTOM (solid shape): 2.96,103.54 3.9,103.54 4.11,103.34 4.47,102.95 4.82,103.34 5.78,103.34 6.37,102.75 6.37,102.19 6.91,101.65 6.91,100.13 6.7,99.93 4.7,99.93 4,100.62 1.03,100.62 0.85,100.8 0.85,103.98 0.96,104.09 2.41,104.09
DC_IN+ on L3_IN1 (solid shape): outline of 6940 points within 0.88,97.71 145.41,140.75
DC_IN+ on TOP: 1.8,103.84 3.33,103.84 5.63,101.55 5.63,96.19 5.22,95.78 3.59,95.78 3.12,96.24 3.12,96.99 2.71,97.4 1.52,97.4 1.37,97.56 1.37,103.41
DC_IN+ on BOTTOM: 143.3,139.71 146.09,139.71 146.27,139.53 146.27,133.92 146.22,133.87 143.05,133.87 142.79,134.12 142.79,139.2
DC_IN+ on L4_IN2: 18.61,135.62 17.93,134.93 11.63,134.93 11.17,135.39 9.45,135.39 7.95,133.89 3.79,133.89 3.58,134.09 3.58,137.12 4.08,137.62 4.08,139.42 5.13,140.46 17.96,140.46 18.61,139.8
DC_IN_B on BOTTOM: 5.49,99.55 8.43,99.55 8.99,98.99 8.99,96.88 8.35,96.25 8.35,94.72 8.07,94.45 5.33,94.45 5.25,94.52 5.25,95.31 4.9,95.66 4.6,95.66 4.36,95.91 4.36,97.27 5.17,98.08 5.17,99.23
HDMI_5V_C on TOP: 147.16,106.28 148.86,106.28 149.5,105.65 149.5,103.87 151.48,101.89 151.48,100.49 151.28,100.29 150.82,100.29 150.59,100.52 150.59,101.35 148.25,103.69 147.67,103.69 147.44,103.92 147.44,104.76 147.11,105.09 147.11,106.23
ICHP on BOTTOM (solid shape): 8.55,87.43 8.55,78.77 8.48,78.7 7.13,78.7 5.54,80.28 5.54,81.13 5.12,81.54 5.12,86.03 5.38,86.29 5.99,86.29 6.25,86.54 6.25,87.84 6.43,88.03 7.96,88.03
ICHP on TOP: 12.41,94.04 12.41,92.64 12.36,92.59 11.68,92.59 11.47,92.39 11.47,92.03 9.58,90.14 9.58,85.85 10.87,84.56 12.39,84.56 13.98,82.98 13.98,80.06 13.45,79.54 10.88,79.54 9.21,81.21 8.05,81.21 5.48,83.79 5.48,92.17 6.67,93.36 7.3,93.36 7.98,94.04
LDRENB on TOP (solid shape): 34.76,52.12 34.76,51.36 34.22,50.82 34.22,50.49 34.17,50.44 33.72,50.44 33.71,50.45 33.71,50.85 33.99,51.14 33.99,52.12 34.12,52.25 34.63,52.25
LDRENC on TOP (solid shape): 35.24,51.63 35.24,51.01 34.96,50.73 34.96,50.69 34.94,50.67 34.94,50.4 34.88,50.33 34.58,50.33 34.46,50.46 34.46,50.69 34.95,51.19 34.95,51.54 35.07,51.66 35.21,51.66
Net_2 on BOTTOM: 9.17,71.28 9.17,68.1 9.29,67.97 11.45,67.97 11.58,68.1 11.58,68.92 12.14,69.48 12.14,70.62 12.6,71.08 12.6,72.04 12.34,72.29 10.82,72.29 10.44,71.91 10.44,71.53 10.22,71.31 9.2,71.31
NFC_VBAT on TOP (solid shape): 130.37,23.89 130.37,23.38 129.87,22.87 129.87,20.58 129.74,20.46 128.85,20.46 128.14,19.75 127.65,19.75 127.58,19.82 127.58,20.08 128.47,20.96 128.47,23 129.49,24.01 130.25,24.01
NFC_VBAT on TOP (solid shape): 124.66,18.04 124.66,17.54 124.02,16.9 122.37,16.9 121.23,15.76 118.83,15.76 118.69,15.89 118.69,16.19 118.83,16.32 119.38,16.32 119.71,16.65 120.98,16.65 122.25,17.92 123.77,17.92 124.02,18.17 124.53,18.17
OZ8283_HDR1 on TOP (solid shape): 29.37,48.33 29.37,47.69 28.82,47.14 28.31,47.14 28.28,47.17 28.28,47.9 28.81,48.44 29.26,48.44
OZ8283_HDR1 on TOP (solid shape): 56.85,44.25 56.85,43.16 56.66,42.97 55.41,42.97 55.02,43.36 55.02,44.36 55.19,44.52 56.58,44.52
OZ8283_HDR1 on L4_IN2 (solid shape): 55.69,44.45 55.69,43.27 55.61,43.19 54.99,43.19 54.89,43.29 54.89,44.44 55.05,44.59 55.55,44.59
OZ8283_HDR2 on TOP (solid shape): 29.8,44.33 30.2,44.33 30.31,44.21 30.31,43.96 30.27,43.92 29.96,43.92 29.41,44.47 28.9,44.47 28.87,44.5 28.87,44.56 28.92,44.62 29.51,44.62
OZ8283_HDR3 on BOTTOM (solid shape): 30.17,69.22 30.17,67.71 29.95,67.5 29.15,67.5 28.96,67.69 28.96,68.94 29.39,69.36 30.02,69.36
OZ8283_HDR3R on TOP (solid shape): 31.61,69.49 31.61,68.22 31.84,68 31.84,67.61 31.77,67.55 30.25,67.55 29.99,67.81 29.99,68.38 30.31,68.69 30.31,69.39 30.57,69.65 31.45,69.65
OZ8283_HDR3R on BOTTOM (solid shape): 31.63,69.33 31.63,67.6 31.47,67.44 30.51,67.44 30.41,67.54 30.41,69.37 30.53,69.5 31.46,69.5
OZ8283_HDR4 on TOP (solid shape): 73.11,40.69 73.11,38.6 72.98,38.47 72.09,38.47 71.97,38.6 71.97,40.63 72.16,40.82 72.98,40.82
OZ8283_HDR4 on TOP (solid shape): 38.4,53.63 38.4,53.3 38.38,53.3 37.93,52.84 36.97,52.84 36.9,52.91 36.9,52.98 36.95,53.03 37.46,53.03 37.59,53.16 37.59,53.59 37.79,53.8 38.23,53.8
OZ8283_HDR4R on TOP (solid shape): 72.94,37.98 72.94,36.96 72.69,36.71 72.69,35.44 72.56,35.31 71.93,35.31 71.55,35.69 71.55,37.5 72.16,38.11 72.82,38.11
OZ8283_LDR1 on TOP (solid shape): 30.63,47.36 30.63,47.23 30.37,46.98 30.37,46.79 29.61,46.02 28.85,46.02 28.79,46.09 28.79,46.22 28.82,46.25 29.38,46.25 29.42,46.28 29.46,46.28 29.79,46.62 29.8,46.62 30.01,46.77 30.06,47.02 30.06,47.03 30.06,47.24 30.12,47.3 30.12,47.35 30.25,47.49 30.5,47.49
OZ8283_LDR1 on TOP: 67.86,32.43 67.86,30.84 67.64,30.62 66.24,30.62 66.11,30.74 66.11,33.79 66.24,33.92 67.32,33.92 67.49,33.75 67.49,32.8
OZ8283_LDR1 on L4_IN2: 31.25,47.41 30.76,46.91 30.31,46.91 30.06,47.17 30.06,47.33 30.85,48.13 31.15,48.13 31.25,48.02
OZ8283_LDR2 on TOP (solid shape): 40.9,45.35 40.9,44.19 40.69,43.99 39.39,43.99 39.11,44.26 39.11,45.38 39.17,45.44 40.81,45.44
OZ8283_LDR2 on TOP (solid shape): 31.09,46.78 31.09,46.13 30.82,45.86 30.78,45.86 30.78,45.82 30.57,45.62 29.94,45.62 29.9,45.59 29.34,45.59 29.33,45.6 29.33,45.73 29.38,45.78 29.57,45.78 30.5,46.71 30.5,46.73 30.5,46.81 30.58,46.89 30.97,46.89
OZ8283_LDR2 on L4_IN2: 29.55,45.87 29.55,46.31 29.68,46.44 31.03,46.44 31.16,46.3 31.16,45.73 30.9,45.46 29.96,45.46
OZ8283_LDR3 on TOP (solid shape): 34.8,53.45 34.8,53.27 34.77,53.25 33.46,53.25 33.36,53.34 33.36,53.34 33.36,54.18 33.38,54.19 34.07,54.19
OZ8283_LDR4 on TOP (solid shape): 79.71,32.94 79.71,32.05 79.46,31.8 79.46,31.74 79.52,31.67 79.97,31.67 80.1,31.55 80.1,31.04 79.9,30.85 78.57,30.85 78.44,30.98 78.44,31.74 78.89,32.18 78.89,33.01 78.95,33.07 79.59,33.07
OZ8283_LX1 on TOP (solid shape): 32.19,50.92 32.19,50.15 32.03,49.99 31.74,49.99 31.57,50.15 31.52,50.15 31.51,50.17 30.5,50.17 29.8,49.47 29.8,48.69 29.67,48.57 28.76,48.57 28.6,48.41 28.57,48.41 28.15,47.99 28.15,47.44 28.15,47.16 28.13,47.14 27.86,47.14 27.82,47.18 27.82,48 28,48.18 28,48.22 28.07,48.29 28.07,48.41 28.34,48.69 28.34,49.3 29.17,50.13 29.17,51.38 29.35,51.55 31.56,51.55
OZ8283_LX1 on TOP: 67.47,41.32 67.47,34.52 67.13,34.17 62.43,34.17 62.18,34.43 62.18,37.47 62.04,37.61 57.96,37.61 57.8,37.77 57.8,40.83 58.11,41.15 60.3,41.15 61.28,42.12 66.67,42.12
OZ8283_LX2 on TOP (solid shape): 29.78,43.9 29.79,43.9 29.93,43.76 30.33,43.76 30.54,43.97 31.05,43.97 31.2,43.82 31.2,43.46 31.46,43.2 31.46,43 31.37,42.91 31.34,42.91 31.16,42.73 30.61,42.73 30.23,43.1 30.23,43.2 29.97,43.46 29.94,43.46 29.46,43.94 29.44,43.94 29.37,44.01 29,44.01 28.99,44.02 28.95,44.02 28.95,44.06 28.93,44.08 28.93,44.18 28.95,44.2 29.48,44.2
OZ8283_LX2 on BOTTOM (solid shape): 49.7,48.57 49.7,44.45 48.95,43.7 47.41,43.7 46.74,43.02 46.74,41.36 45.95,40.57 41.87,40.57 41.37,41.07 41.37,49.14 41.47,49.24 49.02,49.24
OZ8283_LX2 on TOP: 41.87,49.39 48.79,49.39 49.81,48.37 49.81,44.5 48.98,43.68 47.46,43.68 46.76,42.98 46.76,39.36 46.44,39.04 41.93,39.04 41.3,39.67 41.3,48.82
OZ8283_LX3 on TOP: 35.13,56.13 35.77,56.13 35.93,55.97 35.93,55.61 35.52,55.2 35.52,54.76 35.64,54.65 35.64,53.8 35.59,53.76 35.49,53.76 35.46,53.78 35.46,54.35 34.93,54.87 34.93,55.93
OZ8283_LX3 on TOP: 30.06,63.17 30.06,66.68 30.3,66.92 31.9,66.92 32.02,67.05 32.02,67.09 32.12,67.18 36.55,67.18 36.57,67.16 40.35,67.16 41.06,66.45 41.06,62.54 41.05,62.53 41.06,62.51 41.06,60.59 40.81,60.33 38.29,60.33 36.13,62.49 30.75,62.49
OZ8283_LX4 on TOP: 79.3,33.41 76.5,33.41 76.24,33.66 76.24,35.06 75.99,35.31 72.94,35.31 72.82,35.44 72.82,36.46 73.32,36.96 73.32,37.04 73.67,37.38 75.65,37.38 75.72,37.45 75.72,39.8 75.8,39.88 79.08,39.88 79.29,39.67 79.29,36.52 79.57,36.24 79.57,33.68
OZ8283_LX4 on TOP: 37.61,52.69 38.25,53.33 38.25,53.52 38.31,53.58 38.82,53.58 39.01,53.77 39.26,53.77 39.39,53.64 39.39,52.5 39.26,52.37 37.61,52.37 37.55,52.44 36.79,52.44 36.72,52.5 36.72,52.63 36.79,52.69
PWMB on TOP (solid shape): 34.61,52.6 34.61,52.5 34.56,52.45 34.07,52.45 33.85,52.23 33.85,51.32 33.29,50.76 32.67,50.76 32.6,50.83 32.6,51.3 32.7,51.4 33.11,51.4 33.41,51.69 33.41,52.28 33.49,52.37 33.62,52.37 33.66,52.4 33.83,52.48 33.95,52.63 34.57,52.63
PWRSW_0 on BOTTOM: 128.47,140.09 129.36,140.09 129.61,139.84 129.61,136.92 129.49,136.79 128.34,136.79 128.34,137.93 128.47,138.06
SAFTY_PROTECT on BOTTOM: 3.5,107.17 3.81,107.17 3.86,107.12 3.86,105.82 4.06,105.62 4.06,104.32 3.83,104.09 2.44,104.09 1.55,104.98 1.55,105.95 1.65,106.05 3.22,106.05 3.45,106.28 3.45,107.01 3.43,107.04 3.43,107.09
SATA_5V on TOP: 4.26,65.92 3.14,67.05 3.14,71.84 2.63,72.36 1.59,72.36 1.28,72.67 1.28,75.41 1.55,75.68 3.19,75.68 3.59,76.08 3.59,77.58 3.63,77.61 3.63,78.49 4.14,79 5.53,79 5.84,78.69 5.84,76.66 5.67,76.49 5.67,72.52 7.54,70.65 7.54,70.62 8.07,70.09 8.07,67.45 6.55,65.92
SATA_5V on BOTTOM: 14.17,62.62 17.47,62.62 17.6,62.49 17.6,60.84 15.69,58.94 12.65,58.94 11.76,59.83 10.36,59.83 9.85,59.32 9.22,59.32 8.96,59.57 8.96,61.6 9.22,61.86 12.26,61.86 12.77,61.35 14.04,61.35 14.17,61.48
SATA_5V on L3_IN1: 8.33,70.62 7.31,70.62 6.3,69.61 6.3,60.84 8.07,59.06 9.85,59.06 10.23,59.45 10.23,61.1 9.03,62.3 9.03,69.92
SEC_BAT on TOP: 3.32,94.51 4.82,94.51 5.18,94.15 5.18,82.7 4.84,82.36 4.84,81.91 4.12,81.19 1.52,81.19 0.97,81.74 0.97,87.98 1.37,88.39 2.62,88.39 3.14,88.92 3.14,94.33
USB_5V on BOTTOM (solid shape): outline of 189 points within 137.09,114.05 142.32,118.2
USB_5VOUT on TOP (solid shape): 140.51,64.88 141.12,64.88 141.17,64.83 141.17,64.53 141.17,64.53 141.17,63.76 141.25,63.67 142.22,63.67 142.28,63.61 148.43,63.61 148.71,63.33 148.71,62.09 148.5,61.87 145.31,61.87 145.27,61.83 143.1,61.83 143.06,61.87 140.35,61.87 139.52,62.7 139.52,64.83 139.77,65.08 140.31,65.08
USB_5VOUT on TOP: 135.81,82.38 135.81,84.71 136.29,85.2 137.76,85.2 138.1,84.85 138.87,84.85 139.87,83.86 141.19,83.86 141.43,83.62 141.43,83.08 141.81,82.71 147.15,82.71 148.13,81.73 148.13,81.52 148.13,81.51 148.08,81.26 148.13,81.01 148.13,81 148.13,80.45 147.9,80.22 147.57,80.22 147.19,79.83 140.06,79.83 138.84,81.06 137.13,81.06
USB_5VOUT on BOTTOM: 141.57,107.82 141.57,105.77 140.27,104.47 136.46,104.47 135.08,105.85 135.08,108.5 133.55,110.04 133.55,110.73 133.01,111.26 133.01,119.26 133.39,119.64 136.22,119.64 136.6,120.02 136.6,123.83 136.98,124.21 139.65,124.21 139.74,124.31 139.77,124.31 140.06,124.6 146,124.6 146.25,124.34 146.25,122.89 148.12,121.02 148.12,118.74 147.91,118.54 144.58,118.54 144.13,118.08 144.13,116.4 143.85,116.12 142.65,116.12 142.39,116.39 142.39,118.16 142.06,118.5 138.15,118.5 137.73,118.07 136.66,118.07 136.52,117.93 136.52,112.88
USB_5VOUT on L3_IN1: 136.57,88.21 135.96,87.61 135.96,80.79 136.01,80.74 136.01,78.24 137.44,76.81 137.44,64.32 139.34,62.41 141.25,62.41 142.39,63.55 142.39,82.6 142.03,82.96 142.03,91.64 142.67,92.27 142.67,105.57 142.62,105.62 142.59,105.62 141.73,106.48 137.89,106.48 136.57,105.16
VAD on TOP: 11.5,95.64 12.41,95.64 12.44,95.61 12.44,94.29 12.39,94.24 8.66,94.24 8.27,94.62 8.27,95.74 8.78,96.25 10.87,96.25 11.12,95.99 11.14,95.99
VAD on BOTTOM: 8.6,93.56 8.6,96.05 8.73,96.17 10.48,96.17 10.77,95.89 10.77,94.57 10.56,94.37 10.56,93.48 8.68,93.48
